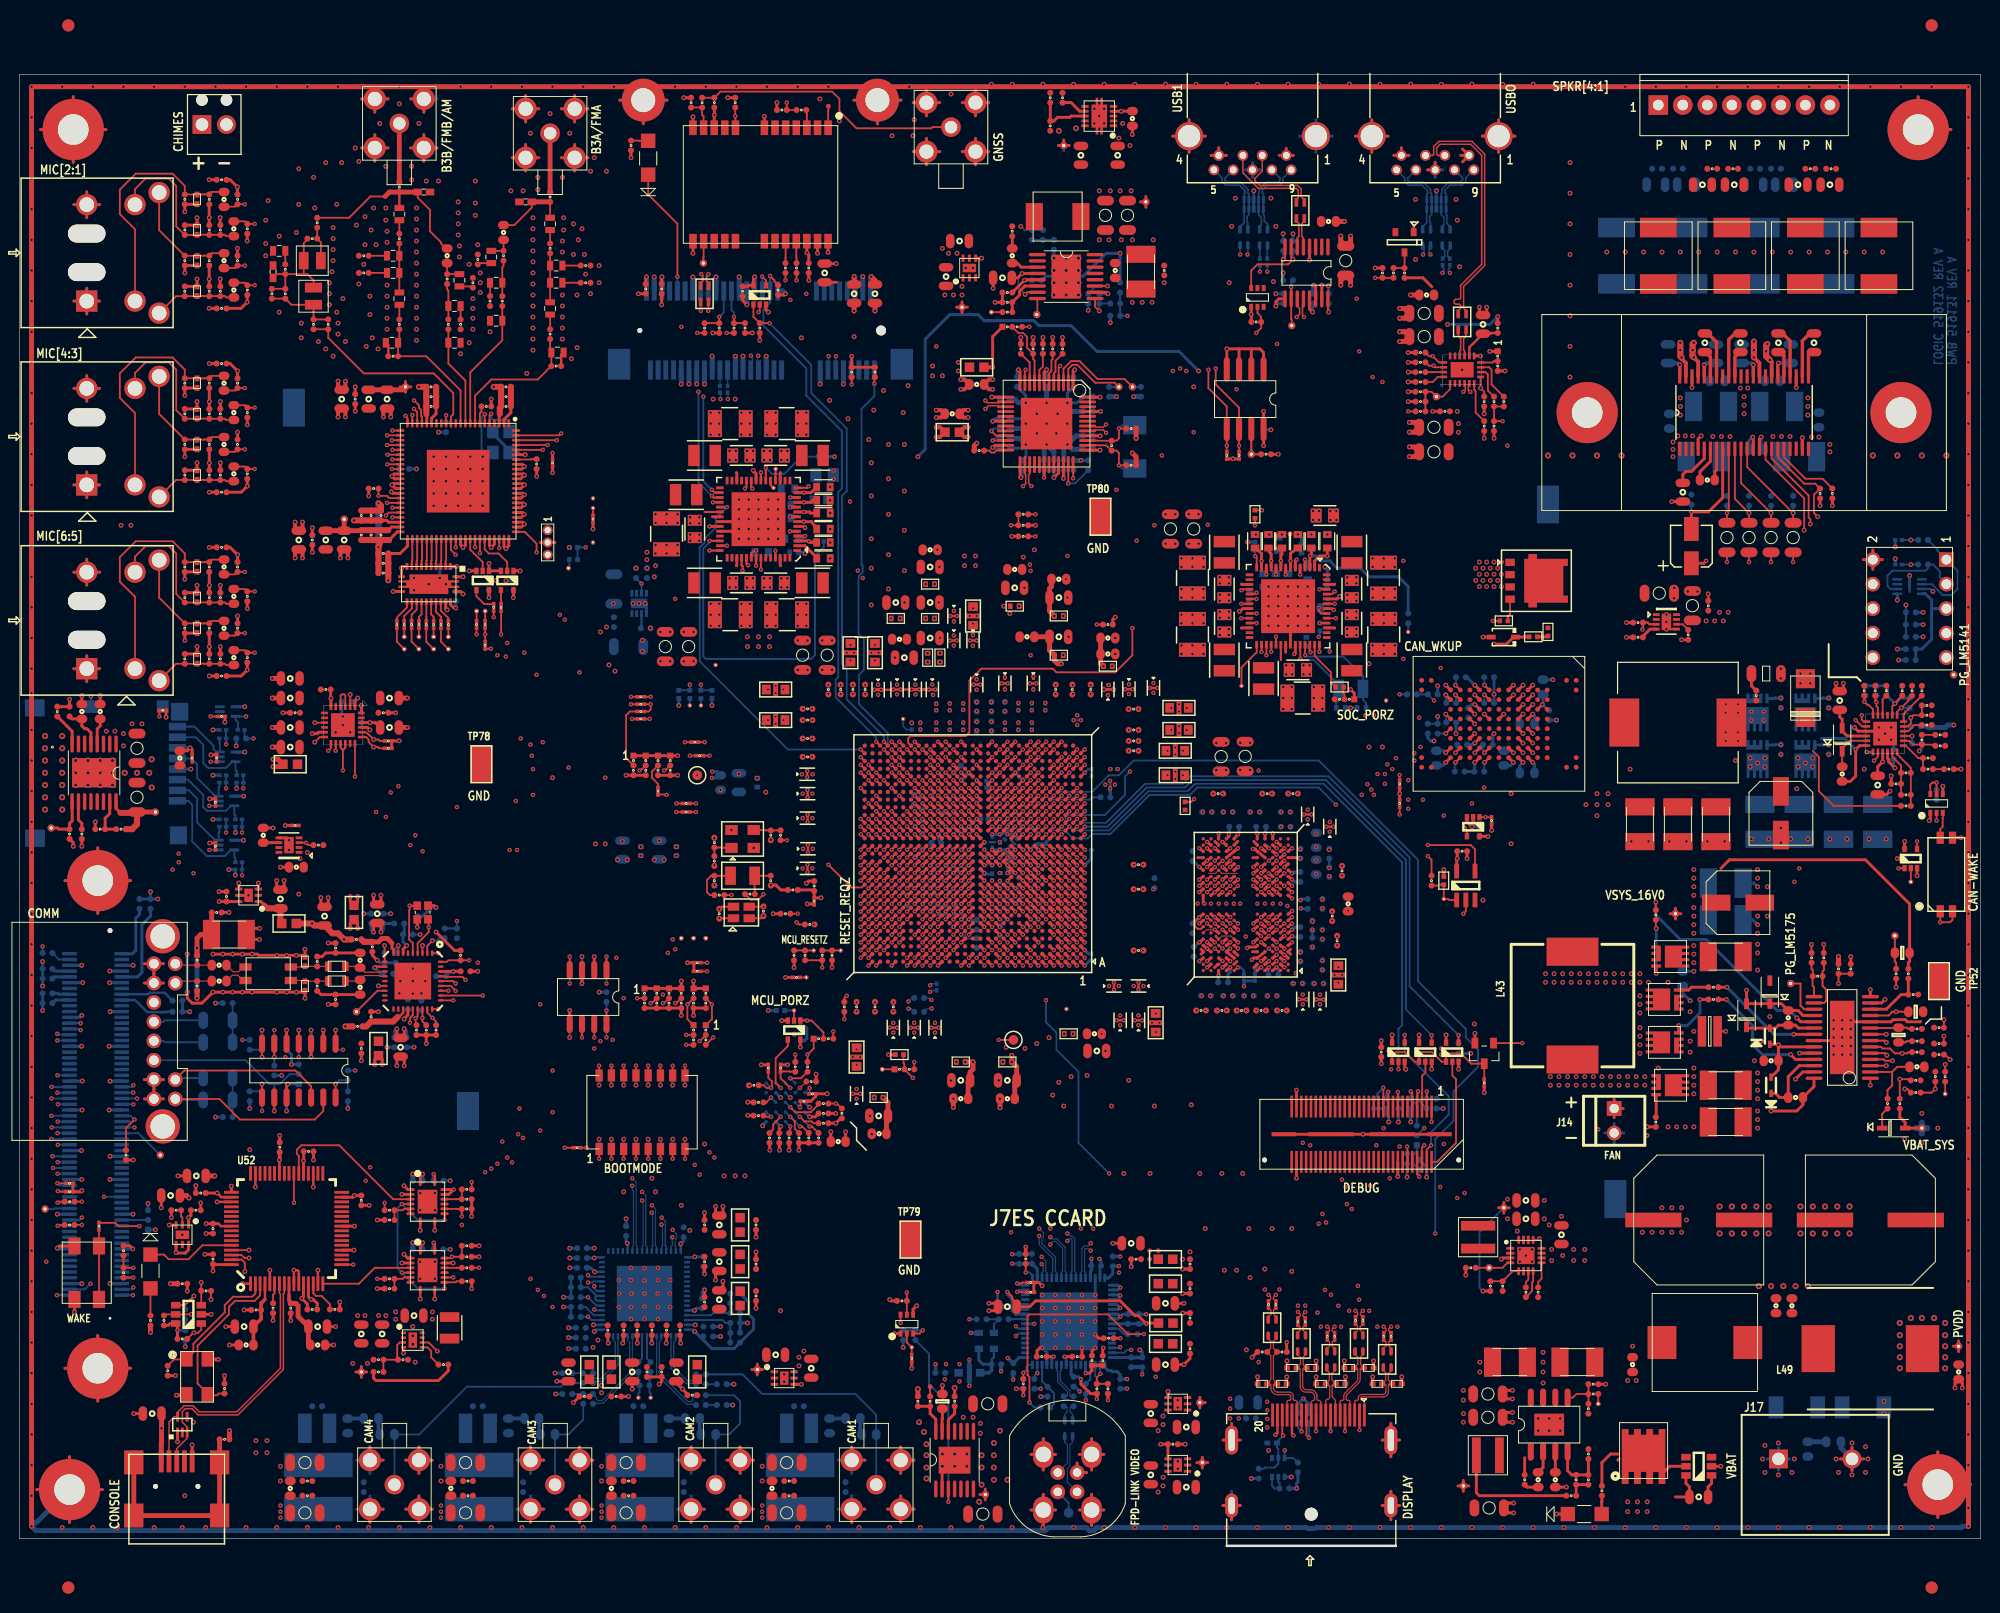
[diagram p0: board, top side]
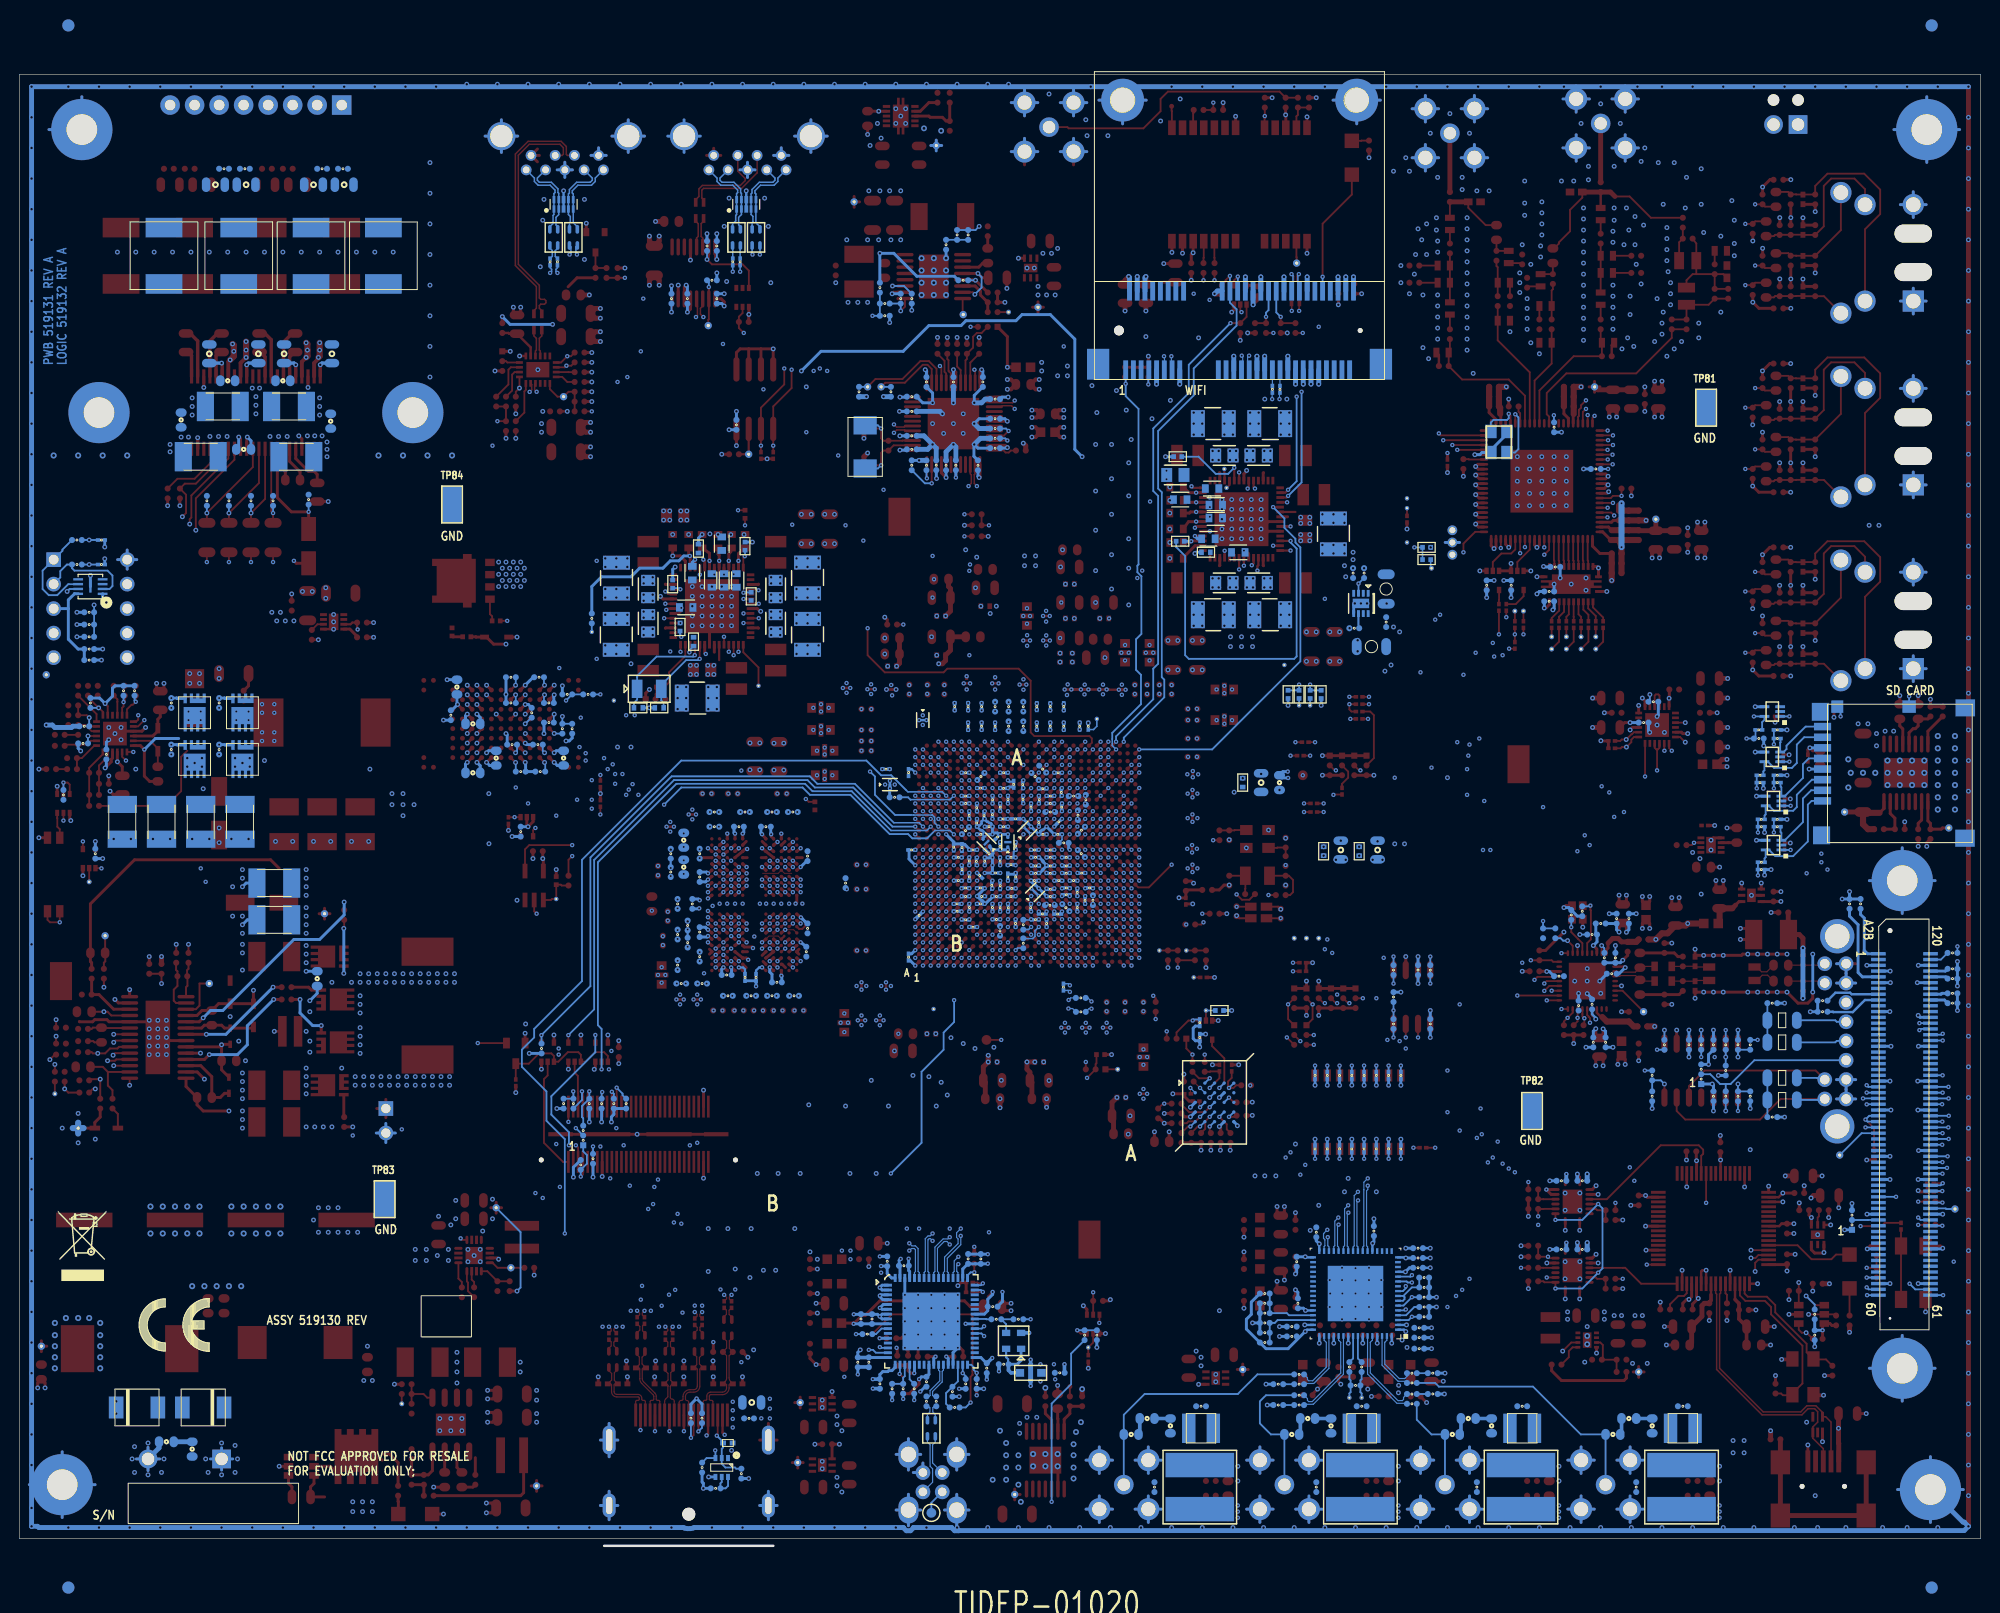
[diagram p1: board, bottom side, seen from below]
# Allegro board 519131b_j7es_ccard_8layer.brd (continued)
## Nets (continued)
DGND: C1.1 C3.2 C4.1 C5.1 C6.1 C7.1 C8.1 C9.1 C10.2 C11.2 C12.2 C13.2 C14.2 C17.1 C19.2 C20.2 C21.1 C24.2 C28.1 C30.2 C34.2 C35.1 C37.2 C38.2 C39.2 C41.1 C42.1 C43.2 C44.2 C45.2 C46.1 C47.1 C49.2 C50.2 C51.2 C52.2 C54.2 C55.1 C56.2 C58.2 C59.2 C60.1 C61.2 C63.2 C65.2 C69.2 C70.2 C72.2 C77.2 C78.2 C79.2 C80.1 C82.2 C87.2 C88.2 C89.2 C90.2 C92.1 C94.2 C96.2 C97.2 C98.2 C99.2 C100.2 C101.2 C102.1 C104.2 C105.2 C106.2 C107.2 C109.2 C111.2 C112.2 C113.2 C114.2 C115.2 C119.2 C120.2 C121.2 C122.2 C123.2 C124.2 C132.2 C133.2 C134.2 C135.2 C136.2 C137.2 C138.2 C139.2 C140.2 C141.2 C143.2 C145.2 C147.1 C149.2 C151.2 C152.2 C153.2 C154.2 C155.2 C156.2 C157.2 C158.2 C159.2 C161.2 C162.2 C163.2 C164.2 C165.2 C166.2 C167.2 C168.2 C169.2 C170.2(GND) C171.2(GND) C172.2 C173.2 C174.2 C175.2 C176.2 C177.1 C179.2 C180.2 C181.2 C182.2 C183.2 C184.2 C185.2(GND) C186.2(GND) C187.2 C188.2 C189.2(GND) C190.2(GND) C191.2 C192.2 C193.2 C194.2 C196.2 C197.2 C198.2 C199.2 C200.2 C201.2 C202.2 C203.2 C204.2(GND) C205.2(GND) C206.2(GND) C207.2(GND) C208.2(GND) C209.2 C210.2(GND) C211.2 C212.2 C213.2 C214.2 C215.2(GND) C216.2(GND) C217.2(GND) C218.2 C219.2 C220.2 C221.2(GND) C222.2(GND) C223.1 C224.2 C225.1 C227.2 C228.2 C229.2 C230.2 C231.2(GND) C232.2(GND) C233.2 C234.2 C235.2 C236.2 C237.2 C238.2 C239.1 C240.2 C241.2(GND) C242.2 C243.1 C244.2 C245.2 C246.2 C247.2(GND) C248.2(GND) C249.1 C250.2 C251.2 C252.2 C253.2 C254.2 C255.2(GND) C256.2 C257.2 C258.2 C259.2 C260.2 C261.2 C264.2(GND) C265.2(GND) C266.2 C267.2(GND) C268.2(GND) C269.2 C270.2 C271.2 C272.2 C273.2 C274.2 C275.2(GND) C276.2(GND) C277.2(GND) C278.2 C279.2 C280.2 C281.2 C282.2(GND) C283.2 C284.2 C285.2 C286.2 C287.2(GND) C288.2 C289.2 C290.2(GND) C291.2 C292.2 C293.2 C294.2 C295.2 C296.2 C297.2 C298.2 C299.2 C300.2 C301.2 C302.2 C303.2 C304.2 C305.1 C306.2 C307.2 C308.2 C309.2 C310.2 C313.1 C314.2(GND) C317.2(GND) C318.2(GND) C320.1 C321.2 C322.2(GND) C323.2(GND) C324.2 C325.2 C326.2 C327.2 C328.2 C329.2 C330.2 C331.2 C332.2 C334.2(GND) C335.2(GND) C336.2(GND) C337.2(GND) C338.2(GND) C339.2(GND) C340.2 C341.2 C342.2 C343.2 C344.2 C345.2 C346.2 C347.2 C348.2 C349.2(GND) C350.2 C351.2 C352.2 C353.2 C355.2 C356.2 C357.1 C358.2 C359.2(GND) C360.2 C362.2 C363.2 C364.2 C365.2 C366.2 C367.2 C368.2 C369.2 C370.2 C371.2 C372.2 C373.2 C374.2 C375.2 C376.2 C377.2 C378.2 C379.2 C380.2 C381.2 C382.2 C383.2 C384.2 C385.2 C386.2 C387.2 C388.2 C389.2 C390.2 C391.2 C392.2 C393.2 C394.2 C396.1 C397.2 C398.2 C399.2 C400.2 C403.2 C404.2 C405.2 C406.2 C407.2 C408.2 C409.2 C410.2 C415.2 C416.2 C417.2 C418.2 C419.2 C420.2 C421.2 C422.2 C423.2 C424.2 C429.2 C430.2 C431.1 C432.2 C433.2 C434.2 C435.2 C436.2 C437.2 C438.2 C439.2 C440.1 C441.2 C443.2 C444.2 C445.2 C446.2 C447.2 C448.2 C449.2 C450.2 C452.2 C453.2 C454.2 C455.2 C456.2 C457.1 C458.2 C459.1 C460.2 C461.2 C462.2 C463.2 C464.1 C465.2 C467.2 C469.2 C470.2 C471.2 C472.1 C473.2 C474.2 C475.2 C476.2 C478.2 C479.2 C480.2 C481.2 C482.2 C483.2 C484.1 C485.1 C486.1 C487.1 C488.2 C489.2 C490.2 C491.2 C492.2 C497.2 C498.2 C504.1 C505.1 C506.2 C507.2 C508.2 C511.2 C512.2 C513.2 C514.2 C515.2 C516.2 C517.1 C518.1 C519.2 C520.2 C521.1 C522.1 C523.2 C524.2 C525.2 C526.2 C527.2 C528.2 C529.2 C530.2 C531.2 C532.2 C533.2 C534.2 C535.2 C536.2 C537.2 C538.2 C539.2 C540.2 C541.2 C542.2 C543.2 C544.2 C545.2 C546.2 C547.2 C548.2 C549.2 C550.2 C551.1 C552.2 C553.2 C554.2 C555.2 C556.2 C557.2 C558.2 C559.2 C560.2 C561.1 C562.1 C563.2 C564.2 C565.2 C566.1 C567.1 C568.2 C569.2 C570.2 C571.2 C572.2 C573.2 C574.2 C575.2 C576.2 C577.2 C578.2 C579.2 C580.2 C581.2 C582.2 C583.2 C584.2 C585.2 C586.2 C587.2 C588.2 C589.2 C590.2 C591.2 C592.1 C593.1 C594.2 C595.2(GND) C596.2 C597.2 C598.2 C599.2 C600.2 C601.2 C602.2 C603.2 C604.2 C605.2 C606.2 C607.2 C608.2 C609.2 C610.2 C611.2 C612.2 C613.2 C614.2(GND) C615.2 C616.2 C617.2 C618.2 C619.2 C620.2 C621.2 C622.2 C623.2 C624.2 C625.2 C626.2 C627.2 C628.2 C629.2 C630.2 C631.2 C632.2 C633.2 C634.2 C635.2 C636.2 C637.2 C638.2 C639.2 C640.2 C641.2 C642.2 C643.2 C644.2 C645.2 C646.2 C647.2 C648.2 C649.2 C650.2 C651.2 C652.2 C653.2 C654.2 C655.2 C657.2 C658.2 C659.2 C660.1 C662.2 C663.2 C664.2 C665.2 C666.2 C667.2 C668.2 C669.2 C670.2 C671.2 C672.2 C673.2 C674.2 C675.2 C676.2 C677.2 C678.2 C679.2 C680.2 C681.2 C682.2 C683.2 C684.2 C685.2 C686.2 C687.2 C688.2 C689.2 C690.2 C691.2 C692.2 C693.2 C694.2 C695.2 C696.2 C697.2 C698.2 C699.2 C700.2 C701.2 C702.2 C703.2 C704.2 C705.2 C706.2 C707.2 C708.2 C709.2 C710.2 C711.2 C712.2 C713.2 C714.2 C715.2 C716.2 C717.2 C718.2 C719.2 C720.2 C722.2 C723.2 C724.2 C725.2 C726.2 C727.2 C728.2 C730.2 C731.2 C732.2 C733.2 C734.2 C735.2 C736.2 C737.2 C738.2 C739.2 C740.2 C741.2 C742.2 C743.2 C744.2 C745.2 C746.2 C747.2 C748.2 C749.2 C750.2 C751.2 C752.2 C753.2 C754.2 C755.2 C756.2 C757.2 C758.2 C759.2 C760.2 C761.2 C762.2 C763.2 C764.2 C765.2 C766.2 C767.2 C768.2 C770.2 C771.2 C772.2 C773.2 C774.2 C775.2 C776.2 C777.2 C778.2 C779.2 C780.2 C781.2 C782.2 C783.2 C784.2 C785.2 C786.2 C787.2 C788.2 C789.2 C790.2 C791.2 C792.2 C793.2 C794.2 C795.2 C796.2 C797.2 C798.2 C799.2 C800.2 C801.2 C802.2 C803.2 C804.2 C805.2 C806.2 C807.2 C808.2 C809.2 C810.2 C811.2 C812.2 C813.2 C814.2 C815.2 C816.2 C817.1 C820.2 C821.1 C824.2 C826.2 C828.2 C833.2 C836.2 C837.1 C839.1 D2.2 D3.2 D4.1(A) D5.2 D6.2(ANODE) D7.2(ANODE) D9.2(ANODE) D15.2(GND) D16.2(GND) D17.2(GND) D18.2(GND) D19.2(GND) D20.2(GND) D21.2(GND) D22.2(GND) D23.2(GND) D24.2(GND) D25.1(CATHODE) DS1.1(CATHODE) FL40.2(GND1) HS1.1 HS1.2 J1.4(GND4) J1.7(GND8) J1.G1 J1.G2 J2.4(GND4) J2.7(GND8) J2.G1 J2.G2 J5.2 J5.3 J5.4 J5.5 J6.2 J6.3 J6.4 J6.5 J7.2 J7.3 J7.4 J7.5 J8.1A J8.1B J9.1A J9.1B J10.2 J11.2 J12.1A J12.1B J13.5 J13.6 J13.11 J13.12 J14.2 J15.16(GND16) J15.57(GND57) J15.58(GND58) J15.61(GNDCT1) J15.62(GNDCT2) J15.63(GNDCT3) J15.64(GNDCT4) J16.4 J16.SH1 J16.SH2 J16.SH3 J16.SH4 J17.2 J18.2(GND#2) J18.5(GND#5) J18.8(GND#8) J18.11(GND#11) J18.16(GND#16) J18.19(RETURN) J18.SH1 J18.SH2 J18.SH3 J18.SH4 J19.5(USBVSS) J20.4(GND#4) J20.9(GND#9) J20.15(GND#15) J20.18(GND#18) J20.21(GND#21) J20.26(GND#26) J20.27(GND#27) J20.29(GND#29) J20.34(GND#34) J20.35(GND#35) J20.37(GND#37) J20.40(GND#40) J20.43(GND#43) J20.50(GND#50) J21.3 J21.4 J21.6 J21.11 J21.17 J21.23 J21.28 J21.36 J21.40 J21.46 J21.52 J21.58 J21.63 J21.69 J21.75 J21.81 J21.86 J21.93 J21.98 J21.104 J21.109 J21.115 J21.118 L1.1 L2.1 L6.1 L23.1 L24.1 L25.1 L26.1 M1.1 M2.1 M3.1 M4.1 M5.1 M6.1 M7.1 M8.1 P1.2 P1.3 P1.4 P1.5 P2.2 P2.3 P2.4 P2.5 P3.2 P3.3 P3.4 P3.5 P4.2 P4.3 P4.4 P4.5 P5.6(VSS) PL1.2 Q1.1(S2) Q2.1(S2) Q2.4(S2) Q6.S Q8.1(S2) Q8.4(S2) Q10.1(S) Q11.1(S) Q15.1(S2) Q15.4(S2) R1.1 R2.1 R8.2 R9.1 R11.1 R14.2 R17.1 R20.1 R21.2 R23.1 R25.2 R26.2 R32.2 R34.2 R35.1 R37.2 R43.2 R44.2 R46.2 R47.2 R52.1 R54.1 R56.2 R58.2 R60.1 R61.2 R64.1 R65.1 R67.1 R69.2 R74.2 R75.2 R77.2 R78.1 R80.1 R84.1 R95.2 R97.2 R101.1 R103.1 R104.2 R106.1 R107.1 R108.1 R111.2 R112.2 R113.2 R114.2 R123.1 R136.2 R137.2 R140.2 R145.2 R148.1 R149.2 R159.2 R169.2 R175.1 R180.2 R182.2 R183.1 R184.2 R189.2 R190.2 R214.2 R216.2 R218.2 R222.1 R227.2 R230.1 R231.2 R235.1 R241.1 R242.2 R244.1 R249.2 R252.1 R253.1 R254.2 R255.1 R256.2 R257.2 R265.1 R269.2 R270.2 R275.1 R276.1 R278.1 R279.1 R280.2 R285.1 R289.1 R291.1 R301.2 R303.2 R306.2 R307.2 R328.2 R331.1 R332.2 R333.2 R334.2 R337.2 R338.2 R341.2 R343.2 R348.2 R349.2 R353.2 R356.2 R358.2 R359.2 R360.2 R361.2 R366.2 R368.2 R369.2 R377.2 R391.2 R394.1 R399.1 R400.1 R401.1 R402.1 R405.1 R413.1 R416.2 R417.2 R418.2 R419.2 R425.2 R430.2 R431.2 R433.2 R436.2 R441.2 R442.2 R443.2 R444.2 R446.2 R449.2 R451.2 R456.2 R457.2 R458.1 RJ2.3 RJ3.3 RJ4.1 RJ5.1 RJ6.1 RJ7.1 RJ8.1 RJ9.1 RJ10.1 RJ11.1 RJ12.3 RJ13.3 RJ18.3 RJ20.1 SW1.3(B2) SW3.1(A) SW3.2(AA) TP52.1 TP78.1 TP79.1 TP80.1 TP81.1 TP82.1 TP83.1 TP84.1 U1.6(GND) U1.11(PP1) U2.7(VDD_USB) U2.10(GND#10) U2.12(GND#12) U2.13(GND#13) U2.24(GND#24) U3.2(GND) U4.2(GND) U5.2(GND) U6.2(NC) U6.5(GND) U6.7(PAD) U7.4(GND#4) U7.13(GND#13) U8.10(AGND) U8.15(PGND#15) U8.16(PGND#16) U8.17(TPAD) U9.2(GND) U10.3(GND) U11.11(GND) U11.21(PAD) U12.2(GND) U13.1(A0) U13.2(A1) U13.3(NC) U13.4(VSS) U14.4(GVDD_RET) U14.13(DVSS) U14.21(GND) U14.25(GND9) U14.30(GND8) U14.37(GND7) U14.42(GND6) U15.2(GND) U16.49(GND(PAD)) U17.2(GND) U18.2(GND) U19.32(SMMODE) U19.33(NVMISO) U19.34(NVMOSI) U19.35(NVSSB) U19.36(NVSCLK) U19.56(DFS1) U19.57(DCLK1) U19.62(DIFS4) U19.63(DICLK4) U19.65(DIFS3) U19.66(DICLK3) U19.68(DIFS2) U19.69(DICLK2) U19.70(DIN2) U19.71(DIFS1) U19.72(DICLK1) U19.73(DIN1) U19.74(GP1) U19.75(GP2) U19.76(GP0) U19.77(DIN0) U19.78(DICLKA) U19.79(DIFSA) U19.80(DICLK0) U19.81(DIFSO) U19.83(ICP) U19.89(EPAD) U20.5(REFGND1) U20.6(REFGND2) U20.21(FB_B2) U20.36(VBACKUP) U20.38(OSC32KIN) U20.57(GND) U21.2(GND) U22.1(OE) U22.3(GND) U23.1(OE) U23.3(GND) U25.11(GND#11) U25.12(GND#12) U25.13(GND#13) U25.22(OEN) U25.25(PP) U26.2(GND) U27.5(REFGND1) U27.6(REFGND2) U27.21(FB_B2) U27.36(VBACKUP) U27.57(GND) U28.5(GND) U28.9(EP) U29.2(GND) U30.2(GND) U31.G2(VSS.1) U31.G3(VSS.2) U31.G4(VSS.3) U31.G5(VSS.4) U31.G6(VSS.5) U31.G7(VSS.6) U31.G8(VSS.7) U31.G9(VSS.8) U31.H2(VSSQ.1) U31.H9(VSSQ.2) U31.J5(VSS.9) U31.L3(VSSQ.3) U31.L8(VSSQ.4) U31.M4(VSSQ.5) U31.M7(VSSQ.6) U31.P2(VSSQ.7) U31.P9(VSSQ.8) U32.1(SPI_SEL) U32.6(AVSS) U32.11(SPKVSS) U32.21(SCLK) U32.24(DVSS) U32.25(IOVSS) U33.3(AGND) U33.9(PGND) U33.25(DAP) U34.12(GND) U34.17(PAD) U35.2(I) U35.3(GND) U36.5(GND) U36.9(EP) U37.A7(VSS#A7) U37.A10(VSS#A10) U37.A13(VSS#A13) U37.A16(VSS#A16) U37.A19(VSS#A19) U37.A22(VSS#A22) U37.AA7(VSS#AA7) U37.AA9(VSS#AA9) U37.AA11(VSS#AA11) U37.AA13(VSS#AA13) U37.AA14(VSS#AA14) U37.AA16(VSS#AA16) U37.AA18(VSS#AA18) U37.AB8(VSS#AB8) U37.AB17(VSS#AB17) U37.AB19(VSS#AB19) U37.AB20(VSS#AB20) U37.AB22(VSS#AB22) U37.AC10(VSS#AC10) U37.AC13(VSS#AC13) U37.AC16(VSS#AC16) U37.AD11(VSS#AD11) U37.AD14(VSS#AD14) U37.AD17(VSS#AD17) U37.AE7(VSS#AE7) U37.AE10(VSS#AE10) U37.AE12(VSS#AE12) U37.AE15(VSS#AE15) U37.AE16(VSS#AE16) U37.AE19(VSS#AE19) U37.AF5(VSS#AF5) U37.AF8(VSS#AF8) U37.AF11(VSS#AF11) U37.AF14(VSS#AF14) U37.AF17(VSS#AF17) U37.AF20(VSS#AF20) U37.AF25(VSS#AF25) U37.AG4(VSS#AG4) U37.AG7(VSS#AG7) U37.AG10(VSS#AG10) U37.AG13(VSS#AG13) U37.AG16(VSS#AG16) U37.AG19(VSS#AG19) U37.AH2(VSS#AH2) U37.AH5(VSS#AH5) U37.AH8(VSS#AH8) U37.AH11(VSS#AH11) U37.AH14(VSS#AH14) U37.AH17(VSS#AH17) U37.AH20(VSS#AH20) U37.AJ4(VSS#AJ4) U37.AJ7(VSS#AJ7) U37.AJ10(VSS#AJ10) U37.AJ13(VSS#AJ13) U37.AJ16(VSS#AJ16) U37.AJ19(VSS#AJ19) U37.B3(VSS#B3) U37.B6(VSS#B6) U37.B9(VSS#B9) U37.B12(VSS#B12) U37.B15(VSS#B15) U37.B18(VSS#B18) U37.B21(VSS#B21) U37.C1(VSS#C1) U37.C5(VSS#C5) U37.C8(VSS#C8) U37.C11(VSS#C11) U37.C14(VSS#C14) U37.C17(VSS#C17) U37.C20(VSS#C20) U37.D2(VSS#D2) U37.D4(VSS#D4) U37.D7(VSS#D7) U37.D10(VSS#D10) U37.D13(VSS#D13) U37.D16(VSS#D16) U37.D19(VSS#D19) U37.E1(VSS#E1) U37.E5(VSS#E5) U37.E9(VSS#E9) U37.E12(VSS#E12) U37.E15(VSS#E15) U37.F4(VSS#F4) U37.F8(VSS#F8) U37.F14(VSS#F14) U37.G1(VSS#G1) U37.G7(VSS#G7) U37.G11(VSS#G11) U37.G13(VSS#G13) U37.G15(VSS#G15) U37.G17(VSS#G17) U37.H4(VSS#H4) U37.H6(VSS#H6) U37.H8(VSS#H8) U37.H10(VSS#H10) U37.H12(VSS#H12) U37.H14(VSS#H14) U37.H16(VSS#H16) U37.H18(VSS#H18) U37.H20(VSS#H20) U37.J7(VSS#J7) U37.J9(VSS#J9) U37.J11(VSS#J11) U37.J13(VSS#J13) U37.J15(VSS#J15) U37.J17(VSS#J17) U37.J21(VSS#J21) U37.J23(VSS#J23) U37.K1(VSS#K1) U37.K4(VSS#K4) U37.K8(VSS#K8) U37.K10(VSS#K10) U37.K12(VSS#K12) U37.K14(VSS#K14) U37.K16(VSS#K16) U37.K18(VSS#K18) U37.K20(VSS#K20) U37.K22(VSS#K22) U37.L3(VSS#L3) U37.L7(VSS#L7) U37.L9(VSS#L9) U37.L13(VSS#L13) U37.L15(VSS#L15) U37.L17(VSS#L17) U37.L19(VSS#L19) U37.L21(VSS#L21) U37.L23(VSS#L23) U37.M1(VSS#M1) U37.M4(VSS#M4) U37.M6(VSS#M6) U37.M8(VSS#M8) U37.M10(VSS#M10) U37.M14(VSS#M14) U37.M16(VSS#M16) U37.M18(VSS#M18) U37.M20(VSS#M20) U37.M28(VSS#M28) U37.N3(VSS#N3) U37.N7(VSS#N7) U37.N15(VSS#N15) U37.N17(VSS#N17) U37.N19(VSS#N19) U37.N21(VSS#N21) U37.N27(VSS#N27) U37.N29(VSS#N29) U37.P1(VSS#P1) U37.P4(VSS#P4) U37.P8(VSS#P8) U37.P10(VSS#P10) U37.P12(VSS#P12) U37.P14(VSS#P14) U37.P16(VSS#P16) U37.P18(VSS#P18) U37.P20(VSS#P20) U37.P28(VSS#P28) U37.R3(VSS#R3) U37.R7(VSS#R7) U37.R9(VSS#R9) U37.R13(VSS#R13) U37.R15(VSS#R15) U37.R17(VSS#R17) U37.R19(VSS#R19) U37.T8(VSS#T8) U37.T10(VSS#T10) U37.T14(VSS#T14) U37.T16(VSS#T16) U37.T18(VSS#T18) U37.T21(VSS#T21) U37.U5(VSS#U5) U37.U9(VSS#U9) U37.U15(VSS#U15) U37.U17(VSS#U17) U37.U19(VSS#U19) U37.U21(VSS#U21) U37.V8(VSS#V8) U37.V10(VSS#V10) U37.V12(VSS#V12) U37.V14(VSS#V14) U37.V18(VSS#V18) U37.W9(VSS#W9) U37.W11(VSS#W11) U37.W13(VSS#W13) U37.W16(VSS#W16) U37.W20(VSS#W20) U37.Y8(VSS#Y8) U37.Y10(VSS#Y10) U37.Y12(VSS#Y12) U37.Y15(VSS#Y15) U37.Y17(VSS#Y17) U37.Y19(VSS#Y19) U37.Y21(VSS#Y21) U38.3(GND) U39.5(GND) U39.7(PAD) U40.A3(VSS#A3) U40.A10(VSS#A10) U40.AB3(VSS#AB3) U40.AB5(VSS#AB5) U40.AB8(VSS#AB8) U40.AB10(VSS#AB10) U40.C1(VSS#C1) U40.C5(VSS#C5) U40.C8(VSS#C8) U40.C12(VSS#C12) U40.D2(VSS#D2) U40.D4(VSS#D4) U40.D9(VSS#D9) U40.D11(VSS#D11) U40.E1(VSS#E1) U40.E5(VSS#E5) U40.E8(VSS#E8) U40.E12(VSS#E12) U40.G1(VSS#G1) U40.G3(VSS#G3) U40.G5(VSS#G5) U40.G8(VSS#G8) U40.G10(VSS#G10) U40.G12(VSS#G12) U40.J1(VSS#J1) U40.J3(VSS#J3) U40.J10(VSS#J10) U40.J12(VSS#J12) U40.K2(VSS#K2) U40.K4(VSS#K4) U40.K9(VSS#K9) U40.K11(VSS#K11) U40.N2(VSS#N2) U40.N4(VSS#N4) U40.N9(VSS#N9) U40.N11(VSS#N11) U40.P1(VSS#P1) U40.P3(VSS#P3) U40.P10(VSS#P10) U40.P12(VSS#P12) U40.T1(VSS#T1) U40.T3(VSS#T3) U40.T5(VSS#T5) U40.T8(VSS#T8) U40.T10(VSS#T10) U40.T12(VSS#T12) U40.V1(VSS#V1) U40.V5(VSS#V5) U40.V8(VSS#V8) U40.V12(VSS#V12) U40.W2(VSS#W2) U40.W4(VSS#W4) U40.W9(VSS#W9) U40.W11(VSS#W11) U40.Y1(VSS#Y1) U40.Y5(VSS#Y5) U40.Y8(VSS#Y8) U40.Y12(VSS#Y12) U41.2(GND) U42.37(GND) U43.2(GND) U44.2(GND) U45.3(GND) U46.10(AGND) U46.13(ISNS(-)) U46.14(ISNS(+)) U46.22(PGND) U46.29(PAD) U47.3(GND) U48.3(GND) U49.3(GND) U50.2(GND) U51.3(2DIR) U51.8(GND.1) U51.9(GND.2) U51.14(2O\E\) U51.15(1O\E\) U51.17(GND.3) U52.1(GND#1) U52.5(GND#5) U52.10(AGND) U52.11(GND#11) U52.13(TEST) U52.15(GND#15) U52.25(GND#25) U52.35(GND#35) U52.47(GND#47) U52.51(GND#51) U53.3(GND#3) U53.7(GND#7) U54.3(FREQ) U54.6(AGND) U54.14(PGND#14) U54.15(PGND#15) U54.17(PGND#17) U55.3(2DIR) U55.8(GND.1) U55.9(GND.2) U55.14(2O\E\) U55.17(GND.3) U56.2(GND) U57.1(GND) U57.9(PAD) U58.2(NC) U58.5(GND) U58.7(PAD) U59.2(NC) U59.5(GND) U59.7(PAD) U60.4(GND) U61.6(AGND) U61.8(PGND) U61.9(PAD) U62.2(GND) U62.15(TAB(GND)) U63.2(NC) U63.5(GND) U63.7(PAD) U64.2(GND) U65.3(GND#3) U65.8(GND#8) U66.3(GND#3) U66.8(GND#8) U67.1(GND#1) U67.9(GND#9) U68.5(GND) U68.9(EP) U69.4(GND) U70.4(GND) U71.4(GND) U72.4(GND) U73.B3(VSS#B3) U73.C1(VSS#C1) U73.E5(VSS#E5) U74.65(DAP) U75.1(DSI1_D2N) U75.2(DSI1_D2P) U75.3(DSI1_D1N) U75.4(DSI1_D1P) U75.5(DSI1_D0N) U75.6(DSI1_D0P) U75.7(DSI1_CLKN) U75.8(DSI1_CLKP) U75.29(RES0) U75.40(RES1) U75.62(DSI1_D3N) U75.63(DSI1_D3P) U75.65(GND) U76.2(GND) U77.3(GND) U78.2(GND) Y1.2(GND1) Y1.4(GND2) Y3.2(GND1) Y3.4(GND2) Y4.2(GND1) Y4.4(GND2) Y5.2(NC1) Y5.4(NC2) Y6.2(GND1) Y6.4(GND2)
PVDD: C376.1 C448.1 C504.2 C505.2 C513.1 C514.1 C517.2 C518.2 C529.1 C530.1 L49.2 TP65.1(TP) U14.1(PVDD1) U14.2(PVDDQ) U14.3(VBAT) U14.22(PVDD3) U14.33(PVDD4) U14.34(PVDD5)
V3V3_DP0: C472.2 C833.1 C836.1 J18.20(PWR) TP72.1(TP) U63.1(OUT)
V941_IO_1V1: C394.1 C410.1 C430.1 C459.2 FL23.1 FL25.1 FL27.1 TP70.1(TP) U59.1(OUT)
V960_IO_1V1: C391.1 C397.1 C431.2 C452.1 FL22.1 FL24.1 FL34.1 TP67.1(TP) U58.1(OUT)
VBAT: C477.2 C838.2 D26.1(CATHODE) J17.1 Q9.1(S1) Q9.2(S2) Q9.3(S3) U64.3(EN) U64.6(ANODE)
VBAT_SYS: C266.1 C358.1 C364.1 C377.1 C439.1 C645.1 C646.1 C647.1 C648.1 C787.1 D13.2(ANODE) J14.1 L46.2 Q7.5(D) Q12.5(D) Q13.5(D) R199.1 R315.2 R342.2 RJ18.1 TP60.1(TP) U33.15(VIN) U50.10(VSUP)
VBUS2_5V0: C21.2 J1.1(VBUS) U7.2(VBUS_CON) U7.3(VBUS_SON)
VBUS_USBC_CONN: C60.2 C65.1 C72.1 J2.1(VBUS) R19.1 R33.1 U11.15(OUT#15) U11.16(OUT#16)
VCC_1V1USB: C82.1 C506.1 C508.1 C515.1 C516.1 C531.1 C533.1 FL4.1 RJ1.1 U16.1(VDD#1) U16.12(VDD#12) U16.18(VDD#18) U16.30(VDD#30) U16.34(VDD#34) U16.45(VDD#45)
VCC_APL: C580.1 J11.5 R296.2 U67.8(VCC)
VCC_LM5141: C230.1 D8.2(ANODE) U33.10(VCC)
VCC_LM5175: C350.1 D11.2(A) D12.2(A) R193.2 U46.23(VCC)
VCCA_3V3: C105.1 C106.1 C119.1 C120.1 C153.1 C154.1 C157.1 C158.1 C175.1 C176.1 C201.1 C527.1 C528.1 C535.1 C536.1 C538.1 C543.1 C544.1 C546.1 C547.1 C548.1 C549.1 C552.1 C553.1 C556.1 C557.1 C558.1 C559.1 C560.1 C563.1 C564.1 C565.1 C572.1 C573.1 U20.4(VCCA) U20.8(PVIN_LDO4) U20.10(PVIN_LDO3) U20.12(PVIN_LDO12) U20.17(PVIN_B2) U20.26(PVIN_B1) U20.35(PVIN_B5) U20.45(PVIN_B3) U20.54(PVIN_B4) U24.1(S1) U24.2(S2) U24.3(S3) U27.4(VCCA) U27.8(PVIN_LDO4) U27.10(PVIN_LDO3) U27.12(PVIN_LDO12) U27.17(PVIN_B2) U27.26(PVIN_B1) U27.35(PVIN_B5) U27.45(PVIN_B3) U27.54(PVIN_B4) U68.1(VIN1) U68.2(VIN2) U68.4(VBIAS)
VDD1_LPDDR4_1V8: C135.1 C635.1 C636.1 C652.1 C666.1 C683.1 C705.1 C759.1 C761.1 C771.1 C775.1 C777.1 U27.13(VOUT_LDO1) U40.F1(VDD1#F1) U40.F12(VDD1#F12) U40.G4(VDD1#G4) U40.G9(VDD1#G9) U40.T4(VDD1#T4) U40.T9(VDD1#T9) U40.U1(VDD1#U1) U40.U12(VDD1#U12)
VDD18_DSI: C384.1 C388.1 C801.1 C824.1 FL21.2 R246.1 R248.1 R447.1 U75.24(VDD18#24) U75.61(VDD18#61)
VDD_1P0: C303.1 FL14.1 R152.2 R176.2
VDD_CORE_0V8: C98.1 C99.1 C168.1 C169.1 C187.1 C188.1 C189.1(INPUT) C189.3(OUTPUT) C190.1(INPUT) C190.3(OUTPUT) C192.1 C193.1 C210.1(INPUT) C210.3(OUTPUT) C211.1 C212.1 C213.1 C214.1 C215.1(INPUT) C215.3(OUTPUT) C216.1(INPUT) C216.3(OUTPUT) C217.1(INPUT) C217.3(OUTPUT) C222.1(INPUT) C222.3(OUTPUT) C233.1 C241.1(INPUT) C241.3(OUTPUT) C242.1 C250.1 C258.1 C264.1(INPUT) C264.3(OUTPUT) C267.1(INPUT) C267.3(OUTPUT) C268.1(INPUT) C268.3(OUTPUT) C276.1(INPUT) C276.3(OUTPUT) C277.1(INPUT) C277.3(OUTPUT) C287.1(INPUT) C287.3(OUTPUT) C519.1 C520.1 C569.1 C570.1 C606.1 C644.1 C662.1 C664.1 C669.1 C672.1 C673.1 C674.1 C685.1 C686.1 C687.1 C688.1 C693.1 C694.1 C695.1 C701.1 C702.1 C707.1 C708.1 C710.1 C717.1 C722.1 C726.1 C727.1 C728.1 C730.1 C736.1 FL9.1 FL11.1 FL17.1 L28.2 L29.2 L34.2 L35.2 U20.22(FB_B1) U37.J10(VDD_CORE#J10) U37.K9(VDD_CORE#K9) U37.K11(VDD_CORE#K11) U37.K13(VDD_CORE#K13) U37.K15(VDD_CORE#K15) U37.K17(VDD_CORE#K17) U37.L10(VDD_CORE#L10) U37.L16(VDD_CORE#L16) U37.L18(VDD_CORE#L18) U37.M15(VDD_CORE#M15) U37.N14(VDD_CORE#N14) U37.N16(VDD_CORE#N16) U37.N18(VDD_CORE#N18) U37.P13(VDD_CORE#P13) U37.P15(VDD_CORE#P15) U37.P17(VDD_CORE#P17) U37.R14(VDD_CORE#R14) U37.R16(VDD_CORE#R16) U37.R18(VDD_CORE#R18) U37.R20(VDD_CORE#R20) U37.T9(VDD_CORE#T9) U37.T15(VDD_CORE#T15) U37.T17(VDD_CORE#T17) U37.U14(VDD_CORE#U14) U37.U16(VDD_CORE#U16) U37.U18(VDD_CORE#U18) U37.V15(VDD_CORE#V15) U37.V17(VDD_CORE#V17) U37.V20(VDD_CORE#V20) U37.W14(VDD_CORE#W14)
VDD_CORE_0V8_REG_SW1: L28.1 U20.27(SW_B1A) U20.28(SW_B1B)
VDD_CORE_0V8_REG_SW2: L29.1 U20.15(SW_B2A) U20.16(SW_B2B)
VDD_CORE_0V8_REG_SW3: L34.1 U20.43(SW_B3A) U20.44(SW_B3B)
VDD_CORE_0V8_REG_SW4: L35.1 U20.55(SW_B4A) U20.56(SW_B4B)
VDD_CORE_RAM_0V85: C612.1 C613.1 C649.1 C650.1 C657.1 C720.1 FL39.2 U37.L14(VDDAR_CORE#L14) U37.V13(VDDAR_CORE#V13) U37.V16(VDDAR_CORE#V16) U37.W19(VDDAR_CORE#W19)
VDD_CPU_AVS: C122.1 C123.1 C151.1 C179.1 C218.1 C219.1 C220.1 C221.1(INPUT) C221.3(OUTPUT) C231.1(INPUT) C231.3(OUTPUT) C232.1(INPUT) C232.3(OUTPUT) C234.1 C246.1 C247.1(INPUT) C247.3(OUTPUT) C248.1(INPUT) C248.3(OUTPUT) C254.1 C255.1(INPUT) C255.3(OUTPUT) C256.1 C257.1 C265.1(INPUT) C265.3(OUTPUT) C554.1 C577.1 C595.1(INPUT) C595.3(OUTPUT) C614.1(INPUT) C614.3(OUTPUT) C642.1 C651.1 C655.1 C663.1 C665.1 C668.1 C677.1 C692.1 C699.1 L32.2 L36.2 U27.22(FB_B1) U37.N10(VDD_CPU#N10) U37.P11(VDD_CPU#P11) U37.R10(VDD_CPU#R10) U37.R12(VDD_CPU#R12) U37.U10(VDD_CPU#U10) U37.V9(VDD_CPU#V9) U37.V11(VDD_CPU#V11) U37.W10(VDD_CPU#W10)
VDD_CPU_AVS_REG_SW1: L36.1 U27.27(SW_B1A) U27.28(SW_B1B)
VDD_CPU_AVS_REG_SW2: L32.1 U27.15(SW_B2A) U27.16(SW_B2B)
VDD_CPU_RAM_0V85: C149.1 C155.1 C643.1 C714.1 FL6.2 U37.L11(VDDAR_CPU#L11) U37.W12(VDDAR_CPU#W12)
VDD_DDR_1V1: C152.1 C269.1 C270.1 C271.1 C275.1(INPUT) C275.3(OUTPUT) C282.1(INPUT) C282.3(OUTPUT) C288.1 C291.1 C294.1 C299.1 C304.1 C306.1 C309.1 C314.1(INPUT) C314.3(OUTPUT) C317.1(INPUT) C317.3(OUTPUT) C318.1(INPUT) C318.3(OUTPUT) C322.1(INPUT) C322.3(OUTPUT) C323.1(INPUT) C323.3(OUTPUT) C327.1 C328.1 C329.1 C330.1 C331.1 C334.1(INPUT) C334.3(OUTPUT) C335.1(INPUT) C335.3(OUTPUT) C336.1(INPUT) C336.3(OUTPUT) C555.1 C634.1 C637.1 C653.1 C654.1 C670.1 C671.1 C682.1 C684.1 C689.1 C697.1 C698.1 C706.1 C709.1 C716.1 C725.1 C733.1 C734.1 C735.1 C739.1 C745.1 C755.1 C758.1 C760.1 C762.1 C763.1 C764.1 C767.1 C770.1 C772.1 C774.1 C776.1 L33.2 R132.1 R352.1 R365.1 R373.1 R374.1 U27.50(FB_B4) U37.A1(VDDS_DDR#A1) U37.G8(VDDS_DDR#G8) U37.H7(VDDS_DDR_BIAS#H7) U37.J6(VDDS_DDR_BIAS#J6) U37.J8(VDDS_DDR#J8) U37.K7(VDDS_DDR#K7) U37.L8(VDDS_DDR#L8) U37.M7(VDDS_DDR#M7) U37.M9(VDDS_DDR_C) U37.N8(VDDS_DDR#N8) U37.P7(VDDS_DDR#P7) U37.R6(VDDS_DDR_BIAS#R6) U37.R8(VDDS_DDR#R8) U37.T1(VDDS_DDR#T1) U37.T7(VDDS_DDR_BIAS#T7) U40.A4(VDD2#A4) U40.A9(VDD2#A9) U40.AA3(VDDQ#AA3) U40.AA5(VDDQ#AA5) U40.AA8(VDDQ#AA8) U40.AA10(VDDQ#AA10) U40.AB4(VDD2#AB4) U40.AB9(VDD2#AB9) U40.B3(VDDQ#B3) U40.B5(VDDQ#B5) U40.B8(VDDQ#B8) U40.B10(VDDQ#B10) U40.D1(VDDQ#D1) U40.D5(VDDQ#D5) U40.D8(VDDQ#D8) U40.D12(VDDQ#D12) U40.F3(VDDQ#F3) U40.F5(VDD2#F5) U40.F8(VDD2#F8) U40.F10(VDDQ#F10) U40.H1(VDD2#H1) U40.H5(VDD2#H5) U40.H8(VDD2#H8) U40.H12(VDD2#H12) U40.K1(VDD2#K1) U40.K3(VDD2#K3) U40.K10(VDD2#K10) U40.K12(VDD2#K12) U40.N1(VDD2#N1) U40.N3(VDD2#N3) U40.N10(VDD2#N10) U40.N12(VDD2#N12) U40.R1(VDD2#R1) U40.R5(VDD2#R5) U40.R8(VDD2#R8) U40.R12(VDD2#R12) U40.U3(VDDQ#U3) U40.U5(VDD2#U5) U40.U8(VDD2#U8) U40.U10(VDDQ#U10) U40.W1(VDDQ#W1) U40.W5(VDDQ#W5) U40.W8(VDDQ#W8) U40.W12(VDDQ#W12)
VDD_DDR_1V1_REG_SW: L33.1 U27.55(SW_B4A) U27.56(SW_B4B)
VDD_DSI_OSC: C817.2 FL40.3(OUT) U76.1(STANDBY) U76.4(VDD)
VDD_IO_1V8: C115.1 C204.1(INPUT) C204.3(OUTPUT) C205.1(INPUT) C205.3(OUTPUT) C608.1 C609.1 C620.1 C628.1 R297.1 R298.1 R311.1 R312.1 R313.2 R314.1 R318.1 R324.1 R325.1 R329.1 R330.1 U20.9(VOUT_LDO3) U31.H3(VCCQ.1) U31.H8(VCCQ.2) U31.L2(VCCQ.3) U31.L4(VCCQ.4) U31.L7(VCCQ.5) U31.L9(VCCQ.6) U31.P3(VCCQ.7) U31.P8(VCCQ.8) U37.AA8(VDDS_MMC0#AA8) U37.AB7(VDDS_MMC0#AB7) U37.Y7(VDDS_MMC0#Y7)
VDD_IO_3V3: C3.1 C39.1 C45.1 C51.1 C55.2 C59.1 C87.1 C88.1 C116.1 C117.1 C118.1 C144.1 C146.1 C150.1 C165.1 C166.1 C170.1(INPUT) C170.3(OUTPUT) C171.1(INPUT) C171.3(OUTPUT) C185.1(INPUT) C185.3(OUTPUT) C186.1(INPUT) C186.3(OUTPUT) C206.1(INPUT) C206.3(OUTPUT) C245.1 C281.1 C289.1 C295.1 C498.1 C525.1 C551.2 C561.2 C562.2 C566.2 C567.2 C583.1 C584.1 C585.1 C586.1 C587.1 C588.1 C589.1 C590.1 C591.1 C596.1 C597.1 C598.1 C599.1 C600.1 C601.1 C602.1 C603.1 C604.1 C605.1 C611.1 C618.1 C619.1 C621.1 C626.1 C629.1 C631.1 C660.2 C789.1 C793.1 C796.1 C815.1 C816.1 C820.1 C821.2 FL5.2 FL12.2 FL13.2 FL16.1 FL40.1(IN) J20.2(3.3VAUX) J20.24(+3.3VAUX#24) J20.39(+3.3VAUX#39) J20.41(+3.3VAUX#41) J20.52(+3.3VAUX#52) L27.1 R3.1 R6.1 R29.1 R31.1 R36.2 R38.2 R39.2 R40.2 R41.1 R42.1 R68.2 R70.2 R73.2 R118.1 R121.1 R126.1 R131.1 R139.1 R142.1 R164.1 R211.1 R213.1 R228.1 R233.1 R234.1 R240.2 R250.1 R266.1 R273.2 R274.2 R282.1 R288.1 R292.2 R296.1 R316.2 R379.2 R382.2 R393.1 R395.1 R396.1 R397.1 R398.1 R426.2 R427.2 R429.1 R439.1 R448.1 R464.2 R465.2 RJ2.1 RJ4.3 RJ5.3 RJ6.3 RJ7.3 RJ20.3 U1.4(BIAS) U2.22(V_BCKP) U2.23(VCC) U7.9(VIN) U10.5(VCC) U14.14(DVDD) U19.42(VIO1) U19.45(VIO2) U22.5(VCC) U23.5(VCC) U25.1(VCCA) U25.2(DIR) U25.23(VCCB#23) U25.24(VCCB#24) U28.7(VOUT1) U28.8(VOUT2) U31.F2(VCC.1) U31.F3(VCC.2) U31.F4(VCC.3) U31.F5(VCC.4) U31.F6(VCC.5) U31.F7(VCC.6) U31.F8(VCC.7) U31.F9(VCC.8) U32.22(IOVDD) U35.5(VCC) U36.1(VIN1) U36.2(VIN2) U36.4(VBIAS) U37.AA17(VDDSHV2#AA17) U37.AA19(VDDSHV1#AA19) U37.AA20(VDDSHV1#AA20) U37.AA21(VDDSHV4#AA21) U37.AB16(VDDSHV2#AB16) U37.AB18(VDDSHV2#AB18) U37.AC17(VDDSHV2#AC17) U37.AC19(VDDSHV1#AC19) U37.AC20(VDDSHV1#AC20) U37.U8(VDDSHV0#U8) U37.U20(VDDSHV6#U20) U37.U22(VDDSHV6#U22) U37.V7(VDDSHV0#V7) U37.V21(VDDSHV3#V21) U37.W22(VDDSHV3#W22) U37.Y22(VDDSHV4#Y22) U39.3(EN) U39.4(BIAS) U39.6(IN) U51.16(VCCB) U74.16(VDDIO) U75.16(VDDIO#16) U75.33(VDDIO#33)
VDD_MCU_0V85: C180.1 C324.1 C325.1 C326.1 C337.1(INPUT) C337.3(OUTPUT) C338.1(INPUT) C338.3(OUTPUT) C349.1(INPUT) C349.3(OUTPUT) C359.1(INPUT) C359.3(OUTPUT) C576.1 C696.1 C703.1 C711.1 C712.1 C718.1 FL19.1 L37.2 U27.49(FB_B3) U37.L20(VDD_MCU#L20) U37.M19(VDD_MCU#M19) U37.M21(VDD_MCU#M21) U37.N20(VDD_MCU#N20) U37.P19(VDD_MCU#P19)
VDD_MCU_0V85_REG_SW: L37.1 U27.43(SW_B3A) U27.44(SW_B3B)
VDD_MCU_RAM_0V85: C360.1 C363.1 C724.1 FL19.2 U37.K19(VDDAR_MCU#K19) U37.T19(VDDAR_MCU#T19)
VDD_MCUIO_1V8: C136.1 C339.1(INPUT) C339.3(OUTPUT) C362.1 C365.1 C366.1 C740.1 C747.1 C773.1 C782.1 R187.2 R188.2 R194.2 R195.2 R196.1 R200.1 R201.1 R203.1 R204.1 R205.1 R206.1 R207.1 R208.1 R385.2 U27.11(VOUT_LDO2) U37.H19(VDDSHV1_MCU#H19) U37.H21(VDDSHV1_MCU#H21) U37.J20(VDDSHV1_MCU#J20) U45.5(VCC) U73.B4(VCC#B4) U73.D1(VCC#D1) U73.E4(VCC#E4)
VDD_MCUIO_3V3: C290.1(INPUT) C290.3(OUTPUT) C521.2 C550.1 C568.1 C571.1 C579.1 C719.1 C723.1 C731.1 C781.1 C786.1 C794.1 C839.2 R62.1 R63.1 R155.1 R158.1 R163.1 R166.1 R210.2 R221.1 R284.2 R408.1 R410.1 R412.1 R414.1 R415.1 R420.2 R421.2 R422.2 R423.2 R424.1 R463.2 RJ3.1 RJ8.3 RJ9.3 RJ10.3 RJ11.3 RJ12.1 RJ13.1 U13.8(VCC) U20.48(VIO_IN) U27.48(VIO_IN) U37.J22(VDDSHV2_MCU#J22) U37.K21(VDDSHV2_MCU#K21) U37.L22(VDDSHV0_MCU#L22) U37.M22(VDDSHV0_MCU#M22) U44.5(VIO/NC) U50.5(VIO) U55.16(VCCB) U68.7(VOUT1) U68.8(VOUT2) U77.5(VCC)
VDD_PHYIO_1V8: C229.1 C582.1 C610.1 FL7.1 FL8.1 FL18.1 L38.2 U27.37(FB_B5) U37.W7(VDDA_1P8_MLB)
VDD_PHYIO_1V8_REG_SW: L38.1 U27.34(SW_B5A)
VDD_RAM_0V85: C124.1 C545.1 FL6.1 FL39.1 L30.2 U20.37(FB_B5)
VDD_RAM_0V85_REG_SW: L30.1 U20.34(SW_B5A)
VDD_SD_DV: C111.1 C667.1 R320.1 R321.1 R336.1 R339.1 R345.1 R346.1 R351.1 U20.13(VOUT_LDO1) U37.T20(VDDSHV5#T20) U37.T22(VDDSHV5#T22)
VDD_SPK: C237.1 C244.1 C252.1 FL12.1 U32.8(LDO_SEL) U32.10(SPKVDD)
VDD_TAS: C203.1 C209.1 C227.1 C228.1 C238.1 U32.7(AVDD) U32.23(DVDD)
VDDA_0P8_CSIRX: C351.1 C355.1 C741.1 C743.1 C744.1 C748.1 C752.1 C756.1 FL17.2 U37.G12(VDDA_0P8_DP#G12) U37.G14(VDDA_0P8_DP_C#G14) U37.H13(VDDA_0P8_DP_C#H13) U37.H15(VDDA_0P8_DSITX) U37.H17(VDDA_0P8_CSIRX) U37.J12(VDDA_0P8_DP#J12) U37.J16(VDDA_0P8_DSITX_C)
VDDA_0P8_DLL_MMC0: C191.1 C200.1 C633.1 C641.1 FL10.2 U37.W8(VDDA_0P8_PLL_MLB) U37.Y9(VDDA_0P8_DLL_MMC0)
VDDA_0P8_PLL_DDR: C342.1 C347.1 C704.1 FL15.2 U37.N9(VDDA_0P8_PLL_DDR)
VDDA_0P8_SERDES: C184.1 C196.1 C197.1 C198.1 C623.1 C624.1 C630.1 C632.1 C639.1 FL11.2 U37.AA12(VDDA_0P8_SERDES2_3#AA12) U37.AA15(VDDA_0P8_SERDES0_1#AA15) U37.AB12(VDDA_0P8_SERDES_C2_3#AB12) U37.AB13(VDDA_0P8_SERDES_C2_3#AB13) U37.AB14(VDDA_0P8_SERDES_C0_1#AB14) U37.AB15(VDDA_0P8_SERDES_C0_1#AB15) U37.Y11(VDDA_0P8_SERDES2_3#Y11) U37.Y13(VDDA_0P8_SERDES2_3#Y13) U37.Y14(VDDA_0P8_SERDES0_1#Y14) U37.Y16(VDDA_0P8_SERDES0_1#Y16)
VDDA_0P8_UFS: C182.1 C194.1 FL9.2 U37.AA10(VDDA_0P8_USB) U37.AB9(VDDA_0P8_UFS)
VDDA_1P8_CSI_RX: C352.1 C356.1 C738.1 C753.1 FL18.2 U37.G16(VDDA_1P8_CSIRX) U37.H11(VDDA_1P8_DP) U37.J14(VDDA_1P8_DSITX)
VDDA_1P8_SERDES: C156.1 C167.1 C615.1 C617.1 FL7.2 U37.AC11(VDDA_1P8_SERDES2_3#AC11) U37.AC12(VDDA_1P8_SERDES2_3#AC12) U37.AC14(VDDA_1P8_SERDES0_1#AC14) U37.AC15(VDDA_1P8_SERDES0_1#AC15)
VDDA_1P8_UFS: C162.1 C172.1 C616.1 FL8.2 U37.AC8(VDDA_1P8_UFS) U37.AC9(VDDA_1P8_USB)
VDDA_LM5141: C224.1 R299.2 R300.2 R308.2 U33.2(VDDA)
VDDA_TC811: C301.1 C750.1 C751.1 C766.1 FL13.1 R154.1 R177.1 R178.1 R179.1 R357.2 U42.11(VDDA)
VDDHS11_DSI: C400.1 C429.1 C432.1 C433.1 C434.1 C435.1 C799.1 FL23.2 U75.12(VDD11_A) U75.21(VDD11_HS1) U75.25(VDD11_S) U75.28(VDD11_HS0) U75.64(VDD11_DSI)
VDDI_MMC2: C581.1 C594.1 U31.E4(VDDIM)
VDDIO_TC811: C345.1 C346.1 C779.1 C780.1 C783.1 C784.1 FL16.2 R165.2 R362.2 U42.22(VDDIO)
VDDL11_DSI: C405.1 C804.1 C806.1 C807.1 FL25.2 U75.9(VDD11_L#9) U75.42(VDD11_L#42)
VDDP11_DSI: C438.1 C797.1 C798.1 C826.1 FL27.2 U75.17(VDD11_P0) U75.50(VDD11_P1)
VINT_LEOA_1V8: C140.1 R277.1 U27.2(VOUT_LDOVINT)
VINT_LEOB_1V8: C145.1 U20.2(VOUT_LDOVINT)
A2B_GPIO_INTR_43: J21.43 U37.AG25(PRG1_PRU1_GPO13)
A2B_GPIO_INTR_77: R215.2 U37.AJ25(PRG1_PRU1_GPO11)
A2B_GPIO_OUT_57: R222.2 R225.2 U37.AH21(PRG1_PRU0_GPO19)
A2B_GPIO_OUT_74: J21.74 U37.AH25(PRG1_PRU1_GPO12)
A2B_MCU_SCL: J21.24 U37.G27(WKUP_GPIO0_8)
A2B_MCU_SDA: J21.25 U37.G28(WKUP_GPIO0_7)
A2B_MCU_SPI_CLK: J21.59 RJ8.2 U37.E27(MCU_SPI0_CLK)
A2B_MCU_SPI_CS0: J21.62 U37.E25(MCU_SPI0_CS0)
A2B_MCU_SPI_D0: J21.60 RJ9.2 U37.E24(MCU_SPI0_D0)
A2B_MCU_SPI_D1: J21.61 RJ10.2 U37.E28(MCU_SPI0_D1)
A2B_SCL1: J21.79 R213.2 U37.T28(MMC2_DAT3)
A2B_SDA1: J21.80 R211.2 U37.T29(MMC2_DAT2)
A2B_SPI1_CLK: J21.82 R134.2
A2B_SPI1_CS0: J21.85 U37.W27(RGMII6_TD0)
A2B_SPI1_D0: J21.83 U37.V25(RGMII6_TD1)
A2B_SPI1_D1: J21.84 U37.W24(RGMII6_RD1)
A2B_SPORT0_CLK: J21.87 R109.2
A2B_SPORT0_D0: J21.88 R209.1 U37.AD20(PRG1_PRU0_GPO5)
A2B_SPORT0_D1: J21.31 U37.AE20(PRG1_PRU0_GPO7)
A2B_SPORT0_FS: J21.89 R120.2
A2B_SPORT1_CLK: J21.92 U37.AH24(PRG1_PRU1_GPO4)
A2B_SPORT1_D0: J21.91 U37.AD23(PRG1_PRU1_GPO3)
A2B_SPORT1_FS: J21.90 U37.AE23(PRG1_PRU1_GPO6)
A2B_WKUP_GPIO_0: J21.97 R423.1 SW2.1(A1) U37.F26(WKUP_GPIO0_0)
A2B_WKUP_GPIO_1: J21.96 R422.1 SW2.2(A2) U37.F25(WKUP_GPIO0_1)
A2B_WKUP_GPIO_2: J21.95 R421.1 SW2.3(A3) U37.F28(WKUP_GPIO0_2)
A2B_WKUP_GPIO_15: J21.94 RJ11.2 U37.J27(WKUP_GPIO0_15)
A2B_WKUP_UART0_RXD: J21.27 RJ15.3 U37.J29(WKUP_UART0_RXD)
A2B_WKUP_UART0_TXD: J21.26 RJ14.3 U37.J28(WKUP_UART0_TXD)
A2B_XREF_CLK_IN: R130.2 R219.2
A2B_XREF_CLK_OUT: R367.2 U37.W25(RGMII6_RD0)
A72_CONSOLE_RXD: R212.2 U37.AB2(UART0_RXD)
A72_CONSOLE_TXD: R216.1 U37.AB3(UART0_TXD) U51.11(2B1)
AMI: C66.1 R27.1 U19.13(AMI)
APL_RSTN: R295.1 U37.W3(MCAN1_RX)
APL_SCL: J11.1 R281.1 U67.6(SCL)
APL_SDA: J11.3 R287.1 U67.2(SDA)
AUDIO_EXT_REFCLK2: R130.1 U37.W26(RGMII6_RXC)
B3A: C62.1 L23.2 U19.9(B3A)
BOOTMODE0: R209.2 R419.1 SW2.5(A5)
BOOTMODE1: R115.2 RJ4.2
BOOTMODE2: RJ5.2 U37.AC29(PRG0_PRU0_GPO5)
BOOTMODE3: R128.2 RJ6.2
BOOTMODE4: R418.1 SW2.6(A6) U37.V6(TIMER_IO0)
BOOTMODE5: R417.1 SW2.7(A7) U37.V5(TIMER_IO1)
BOOTMODE6: R100.2 R416.1 SW2.8(A8)
BOOTMODE7: RJ7.2 U37.AB24(PRG0_PRU0_GPO17)
C_DP0_AUX_N: C401.1 U37.G6(DP0_AUXN)
C_DP0_AUX_P: C402.1 U37.F7(DP0_AUXP)
C_DP0_TX0_N: C427.1 U37.B11(SERDES4_TX0_N)
C_DP0_TX0_P: C428.1 U37.A12(SERDES4_TX0_P)
C_DP0_TX1_N: C411.1 U37.B10(SERDES4_TX1_N)
C_DP0_TX1_P: C412.1 U37.A11(SERDES4_TX1_P)
C_DP0_TX2_N: C425.1 U37.B8(SERDES4_TX2_N)
C_DP0_TX2_P: C426.1 U37.A9(SERDES4_TX2_P)
C_DP0_TX3_N: C413.1 U37.B7(SERDES4_TX3_N)
C_DP0_TX3_P: C414.1 U37.A8(SERDES4_TX3_P)
C_PCIE0_TX0_N: C509.1 U37.AF19(SERDES0_TX0_N)
C_PCIE0_TX0_P: C510.1 U37.AG18(SERDES0_TX0_P)
C_UB981_DOUT0_N: C831.1 U75.26(DOUT0-)
C_UB981_DOUT0_P: C832.1 U75.27(DOUT0+)
C_USB0_SS_TX_N: C494.1 U37.AF9(SERDES3_TX0_N)
C_USB0_SS_TX_P: C493.1 U37.AG8(SERDES3_TX0_P)
C_USB1_SS_TX_N: C496.1 U37.AF12(SERDES2_TX1_N)
C_USB1_SS_TX_P: C495.1 U37.AG11(SERDES2_TX1_P)
CAM_0_N: C827.1 U74.51(RIN0-)
CAM_0_P: C823.1 U74.50(RIN0+)
CAM_1_N: C835.1 U74.54(RIN1-)
CAM_1_P: C830.1 U74.53(RIN1+)
CAM_2_N: C829.1 U74.60(RIN2-)
CAM_2_P: C834.1 U74.59(RIN2+)
CAM_3_N: C822.1 U74.63(RIN3-)
CAM_3_P: C825.1 U74.62(RIN3+)
CAM_POWERON: R438.2 U62.3(IN)
CAN_POWER_ON_HV: Q2.2(G2) R392.1
CAN_WAKE: J13.10 R220.1 R406.2 RJ18.2
CAN_WKUP: R293.1 SW1.1(A1) SW1.2(A2) TP23.1 U27.47(GPIO4)
CANH_1: J13.4 R409.1 U50.13(CANH)
CANH_2: J13.9 R387.1 U44.7(CANH)
CANL_1: J13.3 R404.2 U50.12(CANL)
CANL_2: J13.8 R384.2 U44.6(CANL)
CHIMES_FSYNC: R116.2 U32.14(WCLK)
CHIMES_M_SCLK: R122.2 U32.15(BCLK) U32.16(MCLK)
CHIMES_NSTANDBY: R307.1 U32.2(RSTN) U37.AH23(PRG1_PRU0_GPO4)
CHIMES_SDIN: U32.13(DIN) U37.AG24(PRG1_PRU0_GPO13)
CHIMES_SDOUT: U32.18(GPIO/DOUT) U37.AD24(PRG1_PRU0_GPO14)
CON_DP0_AUX_N: D19.1(I/O) FL26.3 J18.17(AUX_CH_N) R240.1
CON_DP0_AUX_P: D20.1(I/O) FL26.2 J18.15(AUX_CH_P) R241.2
CON_DP0_HPD: J18.18(HPD) Q15.2(G2) R458.2 U78.1(IO)
CON_DP0_TX0_N: D23.1(I/O) FL31.3 J18.3(ML_L0_N)
CON_DP0_TX0_P: D24.1(I/O) FL31.2 J18.1(ML_L0_P)
CON_DP0_TX1_N: D18.1(I/O) FL28.3 J18.6(ML_L1_N)
CON_DP0_TX1_P: D17.1(I/O) FL28.2 J18.4(ML_L1_P)
CON_DP0_TX2_N: D21.1(I/O) FL30.3 J18.9(ML_L2_N)
CON_DP0_TX2_P: D22.1(I/O) FL30.2 J18.7(ML_L2_P)
CON_DP0_TX3_N: D15.1(I/O) FL29.3 J18.12(ML_L3_N)
CON_DP0_TX3_P: D16.1(I/O) FL29.2 J18.10(ML_L3_P)
CON_MMC1_CLK: P5.5(CLK) R340.2 U71.3(IO1)
CON_MMC1_CMD: P5.3(CMD) R344.2 U71.5(IO2)
CON_MMC1_DAT0: P5.7(DAT0) R335.2 U70.5(IO2)
CON_MMC1_DAT1: P5.8(DAT1) R322.2 U70.3(IO1)
CON_MMC1_DAT2: P5.1(DAT2) R350.2 U72.5(IO2)
CON_MMC1_DAT3: P5.2(DAT3) R347.2 U72.3(IO1)
CONN_USB1_DM: FL3.2 J2.2(D-)
CONN_USB1_DP: FL3.3 J2.3(D+)
CONN_USB2_DM: FL1.3 J1.2(D-)
CONN_USB2_DP: FL1.2 J1.3(D+)
CONN_USB_RXN0: FL36.3 J2.5(STDA_SSRX-) U65.5(D2-) U65.6(NC6)
CONN_USB_RXN1: FL38.3 J1.5(STDA_SSRX-) U66.5(D2-) U66.6(NC6)
CONN_USB_RXP0: FL36.2 J2.6(STDA_SSRX+) U65.4(D2+) U65.7(NC7)
CONN_USB_RXP1: FL38.2 J1.6(STDA_SSRX+) U66.4(D2+) U66.7(NC7)
CONN_USB_TXN0: FL35.3 J2.8(STDA_SSTX-) U65.2(D1-) U65.9(NC9)
CONN_USB_TXN1: FL37.3 J1.8(STDA_SSTX-) U66.2(D1-) U66.9(NC9)
CONN_USB_TXP0: FL35.2 J2.9(STDA_SSTX+) U65.1(D1+) U65.10(NC10)
CONN_USB_TXP1: FL37.2 J1.9(STDA_SSTX+) U66.1(D1+) U66.10(NC10)
CS_P: C769.1 Q4.1(S) Q5.1(S) R160.2 R180.1
CSI0_RX0_N: U37.B19(CSI0_RXN0) U74.24(CSI0_D0-)
CSI0_RX0_P: U37.A20(CSI0_RXP0) U74.25(CSI0_D0+)
CSI0_RX1_N: U37.D18(CSI0_RXN1) U74.26(CSI0_D1-)
CSI0_RX1_P: U37.C19(CSI0_RXP1) U74.27(CSI0_D1+)
CSI0_RX2_N: U37.D17(CSI0_RXN2) U74.28(CSI0_D2-)
CSI0_RX2_P: U37.C18(CSI0_RXP2) U74.29(CSI0_D2+)
CSI0_RX3_N: U37.E16(CSI0_RXN3) U74.30(CSI0_D3-)
CSI0_RX3_P: U37.E17(CSI0_RXP3) U74.31(CSI0_D3+)
CSI0_RXCLK_N: U37.B20(CSI0_RXCLKN) U74.22(CSI0_CLK-)
CSI0_RXCLK_P: U37.A21(CSI0_RXCLKP) U74.23(CSI0_CLK+)
CSI0_RXRCALIB: R366.1 U37.F16(CSI0_RXRCALIB)
CSI1_RXRCALIB: R358.1 U37.F15(CSI1_RXRCALIB)
D3B: C68.1 L25.2 U19.10(B3B)
DDR0_CAL0: R356.1 U37.H2(DDR0_CAL0)
DEBUGN: J10.3 U19.54(DEBUGN)
DEBUGP: J10.1 U19.55(DEBUGP)
DOUT0: U19.61(DOUT0) U23.2(I)
DOUT1: U19.58(DOUT1) U22.2(I)
DP0_AUX_N: C401.2 FL26.4
DP0_AUX_P: C402.2 FL26.1
DP0_CONFIG1: J18.13(CONFIG1) R456.1
DP0_CONFIG2: J18.14(CONFIG2) R457.1
DP0_HPD: Q15.3(D2) R465.1 U37.Y4(SPI0_CS1)
DP0_TX0_N: C427.2 FL31.4
DP0_TX0_P: C428.2 FL31.1
DP0_TX1_N: C411.2 FL28.4
DP0_TX1_P: C412.2 FL28.1
DP0_TX2_N: C425.2 FL30.4
DP0_TX2_P: C426.2 FL30.1
DP0_TX3_N: C413.2 FL29.4
DP0_TX3_P: C414.2 FL29.1
DSI0_TX0_N: U37.D11(DSI_TXN0) U75.57(DSI0_D0N)
DSI0_TX0_P: U37.C12(DSI_TXP0) U75.58(DSI0_D0P)
DSI0_TX1_N: U37.D12(DSI_TXN1) U75.55(DSI0_D1N)
DSI0_TX1_P: U37.C13(DSI_TXP1) U75.56(DSI0_D1P)
DSI0_TX2_N: U37.B13(DSI_TXN2) U75.53(DSI0_D2N)
DSI0_TX2_P: U37.A14(DSI_TXP2) U75.54(DSI0_D2P)
DSI0_TX3_N: U37.B14(DSI_TXN3) U75.51(DSI0_D3N)
DSI0_TX3_P: U37.A15(DSI_TXP3) U75.52(DSI0_D3P)
DSI0_TXCLK_N: U37.E10(DSI_TXCLKN) U75.59(DSI0_CLKN)
DSI0_TXCLK_P: U37.E11(DSI_TXCLKP) U75.60(DSI0_CLKP)
DSI_TX_CALIB: R361.1 U37.F12(DSI_TXRCALIB)
DSI_UB981_INTB: R437.2 R455.2 U37.AC4(UART1_CTSN)
EMU_RSTN: J15.6(NRESET) R156.2 R157.2
EN_3V3IO_LDSW: Q6.G R84.2 U20.53(GPIO11) U28.3(ON) U46.1(EN/UVLO) U54.13(EN)
EN_DRV_OUT: TP34.1 U27.29(EN_DRV)
EN_MCU3V3IO_LDSW: R289.2 R294.1 U68.3(ON)
ENET_EN: R364.1 U37.T27(MMC2_DAT1)
ENET_INH: R369.1 U37.W23(RGMII6_TD3) U42.10(INH)
ENET_INTSN: R362.1 R363.1 U37.V23(RGMII6_RX_CTL)
ENET_WAKE: R368.1 U37.Y23(PRG1_PRU1_GPO8) U42.8(WAKE)
EXT_TDI: J15.5(TDI) U48.2(I)
EXT_TDO: J15.4(TDO) U47.4(O)
EXT_TMS: J15.2(TMS) U49.2(I)
FB: R167.1 R175.2 U46.11(FB)
FB_5141: R123.2 R124.1 U33.19(FB)
FMA: C71.1 C79.1 L26.2 U19.8(FMA)
FMB: C67.1 C77.1 L24.2 U19.11(FMB)
FPD_DOUT0_N: FL41.3 J16.3
FPD_DOUT0_P: FL41.2 J16.1
G720_VDD1A: C307.1 R152.1 U42.9(NC9)
G720_VDD1B: C332.1 R176.1 U42.21(NC21)
G720_VDDIO: C768.1 R165.1 U42.34(TX_ER)
G720_VSLEEP: R357.1 R364.2 U42.7(EN)
H_DDR_RET_1V1: R132.2 U20.47(GPIO4) U37.P6(DDR_RET)
H_MCU_INT#: R151.2 R284.1 U20.14(NINT) U27.14(NINT)
H_MCU_PORZ_1V8: R381.1 TP55.1 U27.25(NRSTOUT) U37.H23(MCU_PORZ) U45.2(B)
H_MCU_SAFETY_ERRZ: R174.2 U77.2(A)
H_MMC1_CLK: R336.2 R340.1 U37.P25(MMC1_CLK)
H_MMC1_CMD: R344.1 R346.2 U37.R29(MMC1_CMD)
H_MMC1_D0: R335.1 R339.2 U37.R24(MMC1_DAT0)
H_MMC1_D1: R320.2 R322.1 U37.P24(MMC1_DAT1)
H_MMC1_D2: R350.1 R351.2 U37.R25(MMC1_DAT2)
H_MMC1_D3: R345.2 R347.1 U37.R26(MMC1_DAT3)
H_MMC1_SDCD: R319.1 R321.2 U37.P23(MMC1_SDCD)
H_PMIC_POWER_EN1: RJ17.3 U37.G23(PMIC_POWER_EN1)
H_SOC_PORZ_1V8: R290.1 TP35.1 U27.53(GPIO11) U37.J24(PORZ)
HDRV1_N: C361.2 L43.1 Q5.5(D) Q7.1(S) U46.28(SW1)
HDRV1_P: R202.2 U46.27(HDRV1)
HDRV2_N: C333.1 D9.1(CATHODE) D10.2(ANODE) L43.2 Q3.1(S) Q4.5(D) U46.18(SW2)
HDRV2_P: R150.1 U46.19(HDRV2)
I2C0_SCL: R281.2 R282.2 U37.AC5(I2C0_SCL)
I2C0_SDA: R287.2 R288.2 U37.AA5(I2C0_SDA)
I2C1_SCL: R233.2 U37.Y6(I2C1_SCL) U75.47(I2C_SCL)
I2C1_SDA: R228.2 U37.AA6(I2C1_SDA) U75.48(I2C_SDA)
I2C3_SCL: R121.2 U14.15(SCL) U32.19(SCL/SSZ) U37.T26(MMC2_CLK)
I2C3_SDA: R118.2 U14.16(SDA) U32.20(SDA/MOSI) U37.T25(MMC2_CMD)
I2C4_SCL: R30.2 U37.AD19(PRG1_MDIO0_MDIO)
I2C4_SDA: R28.2 U37.AD18(PRG1_MDIO0_MDC)
I2C6_SCL: R126.2 U37.AA3(SPI0_D1) U74.12(I2C_SCL)
I2C6_SDA: R131.2 U37.W1(I3C0_SDA) U74.11(I2C_SDA)
ICN: R64.2 U19.82(ICN)
LDRV1: R173.2 U46.25(LDRV1)
LDRV2: R172.1 U46.21(LDRV2)
LEOA_GPIO3: R294.2 U27.46(GPIO3)
LEOA_GPIO7: U27.18(GPIO7) U77.4(Y)
LEOA_GPIO8: R105.2 U27.41(GPIO8)
LEOA_GPIO9: R291.2 U27.19(GPIO9)
LEOA_GPIO10: R183.2 RJ17.2 U27.42(GPIO10)
LEOA_OSC32KCAP: C578.1 U27.40(OSC32KCAP)
LEOA_OSC32KIN: C593.2 U27.38(OSC32KIN) Y8.2
LEOA_OSC32KOUT: C592.2 U27.39(OSC32KOUT) Y8.1
LEOA_SCLK: U20.23(GPIO5) U27.23(GPIO5)
LEOA_SDATA: U20.24(GPIO6) U27.24(GPIO6)
LEOA_WDOG_DISABLE: R105.1 RJ3.2
LEOB_GPIO1: TP16.1 U20.32(GPIO1)
LEOB_GPIO3: TP32.1 U20.46(GPIO3)
LEOB_GPIO7: TP14.1 U20.18(GPIO7)
LEOB_GPIO8: TP19.1 U20.41(GPIO8)
LEOB_GPIO9: TP13.1 U20.19(GPIO9)
LEOB_GPIO10: R285.2 R286.1 U20.42(GPIO10)
LFDSI: C386.1 U75.49(LFDSI)
LFT: C828.1 U75.20(LFT)
LM5141_CS: C262.2 R129.1 R133.2 U33.18(CS)
LM5141_HB: C263.2 D8.1(CATHODE) U33.11(HB)
LM5141_HO: R326.2 U33.13(HO)
LM5141_HOL: R327.1 U33.14(HOL)
LM5141_LO: R310.2 U33.8(LO)
LM5141_LOL: R309.1 U33.7(LOL)
LM5141_SW: C226.2 C263.1 D7.1(CATHODE) L39.1 Q10.5(D) Q11.5(D) Q12.1(S) Q13.1(S) R133.1 U33.12(SW)
LM5141_VOUT: C262.1 R127.1 R129.2 U33.17(VOUT)
LPDDR4_CA0: U37.G4(DDR0_CA0) U40.H2(CA0_A) U40.R2(CA0_B)
LPDDR4_CA1: U37.H3(DDR0_CA1) U40.J2(CA1_A) U40.P2(CA1_B)
LPDDR4_CA2: U37.K5(DDR0_CA2) U40.H9(CA2_A) U40.R9(CA2_B)
LPDDR4_CA3: U37.J4(DDR0_CA3) U40.H10(CA3_A) U40.R10(CA3_B)
LPDDR4_CA4: U37.K2(DDR0_CA4) U40.H11(CA4_A) U40.R11(CA4_B)
LPDDR4_CA5: U37.H5(DDR0_CA5) U40.J11(CA5_A) U40.P11(CA5_B)
LPDDR4_CK_C: U37.J1(DDR0_CKN) U40.J9(CK_C_A) U40.P9(CK_C_B)
LPDDR4_CK_T: U37.H1(DDR0_CKP) U40.J8(CK_T_A) U40.P8(CK_T_B)
LPDDR4_CKE0: U37.G3(DDR0_CKE0) U40.J4(CKE0_A) U40.P4(CKE0_B)
LPDDR4_CKE1: U37.J3(DDR0_CKE1) U40.J5(CKE1_A) U40.P5(CKE1_B)
LPDDR4_CSN0_0: U37.J5(DDR0_CSN0_0) U40.H4(CS0_A)
LPDDR4_CSN0_1: U37.K3(DDR0_CSN0_1) U40.R4(CS0_B)
LPDDR4_CSN1_0: U37.G5(DDR0_CSN1_0) U40.H3(CS1_A)
LPDDR4_CSN1_1: U37.J2(DDR0_CSN1_1) U40.R3(CS1_B)
LPDDR4_DM0_DBI0#: U37.A3(DDR0_DM0) U40.C3(DMI0_A)
LPDDR4_DM1_DBI1#: U37.E4(DDR0_DM1) U40.C10(DMI1_A)
LPDDR4_DM2_DBI2#: U37.N1(DDR0_DM2) U40.Y3(DMI0_B)
LPDDR4_DM3_DBI3#: U37.R5(DDR0_DM3) U40.Y10(DMI1_B)
LPDDR4_DQ0: U37.A5(DDR0_DQ0) U40.B2(DQ0_A)
LPDDR4_DQ1: U37.A6(DDR0_DQ1) U40.C2(DQ1_A)
LPDDR4_DQ2: U37.B5(DDR0_DQ2) U40.E2(DQ2_A)
LPDDR4_DQ3: U37.C2(DDR0_DQ3) U40.F2(DQ3_A)
LPDDR4_DQ4: U37.B4(DDR0_DQ4) U40.F4(DQ4_A)
LPDDR4_DQ5: U37.C3(DDR0_DQ5) U40.E4(DQ5_A)
LPDDR4_DQ6: U37.A2(DDR0_DQ6) U40.C4(DQ6_A)
LPDDR4_DQ7: U37.A4(DDR0_DQ7) U40.B4(DQ7_A)
LPDDR4_DQ8: U37.D1(DDR0_DQ8) U40.B11(DQ8_A)
LPDDR4_DQ9: U37.C4(DDR0_DQ9) U40.C11(DQ9_A)
LPDDR4_DQ10: U37.F1(DDR0_DQ10) U40.E11(DQ10_A)
LPDDR4_DQ11: U37.G2(DDR0_DQ11) U40.F11(DQ11_A)
LPDDR4_DQ12: U37.F2(DDR0_DQ12) U40.F9(DQ12_A)
LPDDR4_DQ13: U37.F3(DDR0_DQ13) U40.E9(DQ13_A)
LPDDR4_DQ14: U37.D3(DDR0_DQ14) U40.C9(DQ14_A)
LPDDR4_DQ15: U37.F5(DDR0_DQ15) U40.B9(DQ15_A)
LPDDR4_DQ16: U37.L5(DDR0_DQ16) U40.AA2(DQ0_B)
LPDDR4_DQ17: U37.M5(DDR0_DQ17) U40.Y2(DQ1_B)
LPDDR4_DQ18: U37.N5(DDR0_DQ18) U40.V2(DQ2_B)
LPDDR4_DQ19: U37.L4(DDR0_DQ19) U40.U2(DQ3_B)
LPDDR4_DQ20: U37.L2(DDR0_DQ20) U40.U4(DQ4_B)
LPDDR4_DQ21: U37.L1(DDR0_DQ21) U40.V4(DQ5_B)
LPDDR4_DQ22: U37.N2(DDR0_DQ22) U40.Y4(DQ6_B)
LPDDR4_DQ23: U37.N4(DDR0_DQ23) U40.AA4(DQ7_B)
LPDDR4_DQ24: U37.T3(DDR0_DQ24) U40.AA11(DQ8_B)
LPDDR4_DQ25: U37.T2(DDR0_DQ25) U40.Y11(DQ9_B)
LPDDR4_DQ26: U37.P2(DDR0_DQ26) U40.V11(DQ10_B)
LPDDR4_DQ27: U37.P3(DDR0_DQ27) U40.U11(DQ11_B)
LPDDR4_DQ28: U37.P5(DDR0_DQ28) U40.U9(DQ12_B)
LPDDR4_DQ29: U37.R4(DDR0_DQ29) U40.V9(DQ13_B)
LPDDR4_DQ30: U37.T4(DDR0_DQ30) U40.Y9(DQ14_B)
LPDDR4_DQ31: U37.T5(DDR0_DQ31) U40.AA9(DQ15_B)
LPDDR4_DQS0_N: U37.B1(DDR0_DQS0N) U40.E3(DQS0_C_A)
LPDDR4_DQS0_P: U37.B2(DDR0_DQS0P) U40.D3(DQS0_T_A)
LPDDR4_DQS1_N: U37.E2(DDR0_DQS1N) U40.E10(DQS1_C_A)
LPDDR4_DQS1_P: U37.E3(DDR0_DQS1P) U40.D10(DQS1_T_A)
LPDDR4_DQS2_N: U37.M2(DDR0_DQS2N) U40.V3(DQS0_C_B)
LPDDR4_DQS2_P: U37.M3(DDR0_DQS2P) U40.W3(DQS0_T_B)
LPDDR4_DQS3_N: U37.R1(DDR0_DQS3N) U40.V10(DQS1_C_B)
LPDDR4_DQS3_P: U37.R2(DDR0_DQS3P) U40.W10(DQS1_T_B)
LPDDR4_ODT_CA_A: R359.1 R365.2 U40.G2(ODT_CA_A)
LPDDR4_ODT_CA_B: R349.1 R352.2 U40.T2(ODT_CA_B)
LPDDR4_RST#: R353.1 U37.K6(DDR0_RESETN) U40.T11(RESET_N)
LPDDR4_ZQ0: R373.2 U40.A5(ZQ0)
LPDDR4_ZQ1: R374.2 U40.A8(ZQ1)
LS2_CT: C181.1 U28.6(CT)
LS3_CT: C575.1 U68.6(CT)
MCAN_EN: R390.1 U37.F29(WKUP_GPIO0_6)
MCAN_NFAULT: R407.1 U37.F27(WKUP_GPIO0_3)
MCASP1_ACLKX_BOOTMODE6: R94.1 R100.1 U37.AB27(PRG0_PRU1_GPO5)
MCASP1_AFSX: R93.1 U37.AA28(PRG0_PRU1_GPO8)
MCASP2_AXR3_BOOTMODE3: R128.1 U37.Y25(PRG0_PRU1_GPO17)
MCASP3_ACLKX: R109.1 U37.AG20(PRG1_PRU0_GPO9)
MCASP3_AFSX: R120.1 U37.AD21(PRG1_PRU0_GPO10)
MCASP7_ACLKX: R122.1 U37.AF24(PRG1_PRU0_GPO11)
MCASP7_AFSX: R116.1 U37.AJ24(PRG1_PRU0_GPO12)
MCU_ADC0_AIN0: J21.108 U37.K25(MCU_ADC0_AIN0)
MCU_ADC0_AIN1: J21.107 U37.K26(MCU_ADC0_AIN1)
MCU_ADC0_AIN2: J21.106 U37.K28(MCU_ADC0_AIN2)
MCU_ADC0_AIN3: J21.105 U37.L28(MCU_ADC0_AIN3)
MCU_ADC0_AIN4: TP46.1(TP) U37.K24(MCU_ADC0_AIN4)
MCU_ADC0_AIN5: TP48.1(TP) U37.K27(MCU_ADC0_AIN5)
MCU_ADC0_AIN6: TP47.1(TP) U37.K29(MCU_ADC0_AIN6)
MCU_BOOTMODE6: R420.1 SW2.4(A4) U37.H29(WKUP_GPIO0_14)
MCU_BOOTMODE8: RJ12.2 RJ14.1 U37.G29(WKUP_GPIO0_12)
MCU_BOOTMODE9: RJ13.2 RJ15.1 U37.H28(WKUP_GPIO0_13)
MCU_CAN0_STBZ: R403.1 U37.H26(WKUP_GPIO0_10)
MCU_CAN1_STBZ: R386.1 U37.H27(WKUP_GPIO0_11)
MCU_CONSOLE_RXD: R223.2 RJ15.2
MCU_CONSOLE_TXD: RJ14.2 U55.11(2B1)
MCU_DMTIMER2: TP43.1(TP) U37.A28(MCU_RGMII1_TD3) U38.2(I)
MCU_DMTIMER3: C64.2 TP6.1(TP) U37.A27(MCU_RGMII1_TD2)
MCU_DMTIMER4: C354.1 TP59.1(TP) U37.A25(MCU_RGMII1_RD3)
MCU_DMTIMER5: C451.1 TP71.1(TP) U37.D24(MCU_RGMII1_RD2)
MCU_DMTIMER8: RJ17.1 TP58.1(TP) U37.D26(MCU_I3C0_SCL)
MCU_DMTIMER9: R286.2 TP20.1(TP) U37.D25(MCU_I3C0_SDA)
MCU_HYPERBUS0_CS1#: R185.1 U37.E22(MCU_OSPI1_CSN1)
MCU_HYPERBUS0_RESETO#: R186.2 U73.A2(RFU1)
MCU_I2C0_SCL: R163.2 U27.32(GPIO1) U37.J26(MCU_I2C0_SCL)
MCU_I2C0_SDA: R166.2 U27.33(GPIO2) U37.H25(MCU_I2C0_SDA)
MCU_MCAN0_RX: R389.1 U37.C29(MCU_MCAN0_RX)
MCU_MCAN0_TX: R388.1 U37.D29(MCU_MCAN0_TX)
MCU_MCAN1_RX: R372.1 U37.G24(WKUP_GPIO0_5)
MCU_MCAN1_TX: R371.1 U37.G25(WKUP_GPIO0_4)
MCU_OSPI0_CLK_N: R194.1 R378.2 U73.B1(RFU3)
MCU_OSPI0_CLK_P: R190.1 R383.2 U73.B2(C)
MCU_OSPI0_CS0#: R195.1 U37.F19(MCU_OSPI0_CSN0) U73.C2(S#)
MCU_OSPI0_D0: R206.2 U37.D20(MCU_OSPI0_D0) U73.D3(DQ0)
MCU_OSPI0_D1: R203.2 U37.G19(MCU_OSPI0_D1) U73.D2(DQ1)
MCU_OSPI0_D2: R196.2 U37.G20(MCU_OSPI0_D2) U73.C4(DQ2/W#)
MCU_OSPI0_D3: R204.2 U37.F20(MCU_OSPI0_D3) U73.D4(DQ3)
MCU_OSPI0_D4: R201.2 U37.F21(MCU_OSPI0_D4) U73.D5(DQ4)
MCU_OSPI0_D5: R205.2 U37.E21(MCU_OSPI0_D5) U73.E3(DQ5)
MCU_OSPI0_D6: R207.2 U37.B22(MCU_OSPI0_D6) U73.E2(DQ6)
MCU_OSPI0_D7: R208.2 U37.G21(MCU_OSPI0_D7) U73.E1(DQ7)
MCU_OSPI0_DQS: R197.2 R200.2 U37.D21(MCU_OSPI0_DQS)
MCU_OSPI0_ECC_FAIL: R192.1 U37.B23(MCU_OSPI1_DQS)
MCU_OSPI_RST#: U45.4(Y) U73.A4(RESET#)
MCU_PORZ_OUT: Q8.2(G2) R242.1 TP66.1 U37.B28(MCU_PORZ_OUT)
MCU_RESETSTATZ: R169.1 TP51.1 U37.C27(MCU_RESETSTATZ)
MCU_RESETZ: R155.2 R156.1 TP49.1 U37.D28(MCU_RESETZ)
MCUBOOT_BUFF_ENZ: C385.1 J21.99 Q8.6(D2) R221.2 U38.1(OE) U55.15(1O\E\)
MDIO0_MDC: U37.V24(MDIO0_MDC) U42.1(MDC)
MDIO0_MDIO: R154.2 U37.V26(MDIO0_MDIO) U42.36(MDIO)
MMC0_CALPAD: R331.2 U37.AE1(MMC0_CALPAD)
MMC0_CLK: R119.2 R317.1 R318.2
MMC0_CMD: R314.2 U31.P5(CMD) U37.AE3(MMC0_CMD)
MMC0_DAT0: R297.2 U31.K2(DAT0) U37.AG2(MMC0_DAT0)
MMC0_DAT1: R298.2 U31.N2(DAT1) U37.AH1(MMC0_DAT1)
MMC0_DAT2: R311.2 U31.K3(DAT2) U37.AG3(MMC0_DAT2)
MMC0_DAT3: R312.2 U31.N3(DAT3) U37.AF4(MMC0_DAT3)
MMC0_DAT4: R325.2 U31.N8(DAT4) U37.AE5(MMC0_DAT4)
MMC0_DAT5: R324.2 U31.K8(DAT5) U37.AF3(MMC0_DAT5)
MMC0_DAT6: R330.2 U31.N9(DAT6) U37.AG1(MMC0_DAT6)
MMC0_DAT7: R329.2 U31.K9(DAT7) U37.AF2(MMC0_DAT7)
MMC0_DS: R302.1 U37.AE4(MMC0_DS)
MMC_PWR_ON: R142.2 U36.3(ON) U37.AG29(PRG0_PRU1_GPO16)
NEO_RESETN: R2.2 U2.8(RESET_N) U37.AC2(UART0_CTSN)
NEO_RXD: R15.2 U37.AA4(UART1_RXD)
NEO_TIMEPULSE: R3.2 R4.1 U37.T24(MMC2_DAT0)
NEO_TXD: R16.2 U37.AB4(UART1_TXD)
NTRST: J15.9(NTRST) R412.2 RJ19.3
OSC1_XI: R141.1 U37.P29(OSC1_XI)
OSC1_XO: R143.1 U37.P27(OSC1_XO)
OSPI0_ECC_FAIL/MCU_HYPERBUS0_IN: R187.1 R192.2 U73.A5(DNU1)
OSPI_DQS_R: R197.1 U73.C3(DQS)
OUT1M3: C76.1 L11.1 U14.24(OUT_1M)
OUT1P3: C75.1 L10.1 U14.26(OUT_1P)
OUT2M3: C500.1 L55.1 U14.29(OUT_2M)
OUT2P3: C501.1 L56.1 U14.31(OUT_2P)
OUT3M3: C74.1 L9.1 U14.36(OUT_3M)
OUT3P3: C73.1 L8.1 U14.38(OUT_3P)
OUT4M3: C502.1 L57.1 U14.41(OUT_4M)
OUT4P3: C503.1 L58.1 U14.43(OUT_4P)
PCIE0_CLKREQ#: J20.7(CLKREQ#) R41.2 U37.W2(I3C0_SCL)
PCIE0_PERSTZ: J20.22(PERST#) U10.4(Y)
PCIE0_RC_RSTZ: R32.1 U10.1(A) U37.AJ26(PRG1_PRU1_GPO16)
PCIE0_REFCLK_N: J20.11(REFCLK-) R328.1 U37.AE17(PCIE_REFCLK0N)
PCIE0_REFCLK_P: J20.13(REFCLK+) R338.1 U37.AD16(PCIE_REFCLK0P)
PCIE0_RX0_N: J20.23(PERN0) U37.AH19(SERDES0_RX0_N)
PCIE0_RX0_P: J20.25(PERP0) U37.AJ18(SERDES0_RX0_P)
PCIE0_SCL: J20.30(SMB_CLK) R30.1 R31.2
PCIE0_SDA: J20.32(SMB_DATA) R28.1 R29.2
PCIE0_TX0_N: C509.2 J20.31(PETN0)
PCIE0_TX0_P: C510.2 J20.33(PETP0)
PCIE0_USB_D+: FL2.3 U16.14(USB_DP_DN2)
PCIE0_USB_D-: FL2.2 U16.15(USB_DM_DN2)
PCIE0_W_DISABLE#: J20.20(W_DISABLE#) R21.1 U37.AJ27(PRG1_PRU1_GPO15)
PCIE0_WAKE#: J20.1(WAKE#) R42.2 U37.AH26(PRG1_PRU1_GPO14)
PG_LM5141: R72.2 R323.1 TP33.1(TP) U33.21(PG) U57.6(EN)
PG_LM5175: C313.2 R164.2 R271.1 TP53.1(TP) U46.17(PGOOD)
PG_LM53603: R48.2 TP7.1(TP) U8.8(RESETN) U11.7(EN)
PMICB_EN: R277.2 U20.20(NPWRON/ENABLE)
PMICB_FB3: R303.1 R304.1 U20.49(FB_B3)
PMICB_FB4: R305.1 R306.1 U20.50(FB_B4)
PWR_SW_CNTL_DSI0: R256.1 U37.AB1(UART0_RTSN) U63.4(EN)
RESET_REQZ: R157.1 R158.2 TP50.1 U37.C28(RESET_REQZ)
RESETSTATZ: R348.1 TP54.1 U37.T6(RESETSTATZ)
RGMII5_RD0: R179.2 U37.T23(RGMII5_RD0) U42.26(RX_D0)
RGMII5_RD1: R178.2 U37.R23(RGMII5_RD1) U42.25(RX_D1)
RGMII5_RD2: R177.2 U37.U24(RGMII5_RD2) U42.24(RX_D2)
RGMII5_RD3: U37.U27(RGMII5_RD3) U42.23(RX_D3)
RGMII5_RX_CTL: U37.U26(RGMII5_RX_CTL) U42.15(RX_DV/CRS_DIV/RX_CTRL)
RGMII5_RXC: U37.U25(RGMII5_RXC) U42.27(RX_CLK)
RGMII5_TD0: U37.U28(RGMII5_TD0) U42.33(TX_D0)
RGMII5_TD1: U37.V27(RGMII5_TD1) U42.32(TX_D1)
RGMII5_TD2: U37.V29(RGMII5_TD2) U42.31(TX_D2)
RGMII5_TD3: U37.V28(RGMII5_TD3) U42.30(TX_D3)
RGMII5_TX_CTL: U37.U23(RGMII5_TX_CTL) U42.29(TX_EN/TX_CTRL)
RGMII5_TXC: U37.U29(RGMII5_TXC) U42.28(TX_CLK)
SEL_SDIO_3V3_1V8N: R73.1 TP17.1 U20.33(GPIO2) U37.AH29(PRG0_PRU0_GPO13)
SERDES0_REXT: R334.1 U37.AE18(SERDES0_REXT)
SERDES1_REXT: R333.1 U37.AE13(SERDES1_REXT)
SERDES2_REXT: R341.1 U37.AD13(SERDES2_REXT)
SERDES3_REXT: R332.1 U37.AE8(SERDES3_REXT)
SERDES4_REXT: R360.1 U37.F9(SERDES4_REXT)
SOC_EMU0: J15.19(TRD0.1) R414.2 U37.C26(EMU0)
SOC_EMU1: J15.21(TRD0.2) R415.2 U37.B29(EMU1)
SOC_HYPERBUS0_RESET#: RJ16.3 U37.E19(MCU_OSPI0_CSN1)
SOC_MCU_OSPI0_CLK_R: R383.1 U37.E20(MCU_OSPI0_CLK)
SOC_MCU_OSPI0_LBCLKO_R: R378.1 U37.C21(MCU_OSPI0_LBCLKO)
SOC_PORZ_OUT: R136.1 U10.2(B) U16.11(GRSTZ) U35.1(OE) U37.U1(PORZ_OUT) U42.3(RESET_N)
SOC_PWR_EN: R72.1 U27.20(NPWRON/ENABLE)
SOC_SAFETY_ERRZ: R135.2 R463.1 TP40.1 U77.1(B)
SOC_TCK: J15.3(TCK) R410.2 R411.2 U37.E29(TCK)
SOC_TDI: U37.V1(TDI) U48.4(O)
SOC_TDO: U37.V3(TDO) U47.2(I)
SOC_TMS: R393.2 U37.V2(TMS) U49.4(O)
SOC_TRST#: RJ19.2 U37.F24(TRSTN)
SOC_WKUP_I2C0_SCL: R63.2 U13.6(SCL) U20.31(SCL_I2C1/SCK_SPI) U27.31(SCL_I2C1/SCK_SPI) U37.J25(WKUP_I2C0_SCL)
SOC_WKUP_I2C0_SDA: R62.2 U13.5(SDA) U20.30(SDA_I2C1/SDI_SPI) U27.30(SDA_I2C1/SDI_SPI) U37.H24(WKUP_I2C0_SDA)
SPI5_CLK: R134.1 U37.W29(RGMII6_TXC)
SPI6_CLK_BOOTMODE1: R110.1 R115.1 U37.AC22(PRG1_PRU1_GPO17)
SPKM: J4.2 U32.9(SPKM)
SPKP: J4.1 U32.12(SPKP)
TPA6304_NSTANDBY: R69.1 U14.17(STANDBYN) U37.AJ23(PRG1_PRU0_GPO3)
TRD1_N: C316.1 J13.2 R170.1
TRD1_P: C312.1 J13.1 R161.1
TRD_N: C319.1 L42.1 U42.13(TRD_N)
TRD_P: C311.1 L40.1 U42.12(TRD_P)
TRSTPD: J15.8(TRSTPD) R425.1 RJ19.1
TUNER0_IQ_ACLKR: R89.2 TP30.1(TP) U37.AE27(PRG0_PRU0_GPO2)
TUNER0_IQ_AXR0: R90.2 TP26.1(TP) U37.AF28(PRG0_PRU0_GPO0)
TUNER0_IQ_AXR1: R88.2 TP25.1(TP) U37.AE28(PRG0_PRU0_GPO1)
TUNER0_IQ_FSR: R87.2 TP29.1(TP) U37.AD26(PRG0_PRU0_GPO3)
TUNER1_IQ_ACLKR: R91.2 TP31.1(TP) U37.AA27(PRG0_MDIO0_MDC)
TUNER1_IQ_AXR0: R86.2 TP24.1(TP) U37.AE25(PRG0_PRU1_GPO14)
TUNER1_IQ_AXR1: R85.2 TP28.1(TP) U37.AF29(PRG0_PRU1_GPO15)
TUNER1_IQ_FSR: R92.2 TP27.1(TP) U37.Y26(PRG0_MDIO0_MDIO)
TUNER_AGND: C142.1 PL1.1
TUNER_AUDIO_ACLKX: R94.2 TP22.1(TP) U19.60(DCLK0)
TUNER_AUDIO_AXR0: U19.67(DIN3) U37.AE29(PRG0_PRU1_GPO0)
TUNER_AUDIO_AXR1: U19.64(DIN4) U37.AD28(PRG0_PRU1_GPO1)
TUNER_AUDIO_AXR10: R82.2 U37.AD27(PRG0_PRU1_GPO2)
TUNER_AUDIO_AXR11: R81.2 U37.AC25(PRG0_PRU1_GPO3)
TUNER_AUDIO_FSX: R93.2 TP21.1(TP) U19.59(DFSO)
TUNER_IN1M: C23.1 R9.2 U19.20(AIN0N)
TUNER_IN1P: C18.1 R8.1 U19.19(AIN0P)
TUNER_IN2M: C53.1 R20.2 U19.22(AIN1N)
TUNER_IN2P: C36.1 R14.1 U19.21(AIN1P)
TUNER_IN3M: C95.1 R52.2 U19.24(AIN2N)
TUNER_IN3P: C81.1 R46.1 U19.23(AIN2P)
TUNER_IN4M: C108.1 R65.2 U19.26(AIN3N)
TUNER_IN4P: C103.1 R58.1 U19.25(AIN3P)
TUNER_IN5M: C160.1 R78.2 U19.28(AIN4N)
TUNER_IN5P: C148.1 R77.1 U19.27(AIN4P)
TUNER_IN6M: C195.1 R101.2 U19.30(AIN5N)
TUNER_IN6P: C178.1 R97.1 U19.29(AIN5P)
TUNER_INTB_CHIP0: R68.1 U19.37(INTB) U37.W28(RGMII6_TD2)
TUNER_OUT0: C131.2 U19.84(AOUT0)
TUNER_OUT1: C130.2 U19.85(AOUT1)
TUNER_OUT2: C129.2 U19.86(AOUT2)
TUNER_OUT3: C128.2 U19.87(AOUT3)
TUNER_RSTB_CHIP0: R280.1 U19.31(RSTB) U37.Y27(RGMII6_RD2)
TUNER_SPI_CS0: U19.41(SSB/A1) U37.AC21(PRG1_PRU1_GPO7)
TUNER_SPI_D0: U19.39(MOSI/SDA) U37.AJ22(PRG1_PRU1_GPO18)
TUNER_SPI_D1: U19.38(MISO/A0) U37.AH22(PRG1_PRU1_GPO19)
TUNER_SPI_SCLK: R110.2 U19.40(SCLK/SCL)
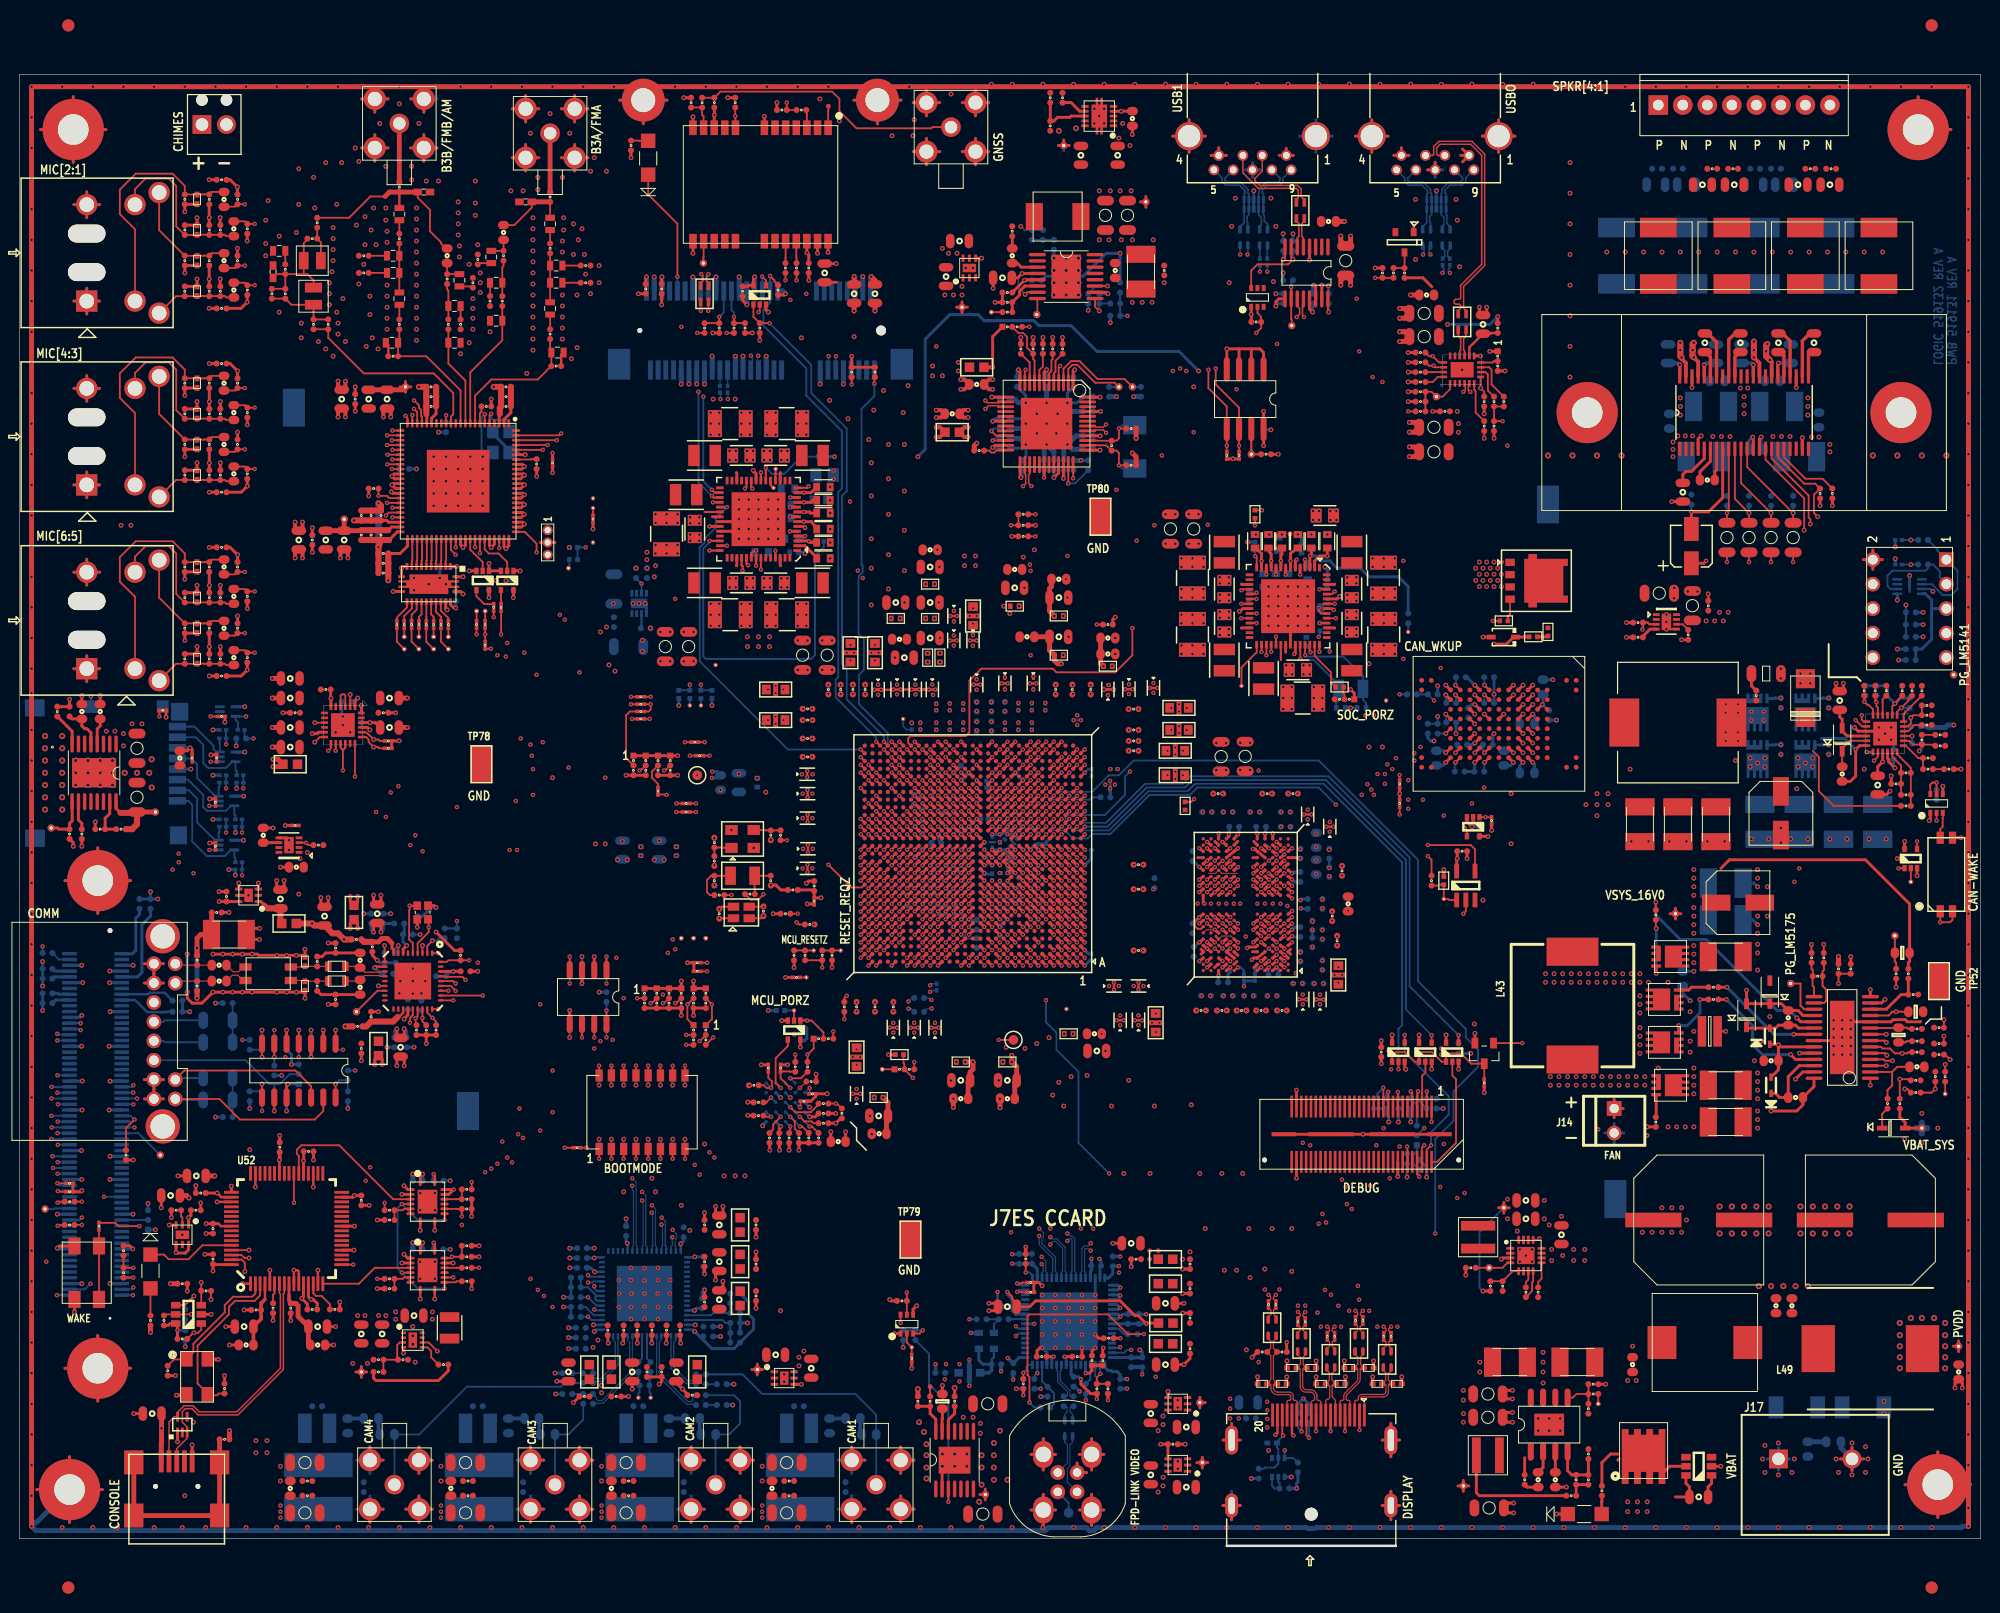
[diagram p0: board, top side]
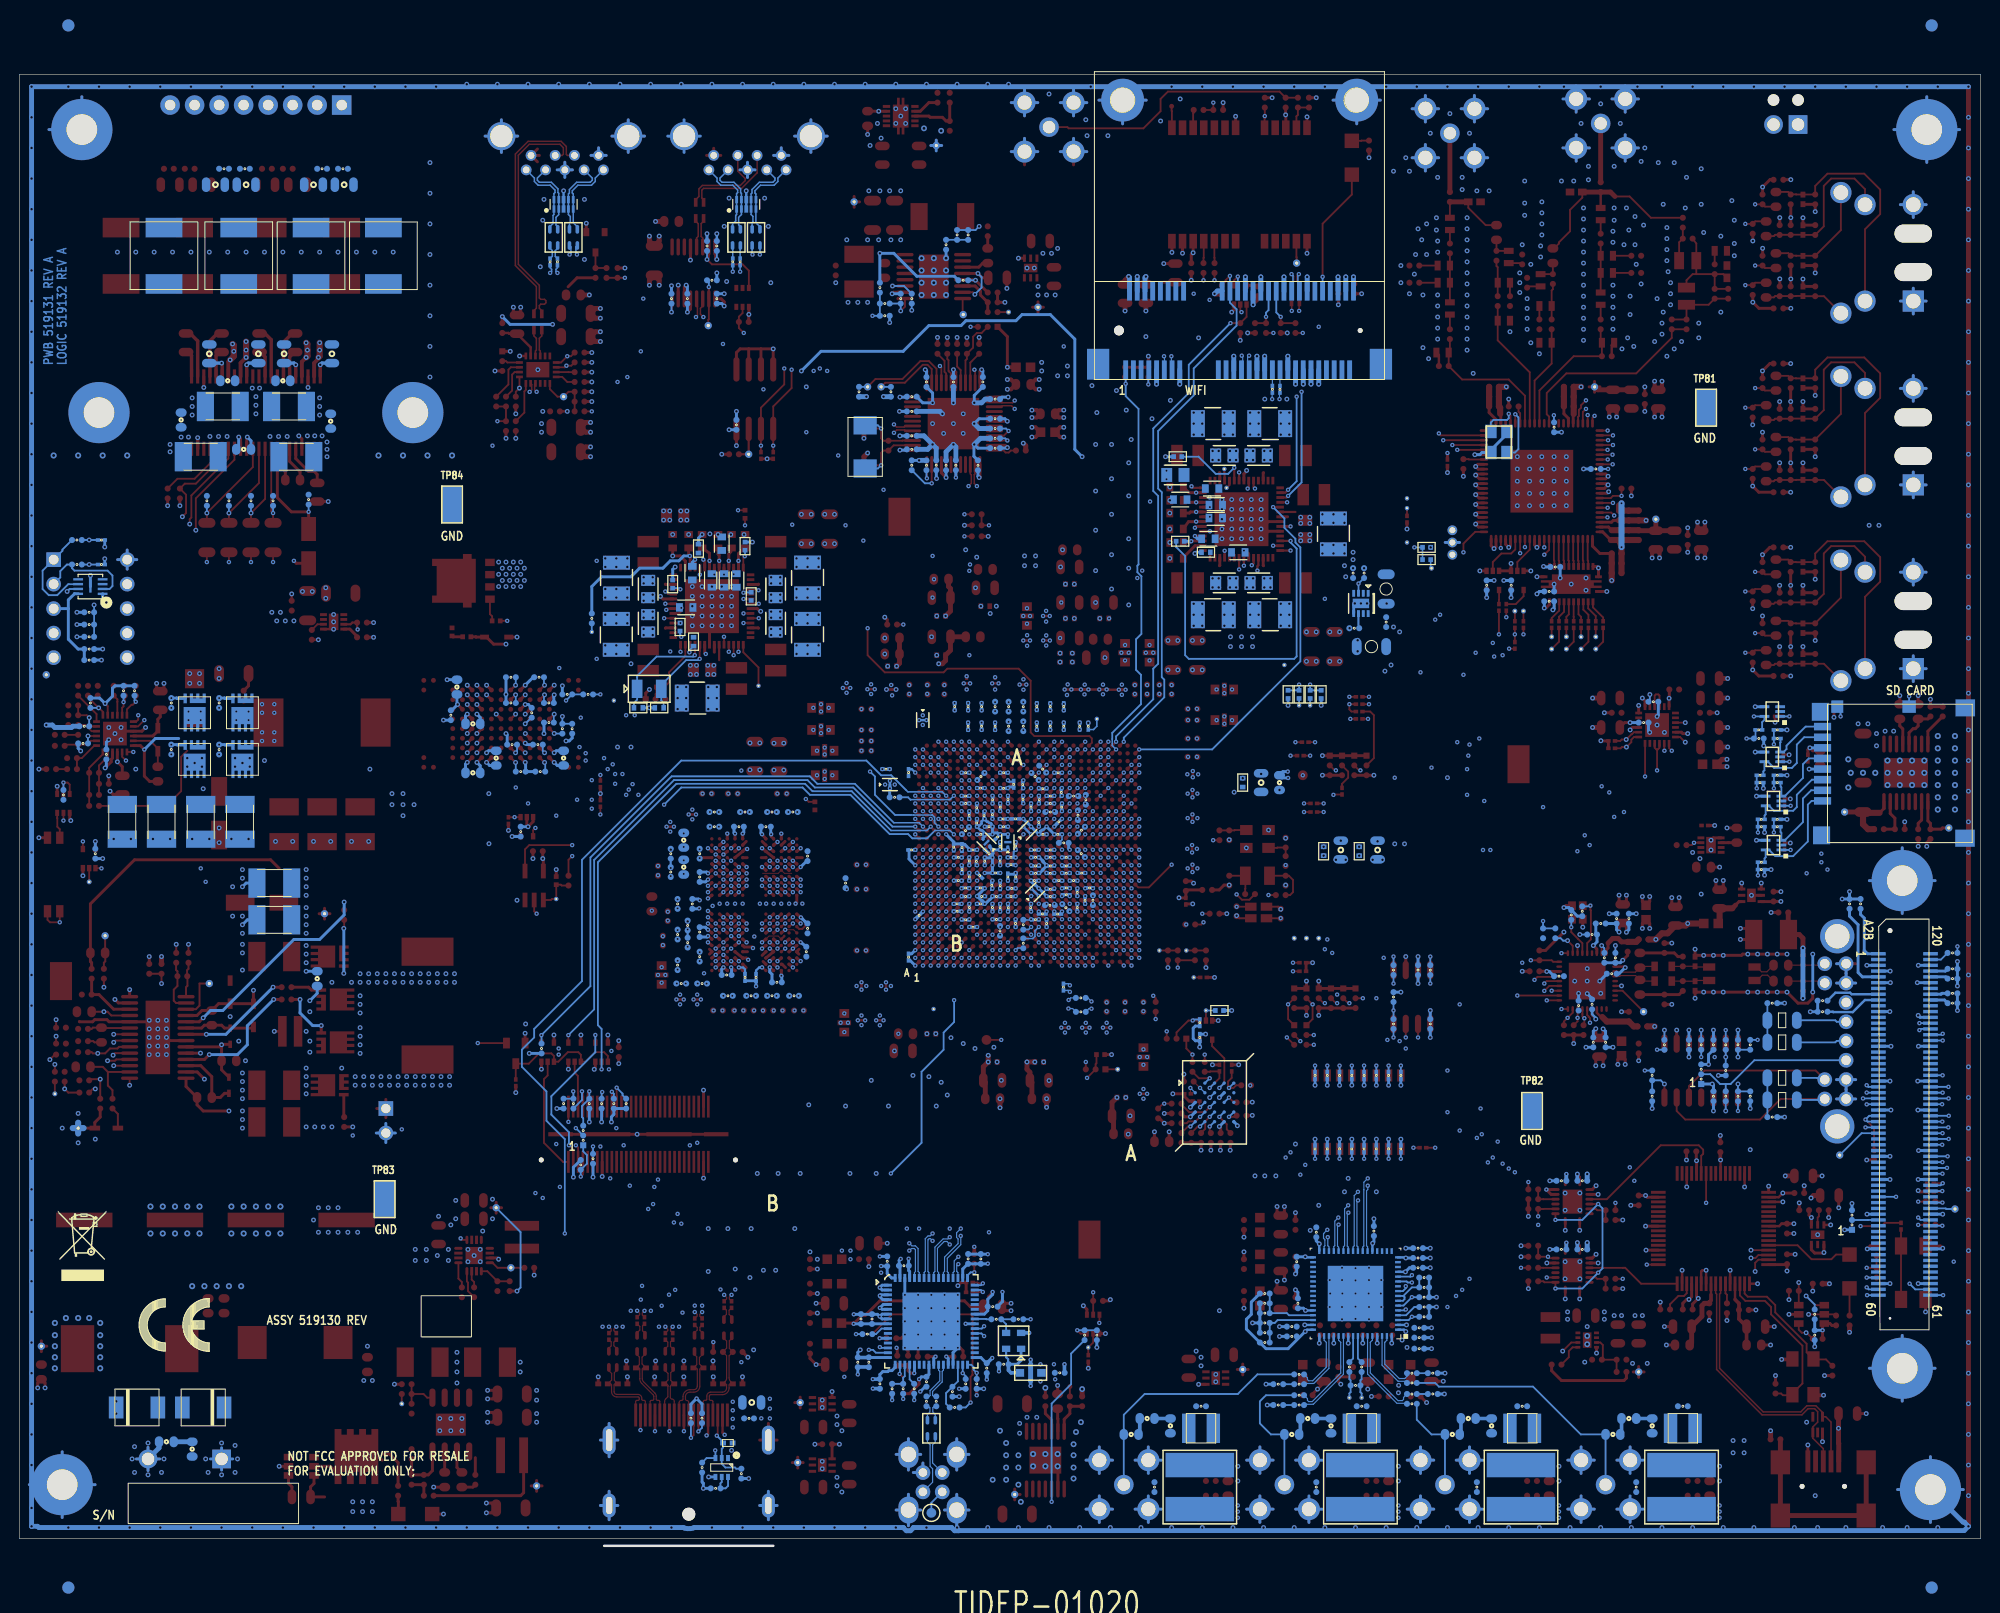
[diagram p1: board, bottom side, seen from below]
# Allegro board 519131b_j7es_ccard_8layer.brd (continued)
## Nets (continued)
UB960_CAM_NPOWERON: Q8.5(G2) R234.2 U37.AB5(SPI0_D0)
UB960_FRAME_SYNC: U37.AA2(SPI0_CS0) U74.9(GPIO_0)
UB960_IDX: C808.1 R436.1 R440.2 U74.46(IDX)
UB960_INTB: R429.2 U37.W5(MCAN0_RX) U74.6(INTB)
UB960_MODE: C805.1 R428.2 R430.1 U74.45(MODE)
UB960_PDB: R433.1 U37.AA1(SPI0_CLK) U74.3(PDB)
UB960_REFCLK: R435.2 U74.5(REFCLOCK)
UB981_CLKIN: R434.2 U75.41(REFCLK0)
UB981_DOUT0_N: C831.2 FL41.4
UB981_DOUT0_P: C832.2 FL41.1
UB981_GPIO0: U37.Y3(SPI1_CS0) U75.14(GPIO0)
UB981_GPIO1: U37.W4(SPI1_CS1) U75.15(GPIO1)
UB981_GPIO2: U37.Y5(SPI1_D0) U75.38(I2S_DC/GPIO2)
UB981_GPIO3: U37.Y2(SPI1_D1) U75.39(I2S_DD/GPIO3)
UB981_IDX: R446.1 R447.2 U75.19(IDX)
UB981_INTB: R448.2 R455.1 U75.30(INTB)
UB981_MODE_SEL0: R248.2 R249.1 U75.18(MODE_SEL0)
UB981_MODE_SEL1: R246.2 R443.1 U75.32(MODE_SEL1)
UB981_PDB: R442.1 U37.Y1(SPI1_CLK) U75.31(PDB)
UB981_REM_INTB: R437.1 U75.10(REM_INTB)
USART_A_RXD: R226.1 U52.17(ADBUS1/RXD/TDI)
USART_A_TXD: U52.16(ADBUS0/TXD/TCK) U55.4(1A1)
USART_B_RXD: R217.1 U52.39(BDBUS1/RXD/TDI)
USART_B_TXD: U51.4(1A1) U52.38(BDBUS0/TXD/TCK)
USART_DM: J19.2(D-) U52.7(USBDM) U60.5(IO2)
USART_DP: J19.3(D+) U52.8(USBDP) U60.3(IO1)
USART_EECS: R238.1 U52.63(EECS) U56.5(CS)
USART_EEDIN: R232.2 U52.61(EEDATA) U56.3(DIN)
USART_EEDOUT: R232.1 R239.1 U56.1(DO)
USART_EESK: R432.1 U52.62(EESK) U56.4(CLK)
USART_GND: J19.6(SHIELD1) J19.7(SHIELD2) J19.8(SHIELD3) J19.9(SHIELD4) R255.2
USART_LED: D14.2(ANODE) R237.2
USART_NR: C374.1 U53.2(NR)
USART_OSCI: C441.1 U52.2(OSCI) Y5.1
USART_OSCO: C449.1 U52.3(OSCO) Y5.3
USART_PD: R227.1 U51.5(1A2) U51.10(2B2) U55.5(1A2) U55.10(2B2)
USART_PWREN: D14.1(CATHODE) U52.60(PWREN#)
USART_RESETN: R236.2 U52.14(RESET#)
USART_RSET: R235.2 U52.6(REF)
USB0_CS: C499.1 R55.1 R268.2 R272.1
USB0_DATA_N: U11.4(DM_OUT) U37.AJ5(USB0_DM)
USB0_DATA_P: U11.5(DP_OUT) U37.AH6(USB0_DP)
USB0_DRVVBUS: R49.1 R50.1 R56.1 U37.U6(USB0_DRVVBUS)
USB0_ID: R95.1 U37.AC6(USB0_ID)
USB0_IMON: R51.1 U37.L29(MCU_ADC0_AIN7)
USB0_RCALIB: R343.1 U37.AB6(USB0_RCALIB)
USB0_SS_RX2_N: FL36.4 U37.AH9(SERDES3_RX0_N)
USB0_SS_RX2_P: FL36.1 U37.AJ8(SERDES3_RX0_P)
USB0_SS_TX2_N: C494.2 FL35.4
USB0_SS_TX2_P: C493.2 FL35.1
USB0_STATUS: R39.1 U11.17(STATUS) U37.AD5(UART1_RTSN)
USB0_VBUS_OCN: R40.1 U11.18(FAULT) U37.W6(MCAN0_TX)
USB0_VBUS_SOC: R17.2 R18.2 U37.AC7(USB0_VBUS)
USB1_DATA_N: U16.27(USB_DM_UP) U37.AH7(USB1_DM)
USB1_DATA_P: U16.26(USB_DP_UP) U37.AJ6(USB1_DP)
USB1_DM: FL3.1 U11.14(DM_IN)
USB1_DP: FL3.4 U11.13(DP_IN)
USB1_DRVVBUS: R71.1 RJ1.3 U37.V4(MCAN1_TX)
USB1_HUB_D_N: U7.12(D-) U16.42(USB_DM_DN1)
USB1_HUB_D_P: U7.11(D+) U16.41(USB_DP_DN1)
USB1_HUB_PWRCLT1: Q1.2(G2) R26.1 U16.4(PWRCLT1/BATEN1)
USB1_ID: R75.1 U37.AD7(USB1_ID)
USB1_RCALIB: R337.1 U37.AD9(USB1_RCALIB)
USB1_SS_RX1_N: FL38.4 U37.AH12(SERDES2_RX1_N)
USB1_SS_RX1_P: FL38.1 U37.AJ11(SERDES2_RX1_P)
USB1_SS_TX1_N: C496.2 FL37.4
USB1_SS_TX1_P: C495.2 FL37.1
USB1_VBUS_SOC: R71.2 R74.1 U37.AD8(USB1_VBUS)
USB2_DM: FL1.4 U7.5(VD-)
USB2_DP: FL1.1 U7.6(VD+)
VCAM_10V5: C460.1 C461.1 C462.1 C463.1 C465.1 C469.1 C470.1 C471.1 C483.1 L51.2 L52.2 L53.2 L54.2 TP74.1(TP) U62.5(OUT5) U62.6(OUT6) U62.7(OUT7)
VCAM_VDD18: C443.1 C809.1 C810.1 C812.1 C813.1 C814.1 FL32.2 R428.1 R440.1 U74.1(VDD18_P3) U74.2(VDD18_P2) U74.47(VDD18_P1) U74.48(VDD18_P0)
VCAM_VDD18_FPD: C417.1 C419.1 C420.1 C422.1 C444.1 C445.1 FL33.2 U74.49(VDD18_FPD0) U74.55(VDD18_FPD1) U74.58(VDD18_FPD2) U74.64(VDD18_FPD3)
VCAM_VDD_CSI: C389.1 C390.1 C791.1 C800.1 FL22.2 U74.21(VDD_CSI0) U74.33(VDD_CSI1)
VCAM_VDD_FPD: C418.1 C421.1 C446.1 C447.1 FL34.2 U74.52(VDD_FPD1) U74.61(VDD_FPD2)
VCAM_VDDA18: C379.1 C380.1 C792.1 FL20.2 U74.32(VDDA18A)
VCAM_VDDL: C398.1 C399.1 C802.1 C803.1 FL24.2 U74.13(VDDL1) U74.44(VDDL2)
VCAP_MCU_VDDS0: C732.1 U37.K23(CAP_VDDS0_MCU)
VCAP_MCU_VDDS1: C737.1 U37.J18(CAP_VDDS1_MCU)
VCAP_MCU_VDDS2: C742.1 U37.J19(CAP_VDDS2_MCU)
VCAP_VDDS0: C659.1 U37.U7(CAP_VDDS0)
VCAP_VDDS1: C622.1 U37.AB21(CAP_VDDS1)
VCAP_VDDS2: C638.1 U37.Y18(CAP_VDDS2)
VCAP_VDDS3: C640.1 U37.W21(CAP_VDDS3)
VCAP_VDDS4: C627.1 U37.AA22(CAP_VDDS4)
VCAP_VDDS5: C680.1 U37.R22(CAP_VDDS5)
VCAP_VDDS6: C658.1 U37.V22(CAP_VDDS6)
VDA_DLL_0V8: C137.1 FL10.1 FL15.1 U27.9(VOUT_LDO3)
VDA_MCU_1V8: C138.1 C675.1 C676.1 C678.1 C679.1 C700.1 R290.2 R381.2 U27.7(VOUT_LDO4) U37.G18(VDDA_MCU_PLLGRP0) U37.H22(VDDA_WKUP) U37.M23(VDDA_ADC1) U37.N22(VDDA_ADC0) U37.P21(VDDA_MCU_TEMP) U37.P22(VDDA_POR_WKUP)
VDA_PLL_1V8: C121.1 C163.1 C173.1 C690.1 C691.1 C715.1 U20.7(VOUT_LDO4) U37.H9(VDDA_TEMP2_3) U37.L12(VDDA_PLLGRP3) U37.M17(VDDA_PLLGRP2) U37.P9(VDDA_PLLGRP5) U37.R11(VDDA_PLLGRP4) U37.R21(VDDS_OSC1) U37.W15(VDDA_TEMP0_1) U37.W17(VDDA_PLLGRP1) U37.W18(VDDA_PLLGRP6) U37.Y20(VDDA_PLLGRP0)
VDA_USB_3V3: C114.1 C164.1 C174.1 U20.11(VOUT_LDO2) U37.AB10(VDDA_3P3_USB)
VEXP_1V8A: J21.113 R376.2
VEXP_1V8B: J21.112 R380.2
VEXP_3V3A: J21.8 R379.1
VEXP_3V3B: J21.9 R382.1
VEXP_5V0A: J21.1 R355.1
VEXP_5V0B: J21.5 R354.1
VEXP_5V0C: J21.117 R370.2
VEXP_5V0D: J21.116 R375.2
VIO_3V3_SD: C259.1 C260.1 C261.1 C273.1 C286.1 P5.4(VDD) U36.7(VOUT1) U36.8(VOUT2) U70.1(VCC) U71.1(VCC) U72.1(VCC)
VIO_3V3USB: C97.1 C507.1 C511.1 C512.1 C523.1 C524.1 C526.1 C532.1 C534.1 FL5.1 U16.7(VDD33#7) U16.13(VDD33#13) U16.23(VDD33#23) U16.25(VDD33#25) U16.33(VDD33#33) U16.37(VDD33#37) U16.40(VDD33#40) U16.48(VDD33#48)
VMIC_BIAS: C10.1 C63.1 C78.1 C112.1 C143.1 C202.1 C272.1 R7.2 R10.1 R13.2 R22.1 R45.2 R53.1 R57.2 R66.1 R76.2 R79.1 R96.2 R102.1 R138.1 TP41.1(TP) U34.16(OUT)
VMON_VEXT: TP39.1(TP) U37.V19(VMON_IR_VEXT)
VMON_VSYS: C297.1 R144.2 R145.1 U37.M26(VMON_ER_VSYS)
VOSNS: C320.2 R168.2 U46.12(VOSNS)
VPCIE0_1V5: C4.2 C52.1 C58.1 J20.6(1.5V) J20.28(+1.5V#28) J20.48(+1.5V#48) R5.2 TP2.1(TP) U1.9(VOUT1) U1.10(VOUT2)
VPHY_USART: C408.1 C415.1 L47.1 U52.4(VPHY)
VPLL_USART: C406.1 C416.1 L48.1 U52.9(VPLL)
VPP_EFUSE_1V8: C207.1(INPUT) C207.3(OUTPUT) C208.1(INPUT) C208.3(OUTPUT) C625.1 C757.1 U37.AB11(VPP_CORE) U37.F17(VPP_MCU)
VRTC_LEOA_1V8: C139.1 R293.2 U27.3(VOUT_LDOVRTC)
VRTC_LEOB_1V8: C141.1 R283.1 U20.3(VOUT_LDOVRTC)
VSYS_3V3: C159.1 C183.1 C274.1 C278.1 C279.1 C280.1 C348.1 C383.1 C409.1 C681.1 L39.2 L45.1 R98.1 R125.2 R127.2 R144.1 R191.1 R224.2 R323.2 U24.5(D) U28.1(VIN1) U28.2(VIN2) U28.4(VBIAS) U38.5(VCC) U47.5(VCC) U48.5(VCC) U49.5(VCC) U54.10(AVIN) U54.11(PVIN#11) U54.12(PVIN#12) U57.4(ILM) U57.8(VIN)
VSYS_5V0: C423.1 C424.1 C442.1 C464.2 C607.1 C765.1 C785.1 R243.2 R245.2 R354.2 R355.2 R370.1 R375.1 TP68.1(TP) U33.16(VCCX) U44.3(VCC) U50.3(VCC) U57.2(VOUT) U63.6(IN)
VSYS_10V5: C253.1 C450.1 C455.1 C458.1 C478.1 L50.2 R261.2 TP73.1(TP) U34.1(IN) U34.2(EN1) U46.24(BIAS) U62.8(VS8) U62.9(VS9) U62.10(VS10)
VSYS_16V0: C41.2 C42.2 C43.1 C298.1 C310.1 C436.1 C437.1 C713.1 C754.1 C769.2 Q3.5(D) R153.2 R168.1 R247.1 TP44.1(TP) U8.12(VIN1) U8.13(VIN2) U61.7(VIN)
VSYS_IO_1V8: C5.2 C28.2 C132.1 C133.1 C373.1 C378.1 C381.1 C392.1 C440.2 C453.1 C454.1 C457.2 FL20.1 FL21.1 FL32.1 FL33.1 L31.1 L44.2 R229.2 R376.1 R380.1 TP62.1(TP) U1.1(IN1) U1.2(IN2) U1.5(EN) U6.4(EN) U6.6(IN) U54.16(VOS) U58.4(EN) U58.6(IN) U59.4(EN) U59.6(IN)
VSYS_SENSE: D6.1(CATHODE) R99.2 U27.51(VSYS_SENSE)
VTUN_1V8: C125.1 C126.1 C127.1 C134.1 L31.2 TP18.1(TP) U19.43(VD)
VTUN_3V3: C83.2 C84.2 C85.2 C86.2 C89.1 C91.2 C93.2 L27.2 TP9.1(TP) U19.3(VA1) U19.18(VA2)
VUSART_1V8: C368.1 C369.1 C387.1 C407.1 U52.12(VCORE#12) U52.37(VCORE#37) U52.49(VREGOUT) U52.64(VCORE#64)
VUSART_3V3: C367.1 C370.1 C371.1 C372.1 C375.1 C382.1 C790.1 C795.1 C811.1 L47.2 L48.2 R236.1 R238.2 R239.2 R432.2 U51.1(VCCA) U51.2(1DIR) U52.20(VCCIO#20) U52.31(VCCIO#31) U52.42(VCCIO#42) U52.50(VREGIN) U52.56(VCCIO#56) U53.1(VOUT) U55.1(VCCA) U55.2(1DIR) U56.6(VCC)
VUSART_VBUS: C393.1 C456.1 J19.1(USBVDD) R237.1 U53.4(EN) U53.6(VIN) U60.1(VCC)
VUSB_5V0: C19.1 C20.1 C37.1 C94.1 C100.1 C104.1 C497.1 C499.2 L4.2 R48.1 R264.1 R267.2 R268.1 TP3.1(TP) U7.14(VBUS_SYS#14) U7.15(VBUS_SYS#15) U11.2(IN#2) U11.3(IN#3)
VUSB_IO_1V1: C46.2 FL4.2 TP5.1(TP) U6.1(OUT)
WKUP_GPIO0_30: R186.1 RJ16.1 U37.A23(MCU_OSPI1_LBCLKO)
WKUP_LFOSC_XI: R146.1 U37.N28(WKUP_LFOSC0_XI)
WKUP_LFOSC_XO: R147.1 U37.N26(WKUP_LFOSC0_XO)
WKUP_OSC0_XIN: C300.1 U37.M29(WKUP_OSC0_XI) Y4.3
WKUP_OSC0_XOUT: C302.1 U37.M27(WKUP_OSC0_XO) Y4.1
XTAL1: U19.6(XTALI) Y6.1(Y1)
XTAL2: U19.5(XTALO) Y6.3(C1)
ZIFCLK0: U19.50(ZIFCLK) U25.6(A4)
ZIFCLK1: U19.52(ISFSN) U25.4(A2)
ZIFFS0: U19.48(ZIFFS) U25.8(A6)
ZIFFS1: U19.53(ISFSP) U25.3(A1)
ZIFI0: U19.51(ZIFI0) U25.5(A3)
ZIFI1: U19.47(ZIFI1) U25.9(A7)
ZIFQ0: U19.49(ZIFQ0) U25.7(A5)
ZIFQ1: U19.46(ZIFQ1) U25.10(A8)
N22073312: R317.2 U31.P6(CLK)
N22073335: R313.1 U31.M5(RSTN) U35.4(O)
N23139394: D4.3(C) R18.1 R19.2
N23154802: R174.1 U37.D27(MCU_SAFETY_ERRORN)
N23300995: R316.1 TP38.1 U37.AC18(EXTINTN)
N23785887: J16.2 TP75.1(TP)
N23786032: R434.1 R435.1 U76.3(OUTPUT)
N24377130: R135.1 U37.U4(SOC_SAFETY_ERRORN)
N24525426: R151.1 U37.G26(WKUP_GPIO0_9)
N27191474: R83.2 U27.52(OVPGDRV)
N27191486: R83.1 U24.4(GATE)
N27191539: R98.2 R99.1
N28200806: C293.1 R146.2 Y2.2
N28200825: C292.1 R147.2 Y2.1
N28200987: C284.1 R141.2 Y1.3
N28201033: C285.1 R143.2 Y1.1
N28832809: C827.2 R444.1
N28833063: C473.1 C479.1 L51.1 L75.2 R459.2
N28833077: L67.2 L75.1 R450.2 R459.1
N28833083: L63.2 L67.1 R450.1
N28833091: L59.2 L63.1
N28833093: L59.1 L71.2
N28833539: C823.2 L71.1 P4.1
N28846480: L64.2 L68.1 R454.1
N28846484: L68.2 L76.1 R454.2 R460.1
N28846490: C476.1 C482.1 L54.1 L76.2 R460.2
N28846519: C830.2 L72.1 P3.1
N28846523: L60.1 L72.2
N28846525: L60.2 L64.1
N28846680: C835.2 R451.1
N28847093: L65.2 L69.1 R452.1
N28847097: L69.2 L77.1 R452.2 R461.1
N28847103: C475.1 C481.1 L53.1 L77.2 R461.2
N28847132: C834.2 L73.1 P2.1
N28847136: L61.1 L73.2
N28847138: L61.2 L65.1
N28847293: C829.2 R449.1
N28847739: L66.2 L70.1 R453.1
N28847743: L70.2 L78.1 R453.2 R462.1
N28847749: C474.1 C480.1 L52.1 L78.2 R462.2
N28847778: C825.2 L74.1 P1.1
N28847782: L62.1 L74.2
N28847784: L62.2 L66.1
N28847939: C822.2 R441.1
N28964551: R301.1 R302.2 U31.K5(DS)
N28998069: TP57.1(TP) U37.F13(TEMP_DIODE_P)
N29097715: C487.2 C491.1 J3.1 L58.2
N29097939: C486.2 C490.1 J3.2 L57.2
N29097966: C503.2 U14.44(BST_4P)
N29098001: C502.2 U14.40(BST_4M)
N29098045: C6.2 C11.1 J3.3 L8.2
N29098079: C113.1 U14.5(GVDD)
N29098081: C73.2 U14.39(BST_3P)
N29098121: C110.2 U14.7(AVDD_RET)
N29098125: C110.1 U14.6(AVDD)
N29098127: C74.2 U14.35(BST_3M)
N29098169: C7.2 C12.1 J3.4 L9.2
N29098206: C142.2 C537.1 U14.8(IN_REF)
N29098208: C501.2 U14.32(BST_2P)
N29098269: C128.1 C542.1 U14.9(IN4_P)
N29098271: C500.2 U14.28(BST_2M)
N29098305: C129.1 C541.1 U14.10(IN3_P)
N29098342: C130.1 C540.1 U14.11(IN2_P)
N29098355: C485.2 C489.1 J3.5 L56.2
N29098388: C484.2 C488.1 J3.6 L55.2
N29098394: C131.1 C539.1 U14.12(IN1_P)
N29098396: C75.2 U14.27(BST_1P)
N29098418: C8.2 C13.1 J3.7 L10.2
N29098431: C9.2 C14.1 J3.8 L11.2
N29098435: C76.2 U14.23(BST_1M)
N29098652: R70.1 U14.18(FAULTN)
N29134681: R431.1 U74.4(TESTEN)
N29136651: C818.2 R445.1 TP76.1
N29136657: C819.2 R445.2 TP77.1
N29136703: C818.1 U74.56(LPTXP)
N29136712: C819.1 U74.57(LPTXN)
N29139158: R426.1 R427.1 U74.7(I2C_SDA2) U74.8(I2C_SCL2)
N29142214: C778.1 R384.1 R387.2
N29142221: R371.2 U44.1(TXD)
N29142246: R372.2 U44.4(RXD)
N29142266: R377.1 R386.2 U44.8(STB)
N29144479: C17.2 C18.2 J8.5B R7.1 U3.1(IO)
N29144501: C80.2 C81.2 J9.5B R45.1 U12.1(IO)
N29144523: C147.2 C148.2 J12.5B R76.1 U21.1(IO)
N29144983: C23.2 C24.1 J8.2B R10.2 R11.2 U4.1(IO)
N29144989: C95.2 C96.1 J9.2B R53.2 R54.2 U15.1(IO)
N29144995: C160.2 C161.1 J12.2B R79.2 R80.2 U26.1(IO)
N29145145: C35.2 C36.2 J8.5A R13.1 U5.1(IO)
N29145167: C102.2 C103.2 J9.5A R57.1 U17.1(IO)
N29145189: C177.2 C178.2 J12.5A R96.1 U29.1(IO)
N29145646: C53.2 C54.1 J8.2A R22.2 R23.2 U9.1(IO)
N29145652: C108.2 C109.1 J9.2A R66.2 R67.2 U18.1(IO)
N29145658: C195.2 C199.1 J12.2A R102.2 R103.2 U30.1(IO)
N29159706: C574.1 J11.8 R292.1 R295.2 U67.7(RST)
N29176310: J21.119 R367.1
N29176636: J21.32 TP61.1(TP)
N29176758: J21.77 R215.1
N29176776: J21.76 TP63.1(TP)
N29176797: J21.47 RJ20.2
N29176814: J21.73 R219.1
N29176862: J21.57 R225.1
N29180491: J15.1(VREF_DBG) J15.12(VREF_TR) R424.2
N29180693: Q6.D R191.2 U47.1(OE) U48.1(OE) U49.1(OE)
N29180734: J15.7(RTCK) R411.1
N29180779: J15.15(TGT_DETECT) R413.2
N29182955: R223.1 U55.13(1B1)
N29183037: R226.2 R231.1 U55.6(2A1)
N29184661: R212.1 R214.1 U51.13(1B1)
N29185762: R217.2 R218.1 U51.6(2A1)
N29203019: C16.1 C25.2 D3.1 L5.1
N29203023: C25.1 C32.2 L12.2
N29203029: C32.1 C62.2 L17.2
N29203179: C34.1 L12.1
N29203181: C61.1 L17.1
N29203576: C16.2 J7.1
N29203584: R82.1 U23.4(O)
N29203608: R81.1 U22.4(O)
N29203733: C29.2 L5.2
N29203735: C29.1 L14.2 L18.2 L22.1
N29203745: C71.2 L22.2
N29203827: C522.2 U19.14(AMVAG)
N29203843: C38.1 L14.1
N29203845: C50.1 L18.1
N29203849: C83.1 C85.1 C91.1 U19.17(ABYP2)
N29203873: C116.2 C117.2 C118.2 C125.2 C126.2 C127.2 C144.2 C146.2 C150.2 U19.44(DBYP)
N29204635: C15.1 C22.1 C31.2 D2.1 L3.1
N29204639: C31.1 C48.2 L16.2
N29204645: C48.1 C68.2 L21.2
N29204746: C49.1 L16.1
N29204748: C69.1 L21.1
N29205057: C15.2 J5.1
N29205223: C27.2 L3.2
N29205225: C27.1 L7.2 L15.2 L20.1
N29205235: C67.2 L20.2
N29205377: C44.1 L15.1
N29205379: C30.1 L7.1
N29205614: C26.1 C40.1 C57.2 D5.1 L13.2 L19.1 R24.2
N29205618: C57.1 C66.2 L19.2 R24.1 R27.2
N29205650: C22.2 C26.2 L13.1
N29205730: C40.2 L6.2
N29214431: C2.2 J6.1 L2.2
N29214437: C2.1 L1.2 U2.11(RF_IN)
N29214443: TP4.1(TP) U2.14(LA_EN)
N29214525: R15.1 U2.20(TXD/SPI_MISO)
N29214549: R16.1 U2.21(RXD_SPI_MOSI)
N29214557: R4.2 U2.3(TIMEPULSE)
N29214575: TP1.1(TP) U2.1(SAFEBOOT_N)
N29427544: C403.1 C404.1 L46.1 L49.1 Q9.5(D1) R260.2 U64.4(CATHODE)
N29427613: C837.2 C838.1
N29427634: D25.2(ANODE) D26.2(ANODE)
N29427748: DS1.2(ANODE) R260.1
N29427750: Q9.4(G) U64.5(GATE)
N29427801: C477.1 U64.1(VCAP)
N29457313: R274.1 TP10.1(TP) U16.2(SCL/SMBCLK)
N29457315: R273.1 TP11.1(TP) U16.3(SDA/SMBDAT)
N29457363: R35.2 RJ1.2 U16.9(USB_VBUS)
N29457411: R34.1 U16.10(TEST)
N29457441: R60.2 U16.24(USB_R1)
N29457479: R278.2 U16.35(GANGED/SMBA2)
N29457500: R279.2 U16.36(FULLPWWRMGMTTZ/SMBA1)
N29457524: R276.2 U16.22(SMBUSZ)
N29457542: R38.1 U16.5(OVERCUR1Z)
N29457548: R275.2 U16.21(PWRCTL_POL)
N29457593: C107.1 R59.2 U16.38(XI) Y7.1
N29457640: R37.1 U16.6(PWRCTL2/BATEN2)
N29457654: C101.1 R59.1 U16.39(XO) Y7.2
N29457660: R36.1 U16.8(OVERCUR2Z)
N29483068: FL2.4 J20.38(USB_D+)
N29483119: FL2.1 J20.36(USB_D-)
N29500308: R149.1 U37.L24(MCU_ADC1_AIN2) U37.L25(MCU_ADC1_AIN6) U37.L26(MCU_ADC1_AIN3) U37.L27(MCU_ADC1_AIN7) U37.M24(MCU_ADC1_AIN5) U37.M25(MCU_ADC1_AIN1) U37.N23(MCU_ADC1_AIN0) U37.N24(MCU_ADC1_AIN4)
N29500526: R119.1 U37.AF1(MMC0_CLK)
N29520912: R402.2 SW2.16(B1)
N29520937: R401.2 SW2.15(B2)
N29520962: R400.2 SW2.14(B3)
N29520987: R399.2 SW2.13(B4)
N29521012: R398.2 SW2.12(B5)
N29521037: R397.2 SW2.11(B6)
N29521062: R396.2 SW2.10(B7)
N29521082: R395.2 SW2.9(B8)
N29622583: R283.2 U20.40(OSC32KCAP)
N29626619: C236.1 U34.4(VCC)
N29626723: R137.1 R138.2 U34.15(FB1)
N29626795: C235.1 R114.1 U34.5(SNS_1)
N29626827: R140.1 U34.10(LIM1)
N29626839: R113.1 U34.8(SNS_EN)
N29626843: R139.2 TP42.1(TP) U34.9(ERR)
N29649764: D1.1(CATHODE) J20.44(LED_WLAN#)
N29668820: C296.1 FL14.2 U39.1(OUT)
N29890935: C92.2 U19.7(DACREF)
N29891501: C84.1 C86.1 C93.1 U19.2(ABYP1)
N30029908: R92.1 U25.21(B1)
N30029911: R91.1 U25.20(B2)
N30029914: R90.1 U25.19(B3)
N30029917: R88.1 U25.17(B5)
N30029920: R89.1 U25.18(B4)
N30029923: R87.1 U25.16(B6)
N30029926: R86.1 U25.15(B7)
N30029929: R85.1 U25.14(B8)
N30068694: U32.3(AINL) U32.4(AINR)
N30080305: R269.1 U7.16(IADJ)
N30080322: R266.2 TP8.1(TP) U7.10(FLT)
N30080336: Q1.6(D2) R264.2 U7.7(VEN)
N30080339: R265.2 U7.8(DEN)
N30130836: R250.2 R251.2 U62.14(STN)
N30130873: R251.1 TP69.1(TP)
N30130899: R252.2 U62.13(CL)
N30130913: R253.2 U62.12(DIAG_EN)
N30133146: Q8.3(D2) R438.1 R439.2
N30186501: R385.1 RJ16.2 U45.1(A)
N30188271: Q12.4(G) Q13.4(G) R326.1 R327.2
N30188608: Q10.4(G) Q11.4(G) R309.2 R310.1
N30703324: C70.1 R33.2 U11.12(BIAS)
N30703458: R43.1 U11.19(ILIM_LO)
N30703463: R44.1 U11.20(ILIM_HI)
N30745719: C90.1 R47.1 R51.2 TP12.1(TP) U11.1(IMON)
N30746595: RJ2.2 U11.10(OVP_SEL)
N30808408: L45.2 U57.7(SW)
N30809211: C442.2 R243.1 R244.2 U57.3(FB)
N30811250: C451.2 R247.2 R254.1 U61.5(EN/SYNC)
N30811520: C467.1 U61.3(VCC)
N30812987: C466.1 U61.2(BOOT)
N30812990: C466.2 R258.1
N30812993: L50.1 R258.2 U61.1(SW)
N30813342: C468.1 R257.1 R259.1 U61.4(FB)
N30813649: C468.2 R259.2 R261.1
N30821669: R245.1 U57.5(PG)
N31193882: Q7.4(G) R202.1
N31194203: Q5.4(G) R173.1
N31194290: Q4.4(G) R172.2
N31194295: Q3.4(G) R150.2
N31194655: D13.1(CATHODE) R198.1
N31194670: C353.1 R198.2 U46.2(VIN)
N31194787: C361.1 D12.1(K) U46.26(BOOT1)
N31194818: C333.2 D10.1(CATHODE) D11.1(K) U46.20(BOOT2)
N31196095: C315.2 R159.1 U46.15(CSG)
N31196104: C315.1 R160.1 U46.16(CS)
N31196146: C344.1 U46.7(SLOPE)
N31196169: R184.1 U46.5(DTH)
N31196187: C354.2 R182.1 U46.6(RT/SYNC)
N31196205: R189.1 R193.1 U46.4(MODE)
N31196259: C341.1 R181.2 U46.9(COMP)
N31196266: C343.1 R181.1
N31197066: C340.1 U46.8(SS)
N31197134: C357.2 R199.2 U46.3(VISNS)
N31197473: R153.1 R167.2 TP45.1(TP)
N31208960: C226.1 R104.1
N31222024: R108.2 R308.1 U33.1(DEMB) U38.4(O)
N31222073: C239.2 R111.1 R315.1 U33.23(EN)
N31222132: C249.2 R117.1
N31222198: C251.1 R117.2 U33.20(COMP)
N31222241: C225.2 U33.24(RES)
N31222246: C243.2 U33.22(SS)
N31222265: R106.2 R300.1 U33.6(OSC)
N31222285: C223.2 R299.1 U33.5(DITH)
N31222303: R107.2 U33.4(RT)
N31222717: R124.2 R125.1
N31223527: L4.1 R12.2 R262.1 R263.1 U8.1(SW1) U8.2(SW2)
N31223584: C56.1 R267.1 U8.5(BIAS)
N31223889: C33.2 R12.1
N31224124: R270.1 R272.2 U8.9(FB)
N31225374: R55.2 U11.6(CS)
N31225630: R271.2 U8.11(EN)
N31225660: C64.1 R25.1 U8.6(SYNC)
N31226612: C47.2 U8.4(VCC) U8.7(FPWM)
N31251157: C319.2 C321.1 R171.2
N31251611: L41.3 L42.2 R171.1 U43.1(IO)
N31252401: L40.2 L41.4 R162.1 U41.1(IO)
N31252434: C308.1 C311.2 R162.2
N31279750: R220.2 SW3.3(B) SW3.4(BB)
N31313642: R49.2 U11.8(CTL1)
N31313645: R50.2 U11.9(CTL2)
N31555915: C492.1 R262.2 R263.2
N31823309: R224.1 TP64.1(TP) U54.4(PG)
N31823321: R229.1 R230.2 U54.5(FB)
N31823861: L44.1 U54.1(SW#1) U54.2(SW#2)
N31828740: C395.1 U54.7(CP)
N31828749: C395.2 U54.8(CN)
N31829052: C396.2 U54.9(SS)
N31832097: R1.2 R5.1 U1.8(FB)
N31834422: C1.2 U1.7(SS)
N31987713: R304.2 TP37.1(TP)
N31987901: R305.2 TP36.1(TP)
N32008315: D1.2(ANODE) R6.2
N32011520: J21.29 J21.30 R210.1
N32137181: R185.2 R188.1 U73.A3(RFU2)
N32140279: Q2.3(D2) SW1.4(B1)
N32140322: Q2.5(G2) Q2.6(D2) R342.1
N32413216: R61.1 TP15.1(TP) U13.7(WP)
N32594642: P5.9(INSERT) R319.2 U69.5(IO2)
N32594704: P5.10(INSERT_COM) R112.1
N32594856: C240.1 U69.1(VCC)
N32595187: C283.1 U36.6(CT)
N33430702: Q15.5(G2) Q15.6(D2) R464.1
N33657189: C305.2 R148.2 R161.2 R170.2
N33657272: C312.2 L41.1
N33657370: C316.2 L41.2
N33657483: C746.1 U42.5(XI) Y3.3(C1)
N33657512: C749.1 U42.4(XO) Y3.1(Y1)
N33657557: R363.2 U42.2(INT_N)
N33657559: TP56.1(TP) U42.16(CLK_OUT/GPIO_2)
N33658409: R391.1 R392.2 U50.7(INH)
N33658469: R407.2 R408.2 U50.8(NFAULT)
N33658487: R390.2 R394.2 U50.6(EN)
N33658532: R403.2 R405.2 U50.14(NSTB)
N33658660: R406.1 U50.9(WAKE)
N33658666: C788.1 R404.1 R409.2
N33658711: R389.2 U50.4(RXD)
N33658728: R388.2 U50.1(TXD)
N289339640: C33.1 U8.3(CBOOT)

Pads without a net: D4 2; J11 4 6 7 9 10; J13 7 13 14; J15 10 11 13 14 17 18 20 22 23 24 25 26 27 28 29 30 31 32 33 34 35 36 37 38 39 40 41 42 43 44 45 46 47 48 49 50 51 52 53 54 55 56 59 60; J19 4; J20 3 5 8 10 12 14 16 17 19 42 45 46 47 49 51; J21 2 7 10 12 13 14 15 16 18 19 20 21 22 33 34 35 37 38 39 41 42 44 45 48 49 50 51 53 54 55 56 64 65 66 67 68 70 71 72 78 100 101 102 103 110 111 114 120; NOREF#3 1; NOREF#4 1; NOREF#5 1; NOREF#6 1; NOREF#10 1; NOREF#12 1; NOREF#13 1; NOREF#14 1; P5 11 12 13 14; Q1 3 4 5; U1 3; U2 2 4 5 6 9 15 16 17 18 19; U6 3; U7 1; U8 14; U14 19 20; U16 16 17 19 20 28 29 31 32 43 44 46 47; U19 1 4 12 15 16 88; U20 1 25 29 39 51 52; U27 1; U31 A1 A2 A9 A10 B1 B10 D2 D3 D4 D5 D6 D7 D8 D9 E2 E3 E5 E6 E7 E8 E9 H4 H5 H6 H7 J2 J3 J4 J6 J7 J8 J9 K4 K6 K7 L5 L6 M2 M3 M6 M8 M9 N4 N5 N6 N7 P4 P7 T1 T10 U1 U2 U9 U10; U32 5 17; U34 3 6 7 11 13 14; U37 A17 A18 A24 A26 AA23 AA24 AA25 AA26 AA29 AB23 AB25 AB26 AB28 AB29 AC1 AC3 AC23 AC24 AC26 AC27 AC28 AD1 AD2 AD3 AD4 AD6 AD10 AD12 AD15 AD22 AD25 AD29 AE2 AE6 AE9 AE11 AE14 AE21 AE22 AE24 AE26 AF6 AF7 AF10 AF13 AF15 AF16 AF18 AF21 AF22 AF23 AF26 AF27 AG5 AG6 AG9 AG12 AG14 AG15 AG17 AG21 AG22 AG23 AG26 AG27 AG28 AH3 AH4 AH10 AH13 AH15 AH16 AH18 AH27 AH28 AJ2 AJ3 AJ9 AJ12 AJ14 AJ15 AJ17 AJ20 AJ21 AJ28 AJ29 B16 B17 B24 B25 B26 B27 C6 C7 C9 C10 C15 C16 C22 C23 C24 C25 D5 D6 D8 D9 D14 D15 D22 D23 E6 E7 E8 E13 E14 E18 E23 E26 F6 F10 F11 F18 F22 F23 G9 G10 G22 L6 N6 N25 P26 R27 R28 U2 U3 Y24 Y28 Y29; U39 2; U40 A1 A2 A11 A12 AA1 AA12 AB1 AB2 AB11 AB12 B1 B12 G11 K5 K8 N5 N8; U42 6 14 17 18 19 20 35; U50 11; U51 7 12; U52 18 19 21 22 23 24 26 27 28 29 30 32 33 34 36 40 41 43 44 45 46 48 52 53 54 55 57 58 59; U53 5; U55 7 12; U58 3; U59 3; U60 2; U62 1 4 11; U63 3; U67 3 4 5; U69 2 3; U70 2; U71 2; U72 2; U73 B5 C5; U74 10 14 15 17 18 19 20 34 35 36 37 38 39 40 41 42 43; U75 11 13 22 23 34 35 36 37 43 44 45 46

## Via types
v1: diameter 0.457, hole 0.203, TOP to BOTTOM, 2019 vias
v2: diameter 0.508, hole 0.254, TOP to BOTTOM, 2232 vias
v3: diameter 0.61, hole 0.305, TOP to BOTTOM, 22 vias
v4: diameter 0.635, hole 0.305, TOP to BOTTOM, 95 vias

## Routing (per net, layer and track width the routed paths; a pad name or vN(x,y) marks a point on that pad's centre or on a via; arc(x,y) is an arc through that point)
DGND: length 7380
  TOP w0.102: U40.G12 122.98,63.86 123.93,63.86 U40.G10
  TOP w0.203: Y4.2 76.82,65.05 v2(77.09,65.32) ; Y4.4 72.78,66.25 v2(72.52,65.98) ; v2(113.36,88.76) C221.2 ; R159.2 v2(185.67,62.35)
  TOP w0.229: J18.2 v1(138.84,12) ; v1(94.38,80.95) 94.78,80.55 U37.AF20 ; U20.21 v1(76.83,111.27) ; v1(90.38,80.95) 90.78,80.55 U37.AF25 ; U27.21 v1(126.59,97.65)
  TOP w0.254: L26.1 56.13,123.43 C79.2 ; U28.5 170.65,95.02 v2(170.64,95.01) ; J18.8 v1(135.84,11.88) ; C166.2 v2(174.98,98.67) ; C181.2 v2(172.22,93.92) ; U11.11 v2(151.37,123.33) ; v2(43.04,32.71) U51.9 ; v1(130.12,11.51) 130.34,11.73 J18.19 ; U52.51 v2(20.5,35.65) ; C94.2 v2(146.43,117.59) ; U52.47 v2(24.46,37.2) ; U52.1 v2(23.11,27.17) ; U53.3 v2(15.54,33.26) ; U52.10 v2(28.45,28.56) 28.83,28.56 28.96,28.44 U52.11 ; R180.2 v2(176.78,53.33) ; v1(91.31,88.76) v1(92.44,88.76) ; v2(43.04,25.59) U55.9 ; L24.1 38.23,124.45 C77.2 ; v1(90.55,88.76) 90.33,88.76 90.3,88.74 v1(89.29,88.74) ; C221.2 v2(112.37,88.76) ; v2(41.54,25.59) U55.8 ; v2(41.54,32.71) U51.8 ; v1(132,11.44) 131.84,11.59 J18.16 ; J18.5 v1(137.34,11.88) ; U52.5 v2(25.96,28.56) ; U52.15 v2(30.94,28.56) ; U52.35 v2(30.45,37.2) ; J18.11 v1(134.34,11.88)
  TOP w0.305: v1(103.98,76.95) 103.58,76.55 U37.AA9 ; v1(95.98,70.55) 96.38,70.95 U37.P18 ; U37.N27 89.18,70.15 v1(88.78,69.75) ; U2.10 71.99,148.31 v2(72.01,148.33) L2.1 ; 62.19,149.85 M6.1 ; M6.1 64.64,147.4 ; M6.1 67.09,149.85 ; v1(131.86,69.06) 131.45,69.38 U40.T1 ; C444.2 v2(63.5,16.25) ; R183.1 v2(90.04,50.92) ; U19.77 52.19,110.1 v2(52.32,109.97) 51.95,109.6 U19.76 ; U37.K20 94.78,67.75 v1(94.38,67.35) ; v2(69.85,54.98) RJ12.3 RJ13.3 ; U31.G9 v2(155.79,81.2) ; U37.B18 96.38,61.35 v1(95.98,60.95) ; v1(127.69,60.74) 127.88,60.93 128.25,60.93 U40.C5 U40.D4 ; M7.1 11.53,68.95 ; M7.1 8.13,65.55 ; M7.1 8.13,72.35 ; M7.1 4.72,68.95 ; 128.25,71.98 129.05,71.33 U40.W4 ; 128.25,71.98 128.01,72.23 v1(127.8,72.23) ; 128.25,71.98 U40.Y5 ; U37.U17 v1(96.78,73.75) ; v2(151.26,128.39) 151.26,127.99 151.64,127.61 C70.2 152.02,127.96 v2(152.02,128.39) ; C452.2 69.22,15.74 v2(68.71,16.25) 68.07,16.88 C447.2 ; P1.3 42.77,8.88 ; P1.3 40.03,8.88 ; P1.3 41.4,10.25 ; P1.3 41.4,7.51 ; v1(104.78,82.55) 104.38,82.15 U37.AH8 ; J16.SH3 111.09,5.34 ; J16.SH3 111.09,2.08 ; J16.SH3 112.36,3.71 ; J16.SH3 109.82,3.71 ; U40.E8 v1(126.25,61.91) ; v1(97.58,80.15) 97.98,79.75 U37.AE16 ; C454.2 v2(63.12,15.48) ; v1(122.25,69.06) 122.65,69.38 U40.T12 ; U37.AA14 99.58,76.55 v1(99.18,76.95) ; 40.03,3.8 P1.5 ; P1.5 41.4,5.17 ; P1.5 41.4,2.43 ; P1.5 42.77,3.8 ; U37.AC10 102.78,78.15 v1(103.18,78.55) ; U40.AB5 v1(128.25,73.82) ; D19.2 v2(128.28,17.52) ; U37.N17 97.18,70.15 v1(96.78,69.75) ; R149.2 v2(78.11,65.52) ; 198.75,2.94 M3.1 ; M3.1 198.75,9.74 ; M3.1 202.16,6.34 ; M3.1 195.35,6.34 ; J2.4 143.97,144.12 ; J2.4 143.18,144.91 ; J2.4 142.4,144.12 ; R58.2 v2(22.61,115.43) ; 12.95,58.33 J13.6 ; J13.6 14.94,58.33 ; J13.6 13.94,59.32 ; C238.2 v2(38.99,86.35) ; U37.N15 98.78,70.15 v1(98.38,69.75) ; 12.95,46.32 J13.12 ; J13.12 13.94,47.31 ; J13.12 14.94,46.32 ; R32.2 v2(76.71,124.96) ; C366.2 v2(85.6,42.92) ; R227.2 v2(46.86,26.66) ; U21.2 18.4,100.95 C147.1 v2(17.14,100.19) ; v1(102.38,68.95) 102.78,69.34 U37.M10 ; U48.3 v2(146.32,49.41) ; v1(103.98,71.35) 103.58,71.75 U37.R9 ; U37.A22 93.18,60.54 v1(92.78,60.14) ; v2(154.69,16.12) 154.05,16.12 C450.2 154.18,15.23 v2(154.69,15.23) ; U37.G1 109.98,65.35 v1(110.38,64.95) ; v1(95.98,68.95) 96.38,69.35 U37.M18 ; v2(72.9,35.17) 72.9,34.61 C380.2 72.14,34.61 v2(72.14,35.17) ; 58.04,2.43 P2.5 ; P2.5 59.41,3.8 ; P2.5 58.04,5.17 ; P2.5 56.67,3.8 ; v1(108.78,69.75) 108.38,70.15 U37.N3 ; U37.AJ7 105.18,82.95 v1(105.58,83.35) ; v1(111.46,20.52) 111.12,20.19 C434.2 ; U37.K14 v1(99.98,67.35) ; U37.E9 v1(103.98,63.35) ; J15.61 J15.62 v2(139.19,42.66) J15.63 J15.64 ; 35.46,144.9 J5.3 ; J5.3 36.83,143.52 ; J5.3 38.2,144.9 ; J5.3 36.83,146.27 ; R190.2 v2(82.55,48.88) ; v2(188.85,52.69) v2(187.96,52.69) 187.63,52.37 U46.22 ; U40.Y8 125.85,71.98 ; 125.85,71.98 125.05,71.33 U40.W9 ; 125.85,71.98 v1(126.26,72.31) ; U37.B3 v1(108.78,60.95) ; J6.5 95.35,149.6 ; J6.5 92.61,149.6 ; J6.5 93.98,148.22 ; J6.5 93.98,150.97 ; v1(96.78,77.75) 97.18,77.35 U37.AB17 ; v1(94.38,68.95) 94.78,69.35 U37.M20 ; v1(110.08,20.52) 110.09,20.52 110.09,19.61 C433.2 ; J6.2 99.06,145.89 ; J6.2 97.69,144.52 ; J6.2 99.06,143.14 ; J6.2 100.43,144.52 ; 13.94,47.33 J13.11 ; J13.11 14.94,48.33 ; J13.11 12.95,48.33 ; 54,104 J10.2 55.47,104 ; U37.AD14 99.58,78.95 v1(99.18,79.35) ; v1(101.58,74.55) 101.18,74.15 U37.V12 ; U37.G13 100.38,65.35 v1(100.78,64.95) ; U37.P20 94.78,70.95 v1(94.38,70.55) ; 106.08,2.08 J16.SH2 ; J16.SH2 104.81,3.71 ; J16.SH2 107.35,3.71 ; J16.SH2 106.08,5.34 ; U37.U15 98.78,73.35 v1(98.38,73.75) ; 41.97,149.98 41.97,149.97 ; 41.97,149.98 41.97,151.24 ; 41.97,149.98 J5.4 ; C88.2 v2(34.8,120.13) ; J6.4 99.06,150.97 ; J6.4 97.69,149.6 ; J6.4 99.06,148.22 ; J6.4 100.43,149.6 ; M8.1 8.13,21.81 ; M8.1 4.72,18.4 ; M8.1 8.13,15 ; M8.1 11.53,18.4 ; U37.AB8 104.38,77.35 v1(104.78,77.75) ; U37.W11 101.98,74.95 v1(102.38,75.35) ; v2(17.14,131.94) C35.1 18.4,132.7 U5.2 ; v1(98.38,71.35) 98.78,71.75 U37.R15 ; RJ8.1 RJ9.1 RJ10.1 RJ11.1 v2(68.58,58.54) ; J1.G2 122.88,146.12 ; J1.G2 121.19,147.81 ; J1.G2 119.5,146.12 ; J1.G2 121.19,144.43 ; v1(103.98,75.35) 103.58,74.95 U37.W9 ; 70.97,3.8 P3.4 69.6,2.43 ; U37.K8 v1(104.78,67.35) ; C416.2 v2(32.77,22.72) ; J13.5 14.94,60.34 ; J13.5 12.95,60.34 ; J13.5 13.94,59.35 ; C24.2 18.4,136.9 U4.2 v2(18.41,137.66) ; C430.2 121.28,19.42 v2(120.65,18.79) C438.2 ; v1(110.38,68.95) 109.98,69.35 U37.M1 ; U32.24 v2(35.43,87.11) ; U37.AJ10 102.78,82.95 v1(103.18,83.35) ; U37.K18 96.38,67.75 v1(95.98,67.35) ; 111.09,7.85 J16.SH4 ; J16.SH4 109.82,9.48 ; J16.SH4 111.09,11.1 ; J16.SH4 112.36,9.48 ; U40.P3 129.85,68.08 v1(130.26,67.76) 130.65,67.43 U40.N2 ; 123.47,144.12 J1.4 ; J1.4 124.26,144.91 ; J1.4 125.05,144.12 ; 59.56,59.68 v2(59.56,61.08) ; J19.5 v2(17.91,10.45) ; U37.C20 94.78,62.15 v1(94.38,61.75) ; C392.2 v2(120.52,28.69) ; v2(20.82,137.67) 20.82,136.91 R11.1 ; 73.3,8.88 P3.3 ; P3.3 74.68,7.51 ; P3.3 74.68,10.25 ; P3.3 76.05,8.88 ; C308.2 v2(32,62.47) ; J7.4 58.9,148.96 ; J7.4 57.53,150.33 ; J7.4 57.53,147.59 ; J7.4 56.16,148.96 ; U37.A19 95.58,60.54 v1(95.18,60.14) ; v2(27.94,73.14) 27.7,73.38 U36.5 ; v2(43.18,66.16) 42.98,66.36 Y3.2 ; J9.1B 8.32,119.97 ; J9.1B 6.99,121.31 ; J9.1B 6.99,118.64 ; J9.1B 5.65,119.97 ; v1(100.78,71.35) 100.38,71.75 U37.R13 ; R23.1 20.82,130.56 v2(20.82,131.32) ; v1(111.46,21.89) 111.83,21.52 C429.2 112.39,21.52 ; C236.2 v2(8.38,88.13) ; U12.2 18.4,120 17.14,120 v2(17.14,119.24) ; U51.14 44.5,36.43 v1(45,36.93) U51.15 ; v2(77.85,68.49) 78.39,68.49 78.89,67.99 R145.2 ; J8.1A 6.99,130.36 ; J8.1A 6.99,127.69 ; J8.1A 8.32,129.02 ; J8.1A 5.65,129.02 ; v1(103.18,74.55) 102.78,74.15 U37.V10 ; J12.1B 8.32,100.92 ; J12.1B 5.65,100.92 ; J12.1B 6.99,99.59 ; J12.1B 6.99,102.26 ; R2.1 v2(73.41,150.1) ; U37.M8 104.38,69.35 v1(104.78,68.95) ; U40.T10 124.25,69.38 v1(123.85,69.06) ; R65.1 v2(23.62,109.84) 22.99,109.21 21.46,109.21 ; v1(127.85,70.36) 128.25,70.68 U40.V5 ; J2.G1 153.25,147.81 ; J2.G1 153.25,144.43 ; J2.G1 151.57,146.12 ; J2.G1 154.94,146.12 ; C375.2 v2(18.8,35.55) ; J5.4 41.91,151.35 ; J5.4 41.91,148.6 ; J5.4 40.54,149.98 ; J17.2 189.87,10.21 ; J17.2 191.07,9.01 ; J17.2 189.87,7.8 ; J17.2 188.66,9.01 ; v2(37.47,67.44) 37.47,66.87 C301.2 36.7,66.87 v2(36.7,67.44) ; C406.2 v2(28.12,23.36) ; U37.K12 v1(101.58,67.35) ; v1(93.58,69.75) 93.98,70.15 U37.N21 ; U37.H18 96.38,66.15 v1(95.98,65.75) ; v1(107.98,68.95) 107.58,69.35 U37.M4 ; U37.C11 v1(102.38,61.75) ; v1(109.58,62.55) 109.18,62.95 U37.D2 ; 22.61,133.72 22.59,133.73 v2(22.59,134.5) ; U37.V18 v1(95.98,74.55) ; v1(93.58,60.95) 93.98,61.35 U37.B21 ; v2(3.94,30.85) 4.17,31.08 SW3.2 ; U37.J23 92.38,66.95 v1(91.98,66.55) ; 127.64,124.07 126.36,124.07 ; 127.64,124.07 U13.2 ; 127.64,124.07 128.52,124.07 128.91,123.69 U13.1 ; 126.36,124.07 U13.3 ; 126.36,124.07 v2(125.09,124.07) U13.4 ; v1(131.86,67.76) 131.45,68.08 U40.P1 ; J18.SH2 143,10.96 ; J18.SH2 142.09,12.69 ; J18.SH2 141.19,10.96 ; J18.SH2 142.09,9.23 ; R21.2 79.25,129.66 v2(79.38,129.78) ; U37.P4 107.58,70.95 v1(107.98,70.55) ; v2(193.29,84.19) 192.53,84.19 192.28,84.44 U33.9 190.51,84.44 v2(190.12,84.83) ; U37.M14 99.58,69.35 v1(99.98,68.95) ; v1(125.45,65.16) U40.K9 ; C52.2 v2(66.55,128.64) ; J18.SH1 125.59,12.69 ; J18.SH1 126.5,10.96 ; J18.SH1 124.69,10.96 ; v1(106.38,60.95) 105.98,61.35 U37.B6 ; U37.J17 97.18,66.95 v1(96.78,66.55) ; U31.G4 v2(155.79,87.21) ; 5.65,109.97 J9.1A ; J9.1A 6.99,108.64 ; J9.1A 6.99,111.31 ; J9.1A 8.32,109.97 ; U40.V1 131.45,70.68 v1(131.06,70.36) ; v1(104.78,72.15) 104.38,72.55 U37.T8 ; C51.2 v2(64.14,129.78) ; U37.Y17 97.18,75.75 v1(96.78,76.15) ; v2(30.35,84.19) 30.86,84.19 31,84.33 31.62,84.33 ; C369.2 v2(16.43,38.34) ; C216.2 v1(93.22,88.76) v1(94.21,88.76) ; U37.K10 v1(103.18,67.35) ; R78.1 v2(23.62,97.14) ; 56.16,143.88 57.53,143.88 ; 57.53,143.88 57.53,145.25 ; 57.53,143.88 57.53,142.51 ; 57.53,143.88 58.9,143.88 ; U7.13 133.67,128.2 v2(133.99,127.88) ; 23.61,129.66 v2(23.61,128.91) 22.97,128.27 21.46,128.27 ; 23.61,129.66 R20.1 ; 23.61,129.66 23.61,129.67 ; C399.2 v2(70.99,26.53) ; U54.3 153.68,29.84 v2(153.54,29.71) ; 70.97,8.88 P3.2 69.6,10.25 ; J15.58 v2(132.32,38.11) ; C286.2 v2(19.72,72.85) ; J11.2 192.02,103.22 ; J11.2 193.02,102.22 ; J11.2 191.03,102.22 ; J11.2 192.02,101.23 ; U37.H4 v1(107.98,65.75) ; 200.13,146.8 M2.1 196.72,150.21 ; v2(154.69,12.82) 154.18,12.82 C458.2 154.18,13.83 v2(154.69,13.83) ; v1(97.58,83.35) 97.98,82.95 U37.AJ16 ; v1(105.58,62.55) 105.18,62.95 U37.D7 ; v1(89.29,88.74) C222.2 v1(88.59,88.74) ; U37.AH20 94.78,82.15 v1(94.38,82.55) ; 51.08,148.96 J7.5 ; J7.5 52.45,150.33 ; J7.5 52.45,147.59 ; J7.5 53.82,148.96 ; v2(46.86,34.15) R216.2 R214.2 ; J16.SH1 106.08,11.1 ; J16.SH1 106.08,7.85 ; J16.SH1 104.81,9.48 ; J16.SH1 107.35,9.48 ; v1(97.58,62.55) 97.98,62.95 U37.D16 ; J18.SH4 142.09,5.65 ; J18.SH4 141.19,4.18 ; J18.SH4 142.09,2.71 ; J18.SH4 143,4.18 ; 88.9,147.4 M5.1 ; M5.1 91.35,149.85 ; M5.1 86.45,149.85 ; v1(99.98,72.94) 99.58,72.54 U37.T14 ; C388.2 v2(115.19,28.95) ; U37.P8 104.38,70.95 v1(104.78,70.55) ; U37.A7 v1(105.58,60.14) ; v2(23.29,24.45) C408.2 ; R67.1 v2(20.83,112.26) ; P3.5 74.68,5.17 ; P3.5 76.05,3.8 ; P3.5 74.68,2.43 ; P3.5 73.3,3.8 ; U40.N4 129.05,67.43 v1(128.66,67.76) ; U37.G15 98.78,65.35 v1(98.38,64.95) ; v2(179.58,114.92) 179.64,114.86 U14.13 ; C362.2 v2(84.58,44.82) ; U40.Y1 131.45,71.98 v1(131.86,72.31) ; U37.L7 v1(105.58,68.15) ; D16.2 v2(134.35,19.17) ; U55.3 v2(39.63,29.32) ; v2(18.29,37.33) C370.2 ; v2(31.24,67.19) 31.24,66.61 C303.2 32,66.61 v2(32,67.19) ; 52.96,2.43 P2.4 54.33,3.8 ; U37.L17 97.18,68.55 v1(96.78,68.15) ; C209.2 32.26,87.87 v2(32.28,87.85) U32.6 ; U37.L3 v1(108.78,68.15) ; J15.57 v2(132.32,47.23) ; v2(197.87,75.17) 197.98,75.29 Q2.1 ; v2(16.18,17.64) C441.2 ; U14.42 v2(173.29,120.07) ; U25.13 v2(38.73,98.92) ; U40.T3 129.85,69.38 v1(129.46,69.71) ; U37.E1 v1(110.38,63.35) ; C295.2 v2(20.7,67.81) ; U37.M6 105.98,69.35 v1(106.38,68.95) ; v1(103.18,70.55) 102.78,70.95 U37.P10 ; C133.2 v2(30.35,105.53) ; 21.46,141.61 21.83,141.61 v2(22.59,140.85) 22.59,140.08 R8.2 ; 21.46,141.61 21.46,141.59 ; 21.46,141.61 21.45,141.61 ; PL1.2 v2(55.24,111.24) ; U52.25 v2(34.72,33.14) ; v1(89.03,92.57) C190.2 v1(88.27,92.57) ; U37.AA13 100.38,76.55 v1(100.78,76.95) ; v1(104.78,80.95) 104.38,80.55 U37.AF8 ; U39.5 v2(23.75,67.43) ; C407.2 30.86,25.14 30.46,25.54 v2(30.23,25.54) 29.95,25.82 U52.13 ; U37.L13 v1(100.78,68.15) ; C289.2 v2(27.05,70.35) ; U37.C8 v1(104.78,61.75) ; R35.1 v2(105.03,125.26) ; v1(93.58,76.15) 93.98,75.75 U37.Y21 ; v2(24.89,62.85) 24,62.85 23.52,63.34 C305.1 23.52,63.39 24.13,64 v2(24.89,64) ; 56.67,8.88 P2.3 ; P2.3 58.04,7.51 ; P2.3 58.04,10.25 ; P2.3 59.41,8.88 ; v1(96.78,61.75) 97.18,62.15 U37.C17 ; U40.E5 128.1,62.07 127.3,62.07 v1(127.19,61.97) ; v1(97.58,76.95) 97.98,76.55 U37.AA16 ; C384.2 v2(113.28,31.36) ; U37.C1 v1(110.38,61.75) ; U37.T16 97.98,72.55 v1(97.58,72.15) ; U37.R7 105.18,71.75 v1(105.58,71.35) ; U37.AG13 100.38,81.35 v1(100.78,81.75) ; U19.79 52.21,111.1 v2(52.32,110.99) 51.94,110.6 U19.78 ; v2(193.29,56.63) 192.93,56.27 U46.13 ; 36.83,148.6 J5.5 ; J5.5 38.2,149.98 ; J5.5 36.83,151.25 ; J5.5 35.46,149.98 ; v1(104.78,74.55) 104.38,74.15 U37.V8 ; 87.61,8.88 P4.2 86.23,10.25 ; U37.Y8 104.38,75.75 v1(104.78,76.15) ; U20.6 81.27,105.67 v1(81.41,105.53) ; 52.45,143.88 52.45,145.25 ; 52.45,143.88 52.45,142.51 ; 52.45,143.88 53.82,143.88 ; 52.45,143.88 51.08,143.88 ; v1(100.78,78.55) 100.38,78.15 U37.AC13 ; R84.1 v2(166.5,95.7) ; U40.AB10 124.25,73.82 v1(124.26,73.82) ; U40.V8 125.85,70.68 v1(125.46,70.36) ; U37.T10 102.78,72.55 v1(103.18,72.15) ; U37.P14 v1(99.98,70.55) ; v1(122.25,72.31) 122.65,71.98 U40.Y12 ; v2(21.39,22.72) C415.2 22.33,22.75 ; U25.12 v2(39.6,101.36) 39.75,101.51 U25.11 ; R140.2 v2(6.48,72.51) ; Q1.1 v2(127.62,127.64) 127.64,127.62 R26.2 ; v2(77.6,127.88) 77.36,128.12 U10.3 ; U62.2 95.6,8.21 ; v2(38.54,109.26) 38.71,109.1 U19.36 ; v2(174.24,115.05) 173.93,114.73 U14.4 ; C45.2 84.66,130.98 ; v1(103.18,80.15) 102.78,79.75 U37.AE10 ; R148.1 v2(21.72,65.65) ; v1(100.78,66.55) 100.38,66.95 U37.J13 ; U23.1 v2(51.89,101.06) ; U37.AG19 95.58,81.35 v1(95.18,81.75) ; U31.G3 v2(155.79,88.21) ; v1(103.98,73.75) 103.58,73.35 U37.U9 ; D18.2 v2(137.28,19.17) ; U2.24 v2(83.79,134.07) ; U37.E15 98.78,63.75 v1(98.38,63.35) ; U31.G5 v2(155.79,86.21) ; C54.2 18.4,130.55 U9.2 v2(18.41,131.31) ; U37.P28 88.38,70.95 v1(87.98,70.55) ; 103.5,104.64 v2(102.83,104.64) ; 91.31,2.43 P4.5 ; P4.5 92.69,3.8 ; P4.5 91.31,5.17 ; P4.5 89.94,3.8 ; RJ4.1 RJ5.1 RJ6.1 RJ7.1 v2(68.2,81.9) ; U37.AA7 105.18,76.55 v1(105.58,76.95) ; U45.3 v2(78.99,54.45) ; v1(112.31,20.52) 112.24,20.45 C435.2 ; v1(107.18,82.55) 106.78,82.15 U37.AH5 ; v2(17.14,93.84) C177.1 18.4,94.6 U29.2 ; U40.C8 125.85,60.93 U40.D9 125.06,61.59 125.45,61.91 v1(125.45,61.91) ; C365.2 v2(78.77,41.01) ; C390.2 72.14,28.11 v2(72.14,27.55) ; U19.73 52.16,108.1 v2(52.32,107.94) 51.99,107.6 U19.72 ; C273.2 v2(19.72,77.42) ; L1.1 v2(68.83,150.1) ; U19.68 52.02,105.6 v2(52.32,105.91) 52.13,106.1 U19.69 ; U37.U19 v1(95.18,73.75) ; J8.1B 8.32,139.02 ; J8.1B 6.99,140.36 ; J8.1B 6.99,137.69 ; J8.1B 5.65,139.02 ; U19.70 52,106.6 v2(52.32,106.92) 52.14,107.1 U19.71 ; v1(93.58,66.55) 93.98,66.95 U37.J21 ; v2(17.14,112.89) C102.1 18.4,113.65 U17.2 ; U8.10 112.62,129.94 v2(112.78,129.78) ; v1(93.58,72.15) 93.98,72.55 U37.T21 ; v2(39.12,49.76) 39.12,50.33 C345.2 39.88,50.33 v2(39.88,49.76) ; U47.3 143.53,49.5 v2(143.64,49.39) ; v1(86.49,92.57) C189.2 v1(85.72,92.57) ; R69.2 v2(186.56,107.81) ; v1(101.58,76.15) 101.18,75.75 U37.Y12 ; U37.K22 93.18,67.75 v1(92.78,67.35) ; 5.65,90.92 J12.1A ; J12.1A 8.32,90.92 ; J12.1A 6.99,92.26 ; J12.1A 6.99,89.59 ; D15.2 v2(131.33,19.17) ; U40.G8 v1(125.45,63.86) ; U37.C5 v1(107.18,61.75) ; v2(48.66,101.83) U22.1 U23.3 ; v1(96.78,79.35) 97.18,78.95 U37.AD17 ; R46.2 v2(22.61,121.78) 21.84,122.54 21.46,122.54 ; U40.W11 123.45,71.33 v1(123.06,71.01) 122.65,70.68 U40.V12 ; v1(98.38,80.15) 98.78,79.75 U37.AE15 ; C55.1 74.93,129.09 v2(75.38,128.64) ; U19.62 48.72,103.67 v2(48.9,103.49) 49.22,103.82 U19.63 ; U40.D11 v1(123.05,61.91) U40.E12 ; Q2.4 v2(199.28,78.73) ; U40.N9 125.05,67.43 v1(125.45,67.76) ; U19.35 38.98,109.6 v2(38.61,109.97) 38.74,110.1 U19.34 ; v2(113.54,96.26) 113.28,96 R95.2 ; U2.7 v2(77.19,148.17) ; v1(96.78,82.55) 97.18,82.15 U37.AH17 ; C367.2 v2(26.97,42.53) ; R47.2 v2(143.89,119.62) ; U27.36 131.69,94.63 v2(131.44,97.4) ; v2(81.64,66.54) 82.35,66.54 C297.2 ; C161.2 18.4,98.8 U26.2 v2(18.41,99.56) ; 109.59,8.59 J16.4 110.58,7.59 ; M4.1 8.61,5.83 ; M4.1 5.21,9.24 ; M4.1 5.21,2.43 ; M4.1 1.8,5.83 ; 58.04,15.48 v2(57.4,14.85) ; 146.69,143.41 J2.7 145.9,142.62 ; U40.C12 v1(122.25,60.61) ; C445.2 C446.2 66.55,17.01 v2(66.29,16.75) ; v1(110.38,70.55) 109.98,70.95 U37.P1 ; J5.2 41.91,146.27 ; J5.2 41.91,143.52 ; J5.2 43.28,144.9 ; J5.2 40.54,144.9 ; v1(105.58,80.15) 105.18,79.75 U37.AE7 ; U37.U21 93.98,73.35 v1(93.58,73.75) ; v2(29.59,61.84) U41.2 29.45,61.2 v2(28.7,61.2) v2(27.69,61.2) v2(26.67,61.2) 24.78,61.2 24.66,61.33 v2(24.13,61.33) v2(23.11,61.33) v2(22.1,61.33) v2(21.08,61.33) v2(20.07,61.33) ; R242.2 v2(92.46,18.4) ; 140.12,144.43 J2.G2 ; J2.G2 138.43,146.12 ; J2.G2 140.12,147.81 ; J2.G2 141.8,146.12 ; U37.V14 99.58,74.15 v1(99.18,74.55) ; C266.2 193.47,77.89 v2(193.8,78.22) ; C259.2 17.4,82.41 v2(17.7,82.72) 17.91,82.51 C260.2 ; v1(103.98,60.95) 103.58,61.35 U37.B9 ; v2(26.67,68.96) 26.67,68.39 C296.2 27.43,68.39 v2(27.43,68.96) ; U37.AF17 97.18,80.55 v1(96.78,80.95) ; U40.A10 v1(124.25,59.09) ; R43.2 v2(143.89,121.66) ; U37.F14 v1(99.98,64.15) ; U37.L23 92.38,68.55 v1(91.98,68.15) ; U35.3 149.97,75.06 v2(150.5,74.54) 150.62,74.67 U35.2 ; M1.1 5.59,150.21 ; M1.1 5.59,143.4 ; M1.1 8.99,146.8 ; M1.1 2.18,146.8 ; v1(97.58,81.75) 97.98,81.35 U37.AG16 ; U19.33 38.87,110.6 v2(38.61,110.86) 38.85,111.1 U19.32 ; U32.1 34.77,87.59 v2(35.05,87.87) ; U40.J3 v1(130.26,65.16) U40.K2 ; v1(95.18,80.15) 95.58,79.75 U37.AE19 ; U2.12 v2(69.79,148.12) ; v1(96.78,71.35) 97.18,71.75 U37.R17 ; C394.2 v2(120.52,26.15) ; U19.65 50.22,103.57 v2(50.42,103.37) 50.72,103.66 U19.66 ; v2(189.74,54.47) 189.89,54.32 U46.10 193.9,54.32 194.12,54.54 195.39,54.54 195.61,54.32 196.95,54.32 196.98,54.35 ; U31.G6 v2(155.79,84.21) ; v2(17.4,57.39) 17.4,56.76 17.91,56.25 18.92,56.25 v2(20.07,57.39) v2(21.08,57.39) v2(22.1,57.39) v2(23.11,57.39) v2(24.13,57.39) v2(26.67,57.39) v2(27.69,57.39) v2(28.7,57.39) 29.45,57.39 U43.2 v2(29.59,56.76) ; v1(97.58,68.95) 97.98,69.35 U37.M16 ; U37.B12 101.18,61.35 v1(101.58,60.95) ; Q6.S v2(150.8,53.13) ; U31.L3 v2(150.79,88.21) ; R64.1 v2(53.59,110.86) ; U37.L15 98.78,68.55 v1(98.38,68.15) ; U51.3 v2(39.63,36.43) ; U37.AF11 101.98,80.55 v1(102.38,80.95) ; U37.F8 104.38,64.54 v1(104.78,64.15) ; v1(105.97,20.52) 105.73,20.52 105.43,20.22 105.43,19.61 C432.2 ; v1(95.18,76.15) 95.58,75.75 U37.Y19 ; U37.H8 v1(104.78,65.75) ; C839.1 v2(149.99,71.24) ; v2(37.08,60.7) 36.58,61.2 36.58,61.58 ; v2(100.46,25.14) 101.09,25.14 101.4,24.83 C405.2 101.38,24.79 100.97,24.37 v2(100.46,24.37) ; U31.M4 v2(150.79,86.21) ; 52.96,10.25 P2.2 54.33,8.88 ; U37.D4 v1(107.98,62.55) ; U40.T5 128.25,69.38 v1(128.66,69.06) ; U37.AJ19 95.58,82.95 v1(95.18,83.35) ; v1(99.18,82.55) 99.58,82.15 U37.AH14 ; U37.W20 v1(94.38,75.35) ; U37.K16 97.98,67.75 v1(97.58,67.35) ; v2(36.32,84.57) 36.06,84.83 U32.21 ; U46.14 v2(191.77,57.65) ; v1(131.06,71.66) 130.65,71.33 U40.W2 ; U37.M28 88.38,69.35 v1(87.98,68.95) ; v1(126.25,73.76) 125.85,73.28 U40.AB8 ; v1(97.58,75.35) 97.98,74.95 U37.W16 ; U37.P12 101.18,70.95 v1(101.58,70.55) ; U37.AD11 101.98,78.95 v1(102.38,79.35) ; U37.G7 v1(105.58,64.95) ; D21.2 v2(134.36,17.52) ; U37.K4 v1(107.98,67.35) ; v2(188.21,89.4) 188.21,88.89 188.52,88.59 C230.2 188.67,88.59 188.98,88.89 v2(188.98,89.4) ; Y3.4 v2(41.22,64.12) ; v1(95.18,71.35) 95.58,71.75 U37.R19 ; U37.A10 v1(103.18,60.14) ; 21.46,128.27 21.45,128.27 ; 21.46,128.27 21.46,128.26 ; 36.32,2.43 P1.4 37.69,3.8 ; U40.E1 v1(131.86,62.56) ; U31.G7 v2(155.79,83.21) ; R37.2 v2(107.06,125.26) ; v1(97.58,60.14) 97.98,60.54 U37.A16 ; R169.2 v2(79.38,58.92) ; U37.N7 v1(105.58,69.75) ; U40.G3 v1(130.26,63.86) ; R112.2 v2(15.2,85.88) ; v1(97.58,70.55) 97.98,70.95 U37.P16 ; C183.2 v2(166.5,94.17) ; v1(130.26,59.96) 129.85,59.63 U40.A3 ; 131.3,20.1 131.23,20.1 ; 131.3,20.1 R241.1 ; 131.3,20.1 v1(131.3,21.12) ; v2(72.9,27.42) 72.9,26.86 C398.2 ; C379.2 v2(70.99,34.53) ; v1(99.18,80.95) 99.58,80.55 U37.AF14 ; C400.2 v2(120.65,25.14) ; U50.2 v2(31.5,53.46) ; 92.61,144.52 J6.3 ; J6.3 93.98,145.89 ; J6.3 93.98,143.14 ; J6.3 95.35,144.52 ; U37.U5 106.78,73.35 v1(107.18,73.75) ; v1(93.58,68.15) 93.98,68.55 U37.L21 ; D4.1 v2(144.46,137.09) ; U37.K1 v1(110.38,67.35) ; v1(107.98,83.35) 107.58,82.95 U37.AJ4 ; v1(95.98,72.15) 96.38,72.55 U37.T18 ; v1(103.18,62.55) 102.78,62.95 U37.D10 ; R17.1 v2(140.46,132.45) ; U19.57 46.22,103.74 v2(45.97,103.49) 45.72,103.75 U19.56 ; 22.61,101.97 v2(22.61,102.73) 21.84,103.49 21.46,103.49 ; C235.2 v2(6.48,88.13) ; C456.2 v2(11.86,13.71) ; C199.2 18.4,92.45 U30.2 v2(18.41,93.21) ; v1(103.18,76.15) 102.78,75.75 U37.Y10 ; U40.P12 122.65,68.08 v1(122.25,67.76) ; v1(128.66,65.16) U40.K4 ; U40.C1 v1(131.06,61.26) U40.D2 ; C368.2 v2(30.48,39.99) ; v1(105.58,81.75) 105.18,81.35 U37.AG7 ; C3.2 v2(115.32,146.29) ; v1(95.18,62.55) 95.58,62.95 U37.D19 ; U40.G5 v1(128.66,63.21) ; v2(101.09,128.89) R25.2 C56.2 ; v1(98.38,60.95) 98.78,61.35 U37.B15 ; v1(98.38,76.15) 98.78,75.75 U37.Y15 ; R231.2 v2(37.08,26.66) ; C47.1 v2(100.89,130.34) ; C410.2 v2(120.52,24.12) ; v1(98.38,66.55) 98.78,66.95 U37.J15 ; U2.13 v2(69.79,133.97) ; 23.61,136.01 R9.1 ; 23.61,136.01 23.61,136.02 ; 23.61,136.01 v2(23.61,135.26) ; C346.2 v2(35.43,50.28) ; v1(95.98,76.95) 96.38,76.55 U37.AA18 ; v1(100.78,75.35) 100.38,74.95 U37.W13 ; R137.2 v2(7.87,75.05) ; C313.1 v2(189.74,61.08) ; U20.36 73.81,106.17 74.04,105.93 v2(76.58,106.42) 74.04,104.92 73.79,105.17 U20.38 ; U27.6 132.2,102.09 v1(132.33,102.22) ; v1(102.38,76.95) 101.98,76.55 U37.AA11 ; v1(95.18,69.75) 95.58,70.15 U37.N19 ; 36.32,10.25 P1.2 37.69,8.88 ; RJ2.3 v2(153.92,121.78) ; U37.J9 v1(103.98,66.55) ; v1(87.18,69.75) 87.58,70.15 U37.N29 ; R34.2 v2(103.76,125.26) ; v1(102.38,82.55) 101.98,82.15 U37.AH11 ; v1(101.58,80.15) 101.18,79.75 U37.AE12 ; D17.2 v2(140.3,19.17) ; v1(94.38,77.75) 94.78,77.35 U37.AB20 ; U37.F4 v1(107.98,64.15) ; v1(109.58,82.55) 109.18,82.15 U37.AH2 ; C374.2 v2(15.75,34.03) ; v1(97.58,78.55) 97.98,78.15 U37.AC16 ; C389.2 v2(70.99,28.18) ; U22.3 v2(46.61,101.06) ; U3.2 18.4,139.05 C17.1 v2(17.14,138.29) ; v1(102.38,64.95) 101.98,65.35 U37.G11 ; C39.2 v2(81.79,131.18) ; R252.1 v2(95.63,16.63) ; v1(105.58,66.55) 105.18,66.95 U37.J7 ; v1(112.78,15.11) R249.2 112.78,15.86 ; 23.62,116.96 v2(23.62,116.19) ; v2(154.81,4.43) 154.31,4.43 C478.2 154.31,3.42 v2(154.81,3.42) ; U31.M7 v2(150.78,84.2) ; R101.1 v2(23.62,90.79) 22.99,90.16 21.46,90.16 ; C371.2 v2(14.71,35.04) ; U40.J1 v1(131.86,65.16) ; U31.H2 v2(154.79,89.21) ; U40.P10 124.25,68.08 v1(123.85,67.76) 123.45,67.43 U40.N11 ; U37.E12 v1(101.58,63.35) ; C372.2 v2(36.25,35.3) ; U19.74 51.97,108.6 v2(52.32,108.96) 52.18,109.1 U19.75 ; R103.1 v2(20.83,93.21) ; C113.2 v2(171.2,108.24) ; 124.69,4.18 J18.SH3 ; J18.SH3 126.5,4.18 ; J18.SH3 125.59,2.71 ; U37.AG10 102.78,81.35 v1(103.18,81.75) ; U25.22 44.17,97.17 v2(44.32,97.02) ; U37.H16 97.98,66.15 v1(97.58,65.75) ; U37.G17 97.18,65.35 v1(96.78,64.95) ; v1(123.85,63.86) U40.G10 ; P4.3 91.31,10.25 ; P4.3 91.31,7.51 ; P4.3 92.69,8.88 ; P4.3 89.94,8.88 ; U19.80 52.05,111.6 v2(52.32,111.88) 52.1,112.1 U19.81 ; U37.H20 94.78,66.15 v1(94.38,65.75) ; U40.K11 v1(123.85,65.16) U40.J10 ; C237.2 v2(27.3,86.35) ; U19.83 v2(52.41,113.1) ; U31.J5 v2(153.79,86.21) ; C443.2 v2(55.68,17.06) ; U37.D13 100.38,62.95 v1(100.78,62.55) ; U37.H12 v1(101.58,65.75) ; v2(17.4,26.41) 17.4,27.17 ; U37.H6 v1(106.38,65.75) ; U31.H9 v2(154.79,81.2) ; 86.23,2.43 P4.4 87.61,3.8 ; C348.2 v2(141.1,49.98) ; U37.AG4 107.58,81.35 v1(107.98,81.75) ; R136.2 v2(152.53,74.16) ; U37.L9 v1(103.98,68.15) ; R54.1 v2(20.83,118.61) ; v2(21.26,17.64) C449.2 ; Q8.1 v2(90.68,22) ; R97.2 v2(22.61,96.38) ; C321.2 v2(32,56.12) ; U37.J11 v1(102.38,66.55) ; v1(95.18,68.15) 95.58,68.55 U37.L19 ; v1(125.45,69.06) 125.85,69.38 U40.T8 ; U37.C14 v1(99.98,61.75) ; U7.4 v2(133.67,133.28) ; U31.P9 v2(147.78,81.2) ; D6.2 v2(151.64,94.19) ; C240.2 v2(21.3,85.37) ; C283.2 v2(26.29,74.41) ; v2(5.21,87.75) R114.2 R113.2 ; U31.G8 v2(155.79,82.2) ; C261.2 v2(19.85,81.99) ; DS1.1 v2(159.26,3.29) ; J15.16 v2(142.81,38.28) ; C96.2 18.4,117.85 U15.2 v2(18.41,118.61) ; v2(19.86,23.99) U56.2 ; D22.2 v2(137.38,17.52) ; C391.2 v2(76.33,30.47) ; R74.2 v2(105.28,105.78) ; U31.L8 v2(150.79,82.2) ; C467.2 v2(160.27,6.09) ; R218.2 v2(37.08,33.77) ; U37.AF5 106.78,80.55 v1(107.18,80.95) ; C92.1 v2(48.9,118.86) ; U14.25 v2(184.09,120.07) ; R61.2 v2(130.43,113.15) ; R253.1 v3(96.9,16.37) ; v1(132.69,100.67) U27.5 ; U37.AB19 95.58,77.35 v1(95.18,77.75) ; v1(108.78,71.35) 108.38,71.75 U37.R3 ; D20.2 v2(131.31,17.52) ; U37.E5 v1(107.18,63.35) ; U37.H10 v1(103.18,65.75) ; U31.P2 v2(147.78,89.21) ; 10.79,31.1 11.43,31.1 v2(11.76,30.78) ; R256.2 v2(120.78,10.53) ; SW1.3 v2(201.17,73.4) ; Q8.4 92.6,24.52 v2(92.96,24.88) ; C381.2 v2(76.33,31.99) ; SW3.1 v2(5.71,24.25) ; U37.AB22 v1(92.78,77.75) ; U38.3 v2(196.61,69.46) ; C385.2 v2(47.62,29.96) ; v2(19.35,32.37) 20.07,32.37 ; D23.2 v2(140.2,17.52) ; C90.2 v2(143.89,118.61) ; v2(200.53,16.37) 200.53,16.88 C448.2 201.29,16.88 v2(201.29,16.37) ; v1(79.85,105.17) U20.5 ; U40.AB3 v1(129.85,73.82) ; R80.1 v2(20.83,99.56) ; U37.A13 v1(100.78,60.14) ; C281.2 v2(27.56,74.67) ; C332.2 v2(37.21,55.36) ; U64.2 v2(176.28,8.24) ; U31.G2 v2(155.79,89.21) ; U49.3 v2(149.11,49.41) ; v2(18.41,112.26) U18.2 18.4,111.5 C109.2 ; v2(19.23,30.22) C387.2 ; U40.G1 v1(131.86,63.86) ; v1(100.78,83.35) 100.38,82.95 U37.AJ13 ; C397.2 v2(76.33,24.63) ; D24.2 v2(143.22,17.52) ; R56.2 v2(152.78,114.8) ; U55.14 v2(44.95,29.32) ; U40.J12 v1(122.25,64.51) ; R235.1 v2(26.29,23.36) ; R44.2 v2(143.89,120.64) ; U37.H14 v1(99.98,65.75)
  TOP w0.356: U14.21 v2(184.72,114.86)
  TOP w0.381: v2(20.62,19.32) 19.51,19.32 ; 19.51,19.32 Y5.4 ; 19.51,19.32 19.48,19.32 ; v2(16.28,15.61) 17.3,15.61 Y5.2 ; C386.2 v1(104.27,30.99)
  TOP w0.406: v2(33.78,120.72) 33.78,120.21 C87.2 33.02,120.21 v2(33.02,120.72) ; v2(97.54,120.89) 97.92,120.89 C82.2 97.92,119.88 v2(97.54,119.88) ; v2(37.72,117.01) 37.72,117.52 C89.2 38.48,117.52 v2(38.48,117.01) ; v2(28.57,106.11) 28.57,105.6 C132.2 29.34,105.6 v2(29.34,106.11) ; v2(95,117.72) 95.5,117.72 C97.2 95.5,116.96 v2(95,116.96) ; v2(34.04,102.4) 34.04,102.91 C134.2 33.27,102.91 v2(33.27,102.4)
  TOP w0.508: R255.1 v2(21.77,11.93) ; v2(143,128.26) 143.51,128.26 C65.2 143.51,127.24 v2(143,127.24) ; v2(143,124.83) 143.51,124.83 C72.2 143.51,125.85 v2(143,125.85) ; v2(144.02,116.45) 144.53,116.45 C100.2 144.53,115.43 v2(144.02,115.43) ; C58.2 v2(86.49,128.01) ; C107.2 115.7,112.89 v2(115.32,113.27) ; C227.2 v2(26.21,87.87) ; C21.1 v2(137.29,137.28) ; C203.2 v2(26.21,89.91) ; R60.1 98.93,114.04 v2(99.19,114.29) ; v2(201.93,2.02) v2(201.93,3.93) v2(201.93,8.37) v2(201.93,11.55) v2(201.93,14.72) v2(201.93,17.9) v2(201.93,21.07) v2(201.93,24.25) v2(201.93,27.42) v2(201.93,30.6) v2(201.93,33.77) v2(201.93,36.95) v2(201.93,40.12) v2(201.93,43.3) v2(201.93,46.47) v2(201.93,49.65) v2(201.93,52.82) v2(201.93,56) v2(201.93,59.17) v2(201.93,62.35) v2(201.93,65.52) v2(201.93,68.7) v2(201.93,71.87) v2(201.93,75.05) v2(201.93,78.22) v2(201.93,81.4) v2(201.93,84.57) v2(201.93,87.75) v2(201.93,90.92) v2(201.93,94.1) v2(201.93,97.27) v2(201.93,100.45) v2(201.93,103.62) v2(201.93,106.8) v2(201.93,109.97) v2(201.93,113.15) v2(201.93,116.32) v2(201.93,119.5) v2(201.93,122.67) v2(201.93,125.85) v2(201.93,129.02) v2(201.93,132.2) v2(201.93,135.37) v2(201.93,138.55) v2(201.93,141.72) v2(201.93,144.9) v2(201.93,148.07) v2(201.93,151.25) v2(198.12,151.25) v2(194.94,151.25) v2(191.77,151.25) v2(188.59,151.25) v2(185.42,151.25) v2(182.25,151.25) v2(179.07,151.25) v2(175.9,151.25) v2(172.72,151.25) v2(169.54,151.25) v2(166.37,151.25) v2(163.19,151.25) v2(160.02,151.25) v2(92.2,151.25) v2(83.82,151.25) v2(80.64,151.25) v2(77.47,151.25) v2(74.3,151.25) v2(71.12,151.25) v2(67.94,151.25) v2(61.59,151.25) v2(58.42,151.25) v2(55.24,151.25) v2(52.07,151.25) v2(48.9,151.25) v2(45.72,151.25) v2(43.18,151.25) v2(39.37,151.25) v2(35.56,151.25) v2(33.02,151.25) v2(29.84,151.25) v2(26.67,151.25) v2(23.5,151.25) v2(20.32,151.25) v2(17.14,151.25) v2(13.97,151.25) v2(10.79,151.25) v2(7.62,151.25) v2(4.45,151.25) v2(1.27,151.25) v2(1.27,148.07) v2(1.27,144.9) v2(1.27,141.72) v2(1.27,138.55) v2(1.27,135.37) v2(1.27,132.2) v2(1.27,129.02) v2(1.27,125.85) v2(1.27,122.67) v2(1.27,119.5) v2(1.27,116.32) v2(1.27,113.15) v2(1.27,109.97) v2(1.27,106.8) v2(1.27,103.62) v2(1.27,100.45) v2(1.27,97.27) v2(1.27,94.1) v2(1.27,90.92) v2(1.27,88.38) v2(1.27,84.57) v2(1.27,81.4) v2(1.27,78.22) v2(1.27,75.05) v2(1.27,71.87) v2(1.27,68.7) v2(1.27,65.52) v2(1.27,62.35) v2(1.27,59.17) v2(1.27,56) v2(1.27,52.82) v2(1.27,49.65) v2(1.27,46.47) v2(1.27,43.3) v2(1.27,40.12) v2(1.27,36.95) v2(1.27,33.77) v2(1.27,30.6) v2(1.27,27.42) v2(1.27,24.25) v2(1.27,21.07) v2(1.27,17.9) v2(1.27,14.72) v2(1.27,11.55) v2(1.27,8.37) v2(1.27,5.2) v2(1.27,2.02) ; v2(137.92,135.75) 137.92,135.24 C37.2 136.91,135.24 v2(136.91,135.75) ; C252.2 v2(26.21,82.79) ; C101.2 v2(115.7,114.8) ; C244.2 v2(26.21,84.83) ; v2(144.02,113.91) 144.53,113.91 C104.2 144.53,112.89 v2(144.02,112.89) ; C245.2 v2(40.21,84.83) ; C60.1 v2(144.15,129.66) ; C59.2 v2(88.65,128.01) ; C228.2 v2(40.21,87.87)
  L2-SIGNAL w0.305: J9.1B 6.99,121.51 ; J9.1B 5.45,119.97 ; J9.1B 8.52,119.97 ; J5.3 36.83,146.47 ; J5.3 38.41,144.9 ; J5.3 35.25,144.9 ; J5.3 36.83,143.32 ; J11.2 193.22,102.22 ; J11.2 190.83,102.22 ; J11.2 192.02,103.42 ; J11.2 192.02,101.03 ; J5.2 43.49,144.9 ; J5.2 41.91,143.32 ; J5.2 41.91,146.47 ; J5.2 40.33,144.9 ; J1.G2 121.19,148.02 ; J1.G2 121.19,144.23 ; J1.G2 123.08,146.12 ; J1.G2 119.3,146.12 ; J6.4 99.06,151.17 ; J6.4 97.48,149.6 ; J6.4 99.06,148.02 ; J6.4 100.64,149.6 ; 6.99,89.38 J12.1A ; J12.1A 5.45,90.92 ; J12.1A 8.52,90.92 ; 192.29,117.46 HS1.2 ; HS1.2 194.94,120.12 ; HS1.2 194.94,114.81 ; HS1.2 197.6,117.46 ; J7.5 52.45,150.54 ; J7.5 52.45,147.39 ; J7.5 54.03,148.96 ; J7.5 50.88,148.96 ; 5.45,129.02 J8.1A ; J8.1A 8.52,129.02 ; J8.1A 6.99,127.48 ; 196.72,144.15 M2.1 ; M2.1 199.38,146.8 ; M2.1 194.07,146.8 ; M2.1 196.72,149.46 ; M1.1 5.59,149.46 ; M1.1 2.93,146.8 ; M1.1 8.24,146.8 ; M1.1 5.59,144.15 ; 5.45,100.92 J12.1B ; J12.1B 8.52,100.92 ; J12.1B 6.99,102.46 ; 99.06,142.94 J6.2 ; J6.2 97.48,144.52 ; J6.2 99.06,146.09 ; J6.2 100.64,144.52 ; J2.4 144.18,144.12 ; J2.4 143.18,145.11 ; J2.4 142.19,144.12 ; 35.25,149.98 J5.5 ; J5.5 36.83,151.55 ; J5.5 36.83,148.4 ; J5.5 38.41,149.98 ; 40.33,149.98 J5.4 ; J5.4 41.91,148.4 ; J5.4 41.91,151.55 ; J5.4 43.49,149.98 ; 164.03,42.79 J14.2 ; J14.2 165.23,41.59 ; J14.2 165.23,43.98 ; J14.2 166.42,42.79 ; 145.69,142.62 J2.7 ; J2.7 146.69,143.61 ; J2.7 146.69,141.63 ; J2.7 147.68,142.62 ; 88.9,147.2 M5.1 ; M5.1 91.55,149.85 ; M5.1 86.25,149.85 ; 5.45,109.97 J9.1A ; J9.1A 6.99,108.43 ; J9.1A 8.52,109.97 ; J2.G2 142.01,146.12 ; J2.G2 140.12,148.02 ; J2.G2 140.12,144.23 ; J2.G2 138.22,146.12 ; 57.53,142.31 57.53,143.88 ; 57.53,143.88 59.11,143.88 ; 57.53,143.88 57.53,145.46 ; 57.53,143.88 55.96,143.88 ; 92.4,144.52 J6.3 ; J6.3 93.98,146.09 ; J6.3 93.98,142.94 ; J6.3 95.56,144.52 ; 5.45,139.02 J8.1B ; J8.1B 8.52,139.02 ; J8.1B 6.99,140.56 ; 64.64,147.2 M6.1 ; M6.1 61.99,149.85 ; M6.1 67.3,149.85 ; M3.1 201.41,6.34 ; M3.1 198.75,3.69 ; M3.1 198.75,8.99 ; M3.1 196.1,6.34 ; 55.68,104 J10.2 53.8,104 ; 52.45,143.88 52.45,145.46 ; 52.45,143.88 52.45,142.31 ; 52.45,143.88 50.88,143.88 ; 52.45,143.88 54.03,143.88 ; J17.2 189.87,10.41 ; J17.2 188.46,9.01 ; J17.2 189.87,7.6 ; J17.2 191.27,9.01 ; J2.G1 153.25,148.02 ; J2.G1 155.15,146.12 ; J2.G1 151.36,146.12 ; J2.G1 153.25,144.23 ; 92.4,149.6 J6.5 ; J6.5 95.56,149.6 ; J6.5 93.98,151.17 ; J6.5 93.98,148.02 ; 126.77,142.62 J1.7 ; J1.7 128.75,142.62 ; J1.7 127.76,141.63 ; J1.7 127.76,143.61 ; HS1.1 165.09,117.46 ; HS1.1 162.43,114.81 ; HS1.1 162.43,120.12 ; HS1.1 159.78,117.46 ; J1.G1 134.33,148.02 ; J1.G1 136.22,146.12 ; J1.G1 134.33,144.23 ; J1.G1 132.44,146.12 ; J7.4 59.11,148.96 ; J7.4 57.53,147.39 ; J7.4 55.96,148.96 ; J7.4 57.53,150.54 ; J1.4 124.26,145.11 ; J1.4 125.25,144.12 ; J1.4 123.27,144.12
  L2-SIGNAL w0.508: v2(4.45,151.25) v2(7.62,151.25) v2(10.79,151.25) v2(13.97,151.25) v2(17.14,151.25) v2(20.32,151.25) v2(23.5,151.25) v2(26.67,151.25) v2(29.84,151.25) v2(33.02,151.25) v2(35.56,151.25) v2(39.37,151.25) v2(43.18,151.25) v2(45.72,151.25) v2(48.9,151.25) v2(52.07,151.25) v2(55.24,151.25) v2(58.42,151.25) v2(61.59,151.25) v2(67.94,151.25) v2(71.12,151.25) v2(74.3,151.25) v2(77.47,151.25) v2(80.64,151.25) v2(83.82,151.25) v2(92.2,151.25) v2(160.02,151.25) v2(163.19,151.25) v2(166.37,151.25) v2(169.54,151.25) v2(172.72,151.25) v2(175.9,151.25) v2(179.07,151.25) v2(182.25,151.25) v2(185.42,151.25) v2(188.59,151.25) v2(191.77,151.25) v2(194.94,151.25) v2(198.12,151.25) v2(201.93,151.25) v2(201.93,148.07) v2(201.93,144.9) v2(201.93,141.72) v2(201.93,138.55) v2(201.93,135.37) v2(201.93,132.2) v2(201.93,129.02) v2(201.93,125.85) v2(201.93,122.67) v2(201.93,119.5) v2(201.93,116.32) v2(201.93,113.15) v2(201.93,109.97) v2(201.93,106.8) v2(201.93,103.62) v2(201.93,100.45) v2(201.93,97.27) v2(201.93,94.1) v2(201.93,90.92) v2(201.93,87.75) v2(201.93,84.57) v2(201.93,81.4) v2(201.93,78.22) v2(201.93,75.05) v2(201.93,71.87) v2(201.93,68.7) v2(201.93,65.52) v2(201.93,62.35) v2(201.93,59.17) v2(201.93,56) v2(201.93,52.82) v2(201.93,49.65) v2(201.93,46.47) v2(201.93,43.3) v2(201.93,40.12) v2(201.93,36.95) v2(201.93,33.77) v2(201.93,30.6) v2(201.93,27.42) v2(201.93,24.25) v2(201.93,21.07) v2(201.93,17.9) v2(201.93,14.72) v2(201.93,11.55) v2(201.93,8.37) v2(201.93,3.93) v2(201.93,2.02) 201.29,2.02 201.17,1.89 v2(198.12,1.89) v2(194.94,1.89) v2(191.77,1.89) v2(188.59,1.89) v2(185.42,1.89) v2(182.25,1.89) v2(179.07,1.89) v2(175.9,1.89) v2(172.72,1.89) v2(169.54,1.89) v2(166.37,1.89) v2(163.19,1.89) v2(160.02,1.89) v2(156.84,1.89) v2(153.67,1.89) v2(150.5,1.89) v2(147.32,1.89) v2(144.15,1.89) v2(140.97,1.89) v2(137.79,1.89) v2(135.64,1.89) 134.42,1.89 134.28,1.84 133.99,1.78 133.7,1.78 133.41,1.84 133.27,1.89 v2(131.44,1.89) v2(128.27,1.89) v2(125.09,1.89) v2(121.92,1.89) v2(118.75,1.89) v2(115.57,1.89) v2(112.39,1.89) v2(109.22,1.89) v2(106.05,1.89) v2(102.87,1.89) v2(99.69,1.89) v2(96.52,1.89) v2(93.34,1.89) v2(90.17,1.89) v2(87,1.89) v2(83.82,1.89) v2(80.64,1.89) v2(77.47,1.89) v2(74.3,1.89) v2(71.12,1.89) v2(67.94,1.89) v2(64.77,1.89) v2(61.59,1.89) v2(58.42,1.89) v2(55.24,1.89) v2(52.07,1.89) v2(48.9,1.89) v2(45.72,1.89) v2(42.55,1.89) v2(39.37,1.89) v2(36.2,1.89) v2(33.02,1.89) v2(29.84,1.89) v2(26.67,1.89) v2(23.5,1.89) v2(19.3,1.89) v2(16.89,1.89) v2(13.97,1.89) v2(10.16,1.89) v2(7.62,1.89) v2(4.45,1.89) 2.03,1.89 1.91,2.02 v2(1.27,2.02) v2(1.27,5.2) v2(1.27,8.37) v2(1.27,11.55) v2(1.27,14.72) v2(1.27,17.9) v2(1.27,21.07) v2(1.27,24.25) v2(1.27,27.42) v2(1.27,30.6) v2(1.27,33.77) v2(1.27,36.95) v2(1.27,40.12) v2(1.27,43.3) v2(1.27,46.47) v2(1.27,49.65) v2(1.27,52.82) v2(1.27,56) v2(1.27,59.17) v2(1.27,62.35) v2(1.27,65.52) v2(1.27,68.7) v2(1.27,71.87) v2(1.27,75.05) v2(1.27,78.22) v2(1.27,81.4) v2(1.27,84.57) v2(1.27,88.38) v2(1.27,90.92) v2(1.27,94.1) v2(1.27,97.27) v2(1.27,100.45) v2(1.27,103.62) v2(1.27,106.8) v2(1.27,109.97) v2(1.27,113.15) v2(1.27,116.32) v2(1.27,119.5) v2(1.27,122.67) v2(1.27,125.85) v2(1.27,129.02) v2(1.27,132.2) v2(1.27,135.37) v2(1.27,138.55) v2(1.27,141.72) v2(1.27,144.9) v2(1.27,148.07) v2(1.27,151.25) v2(4.45,151.25)
  L3-GND w0.305: P3.4 70.92,3.8 ; P3.4 69.6,2.48 ; P3.4 69.6,5.12 ; P3.4 68.27,3.8 ; J13.6 14.88,58.33 ; J13.6 13,58.33 ; J13.6 13.94,57.39 ; J13.6 13.94,59.27 ; 6.99,127.74 J8.1A ; J8.1A 5.7,129.02 ; J8.1A 6.99,130.31 ; J8.1A 8.27,129.02 ; 8.13,65.6 M7.1 ; M7.1 11.48,68.95 ; M7.1 8.13,72.3 ; M7.1 4.77,68.95 ; 104.86,3.71 J16.SH2 ; J16.SH2 107.3,3.71 ; J16.SH2 106.08,2.14 ; J16.SH2 106.08,5.29 ; 56.72,8.88 P2.3 ; P2.3 58.04,10.2 ; P2.3 59.36,8.88 ; P2.3 58.04,7.56 ; 64.64,147.45 M6.1 ; M6.1 67.04,149.85 ; M6.1 62.24,149.85 ; 6.99,89.64 J12.1A ; J12.1A 5.7,90.92 ; J12.1A 8.27,90.92 ; J12.1A 6.99,92.21 ; 92.66,149.6 J6.5 ; J6.5 95.3,149.6 ; J6.5 93.98,148.27 ; M4.1 5.21,9.19 ; M4.1 1.85,5.83 ; M4.1 8.56,5.83 ; M4.1 5.21,2.48 ; M2.1 200.08,146.8 ; M2.1 193.37,146.8 ; M2.1 196.72,150.16 ; M2.1 196.72,143.45 ; 138.48,146.12 J2.G2 ; J2.G2 141.75,146.12 ; J2.G2 140.12,147.76 ; J2.G2 140.12,144.48 ; 97.74,149.6 J6.4 ; J6.4 99.06,148.27 ; J6.4 100.38,149.6 ; 6.99,99.64 J12.1B ; J12.1B 6.99,102.21 ; J12.1B 8.27,100.92 ; J12.1B 5.7,100.92 ; 5.7,139.02 J8.1B ; J8.1B 6.99,140.31 ; J8.1B 6.99,137.74 ; J8.1B 8.27,139.02 ; 36.32,2.48 P1.4 ; P1.4 37.64,3.8 ; P1.4 36.32,5.12 ; P1.4 35,3.8 ; J9.1A 8.27,109.97 ; J9.1A 6.99,108.69 ; J9.1A 5.7,109.97 ; J9.1A 6.99,111.26 ; P4.5 91.31,5.12 ; P4.5 92.63,3.8 ; P4.5 89.99,3.8 ; P4.5 91.31,2.48 ; J17.2 191.02,9.01 ; J17.2 188.71,9.01 ; J17.2 189.87,7.85 ; J17.2 189.87,10.16 ; J16.4 109.59,8.53 ; J16.4 109.59,6.65 ; J16.4 110.53,7.59 ; J16.4 108.65,7.59 ; 56.21,143.88 57.53,143.88 ; 57.53,143.88 58.85,143.88 ; 57.53,143.88 57.53,142.56 ; 57.53,143.88 57.53,145.2 ; 6.99,118.69 J9.1B ; J9.1B 8.27,119.97 ; J9.1B 5.7,119.97 ; J9.1B 6.99,121.26 ; 124.26,143.39 J1.4 ; J1.4 123.52,144.12 ; J1.4 124.26,144.86 ; J1.4 125,144.12 ; P3.3 76,8.88 ; P3.3 73.35,8.88 ; P3.3 74.68,10.2 ; P3.3 74.68,7.56 ; J6.2 100.38,144.52 ; J6.2 99.06,145.84 ; J6.2 97.74,144.52 ; 165.23,41.85 J14.2 ; J14.2 165.23,43.73 ; J14.2 166.17,42.79 ; J14.2 164.29,42.79 ; 73.35,3.8 P3.5 ; P3.5 76,3.8 ; P3.5 74.68,5.12 ; P3.5 74.68,2.48 ; J11.2 192.02,103.17 ; J11.2 192.02,101.28 ; J11.2 192.96,102.22 ; J11.2 191.08,102.22 ; M8.1 8.13,21.76 ; M8.1 4.77,18.4 ; M8.1 11.48,18.4 ; M8.1 8.13,15.05 ; J18.SH1 125.59,12.64 ; J18.SH1 126.45,10.96 ; J18.SH1 125.59,9.28 ; J18.SH1 124.74,10.96 ; 88.9,147.45 M5.1 ; M5.1 91.3,149.85 ; M5.1 86.5,149.85 ; 36.32,7.56 P1.2 ; P1.2 35,8.88 ; P1.2 37.64,8.88 ; P1.2 36.32,10.2 ; 121.19,144.48 J1.G2 ; J1.G2 122.83,146.12 ; J1.G2 121.19,147.76 ; J1.G2 119.55,146.12 ; 58.04,2.48 P2.5 ; P2.5 56.72,3.8 ; P2.5 58.04,5.12 ; P2.5 59.36,3.8 ; J7.5 53.77,148.96 ; J7.5 52.45,150.28 ; J7.5 52.45,147.64 ; J7.5 51.13,148.96 ; P3.2 69.6,10.2 ; P3.2 70.92,8.88 ; P3.2 68.27,8.88 ; P3.2 69.6,7.56 ; 54.05,104 J10.2 55.42,104 ; 52.45,143.88 52.45,145.2 ; 52.45,143.88 52.45,142.56 ; 52.45,143.88 51.13,143.88 ; 52.45,143.88 53.77,143.88 ; J13.12 14.88,46.32 ; J13.12 13.94,45.38 ; J13.12 13,46.32 ; J13.12 13.94,47.26 ; J2.7 146.69,143.36 ; J2.7 147.42,142.62 ; J2.7 146.69,141.89 ; J2.7 145.95,142.62 ; 41.91,143.58 J5.2 ; J5.2 41.91,146.22 ; J5.2 40.59,144.9 ; J5.2 43.23,144.9 ; 36.83,143.58 J5.3 ; J5.3 35.51,144.9 ; J5.3 36.83,146.22 ; J5.3 38.15,144.9 ; J7.4 58.85,148.96 ; J7.4 56.21,148.96 ; J7.4 57.53,150.28 ; J7.4 57.53,147.64 ; J13.5 14.88,60.34 ; J13.5 13.94,61.28 ; J13.5 13,60.34 ; J13.5 13.94,59.4 ; 142.09,9.28 J18.SH2 ; J18.SH2 141.24,10.96 ; J18.SH2 142.95,10.96 ; J18.SH2 142.09,12.64 ; HS1.2 198.3,117.46 ; HS1.2 194.94,114.11 ; HS1.2 191.59,117.46 ; HS1.2 194.94,120.82 ; 41.4,7.56 P1.3 ; P1.3 42.72,8.88 ; P1.3 41.4,10.2 ; P1.3 40.08,8.88 ; 92.66,144.52 J6.3 ; J6.3 95.3,144.52 ; J6.3 93.98,145.84 ; P2.2 54.28,8.88 ; P2.2 51.64,8.88 ; P2.2 52.96,7.56 ; P2.2 52.96,10.2 ; P4.4 87.55,3.8 ; P4.4 86.23,2.48 ; P4.4 84.91,3.8 ; P4.4 86.23,5.12 ; 52.96,2.48 P2.4 ; P2.4 52.96,5.12 ; P2.4 51.64,3.8 ; P2.4 54.28,3.8 ; P1.5 42.72,3.8 ; P1.5 41.4,5.12 ; P1.5 41.4,2.48 ; P1.5 40.08,3.8 ; J5.5 38.15,149.98 ; J5.5 36.83,148.66 ; J5.5 35.51,149.98 ; J5.5 36.83,151.3 ; J16.SH1 107.3,9.48 ; J16.SH1 106.08,11.05 ; J16.SH1 104.86,9.48 ; J16.SH1 106.08,7.9 ; 159.08,117.46 HS1.1 ; HS1.1 162.43,114.11 ; HS1.1 165.79,117.46 ; HS1.1 162.43,120.82 ; J1.G1 134.33,147.76 ; J1.G1 135.97,146.12 ; J1.G1 134.33,144.48 ; J1.G1 132.69,146.12 ; J2.4 143.18,144.86 ; J2.4 143.18,143.39 ; J2.4 142.45,144.12 ; J2.4 143.92,144.12 ; J5.4 41.91,151.3 ; J5.4 40.59,149.98 ; J5.4 43.23,149.98 ; J5.4 41.91,148.66 ; 195.4,6.34 M3.1 ; M3.1 198.75,9.69 ; M3.1 202.11,6.34 ; M3.1 198.75,2.99 ; J18.SH3 126.45,4.18 ; J18.SH3 125.59,5.6 ; J18.SH3 124.74,4.18 ; J18.SH3 125.59,2.76 ; J1.7 127.76,143.36 ; J1.7 127.02,142.62 ; J1.7 128.5,142.62 ; J1.7 127.76,141.89 ; J2.G1 154.89,146.12 ; J2.G1 153.25,147.76 ; J2.G1 153.25,144.48 ; J2.G1 151.62,146.12 ; P4.3 92.63,8.88 ; P4.3 89.99,8.88 ; P4.3 91.31,10.2 ; P4.3 91.31,7.56 ; J16.SH4 111.09,11.05 ; J16.SH4 109.87,9.48 ; J16.SH4 112.31,9.48 ; J16.SH4 111.09,7.9 ; 13.94,47.39 J13.11 ; J13.11 13.94,49.27 ; J13.11 14.88,48.33 ; J13.11 13,48.33 ; 142.09,2.76 J18.SH4 ; J18.SH4 141.24,4.18 ; J18.SH4 142.09,5.6 ; J18.SH4 142.95,4.18 ; 2.23,146.8 M1.1 ; M1.1 5.59,143.45 ; M1.1 5.59,150.16 ; M1.1 8.94,146.8 ; 84.91,8.88 P4.2 ; P4.2 87.55,8.88 ; P4.2 86.23,7.56 ; P4.2 86.23,10.2 ; 109.87,3.71 J16.SH3 ; J16.SH3 111.09,5.29 ; J16.SH3 112.31,3.71 ; J16.SH3 111.09,2.14
  L4-SIGNAL w0.305: 192.29,117.46 HS1.2 ; HS1.2 197.6,117.46 ; HS1.2 194.94,120.12 ; HS1.2 194.94,114.81 ; J1.G2 121.19,148.02 ; J1.G2 119.3,146.12 ; J1.G2 121.19,144.23 ; J1.G2 123.08,146.12 ; 193.22,102.22 J11.2 192.02,103.42 ; v2(176.78,53.33) 175.9,53.33 175.57,53.66 175.57,54.02 176.28,54.73 178.56,54.73 183.77,59.93 183.77,63.24 184.53,64 185.42,64 185.93,63.49 185.93,62.6 v2(185.67,62.35) ; 127.76,141.63 J1.7 ; J1.7 126.77,142.62 ; J1.7 127.76,143.61 ; J1.7 128.75,142.62 ; 142.09,2.5 J18.SH4 ; J18.SH4 142.09,5.86 ; J18.SH4 143.2,4.18 ; J18.SH4 140.99,4.18 ; 142.19,144.12 J2.4 ; J2.4 144.18,144.12 ; J2.4 143.18,145.11 ; J2.G1 153.25,148.02 ; J2.G1 155.15,146.12 ; J2.G1 153.25,144.23 ; J2.G1 151.36,146.12 ; J1.4 125.25,144.12 ; J1.4 123.27,144.12 ; J1.4 124.26,145.11 ; 194.07,146.8 M2.1 ; M2.1 196.72,149.46 ; M2.1 196.72,144.15 ; M2.1 199.38,146.8 ; 55.68,104 J10.2 53.8,104 ; 165.23,41.59 J14.2 ; J14.2 165.23,43.98 ; J14.2 166.42,42.79 ; J14.2 164.03,42.79 ; J1.G1 136.22,146.12 ; J1.G1 134.33,144.23 ; J1.G1 134.33,148.02 ; J1.G1 132.44,146.12 ; 138.22,146.12 J2.G2 ; J2.G2 142.01,146.12 ; J2.G2 140.12,148.02 ; J2.G2 140.12,144.23 ; 189.87,7.6 J17.2 ; J17.2 191.27,9.01 ; J17.2 189.87,10.41 ; J17.2 188.46,9.01 ; J18.SH3 126.7,4.18 ; J18.SH3 125.59,5.86 ; J18.SH3 125.59,2.5 ; J18.SH3 124.49,4.18 ; HS1.1 162.43,120.12 ; HS1.1 165.09,117.46 ; HS1.1 162.43,114.81 ; HS1.1 159.78,117.46 ; 198.75,3.69 M3.1 ; M3.1 198.75,8.99 ; M3.1 196.1,6.34 ; M3.1 201.41,6.34 ; J2.7 146.69,143.61 ; J2.7 145.69,142.62 ; J2.7 147.68,142.62 ; J2.7 146.69,141.63
  L4-SIGNAL w0.508: v2(166.37,151.25) v2(169.54,151.25) v2(172.72,151.25) v2(175.9,151.25) v2(179.07,151.25) v2(182.25,151.25) v2(185.42,151.25) v2(188.59,151.25) v2(191.77,151.25) v2(194.94,151.25) v2(198.12,151.25) v2(201.93,151.25) v2(201.93,148.07) v2(201.93,144.9) v2(201.93,141.72) v2(201.93,138.55) v2(201.93,135.37) v2(201.93,132.2) v2(201.93,129.02) v2(201.93,125.85) v2(201.93,122.67) v2(201.93,119.5) v2(201.93,116.32) v2(201.93,113.15) v2(201.93,109.97) v2(201.93,106.8) v2(201.93,103.62) v2(201.93,100.45) v2(201.93,97.27) v2(201.93,94.1) v2(201.93,90.92) v2(201.93,87.75) v2(201.93,84.57) v2(201.93,81.4) v2(201.93,78.22) v2(201.93,75.05) v2(201.93,71.87) v2(201.93,68.7) v2(201.93,65.52) v2(201.93,62.35) v2(201.93,59.17) v2(201.93,56) v2(201.93,52.82) v2(201.93,49.65) v2(201.93,46.47) v2(201.93,43.3) v2(201.93,40.12) v2(201.93,36.95) v2(201.93,33.77) v2(201.93,30.6) v2(201.93,27.42) v2(201.93,24.25) 201.93,22.34 202.31,21.96 202.31,3.28 201.93,2.9 v2(201.93,2.02) 201.29,2.02 201.17,1.89 v2(198.12,1.89) v2(194.94,1.89) v2(191.77,1.89) v2(188.59,1.89) v2(185.42,1.89) v2(182.25,1.89) v2(179.07,1.89) v2(175.9,1.89) v2(172.72,1.89) v2(169.54,1.89) v2(166.37,1.89) v2(163.19,1.89) v2(160.02,1.89) v2(156.84,1.89) v2(153.67,1.89) v2(150.5,1.89) v2(147.32,1.89) v2(144.15,1.89) v2(140.97,1.89) v2(137.79,1.89) v2(135.64,1.89) 134.42,1.89 134.28,1.84 133.99,1.78 133.7,1.78 133.41,1.84 133.27,1.89 v2(131.44,1.89) v2(128.27,1.89) v2(125.09,1.89) v2(121.92,1.89) v2(118.75,1.89) v2(115.57,1.89) v2(112.39,1.89) v2(109.22,1.89) v2(106.05,1.89) v2(102.87,1.89) v2(99.69,1.89) v2(96.52,1.89) v2(93.34,1.89) v2(90.17,1.89) v2(87,1.89) v2(83.82,1.89) v2(80.64,1.89) v2(77.47,1.89) v2(74.3,1.89) v2(71.12,1.89) v2(67.94,1.89) v2(64.77,1.89) v2(61.59,1.89) v2(58.42,1.89) v2(55.24,1.89) v2(52.07,1.89) v2(48.9,1.89) v2(45.72,1.89) v2(42.55,1.89) v2(39.37,1.89) v2(36.2,1.89) v2(33.02,1.89) v2(29.84,1.89) v2(26.67,1.89) v2(23.5,1.89) v2(19.3,1.89) v2(16.89,1.89) v2(13.97,1.89) v2(10.16,1.89) v2(7.62,1.89) v2(4.45,1.89) 2.03,1.89 1.91,2.02 v2(1.27,2.02) v2(1.27,5.2) v2(1.27,8.37) v2(1.27,11.55) v2(1.27,14.72) v2(1.27,17.9) v2(1.27,21.07) v2(1.27,24.25) v2(1.27,27.42) v2(1.27,30.6) v2(1.27,33.77) v2(1.27,36.95) v2(1.27,40.12) v2(1.27,43.3) v2(1.27,46.47) v2(1.27,49.65) v2(1.27,52.82) v2(1.27,56) v2(1.27,59.17) v2(1.27,62.35) v2(1.27,65.52) v2(1.27,68.7) v2(1.27,71.87) v2(1.27,75.05) v2(1.27,78.22) v2(1.27,81.4) v2(1.27,84.57) v2(1.27,88.38) v2(1.27,90.92) v2(1.27,94.1) v2(1.27,97.27) v2(1.27,100.45) v2(1.27,103.62) v2(1.27,106.8) v2(1.27,109.97) v2(1.27,113.15) v2(1.27,116.32) v2(1.27,119.5) v2(1.27,122.67) v2(1.27,125.85) v2(1.27,129.02) v2(1.27,132.2) v2(1.27,135.37) v2(1.27,138.55) v2(1.27,141.72) v2(1.27,144.9) v2(1.27,148.07) v2(1.27,151.25) v2(4.45,151.25) v2(7.62,151.25) v2(10.79,151.25) v2(13.97,151.25) v2(17.14,151.25) v2(20.32,151.25) v2(23.5,151.25) v2(26.67,151.25) v2(29.84,151.25) v2(33.02,151.25) v2(35.56,151.25) v2(39.37,151.25) v2(43.18,151.25) v2(45.72,151.25) v2(48.9,151.25) v2(52.07,151.25) v2(55.24,151.25) v2(58.42,151.25) v2(61.59,151.25) 63.88,151.25 M6.1 66.67,151.25 v2(67.94,151.25) v2(71.12,151.25) v2(74.3,151.25) v2(77.47,151.25) v2(80.64,151.25) v2(83.82,151.25) 86.87,151.25 M5.1 89.66,151.25 v2(92.2,151.25) v2(160.02,151.25) v2(163.19,151.25) v2(166.37,151.25)
  L5-SIGNAL w0.097: v2(140.21,99.18) 140.21,99.12
  L5-SIGNAL w0.305: 93.98,148.02 J6.5 ; J6.5 93.98,151.17 ; J6.5 95.56,149.6 ; J6.5 92.4,149.6 ; M1.1 8.24,146.8 ; M1.1 5.59,144.15 ; M1.1 2.93,146.8 ; M1.1 5.59,149.46 ; M2.1 196.72,149.46 ; M2.1 194.07,146.8 ; M2.1 199.38,146.8 ; M2.1 196.72,144.15 ; 51.38,3.8 P2.4 ; P2.4 54.53,3.8 ; P2.4 52.96,2.22 ; P2.4 52.96,5.38 ; J6.2 99.06,146.09 ; J6.2 99.06,142.94 ; J6.2 97.48,144.52 ; J6.2 100.64,144.52 ; 58.04,7.3 P2.3 ; P2.3 58.04,10.46 ; P2.3 59.61,8.88 ; P2.3 56.46,8.88 ; 89.74,8.88 P4.3 ; P4.3 92.89,8.88 ; P4.3 91.31,10.46 ; P4.3 91.31,7.3 ; 68.02,3.8 P3.4 ; P3.4 69.6,2.22 ; P3.4 69.6,5.38 ; P3.4 71.17,3.8 ; 57.53,142.31 57.53,143.88 ; 57.53,143.88 55.96,143.88 ; 57.53,143.88 59.11,143.88 ; 57.53,143.88 57.53,145.46 ; 86.23,2.22 P4.4 ; P4.4 84.66,3.8 ; P4.4 87.81,3.8 ; P4.4 86.23,5.38 ; J8.1B 8.52,139.02 ; J8.1B 5.45,139.02 ; J8.1B 6.99,140.56 ; 140.99,10.96 J18.SH2 ; J18.SH2 143.2,10.96 ; J18.SH2 142.09,12.89 ; J18.SH2 142.09,9.03 ; 52.45,143.88 52.45,145.46 ; 52.45,143.88 54.03,143.88 ; 52.45,143.88 52.45,142.31 ; 52.45,143.88 50.88,143.88 ; 5.21,3.18 M4.1 ; M4.1 2.55,5.83 ; M4.1 7.86,5.83 ; M4.1 5.21,8.49 ; 35.25,149.98 J5.5 ; J5.5 36.83,148.4 ; J5.5 38.41,149.98 ; 124.49,4.18 J18.SH3 ; J18.SH3 125.59,5.86 ; J18.SH3 125.59,2.5 ; J18.SH3 126.7,4.18 ; P1.3 41.4,10.46 ; P1.3 41.4,7.3 ; P1.3 39.83,8.88 ; P1.3 42.98,8.88 ; J6.3 93.98,146.09 ; J6.3 95.56,144.52 ; J6.3 92.4,144.52 ; J6.3 93.98,142.94 ; 41.4,2.22 P1.5 ; P1.5 39.83,3.8 ; P1.5 42.98,3.8 ; P1.5 41.4,5.38 ; J17.2 191.27,9.01 ; J17.2 189.87,10.41 ; J17.2 188.46,9.01 ; J17.2 189.87,7.6 ; 86.25,149.85 M5.1 ; M5.1 91.55,149.85 ; M5.1 88.9,147.2 ; 5.45,119.97 J9.1B ; J9.1B 6.99,121.51 ; J9.1B 8.52,119.97 ; P2.2 52.96,10.46 ; P2.2 52.96,7.3 ; P2.2 54.53,8.88 ; P2.2 51.38,8.88 ; M6.1 67.3,149.85 ; M6.1 64.64,147.2 ; M6.1 61.99,149.85 ; P2.5 59.61,3.8 ; P2.5 58.04,5.38 ; P2.5 56.46,3.8 ; J5.4 43.49,149.98 ; J5.4 41.91,148.4 ; J5.4 40.33,149.98 ; 111.09,7.65 J16.SH4 ; J16.SH4 109.61,9.48 ; J16.SH4 112.56,9.48 ; J16.SH4 111.09,11.31 ; 36.32,7.3 P1.2 ; P1.2 36.32,10.46 ; P1.2 34.75,8.88 ; P1.2 37.9,8.88 ; HS1.1 162.43,120.12 ; HS1.1 165.09,117.46 ; HS1.1 162.43,114.81 ; 5.45,129.02 J8.1A ; J8.1A 8.52,129.02 ; J8.1A 6.99,127.48 ; 5.47,68.95 M7.1 ; M7.1 10.78,68.95 ; M7.1 8.13,71.61 ; M3.1 201.41,6.34 ; M3.1 196.1,6.34 ; M3.1 198.75,3.69 ; M3.1 198.75,8.99 ; 106.08,7.65 J16.SH1 ; J16.SH1 106.08,11.31 ; J16.SH1 107.56,9.48 ; J16.SH1 104.61,9.48 ; 5.47,18.4 M8.1 ; M8.1 8.13,15.75 ; M8.1 8.13,21.06 ; M8.1 10.78,18.4 ; P4.5 92.89,3.8 ; P4.5 89.74,3.8 ; P4.5 91.31,2.22 ; P4.5 91.31,5.38 ; 140.99,4.18 J18.SH4 ; J18.SH4 142.09,2.5 ; J18.SH4 142.09,5.86 ; J18.SH4 143.2,4.18 ; J9.1A 8.52,109.97 ; J9.1A 6.99,108.43 ; J9.1A 5.45,109.97 ; 97.48,149.6 J6.4 ; J6.4 100.64,149.6 ; J6.4 99.06,151.17 ; J6.4 99.06,148.02 ; J5.3 36.83,146.47 ; J5.3 35.25,144.9 ; J5.3 36.83,143.32 ; J5.3 38.41,144.9 ; J14.2 165.23,43.98 ; J14.2 166.42,42.79 ; J14.2 165.23,41.59 ; 86.23,7.3 P4.2 ; P4.2 86.23,10.46 ; P4.2 87.81,8.88 ; P4.2 84.66,8.88 ; 106.08,5.54 J16.SH2 104.61,3.71 ; 112.56,3.71 J16.SH3 111.09,5.54 ; P1.4 36.32,5.38 ; P1.4 34.75,3.8 ; P1.4 37.9,3.8 ; J18.SH1 126.7,10.96 ; J18.SH1 125.59,12.89 ; J18.SH1 124.49,10.96 ; J18.SH1 125.59,9.03 ; J7.5 54.03,148.96 ; J7.5 52.45,150.54 ; J7.5 52.45,147.39 ; J7.5 50.88,148.96 ; 5.45,90.92 J12.1A ; J12.1A 8.52,90.92 ; J12.1A 6.99,89.38 ; J5.2 41.91,146.47 ; J5.2 41.91,143.32 ; J5.2 43.49,144.9 ; J5.2 40.33,144.9 ; 5.45,100.92 J12.1B ; J12.1B 6.99,102.46 ; J12.1B 8.52,100.92 ; 55.96,148.96 J7.4 ; J7.4 59.11,148.96 ; J7.4 57.53,150.54 ; J7.4 57.53,147.39 ; P3.3 74.68,10.46 ; P3.3 76.25,8.88 ; P3.3 73.1,8.88 ; P3.3 74.68,7.3 ; 69.6,7.3 P3.2 ; P3.2 71.17,8.88 ; P3.2 68.02,8.88 ; P3.2 69.6,10.46 ; 109.59,8.79 J16.4 110.78,7.59 ; 73.1,3.8 P3.5 ; P3.5 76.25,3.8 ; P3.5 74.68,5.38
  L5-SIGNAL w0.508: v2(1.27,36.95) v2(1.27,40.12) v2(1.27,43.3) v2(1.27,46.47) v2(1.27,49.65) v2(1.27,52.82) v2(1.27,56) v2(1.27,59.17) v2(1.27,62.35) v2(1.27,65.52) v2(1.27,68.7) v2(1.27,71.87) v2(1.27,75.05) v2(1.27,78.22) v2(1.27,81.4) v2(1.27,84.57) v2(1.27,88.38) v2(1.27,90.92) v2(1.27,94.1) v2(1.27,97.27) v2(1.27,100.45) v2(1.27,103.62) v2(1.27,106.8) v2(1.27,109.97) v2(1.27,113.15) v2(1.27,116.32) v2(1.27,119.5) v2(1.27,122.67) v2(1.27,125.85) v2(1.27,129.02) v2(1.27,132.2) v2(1.27,135.37) v2(1.27,138.55) v2(1.27,141.72) v2(1.27,144.9) v2(1.27,148.07) v2(1.27,151.25) v2(4.45,151.25) v2(7.62,151.25) v2(10.79,151.25) v2(13.97,151.25) v2(17.14,151.25) v2(20.32,151.25) v2(23.5,151.25) v2(26.67,151.25) v2(29.84,151.25) v2(33.02,151.25) v2(35.56,151.25) v2(39.37,151.25) v2(43.18,151.25) v2(45.72,151.25) v2(48.9,151.25) v2(52.07,151.25) v2(55.24,151.25) v2(58.42,151.25) v2(61.59,151.25) v2(67.94,151.25) v2(71.12,151.25) v2(74.3,151.25) v2(77.47,151.25) v2(80.64,151.25) v2(83.82,151.25) v2(92.2,151.25) v2(160.02,151.25) v2(163.19,151.25) v2(166.37,151.25) v2(169.54,151.25) v2(172.72,151.25) v2(175.9,151.25) v2(179.07,151.25) v2(182.25,151.25) v2(185.42,151.25) v2(188.59,151.25) v2(191.77,151.25) v2(194.94,151.25) v2(198.12,151.25) v2(201.93,151.25) v2(201.93,148.07) v2(201.93,144.9) v2(201.93,141.72) v2(201.93,138.55) v2(201.93,135.37) v2(201.93,132.2) v2(201.93,129.02) v2(201.93,125.85) v2(201.93,122.67) v2(201.93,119.5) v2(201.93,116.32) v2(201.93,113.15) v2(201.93,109.97) v2(201.93,106.8) v2(201.93,103.62) v2(201.93,100.45) v2(201.93,97.27) v2(201.93,94.1) v2(201.93,90.92) v2(201.93,87.75) v2(201.93,84.57) v2(201.93,81.4) v2(201.93,78.22) v2(201.93,75.05) v2(201.93,71.87) v2(201.93,68.7) v2(201.93,65.52) v2(201.93,62.35) v2(201.93,59.17) v2(201.93,56) v2(201.93,52.82) v2(201.93,49.65) v2(201.93,46.47) v2(201.93,43.3) v2(201.93,40.12) v2(201.93,36.95) v2(201.93,33.77) v2(201.93,30.6) v2(201.93,27.42) v2(201.93,24.25) v2(201.93,21.07) v2(201.93,17.9) v2(201.93,14.72) v2(201.93,11.55) v2(201.93,8.37) v2(201.93,3.93) v2(201.93,2.02) 201.31,2.02 201.18,1.89 v2(198.12,1.89) v2(194.94,1.89) v2(191.77,1.89) v2(188.59,1.89) v2(185.42,1.89) v2(182.25,1.89) v2(179.07,1.89) v2(175.9,1.89) v2(172.72,1.89) v2(169.54,1.89) v2(166.37,1.89) v2(163.19,1.89) v2(160.02,1.89) v2(156.84,1.89) v2(153.67,1.89) v2(150.5,1.89) v2(147.32,1.89) v2(144.15,1.89) v2(140.97,1.89) v2(137.79,1.89) v2(135.64,1.89) 134.42,1.89 134.28,1.84 133.99,1.78 133.7,1.78 133.41,1.84 133.27,1.89 v2(131.44,1.89) v2(128.27,1.89) v2(125.09,1.89) v2(121.92,1.89) v2(118.75,1.89) v2(115.57,1.89) v2(112.39,1.89) v2(109.22,1.89) v2(106.05,1.89) v2(102.87,1.89) v2(99.69,1.89) v2(96.52,1.89) v2(93.34,1.89) 91.59,1.89 91.53,1.83 91.1,1.83 91.03,1.89 v2(90.17,1.89) v2(87,1.89) 86.51,1.89 86.45,1.83 86.02,1.83 85.95,1.89 v2(83.82,1.89) v2(80.64,1.89) v2(77.47,1.89) 75.08,1.89 74.89,1.7 74.46,1.7 74.27,1.89 v2(71.12,1.89) 70,1.89 69.81,1.7 69.38,1.7 69.19,1.89 v2(67.94,1.89) v2(64.77,1.89) v2(61.59,1.89) 58.45,1.89 58.25,1.7 57.82,1.7 57.63,1.89 v2(55.24,1.89) 53.37,1.89 53.17,1.7 52.74,1.7 52.55,1.89 v2(52.07,1.89) v2(48.9,1.89) v2(45.72,1.89) v2(42.55,1.89) 41.81,1.89 41.62,1.7 41.19,1.7 41,1.89 v2(39.37,1.89) 36.73,1.89 36.54,1.7 36.11,1.7 35.92,1.89 v2(33.02,1.89) v2(29.84,1.89) v2(26.67,1.89) v2(23.5,1.89) v2(19.3,1.89) v2(16.89,1.89) v2(13.97,1.89) v2(10.16,1.89) v2(7.62,1.89) v2(4.45,1.89) 2.02,1.89 1.89,2.02 v2(1.27,2.02) v2(1.27,5.2) v2(1.27,8.37) v2(1.27,11.55) v2(1.27,14.72) v2(1.27,17.9) v2(1.27,21.07) v2(1.27,24.25) v2(1.27,27.42) v2(1.27,30.6) v2(1.27,33.77) v2(1.27,36.95)
  L6-PWR w0.152: v1(76.83,111.27) 76.53,110.97 75.55,110.97 74.1,109.53 74.1,103.05 71.63,100.57 71.63,98.26 72.06,97.83 72.06,97.47 71.81,97.22 71.8,97.21 71.8,96.94 71.81,96.94 72.06,96.69 72.06,96.33 71.8,96.07 71.8,95.8 71.81,95.8 72.06,95.55 72.06,95.16 71.5,94.6 71.5,90.9 73.03,89.38 73.03,83.05 75.74,80.33 75.74,78.72 76.71,77.76 76.71,75.81 77.98,74.54 81.79,74.54 85.12,71.21 86.49,71.21 86.74,70.96 93.02,70.96 93.17,71.11 93.17,71.5 93.41,71.74 93.74,71.74 93.75,71.74 94.78,71.74 v1(95.18,71.35) ; v1(87.18,69.75) 86.77,69.75 86.04,70.47 85.02,70.47 81.48,74.01 77.62,74.01 76.12,75.5 76.12,77.41 75.18,78.35 75.18,80 75.03,80.15 74.69,80.15 v2(74.55,80.01) 74.55,80.51 72.26,82.79 72.26,89.14 70.87,90.54 70.87,100.83 72.77,102.73 72.77,103.88 73.41,104.51 73.41,106.99 72.9,107.5 72.9,107.83 73.41,108.34 73.41,109.92 75.39,111.9 76.49,111.9 v2(77.14,112.55)
  L6-PWR w0.305: 188.71,9.01 J17.2 ; J17.2 191.02,9.01 ; J17.2 189.87,10.16 ; J17.2 189.87,7.85 ; M3.1 198.75,9.69 ; M3.1 202.11,6.34 ; M3.1 195.4,6.34 ; M3.1 198.75,2.99
  L7-SIGNAL w0.152: v1(126.59,97.65) 126.59,97.65 126.87,97.65 127.66,96.87 127.66,94.22 128.16,93.73 134.21,93.73 135.1,92.84 135.1,90.16 134.56,89.61 134.56,88.72 134.32,88.48 133.78,88.48 133.32,88.03 133.32,83.4 128.37,78.45 118.59,78.45 112.78,72.63 104.72,72.63 103.98,73.38 v1(103.98,73.75) ; v2(137.58,96.84) 137.53,96.89 137.03,96.89 136.7,96.56 136.23,96.56 135.78,96.1 135.78,94.41 136.84,93.34 136.84,86.79 135.13,85.08 135.13,75.18 133.81,73.86 133.81,69.71 v1(131.86,67.76) ; v2(105.16,103.24) 109.73,103.24 117.47,95.49 117.47,93.08 119.32,91.23 130.18,91.23 131.01,92.06 131.89,92.06 132.69,91.26 v2(133.04,91.26) 133.94,92.16 134.02,92.16 134.48,91.7 134.48,90.46 132.79,88.78 132.79,83.63 128.22,79.06 118.19,79.06 112.29,73.17 105.6,73.17 105.19,73.59 105.19,74.14 v1(104.78,74.55) ; v2(138.52,96.2) 138.95,95.77 138.95,91.67 139.62,91 140.01,91 140.26,91.25 140.26,91.61 139.48,92.38 139.48,97.44 138.96,97.96 v2(138.52,97.96) v2(137.58,97.96) 136.54,97.96 136.44,98.06 135.88,98.06 135.24,97.42 135.24,94.08 136.27,93.06 136.27,87.24 134.37,85.33 134.37,75.43 133.2,74.26 133.2,70.2 132.33,69.33 132.21,69.33 131.93,69.06 v1(131.86,69.06) ; 127.89,93.21 127.92,93.21 127.93,93.2 129.93,93.2 130.3,92.83 130.3,92.45 129.67,91.81 119.76,91.81 118.26,93.31 118.26,95.74 110,104 104.78,104 104.39,103.62 104.39,102.86 v2(104.01,102.48)
  L7-SIGNAL w0.163: 127.89,93.21 127.05,94.04 127.05,95.29 126.86,95.49 123.83,95.49 123.7,95.62 v2(122.68,95.62)
  L7-SIGNAL w0.305: J5.4 43.49,149.98 ; J5.4 40.33,149.98 ; J5.4 41.91,151.55 ; J5.4 41.91,148.4 ; J16.SH3 112.56,3.71 ; J16.SH3 109.61,3.71 ; J16.SH3 111.09,1.88 ; J16.SH3 111.09,5.54 ; 92.4,144.52 J6.3 ; J6.3 93.98,142.94 ; J6.3 95.56,144.52 ; J6.3 93.98,146.09 ; J6.4 99.06,151.17 ; J6.4 97.48,149.6 ; J6.4 99.06,148.02 ; J6.4 100.64,149.6 ; J2.4 143.18,145.11 ; J2.4 144.18,144.12 ; J2.4 142.19,144.12 ; P3.4 71.17,3.8 ; P3.4 69.6,5.38 ; P3.4 68.02,3.8 ; P3.4 69.6,2.22 ; J1.4 125.25,144.12 ; J1.4 123.27,144.12 ; J1.4 124.26,145.11 ; P2.3 58.04,10.46 ; P2.3 59.61,8.88 ; P2.3 58.04,7.3 ; P2.3 56.46,8.88 ; 6.99,89.38 J12.1A ; J12.1A 8.52,90.92 ; J12.1A 5.45,90.92 ; 55.96,143.88 57.53,143.88 ; 57.53,143.88 57.53,145.46 ; 57.53,143.88 59.11,143.88 ; 57.53,143.88 57.53,142.31 ; 53.8,104 J10.2 55.68,104 ; 140.99,4.18 J18.SH4 ; J18.SH4 142.09,2.5 ; J18.SH4 142.09,5.86 ; J18.SH4 143.2,4.18 ; P4.3 91.31,10.46 ; P4.3 89.74,8.88 ; P4.3 92.89,8.88 ; P4.3 91.31,7.3 ; P1.5 42.98,3.8 ; P1.5 41.4,5.38 ; P1.5 41.4,2.22 ; P1.5 39.83,3.8 ; 188.46,9.01 J17.2 ; J17.2 189.87,7.6 ; J17.2 191.27,9.01 ; J17.2 189.87,10.41 ; P3.3 74.68,10.46 ; P3.3 74.68,7.3 ; P3.3 76.25,8.88 ; P3.3 73.1,8.88 ; M1.1 8.24,146.8 ; M1.1 5.59,149.46 ; M1.1 2.93,146.8 ; M1.1 5.59,144.15 ; J5.3 36.83,146.47 ; J5.3 35.25,144.9 ; J5.3 36.83,143.32 ; J5.3 38.41,144.9 ; J2.G1 153.25,148.02 ; J2.G1 155.15,146.12 ; J2.G1 153.25,144.23 ; J2.G1 151.36,146.12 ; 61.99,149.85 M6.1 ; M6.1 67.3,149.85 ; M6.1 64.64,147.2 ; J1.7 127.76,143.61 ; J1.7 128.75,142.62 ; J1.7 127.76,141.63 ; J1.7 126.77,142.62 ; J16.SH4 111.09,11.31 ; J16.SH4 109.61,9.48 ; J16.SH4 112.56,9.48 ; J16.SH4 111.09,7.65 ; 86.23,2.22 P4.4 ; P4.4 84.66,3.8 ; P4.4 87.81,3.8 ; P4.4 86.23,5.38 ; P1.2 37.9,8.88 ; P1.2 36.32,7.3 ; P1.2 34.75,8.88 ; P1.2 36.32,10.46 ; J14.2 166.42,42.79 ; J14.2 165.23,41.59 ; J14.2 165.23,43.98 ; 74.68,2.22 P3.5 ; P3.5 76.25,3.8 ; P3.5 74.68,5.38 ; P3.5 73.1,3.8 ; M3.1 201.41,6.34 ; M3.1 198.75,3.69 ; M3.1 196.1,6.34 ; M3.1 198.75,8.99 ; 5.45,109.97 J9.1A ; J9.1A 8.52,109.97 ; J9.1A 6.99,108.43 ; P2.4 52.96,5.38 ; P2.4 52.96,2.22 ; P2.4 51.38,3.8 ; P2.4 54.53,3.8 ; 41.4,7.3 P1.3 ; P1.3 39.83,8.88 ; P1.3 42.98,8.88 ; P1.3 41.4,10.46 ; J2.7 146.69,143.61 ; J2.7 145.69,142.62 ; J2.7 147.68,142.62 ; J2.7 146.69,141.63 ; J7.5 52.45,150.54 ; J7.5 54.03,148.96 ; J7.5 50.88,148.96 ; J7.5 52.45,147.39 ; 5.45,129.02 J8.1A ; J8.1A 6.99,127.48 ; J8.1A 8.52,129.02 ; 86.25,149.85 M5.1 ; M5.1 88.9,147.2 ; M5.1 91.55,149.85 ; 91.31,2.22 P4.5 ; P4.5 91.31,5.38 ; P4.5 92.89,3.8 ; P4.5 89.74,3.8 ; P3.2 71.17,8.88 ; P3.2 69.6,7.3 ; P3.2 69.6,10.46 ; P3.2 68.02,8.88 ; J12.1B 8.52,100.92 ; J12.1B 5.45,100.92 ; J12.1B 6.99,102.46 ; J16.SH1 106.08,11.31 ; J16.SH1 104.61,9.48 ; J16.SH1 107.56,9.48 ; J16.SH1 106.08,7.65 ; 97.48,144.52 J6.2 ; J6.2 100.64,144.52 ; J6.2 99.06,146.09 ; J6.2 99.06,142.94 ; J11.2 192.02,103.42 ; J11.2 190.83,102.22 ; J11.2 192.02,101.03 ; J11.2 193.22,102.22 ; 57.53,147.39 J7.4 ; J7.4 55.96,148.96 ; J7.4 57.53,150.54 ; J7.4 59.11,148.96 ; 132.44,146.12 J1.G1 ; J1.G1 134.33,148.02 ; J1.G1 136.22,146.12 ; J1.G1 134.33,144.23 ; J1.G2 123.08,146.12 ; J1.G2 121.19,144.23 ; J1.G2 121.19,148.02 ; J1.G2 119.3,146.12 ; M2.1 196.72,149.46 ; M2.1 199.38,146.8 ; M2.1 194.07,146.8 ; M2.1 196.72,144.15 ; 162.43,114.81 HS1.1 ; HS1.1 165.09,117.46 ; HS1.1 159.78,117.46 ; HS1.1 162.43,120.12 ; J5.2 43.49,144.9 ; J5.2 40.33,144.9 ; J5.2 41.91,143.32 ; J5.2 41.91,146.47 ; J9.1B 8.52,119.97 ; J9.1B 6.99,121.51 ; J9.1B 5.45,119.97 ; J8.1B 8.52,139.02 ; J8.1B 6.99,140.56 ; J8.1B 5.45,139.02 ; 52.45,142.31 52.45,143.88 ; 52.45,143.88 54.03,143.88 ; 52.45,143.88 52.45,145.46 ; 52.45,143.88 50.88,143.88 ; 34.75,3.8 P1.4 ; P1.4 37.9,3.8 ; P1.4 36.32,2.22 ; P1.4 36.32,5.38 ; J18.SH3 125.59,5.86 ; J18.SH3 124.49,4.18 ; J18.SH3 125.59,2.5 ; J18.SH3 126.7,4.18 ; J18.SH2 142.09,12.89 ; J18.SH2 142.09,9.03 ; J18.SH2 143.2,10.96 ; J18.SH2 140.99,10.96 ; J18.SH1 126.7,10.96 ; J18.SH1 124.49,10.96 ; J18.SH1 125.59,12.89 ; J18.SH1 125.59,9.03 ; 5.47,68.95 M7.1 ; M7.1 8.13,71.61 ; M7.1 10.78,68.95 ; 104.61,3.71 J16.SH2 ; J16.SH2 106.08,5.54 ; J16.SH2 107.56,3.71 ; J16.SH2 106.08,1.88 ; 36.83,148.4 J5.5 ; J5.5 38.41,149.98 ; J5.5 36.83,151.55 ; J5.5 35.25,149.98 ; 192.29,117.46 HS1.2 ; HS1.2 197.6,117.46 ; HS1.2 194.94,120.12 ; HS1.2 194.94,114.81 ; P4.2 86.23,10.46 ; P4.2 87.81,8.88 ; P4.2 86.23,7.3 ; P4.2 84.66,8.88 ; P2.5 59.61,3.8 ; P2.5 58.04,5.38 ; P2.5 56.46,3.8 ; P2.5 58.04,2.22 ; J6.5 95.56,149.6 ; J6.5 92.4,149.6 ; J6.5 93.98,148.02 ; J6.5 93.98,151.17 ; P2.2 54.53,8.88 ; P2.2 52.96,7.3 ; P2.2 52.96,10.46 ; P2.2 51.38,8.88 ; 110.78,7.59 J16.4 109.59,8.79 ; 138.22,146.12 J2.G2 ; J2.G2 142.01,146.12 ; J2.G2 140.12,144.23 ; J2.G2 140.12,148.02
  L7-SIGNAL w0.508: v2(182.25,1.89) v2(179.07,1.89) v2(175.9,1.89) v2(172.72,1.89) v2(169.54,1.89) v2(166.37,1.89) v2(163.19,1.89) v2(160.02,1.89) v2(156.84,1.89) v2(153.67,1.89) v2(150.5,1.89) v2(147.32,1.89) v2(144.15,1.89) v2(140.97,1.89) v2(137.79,1.89) v2(135.64,1.89) 134.42,1.89 134.28,1.84 133.99,1.78 133.7,1.78 133.41,1.84 133.27,1.89 v2(131.44,1.89) v2(128.27,1.89) v2(125.09,1.89) v2(121.92,1.89) v2(118.75,1.89) v2(115.57,1.89) v2(112.39,1.89) v2(109.22,1.89) v2(106.05,1.89) v2(102.87,1.89) v2(99.69,1.89) v2(96.52,1.89) v2(93.34,1.89) 91.59,1.89 91.53,1.83 91.1,1.83 91.03,1.89 v2(90.17,1.89) v2(87,1.89) 86.51,1.89 86.45,1.83 86.02,1.83 85.95,1.89 v2(83.82,1.89) v2(80.64,1.89) v2(77.47,1.89) 75.08,1.89 74.89,1.7 74.46,1.7 74.27,1.89 v2(71.12,1.89) 70,1.89 69.81,1.7 69.38,1.7 69.19,1.89 v2(67.94,1.89) v2(64.77,1.89) v2(61.59,1.89) 58.45,1.89 58.25,1.7 57.82,1.7 57.63,1.89 v2(55.24,1.89) 53.37,1.89 53.17,1.7 52.74,1.7 52.55,1.89 v2(52.07,1.89) v2(48.9,1.89) v2(45.72,1.89) v2(42.55,1.89) 41.81,1.89 41.62,1.7 41.19,1.7 41,1.89 v2(39.37,1.89) 36.73,1.89 36.54,1.7 36.11,1.7 35.92,1.89 v2(33.02,1.89) v2(29.84,1.89) v2(26.67,1.89) v2(23.5,1.89) v2(19.3,1.89) v2(16.89,1.89) v2(13.97,1.89) v2(10.16,1.89) v2(7.62,1.89) v2(4.45,1.89) 2.02,1.89 1.89,2.02 v2(1.27,2.02) v2(1.27,5.2) v2(1.27,8.37) v2(1.27,11.55) v2(1.27,14.72) v2(1.27,17.9) v2(1.27,21.07) v2(1.27,24.25) v2(1.27,27.42) v2(1.27,30.6) v2(1.27,33.77) v2(1.27,36.95) v2(1.27,40.12) v2(1.27,43.3) v2(1.27,46.47) v2(1.27,49.65) v2(1.27,52.82) v2(1.27,56) v2(1.27,59.17) v2(1.27,62.35) v2(1.27,65.52) v2(1.27,68.7) v2(1.27,71.87) v2(1.27,75.05) v2(1.27,78.22) v2(1.27,81.4) v2(1.27,84.57) v2(1.27,88.38) v2(1.27,90.92) v2(1.27,94.1) v2(1.27,97.27) v2(1.27,100.45) v2(1.27,103.62) v2(1.27,106.8) v2(1.27,109.97) v2(1.27,113.15) v2(1.27,116.32) v2(1.27,119.5) v2(1.27,122.67) v2(1.27,125.85) v2(1.27,129.02) v2(1.27,132.2) v2(1.27,135.37) v2(1.27,138.55) v2(1.27,141.72) v2(1.27,144.9) v2(1.27,148.07) v2(1.27,151.25) v2(4.45,151.25) v2(7.62,151.25) v2(10.79,151.25) v2(13.97,151.25) v2(17.14,151.25) v2(20.32,151.25) v2(23.5,151.25) v2(26.67,151.25) v2(29.84,151.25) v2(33.02,151.25) v2(35.56,151.25) v2(39.37,151.25) v2(43.18,151.25) v2(45.72,151.25) v2(48.9,151.25) v2(52.07,151.25) v2(55.24,151.25) v2(58.42,151.25) v2(61.59,151.25) v2(67.94,151.25) v2(71.12,151.25) v2(74.3,151.25) v2(77.47,151.25) v2(80.64,151.25) v2(83.82,151.25) v2(92.2,151.25) v2(160.02,151.25) v2(163.19,151.25) v2(166.37,151.25) v2(169.54,151.25) v2(172.72,151.25) v2(175.9,151.25) v2(179.07,151.25) v2(182.25,151.25) v2(185.42,151.25) v2(188.59,151.25) v2(191.77,151.25) v2(194.94,151.25) v2(198.12,151.25) v2(201.93,151.25) v2(201.93,148.07) v2(201.93,144.9) v2(201.93,141.72) v2(201.93,138.55) v2(201.93,135.37) v2(201.93,132.2) v2(201.93,129.02) v2(201.93,125.85) v2(201.93,122.67) v2(201.93,119.5) v2(201.93,116.32) v2(201.93,113.15) v2(201.93,109.97) v2(201.93,106.8) v2(201.93,103.62) v2(201.93,100.45) v2(201.93,97.27) v2(201.93,94.1) v2(201.93,90.92) v2(201.93,87.75) v2(201.93,84.57) v2(201.93,81.4) v2(201.93,78.22) v2(201.93,75.05) v2(201.93,71.87) v2(201.93,68.7) v2(201.93,65.52) v2(201.93,62.35) v2(201.93,59.17) v2(201.93,56) v2(201.93,52.82) v2(201.93,49.65) v2(201.93,46.47) v2(201.93,43.3) v2(201.93,40.12) v2(201.93,36.95) v2(201.93,33.77) v2(201.93,30.6) v2(201.93,27.42) v2(201.93,24.25) v2(201.93,21.07) v2(201.93,17.9) v2(201.93,14.72) v2(201.93,11.55) v2(201.93,8.37) v2(201.93,3.93) v2(201.93,2.02) 201.31,2.02 201.18,1.89 v2(198.12,1.89) v2(194.94,1.89) v2(191.77,1.89) v2(188.59,1.89) v2(185.42,1.89) v2(182.25,1.89)
  BOTTOM w0.152: v1(94.36,57.42) 94.51,57.57 95.02,57.57 C773.2 ; v1(99.98,61.75) 99.76,61.97 99.19,61.97 R366.2 ; C649.2 95.75,74.78 v1(95.98,74.55) ; v1(95.98,65.75) 95.9,65.67 95.9,65.49 C747.2 ; 99.19,64.87 R358.2
  BOTTOM w0.163: v1(101.58,68.94) C715.2 101.58,68.71 ; C667.2 95.18,73.19 v1(95.18,73.75) ; 102.45,68.74 C714.2 102.45,68.88 v1(102.38,68.95) ; 99.19,64.87 98.45,64.87 v1(98.38,64.95)
  BOTTOM w0.191: U73.B3 v2(79.87,46.46)
  BOTTOM w0.203: v1(97.58,65.75) 97.58,65.58 97.5,65.5 C748.2 ; C644.2 100.78,75.35 v1(100.78,75.35)
  BOTTOM w0.254: v2(146.81,140.45) U65.8 U65.3 ; C793.2 v2(57.02,30.85) ; U66.3 U66.8 v2(127.89,140.45) ; C796.2 v2(57.02,29.83) ; v2(56.39,24.75) R431.2 R433.2 ; C802.2 v2(57.02,28.82) ; 130.94,135.24 v2(130.94,136.01)
  BOTTOM w0.305: C653.2 128.14,73.94 v1(128.25,73.82) ; C592.1 v2(137.92,86.86) C593.1 ; J21.86 v2(6.44,40.97) ; 92.61,149.6 J6.5 ; J6.5 95.35,149.6 ; J6.5 93.98,150.97 ; J6.5 93.98,148.22 ; C547.2 v2(130.81,104.83) ; 35.46,149.98 J5.5 ; J5.5 36.83,151.35 ; J5.5 36.83,148.6 ; J5.5 38.2,149.98 ; v2(34.29,84.32) 34.42,84.44 C596.2 ; C672.2 104.67,72.13 105.26,72.71 105.59,72.71 ; C814.2 v2(56.9,20.44) ; J1.7 127.76,143.41 ; J1.7 126.97,142.62 ; J1.7 127.76,141.83 ; J1.7 128.55,142.62 ; v1(130.26,59.96) 130.43,59.78 C767.2 ; J7.5 53.82,148.96 ; J7.5 52.45,150.33 ; J7.5 51.08,148.96 ; J7.5 52.45,147.59 ; P4.4 86.23,5.17 ; P4.4 86.23,2.43 ; P4.4 84.86,3.8 ; P4.4 87.61,3.8 ; J18.SH2 142.09,12.69 ; J18.SH2 142.09,9.23 ; J18.SH2 141.19,10.96 ; J18.SH2 143,10.96 ; J18.SH4 143,4.18 ; J18.SH4 142.09,5.65 ; J18.SH4 141.19,4.18 ; J18.SH4 142.09,2.71 ; 151.26,74.54 v2(150.5,74.54) ; P1.4 36.32,5.17 ; P1.4 36.32,2.43 ; P1.4 34.95,3.8 ; P1.4 37.69,3.8 ; U72.4 v2(23.23,73.13) ; R301.2 v2(146.94,89.14) ; R307.2 33.4,86.1 v2(33.53,85.97) ; J5.3 38.2,144.9 ; J5.3 36.83,143.52 ; J5.3 35.46,144.9 ; J5.3 36.83,146.27 ; C778.2 v2(20.32,56.25) ; 51.08,143.88 52.45,143.88 ; 52.45,143.88 53.82,143.88 ; 52.45,143.88 52.45,145.25 ; 52.45,143.88 52.45,142.51 ; P1.2 36.32,10.25 ; P1.2 34.95,8.88 ; P1.2 37.69,8.88 ; P1.2 36.32,7.51 ; R401.1 v2(61.34,47.74) ; J2.G1 153.25,147.81 ; J2.G1 154.94,146.12 ; J2.G1 153.25,144.43 ; J2.G1 151.57,146.12 ; R343.2 113.03,78.23 113,78.26 v1(113,78.53) C614.2 ; J16.SH1 107.35,9.48 ; J16.SH1 106.08,11.1 ; J16.SH1 104.81,9.48 ; J16.SH1 106.08,7.85 ; 8.13,15 M8.1 ; M8.1 4.72,18.4 ; M8.1 11.53,18.4 ; M8.1 8.13,21.81 ; v2(17.4,57.39) v2(17.4,61.33) ; 125.59,2.71 J18.SH3 ; J18.SH3 126.5,4.18 ; J18.SH3 124.69,4.18 ; J18.SH3 125.59,5.65 ; J13.11 14.94,48.33 ; J13.11 13.94,47.33 ; J13.11 12.95,48.33 ; 196.72,150.21 M2.1 200.13,146.8 ; 188.66,9.01 J17.2 ; J17.2 189.87,7.8 ; J17.2 191.07,9.01 ; J17.2 189.87,10.21 ; R413.1 v2(142.88,43.93) ; C813.2 v2(56.9,21.58) ; 138.43,146.12 J2.G2 ; J2.G2 140.12,144.43 ; J2.G2 141.8,146.12 ; J2.G2 140.12,147.81 ; C609.2 147.47,80.89 v2(147.78,81.2) ; U75.4 113.74,25.52 114.05,25.82 v1(114.05,25.93) 113.96,26.02 U75.3 ; 6.99,127.69 J8.1A ; J8.1A 6.99,130.36 ; J8.1A 5.65,129.02 ; J8.1A 8.32,129.02 ; 88.27,151.25 M5.1 ; M5.1 88.9,147.4 ; M5.1 91.35,149.85 ; M5.1 86.45,149.85 ; v2(40.77,57.24) 40.26,56.73 C779.2 ; 97.69,149.6 J6.4 ; J6.4 99.06,150.97 ; J6.4 100.43,149.6 ; J6.4 99.06,148.22 ; 110.58,7.59 J16.4 109.59,8.59 ; U75.6 113.81,24.52 113.96,24.66 v1(114.05,24.66) 113.69,25.02 U75.5 ; R419.2 v2(65.15,42.15) ; R441.2 v2(55.5,17.9) ; R368.2 R369.2 37.34,60.44 v2(37.08,60.7) ; J21.93 v2(6.51,45.17) ; P4.2 86.23,10.25 ; P4.2 86.23,7.51 ; P4.2 87.61,8.88 ; P4.2 84.86,8.88 ; 58.04,2.43 P2.5 ; P2.5 59.41,3.8 ; P2.5 56.67,3.8 ; P2.5 58.04,5.17 ; C492.2 v4(107.19,133.47) ; R402.1 v2(60.07,47.74) ; C746.2 41.78,65.27 C749.2 42.67,66.16 v2(43.18,66.16) ; C791.2 v2(62.87,33.9) ; U75.29 106.46,20.03 v1(105.97,20.52) ; 52.96,7.51 P2.2 ; P2.2 51.59,8.88 ; P2.2 54.33,8.88 ; P2.2 52.96,10.25 ; R303.2 v2(71.75,87.11) ; R451.2 v2(73.91,14.59) ; 112.05,29.03 112.02,29.03 ; 112.05,29.03 112.05,29.58 v1(111.89,29.74) ; 112.05,29.03 111.96,28.95 U75.63 ; 112.05,29.03 C801.2 ; 13.94,59.35 J13.5 14.94,60.34 ; M4.1 5.21,9.24 ; M4.1 5.21,2.43 ; M4.1 1.8,5.83 ; M4.1 8.61,5.83 ; 69.6,2.43 P3.4 ; P3.4 69.6,5.17 ; P3.4 70.97,3.8 ; P3.4 68.22,3.8 ; J11.2 192.02,103.22 ; J11.2 193.02,102.22 ; J11.2 191.03,102.22 ; J11.2 192.02,101.23 ; 5.65,100.92 J12.1B ; J12.1B 6.99,102.26 ; J12.1B 8.32,100.92 ; J12.1B 6.99,99.59 ; R417.2 v2(67.69,42.15) ; J21.109 6.27,54.78 v2(6.48,54.98) ; 5.65,139.02 J8.1B ; J8.1B 6.99,137.69 ; J8.1B 6.99,140.36 ; J8.1B 8.32,139.02 ; 64.64,147.4 M6.1 ; M6.1 62.19,149.85 ; M6.1 67.09,149.85 ; v1(116.75,24) 116,24 ; 116,24 114.86,24 ; 116,24 C806.2 116,24.04 ; 106.08,2.08 J16.SH2 ; J16.SH2 107.35,3.71 ; J16.SH2 104.81,3.71 ; J16.SH2 106.08,5.34 ; J12.1A 8.32,90.92 ; J12.1A 6.99,89.59 ; J12.1A 6.99,92.26 ; J12.1A 5.65,90.92 ; 27.69,46.09 v2(27.69,45.07) ; C511.2 109.6,118.48 v2(108.58,118.48) 108.58,119.5 C506.2 ; C516.2 103.76,116.83 v2(104.27,116.32) ; v2(145.8,38.22) 145.8,39.23 R425.2 ; v2(180.09,68.32) 179.71,68.7 C713.2 ; v2(155.79,81.2) 155.45,80.86 C611.2 ; 41.4,7.51 P1.3 ; P1.3 42.77,8.88 ; P1.3 41.4,10.25 ; P1.3 40.03,8.88 ; R416.2 v2(68.96,42.15) ; C654.2 126.36,73.87 v1(126.25,73.76) ; 58.04,7.51 P2.3 ; P2.3 58.04,10.25 ; P2.3 59.41,8.88 ; P2.3 56.67,8.88 ; 132.64,146.12 J1.G1 ; J1.G1 134.33,147.81 ; J1.G1 136.02,146.12 ; J1.G1 134.33,144.43 ; U67.9 v2(195.83,100.57) ; v2(44.32,97.02) 44.2,97.14 C567.1 ; C799.2 v1(114.05,30) ; J14.2 166.22,42.79 ; J14.2 164.24,42.79 ; J14.2 165.23,41.8 ; J14.2 165.23,43.78 ; C581.2 v2(158.88,89.78) ; C750.2 v2(38.48,65.52) ; C498.2 v2(130.18,129.78) ; U67.1 v2(194.56,98.03) ; 40.03,3.8 P1.5 ; P1.5 41.4,2.43 ; P1.5 42.77,3.8 ; P1.5 41.4,5.17 ; R418.2 v2(66.42,42.15) ; 89.94,3.8 P4.5 ; P4.5 92.69,3.8 ; P4.5 91.31,5.17 ; P4.5 91.31,2.43 ; v2(52.41,113.1) 51.89,113.1 51.66,113.32 Y6.4 50.75,113.58 49.07,115.26 Y6.2 ; 114.86,24 C807.2 ; 114.86,24 114.86,23.97 ; 114.86,24 114.29,24 v1(114.06,23.77) ; J21.36 v2(9.4,40.37) ; 57.53,142.51 57.53,143.88 ; 57.53,143.88 58.9,143.88 ; 57.53,143.88 57.53,145.25 ; 57.53,143.88 56.16,143.88 ; C812.2 v2(72.64,21.71) ; 195.33,71.24 v2(194.56,71.24) ; J1.4 124.26,144.91 ; J1.4 125.05,144.12 ; J1.4 123.47,144.12 ; C780.2 v2(41.66,57.27) ; 5.59,143.4 M1.1 ; M1.1 8.99,146.8 ; M1.1 5.59,150.21 ; M1.1 2.18,146.8 ; 109.82,9.48 J16.SH4 ; J16.SH4 111.09,11.1 ; J16.SH4 112.36,9.48 ; J16.SH4 111.09,7.85 ; J21.118 v2(6.46,60.17) ; 54,104 J10.2 55.47,104 ; R399.1 v2(63.88,47.74) ; P3.3 76.05,8.88 ; P3.3 73.3,8.88 ; P3.3 74.68,7.51 ; P3.3 74.68,10.25 ; 105.59,72.71 105.64,72.76 106.4,72.76 R348.2 106.4,72.97 v1(107.18,73.75) ; 105.59,72.71 C670.2 ; C766.2 38.71,59.3 v2(39.47,58.54) ; 30.23,52.44 v2(30.23,53.46) ; v2(70.99,28.18) 70.87,28.31 C800.2 ; 109.82,3.71 J16.SH3 ; J16.SH3 111.09,5.34 ; J16.SH3 111.09,2.08 ; J16.SH3 112.36,3.71 ; 68.22,8.88 P3.2 ; P3.2 70.97,8.88 ; P3.2 69.6,10.25 ; P3.2 69.6,7.51 ; 25.15,52.44 v2(25.15,53.46) ; J13.12 13.94,47.31 ; J13.12 14.94,46.32 ; J13.12 12.95,46.32 ; v1(111.46,26.01) 111.46,26.02 U75.62 ; U75.1 113.81,27.02 v1(114.06,26.77) 113.81,26.52 U75.2 ; C782.2 v2(80.3,53.04) ; R457.2 132.48,14.71 v1(133.04,15.27) 133.62,14.68 R456.2 ; C497.2 v2(133.99,127.88) ; 73.3,3.8 P3.5 ; P3.5 74.68,5.17 ; P3.5 76.05,3.8 ; P3.5 74.68,2.43 ; v1(100.78,78.55) 100.68,78.65 100.18,78.65 R341.2 ; v1(109.85,15.99) 109.35,16.5 C824.2 ; U68.5 64.96,97.57 v2(64.85,97.68) ; 5.65,119.97 J9.1B ; J9.1B 6.99,118.64 ; J9.1B 6.99,121.31 ; J9.1B 8.32,119.97 ; Q15.4 v2(131.79,7.14) ; 146.69,141.83 J2.7 ; J2.7 147.47,142.62 ; J2.7 145.9,142.62 ; J2.7 146.69,143.41 ; 92.61,144.52 J6.3 ; J6.3 95.35,144.52 ; J6.3 93.98,145.89 ; C808.2 C805.2 R430.2 ; C808.2 R436.2 ; C808.2 v2(75.44,23.1) ; 5.65,109.97 J9.1A ; J9.1A 6.99,108.64 ; J9.1A 8.32,109.97 ; J9.1A 6.99,111.31 ; R278.1 v2(109.98,112.51) ; C804.2 101.86,24.8 101.35,25.32 v1(101.35,26.31) ; C786.2 28.19,50.92 v2(28.19,49.9) RJ18.3 ; J21.4 v2(9.38,59.57) ; C798.2 103.59,30.23 ; 103.59,30.23 104.9,30.23 104.9,30.23 ; 103.59,30.23 v1(102.87,30.23) ; C548.2 132.84,104.45 v2(132.46,104.83) ; J13.6 14.94,58.33 ; J13.6 13.94,59.32 ; J13.6 12.95,58.33 ; M7.1 8.13,72.35 ; M7.1 11.53,68.95 ; M7.1 8.13,65.55 ; M7.1 4.72,68.95 ; v1(131.86,63.86) 132.04,64.04 132.05,64.04 132.14,64.12 C759.2 ; C561.1 v2(50.42,100.07) ; U75.7 113.81,24.02 v1(114.06,23.77) ; J6.2 99.06,145.89 ; J6.2 100.43,144.52 ; J6.2 97.69,144.52 ; C788.2 v2(20.32,44.44) ; 119.5,146.12 J1.G2 ; J1.G2 121.19,147.81 ; J1.G2 122.88,146.12 ; J1.G2 121.19,144.43 ; M3.1 198.75,9.74 ; M3.1 198.75,2.94 ; M3.1 202.16,6.34 ; M3.1 195.35,6.34 ; v2(154.79,81.2) 154.48,80.89 C608.2 ; 40.54,149.98 J5.4 ; J5.4 41.91,148.6 ; J5.4 41.91,151.35 ; J5.4 43.28,149.98 ; J7.4 58.9,148.96 ; J7.4 56.16,148.96 ; J7.4 57.53,147.59 ; J7.4 57.53,150.33 ; 52.96,2.43 P2.4 ; P2.4 52.96,5.17 ; P2.4 54.33,3.8 ; P2.4 51.59,3.8 ; P4.3 92.69,8.88 ; P4.3 91.31,10.25 ; P4.3 89.94,8.88 ; P4.3 91.31,7.51 ; J21.75 v2(3.94,34.38) ; C751.2 v2(35.69,65.52) ; R270.2 v2(112.78,129.78) ; v1(110.38,70.55) 111.02,71.19 111.02,72.13 C671.2 ; v1(116.33,17.77) C815.2 116.33,18.54 ; C734.2 132.81,66.03 v1(132.76,66.08) ; J21.104 v2(6.45,51.78) ; C770.2 124.21,59.04 v1(124.25,59.09) ; C789.2 v2(44.64,37.84) ; 196.47,95.49 v2(197.23,95.49) ; v2(77.01,43.54) 77.01,43.58 77.04,43.61 77.04,43.63 U73.E5 ; J21.52 v2(11.76,30.78) ; R377.2 v2(60.07,57.39) ; v2(155.79,86.21) 155.45,85.86 C597.2 ; J2.4 143.18,144.91 ; J2.4 142.4,144.12 ; J2.4 143.97,144.12 ; J21.28 v2(9.3,45.17) ; C524.2 103.89,113.78 v2(104.27,114.16) 104.3,114.13 104.3,112.93 C534.2 ; 41.91,143.52 J5.2 ; J5.2 43.28,144.9 ; J5.2 41.91,146.27 ; J5.2 40.54,144.9 ; C794.2 v2(44.64,30.72) ; U70.4 v2(23.36,82.28) ; v1(114.06,23.77) 113.81,23.52 U75.8 ; U71.4 v2(23.23,77.71) ; C566.1 v2(44.2,99.68) ; R400.1 v2(62.61,47.74) ; v2(3.94,30.85) 4.01,30.78 J21.69 ; v2(70.99,26.53) 70.74,26.28 C803.2 ; R394.1 v2(27.18,48.76) ; J21.23 v2(9.4,48.17) ; J21.63 v2(6.48,27.18) ; 110.22,65.11 110.21,65.11 110.36,64.95 v1(110.38,64.95) ; R280.2 v2(41.15,111.62) ; J21.81 v2(6.48,37.97) ; v1(131.86,69.06) 132.09,68.82 C705.2 ; RJ20.1 v2(14.1,32.76) ; R249.2 v1(112.78,15.11) ; J21.58 v2(9.4,27.18) ; J21.3 v2(11.8,60.17) ; C562.1 v2(49.4,100.07) ; 40.13,51.68 v2(40.89,51.68) ; U73.C1 v2(81.87,45.46) ; C810.2 v2(56.9,22.6) ; C811.2 v2(17.2,20.64) ; J21.17 v2(9.3,51.78) ; v2(180.09,64.38) 179.58,64.89 C754.2 ; C765.2 v2(58.29,61.08) ; C809.2 v2(72.64,22.72) ; J21.46 v2(11.78,34.38) ; P5.6 v2(17.7,82.72) ; C781.2 v2(57.02,52.69) ; C607.2 194.18,83.3 v2(193.93,83.56) ; R449.2 v2(55.56,15.74) ; C763.2 110.76,61.37 v1(110.38,61.75) ; R444.2 v2(74.04,16.75) ; J21.115 v2(6.57,58.37) ; C594.2 v2(159.26,85.59) ; R269.2 v2(135.64,130.61) ; R306.2 v2(68.33,87.11) ; v2(104.27,118.48) 104.27,119.24 C508.2 ; J21.11 v2(9.41,55.38) ; J21.6 v2(9.36,58.37) ; v2(179.58,114.92) 179.2,114.54 C525.2 ; C828.2 v1(110.49,15.11) ; R458.1 v2(127.64,6.97) ; C551.1 v2(43.56,100.32) ; J21.98 v2(6.53,48.17) ; C521.1 v2(129.67,115.69) ; J21.40 v2(9.4,37.97) ; R442.2 v1(105.83,16.28) ; R443.2 v2(103.29,16.28) ; 34.04,46.09 v2(34.04,45.33) ; U75.40 v1(105.16,23.02) ; U69.4 v2(23.36,86.98) ; 38.86,51.68 v2(38.1,51.68) ; 44.2,115.43 v2(43.43,115.43) ; C580.2 v2(194.56,92.95)
  BOTTOM w0.381: 94.92,17.93 C821.1 ; 94.92,17.93 v1(94.92,18.82) ; 94.92,17.93 94.95,17.93 ; v1(98.42,16.57) FL40.2 v1(98.42,19.29) ; U76.2 v1(98.58,22.07) ; 101.71,18.82 v1(101.71,18.1) ; C816.2 115.19,18.54 116.33,18.54 ; C820.2 v1(102.97,17.23) ; v1(114.77,16.3) 114.05,16.3
  BOTTOM w0.508: J20.43 v2(68.58,120.42) ; C507.2 v2(106.43,118.48) ; J20.35 v2(71.78,123.31) ; J20.29 v2(74.18,123.31) ; v2(104.27,114.16) 103.63,114.8 R276.1 ; v2(104.27,118.48) 103.5,118.48 103.12,118.86 C512.2 ; J20.50 v2(65.78,131.53) ; R275.1 103.76,115.81 v2(104.27,116.32) ; C523.2 109.47,115.05 v2(108.58,114.16) ; 40.77,37.84 v2(40.77,38.53) ; v2(79.38,129.78) 79.08,130.08 J20.18 ; J17.2 188.72,10.15 C837.1 ; v2(108.58,114.16) 109.09,113.65 C526.2 ; v2(108.58,114.16) 108.2,113.78 C531.2 ; J20.26 v2(75.38,128.64) ; J20.40 v2(69.78,131.53) ; v2(1.27,151.25) v2(4.45,151.25) v2(7.62,151.25) v2(10.79,151.25) v2(13.97,151.25) v2(17.14,151.25) v2(20.32,151.25) v2(23.5,151.25) v2(26.67,151.25) v2(29.84,151.25) v2(33.02,151.25) v2(35.56,151.25) v2(39.37,151.25) v2(43.18,151.25) v2(45.72,151.25) v2(48.9,151.25) v2(52.07,151.25) v2(55.24,151.25) v2(58.42,151.25) v2(61.59,151.25) v2(67.94,151.25) v2(71.12,151.25) v2(74.3,151.25) v2(77.47,151.25) v2(80.64,151.25) v2(83.82,151.25) v2(92.2,151.25) v2(160.02,151.25) v2(163.19,151.25) v2(166.37,151.25) v2(169.54,151.25) v2(172.72,151.25) v2(175.9,151.25) v2(179.07,151.25) v2(182.25,151.25) v2(185.42,151.25) v2(188.59,151.25) v2(191.77,151.25) v2(194.94,151.25) v2(198.12,151.25) v2(201.93,151.25) v2(201.93,148.07) v2(201.93,144.9) v2(201.93,141.72) v2(201.93,138.55) v2(201.93,135.37) v2(201.93,132.2) v2(201.93,129.02) v2(201.93,125.85) v2(201.93,122.67) v2(201.93,119.5) v2(201.93,116.32) v2(201.93,113.15) v2(201.93,109.97) v2(201.93,106.8) v2(201.93,103.62) v2(201.93,100.45) v2(201.93,97.27) v2(201.93,94.1) v2(201.93,90.92) v2(201.93,87.75) v2(201.93,84.57) v2(201.93,81.4) v2(201.93,78.22) v2(201.93,75.05) v2(201.93,71.87) v2(201.93,68.7) v2(201.93,65.52) v2(201.93,62.35) v2(201.93,59.17) v2(201.93,56) v2(201.93,52.82) v2(201.93,49.65) v2(201.93,46.47) v2(201.93,43.3) v2(201.93,40.12) v2(201.93,36.95) v2(201.93,33.77) v2(201.93,30.6) v2(201.93,27.42) v2(201.93,24.25) v2(201.93,21.07) v2(201.93,17.9) v2(201.93,14.72) v2(201.93,11.55) v2(201.93,8.37) v2(201.93,3.93) v2(201.93,2.02) 201.31,2.02 201.18,1.89 v2(198.12,1.89) v2(194.94,1.89) v2(191.77,1.89) v2(188.59,1.89) v2(185.42,1.89) v2(182.25,1.89) v2(179.07,1.89) v2(175.9,1.89) v2(172.72,1.89) v2(169.54,1.89) v2(166.37,1.89) v2(163.19,1.89) v2(160.02,1.89) v2(156.84,1.89) v2(153.67,1.89) v2(150.5,1.89) v2(147.32,1.89) v2(144.15,1.89) v2(140.97,1.89) v2(137.79,1.89) v2(135.64,1.89) 134.42,1.89 134.28,1.84 133.99,1.78 133.7,1.78 133.41,1.84 133.27,1.89 v2(131.44,1.89) v2(128.27,1.89) v2(125.09,1.89) v2(121.92,1.89) v2(118.75,1.89) v2(115.57,1.89) v2(112.39,1.89) 111.61,1.89 111.61,1.87 111.3,1.56 110.87,1.56 110.57,1.87 110.57,1.89 v2(109.22,1.89) 106.6,1.89 106.6,1.87 106.3,1.56 105.87,1.56 105.85,1.58 1.71,1.58 v2(1.27,2.02) 1.71,2.46 1.84,2.46 M4.1 ; J20.4 v2(87.38,131.56) ; C532.2 107.19,113.4 v2(106.43,114.16) 106.17,113.91 C533.2 ; v2(107.57,117.34) 107.82,117.59 C515.2 ; J20.27 v2(74.98,123.31) ; J20.9 v2(85.38,120.42) ; J20.21 v2(77.38,123.31) ; J20.37 v2(70.98,120.42) ; J20.15 v2(82.98,120.42) ; J20.34 v2(72.18,131.53) ; v2(109.98,112.51) R279.1 ; 40.77,30.72 v2(40.77,31.42)
  vias: v1(62.1,27.55) v1(62.14,26.15) v1(62.1,24.75) v1(63.37,28.82) v1(63.37,27.55) v1(63.41,26.15) v1(63.37,24.75) v1(63.37,23.48) v1(64.77,28.78) v1(64.77,27.51) v1(64.77,26.15) v1(64.77,24.79) v1(64.77,23.53) v1(66.13,26.15) v1(66.17,28.82) v1(66.17,27.55) v1(66.17,24.75) v1(66.17,23.48) v1(67.44,27.55) v1(67.4,26.15) v1(67.44,24.75) v1(78.36,89.14) v1(78.36,88.38) v1(78.36,85.97) v1(78.36,85.21) v1(81.2,86.76) v1(81.2,85.59) v1(81.2,83.68) v1(81.2,81.78) v1(81.62,80.31) v1(81.62,79.66) v1(81.66,78.35) v1(81.66,77.59) v1(81.66,75.81) v1(81.66,75.05) v1(81.7,72.63) v1(81.7,71.87) v1(81.66,70.6) v1(81.66,69.84) v1(83.82,89.22) v1(84.35,111.45) v1(84.35,110.56) v1(85.09,89.22) v1(86.36,89.22) v1(86.36,50.66) v1(86.36,46.85) v1(86.74,55.41) v1(87.12,50.66) v1(87.12,46.85) v1(87.63,89.22) v1(88.65,55.41) v1(90.17,53.71) v1(90.55,55.41) v1(90.93,53.71) v1(92.33,53.71) v1(93.09,53.71) v1(93.34,85.33) v1(94.49,53.71) v1(94.9,88.76) v1(95,87.26) v1(95,85.33) v1(95.25,97.78) v1(95.25,53.71) v1(95.38,94.1) v1(96.44,96.38) v1(96.43,93.84) v1(96.39,87.32) v1(96.39,85.33) v1(97.14,96.38) v1(97.13,93.84) v1(97.79,87.32) v1(97.79,85.33) v1(98.49,96.38) v1(98.49,93.84) v1(98.87,89.27) v1(99.19,96.38) v1(99.19,93.84) v1(99.19,87.44) v1(99.19,85.41) v1(99.57,89.27) v1(100.71,87.44) v1(100.71,85.41) v1(100.78,68.95) v1(101.59,72.95) v1(101.58,69.74) v1(101.75,89.4) v1(102.11,87.44) v1(102.11,85.33) v1(102.41,89.4) v1(102.74,32.5) v1(103.5,87.37) v1(103.5,85.33) v1(104.7,89.4) v1(104.78,92.32) v1(104.9,87.37) v1(104.9,85.33) v1(105.36,89.4) v1(105.97,26.01) v1(105.97,24.64) v1(105.97,23.27) v1(105.97,21.89) v1(106.3,87.37) v1(106.81,32.88) v1(107.34,26.01) v1(107.34,24.64) v1(107.34,23.27) v1(107.34,21.89) v1(107.34,20.52) v1(107.37,89.22) v1(108.58,102.61) v1(108.58,98.29) v1(108.71,26.01) v1(108.71,24.64) v1(108.71,23.27) v1(108.71,21.89) v1(108.71,20.52) v1(109.14,89.22) v1(109.22,85.59) v1(109.98,85.59) v1(109.98,32.88) v1(110.08,26.01) v1(110.08,24.64) v1(110.08,23.27) v1(110.08,21.89) v1(111,89.22) v1(111.25,32.88) v1(111.46,24.64) v1(111.46,23.27) v1(113,79.29) v1(113.41,58.41) v1(113.41,57.65) v1(113.67,109.46) v1(113.67,54.47) v1(113.79,80.51) v1(114.43,54.47) v1(114.58,88.79) v1(115.34,88.79) v1(115.57,54.47) v1(115.95,86.73) v1(115.95,84.57) v1(115.95,82.41) v1(115.95,58.41) v1(115.95,57.65) v1(116.33,54.47) v1(116.41,70.6) v1(116.41,68.06) v1(116.41,61.71) v1(117.12,88.92) v1(117.35,54.22) v1(117.88,88.92) v1(118.11,54.22) v1(118.36,113.02) v1(119.76,82.74) v1(119.76,82.03) v1(119.76,80.25) v1(119.76,79.49) v1(120.14,87.24) v1(120.14,86.48) v1(120.14,84.95) v1(120.14,84.24) v1(121.67,115.43) v1(122.48,57.01) v1(122.6,76.06) v1(122.89,55.49) v1(124.67,77.97) v1(124.76,76.06) v1(124.76,57.01) v1(125.05,55.49) v1(125.44,15.24) v1(125.44,14.22) v1(125.44,13.21) v1(126.11,119.88) v1(126.33,13.21) v1(126.92,57.01) v1(127.08,55.49) v1(127.56,76.06) v1(129.03,26.57) v1(129.11,55.49) v1(129.33,57.01) v1(129.75,77.97) v1(130.3,124.58) v1(130.56,26.57) v1(130.73,76.06) v1(130.73,74.54) v1(131.27,55.49) v1(132,58.28) v1(132.41,77.97) v1(132.46,24.89) v1(132.59,56.63) v1(132.72,72.2) v1(132.72,60.62) v1(133.1,75.81) v1(133.22,24.89) v1(133.35,56.63) v1(133.86,75.81) v1(134.37,72.44) v1(134.37,69.65) v1(134.37,56.63) v1(134.85,22.71) v1(135,66.08) v1(135,62.9) v1(135,59.73) v1(135.08,58.28) v1(135.13,56.63) v1(135.38,74.54) v1(135.76,92.7) v1(136.02,64.81) v1(136.14,74.54) v1(136.27,59.17) v1(136.53,62.27) v1(136.93,22.71) v1(137.03,69.51) v1(137.03,59.17) v1(137.67,65.84) v1(137.77,24.36) v1(138.56,129.28) v1(138.81,123.81) v1(139.85,24.36) v1(140.69,22.71) v1(142.77,22.71) v2(16.89,32.25) v2(17.14,5.2) v2(18.03,12.82) v2(25.53,137.4) v2(25.53,134.99) v2(25.53,133.72) v2(25.78,139.44) v2(26.92,135.75) v2(26.92,127.88) v2(27.94,72.13) v2(28.7,136.13) v2(28.96,142.74) v2(28.96,139.05) v2(29.21,126.74) v2(29.21,125.21) v2(30.48,141.85) v2(30.61,138.67) v2(30.99,124.83) v2(31.75,143.37) v2(31.75,124.07) v2(32.13,130.93) v2(32.13,129.78) v2(32.13,128.64) v2(32.38,132.07) v2(32.51,136.64) v2(32.51,135.5) v2(32.51,134.36) v2(32.51,133.21) v2(32.51,123.31) v2(32.77,84.32) v2(32.89,139.05) v2(32.89,127.88) v2(33.02,126.74) v2(33.02,125.59) v2(33.4,143.37) v2(33.53,129.28) v2(33.53,85.08) v2(33.78,124.83) v2(34.8,144.9) v2(34.92,136.9) v2(35.05,23.87) v2(35.18,143.5) v2(35.18,130.8) v2(35.69,132.83) v2(35.81,137.78) v2(35.81,134.86) v2(35.81,23.87) v2(35.94,124.32) v2(36.32,129.53) v2(36.32,127.62) v2(36.45,136.39) v2(36.58,125.21) v2(36.7,138.67) v2(36.96,134.86) v2(37.16,124.07) v2(37.21,23.87) v2(37.34,147.44) v2(37.97,142.99) v2(37.97,138.67) v2(37.97,137.4) v2(37.97,23.87) v2(38.1,136.26) v2(38.1,135.12) v2(38.1,130.67) v2(38.1,129.53) v2(38.1,128.39) v2(38.1,127.24) v2(38.1,126.1) v2(38.99,24.25) v2(38.99,23.48) v2(39.37,149.47) v2(39.37,57.27) v2(40.64,142.99) v2(40.64,141.59) v2(40.77,59.83) v2(40.77,58.54) v2(40.77,22.72) v2(40.89,100.32) v2(40.89,99.05) v2(41.02,19.04) v2(41.15,138.67) v2(41.15,137.53) v2(41.15,136.39) v2(41.15,135.24) v2(41.15,134.1) v2(41.15,132.96) v2(41.15,131.82) v2(41.15,130.67) v2(41.15,129.53) v2(41.15,128.39) v2(41.15,127.24) v2(41.15,126.1) v2(41.15,124.96) v2(41.4,147.44) v2(41.53,36.57) v2(41.53,34.79) v2(41.53,29.45) v2(41.53,27.68) v2(42.06,58.54) v2(42.16,141.47) v2(42.42,99.68) v2(42.93,112.89) v2(42.93,111.62) v2(42.93,110.35) v2(42.93,109.08) v2(42.93,107.81) v2(43.05,36.57) v2(43.05,34.79) v2(43.05,29.45) v2(43.05,27.68) v2(43.43,141.47) v2(44.2,112.89) v2(44.2,111.62) v2(44.2,110.35) v2(44.2,109.08) v2(44.2,107.81) v2(45.47,139.31) v2(45.47,138.17) v2(45.47,137.02) v2(45.47,135.88) v2(45.47,112.89) v2(45.47,111.62) v2(45.47,110.35) v2(45.47,109.08) v2(45.47,107.81) v2(45.59,134.74) v2(45.59,133.59) v2(45.72,123.56) v2(46.61,132.83) v2(46.61,124.7) v2(46.74,112.89) v2(46.74,111.62) v2(46.74,110.35) v2(46.74,109.08) v2(46.74,107.81) v2(46.99,129.28) v2(46.99,128.26) v2(46.99,127.24) v2(46.99,126.1) v2(47.24,141.47) v2(47.24,139.18) v2(47.24,137.91) v2(47.5,134.86) v2(47.75,131.94) v2(47.75,130.93) v2(47.75,129.91) v2(48.01,112.89) v2(48.01,111.62) v2(48.01,110.35) v2(48.01,109.08) v2(48.01,107.81) v2(48.77,125.85) v2(50.93,140.45) v2(52.2,140.45) v2(52.58,121.53) v2(52.96,146.42) v2(53.21,137.66) v2(53.21,136.51) v2(53.21,135.37) v2(53.21,134.23) v2(53.21,133.09) v2(53.21,131.94) v2(53.21,130.8) v2(53.21,129.66) v2(53.21,128.51) v2(53.21,127.37) v2(53.21,126.23) v2(53.21,125.08) v2(53.21,123.94) v2(53.72,141.85) v2(53.72,140.58) v2(54.99,148.45) v2(56.26,141.85) v2(56.26,135.24) v2(56.26,134.1) v2(56.26,129.66) v2(56.26,128.51) v2(56.26,127.37) v2(56.26,126.23) v2(56.26,125.08) v2(56.39,137.66) v2(56.39,136.39) v2(57.02,146.42) v2(56.98,103.49) v2(57.2,123.05) v2(57.4,137.02) v2(57.4,133.85) v2(57.78,129.66) v2(57.78,124.2) v2(57.91,135.37) v2(58.29,136.51) v2(58.55,133.85) v2(58.67,131.82) v2(59.18,142.48) v2(59.18,129.78) v2(59.56,143.88) v2(60.07,132.7) v2(60.07,130.93) v2(60.83,142.48) v2(61.54,97.67) v2(62.48,73.03) v2(62.61,36.69) v2(63.58,97.68) v2(63.88,101.34) v2(64.21,97.68) v2(64.39,72.46) v2(64.55,93.86) v2(64.55,92.72) v2(65.02,101.34) v2(65.38,95.12) v2(65.53,38.09) v2(65.91,103.75) v2(65.91,102.86) v2(65.91,36.69) v2(66.29,73.09) v2(66.42,94.73) v2(67.06,103.75) v2(67.06,102.86) v2(67.44,94.73) v2(68.07,72.46) v2(68.2,103.75) v2(68.2,102.86) v2(68.58,35.3) v2(68.83,94.73) v2(69.51,104.82) v2(69.51,104.18) v2(69.46,32.7) v2(69.85,94.73) v2(70.45,104.82) v2(70.45,104.18) v2(71.88,118.86) v2(72.01,73.35) v2(72.01,68.49) v2(73.78,74.19) v2(74.17,118.86) v2(74.55,108.45) v2(74.55,107.43) v2(74.55,106.42) v2(74.55,105.4) v2(74.55,104.38) v2(74.8,117.46) v2(74.8,116.32) v2(74.8,115.18) v2(74.8,97.65) v2(74.8,96.51) v2(74.8,95.37) v2(75.39,113.49) v2(75.39,112.55) v2(75.39,100.28) v2(75.39,99.34) v2(75.56,108.45) v2(75.56,107.43) v2(75.56,106.42) v2(75.56,105.4) v2(75.56,104.38) v2(75.69,117.46) v2(75.69,116.32) v2(75.69,115.18) v2(75.69,97.65) v2(75.69,96.51) v2(75.69,95.37) v2(76.02,113.49) v2(76.02,112.55) v2(76.02,100.28) v2(76.02,99.34) v2(76.08,72.34) v2(76.45,79.57) v2(76.58,108.45) v2(76.58,107.43) v2(76.58,105.4) v2(76.58,104.38) v2(77.14,113.49) v2(77.14,100.28) v2(77.14,99.34) v2(77.47,117.46) v2(77.47,116.32) v2(77.47,115.18) v2(77.47,97.65) v2(77.47,96.51) v2(77.47,95.37) v2(77.6,108.45) v2(77.6,107.43) v2(77.6,106.42) v2(77.6,105.4) v2(77.6,104.38) v2(77.78,113.49) v2(77.78,112.55) v2(77.78,100.28) v2(77.78,99.34) v2(77.85,73.19) v2(78.36,117.46) v2(78.36,116.32) v2(78.36,115.18) v2(78.36,97.65) v2(78.36,96.51) v2(78.36,95.37) v2(78.61,108.45) v2(78.61,107.43) v2(78.61,106.42) v2(78.61,105.4) v2(78.61,104.38) v2(79.25,17.77) v2(79.25,17.01) v2(80.64,93.84) v2(81.03,125.21) v2(81.66,93.84) v2(82.93,149.98) v2(83.19,93.84) v2(83.95,118.73) v2(84,109.74) v2(84,108.37) v2(84.01,107.05) v2(84.01,105.4) v2(84.01,104) v2(84.01,102.35) v2(84.2,93.84) v2(84.96,147.69) v2(85.85,116.83) v2(86.49,125.34) v2(88.01,114.67) v2(88.13,44.57) v2(88.27,112.26) v2(88.27,108.83) v2(88.27,104.38) v2(88.27,101.34) v2(88.27,97.53) v2(88.52,117.72) v2(88.57,46.47) v2(89.53,119.75) v2(90.04,114.16) v2(90.04,110.61) v2(90.04,106.92) v2(90.04,102.73) v2(90.04,99.18) v2(90.42,146.17) v2(90.73,92.06) v2(91.26,96.13) v2(91.57,117.46) v2(91.69,114.16) v2(91.69,109.34) v2(91.69,105.27) v2(91.69,101.08) v2(91.7,97.78) v2(92.08,120.26) v2(92.58,146.17) v2(92.71,147.82) v2(94.11,92.52) v2(94.82,99.68) v2(94.82,96.13) v2(95.33,101.46) v2(95.38,92.52) v2(96.52,150.48) v2(96.52,48.22) v2(97.08,50.15) v2(98.04,132.45) v2(98.81,132.45) v2(100.71,151.5) v2(101.46,48.25) v2(101.9,50.15) v2(102.23,51.68) v2(102.87,151.5) v2(103.58,97.4) v2(104.14,99.3) v2(104.19,51.55) v2(105.41,117.34) v2(105.41,115.31) v2(105.41,52.06) v2(106.05,151.5) v2(106.43,116.32) v2(106.68,52.67) v2(107.06,46.73) v2(107.44,115.31) v2(107.7,48.05) v2(108.16,96.38) v2(108.16,92.32) v2(108.2,45.58) v2(108.25,53.08) v2(108.58,116.32) v2(108.69,94.22) v2(108.97,48.63) v2(109.22,151.5) v2(110.62,48.76) v2(111.38,148.96) v2(111.38,147.44) v2(111.89,148.2) v2(111.89,135.37) v2(112.39,151.5) v2(112.39,148.96) v2(112.39,147.44) v2(112.53,51.3) v2(112.9,135.37) v2(113.24,91.18) v2(113.16,45.58) v2(113.54,92.45) v2(114.17,135.37) v2(114.43,38.6) v2(114.94,48.25) v2(115.32,135.37) v2(115.57,151.5) v2(117.14,38.6) v2(117.47,135.37) v2(117.6,45.58) v2(118.75,151.5) v2(118.75,106.92) v2(119.76,106.92) v2(120.02,15.1) v2(120.02,14.34) v2(120.02,8.75) v2(120.02,7.99) v2(120.4,99.18) v2(120.4,98.29) v2(120.4,96.51) v2(120.4,95.62) v2(121.16,106.92) v2(121.41,45.71) v2(121.54,99.18) v2(121.54,98.29) v2(121.54,96.51) v2(121.54,95.62) v2(121.67,120.13) v2(121.92,151.5) v2(122.17,106.92) v2(122.3,38.6) v2(122.68,99.18) v2(122.68,98.29) v2(122.68,96.51) v2(122.86,32.88) v2(124,80.41) v2(124.37,98.59) v2(124.37,97.96) v2(124.37,96.84) v2(124.37,96.2) v2(124.59,38.6) v2(124.84,28.56) v2(125.02,80.41) v2(125.09,151.5) v2(125.35,130.93) v2(125.31,98.59) v2(125.31,97.96) v2(125.31,96.84) v2(125.31,96.2) v2(125.6,136.77) v2(125.98,139.69) v2(126.11,28.56) v2(126.49,80.43) v2(126.75,38.6) v2(127.13,20.31) v2(127.38,32.88) v2(127.51,80.43) v2(127.51,27.8) v2(128.12,104.82) v2(128.27,151.5) v2(129.03,28.69) v2(129.41,99.43) v2(129.41,98.41) v2(129.41,97.4) v2(129.41,96.38) v2(129.41,95.37) v2(129.41,9.9) v2(129.49,104.82) v2(129.67,139.69) v2(129.79,32.88) v2(129.92,131.05) v2(130.18,136.77) v2(130.43,99.43) v2(130.43,98.41) v2(130.43,97.4) v2(130.43,96.38) v2(130.43,95.37) v2(131.44,151.5) v2(131.44,99.43) v2(131.44,98.41) v2(131.44,96.38) v2(131.44,95.37) v2(131.83,32.88) v2(131.83,28.44) v2(132.46,99.43) v2(132.46,98.41) v2(132.46,97.4) v2(132.46,96.38) v2(132.46,95.37) v2(133.04,90.32) v2(133.48,99.43) v2(133.48,98.41) v2(133.48,97.4) v2(133.48,96.38) v2(133.48,95.37) v2(133.68,91.26) v2(133.68,90.32) v2(133.86,104.83) v2(134.04,107.27) v2(134.04,106.33) v2(133.96,64.72) v2(134.11,89.02) v2(134.11,87.87) v2(134.11,86.73) v2(134.62,151.5) v2(134.67,107.27) v2(134.67,106.33) v2(135,89.02) v2(135,87.87) v2(135,86.73) v2(135.51,104.83) v2(135.71,72.16) v2(137.58,98.59) v2(137.58,96.2) v2(137.79,151.5) v2(138.52,98.59) v2(138.52,96.84) v2(140.21,98.29) v2(140.21,96.51) v2(140.21,95.62) v2(140.97,151.5) v2(141.35,99.18) v2(141.35,98.29) v2(141.35,96.51) v2(141.35,95.62) v2(142.49,99.18) v2(142.49,98.29) v2(142.49,96.51) v2(142.49,95.62) v2(144.15,151.5) v2(144.65,139.56) v2(144.65,133.34) v2(147.32,151.5) v2(148.84,139.56) v2(148.97,137.4) v2(149.22,132.58) v2(149.48,121.91) v2(150.5,151.5) v2(151.31,19.04) v2(151.31,18.02) v2(151.64,66.92) v2(153.67,151.5) v2(155.45,30.72) v2(155.45,29.45) v2(156.08,30.09) v2(156.72,30.72) v2(156.72,29.45) v2(156.84,151.5) v2(157.35,13.2) v2(157.35,11.93) v2(157.99,35.8) v2(157.99,33.9) v2(158.5,33.26) v2(158.5,13.2) v2(158.5,11.93) v2(159.64,13.2) v2(159.64,11.93) v2(159.77,34.15) v2(160.66,143.37) v2(160.66,140.2) v2(160.66,137.02) v2(160.66,133.85) v2(160.66,130.67) v2(160.66,127.5) v2(160.66,124.32) v2(160.66,121.15) v2(164.47,134.1) v2(166.37,134.1) v2(166.62,17.13) v2(166.88,80.51) v2(167,73.01) v2(167.51,17.13) v2(168.28,134.1) v2(168.78,73.01) v2(170.18,134.1) v2(170.64,96.54) v2(170.64,95.77) v2(170.94,73.01) v2(171.45,99.3) v2(171.45,98.22) v2(172.09,134.1) v2(172.09,118.99) v2(172.09,118.1) v2(172.09,117.21) v2(172.72,73.01) v2(172.85,98.92) v2(173.86,98.92) v2(173.99,134.1) v2(174.88,73.01) v2(175.45,114.99) v2(175.9,134.1) v2(176.34,114.99) v2(176.66,73.01) v2(177.23,114.99) v2(177.8,134.1) v2(179.45,73.27) v2(179.71,134.1) v2(179.77,50.28) v2(180.09,70.09) v2(180.09,69.2) v2(180.09,65.27) v2(180.09,63.49) v2(180.09,62.35) v2(180.09,61.46) v2(180.09,59.68) v2(180.09,49.01) v2(180.09,48.12) v2(180.09,47.23) v2(180.09,46.34) v2(180.09,45.07) v2(180.09,44.19) v2(180.09,43.3) v2(180.47,52.31) v2(181.1,68.32) v2(181.1,65.27) v2(181.23,73.27) v2(181.36,54.85) v2(181.61,134.1) v2(181.67,114.99) v2(182.5,90.92) v2(182.5,89.91) v2(182.5,74.41) v2(182.5,72.89) v2(182.56,114.99) v2(183.51,134.1) v2(183.45,114.99) v2(183.51,73.27) v2(184.53,90.41) v2(184.53,89.4) v2(185.29,118.99) v2(185.29,118.1) v2(185.29,117.21) v2(185.29,73.27) v2(185.42,134.1) v2(185.55,90.41) v2(185.55,89.4) v2(187.32,134.1) v2(187.58,73.27) v2(187.96,54.47) v2(187.96,53.58) v2(187.96,51.81) v2(187.96,50.92) v2(188.21,9.01) v2(188.47,7.61) v2(188.85,54.47) v2(188.85,53.58) v2(188.85,51.81) v2(188.85,50.92) v2(189.23,134.1) v2(189.36,73.27) v2(189.74,53.58) v2(189.74,52.69) v2(189.74,51.81) v2(189.74,50.92) v2(189.87,10.66) v2(189.87,7.36) v2(191.13,134.1) v2(191.13,80.51) v2(191.26,10.28) v2(191.26,7.61) v2(191.52,9.01) v2(191.64,73.27) v2(192.66,84.83) v2(192.66,83.56) v2(193.04,134.1) v2(193.17,14.98) v2(193.17,13.71) v2(193.42,73.27) v2(193.93,84.83) v3(40.77,21.76) v3(40.77,20.89) v3(93.22,12.82) v3(93.73,11.8) v3(93.98,10.53) v3(93.98,9.39) v3(93.98,8.12) v3(93.98,6.97) v3(99.69,9.39) v3(99.69,8.12) v3(100.97,10.66) v3(100.97,9.39) v3(100.97,8.12) v3(100.97,6.85) v3(101.6,11.93) v3(102.36,6.85) v4(2.67,83.94) v4(2.67,82.67) v4(2.67,81.4) v4(2.67,80.13) v4(2.67,78.86) v4(2.67,77.59) v4(2.67,76.32) v4(4.45,83.94) v4(4.45,82.67) v4(4.45,81.4) v4(4.45,80.13) v4(4.45,78.86) v4(4.45,77.59) v4(4.45,76.32) v4(5.84,81.4) v4(5.84,80.13) v4(5.84,78.86) v4(7.11,81.4) v4(7.11,80.13) v4(7.11,78.86) v4(8.38,81.4) v4(8.38,80.13) v4(8.38,78.86) v4(9.65,81.4) v4(9.65,80.13) v4(9.65,78.86) v4(10.92,80.13) v4(12.19,80.13) v4(13.46,80.13) v4(13.72,81.52) v4(13.72,78.6) v4(95.63,9.51) v4(95.63,8.24) v4(96.9,9.51) v4(96.9,8.24) v4(98.17,9.51) v4(98.17,8.24) v4(107.19,132.2) v4(107.19,130.93) v4(107.19,129.66) v4(108.46,133.47) v4(108.46,132.2) v4(108.46,130.93) v4(108.46,129.66) v4(109.73,133.47) v4(109.73,132.2) v4(109.73,130.93) v4(109.73,129.66) v4(158.37,113.02) v4(160.91,113.02) v4(163.45,113.02) v4(165.99,113.02) v4(176.15,35.17) v4(176.15,32.37) v4(177.42,35.17) v4(177.42,32.37) v4(178.69,35.17) v4(178.69,32.37) v4(179.96,35.17) v4(179.96,32.37) v4(180.21,26.91) v4(181.23,35.17) v4(181.23,32.37) v4(181.48,26.91) v4(182.75,26.91) v4(184.02,26.91) v4(184.53,35.17) v4(184.53,32.37) v4(185.29,26.91) v4(185.8,35.17) v4(185.8,32.37) v4(187.07,35.17) v4(187.07,32.37) v4(188.34,35.17) v4(188.34,32.37) v4(189.61,35.17) v4(189.61,32.37) v4(192.02,113.02) v4(194.56,113.02) v4(197.1,113.02) v4(199.64,113.02)
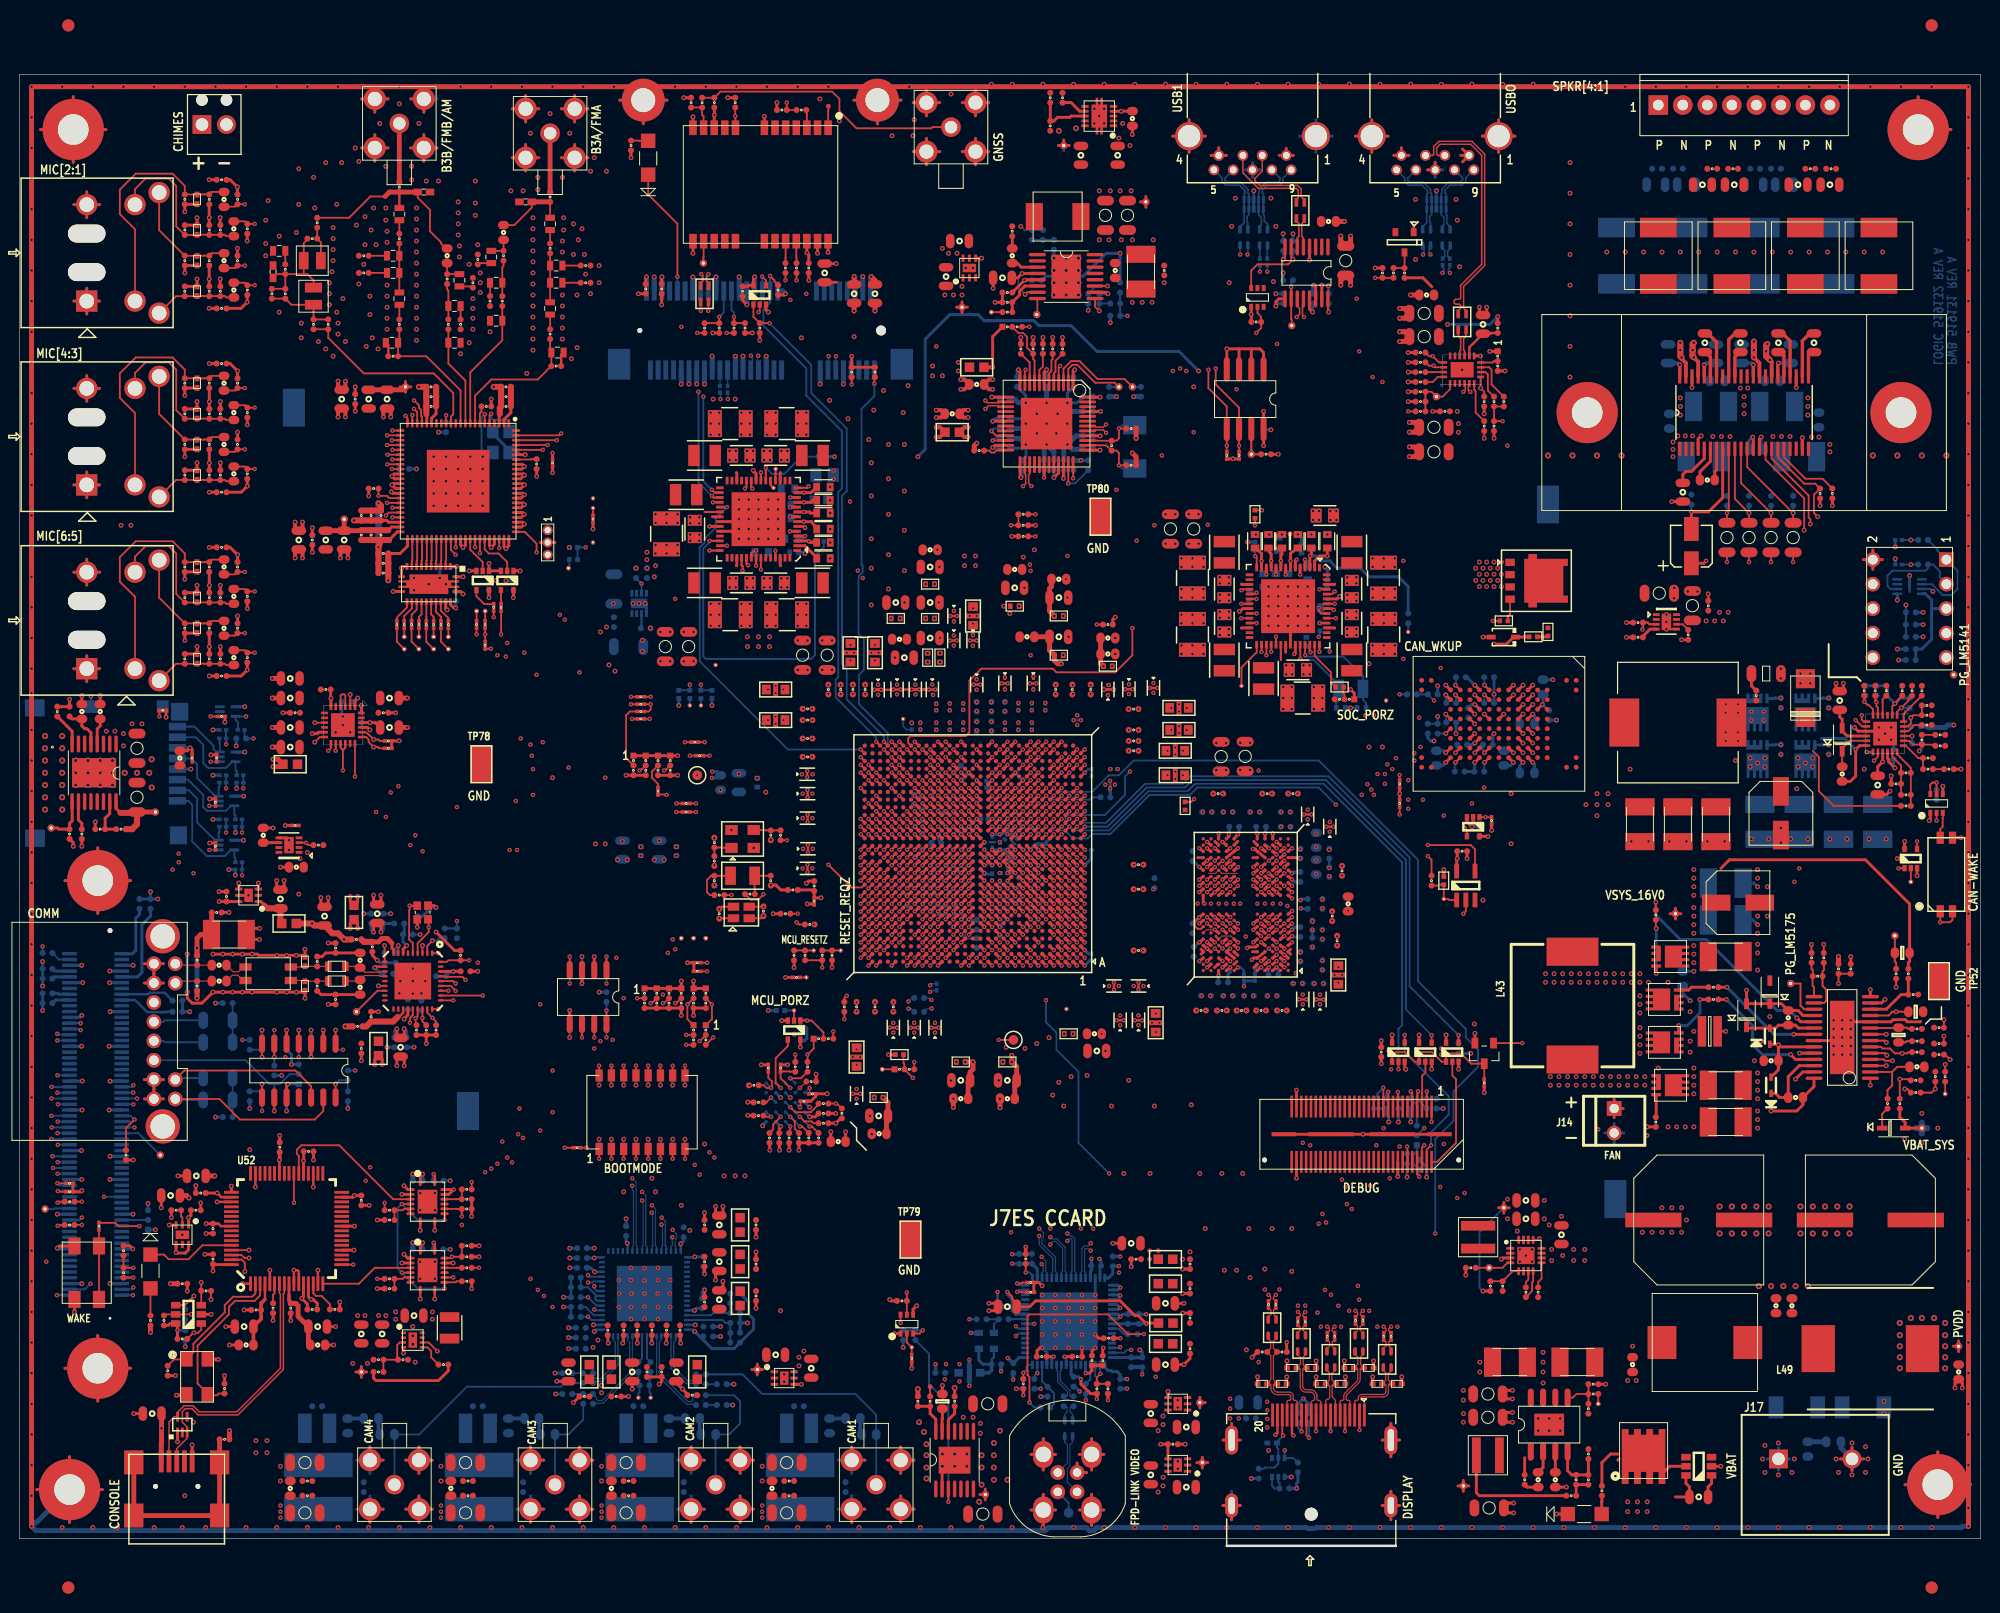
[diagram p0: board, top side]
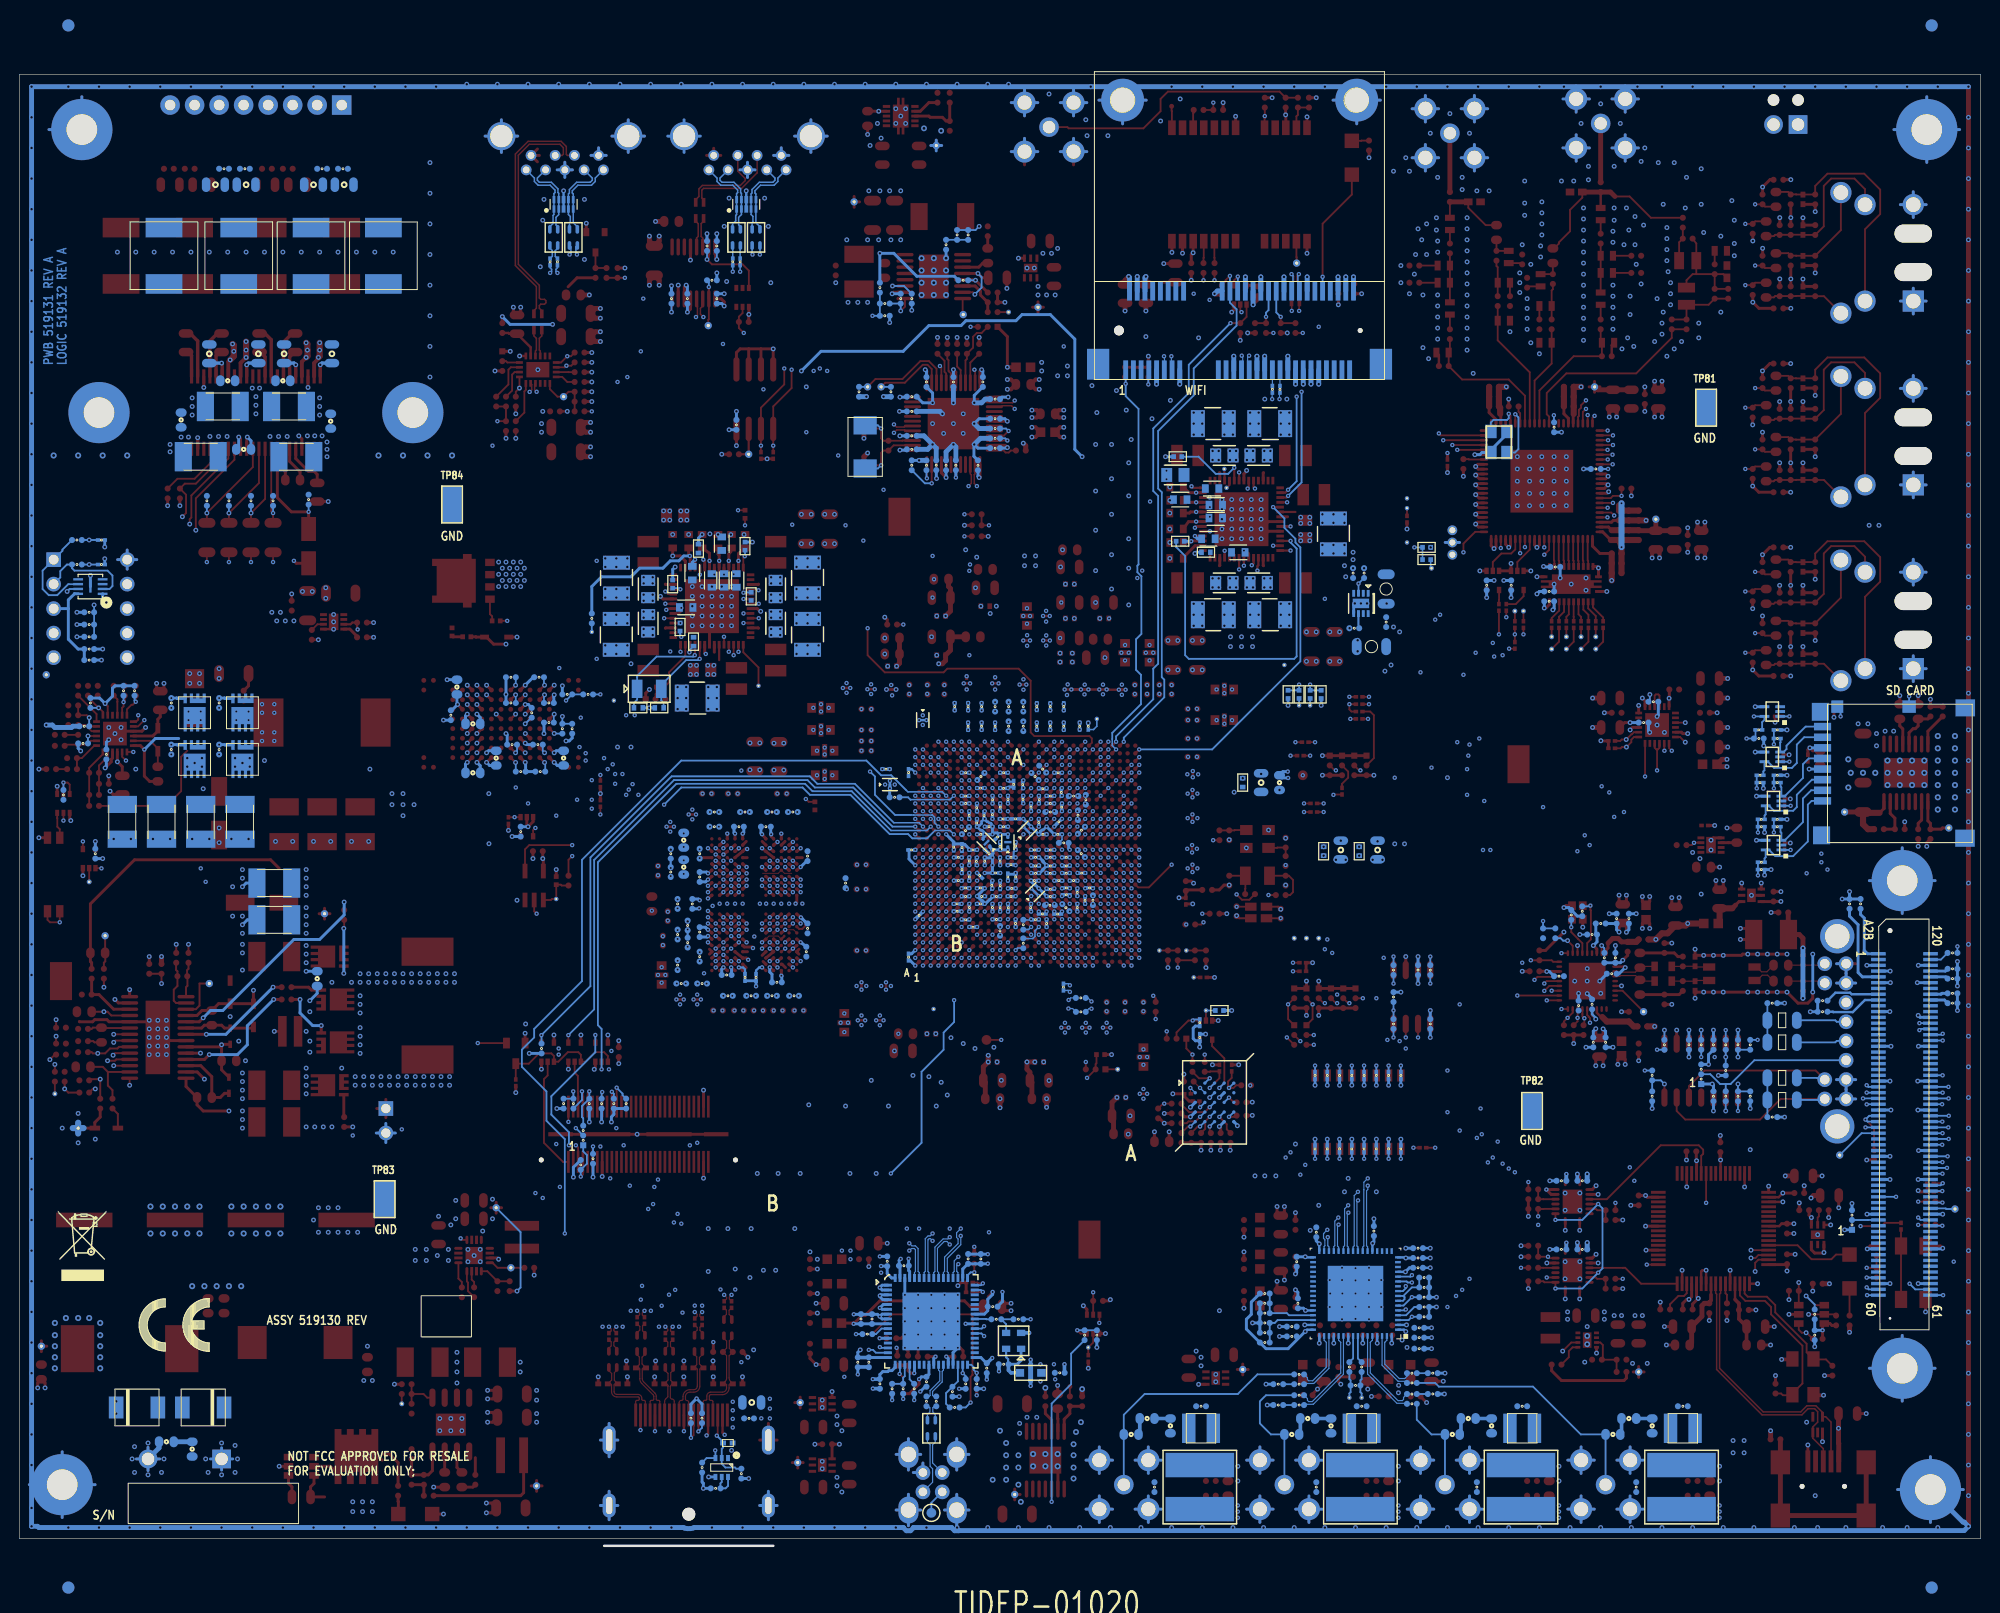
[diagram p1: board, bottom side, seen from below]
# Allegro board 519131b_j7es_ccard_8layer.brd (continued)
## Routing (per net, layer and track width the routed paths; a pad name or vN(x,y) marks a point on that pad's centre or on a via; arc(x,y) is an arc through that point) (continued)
PVDD: length 3.4
  TOP w0.305: 200.91,20.13 TP65.1 ; TP65.1 200.91,21.25 ; TP65.1 200.35,20.69
  L5-SIGNAL w0.305: 200.35,20.69 TP65.1 ; TP65.1 200.91,20.13 ; TP65.1 200.91,21.25
  vias: v2(171.32,114.42) v2(171.32,113.65) v2(171.32,112.89) v2(171.83,115.05) v2(172.59,115.05) v2(173.35,115.05) v2(178.31,120) v2(178.69,119.12) v2(178.69,118.23) v2(178.69,117.34) v2(179.07,120) v2(185.67,114.92) v2(186.44,114.92) v2(187.58,114.16) v2(187.58,113.4) v4(194.82,23.1) v4(194.82,21.83) v4(194.82,20.69) v4(194.82,19.55) v4(194.82,18.4) v4(195.96,23.61) v4(197.1,23.61) v4(198.37,23.61) v4(199.52,23.1) v4(199.52,21.83) v4(199.52,20.69) v4(199.52,19.55) v4(199.52,18.4)
V3V3_DP0: length 2.2
  TOP w0.305: 122,8.63 TP72.1 ; TP72.1 122.56,9.19 ; TP72.1 123.11,8.63 ; TP72.1 122.56,8.07
  vias: v1(129.29,14.94) v1(129.29,14.05) v1(129.29,13.16) v1(129.29,12.27)
V941_IO_1V1: length 1.7
  TOP w0.305: 122.3,14.29 TP70.1 ; TP70.1 122.3,15.41 ; TP70.1 122.86,14.85
V960_IO_1V1: length 2.2
  TOP w0.305: TP67.1 76.45,18.84 ; TP67.1 77.01,18.28 ; TP67.1 76.45,17.72 ; TP67.1 75.89,18.28
VBAT: length 13
  TOP w0.305: 171.58,5.07 C477.2 173.02,6.11 172.67,6.47 U64.6
  L6-PWR w0.305: J17.1 182.25,10.16 ; J17.1 181.09,9.01 ; J17.1 182.25,7.85 ; J17.1 183.4,9.01
  BOTTOM w0.305: 182.25,7.85 J17.1 ; J17.1 183.4,9.01 ; J17.1 181.09,9.01 ; J17.1 182.25,10.16
  vias: v2(166.62,4.56) v2(166.62,3.55) v2(167.64,4.56) v2(167.64,3.55) v2(168.66,4.56) v2(168.66,3.55) v2(180.59,9.01) v2(180.85,10.4) v2(180.85,7.61) v2(182.25,10.66) v2(182.25,7.36) v2(183.64,7.61) v2(183.9,9.01)
VBAT_SYS: length 203
  TOP w0.305: R199.1 194.82,44.44 195.38,43.88 D13.2 TP60.1 ; C266.1 192.53,80.76 v2(193.04,81.27) 193.05,81.27 U33.15 ; v2(27.81,47.87) 27.69,47.74 U50.10 ; J14.1 166.17,45.33 ; J14.1 165.23,46.27 ; J14.1 165.23,44.39
  L5-SIGNAL w0.635: v2(167.13,20.69) 165.48,19.04 165.48,15 158.34,7.86 124.84,7.86 123.06,9.64 117.47,9.64 113.69,13.43 103.76,13.43 101.96,15.23 77.22,15.23 73.15,19.29 54.36,19.29 51.69,16.63 33.15,16.63 27.24,22.53 27.24,35.87 28.57,37.2 28.57,47.11 v2(27.81,47.87)
  L6-PWR w0.305: TP60.1 197.1,43.86 ; TP60.1 197.1,42.74 ; TP60.1 196.54,43.3 ; TP60.1 197.66,43.3
  BOTTOM w0.305: C787.1 27.69,47.74 v2(27.81,47.87) RJ18.1
  BOTTOM w0.508: R315.2 197.66,84.95 197.79,84.83 199.53,84.83 199.78,85.08 v2(200.41,85.08)
  BOTTOM w0.635: 196.54,43.3 TP60.1 ; TP60.1 197.1,43.86 ; TP60.1 197.66,43.3 ; TP60.1 197.1,42.74
  vias: v2(168.15,32.5) v2(169.16,32.5) v2(170.18,35.04) v2(170.18,32.5) v2(170.81,43.42) v2(171.2,35.04) v2(171.2,32.5) v2(171.7,43.42) v2(172.21,35.04) v2(172.21,32.5) v2(172.59,43.42) v2(172.72,33.77) v2(173.48,49.52) v2(173.48,48.63) v2(173.48,47.74) v2(173.48,46.85) v2(173.48,43.42) v2(177.8,81.4) v2(179.32,81.65) v2(179.32,80.76) v2(180.09,81.14) v2(180.85,81.65) v2(180.85,80.76) v2(184.28,81.65) v2(184.28,80.76) v2(185.04,81.14) v2(185.8,81.65) v2(185.8,80.76) v2(195.33,42.15) v2(197.1,44.82) v2(197.1,41.77) v2(198.75,43.3)
VBUS2_5V0: length 2.2
  TOP w0.305: J1.1 131.26,144.86 ; J1.1 132,144.12 ; J1.1 130.53,144.12
VBUS_USBC_CONN: length 12.2
  TOP w0.305: 149.52,143.46 J2.1 ; J2.1 149.52,144.78 ; J2.1 149.32,144.12 ; 146.34,130.51 145.41,131.43 R19.1 ; v2(153.16,127.42) R33.1
  BOTTOM w0.305: v2(153.16,127.42) 152.36,126.61 v2(147.96,126.61)
VCC_1V1USB: length 20.9
  TOP w0.305: U16.45 111.99,117.57 v2(112.01,117.59) ; U16.18 v2(100.84,116.57) ; U16.30 106.18,110.74 v1(106.17,110.73) ; v2(100.84,122.16) 100.84,125.34 RJ1.1 ; v2(109.35,121.91) 109.17,121.74 U16.1 ; U16.12 103.68,121.74 v2(103.5,121.91) ; U16.34 v2(108.18,110.63)
  TOP w0.406: v2(100.84,119.88) 100.46,119.88 C82.1 100.46,120.89 v2(100.84,120.89) ; 99.95,122.16 v2(100.84,122.16)
  BOTTOM w0.305: v2(108.18,110.63) 108.2,110.66 C531.1 ; v2(103.5,121.91) 103.38,121.78 C508.1 ; C516.1 101.1,116.83 v2(100.84,116.57) ; v2(109.35,121.91) 109.22,121.78 C506.1 ; C533.1 v1(106.17,110.73) ; C515.1 v2(112.01,117.59)
VCC_APL: length 10.1
  BOTTOM w0.305: 196.47,91.81 196.47,92.95 197.1,92.95 198.12,93.97 198.12,97.14 ; 198.12,97.14 J11.5 ; 198.12,97.14 198.12,98.05 197.49,98.68 U67.8
VCC_LM5141: length 5.1
  TOP w0.305: U33.10 189.36,83.94 188.85,84.46 D8.2 188.85,85.68 188.59,85.93 C230.1
VCC_LM5175: length 24.4
  TOP w0.203: R193.2 195.58,47.36 v2(195.33,47.36)
  TOP w0.305: D12.2 182.25,49.34 C350.1 v2(182.25,51.93) ; D11.2 182.19,51.98 v2(182.25,51.93) ; v2(182.25,51.93) 182.46,51.72 U46.23
  L4-SIGNAL w0.305: v2(195.33,47.36) 194.56,47.36 193.29,48.63 189.36,48.63 185.67,52.31 182.63,52.31 v2(182.25,51.93)
VCCA_3V3: length 16.6
  TOP w0.305: U20.26 74.33,111.21 74.3,111.24 ; U20.35 71.81,106.67 ; U27.8 v1(131.2,100.68) ; U27.35 131.2,92.63 ; 78.87,101.59 78.83,101.63 U20.54 ; U20.8 v1(79.86,106.67) ; U27.26 126.66,95.15 126.62,95.11 ; 136.27,95.11 136.23,95.15 U27.45 ; U20.12 v1(79.88,108.67) ; U20.10 v1(79.86,107.67) ; 136.27,99.68 136.23,99.65 U27.54 ; 74.3,101.59 74.33,101.63 U20.45 ; U27.12 v1(129.2,100.7) ; v1(133.2,102.22) U27.4 ; U27.10 v1(130.2,100.68) ; 78.87,111.24 78.83,111.21 U20.17 ; U27.17 126.66,99.65 126.62,99.68 ; v1(81.41,104.67) U20.4
  BOTTOM w0.305: C549.1 81.28,102.99 v2(81.41,102.86) ; v1(133.2,102.22) 133.48,101.94 C552.1 ; v1(81.41,104.67) 81.13,104.38 C546.1
  vias: v2(65.02,102.99) v2(65.02,102.22) v2(65.79,100.45) v2(65.91,101.59) v2(69.51,106.62) v2(69.51,105.98) v2(70.45,106.62) v2(70.45,105.98) v2(73.59,113.49) v2(73.59,112.55) v2(73.59,100.28) v2(73.59,99.34) v2(74.22,113.49) v2(74.22,112.55) v2(74.22,100.28) v2(74.22,99.34) v2(78.94,113.49) v2(78.94,112.55) v2(78.94,100.28) v2(78.94,99.34) v2(79.58,113.49) v2(79.58,112.55) v2(79.58,100.28) v2(79.58,99.34) v2(124.37,100.39) v2(124.37,99.76) v2(124.37,95.04) v2(124.37,94.4) v2(125.31,100.39) v2(125.31,99.76) v2(125.31,95.04) v2(125.31,94.4) v2(131.24,91.26) v2(131.24,90.32) v2(131.88,91.26) v2(131.88,90.32) v2(135.82,107.27) v2(135.82,106.33) v2(136.45,107.27) v2(136.45,106.33) v2(137.58,100.39) v2(137.58,99.76) v2(137.58,95.04) v2(137.58,94.4) v2(138.52,100.39) v2(138.52,99.76) v2(138.52,95.04) v2(138.52,94.4) v2(150.88,101.34) v2(150.88,100.07) v2(151.26,101.97) v2(151.26,100.7) v2(151.26,99.43) v2(151.64,101.34) v2(151.64,100.07) v2(152.02,101.97) v2(152.02,100.7) v2(152.02,99.43) v2(152.4,101.34) v2(152.4,100.07) v2(152.78,101.97) v2(152.78,100.7) v2(152.78,99.43) v2(153.16,101.34) v2(153.16,100.07) v2(153.54,101.97) v2(153.54,100.7) v2(153.54,99.43)
VDD1_LPDDR4_1V8: length 14.8
  TOP w0.305: U40.F1 v1(131.86,63.21) ; C135.1 128.12,103.42 128.69,102.84 v1(128.69,102.1) U27.13 ; U40.F12 v1(122.25,62.56) ; v1(131.86,69.71) 131.45,70.03 U40.U1 ; U40.T4 129.05,69.38 v1(129.46,69.06) ; U40.U12 122.65,70.03 v1(122.25,70.36) ; U40.G9 v1(124.65,63.86) ; v1(124.65,69.06) 125.05,69.38 U40.T9 ; U40.G4 v1(128.66,63.86)
  L6-PWR w0.305: v1(122.25,62.56) 122.99,63.29 124.08,63.29 v1(124.65,63.86)
  L7-SIGNAL w0.305: v1(122.25,62.56) 122.25,62.14 122.3,62.09 ; v1(122.25,70.36) 122.25,70.81 122.3,70.86 ; 131.7,70.47 131.86,70.32 v1(131.86,69.71)
  BOTTOM w0.305: 132.72,63.11 131.95,63.11 v1(131.86,63.21) ; C761.1 121.67,62.12 122.02,62.38 v1(122.25,62.56) ; v1(131.86,69.71) 131.99,69.84 C705.1 ; C683.1 121.63,70.98 v1(122.25,70.36)
  vias: v1(123.4,57.01) v1(125.68,76.06) v1(127.84,57.01) v1(128.48,76.06) v1(131.65,74.54) v1(134.16,58.28) v1(134.37,73.84)
VDD18_DSI: length 8.6
  TOP w0.305: v1(109.98,17.28) 109.98,16.78 110.99,15.77 R248.1 v1(111.63,15.23) ; R246.1 v1(104.01,15.61)
  BOTTOM w0.229: R248.1 v1(111.63,15.23)
  BOTTOM w0.305: 111.07,29.03 111.07,28.54 110.96,28.44 U75.61 ; 111.07,29.03 v1(111.07,29.76) ; 111.07,29.03 111.1,29.03 ; 111.07,29.03 C801.1 ; v1(109.98,17.28) 109.75,17.52 C824.1 108.96,17.77 U75.24
  vias: v1(117.09,30.6) v1(117.09,29.71) v1(117.98,30.6)
VDD_1P0: length 7.2
  TOP w0.635: R152.2 v2(33.66,62.85) 33.02,63.49 32.44,63.49 C303.1 30.56,64.3 v2(30.35,64.51) FL14.1 ; R176.2 v2(33.78,53.84)
VDD_CORE_0V8: length 96.2
  TOP w0.305: v1(96.78,67.35) 97.18,67.75 U37.K17 ; U37.M15 98.78,69.35 v1(98.38,68.95) ; U37.U16 97.98,73.35 v1(97.58,73.75) ; U37.R18 96.38,71.75 v1(95.98,71.35) ; U37.L18 96.38,68.55 v1(95.98,68.15) ; U37.R16 97.98,71.75 v1(97.58,71.35) ; U37.K15 98.78,67.75 v1(98.38,67.35) ; v1(103.98,72.15) 103.58,72.55 U37.T9 ; U37.U18 v1(95.98,73.75) ; v1(99.18,73.75) 99.58,73.35 U37.U14 ; v1(98.38,72.15) 98.78,72.55 U37.T15 ; U37.P15 98.78,70.95 v1(98.38,70.55) ; U37.N18 96.38,70.15 v1(95.98,69.75) ; v1(97.58,68.15) 97.98,68.55 U37.L16 ; U37.V15 98.78,74.15 v1(98.38,74.55) ; U37.V17 v1(96.78,74.55) ; v1(94.38,74.55) 94.78,74.15 U37.V20 ; U37.N16 97.98,70.15 v1(97.58,69.75) ; v2(76.05,111.47) 76.05,111.39 76.33,111.11 U20.22 ; v1(99.18,75.35) 99.58,74.95 U37.W14 ; U37.P13 100.38,70.95 v1(100.78,70.55) ; U37.T17 97.18,72.55 v1(96.78,72.15) ; U37.L10 v1(103.18,68.15) ; U37.K13 v1(100.78,67.35) ; U37.R14 99.58,71.75 v1(99.98,71.35) ; U37.K9 v1(103.98,67.35) ; v1(94.38,71.35) 94.78,71.75 U37.R20 ; v1(96.78,70.55) 97.18,70.95 U37.P17 ; v1(94.66,88.19) C217.3 ; U37.J10 v1(103.18,66.55) ; U37.N14 v1(99.98,69.75) ; U37.K11 v1(102.38,67.35)
  TOP w0.508: v2(96.77,46.34) v2(96.77,45.46)
  L6-PWR w0.152: v1(94.38,71.35) 93.98,70.95 93.98,70.35 93.77,70.14 92.94,70.14 92.94,70.14 92.61,70.14 92.61,70.14 91.01,70.14 91.01,70.14 88.94,70.14 88.94,70.14 87,70.14 86.28,70.86 85.03,70.86 81.61,74.27 77.74,74.27 76.39,75.62 76.39,77.64 75.48,78.55 75.48,80.09 72.63,82.93 72.63,89.28 71.18,90.73 71.18,100.64 73.79,103.24 73.79,109.71 75.54,111.47 v2(76.05,111.47)
  BOTTOM w0.152: v1(103.98,72.15) 104,72.13 C672.1 104.11,72.13
  BOTTOM w0.203: C644.1 99.18,75.35 v1(99.18,75.35) ; C685.1 100.18,71.36 ; 100.18,71.36 v1(99.98,71.35) ; 100.18,71.36 100.18,71.95 v1(99.98,72.15)
  BOTTOM w0.254: v1(96.78,74.55) 97.11,74.21 97.23,74.21 97.31,74.13 97.33,74.13 97.39,74.08 97.42,74.08 97.43,74.07 97.43,73.89 v1(97.58,73.75)
  BOTTOM w0.305: v1(97.58,73.75) v1(98.38,74.55) 98.71,74.89 98.72,74.89 v1(99.18,75.35) ; v1(99.98,69.75) 99.98,69.61 ; 99.98,69.61 100.79,69.61 C707.1 ; 99.98,69.61 99.97,69.61 C708.1 ; v1(103.18,68.15) 103.85,67.48 C726.1 103.85,67.22 103.5,66.87 103.42,66.87 103.18,66.63 v1(103.18,66.55) 103.11,66.55 102.67,66.99 102.64,66.99 C727.1 ; v1(97.58,69.75) 97.47,69.75 97.15,70.07 97.15,70.11 96.78,70.47 C695.1 ; C686.1 97.53,71.36 97.16,71 97.16,70.95 97.11,70.9 97.11,70.88 v1(96.78,70.55) ; v1(95.98,73.75) v1(96.78,74.55) ; v1(96.78,67.35) 96.79,67.35 97.21,67.77 97.21,67.78 v1(97.58,68.15) 97.95,68.52 98.04,68.52 98.39,68.87 C710.1
  vias: v1(77.56,88.76) v1(77.56,85.59) v1(79.16,88.76) v1(79.16,85.59) v1(81.07,79.97) v1(81.15,77.97) v1(81.15,75.43) v1(81.2,72.25) v1(82.12,86.76) v1(82.12,85.59) v1(82.12,83.68) v1(82.12,81.78) v1(82.19,79.97) v1(82.16,77.97) v1(82.16,75.43) v1(82.2,72.25) v1(83.82,88.3) v1(85.09,88.3) v1(86.11,93.37) v1(86.11,91.77) v1(86.36,88.3) v1(87.63,88.3) v1(88.65,93.37) v1(88.65,91.77) v1(88.97,89.26) v1(88.97,88.21) v1(90.93,89.26) v1(90.93,88.26) v1(92.82,89.26) v1(92.85,88.25) v1(93.34,84.62) v1(94.59,89.29) v2(66.42,91.68) v2(67.44,91.68) v2(68.83,91.68) v2(69.85,91.68) v2(71.63,117.46) v2(71.63,116.32) v2(71.63,115.18) v2(71.63,97.65) v2(71.63,96.51) v2(71.63,95.37) v2(72.52,117.46) v2(72.52,116.32) v2(72.52,115.18) v2(72.52,97.65) v2(72.52,96.51) v2(72.52,95.37) v2(75.44,94.22) v2(75.44,93.21) v2(76.58,94.22) v2(76.58,93.21) v2(77.72,94.22) v2(77.72,93.21) v2(80.64,117.46) v2(80.64,116.32) v2(80.64,115.18) v2(80.64,97.65) v2(80.64,96.51) v2(80.64,95.37) v2(80.64,90.79) v2(81.53,117.46) v2(81.53,116.32) v2(81.53,115.18) v2(81.53,97.65) v2(81.53,96.51) v2(81.53,95.37) v2(81.66,90.79) v2(83.19,90.79) v2(84.2,90.79)
VDD_CORE_RAM_0V85: length 2.4
  TOP w0.305: v1(97.58,74.55) 97.98,74.15 U37.V16 ; U37.W19 v1(95.18,75.35) ; U37.L14 v1(99.98,68.15) ; v1(100.78,74.55) 100.38,74.15 U37.V13
  BOTTOM w0.152: v1(95.18,75.35) 95.24,75.29 C649.1
  vias: v2(72.64,78.35) v2(77.34,78.12)
VDD_CPU_AVS: length 78.9
  TOP w0.305: v1(103.18,69.74) 102.78,70.14 U37.N10 ; v1(100.78,72.14) 101.18,71.74 U37.R12 101.18,71.75 v1(101.58,72.14) ; v1(103.98,74.55) 103.58,74.15 U37.V9 ; v1(103.18,75.35) 102.78,74.95 U37.W10 ; v1(103.18,71.35) 102.78,71.75 U37.R10 102.78,71.74 v1(102.38,72.14) ; U37.U10 102.78,73.35 v1(103.18,73.75) ; U37.N10 v1(102.38,69.74) ; U37.N10 v1(102.38,70.55) 101.98,70.95 U37.P11 101.98,70.94 v1(102.38,71.34) ; v1(102.38,74.55) 101.98,74.15 U37.V11 ; v2(126.39,96.87) 126.47,96.87 126.75,97.15 U27.22
  L7-SIGNAL w0.152: v1(103.98,74.55) 104.39,74.13 104.39,73.92 104.39,73.91 104.39,73.59 104.39,73.58 104.39,73.45 104.94,72.9 112.53,72.9 118.39,78.76 128.3,78.76 133.06,83.51 133.06,88.57 134.75,90.26 134.75,91.81 134.29,92.27 134.29,93.06 133.88,93.46 128.05,93.46 127.38,94.13 127.38,96.51 127.03,96.87 v2(126.39,96.87)
  BOTTOM w0.254: C655.1 102.49,74.63 102.49,74.85 102.56,74.92 102.72,74.92 102.84,75.05 102.96,75.05 C642.1 103.5,75.08 103.5,74.87 103.71,74.67 103.92,74.67 C651.1 103.62,74.18 103.5,74.18 103.45,74.13 103.4,74.13 103.24,73.97 C665.1
  BOTTOM w0.305: C231.1 100.79,72.15 v1(100.78,72.14) 101.58,72.14 C668.1 ; C231.3 100.79,73.74 v1(100.78,73.75) v1(101.58,73.75) ; C699.1 102.38,69.74 v1(103.18,69.74) ; C692.1 102.41,71.31 v1(102.38,71.34) ; v1(102.38,73.75) 102.38,74.52 C655.1 ; v1(102.38,73.75) 102.23,73.89 101.88,73.89 101.7,73.71 C663.1 ; v1(102.38,73.75) v1(103.18,73.75) 103.18,73.56 103.35,73.39 C247.3 ; C247.1 102.64,72.4 v1(102.38,72.14) ; v1(102.38,71.34) 102.38,71.71 102.32,71.77 102.32,72.08 v1(102.38,72.14) ; v1(102.38,71.34) v1(102.38,70.55) v1(102.38,69.74) ; v1(102.38,72.14) 101.58,72.14 v1(101.58,72.14)
  vias: v1(107.37,88.3) v1(109.14,88.3) v1(109.6,86.09) v1(109.6,85.09) v1(111,88.3) v1(112.5,78.91) v1(112.78,88.15) v1(112.88,89.23) v1(113.5,78.91) v1(114.94,86.73) v1(114.94,84.57) v1(114.94,82.41) v1(118.96,82.41) v1(118.96,79.87) v1(119.34,86.86) v1(119.34,84.57) v1(120.56,82.41) v1(120.56,79.87) v1(120.94,86.86) v1(120.94,84.57) v2(118.75,103.88) v2(119.76,103.88) v2(120.4,102.35) v2(120.4,101.46) v2(120.4,93.33) v2(120.4,92.45) v2(121.16,103.88) v2(121.54,102.35) v2(121.54,101.46) v2(121.54,93.33) v2(121.54,92.45) v2(122.17,103.88) v2(122.68,102.35) v2(122.68,101.46) v2(122.68,93.33) v2(122.68,92.45) v2(124,83.2) v2(125.02,83.2) v2(126.49,83.23) v2(127.51,83.23)
VDD_CPU_RAM_0V85: length 1.1
  TOP w0.305: U37.L11 v1(102.38,68.15) ; U37.W12 101.18,74.95 v1(101.58,75.35)
  vias: v2(93.9,99.68)
VDD_DDR_1V1: length 85.2
  TOP w0.102: U40.F8 125.53,63.21 124.58,63.21 U40.F10 ; 123.19,69.71 123.93,69.71 U40.U10 124.58,69.71 126.19,69.71
  TOP w0.203: U40.H12 122.42,63.95 122.08,63.95 121.81,64.22 121.81,64.72 v1(122.23,65.14)
  TOP w0.229: 123.95,63.24 123.95,63.19 U40.F10 ; U27.50 136.27,97.65 v1(136.27,97.65)
  TOP w0.305: 105.18,69.35 U37.M7 105.18,69.35 ; 105.18,69.35 v1(105.58,68.95) ; 105.18,69.35 v1(104.78,69.75) U37.N8 ; v1(106.38,71.35) 105.98,71.75 ; 105.98,71.75 105.98,71.75 ; 105.98,71.75 U37.R6 105.98,71.75 ; v1(132.72,71.28) 132.67,71.33 U40.W1 ; U40.AB4 v1(129.05,73.82) ; v1(124.65,65.16) U40.K10 ; U40.N1 131.45,67.43 v1(131.86,67.11) ; U40.F5 v1(127.85,62.56) ; U40.W5 127.79,71.33 ; v1(131.86,65.81) U40.K1 ; 109.98,72.55 v1(110.38,72.15) ; 109.98,72.55 U37.T1 109.98,72.55 109.98,72.55 ; U40.U5 128.25,70.03 v1(127.85,69.71) ; U40.N12 122.65,66.69 v1(122.78,66.56) ; 122.43,61.33 122.65,61.56 U40.D12 122.65,61.61 122.43,61.84 ; U37.R8 104.38,71.75 v1(104.78,71.35) 105.18,70.95 U37.P7 105.18,70.95 v1(105.58,70.55) ; U37.A1 v1(110.38,60.14) ; 105.98,71.75 v1(105.58,72.15) 105.18,72.55 U37.T7 ; U40.F8 v1(126.25,62.56) ; U40.N10 124.25,67.43 v1(124.65,67.76) ; U40.R1 131.45,68.73 v1(131.86,68.41) ; U40.A9 125.06,59.63 125.06,59.64 125.45,59.96 v1(125.45,59.96) ; v1(129.46,67.76) 129.85,67.43 U40.N3 ; U40.R5 128.25,68.73 v1(127.85,69.06) ; U37.M9 v1(103.98,68.95) U37.L8 v1(104.78,68.15) U37.K7 v1(105.58,67.35) 105.98,66.95 ; U40.H5 v1(127.85,63.86) ; U37.G8 104.38,65.35 U37.G8 ; U37.G8 v1(104.78,64.95) ; U40.AA5 128.25,72.65 127.89,73.01 ; v1(129.46,65.16) U40.K3 ; 132.67,61.58 v1(132.72,61.54) ; U40.B8 126.14,60.57 ; U40.B5 128.24,60.28 127.89,59.93 ; v1(126.25,69.06) 125.85,68.73 U40.R8 ; U37.J8 104.38,66.95 v1(104.78,66.55) U37.H7 v1(105.58,65.75) ; U40.AA3 129.85,72.63 v1(130.26,72.31) ; U40.D5 127.76,61.58 ; v1(125.31,73.76) 125.31,73.54 125.05,73.28 U40.AB9 ; 105.98,66.95 U37.J6 105.98,66.95 ; 105.98,66.95 v1(106.38,66.55) ; v1(129.46,59.96) 129.05,59.63 U40.A4 ; U40.U3 129.85,70.03 v1(130.26,70.36) ; U40.H1 v1(131.86,64.51) ; U40.R12 122.65,68.73 v1(122.25,68.41) ; U40.K12 122.24,65.15 122.23,65.14 v1(122.23,65.14) ; U40.B3 v1(130.26,60.61) ; 131.7,61.33 131.45,61.57 U40.D1 131.45,61.59 131.7,61.84 ; U40.F3 v1(130.26,62.56) ; U40.AA10 123.87,73.01 ; v1(126.25,70.36) 125.85,70.03 U40.U8 ; U40.AA8 126.24,73.01 ; U40.W8 126.33,71.33 ; 123.83,59.93 124.17,60.28 U40.B10 ; 126.24,61.2 125.86,61.58 U40.D8 ; U40.H8 v1(126.25,63.86) ; U40.W12 122.08,71.33
  L4-SIGNAL w0.163: 105.94,60.35 105.94,60.34 105.98,60.31 105.98,59.98 105.9,59.9 105.89,59.76
  L7-SIGNAL w0.152: v1(136.27,97.65) 135.85,97.65 135.51,97.31 135.51,94.3 136.58,93.23 136.58,87.04 134.75,85.21 134.75,75.3 133.48,74.03 133.48,70.03 v1(131.86,68.41)
  BOTTOM w0.305: C734.1 132.84,67.05 v1(132.72,66.92) ; 129.41,59.17 129.41,59.91 v1(129.46,59.96) ; v1(125.45,59.96) 125.45,59.48 125.22,59.25 C770.1 ; v1(110.38,60.14) 110.92,60.68 C763.1 ; 129.16,74.54 129.16,73.93 v1(129.05,73.82) ; v1(122.23,65.14) 122.07,64.98 122.06,64.98 121.78,64.7 121.78,64.69 121.6,64.51 C758.1 ; C654.1 125.35,73.8 v1(125.31,73.76) ; v1(126.87,58) R374.1 R373.1
  vias: v1(112.9,58.03) v1(113.91,58.03) v1(114.05,54.97) v1(114.05,53.96) v1(115.49,70.6) v1(115.49,68.06) v1(115.49,61.71) v1(115.45,58.03) v1(115.95,54.97) v1(115.95,53.97) v1(116.46,58.03) v1(117.73,55.18) v1(117.73,53.25) v1(121.97,55.49) v1(123.52,76.06) v1(123.7,77.97) v1(124.13,55.49) v1(125.68,57.01) v1(126.16,55.49) v1(127.05,63.16) v1(128.19,55.49) v1(128.78,77.97) v1(130.25,57.01) v1(130.35,55.49) v1(131.37,66.33) v1(131.49,77.97) v1(131.65,76.06) v1(132.26,59.35) v1(132.92,58.28) v1(132.97,57.13) v1(132.97,56.12) v1(133.48,76.31) v1(133.48,75.3) v1(133.96,62.1) v1(134.37,71.05) v1(134.75,57.13) v1(134.75,56.12) v1(135,67) v1(135,63.82) v1(135,60.65) v1(135.71,69.42) v1(135.76,75.04) v1(135.76,74.03) v1(136.02,65.73) v1(136.53,63.19) v1(136.65,59.97) v1(136.65,58.37) v1(137.03,70.47) v2(140.21,102.35) v2(140.21,101.46) v2(141.35,102.35) v2(141.35,101.46) v2(142.49,102.35) v2(142.49,101.46)
VDD_DSI_OSC: length 6.3
  BOTTOM w0.229: 100.73,18.82 100.76,18.82 100.76,19.34 100.97,19.55 U76.4
  BOTTOM w0.305: U76.1 99.42,19.23 99.82,18.82 C817.2 100.73,18.82 ; 100.73,18.2 100.71,18.19
  BOTTOM w0.381: 100.71,18.19 100.46,17.93 FL40.3 ; 100.73,18.82 100.73,18.2
VDD_IO_1V8: length 24.4
  TOP w0.305: C115.1 81.98,107.05 81.86,107.17 v1(81.28,107.17) U20.9 ; U31.P3 v2(147.78,88.21) ; U37.Y7 105.18,75.75 v1(105.58,76.15) ; v1(105.58,77.75) 105.18,77.35 U37.AB7 104.79,76.95 v1(104.78,76.95) 104.38,76.55 U37.AA8 ; U31.L7 v2(150.79,83.21) ; C205.1 v1(105.05,90.13) ; U31.L4 v2(150.79,87.21) ; U31.H8 v2(154.79,82.2) ; U31.L2 v2(150.79,89.21) ; U31.P8 v2(147.78,82.2) ; U31.L9 v2(150.79,81.2) ; U31.H3 v2(154.79,88.21)
  BOTTOM w0.305: v2(150.79,81.2) 150.75,81.17 R329.1 R330.1 ; R313.2 150.46,87.21 v2(150.79,87.21) ; v2(154.79,82.2) 154.58,82.41 C608.1 ; v2(147.78,88.21) 147.83,88.17 R312.1 ; R314.1 v2(148.84,84.19) ; v2(150.79,83.21) 150.63,83.05 R325.1 ; R297.1 v2(152.78,88.25) R311.1 ; R324.1 152.65,84.06 v2(152.78,84.19) ; R318.1 145.92,83.73 146.23,83.43 v2(146.56,83.43) ; v2(147.78,82.2) 147.58,82.41 C609.1 ; R298.1 149.96,90.03 v2(150.79,89.21)
  vias: v1(102.11,90.03) v1(102.11,88.76) v1(105.05,88.76)
VDD_IO_3V3: length 178.5
  TOP w0.254: 43.04,37.71 43.04,38.42 v1(42.93,38.53)
  TOP w0.305: v2(39.35,83.45) 39.33,83.43 R118.1 R121.1 ; R126.1 v2(143,77.97) R131.1 ; v1(97.58,77.75) 97.98,77.35 U37.AB16 ; U2.23 v2(82.69,133.99) ; v1(105.58,74.55) 105.18,74.15 U37.V7 ; U39.6 21.48,66.78 C295.1 v2(20.7,66.79) ; U25.2 v2(45.29,101.51) ; U37.AB18 96.38,77.35 v1(95.98,77.75) ; U31.F3 v2(156.79,88.21) ; U31.F8 v2(156.79,82.2) ; U35.5 152.12,73.55 v2(152.15,73.52) ; R233.1 105.1,26.28 105.1,27.29 R228.1 105.63,27.29 v2(105.97,26.96) ; R29.1 v2(71.84,125.72) ; U2.22 v2(81.59,134.03) 81.79,133.83 C39.1 ; U1.4 v2(114.17,148.7) 114.17,148.71 C3.1 ; U37.AA19 v1(95.18,76.95) ; U37.AA21 v1(93.58,76.95) ; U37.V21 93.98,74.15 v1(93.58,74.55) ; U22.5 v2(48.66,98.29) ; U31.F6 v2(156.79,84.21) ; U31.F2 v2(156.79,89.21) ; R139.1 5.59,72.89 v2(5.59,72.51) ; U37.U20 94.78,73.35 v1(94.38,73.75) ; C45.1 v2(84.63,132.91) ; U37.AC20 94.78,78.15 v1(94.38,78.55) ; v2(90.17,25.52) 90.3,25.39 R234.1 ; U25.24 45.72,98.92 v2(45.97,98.67) ; RJ5.3 RJ4.3 v2(62.87,79.87) ; v2(76.18,131.53) 76.06,131.41 U10.5 75.55,130.65 75.45,130.55 C55.2 ; R211.1 R213.1 6.35,36.69 v2(6.48,36.82) ; U37.Y22 93.18,75.75 v1(92.78,76.15) ; U37.AC19 95.58,78.15 v1(95.18,78.55) ; R3.1 v2(78.49,149.6) ; R70.2 v2(187.83,107.81) ; R73.2 v2(59.44,105.4) ; v1(94.38,76.95) 94.78,76.55 U37.AA20 ; v2(64.98,131.53) 64.9,131.45 C51.1 ; R38.2 v2(108.08,125.26) ; U19.45 40.22,103.63 39.45,102.86 C144.1 ; RJ2.1 v2(152.34,123.81) ; U37.U22 93.18,73.35 v1(92.78,73.75) ; U32.22 v2(36.32,85.33) 36.89,85.33 C245.1 ; C88.1 v2(34.8,117.59) ; U39.3 v2(24.77,68.7) ; U37.AC17 97.18,78.15 v1(96.78,78.55) ; U37.W22 93.18,74.95 v1(92.78,75.35) ; v2(37.59,49.9) 37.59,50.41 37.21,50.79 FL16.1 36.83,50.42 v2(36.83,49.9) ; v1(96.78,76.95) 97.18,76.55 U37.AA17 ; R42.1 R41.1 v2(86.23,123.31) ; U31.F7 v2(156.79,83.21) ; U25.23 44.67,97.58 44.97,97.27 45.21,97.27 v2(45.21,97.21) ; R31.1 v2(75.95,125.72) ; R68.2 v2(36.2,108.83) ; v1(104.78,73.75) 104.38,73.35 U37.U8 ; U23.5 51.2,98.3 v2(51.18,98.29) ; U31.F4 v2(156.79,87.21) ; R36.2 v2(106.05,125.26) ; U19.42 38.25,106.1 38.06,106.29 C118.1 ; v2(68.2,79.87) RJ7.3 RJ6.3 ; v2(180.47,114.92) 180.28,114.73 U14.14 ; U31.F5 v2(156.79,86.21) ; U25.1 v2(45.97,100.45) ; R6.1 v2(63.37,143.88) ; v2(35.05,67.3) 35.05,66.78 FL13.2 34.67,66.41 34.29,66.79 v2(34.29,67.3) ; v2(130.18,128.51) 130.18,128.95 130.48,129.25 U7.9 ; R40.2 v2(143.89,122.67) ; U39.4 v2(22.73,68.7) ; R39.2 v2(143.89,123.69) ; U31.F9 v2(156.79,81.2) ; R240.2 v2(127.72,19.55)
  TOP w0.406: v2(95,115.94) 95.38,115.94 95.89,115.43 ; 95.89,115.43 FL5.2 ; 95.89,115.43 95.38,114.92 v2(95,114.92) ; v2(33.78,117.01) 33.78,117.52 C87.1 33.02,117.52 v2(33.02,117.01)
  TOP w0.508: 27.3,81.02 26.8,81.52 v2(26.29,81.52) ; 27.3,81.02 27.05,80.76 v2(26.29,80.76) ; 27.3,81.02 FL12.2 ; C59.1 88.65,131.18 v2(88.27,131.56) ; R250.1 v3(93.09,16.25) ; R164.1 v2(188.47,61.08)
  TOP w0.635: v2(38.23,100.07) C150.1 C146.1 C144.1 ; C118.1 C117.1 C116.1 v2(34.67,106.29)
  L4-SIGNAL w0.305: v2(143,77.97) v2(154.56,77.97)
  L5-SIGNAL w0.305: v2(152.15,73.52) 152.89,72.78 v2(154.54,72.78)
  L7-SIGNAL w0.305: v2(55.24,79.62) 59.82,79.62 60.45,80.25 62.48,80.25 v2(62.87,79.87) v2(68.2,79.87)
  L7-SIGNAL w0.508: v2(127.72,19.55) 127.72,18.93 127.51,18.71 127.51,16.75 128.52,15.74 128.52,11.93 130.3,10.15 130.3,9.39 131.94,7.75 132.04,7.75 132.4,7.39 132.4,6.89 132.33,6.82 v2(132.33,5.96)
  BOTTOM w0.254: v2(56.39,25.77) R429.1 R427.2 R426.2 ; v2(59.56,29.83) 59.63,29.9 U74.16
  BOTTOM w0.305: R448.1 v2(105.83,15.47) ; C820.1 102.98,18.91 ; 102.98,18.91 102.97,18.9 ; 102.98,18.91 103.58,19.52 U75.33 ; R379.2 R382.2 v2(17.65,55.36) ; R439.1 v2(91.57,20.56) ; R393.1 v2(150.37,51.04) ; C597.1 156.97,86.03 v2(156.79,86.21) ; v2(156.79,81.2) 156.97,81.02 C611.1 ; C816.1 115.19,19.52 ; 115.19,19.52 115.19,19.49 ; 115.19,19.52 U75.16 ; C562.2 48.64,98.3 v2(48.66,98.29) ; R397.1 v2(66.42,47.74) ; 116.33,19.56 116.33,20.06 v2(116.08,20.31) ; 44.58,101.46 45.24,101.46 v2(45.29,101.51) ; R288.1 v2(194.35,102.31) ; C566.2 45.72,98.92 v2(45.97,98.67) ; C498.1 130.43,128.77 v2(130.18,128.51) ; C596.1 36.32,85.33 v2(36.32,85.33) ; R395.1 v2(68.96,47.74) ; 196.47,96.76 v2(197.23,96.76) ; 130.94,131.18 v2(130.94,131.94) ; C525.1 180.47,113.91 v2(180.47,114.92) ; C660.2 v2(152.15,73.52) ; R282.1 v2(194.35,103.53) ; R396.1 v2(67.69,47.74) ; R464.2 v2(132.33,5.96) 132.33,6.48 132.46,6.61 R465.2 ; R398.1 v2(65.15,47.74) ; C796.1 v2(59.56,29.83) ; C793.1 v2(59.56,30.85) ; C561.2 v2(51.18,98.29) ; C567.2 v2(45.21,97.21) ; RJ20.3 v2(13.34,35.49) ; R296.1 v2(194.69,91.81)
  BOTTOM w0.381: 115.19,19.52 116.33,19.52 C815.1 116.33,19.56 ; v1(102.41,19.47) 102.97,18.9 ; C789.1 v1(42.93,38.53)
  BOTTOM w0.508: v2(88.27,131.56) 88.18,131.48 J20.2 ; J20.24 v2(76.18,131.53) ; R273.2 v2(115.44,119.12) ; J20.52 v2(64.98,131.53) ; J20.39 v2(70.18,120.42) ; R274.2 v2(113.67,119.12) ; J20.41 v2(69.38,120.42)
  vias: v1(95,86.6) v1(95,84.57) v1(95.88,17.26) v1(96.01,18.82) v1(96.39,86.6) v1(96.39,84.57) v1(96.82,96.91) v1(96.82,95.8) v1(96.81,94.37) v1(96.81,93.32) v1(97.41,18.82) v1(97.41,17.04) v1(97.79,86.65) v1(97.79,84.57) v1(98.81,97.18) v1(98.81,95.58) v1(98.79,94.39) v1(98.79,93.29) v1(99.17,89.82) v1(99.17,88.74) v1(99.19,86.52) v1(99.19,84.54) v1(100.71,86.52) v1(100.71,84.49) v1(102.11,86.52) v1(102.11,84.57) v1(103.5,86.6) v1(103.5,84.57) v1(104.9,86.6) v1(104.9,84.57) v1(106.3,86.6) v2(29.08,71.24) v2(29.84,71.87) v2(92.46,85.3) v2(94.61,122.29) v2(94.61,121.27) v2(95.63,121.27) v2(97.92,102.61) v2(97.92,101.59) v2(99.06,102.61) v2(99.06,101.59) v2(174.75,95.87) v2(175.64,95.87) v2(176.15,96.76) v2(176.53,95.87) v2(177.04,96.76)
VDD_MCU_0V85: length 117.5
  TOP w0.229: v1(136.18,97.02) 136.14,97.02 136.01,97.15 U27.49
  TOP w0.305: v1(95.18,70.55) 95.58,70.95 U37.P19 ; v1(94.38,69.75) 94.78,70.15 U37.N20 ; v1(95.18,68.95) 95.58,69.35 U37.M19 ; U37.M21 93.98,69.35 v1(93.58,68.95) ; v1(94.38,68.15) 94.78,68.55 U37.L20
  L6-PWR w0.152: v1(95.18,70.55) 95.22,70.55 95.63,70.96 95.81,70.96 95.81,70.96 96.14,70.96 96.14,70.96 96.61,70.96 96.61,70.96 96.93,70.96 97.18,70.7 97.18,68.77 97.41,68.54 97.74,68.54 97.92,68.37 97.92,68.36 97.97,68.31 97.97,67.98 97.97,67.18 97.97,65.58 97.74,65.35 97.72,65.35 97.71,65.34 97.41,65.34 97.34,65.27 97.34,65.27 97.18,65.12 97.18,63.89 97.34,63.74 97.74,63.74 97.97,63.51 97.97,59.37 98.42,58.92 98.42,51.68 100.84,49.27 104.14,49.27 107.31,52.44 121.67,52.44 122.81,53.58 134.62,53.58 141.48,60.44 141.48,77.71 138.5,80.7 138.5,90.1 v2(139.83,91.43)
  L7-SIGNAL w0.152: v1(136.18,97.02) 136.59,97.02 137.1,97.53 138.81,97.53 139.22,97.12 139.22,92.04 v2(139.83,91.43)
  vias: v1(86.74,56.33) v1(86.74,51.46) v1(86.74,49.86) v1(86.74,47.35) v1(86.74,46.34) v1(88.65,56.33) v1(90.55,56.33) v1(90.55,54.21) v1(90.55,53.2) v1(92.71,54.21) v1(92.71,53.2) v2(88.32,42.67) v2(140.21,93.33) v2(140.21,92.45) v2(141.35,93.33) v2(141.35,92.45) v2(142.49,93.33) v2(142.49,92.45)
VDD_MCU_RAM_0V85: length 5.2
  TOP w0.305: U37.T19 95.58,72.55 v1(95.18,72.15) ; v1(95.18,67.35) 95.58,67.75 U37.K19
  TOP w0.508: v2(89.49,46.47) 89.99,45.97 C363.1 89.84,44.41 FL19.2
VDD_MCUIO_1V8: length 25.2
  TOP w0.305: U37.H19 95.58,66.15 v1(95.18,65.75) ; R200.1 85.09,44.31 v2(84.58,43.8) R203.1 ; 76.07,45.96 76.07,45.99 v2(75.46,45.99) ; C136.1 129.49,103.42 129.49,103.04 129.69,102.83 v1(129.69,102.1) U27.11 ; v2(80.77,41.01) R206.1 R207.1 R208.1 ; v2(81.87,44.46) 82.45,44.46 C362.1 ; U45.5 v2(80.91,51.69) ; C366.1 v2(84.07,42.92) ; C365.1 78.74,43.33 v2(78.87,43.46) ; 76.07,44.59 76.07,44.62 v2(75.46,44.62) ; R205.1 v2(79.76,41.01) ; R195.2 82,46.09 82.51,46.6 R194.2 v2(83.69,46.85) ; U37.J20 94.78,66.95 v1(94.38,66.55) ; R188.2 v2(79.59,49.86) ; U37.H21 93.98,66.15 v1(93.58,65.75) ; R187.2 v2(76.87,49.86) ; R204.1 v2(77.75,41.01)
  BOTTOM w0.152: C747.1 95.34,65.49 95.34,65.58 v1(95.18,65.75) ; C773.1 94.51,58.26 94.36,58.11 v1(94.36,58.11)
  BOTTOM w0.305: U73.E4 v2(78.87,43.46) ; v2(80.91,51.69) 80.9,51.71 C782.1 81.36,52.35 81.58,52.58 81.58,53.66 81.37,53.88 R385.2 ; U73.D1 v2(81.87,44.46) ; U73.B4 v2(78.87,46.46)
  vias: v1(94.87,54.21) v1(94.87,53.2)
VDD_MCUIO_3V3: length 128.6
  TOP w0.229: U20.48 75.83,102.87 76.07,103.11 76.28,103.11 v1(76.33,103.16) ; v1(134.62,97.22) 134.62,96.89 134.86,96.65 U27.48
  TOP w0.254: v1(42.93,31.42) 43.04,31.31 U55.16
  TOP w0.305: R62.1 v2(125.73,112.68) R63.1 ; U37.L22 93.18,68.55 v1(92.78,68.15) ; U50.5 v2(27.69,53.46) ; RJ13.1 RJ12.1 v2(69.85,58.54) ; v1(93.58,67.35) 93.97,67.74 U37.K21 ; R158.1 v2(84.2,59.93) ; v1(92.78,66.55) 93.17,66.94 U37.J22 ; R463.2 v2(147.57,70.09) ; C839.2 v2(148.97,71.24) 148.91,71.18 U77.5 ; R155.1 v2(80.26,59.93) ; v2(137.92,88.76) 138.3,88.38 RJ3.1 ; v2(128.91,114.04) U13.8 v2(128.91,117.59) ; v2(68.58,54.98) RJ11.3 RJ10.3 RJ9.3 RJ8.3 ; R166.1 R163.1 v2(69.22,60.44) ; v1(92.78,68.95) 93.18,69.35 U37.M22 ; R221.1 v2(47.62,31.1) ; R210.2 v2(11.81,39.99) ; 57.02,54.09 v2(57.02,55.49)
  L5-SIGNAL w0.305: v2(27.69,53.46) 25.78,51.55 25.78,49.9 23.88,48 v2(23.88,45.33) v2(23.88,41.06) ; v2(63.88,42.15) 63.88,43.17 66.29,45.58 68.07,45.58 69.85,47.36 69.85,53.71 v2(68.58,54.98)
  L7-SIGNAL w0.305: v2(23.88,41.06) 18.97,41.06 18.03,40.12 16.25,40.12 15.36,39.23 12.57,39.23 v2(11.81,39.99) ; v2(27.69,53.46) 28.19,52.95 50.93,52.95 53.47,55.49 v2(57.02,55.49) 57.53,54.98 v2(68.58,54.98)
  BOTTOM w0.305: R410.1 v2(147.51,45.33) ; v2(27.69,53.46) 27.69,52.44 ; R412.1 v2(144.15,43.93) ; C781.1 v2(57.02,55.49) ; R421.2 v2(62.61,42.15) ; R284.2 v2(127.25,104.04) ; 23.88,46.09 v2(23.88,45.33) ; R422.2 v2(61.34,42.15) ; R424.1 v2(143.76,38.22) ; R423.2 v2(60.07,42.15) ; v2(141.86,43.93) 141.86,44.45 141.6,44.71 R414.1 R415.1 ; 128.91,116.7 v2(128.91,117.59) ; R420.2 v2(63.88,42.15)
  BOTTOM w0.381: C794.1 v1(42.93,31.42)
  vias: v1(81.15,70.22) v1(82.16,70.22) v2(60.2,94.73) v2(60.83,95.24)
VDD_PHYIO_1V8: length 38.5
  TOP w0.305: v1(105.58,75.35) 105.18,74.95 U37.W7 ; v1(132.08,92.45) 132.2,92.56 U27.37
  TOP w0.381: v1(108.43,100.19) FL8.1
  TOP w0.508: v2(101.6,46.34) v2(101.6,45.41)
  L7-SIGNAL w0.152: v1(132.08,92.45) 130.85,92.45 129.92,91.51 128.84,91.51 128.83,91.51 128.47,91.51 128.47,91.51 119.55,91.51 117.86,93.21 117.86,95.62 109.8,103.67 104.98,103.67 104.71,103.4 v1(104.71,101.72)
  vias: v1(104.78,101.06) v1(113.03,80.51) v2(130.94,89.02) v2(130.94,87.87) v2(130.94,86.73) v2(131.83,89.02) v2(131.83,87.87) v2(131.83,86.73) v2(139.83,82.79) v2(141.22,82.79)
VDD_PHYIO_1V8_REG_SW: length 1.6
  TOP w0.229: 130.69,91.81 U27.34
VDD_RAM_0V85: length 29.6
  TOP w0.305: v1(71.5,105.67) U20.37
  L6-PWR w0.152: v1(71.79,80.25) 71.79,81.62 71.91,81.74 71.91,82.07 71.79,82.19 71.79,86.18 71.25,86.73 71.25,89.65 70.48,90.41 70.48,103.49 70.88,103.89 70.88,105.04 v1(71.5,105.67)
  BOTTOM w0.305: 72.64,79.87 72.37,79.59 v1(71.75,79.59) ; 72.64,79.87 72.64,79.9 72.29,80.25 v1(71.79,80.25) ; 72.64,79.87 FL39.1
  vias: v2(65.91,106.92) v2(65.91,106.03) v2(67.06,106.92) v2(67.06,106.03) v2(68.2,106.92) v2(68.2,106.03) v2(95.12,103.24)
VDD_RAM_0V85_REG_SW: length 1.6
  TOP w0.229: 70.99,107.17 U20.34
VDD_SD_DV: length 9.4
  TOP w0.305: U20.13 v1(81.28,109.17) 82.03,109.17 C111.1 ; U37.T22 93.18,72.55 v1(92.78,72.15) ; U37.T20 94.78,72.55 v1(94.38,72.15)
  BOTTOM w0.305: v2(22.39,69.52) R351.1 v2(21.72,70.09) ; R321.1 v2(22.48,82.92) ; R345.1 v2(20.07,75.3) ; R320.1 v2(20.07,84.57) ; R336.1 v2(20.07,79.87) ; C667.1 94.49,72.26 v1(94.38,72.15) ; R339.1 v2(22.52,78.51) ; R346.1 v2(22.39,73.94)
  vias: v2(59.69,72.76) v2(60.71,72.76) v2(61.09,91.3) v2(61.72,90.67)
VDDA_0P8_CSIRX: length 9.2
  TOP w0.305: v1(101.58,66.55) 101.18,66.95 U37.J12 ; U37.H15 98.78,66.15 v1(98.38,65.75) ; v1(96.78,65.75) 97.18,66.15 U37.H17 ; v1(97.58,66.55) 97.98,66.95 U37.J16 ; U37.H13 v1(100.78,65.75) ; U37.G12 101.18,65.35 v1(101.58,64.95) ; v1(99.98,64.95) 99.58,65.35 U37.G14
  TOP w0.508: FL17.2 98.3,48.05 C355.1 98.5,49.09 98.81,49.39 v2(98.81,50.15) v2(98,50.15)
  BOTTOM w0.203: v1(96.78,65.75) 96.78,65.66 96.94,65.5 C748.1
VDDA_0P8_DLL_MMC0: length 5.3
  TOP w0.305: U37.Y9 103.58,75.75 v1(103.98,76.15) ; U37.W8 104.38,74.95 v1(104.78,75.35)
  TOP w0.508: FL10.2 C191.1 112.01,91.48 v2(112.32,91.18)
  L5-SIGNAL w0.305: v1(103.98,76.15) 104.32,75.81 v1(104.78,75.35)
VDDA_0P8_PLL_DDR: length 0.6
  TOP w0.305: U37.N9 v1(103.98,69.75)
  vias: v2(109.17,53.08)
VDDA_0P8_SERDES: length 5.8
  TOP w0.305: U37.AB14 99.58,77.35 v1(99.18,77.75) ; U37.Y11 101.98,75.75 v1(102.38,76.15) ; U37.AB15 98.78,77.35 v1(98.38,77.75) ; v1(98.38,76.95) 98.78,76.55 U37.AA15 ; U37.AA12 101.18,76.55 v1(101.58,76.95) ; v1(100.78,77.75) 100.38,77.35 U37.AB13 ; U37.AB12 101.18,77.35 v1(101.58,77.75) ; U37.Y14 99.58,75.75 v1(99.18,76.15) ; U37.Y16 97.98,75.75 v1(97.58,76.15) ; v1(100.78,76.15) 100.38,75.75 U37.Y13
  BOTTOM w0.152: C623.1 99.22,77.71 v1(99.18,77.75) ; v1(100.78,77.75) 100.78,77.75 C624.1
  vias: v2(94.11,91.6) v2(95.38,91.6)
VDDA_0P8_UFS: length 6.2
  TOP w0.305: U37.AB9 103.58,77.35 v1(103.98,77.75) ; v1(103.18,76.95) 102.78,76.55 U37.AA10
  TOP w0.508: FL9.2 C182.1 106.73,92.82 C194.1 107.24,91.76 107.57,91.43 v2(107.95,91.43)
VDDA_1P8_CSI_RX: length 6.5
  TOP w0.305: v1(99.98,66.55) 99.58,66.95 U37.J14 ; U37.G16 97.98,65.35 v1(97.58,64.95) ; U37.H11 101.98,66.15 v1(102.38,65.75)
  TOP w0.508: v2(102.82,50.84) v2(102.82,50.15) 103.33,49.65 C356.1 103.12,48.05 FL18.2
VDDA_1P8_SERDES: length 2.3
  TOP w0.305: U37.AC12 101.18,78.15 v1(101.58,78.55) ; U37.AC11 101.98,78.15 v1(102.38,78.55) ; v1(99.18,78.55) 99.58,78.15 U37.AC14 ; U37.AC15 v1(98.38,78.54)
  vias: v2(101.98,97.4) v2(102.62,96.64)
VDDA_1P8_UFS: length 5.2
  TOP w0.305: v1(104.78,78.55) 104.38,78.15 U37.AC8 ; v1(103.98,78.55) 103.58,78.15 U37.AC9
  TOP w0.508: v2(107.24,96.38) 106.73,96.89 C162.1 106.73,99.23 106.93,99.43 FL8.2
VDDA_LM5141: length 8.5
  TOP w0.203: U33.2 194.04,87.03 v2(194.31,87.3) 194.65,87.64 194.65,87.7 C224.1
  BOTTOM w0.305: R308.2 194.88,87.87 v2(194.31,87.3) 193.55,88.06 193.55,88.89 193.29,89.14 R299.2 R300.2
VDDA_TC811: length 22.3
  TOP w0.254: v2(36.83,59.93) 36.93,60.04 U42.11
  TOP w0.305: v2(35.05,64) 35.05,64.51 34.67,64.89 FL13.1 34.29,64.52 v2(34.29,64) ; v2(37.47,63.62) 37.47,64.18 C301.1 36.7,64.18 v2(36.7,63.6) ; R178.1 v2(42.16,52.06) ; R178.1 R177.1 ; R178.1 R179.1 ; v2(43.18,63.62) 45.09,61.71 R154.1
  L5-SIGNAL w0.305: v2(43.18,63.62) 42.66,63.62 41.9,62.85 38.23,62.85 v2(37.47,63.62)
  BOTTOM w0.305: R357.2 C750.1 37.72,63.87 v2(37.47,63.62) ; C751.1 36.45,63.86 v2(36.7,63.6) ; 37.72,59.3 37.47,59.3 v2(36.83,59.93)
VDDHS11_DSI: length 10.7
  TOP w0.305: C429.1 v1(114.07,21.52) ; 111.12,18.71 C434.1 111.12,18.15 110.87,17.9 v1(110.49,17.9) ; C432.1 v1(107.16,19.61) ; C433.1 v1(108.28,19.61)
  TOP w0.381: 111.12,18.71 112.24,18.71 C435.1
  BOTTOM w0.305: v1(110.49,17.9) 110.46,17.92 U75.21 ; U75.25 108.46,19.43 v1(108.28,19.61) ; v1(113.92,29) 113.28,29 C799.1 113.28,28.22 112.83,27.77 U75.64 ; v1(107.16,19.61) 106.96,19.41 U75.28 ; U75.12 v1(114.07,21.52)
  vias: v1(113.92,28.31)
VDDI_MMC2: length 2.7
  TOP w0.305: U31.E4 v2(157.79,87.21)
  BOTTOM w0.305: C594.1 158.4,86.6 v2(157.79,87.21) 157.86,87.28 C581.1
VDDIO_TC811: length 7.4
  TOP w0.305: v2(39.88,54.6) 39.88,54.65 40.26,55.03 40.26,55.63 U42.22 ; v2(39.88,53.6) 39.88,53.03 C345.1 39.12,53.03 v2(39.12,53.58) ; R165.2 v2(47.5,59.55)
  BOTTOM w0.254: C779.1 40.26,55.11 39.88,54.73 v2(39.88,54.6)
  BOTTOM w0.305: C784.1 38.86,53.33 v2(39.12,53.58) 39.12,53.6 ; C783.1 40.13,53.34 v2(39.88,53.6)
VDDL11_DSI: length 25.1
  TOP w0.229: v1(102.36,26.31) 102.84,25.83 102.84,25.59 103.33,25.11 C405.1
  TOP w0.305: FL25.2 116.83,23.09 v1(116.76,23.02) 115.91,23.87 115.57,23.87 114.05,25.39 105.28,25.39 104.68,24.79 C405.1
  BOTTOM w0.305: U75.9 114.86,23.02 ; 114.86,23.02 116,23.02 ; 114.86,23.02 C807.1 ; 116,23.02 C806.1 ; 116,23.02 v1(116.76,23.02) ; U75.42 103.23,24.02 102.87,24.37 C804.1 102.86,24.79 102.86,25.56 102.36,26.06 v1(102.36,26.31)
VDDP11_DSI: length 7.1
  BOTTOM w0.305: v1(102.87,29.25) 102.88,29.23 C798.1 104.17,29.23 104.18,29.24 C797.1 104.92,29.24 105.46,28.69 U75.50 ; C826.1 114.05,17.75 113.74,18.06 113.22,18.06 113.12,18.16 112.8,18.16 112.46,18.5 U75.17
  BOTTOM w0.381: C826.1 114.05,17.28 v1(114.77,17.28)
  vias: v1(117.73,17.52)
VINT_LEOA_1V8: length 85.4
  TOP w0.305: C140.1 v2(135.51,102.61) 134.73,102.61 134.2,102.07 U27.2
  L5-SIGNAL w0.305: v2(135.51,102.61) 135.51,103.49 134.75,104.26 134.75,105.02 134.11,105.65 133.48,105.65 132.97,106.16 132.97,116.96 129.29,120.64 123.32,120.64 v2(122.17,121.78) ; v2(84.45,112.89) v2(93.09,112.89)
  BOTTOM w0.305: R277.1 v2(84.45,112.89) ; v2(93.09,112.89) 93.85,113.65 93.85,125.08 96.39,127.62 99.31,127.62 99.95,126.99 105.13,126.99 105.64,126.48 108.97,126.48 111.63,123.81 120.14,123.81 v2(122.17,121.78)
VINT_LEOB_1V8: length 2.6
  TOP w0.305: U20.2 81.39,103.67 82.61,102.44 C145.1
A2B_GPIO_INTR_43: length 123.8
  TOP w0.229: v1(90.38,81.75) 90.78,81.35 U37.AG25
  L5-SIGNAL w0.163: v1(8.77,36.17) 8.38,36.57 8.38,62.04 7.62,62.8 7.62,64.61 8.89,65.88 10.26,65.88 14.48,70.09 v1(15.88,70.09)
  L7-SIGNAL w0.107: v1(90.38,81.75) 89.97,82.16 85.47,82.16 84.84,82.79 54.36,82.79 54.23,82.67 40.39,82.67 38.86,81.14 32.51,81.14 30.23,78.86 26.29,78.86 23.37,75.94 19.43,75.94 18.03,74.54 18.03,71.49 16.64,70.09 v1(15.88,70.09)
  BOTTOM w0.191: J21.43 v1(8.77,36.17)
A2B_GPIO_INTR_77: length 126.7
  TOP w0.191: R215.2 v1(6.48,35.68)
  TOP w0.229: U37.AJ25 90.78,82.95 v1(90.38,83.35)
  L5-SIGNAL w0.163: v1(6.48,35.68) 7.62,36.82 7.62,62.02 6.93,62.7 6.93,64.84 8.62,66.52 9.63,66.52 14.86,71.74 v1(16.51,71.74)
  L7-SIGNAL w0.107: v1(16.51,71.74) 16.51,76.44 18.54,78.48 19.94,78.48 21.08,79.62 29.97,79.62 32,81.65 38.61,81.65 41.66,84.7 79.63,84.7 80.01,85.08 88.9,85.08 90.38,83.6 v1(90.38,83.35)
A2B_GPIO_OUT_57: length 144.6
  TOP w0.191: R222.2 R225.2 v1(11.81,28.82)
  TOP w0.229: v1(93.58,82.55) 93.98,82.15 U37.AH21
  L5-SIGNAL w0.163: v1(11.81,28.82) 10.92,29.71 10.92,66.03 14.48,69.59 16.38,69.59 18.67,71.87 18.67,86.6 21.46,89.4 43.43,89.4 46.35,86.48 79.5,86.48 79.88,86.1 89.92,86.1 91.82,84.19 92.5,84.19 93.58,83.11 v1(93.58,82.55)
A2B_GPIO_OUT_74: length 129.1
  TOP w0.229: v1(90.38,82.55) 90.78,82.15 U37.AH25
  L5-SIGNAL w0.163: v1(16.51,70.86) 14.61,70.86 9.91,66.16 8.76,66.16 7.21,64.6 7.21,62.82 8,62.03 8,35.55 v1(6.48,34.03)
  L7-SIGNAL w0.107: v1(16.51,70.86) 17.14,71.49 17.14,76.19 19.05,78.09 20.07,78.09 21.21,79.24 30.1,79.24 32.26,81.4 38.73,81.4 41.78,84.44 80.51,84.44 80.78,84.71 80.79,84.71 80.91,84.82 88.78,84.82 89.95,83.65 89.95,83.2 89.94,83.19 89.94,82.98 v1(90.38,82.55)
  BOTTOM w0.191: v1(6.48,34.03) 6.23,33.78 J21.74
A2B_MCU_SCL: length 87.9
  TOP w0.229: U37.G27 89.18,65.35 v1(88.78,64.95)
  L7-SIGNAL w0.107: v1(11.81,47.74) 11.81,49.52 13.59,51.3 15.24,51.3 18.98,55.04 34.36,55.04 34.58,54.81 37.81,54.81 39.24,56.25 42.16,56.25 42.85,56.93 45.67,56.93 46.23,56.38 48.39,56.38 49.4,57.39 58.93,57.39 61.47,59.94 71.41,59.94 71.41,59.93 73.79,59.93 76.96,63.11 80.77,63.11 81.63,63.96 83.66,63.96 85.01,65.32 88.4,65.32 v1(88.78,64.95)
  BOTTOM w0.191: J21.24 11.64,47.57 v1(11.81,47.74)
A2B_MCU_SDA: length 86.4
  TOP w0.229: v1(87.98,64.95) 88.38,65.35 U37.G28
  L7-SIGNAL w0.107: v1(87.98,64.95) 87.59,64.56 86.4,64.56 85.59,63.74 81.92,63.74 80.9,62.73 77.22,62.73 73.53,59.04 63.5,59.04 61.44,56.98 49.64,56.98 48.68,56.03 44.44,56.03 43.93,56.54 42.94,56.54 42.3,55.9 39.38,55.9 37.98,54.5 34.41,54.5 34.18,54.73 19.81,54.73 14.35,49.27 13.55,49.27 13.55,49.27 13.46,49.27 12.57,48.38 12.57,47.74 v1(11.81,46.98)
  BOTTOM w0.191: J21.25 11.8,46.97 v1(11.81,46.98)
A2B_MCU_SPI_CLK: length 109.2
  TOP w0.191: RJ8.2 v1(64.01,56.76)
  TOP w0.229: v1(88.78,63.35) 88.78,63.35 U37.E27
  L2-SIGNAL w0.107: v1(64.01,56.76) 65.38,55.39 70.58,55.39 70.74,55.23 74.3,55.23 81.66,62.6 84.2,62.6 85.34,63.74 88.38,63.74 v1(88.78,63.35)
  L4-SIGNAL w0.163: v1(53.72,26.53) 53.72,30.6 63.12,39.99 63.12,45.71 63.25,45.84 63.25,53.84 64.01,54.6 v1(64.01,56.76)
  L7-SIGNAL w0.107: v1(11.81,26.79) 12.21,26.79 12.46,26.53 16.26,26.53 16.76,27.04 17.78,27.04 18.67,26.15 43.43,26.15 43.69,25.9 53.09,25.9 v1(53.72,26.53)
  BOTTOM w0.191: v1(11.81,26.79) 11.61,26.58 J21.59
A2B_MCU_SPI_CS0: length 113.9
  TOP w0.229: U37.E25 90.78,63.75 v1(90.38,63.35)
  L2-SIGNAL w0.107: v1(90.38,63.35) 90.01,62.98 90.01,62.44 89.69,62.12 89.42,62.12 89.2,61.9 89.2,61.13 88.39,60.31 88.39,59.81 87.76,59.17 82.17,59.17 81.92,59.43 81.28,59.43 79.88,58.03 78.74,58.03 72.26,51.55 v1(59.56,51.55)
  L4-SIGNAL w0.163: v1(52.96,27.68) 52.96,30.47 58.17,35.68 58.17,50.15 v1(59.56,51.55)
  L7-SIGNAL w0.107: v1(7.37,27.17) 8.26,27.17 9.02,26.41 10.41,26.41 11.3,27.29 14.61,27.29 15.11,27.8 17.53,27.8 18.67,26.66 35.94,26.66 36.45,27.17 46.35,27.17 46.86,27.68 v1(52.96,27.68)
  BOTTOM w0.191: J21.62 6.78,26.58 v1(7.37,27.17)
A2B_MCU_SPI_D0: length 111.9
  TOP w0.191: RJ9.2 65.53,56.25 v1(65.41,56.25)
  TOP w0.229: U37.E24 91.58,63.75 v1(91.18,63.35)
  L2-SIGNAL w0.107: v1(65.41,56.25) 65.92,55.74 70.74,55.74 70.99,55.49 73.91,55.49 81.41,62.98 84.07,62.98 85.67,64.57 90.48,64.57 90.8,64.25 90.8,63.72 v1(91.18,63.35)
  L4-SIGNAL w0.163: v1(54.36,25.9) 54.36,30.6 63.44,39.68 63.44,44.51 64.52,45.58 64.52,53.84 65.41,54.73 v1(65.41,56.25)
  L7-SIGNAL w0.107: v1(11.77,25.98) 16.3,25.98 17.27,25.01 28.57,25.01 28.83,24.75 34.04,24.75 34.54,25.26 41.29,25.26 41.37,25.18 41.71,25.18 41.79,25.26 42.79,25.26 42.87,25.18 43.21,25.18 43.29,25.26 44.45,25.26 44.58,25.39 53.85,25.39 v1(54.36,25.9)
  BOTTOM w0.191: J21.60 v1(11.77,25.98)
A2B_MCU_SPI_D1: length 117.1
  TOP w0.191: v1(66.67,56.25) 66.8,56.25 RJ10.2
  TOP w0.229: U37.E28 88.38,63.75 v1(87.98,63.35)
  L4-SIGNAL w0.163: v1(66.67,56.25) 67.06,55.87 67.06,45.58 65.79,44.31 65.79,39.87 64.64,38.72 63.12,38.72 55.24,30.85 v1(55.24,24.75)
  L7-SIGNAL w0.107: v1(87.98,63.35) 87.75,63.12 87.74,63.12 87.59,62.97 86.35,62.97 85.98,62.6 82.04,62.6 81.28,61.84 78.23,61.84 73.66,57.27 67.69,57.27 v1(66.67,56.25) ; v1(55.24,24.75) 54.85,24.75 54.72,24.88 34.92,24.88 34.42,24.37 24.64,24.37 24.13,23.87 22.86,23.87 22.1,24.63 17.02,24.63 16.26,25.39 10.54,25.39 9.95,25.98 v1(3.9,25.98)
  BOTTOM w0.191: J21.61 v1(3.9,25.98)
A2B_SCL1: length 124.4
  TOP w0.191: R213.2 4.06,36.69 v1(3.98,36.77)
  TOP w0.229: v1(87.98,72.15) 88.38,72.55 U37.T28
  L2-SIGNAL w0.107: v1(48.26,38.72) 48.26,44.31 51.31,47.36 51.31,70.22 50.8,70.73 v1(50.8,72.13)
  L7-SIGNAL w0.107: v1(3.98,36.77) 4.74,36.77 5.46,36.06 6.32,36.06 6.32,36.06 6.64,36.06 6.64,36.06 7.69,36.06 8.83,34.91 12.32,34.91 12.6,34.63 15.09,34.63 15.49,35.04 32.26,35.04 35.56,38.34 38.23,38.34 38.99,39.11 47.88,39.11 v1(48.26,38.72) ; v1(50.8,72.13) 53.85,75.17 74.42,75.17 75.55,74.04 82.7,74.04 83.97,72.77 87.35,72.77 v1(87.98,72.15)
  BOTTOM w0.191: J21.79 v1(3.98,36.77)
A2B_SDA1: length 123
  TOP w0.191: v1(3.94,37.58) R211.2
  TOP w0.229: U37.T29 87.58,72.55 v1(87.18,72.15)
  L2-SIGNAL w0.107: v1(51.56,72.13) 51.56,70.86 51.69,70.73 51.69,46.98 48.9,44.19 v1(48.9,39.11)
  L7-SIGNAL w0.107: v1(51.56,72.13) 53.47,74.03 70.99,74.03 71.88,74.92 74.17,74.92 75.31,73.78 82.55,73.78 83.77,72.55 86.77,72.55 v1(87.18,72.15) ; v1(3.94,37.58) 4.83,37.58 6.1,36.31 8,36.31 9.02,35.3 12.45,35.3 12.8,34.94 13.74,34.94 14.23,35.43 14.51,35.43 14.54,35.45 14.88,35.45 14.9,35.43 18.1,35.43 18.73,36.06 32.77,36.06 35.43,38.72 38.1,38.72 38.73,39.36 48.64,39.36 v1(48.9,39.11)
  BOTTOM w0.191: J21.80 4.15,37.37 v1(3.94,37.58)
A2B_SPI1_CLK: length 105.2
  TOP w0.191: R134.2 v1(68.07,76.06)
  L4-SIGNAL w0.163: v1(36.35,39.23) 36.35,61.05 36.07,61.33 36.07,63.87 36.58,64.38 36.58,65.39 37.97,66.79 v1(37.97,75.55)
  L5-SIGNAL w0.163: v1(68.07,76.06) 67.56,75.55 v1(37.97,75.55)
  L7-SIGNAL w0.107: v1(3.96,38.57) 4.36,38.57 5.6,37.33 8.26,37.33 9.69,35.9 13.62,35.9 13.84,35.68 17.38,35.68 17.41,35.65 17.75,35.65 18.54,36.44 19.43,36.44 20.07,37.07 20.83,37.07 21.58,36.32 32.4,36.32 35.31,39.23 v1(36.35,39.23)
  BOTTOM w0.191: J21.82 v1(3.96,38.57)
A2B_SPI1_CS0: length 128
  TOP w0.229: U37.W27 89.18,74.95 v1(88.78,75.35)
  L2-SIGNAL w0.107: v1(53.21,77.84) 53.21,45.46 50.55,42.79 v1(50.55,40.25)
  L7-SIGNAL w0.107: v1(3.43,40.37) 5.97,40.37 8.35,37.99 8.74,37.99 9.91,36.82 16.76,36.82 17.78,37.84 20.74,37.84 21.25,38.34 33.02,38.34 35.05,40.38 50.02,40.38 50.15,40.25 v1(50.55,40.25) ; v1(53.21,77.84) 53.61,77.44 67.42,77.44 67.69,77.71 70.87,77.71 71.75,76.82 78.72,76.82 78.78,76.76 82,76.76 82.07,76.82 83.82,76.82 84.92,75.72 88.39,75.72 88.76,75.35 v1(88.78,75.35)
  BOTTOM w0.191: J21.85 v1(3.43,40.37)
A2B_SPI1_D0: length 130.9
  TOP w0.229: U37.V25 v1(90.38,74.55)
  L2-SIGNAL w0.107: v1(49.53,39.61) 49.53,44.19 52.07,46.73 52.07,76.57 v1(51.44,77.21)
  L7-SIGNAL w0.107: v1(3.5,39.17) 6.16,39.17 7.78,37.55 8.54,37.55 9.91,36.18 17.02,36.18 17.49,36.66 19.14,36.66 19.78,37.29 20.92,37.29 21.67,36.55 32.24,36.55 35.43,39.74 49,39.74 49.13,39.61 v1(49.53,39.61) ; v1(90.38,74.55) 90,74.92 85.09,74.92 83.44,76.57 82.13,76.57 82.1,76.54 78.69,76.54 78.62,76.6 71.66,76.6 70.81,77.46 67.94,77.46 67.69,77.21 v1(51.44,77.21)
  BOTTOM w0.191: J21.83 v1(3.5,39.17)
A2B_SPI1_D1: length 135.1
  TOP w0.229: v1(91.18,75.35) 91.58,74.95 U37.W24
  L2-SIGNAL w0.107: v1(51.05,39.74) 51.05,42.79 53.47,45.2 53.47,49.9 54.36,50.79 54.36,77.46 53.21,78.6 v1(53.21,80.51)
  L5-SIGNAL w0.163: v1(91.18,75.35) 91.18,76.07 89.9,77.35 84.69,77.35 83.21,78.83 62.51,78.83 61.09,80.25 53.47,80.25 v1(53.21,80.51)
  L7-SIGNAL w0.107: v1(51.05,39.74) 50.16,39.74 49.78,40.12 35.31,40.12 33.02,37.84 21.72,37.84 21.46,37.58 19.56,37.58 18.86,36.88 17.33,36.88 16.89,36.44 9.96,36.44 8.63,37.77 8.07,37.77 6.07,39.77 v1(3.97,39.77)
  BOTTOM w0.191: J21.84 v1(3.97,39.77)
A2B_SPORT0_CLK: length 109.2
  TOP w0.191: R109.2 v1(63.37,88)
  L5-SIGNAL w0.163: v1(3.99,41.57) 4.57,42.15 4.57,65.27 3.3,66.54 3.3,71.24 5.59,73.52 16.13,73.52 18.29,75.68 18.29,87.11 20.95,89.78 24.13,89.78 25.15,90.79 43.05,90.79 46.86,86.98 60.83,86.98 61.85,88 v1(63.37,88)
  BOTTOM w0.191: J21.87 v1(3.99,41.57)
A2B_SPORT0_D0: length 139.5
  TOP w0.191: R209.1 v1(56.52,41.26)
  TOP w0.229: v1(94.38,79.35) 94.78,78.95 U37.AD20
  L2-SIGNAL w0.107: v1(56.52,41.26) 55.75,42.03 55.75,77.84 56.9,78.98 v1(56.9,80.67)
  L5-SIGNAL w0.163: v1(56.9,80.67) 62.77,80.67 63.5,81.4 70.87,81.4 70.96,81.49 80.55,81.49 80.68,81.37 84.1,81.37 86.52,78.95 93.98,78.95 v1(94.38,79.35)
  L7-SIGNAL w0.107: v1(3.32,42.17) 4.55,42.17 8.26,38.47 9.91,38.47 11.18,37.2 16.76,37.2 17.65,38.09 19.18,38.09 19.94,38.85 33.02,38.85 34.8,40.63 51.18,40.63 51.82,41.26 v1(56.52,41.26)
  BOTTOM w0.191: J21.88 v1(3.32,42.17)
A2B_SPORT0_D1: length 127.8
  TOP w0.229: U37.AE20 v1(94.38,80.15)
  L2-SIGNAL w0.107: v1(51.82,45.33) 52.45,45.96 52.45,76.7 51.94,77.21 v1(51.94,83.68)
  L5-SIGNAL w0.163: v1(51.94,83.68) 52.45,84.19 87.12,84.19 89.16,82.15 92.37,82.15 v1(94.38,80.15)
  L7-SIGNAL w0.107: v1(51.82,45.33) 51.41,45.74 23.71,45.74 23.68,45.71 20.83,45.71 16.48,41.36 13.95,41.36 v1(11.94,43.37)
  BOTTOM w0.191: J21.31 v1(11.94,43.37)
A2B_SPORT0_FS: length 111.6
  TOP w0.191: R120.2 v1(68.96,83.3)
  L2-SIGNAL w0.107: v1(54.23,83.3) 54.23,78.86 54.99,78.09 54.99,50.28 54.23,49.52 54.23,44.31 v1(52.2,42.28)
  L5-SIGNAL w0.163: v1(68.96,83.3) v1(54.23,83.3)
  L7-SIGNAL w0.107: v1(3.95,42.77) 5.48,42.77 9.53,38.72 10.29,38.72 11.56,37.45 16.64,37.45 17.53,38.34 18.92,38.34 19.68,39.11 32.77,39.11 34.67,41.01 50.93,41.01 v1(52.2,42.28)
  BOTTOM w0.191: J21.89 v1(3.95,42.77)
A2B_SPORT1_CLK: length 132.6
  TOP w0.229: v1(91.18,82.55) 91.58,82.15 U37.AH24
  L5-SIGNAL w0.163: v1(18.03,69.71) 19.18,70.86 19.18,86.35 21.72,88.89 29.21,88.89 31.62,86.48 36.32,86.48 36.96,87.11 43.31,87.11 44.83,85.59 62.23,85.59 62.99,84.83 75.69,84.83 76,84.52 80.08,84.52 80.26,84.7 89.81,84.7 90.77,83.74 90.77,82.95 v1(91.18,82.55)
  L7-SIGNAL w0.107: v1(18.03,69.71) 17.14,68.82 13.46,68.82 10.03,65.39 6.73,65.39 3.05,61.71 3.05,54.85 2.29,54.09 2.29,45.59 v1(3.31,44.57)
  BOTTOM w0.191: J21.92 v1(3.31,44.57)
A2B_SPORT1_D0: length 133.9
  TOP w0.229: v1(91.98,79.35) 92.38,78.95 U37.AD23
  L2-SIGNAL w0.107: v1(50.04,41.9) 50.04,42.79 52.83,45.58 52.83,76.95 52.32,77.46 52.32,81.14 v1(53.09,81.9)
  L5-SIGNAL w0.163: v1(53.09,81.9) 53.57,82.39 83.72,82.39 86.36,79.75 91.58,79.75 v1(91.98,79.35)
  L7-SIGNAL w0.107: v1(50.04,41.9) 27.94,41.9 25.65,39.61 19.3,39.61 18.54,38.85 16.26,38.85 15.49,38.09 12.06,38.09 10.79,39.36 9.78,39.36 5.17,43.97 v1(3.98,43.97)
  BOTTOM w0.191: J21.91 v1(3.98,43.97)
A2B_SPORT1_FS: length 137.7
  TOP w0.229: U37.AE23 92.38,79.75 v1(91.98,80.15)
  L2-SIGNAL w0.107: v1(52.96,83.05) 53.72,82.29 53.72,78.6 54.61,77.71 54.61,50.54 53.85,49.77 53.85,44.82 v1(51.69,42.66)
  L5-SIGNAL w0.163: v1(91.98,80.15) 91.58,80.55 86.19,80.55 83.99,82.75 53.26,82.75 v1(52.96,83.05)
  L7-SIGNAL w0.107: v1(3.35,43.37) 5.26,43.37 9.65,38.98 10.54,38.98 11.81,37.71 16.51,37.71 17.27,38.47 17.34,38.47 17.43,38.56 18.64,38.56 19.43,39.36 32.51,39.36 34.54,41.39 50.42,41.39 v1(51.69,42.66)
  BOTTOM w0.191: J21.90 v1(3.35,43.37)
A2B_WKUP_GPIO_0: length 114.5
  TOP w0.191: SW2.1 v1(60.07,40.12)
  TOP w0.229: U37.F26 89.98,64.55 v1(89.58,64.15)
  L2-SIGNAL w0.107: v1(60.2,52.32) 60.2,53.2 60.96,53.96 73.53,53.96 81.79,62.22 84.33,62.22 85.02,62.92 88.96,62.92 89.58,63.53 v1(89.58,64.15)
  L4-SIGNAL w0.163: v1(60.07,40.12) SW2.1 59.56,41.65 59.56,50.54 60.2,51.17 v1(60.2,52.32)
  L7-SIGNAL w0.107: v1(60.07,40.12) 59.31,40.12 54.99,44.44 21.21,44.44 17.91,41.14 12.32,41.14 5.88,47.57 v1(3.34,47.57)
  BOTTOM w0.191: R423.1 v1(60.07,40.12) ; J21.97 v1(3.34,47.57)
A2B_WKUP_GPIO_1: length 115.6
  TOP w0.191: 61.34,41.14 v1(61.34,40.12)
  TOP w0.229: U37.F25 90.38,64.15 v1(90.38,64.15)
  L2-SIGNAL w0.107: v1(90.38,64.15) 89.97,63.74 89.97,63.45 89.43,62.92 89.42,62.92 89.2,62.7 89.2,62.4 88.93,62.12 88.62,62.12 88.39,61.89 88.39,60.7 88.21,60.52 87.32,60.52 86.23,59.43 82.42,59.43 82.17,59.68 81.03,59.68 79.78,58.43 78.63,58.43 73.79,53.58 62.61,53.58 v1(61.47,52.44)
  L4-SIGNAL w0.163: v1(61.47,52.44) 61.47,51.17 60.64,50.35 60.64,41.58 61.34,40.88 v1(61.34,40.12)
  L7-SIGNAL w0.107: v1(61.34,40.12) 60.96,39.74 59.18,39.74 54.86,44.06 21.34,44.06 17.91,40.63 16,40.63 15.11,39.74 13.08,39.74 5.85,46.97 v1(3.94,46.97)
  BOTTOM w0.191: J21.96 v1(3.94,46.97) ; R422.1 v1(61.34,40.12)
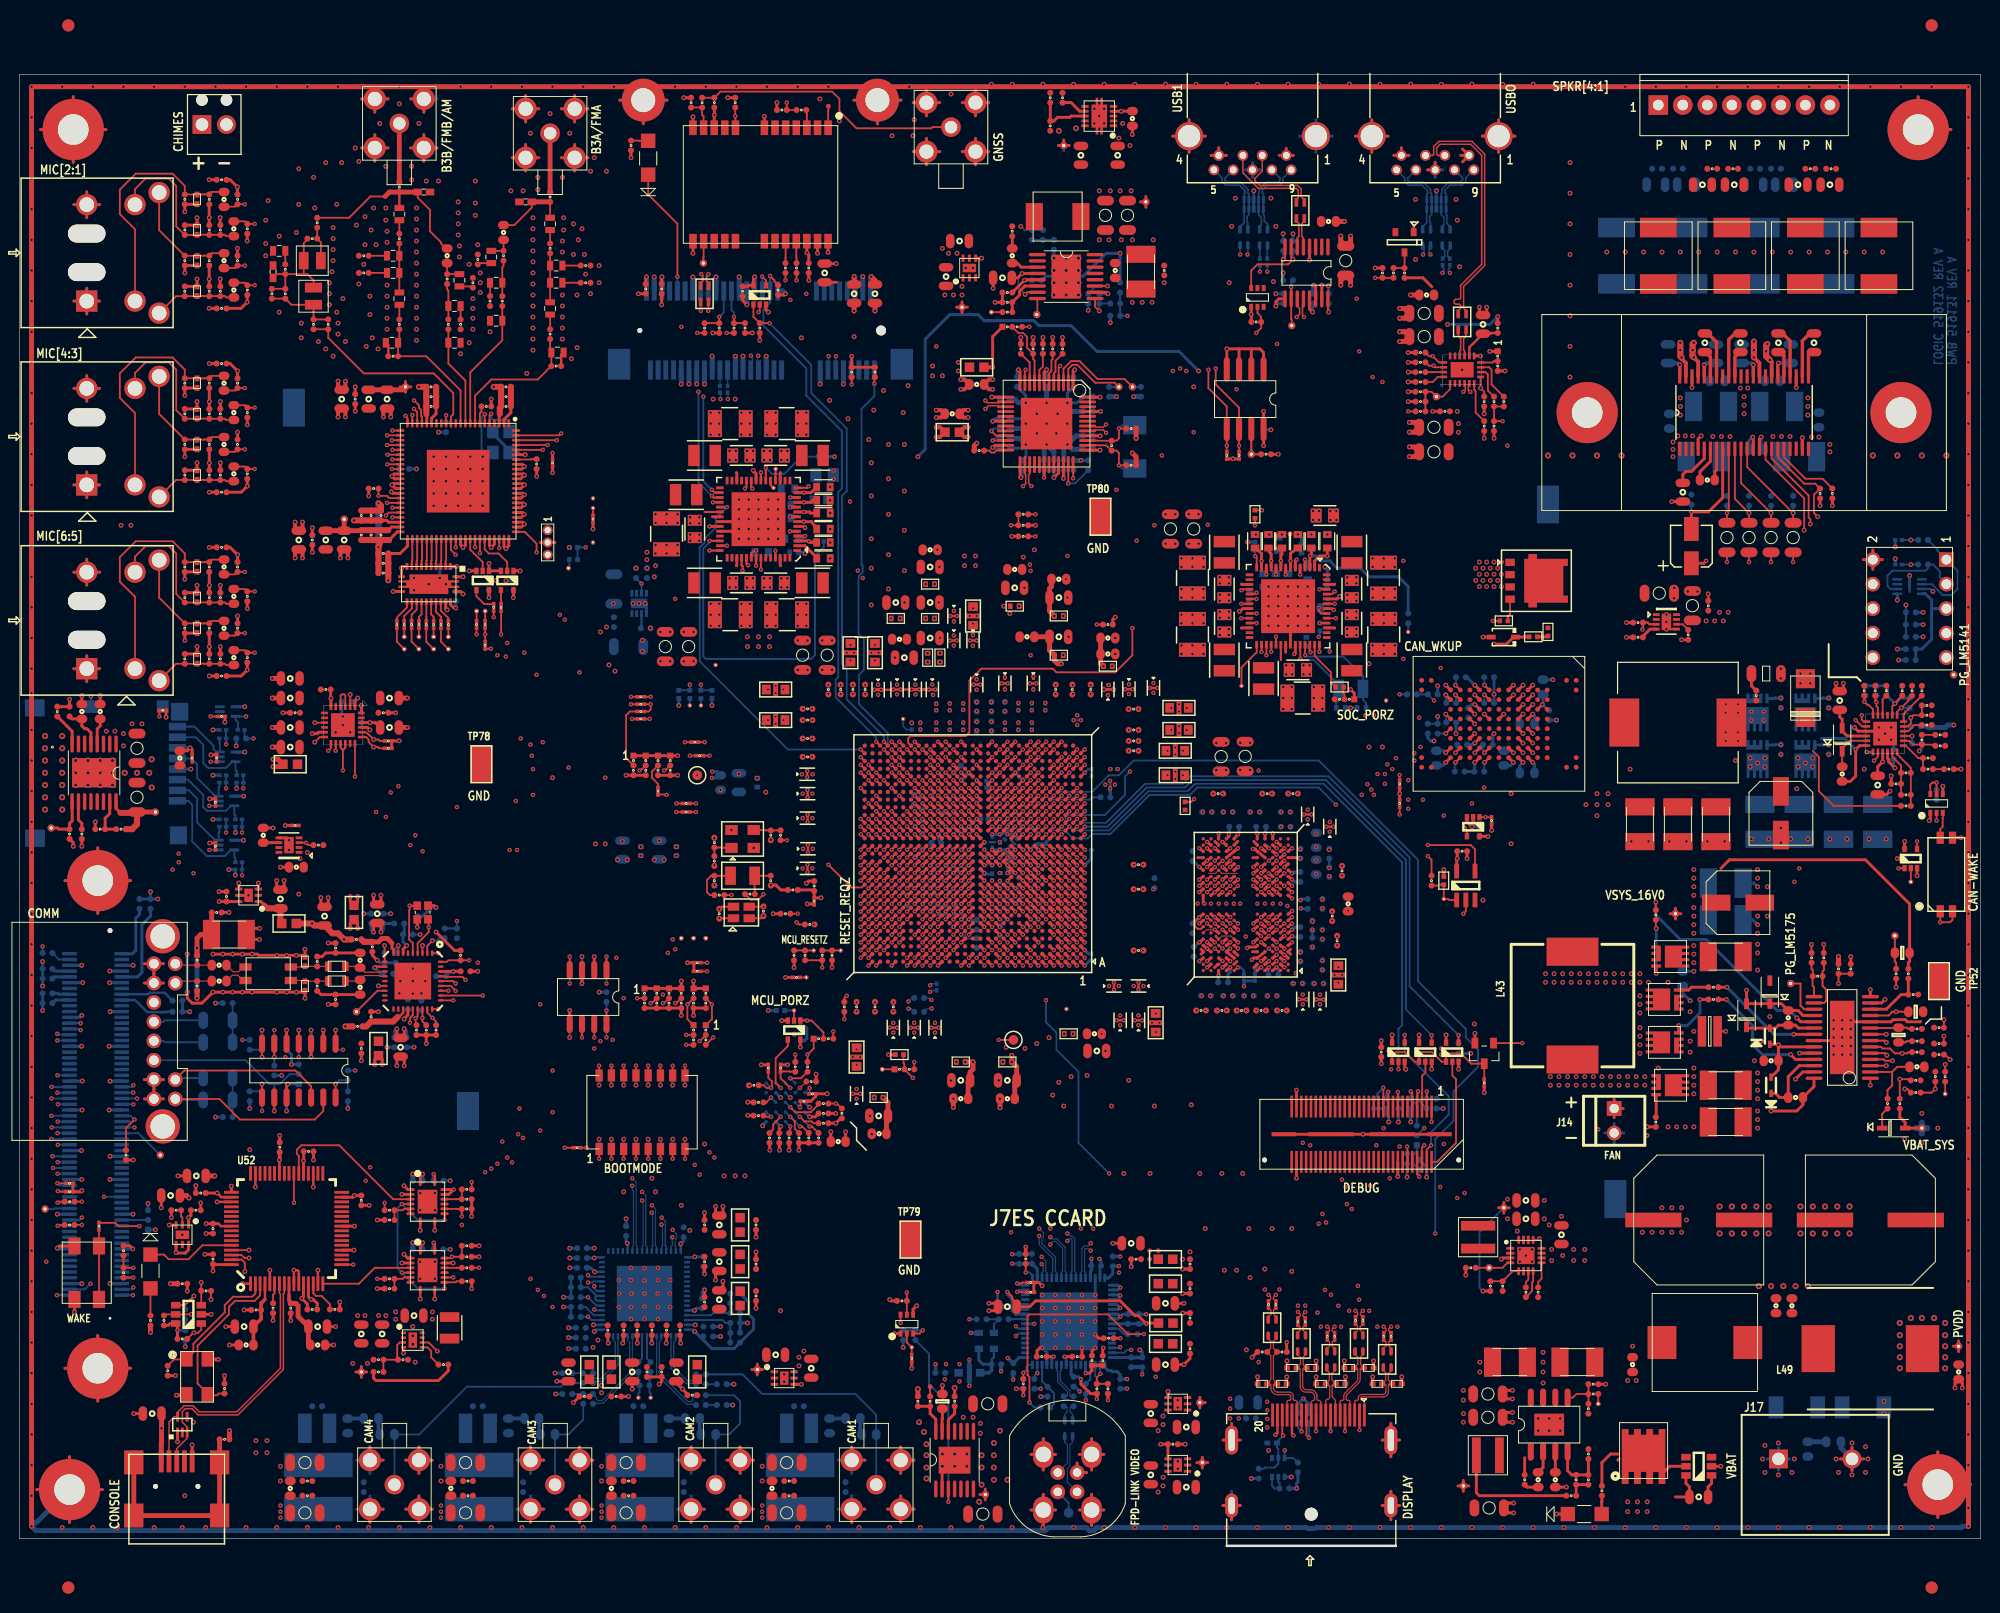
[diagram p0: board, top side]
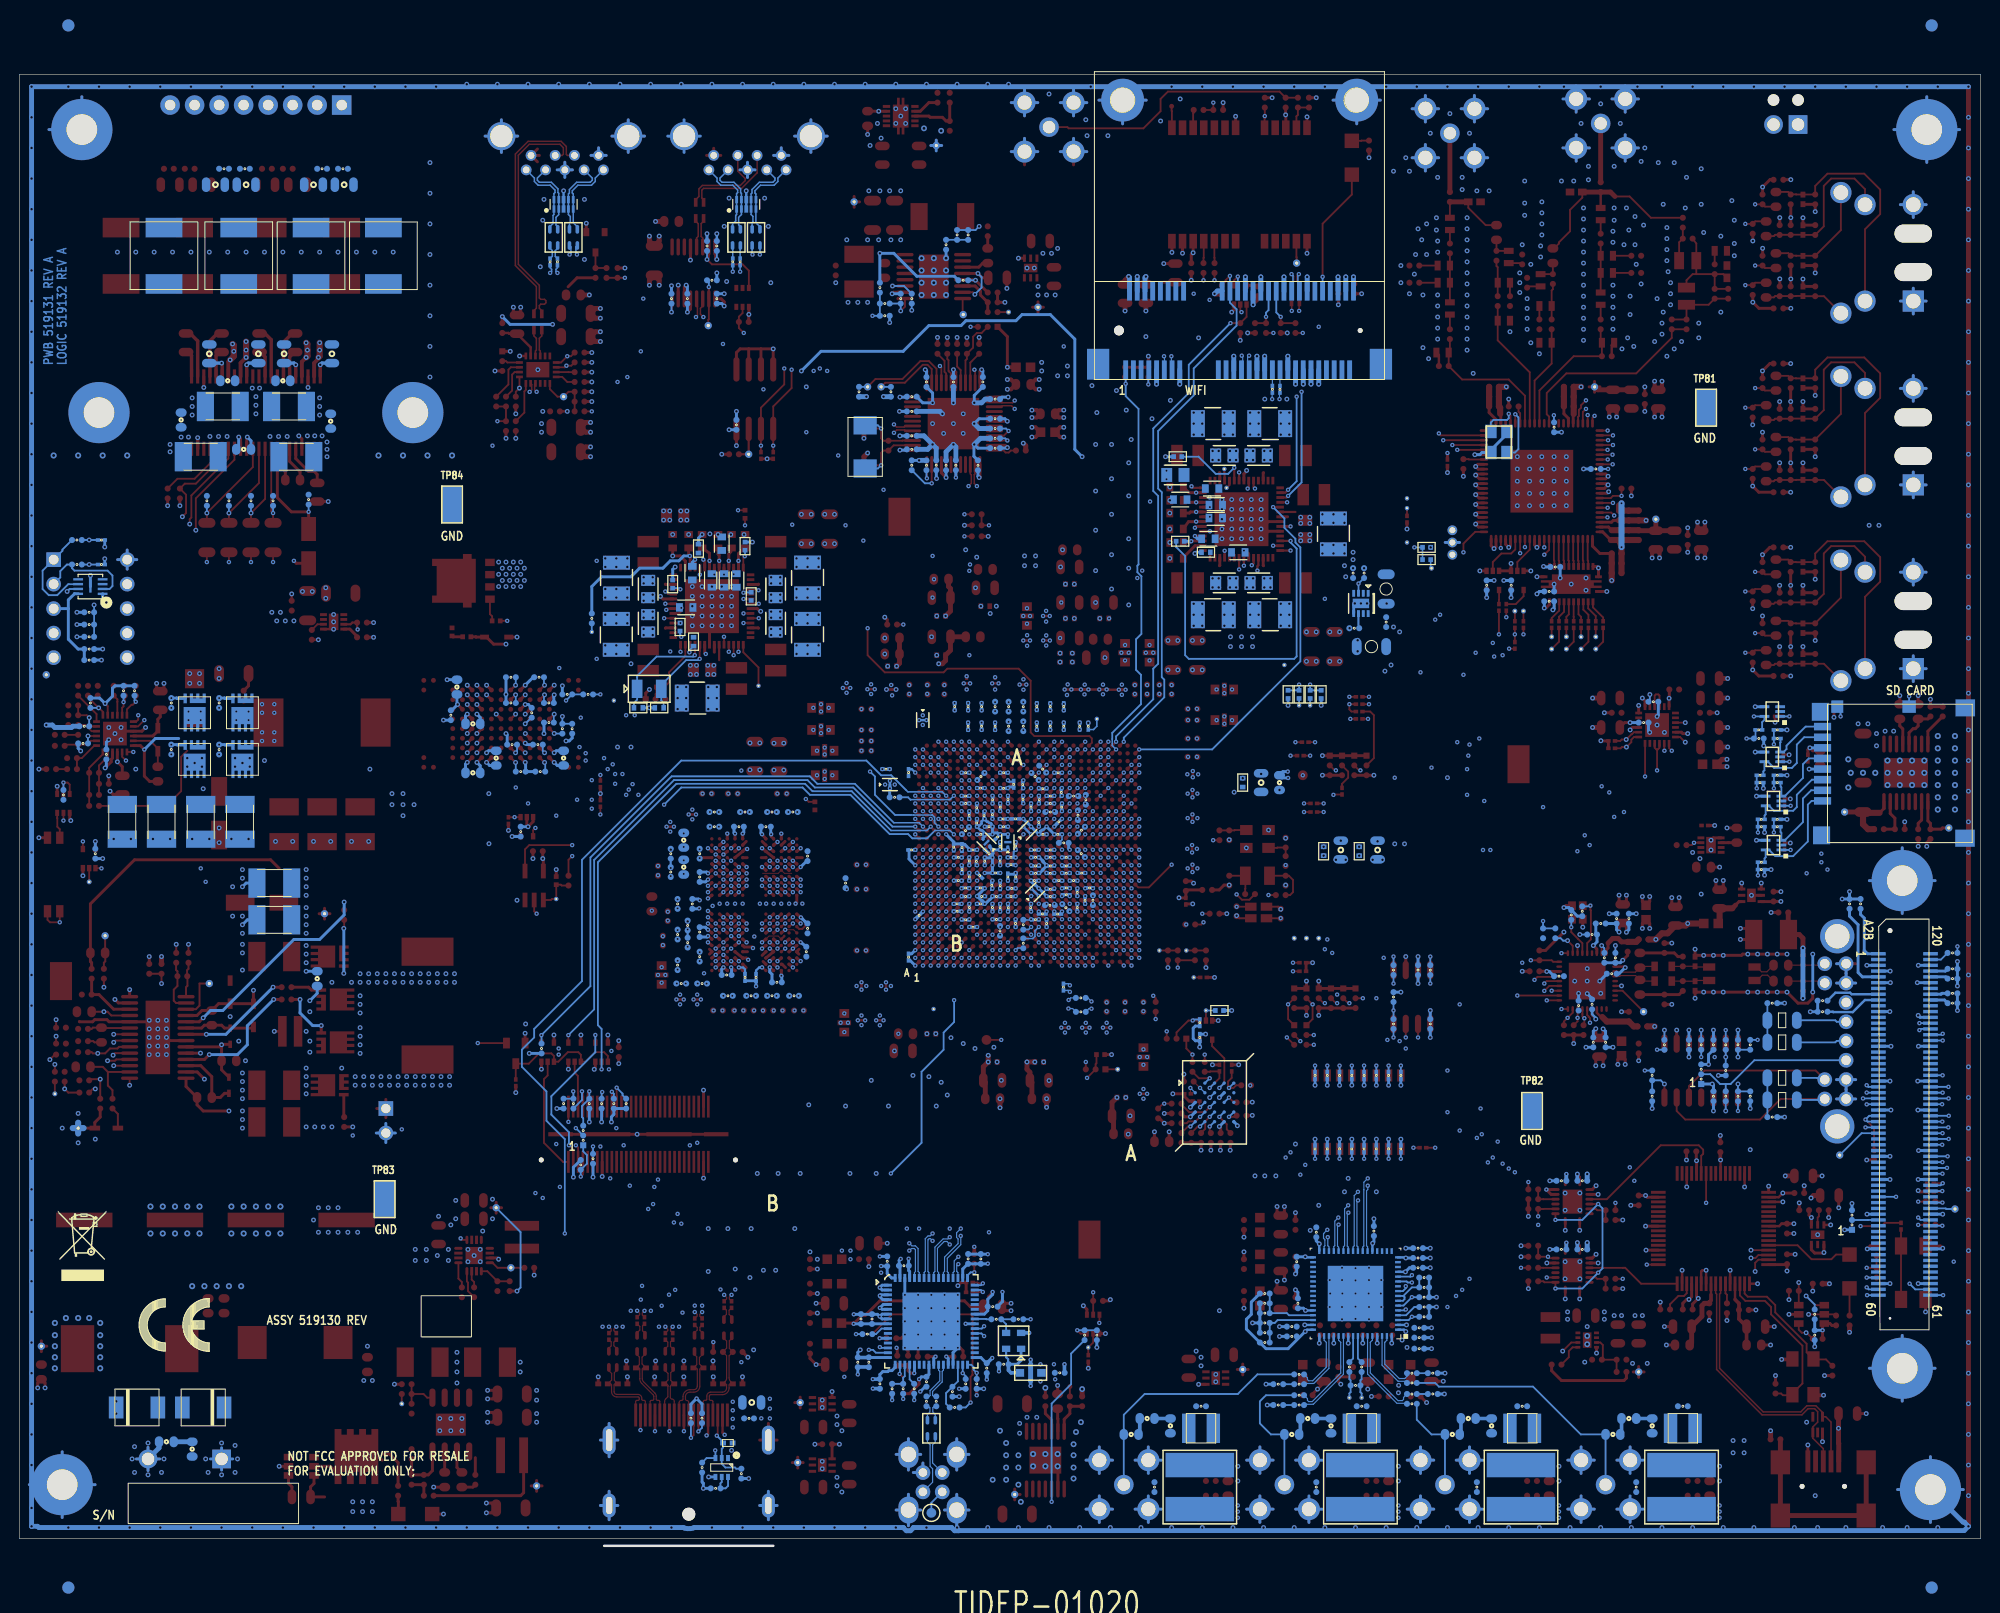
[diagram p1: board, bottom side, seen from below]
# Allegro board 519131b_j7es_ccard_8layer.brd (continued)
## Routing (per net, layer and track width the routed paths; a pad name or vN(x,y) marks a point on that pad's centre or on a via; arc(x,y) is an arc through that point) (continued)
A2B_WKUP_GPIO_2: length 116
  TOP w0.191: SW2.3 v1(62.61,40.12)
  TOP w0.229: U37.F28 87.98,64.15 v1(87.98,64.15)
  L4-SIGNAL w0.163: v1(62.61,40.12) 62.61,41.01 61.98,41.65 61.98,54.09 62.61,54.73 v1(62.61,56.76)
  L7-SIGNAL w0.107: v1(62.61,40.12) 61.98,39.49 58.93,39.49 54.86,43.55 27.3,43.55 24,40.25 18.92,40.25 18.29,39.61 16.2,39.61 15.48,38.9 11.88,38.9 9.78,41 9.66,41 4.29,46.37 v1(3.33,46.37) ; v1(62.61,56.76) 63.5,57.65 73.53,57.65 77.98,62.09 81.03,62.09 81.92,62.98 85.79,62.98 86.56,63.74 87.57,63.74 v1(87.98,64.15)
  BOTTOM w0.191: J21.95 v1(3.33,46.37) ; R421.1 v1(62.61,40.12)
A2B_WKUP_GPIO_15: length 113.7
  TOP w0.191: v1(67.94,56.25) 68.07,56.25 RJ11.2
  TOP w0.229: v1(88.78,66.55) 89.18,66.95 U37.J27
  L4-SIGNAL w0.163: v1(53.98,43.04) v1(53.98,56.12) ; v1(88.78,66.55) 88.78,66.29 88.63,66.14 88.61,66.14 88.38,65.91 88.38,65.89 88.37,65.88 88.37,65.58 88.14,65.35 86.59,65.35 83.85,62.6 72.77,62.6 72.14,61.97 68.51,61.97 68.38,61.84 v1(67.94,61.84)
  L5-SIGNAL w0.163: v1(67.94,56.25) v1(67.94,61.84)
  L7-SIGNAL w0.107: v1(4,45.77) 8.99,40.78 9.69,40.78 12,38.47 15.49,38.47 16.26,39.23 18.54,39.23 19.28,39.97 25.7,39.97 28.77,43.04 51.53,43.04 51.53,43.05 51.85,43.05 51.85,43.04 v1(53.98,43.04) ; v1(53.98,56.12) 62.74,56.12 63.25,55.62 67.31,55.62 v1(67.94,56.25)
  BOTTOM w0.191: J21.94 v1(4,45.77)
A2B_WKUP_UART0_RXD: length 94
  TOP w0.191: RJ15.3 v1(71.88,52.69)
  TOP w0.229: v1(87.18,66.55) 87.18,66.55 U37.J29
  L5-SIGNAL w0.163: v1(87.18,66.55) 85.48,66.55 84.96,66.03 79.63,66.03 74.53,60.93 70.84,60.93 70.61,60.7 70.61,56.5 71.88,55.23 v1(71.88,52.69)
  L7-SIGNAL w0.107: v1(71.88,52.69) 70.23,51.04 58.67,51.04 53.72,46.09 20.57,46.09 19.81,45.33 15.83,45.33 15.39,45.77 14.73,45.77 14.33,45.38 12.19,45.38 v1(11.81,45.76)
  BOTTOM w0.191: v1(11.81,45.76) 11.81,45.77 J21.27
A2B_WKUP_UART0_TXD: length 96
  TOP w0.191: RJ14.3 v1(69.09,51.93)
  TOP w0.229: U37.J28 88.38,66.95 v1(87.98,66.55)
  L5-SIGNAL w0.163: v1(67.19,61.46) 67.19,57.39 67.44,57.14 67.44,53.58 v1(69.09,51.93)
  L7-SIGNAL w0.107: v1(67.19,61.46) 74.29,61.46 76.33,63.49 80.77,63.49 82.3,65.01 83.69,65.01 84.84,66.16 87.59,66.16 v1(87.98,66.55) ; v1(12.19,46.37) 13.08,47.26 17.75,47.26 18.54,46.47 53.34,46.47 58.8,51.93 v1(69.09,51.93)
  BOTTOM w0.191: J21.26 v1(12.19,46.37)
A2B_XREF_CLK_IN: length 103.4
  TOP w0.191: R130.2 v1(68.07,76.95) ; R219.2 v1(6.48,33.26)
  L4-SIGNAL w0.163: v1(36.96,76.06) 36.96,69.2 35.81,68.06 35.81,66.66 36.2,66.28 36.2,64.66 35.69,64.15 35.69,60.95 35.89,60.75 v1(35.89,37.84)
  L5-SIGNAL w0.163: v1(68.07,76.95) 67.18,76.06 v1(36.96,76.06)
  L7-SIGNAL w0.107: v1(6.48,33.26) 11.56,33.26 12.06,33.77 12.06,33.79 12.17,33.9 14.73,33.9 15.62,34.79 32.38,34.79 35.43,37.84 v1(35.89,37.84)
A2B_XREF_CLK_OUT: length 97.4
  TOP w0.229: U37.W25 v1(90.38,75.35)
  L7-SIGNAL w0.107: v1(90.38,75.35) 89.95,75.78 88.62,75.78 88.34,76.06 84.89,76.06 83.91,77.05 81.98,77.05 81.91,76.98 78.87,76.98 78.81,77.05 72.17,77.05 70.87,78.35 44.2,78.35 43.31,77.46 35.19,77.46 30.09,72.38 28.96,72.38 28.7,72.63 21.21,72.63 20.07,71.49 18.92,71.49 16.64,69.2 13.21,69.2 9.91,65.9 6.73,65.9 2.96,62.13 v1(2.41,62.13)
  BOTTOM w0.191: R367.2 v1(2.41,62.13)
A72_CONSOLE_RXD: length 172.6
  TOP w0.191: R212.2 v1(46.86,37.71)
  TOP w0.229: U37.AB2 109.58,77.74 v1(109.58,77.75)
  L2-SIGNAL w0.107: v1(141.72,81.01) 141.72,80.39 141.86,80.25 141.86,56.89 137.03,52.06 v1(137.03,37.96)
  L5-SIGNAL w0.163: v1(137.03,37.96) 136.65,37.58 131.83,37.58 131.71,37.71 76.2,37.71 76.07,37.84 68.1,37.84 66.34,39.59 59.31,39.59 57.43,37.71 v1(46.86,37.71) ; v1(109.58,77.75) 109.58,77.97 110.59,78.98 111.25,78.98 112.29,80.02 114.28,80.02 114.55,79.75 116.97,79.75 118.75,81.52 141.21,81.52 v1(141.72,81.01)
A72_CONSOLE_TXD: length 179
  TOP w0.191: v1(45.85,34.15) 45.85,34.91 45.31,34.91 45.29,34.93 U51.11
  TOP w0.229: U37.AB3 108.78,77.74 v1(108.78,77.75)
  L2-SIGNAL w0.107: v1(137.41,37.2) 137.67,37.45 137.67,52.19 142.24,56.76 142.24,80.1 142.24,80.1 v1(142.24,80.51)
  L4-SIGNAL w0.163: v1(142.24,80.51) 140.34,80.51 140.05,80.79 130.02,80.79 129.41,81.4 123.04,81.4 120.37,78.73 114.55,78.73 113.58,79.7 112.72,79.7 111.49,78.48 110.36,78.48 110.04,78.15 109.18,78.15 v1(108.78,77.75)
  L5-SIGNAL w0.163: v1(45.85,34.15) 48.9,37.2 57.63,37.2 59.59,39.16 66.12,39.16 68.07,37.2 v1(137.41,37.2)
AMI: length 21
  TOP w0.191: U19.13 44.72,117.05 44.96,117.29 44.96,119.5 42.93,121.53 35.69,121.53 32,125.21 R27.1 C66.1
APL_RSTN: length 97.9
  TOP w0.229: v1(108.78,75.35) 108.38,74.95 U37.W3
  L4-SIGNAL w0.163: v1(143.89,79.36) 161.04,79.36 173.86,92.19 181.61,92.19 182.75,93.33 193.67,93.33 194.56,94.22 v2(197.23,94.22)
  L5-SIGNAL w0.163: v1(108.78,75.35) 109.18,75.75 109.75,75.75 109.98,75.98 109.98,76.31 110.22,76.55 110.55,76.55 111.71,77.71 113.54,77.71 114.43,78.6 119.63,78.6 120.4,79.36 121.54,79.36 121.69,79.52 141.83,79.52 141.99,79.36 v1(143.89,79.36)
  BOTTOM w0.191: 196.47,94.22 v2(197.23,94.22)
APL_SCL: length 10.8
  BOTTOM w0.191: R281.1 198.73,103.26 198.73,103.14 J11.1 200.79,101.08 200.79,99.18 200.15,98.54 199.27,98.54 198.13,99.68 U67.6
APL_SDA: length 10.3
  BOTTOM w0.191: U67.2 193.85,99.18 193.55,99.48 193.55,100.57 194.06,101.08 197.49,101.08 197.74,101.34 R287.1 198.27,101.72 198.96,101.03 198.96,100.37 J11.3
AUDIO_EXT_REFCLK2: length 21.4
  TOP w0.191: R130.1 v1(70.1,76.95)
  TOP w0.229: U37.W26 v1(89.58,75.35)
  L5-SIGNAL w0.163: v1(70.1,76.95) 71.25,76.95 71.63,76.57 82.93,76.57 83.75,75.75 88.89,75.75 88.89,75.75 89.18,75.75 v1(89.58,75.35)
B3A: length 13.5
  TOP w0.191: U19.9 46.72,121.64 50.04,124.96 L23.2 C62.1
BOOTMODE0: length 9.2
  TOP w0.191: R209.2 v1(58.77,41.26) ; 65.15,41.14 v1(65.15,40.12)
  L7-SIGNAL w0.107: v1(58.77,41.26) 59.05,40.98 64.29,40.98 v1(65.15,40.12)
  BOTTOM w0.191: R419.1 v1(65.15,40.12)
BOOTMODE1: length 6.9
  TOP w0.191: R115.2 63.25,86.48 62.87,86.1 62.87,81.65 63.63,80.89
BOOTMODE2: length 25.7
  TOP w0.191: 64.9,80.89 64.39,80.38 v1(64.26,80.38)
  TOP w0.229: U37.AC29 87.58,78.15 v1(87.18,78.55)
  L5-SIGNAL w0.163: v1(87.18,78.55) 85.91,78.55 83.44,81.02 80.39,81.02 80.26,81.14 71.37,81.14 71.12,80.89 64.77,80.89 v1(64.26,80.38)
BOOTMODE3: length 2.9
  TOP w0.191: R128.2 66.17,78.98 65.53,79.62 65.53,80.25 66.17,80.89
BOOTMODE4: length 159.8
  TOP w0.191: SW2.6 v1(66.42,40.12)
  TOP w0.229: U37.V6 105.98,74.15 v1(106.38,74.55)
  L2-SIGNAL w0.107: v1(139.95,37.33) 139.95,41.52 140.46,42.03 140.46,52.44 144.27,56.25 144.27,76.24 144.28,76.25 144.28,76.57 144.27,76.57 144.27,76.95 v1(143.89,77.33)
  L5-SIGNAL w0.163: v1(106.38,74.55) 106.81,74.11 106.98,74.11 107.01,74.15 109.77,74.15 109.98,74.36 109.98,74.71 110.21,74.95 110.57,74.95 112.68,77.06 113.78,77.06 114.56,77.84 119.89,77.84 120.65,78.6 122.17,78.6 122.43,78.86 136.91,78.86 138.43,77.33 v1(143.89,77.33) ; v1(66.42,40.12) 67.56,38.98 75.69,38.98 76.58,38.09 130.68,38.09 131.19,38.6 137.41,38.6 138.68,37.33 v1(139.95,37.33)
  BOTTOM w0.191: R418.1 v1(66.42,40.12)
BOOTMODE5: length 90.5
  TOP w0.191: SW2.7 v1(67.69,40.12)
  TOP w0.229: U37.V5 106.78,74.15 v1(107.18,74.55)
  L5-SIGNAL w0.163: v1(107.18,74.55) 106.78,74.95 106.21,74.95 105.98,74.71 105.98,73.59 105.41,73.01 104.9,73.01 104.38,72.49 104.38,58.54 v1(106.36,56.56) ; v1(67.69,40.12) 68.2,39.61 69.34,39.61 69.79,40.06 70.54,40.06 71.25,39.36 76.07,39.36 76.83,38.6 v1(112.9,38.6)
  BOTTOM w0.191: v1(106.36,56.56) 106.36,54.29 107.44,53.2 107.44,51.42 109.73,49.14 109.73,41.77 v1(112.9,38.6) ; R417.1 v1(67.69,40.12)
BOOTMODE6: length 69.2
  TOP w0.191: 68.96,41.14 v1(68.96,40.12) ; R100.2 v1(48.86,92.99)
  L2-SIGNAL w0.107: v1(55.24,44.95) 55.24,48 54.74,48.5 54.74,49.52 55.37,50.15 55.37,78.48 54.74,79.11 54.74,84.44 48.86,90.32 v1(48.86,92.99)
  L7-SIGNAL w0.107: v1(68.96,40.12) 67.69,41.39 59.44,41.39 58.93,41.9 58.29,41.9 v1(55.24,44.95)
  BOTTOM w0.191: R416.1 v1(68.96,40.12)
BOOTMODE7: length 27.6
  TOP w0.191: v1(66.8,80.38) 66.93,80.38 67.44,80.89
  TOP w0.229: U37.AB24 v1(91.18,77.75)
  L5-SIGNAL w0.163: v1(66.8,80.38) 71.25,80.38 71.61,80.74 82.83,80.74 85.42,78.15 87.43,78.15 87.88,78.6 89.7,78.6 90.55,77.75 v1(91.18,77.75)
C_DP0_AUX_N: length 51.6
  TOP w0.122: C401.1 129.64,25.58 129.64,25.78 v1(129.41,26.01) ; U37.G6 v1(106.38,64.95)
  L2-SIGNAL w0.102: v1(106.38,64.95) 105.95,64.51 105.43,64.51 105.21,64.3 105.21,63.63 104.83,63.25 104.83,62.22 105.21,61.83 105.21,59.99 105.33,59.87 105.33,55.06 107.19,53.2 107.19,49.27 129.59,26.86 129.59,26.19 v1(129.41,26.01)
C_DP0_AUX_P: length 51.6
  TOP w0.122: v1(130.18,26.01) 129.92,25.76 129.92,25.61 C402.1 ; U37.F7 v1(105.58,64.15)
  L2-SIGNAL w0.102: v1(130.18,26.01) 129.92,26.26 129.92,27 107.52,49.4 107.52,53.34 105.66,55.19 105.66,58.74 105.81,58.88 106.21,58.88 106.35,59.02 106.35,59.22 106.21,59.36 105.81,59.36 105.66,59.5 105.66,59.71 105.95,59.99 105.95,60.3 105.73,60.51 105.73,60.58 105.95,60.79 105.95,61.1 105.54,61.5 105.54,61.97 105.16,62.36 105.16,63.11 105.54,63.49 105.54,64.16 105.56,64.16 v1(105.58,64.15)
C_DP0_TX0_N: length 69
  TOP w0.122: C427.1 141.6,22.3 141.6,22.45 v1(141.35,22.71) ; v1(102.38,60.95) 101.98,61.35 U37.B11
  L4-SIGNAL w0.122: v1(102.38,60.95) 101.99,60.56 101.99,60.54 101.98,60.53 101.99,60.51 101.99,60.06 101.97,60.03 101.97,59.98 101.92,59.93 101.92,59.31 101.98,59.25 101.98,57.94 101.98,52.92 102.17,52.73 102.17,52.68 102.45,52.4 102.53,52.4 102.96,51.98 102.96,51.9 125.65,29.2 125.65,23.82 130.81,18.66 138.43,18.66 141.58,21.81 141.58,22.48 v1(141.35,22.71)
C_DP0_TX0_P: length 69
  TOP w0.122: C428.1 141.88,22.28 141.88,22.48 v1(142.11,22.71) ; U37.A12 v1(101.58,60.14)
  L4-SIGNAL w0.122: v1(142.11,22.71) 141.88,22.48 141.88,21.68 138.56,18.35 130.68,18.35 125.35,23.69 125.35,29.07 102.65,51.77 102.65,51.85 102.41,52.1 102.33,52.1 101.86,52.56 101.86,52.6 101.68,52.79 101.68,57.94 101.67,59.12 101.61,59.19 101.61,60.03 101.61,60.06 101.57,60.11 101.57,60.13 v1(101.58,60.14)
C_DP0_TX1_N: length 68.5
  TOP w0.122: v1(138.43,24.36) 138.66,24.13 138.66,23.93 C411.1 ; U37.B10 v1(103.18,60.95)
  L4-SIGNAL w0.122: v1(138.43,24.36) 138.76,24.03 138.76,21.4 137.59,20.23 131.39,20.23 127.05,24.58 127.05,30.52 121.67,35.9 121.67,36.11 122.05,36.49 122.05,36.95 121.72,37.27 121.26,37.27 120.88,36.9 120.67,36.9 120.52,37.04 120.52,37.25 120.9,37.63 120.9,38.09 120.58,38.42 120.11,38.42 119.74,38.04 118.77,38.04 103.01,53.8 103.01,59.43 102.77,59.67 102.77,60.53 v1(103.18,60.95)
C_DP0_TX1_P: length 68.5
  TOP w0.122: v1(139.19,24.36) 138.94,24.11 138.94,23.95 C412.1 ; U37.A11 v1(102.38,60.14)
  L4-SIGNAL w0.122: v1(102.38,60.14) 102.46,60.06 102.46,59.54 102.7,59.3 102.7,53.67 118.64,37.74 119.86,37.74 120.24,38.11 120.45,38.11 120.6,37.96 120.6,37.76 120.22,37.38 120.22,36.92 120.55,36.59 121.01,36.59 121.39,36.97 121.59,36.97 121.74,36.82 121.74,36.61 121.36,36.24 121.36,35.77 126.75,30.39 126.75,24.45 131.27,19.93 137.72,19.93 139.06,21.28 139.06,24.23 v1(139.19,24.36)
C_DP0_TX2_N: length 68.2
  TOP w0.122: C425.1 135.74,22.28 135.74,22.48 v1(135.51,22.71) ; U37.B8 104.38,61.35 v1(104.78,60.95)
  L4-SIGNAL w0.122: v1(104.78,60.95) 104.39,60.56 104.39,60.01 104.27,59.88 104.27,59.65 104.19,59.57 104.19,54.46 110.95,47.79 114.38,47.79 114.73,47.44 114.73,46.98 114.2,46.45 114.2,46.24 114.35,46.09 114.56,46.09 115.09,46.62 115.55,46.62 115.87,46.29 115.87,45.83 115.35,45.3 115.35,45.1 115.49,44.95 115.7,44.95 116.23,45.48 116.69,45.48 117.02,45.15 117.02,44.69 116.49,44.16 116.49,43.95 116.64,43.8 116.85,43.8 117.38,44.33 117.84,44.33 118.16,44.01 118.16,43.55 117.63,43.02 117.63,42.81 117.78,42.66 117.99,42.66 118.52,43.19 118.98,43.19 119.31,42.86 119.31,42.4 118.78,41.87 118.78,41.66 118.93,41.52 119.13,41.52 119.66,42.04 120.12,42.04 128.52,33.64 128.52,25.01 131.44,22.09 135.62,22.09 135.74,22.21 135.74,22.48 v1(135.51,22.71)
C_DP0_TX2_P: length 68.2
  TOP w0.122: C426.1 136.02,22.3 136.02,22.45 v1(136.27,22.71) ; U37.A9 v1(103.98,60.15)
  L4-SIGNAL w0.122: v1(136.27,22.71) 136.04,22.48 136.04,22.08 135.74,21.78 131.32,21.78 128.22,24.88 128.22,33.52 120,41.74 119.79,41.74 119.26,41.21 118.8,41.21 118.47,41.54 118.47,42 119,42.53 119,42.74 118.85,42.88 118.65,42.88 118.12,42.35 117.66,42.35 117.33,42.68 117.33,43.14 117.86,43.67 117.86,43.88 117.71,44.03 117.5,44.03 116.97,43.5 116.51,43.5 116.18,43.83 116.18,44.29 116.71,44.82 116.71,45.02 116.57,45.17 116.36,45.17 115.83,44.64 115.37,44.64 115.04,44.97 115.04,45.43 115.57,45.96 115.57,46.17 115.42,46.32 115.21,46.32 114.68,45.79 114.22,45.79 113.9,46.11 113.9,46.57 114.43,47.1 114.43,47.31 114.25,47.49 110.83,47.49 103.89,54.34 103.89,60.05 v1(103.98,60.14)
C_DP0_TX3_N: length 65.4
  TOP w0.122: v1(105.58,60.95) 105.18,61.35 U37.B7 ; v1(132.46,24.23) 132.7,23.99 132.7,23.81 C413.1
  L4-SIGNAL w0.122: v1(132.46,24.23) 132.55,24.23 132.72,24.06 132.72,23.8 132.54,23.61 131.83,23.61 131.32,24.12 131.32,33.14 122.12,42.33 122.12,42.54 122.67,43.1 122.67,43.56 122.35,43.89 121.89,43.89 121.33,43.33 121.12,43.33 120.98,43.48 120.98,43.69 121.53,44.24 121.53,44.7 121.2,45.03 120.74,45.03 120.19,44.47 119.98,44.47 119.83,44.62 119.83,44.83 120.39,45.39 120.39,45.85 120.06,46.17 119.6,46.17 119.04,45.62 118.84,45.62 118.69,45.77 118.69,45.97 119.24,46.53 119.24,46.99 118.92,47.32 118.46,47.32 117.9,46.76 117.69,46.76 117.54,46.91 117.54,47.12 118.1,47.67 118.1,48.13 117.77,48.46 117.31,48.46 116.76,47.91 116.55,47.91 116.4,48.05 116.4,48.26 116.96,48.82 116.96,49.28 116.63,49.6 116.17,49.6 115.74,49.18 111.53,49.18 105.17,55.46 105.17,59.75 105.18,59.76 105.18,60.54 v1(105.58,60.95)
C_DP0_TX3_P: length 65.4
  TOP w0.122: v1(133.22,24.23) 132.98,23.99 132.98,23.82 C414.1 ; U37.A8 v1(104.78,60.15)
  L4-SIGNAL w0.122: v1(104.78,60.14) 104.79,60.14 104.79,59.82 104.86,59.74 104.86,55.33 111.41,48.87 115.87,48.87 116.29,49.3 116.5,49.3 116.65,49.15 116.65,48.94 116.1,48.39 116.1,47.93 116.42,47.6 116.88,47.6 117.44,48.16 117.65,48.16 117.79,48.01 117.79,47.8 117.24,47.24 117.24,46.78 117.57,46.46 118.03,46.46 118.58,47.01 118.79,47.01 118.94,46.86 118.94,46.66 118.38,46.1 118.38,45.64 118.71,45.31 119.17,45.31 119.73,45.87 119.93,45.87 120.08,45.72 120.08,45.51 119.53,44.96 119.53,44.5 119.85,44.17 120.31,44.17 120.87,44.72 121.08,44.72 121.23,44.58 121.23,44.37 120.67,43.81 120.67,43.35 121,43.03 121.46,43.03 122.01,43.58 122.22,43.58 122.37,43.43 122.37,43.22 121.82,42.67 121.82,42.21 131.01,33.01 131.01,23.99 131.7,23.31 132.66,23.31 133.03,23.67 133.03,24.04 v1(133.22,24.23)
C_PCIE0_TX0_N: length 57.9
  TOP w0.122: v1(95.18,80.95) 95.58,80.55 U37.AF19
  L4-SIGNAL w0.122: v1(73.41,118.86) 73.1,119.17 73.1,119.6 73.51,120 75.56,120 76.2,119.37 84.45,119.37 89.03,114.8 89.03,95.62 89.86,94.79 89.86,88.19 91.82,86.22 93.14,86.22 94.15,85.21 94.15,83.39 95.6,81.95 95.6,81.92 95.59,81.91 95.59,81.36 v1(95.18,80.95)
  BOTTOM w0.122: v1(73.41,118.86) 73.41,119.51 C509.1
C_PCIE0_TX0_P: length 57.9
  TOP w0.122: U37.AG18 96.38,81.35 v1(95.98,81.75)
  L4-SIGNAL w0.122: v1(95.98,81.75) 95.98,82 94.46,83.52 94.46,85.34 93.27,86.53 91.95,86.53 90.16,88.32 90.16,94.92 89.33,95.75 89.33,114.92 84.58,119.67 76.33,119.67 75.69,120.31 73.38,120.31 72.8,119.72 72.8,119.01 v1(72.64,118.86)
  BOTTOM w0.122: C510.1 72.64,119.48 v1(72.64,118.86)
C_UB981_DOUT0_N: length 4.1
  BOTTOM w0.122: C831.1 108.95,15.48 108.84,15.59 108.84,16.1 107.84,17.1 107.84,18.09 107.96,18.21 U75.26
C_UB981_DOUT0_P: length 4.1
  BOTTOM w0.122: C832.1 108.48,15.48 108.58,15.59 108.58,15.99 107.59,16.99 107.59,18.09 107.46,18.21 U75.27
C_USB0_SS_TX_N: length 76.5
  TOP w0.157: v1(103.98,80.95) 103.98,80.94 U37.AF9
  L4-SIGNAL w0.147: v1(147.45,131.94) 147.7,131.69 147.7,131.23 147.53,131.06 144.2,131.06 136.83,123.69 132.66,123.69 119.63,110.66 117.6,110.66 110.69,103.75 110.69,95.37 108.97,93.64 108.97,90.46 108.28,89.78 108.28,87.75 105.68,85.14 105.68,84.01 105.18,83.52 105.18,82.38 105.19,82.38 104.96,82.14 104.95,82.15 104.61,82.15 104.38,81.92 104.38,81.58 104.41,81.55 104.41,81.38 v1(103.98,80.95)
  BOTTOM w0.157: C494.1 147.45,132.48 147.6,132.32 147.6,132.1 v1(147.45,131.94)
C_USB0_SS_TX_P: length 76.5
  TOP w0.157: U37.AG8 104.78,81.74 v1(104.78,81.75)
  L4-SIGNAL w0.147: v1(148.21,131.94) 148.08,131.82 148.08,131.18 147.66,130.76 144.33,130.76 136.96,123.38 132.79,123.38 119.76,110.35 117.73,110.35 111,103.62 111,95.24 109.27,93.51 109.27,90.34 108.58,89.65 108.58,87.62 105.98,85.01 105.98,84.69 106.11,84.55 106.47,84.55 106.6,84.42 106.6,84.23 106.47,84.1 106.11,84.1 105.98,83.97 105.98,82.38 105.75,82.15 105.4,82.15 105.08,81.83 105,81.75 v1(104.78,81.75)
  BOTTOM w0.157: C493.1 148.21,132.48 148.05,132.32 148.05,132.1 v1(148.21,131.94)
C_USB1_SS_TX_N: length 65.2
  TOP w0.157: v1(101.58,80.95) 101.58,80.94 U37.AF12
  L4-SIGNAL w0.147: v1(101.58,80.95) 101.58,81.52 102.21,82.15 102.55,82.15 102.78,82.38 102.78,84.08 102.63,84.23 102.63,87.72 103,88.09 103,94.76 106.39,98.15 106.39,101.34 107.36,102.31 107.36,104.55 117.09,114.29 119.08,114.29 128.73,123.94 128.73,131.87 v1(128.52,132.07)
  BOTTOM w0.157: C496.1 v1(128.52,132.07)
C_USB1_SS_TX_P: length 65.2
  TOP w0.157: U37.AG11 102.38,81.74 v1(102.38,81.75)
  L4-SIGNAL w0.147: v1(102.38,81.75) 102.41,81.75 102.51,81.85 102.67,81.85 103.08,82.26 103.08,82.88 103.16,82.96 103.57,82.96 103.81,83.2 103.81,83.53 103.6,83.74 103.19,83.74 103.08,83.85 103.08,84.21 102.94,84.35 102.94,87.6 103.3,87.96 103.3,94.63 106.69,98.02 106.69,101.21 107.66,102.18 107.66,104.43 117.22,113.99 119.2,113.99 129.03,123.81 129.03,131.82 v1(129.29,132.07)
  BOTTOM w0.157: C495.1 v1(129.29,132.07)
CAM_0_N: length 6.6
  BOTTOM w0.122: C827.1 70.03,16.83 69.09,16.83 67.52,18.4 U74.51
CAM_0_P: length 6.6
  BOTTOM w0.122: C823.1 69.75,17.41 69.75,17.23 69.63,17.11 69.2,17.11 67.8,18.51 67.8,21.09 68.02,21.31 U74.50
CAM_1_N: length 9.4
  BOTTOM w0.122: C835.1 70.03,14.67 69.14,14.67 66.02,17.79 U74.54
CAM_1_P: length 9.3
  BOTTOM w0.122: C830.1 69.75,15.26 69.75,15.07 69.63,14.95 69.25,14.95 66.3,17.91 66.3,21.09 66.52,21.31 U74.53
CAM_2_N: length 9.3
  BOTTOM w0.122: U74.60 63.02,21.31 63.24,21.09 63.24,17.93 60.37,15.05 59.91,15.05 59.79,15.17 59.79,15.38 C829.1
CAM_2_P: length 9.3
  BOTTOM w0.122: U74.59 63.52,17.81 60.48,14.77 59.49,14.77 C834.1
CAM_3_N: length 6.4
  BOTTOM w0.122: C822.1 59.44,17.57 59.66,17.34 60.24,17.34 61.74,18.84 61.74,21.09 61.52,21.31 U74.63
CAM_3_P: length 6.4
  BOTTOM w0.122: C825.1 59.61,17.06 60.35,17.06 62.02,18.72 U74.62
CAM_POWERON: length 19.5
  TOP w0.191: U62.3 v1(96.25,4.56)
  BOTTOM w0.191: v1(96.25,4.56) 96.25,14.74 94.23,16.75 94.23,19.93 R438.2
CAN_POWER_ON_HV: length 231.4
  TOP w0.191: Q2.2 v1(198.63,75.17)
  L2-SIGNAL w0.107: v1(147.19,37.2) 147.19,41.9 148.59,43.3 148.59,54.47 149.1,54.98 149.1,66.16 149.48,66.54 149.48,72.76 151,74.28 151,75.17 150.5,75.68 v1(150.5,76.95)
  L4-SIGNAL w0.163: v1(198.63,75.17) 197.74,76.06 195.07,76.06 193.17,77.97 183.77,77.97 182.63,79.11 162.31,79.11 160.15,76.95 v1(150.5,76.95)
  L5-SIGNAL w0.163: v1(147.19,37.2) 141.43,37.2 140.79,37.84 138.68,37.84 137.54,38.98 130.94,38.98 130.43,38.47 127.76,38.47 127.13,39.1 77.09,39.1 76.45,39.74 71.5,39.74 70.48,40.76 31.88,40.76 29.34,43.3 29.34,49.52 28.32,50.54 28.32,53.58 27.81,54.09 24.77,54.09 v1(23.11,52.44)
  BOTTOM w0.191: 23.88,52.44 v1(23.11,52.44)
CAN_WAKE: length 39.4
  TOP w0.191: v1(12.45,33.14) 10.29,33.14 9.94,33.48 R220.1
  L5-SIGNAL w0.163: J13.10 12.7,49.09 12.7,42.53 12.45,42.28 v1(12.45,33.14)
  BOTTOM w0.191: 26.42,47.87 25.91,47.87 23.44,50.33 J13.10 ; 26.42,47.87 27,47.87 28.02,48.88 RJ18.2 ; 26.42,47.87 R406.2
CAN_WKUP: length 96
  TOP w0.191: U27.47 v1(136.4,96.15) ; SW1.1 v1(199.01,64.63) 200.03,64.63 200.28,64.89 SW1.2
  L2-SIGNAL w0.107: v1(145.41,77.33) 145.41,79.75 144.02,81.14 144.02,92.06 143.89,92.19 TP23.1
  L4-SIGNAL w0.163: v1(145.41,77.33) 149.1,77.33 150.11,76.32 160.15,76.32 162.31,78.48 182.5,78.48 183.51,77.46 193.04,77.46 199.01,71.49 v1(199.01,64.63)
  L5-SIGNAL w0.163: v1(136.4,96.15) 136.7,95.85 136.7,95.85 136.93,95.62 138.94,95.62 139.83,94.73 TP23.1
  BOTTOM w0.191: 143.89,95.62 TP23.1
CANH_1: length 20.9
  TOP w0.191: J13.4 20.73,46.32 22.86,44.19 30.61,44.19 31.5,45.07 U50.13
  BOTTOM w0.191: R409.1 16.89,46.22 J13.4
CANH_2: length 54.3
  TOP w0.191: 59.56,54.09 v1(59.56,52.69)
  L5-SIGNAL w0.163: J13.9 22,52.34 24.13,54.47 32.51,54.47 34.42,52.57 50.16,52.57 50.67,52.06 58.93,52.06 v1(59.56,52.69)
  BOTTOM w0.191: R387.1 15.07,52.19 14.92,52.34 J13.9
CANL_1: length 19.2
  TOP w0.191: J13.3 17.09,49.27 28.61,49.27 30.23,47.65 U50.12
  BOTTOM w0.191: J13.3 16.97,48.5 R404.2
CANL_2: length 52.2
  TOP w0.191: U44.6 v1(58.29,52.69)
  L5-SIGNAL w0.163: J13.8 20.42,54.32 20.95,54.85 33.91,54.85 35.81,52.95 50.29,52.95 50.55,53.2 57.78,53.2 v1(58.29,52.69)
  BOTTOM w0.191: R384.2 15.07,54.47 14.92,54.32 J13.8
CHIMES_FSYNC: length 33.9
  TOP w0.191: U32.14 32.78,82.6 32.77,82.58 v1(32.77,82.41) ; R116.2 v1(63.47,85.71)
  L7-SIGNAL w0.107: v1(63.47,85.71) 40.39,85.71 36.96,82.29 36.07,82.29 35.43,82.92 33.27,82.92 v1(32.77,82.41)
CHIMES_M_SCLK: length 41
  TOP w0.191: U32.15 33.28,82.72 33.46,82.54 33.53,82.54 ; v1(33.53,80.38) 33.53,82.54 ; 33.53,82.54 33.59,82.54 33.78,82.72 U32.16 ; R122.2 v1(69.47,81.9)
  L7-SIGNAL w0.107: v1(33.53,80.38) 40.13,80.38 41.15,81.4 68.96,81.4 v1(69.47,81.9)
CHIMES_NSTANDBY: length 63.8
  TOP w0.191: U32.2 v2(34.27,88.24)
  TOP w0.229: U37.AH23 92.38,82.15 v1(91.98,82.55)
  L5-SIGNAL w0.163: v2(34.27,88.24) 34.8,88.76 42.42,88.76 45.21,85.97 62.48,85.97 63.15,85.3 75.85,85.3 76.36,84.8 79.47,84.8 79.76,85.08 90.27,85.08 91.57,83.78 91.57,82.95 v1(91.98,82.55)
  BOTTOM w0.191: R307.1 34.27,87.64 v2(34.27,88.24)
CHIMES_SDIN: length 65.5
  TOP w0.191: v1(32,82.41) 32.28,82.69 U32.13
  TOP w0.229: v1(91.18,81.75) 91.58,81.35 U37.AG24
  L7-SIGNAL w0.107: v1(91.18,81.75) 90.81,82.12 90.81,83.56 88.27,86.1 80.35,86.1 80.02,86.43 76.66,86.43 75.31,85.08 41.66,85.08 38.48,81.9 32.51,81.9 v1(32,82.41)
CHIMES_SDOUT: length 61.4
  TOP w0.191: v1(34.77,79.75) U32.18
  TOP w0.229: v1(91.18,79.35) 91.58,78.95 U37.AD24
  L7-SIGNAL w0.107: v1(91.18,79.35) 90.78,79.75 83.69,79.75 82.67,80.76 59.95,80.76 59.31,80.13 54.61,80.13 54.23,79.75 v1(34.77,79.75)
CON_DP0_AUX_N: length 11.1
  TOP w0.122: FL26.3 129.39,21.5 129.64,21.25 129.64,20.47 129.27,20.1 129.27,20.1 ; 129.27,20.1 129.67,19.7 129.67,17.42 arc(129.62,17.2) 129.5,17.02 129.27,16.79 D19.1 129.54,16.79 arc(129.63,16.75) 129.67,16.66 129.67,16.36 arc(129.87,15.87) 130.36,15.67 131.57,15.67 arc(131.67,15.63) 131.71,15.53 131.71,15.2 arc(131.68,15.11) 131.59,15.08 131.46,15.08 arc(131.38,15.04) 131.34,14.96 J18.17 ; 129.27,20.1 R240.1
CON_DP0_AUX_P: length 11.1
  TOP w0.122: FL26.2 130.2,21.5 129.92,21.22 129.92,20.5 130.32,20.1 130.31,20.1 ; J18.15 132.34,14.96 arc(132.31,15.04) 132.23,15.08 132.09,15.08 arc(132.01,15.11) 131.98,15.2 131.98,15.53 arc(131.86,15.81) 131.57,15.93 130.36,15.93 arc(130.06,16.06) 129.93,16.36 129.93,16.66 arc(129.93,16.68) 129.93,16.7 arc(129.97,16.76) 130.05,16.79 D20.1 130.31,16.79 130.07,17.04 arc(129.96,17.2) 129.92,17.4 129.92,19.7 130.31,20.1 ; 130.31,20.1 R241.2
CON_DP0_HPD: length 7.7
  TOP w0.191: v1(130.94,11.42) 130.84,11.51 J18.18
  BOTTOM w0.191: v1(130.94,11.42) 130.29,10.77 U78.1 130.29,10.19 130.43,10.05 Q15.2 130.43,8.5 130.05,8.12 129.05,8.12 128.92,7.99 128.4,7.99
CON_DP0_TX0_N: length 8.4
  TOP w0.122: FL31.3 141.31,18.2 141.55,17.95 141.55,17.15 D23.1 141.46,16.79 arc(141.55,16.75) 141.58,16.67 141.58,15.98 arc(141.5,15.78) 141.3,15.7 139.09,15.7 arc(138.83,15.58) 138.71,15.32 138.71,15.2 arc(138.68,15.11) 138.59,15.08 138.46,15.08 arc(138.38,15.04) 138.34,14.96 J18.3
CON_DP0_TX0_P: length 8.4
  TOP w0.122: J18.1 139.34,14.96 arc(139.31,15.04) 139.23,15.08 139.09,15.08 arc(139.01,15.11) 138.98,15.2 138.98,15.32 arc(139.01,15.4) 139.09,15.43 141.3,15.43 arc(141.68,15.59) 141.84,15.98 141.84,16.67 arc(141.88,16.75) 141.96,16.79 D24.1 141.83,17.19 141.83,17.87 142.12,18.16 FL31.2
CON_DP0_TX1_N: length 8
  TOP w0.122: FL28.3 138.38,19.85 138.68,19.55 138.68,18.85 D18.1 138.54,18.44 arc(138.62,18.41) 138.66,18.32 138.66,17.32 arc(138.63,17.15) 138.53,17.01 137.35,15.82 arc(137.25,15.68) 137.21,15.5 137.21,15.2 arc(137.18,15.11) 137.09,15.08 136.96,15.08 arc(136.88,15.04) 136.84,14.96 J18.6
CON_DP0_TX1_P: length 8
  TOP w0.122: FL28.2 139.2,19.81 138.96,19.57 138.96,18.79 D17.1 139.04,18.44 arc(138.96,18.41) 138.92,18.32 138.91,17.32 138.92,17.32 arc(138.87,17.05) 138.71,16.83 137.53,15.64 arc(137.48,15.58) 137.47,15.5 137.47,15.2 arc(137.51,15.11) 137.59,15.08 137.73,15.08 arc(137.81,15.04) 137.84,14.96 J18.4
CON_DP0_TX2_N: length 5.7
  TOP w0.122: J18.9 135.34,14.98 arc(135.41,15.14) 135.57,15.21 arc(135.7,15.26) 135.76,15.39 135.76,16.5 arc(135.75,16.51) 135.75,16.53 arc(135.63,16.72) 135.41,16.79 D21.1 135.71,17.15 135.71,17.95 135.46,18.2 FL30.3
CON_DP0_TX2_P: length 5.6
  TOP w0.122: J18.7 136.34,14.98 arc(136.32,15.11) 136.25,15.21 136.01,15.45 136.01,16.5 arc(136.01,16.54) 136,16.59 arc(136.07,16.73) 136.21,16.79 D22.1 135.99,17.19 135.99,17.87 136.28,18.16 FL30.2
CON_DP0_TX3_N: length 8.4
  TOP w0.122: J18.12 133.84,14.86 arc(133.9,15.01) 134.05,15.06 arc(134.15,15.11) 134.19,15.21 134.19,15.47 arc(134.05,15.79) 133.73,15.93 133.32,15.93 arc(132.88,16.11) 132.7,16.54 132.7,18.29 arc(132.66,18.4) 132.55,18.44 D15.1 132.74,18.86 132.74,19.52 132.44,19.83 FL29.3
CON_DP0_TX3_P: length 8.4
  TOP w0.122: FL29.2 133.25,19.83 133.02,19.6 133.02,18.78 D16.1 133.16,18.44 arc(133.04,18.41) 132.96,18.31 arc(132.96,18.3) 132.96,18.29 132.95,16.55 132.96,16.54 arc(133.06,16.29) 133.32,16.18 133.73,16.18 arc(134.23,15.97) 134.44,15.47 134.44,15.21 arc(134.48,15.11) 134.58,15.07 134.62,15.07 arc(134.78,15.01) 134.84,14.85 J18.10
CON_MMC1_CLK: length 8.2
  BOTTOM w0.191: P5.5 17.82,81.62 18.41,81.02 18.41,79.59 20.29,77.71 U71.3 20.65,78.62 20.74,78.71 R340.2
CON_MMC1_CMD: length 9.6
  BOTTOM w0.191: P5.3 17.48,79.42 19.05,77.85 19.05,76.57 19.43,76.19 21.4,76.19 21.92,76.71 U71.5 22.28,75.82 22.39,75.7 R344.2
CON_MMC1_DAT0: length 10.2
  BOTTOM w0.191: R335.2 22.52,80.27 22.4,80.39 U70.5 22.05,81.28 21.4,80.63 19.56,80.63 19.05,81.14 19.05,83.05 18.28,83.81 P5.7
CON_MMC1_DAT1: length 7.1
  BOTTOM w0.191: P5.8 18.14,84.91 20.12,82.93 20.12,82.58 20.42,82.28 U70.3 20.78,83.24 20.74,83.28 R322.2
CON_MMC1_DAT2: length 12.1
  BOTTOM w0.191: P5.1 17.52,77.22 17.91,76.82 17.91,73.01 19.43,71.49 21.28,71.49 21.92,72.13 U72.5 22.28,71.37 22.39,71.26 R350.2
CON_MMC1_DAT3: length 9.3
  BOTTOM w0.191: R347.2 20.74,73.99 20.65,73.91 U72.3 20.29,73.13 18.41,75.01 18.41,77.46 17.56,78.32 P5.2
CONN_USB1_DM: length 25.3
  TOP w0.157: FL3.2 149.07,128.03 149.33,128.29 149.33,128.56 149.18,128.7 148.79,128.7 148.64,128.85 148.64,129.06 148.79,129.2 149.18,129.2 149.33,129.35 149.33,130.66 151.5,132.83 151.5,144.14 150.36,145.28 147.19,145.28 146.84,144.92 146.84,144.25 146.96,144.12 J2.2
CONN_USB1_DP: length 25.3
  TOP w0.157: J2.3 146.42,144.12 146.53,144.24 146.53,145.05 147.07,145.58 150.49,145.58 151.81,144.26 151.81,132.71 149.63,130.53 149.63,128.29 149.89,128.03 FL3.3
CONN_USB2_DM: length 9.6
  TOP w0.157: FL1.3 133.12,139.54 132.79,139.87 132.79,140.65 132.44,141.01 128.5,141.01 128,141.51 128,141.73 128.76,142.49 J1.2
CONN_USB2_DP: length 9.6
  TOP w0.157: FL1.2 132.31,139.54 132.49,139.72 132.49,140.53 132.31,140.71 128.37,140.71 126.76,142.32 J1.3
CONN_USB_RXN0: length 8.5
  BOTTOM w0.157: FL36.3 145.39,136.73 145.81,137.15 U65.5 U65.6 145.81,140.13 145.91,140.23 145.91,140.46 145.33,141.04 143.92,141.04 143.53,141.42 143.53,141.78 J2.5
CONN_USB_RXN1: length 8.5
  BOTTOM w0.157: J1.5 124.61,141.78 124.61,141.42 125,141.04 126.41,141.04 126.99,140.46 126.99,140.23 126.89,140.13 U66.6 U66.5 126.89,137.17 126.74,137.02 126.74,137 126.47,136.73 FL38.3
CONN_USB_RXP0: length 8.5
  BOTTOM w0.157: J2.6 143.84,141.78 143.84,141.55 144.05,141.34 145.46,141.34 146.21,140.58 146.21,140.23 146.31,140.13 U65.7 U65.4 146.31,137.99 146.12,137.8 146.12,137.2 146.2,137.11 FL36.2
CONN_USB_RXP1: length 8.5
  BOTTOM w0.157: FL38.2 127.28,137.15 127.19,137.23 127.19,137.8 127.39,137.99 U66.4 U66.7 127.39,140.13 127.29,140.23 127.29,140.58 126.53,141.34 125.12,141.34 124.91,141.55 124.91,141.78 J1.6
CONN_USB_TXN0: length 8.4
  BOTTOM w0.157: J2.8 149.53,141.78 149.53,141.55 149.32,141.34 148.08,141.34 147.4,140.66 147.4,140.27 147.31,140.19 U65.9 U65.2 147.31,137.99 147.6,137.71 147.6,136.92 147.42,136.74 FL35.3
CONN_USB_TXN1: length 8.4
  BOTTOM w0.157: J1.8 130.61,141.78 130.61,141.55 130.4,141.34 129.16,141.34 128.47,140.66 128.47,140.27 128.39,140.19 U66.9 U66.2 128.39,137.99 128.68,137.71 128.68,136.92 128.5,136.74 FL37.3
CONN_USB_TXP0: length 8.3
  BOTTOM w0.157: J2.9 149.84,141.78 149.84,141.42 149.45,141.04 148.21,141.04 147.7,140.53 147.7,140.27 147.81,140.16 U65.10 U65.1 147.81,137.99 147.9,137.9 147.9,137.06 148.23,136.73 FL35.2
CONN_USB_TXP1: length 8.3
  BOTTOM w0.157: J1.9 130.91,141.78 130.91,141.42 130.53,141.04 129.29,141.04 128.78,140.53 128.78,140.27 128.89,140.16 U66.10 U66.1 128.89,137.99 128.98,137.9 128.98,137.33 129.31,137 FL37.2
CS_P: length 24.5
  TOP w0.203: R160.2 v2(186.94,62.35)
  L4-SIGNAL w0.305: v2(173.48,53.33) 174.62,53.33 175.01,53.71 175.01,54.22 176.02,55.23 178.31,55.23 183.26,60.19 183.26,63.49 184.28,64.51 185.67,64.51 186.44,63.74 186.44,62.85 v2(186.94,62.35)
  BOTTOM w0.305: v2(173.1,56.5) 172.34,57.27 C769.1
  vias: v2(173.1,55.36) v2(173.1,52.31) v2(173.1,51.17)
CSI0_RX0_N: length 59.7
  TOP w0.122: U37.B19 95.58,61.35 v1(95.18,60.95)
  L2-SIGNAL w0.102: v1(95.18,60.95) 94.81,60.58 94.81,59.11 93.98,58.28 93.98,52.19 91.52,49.72 91.52,47.85 91.69,47.67 92.34,47.67 92.71,47.3 92.71,46.78 92.34,46.4 91.69,46.4 91.52,46.23 91.52,45.97 91.69,45.8 92.34,45.8 92.71,45.42 92.71,44.9 92.34,44.53 91.69,44.53 91.52,44.35 91.52,41.59 85.73,35.8 v1(64.51,35.8)
  BOTTOM w0.122: U74.24 64.52,30.98 64.62,31.08 64.62,35.69 v1(64.51,35.8)
CSI0_RX0_P: length 59.7
  TOP w0.122: U37.A20 94.78,60.54 v1(94.38,60.14)
  L2-SIGNAL w0.102: v1(64.52,36.69) 64.52,36.31 64.64,36.18 64.67,36.18 64.72,36.13 85.6,36.13 91.19,41.72 91.19,44.48 91.56,44.86 92.2,44.86 92.38,45.03 92.38,45.29 92.2,45.46 91.56,45.46 91.19,45.84 91.19,46.36 91.56,46.73 92.2,46.73 92.38,46.91 92.38,47.17 92.2,47.34 91.56,47.34 91.19,47.72 91.19,49.86 93.65,52.32 93.65,58.42 94.48,59.25 94.48,59.86 94.38,59.96 v1(94.38,60.14)
  BOTTOM w0.122: v1(64.52,36.69) 64.9,36.31 64.9,31.1 65.02,30.98 U74.25
CSI0_RX1_N: length 60.1
  TOP w0.122: U37.D18 96.38,62.95 v1(95.98,62.55)
  L2-SIGNAL w0.102: v1(95.98,62.55) 95.61,62.18 95.61,61.59 95.89,61.31 96.13,61.31 96.34,61.1 96.34,60.79 95.89,60.33 95.89,58.03 95.96,57.95 95.96,54.99 95.96,52.77 93.6,50.41 93.6,43.93 93.23,43.56 92.76,43.56 92.58,43.38 92.58,43.13 92.76,42.95 93,42.95 93.4,42.55 93.4,41.38 86.6,34.58 74.12,34.58 73.33,33.8 70.63,33.8 69.89,34.53 v1(65.51,34.53)
  BOTTOM w0.122: U74.26 65.52,30.97 65.62,31.07 65.62,34.42 v1(65.51,34.53)
CSI0_RX1_P: length 60.1
  TOP w0.122: U37.C19 95.58,62.15 v1(95.18,61.75)
  L2-SIGNAL w0.102: v1(95.18,61.75) 95.18,61.56 95.61,61.13 95.61,60.52 95.55,60.47 95.55,57.89 95.63,57.82 95.63,55.13 95.63,52.91 93.27,50.55 93.27,44.07 93.09,43.89 92.62,43.89 92.25,43.52 92.25,42.99 92.62,42.62 92.86,42.62 93.07,42.42 93.07,41.52 86.46,34.91 73.98,34.91 73.19,34.13 70.76,34.13 70.03,34.86 67.66,34.86 67.48,35.04 67.48,35.27 67.31,35.45 67.05,35.45 66.87,35.27 66.87,35.04 66.7,34.86 65.74,34.86 65.53,35.07 v1(65.53,35.3)
  BOTTOM w0.122: v1(65.53,35.3) 65.9,34.93 65.9,31.12 66.02,31 U74.27
CSI0_RX2_N: length 59.3
  TOP w0.122: v1(96.78,62.55) 96.78,62.55 U37.D17
  L2-SIGNAL w0.102: v1(66.52,33.29) 69.58,33.29 70.37,32.5 83.2,32.5 83.66,32.96 84.01,32.96 84.46,32.5 86.49,32.5 94.77,40.78 94.77,50.18 97.1,52.52 97.1,58.59 96.77,58.92 96.77,60.36 96.98,60.56 96.98,61.41 96.97,61.42 97.14,61.59 97.14,61.9 96.93,62.11 96.7,62.11 96.59,62.22 96.59,62.36 v1(96.78,62.55)
  BOTTOM w0.122: v1(66.52,33.29) 66.64,33.18 66.64,31.06 66.52,30.95 U74.28
CSI0_RX2_P: length 59.3
  TOP w0.122: U37.C18 96.38,62.15 v1(95.98,61.75)
  L2-SIGNAL w0.102: v1(95.98,61.75) 96.2,61.96 96.27,61.96 96.41,61.82 96.41,61.53 96.54,61.39 96.65,61.28 96.65,60.7 96.44,60.49 96.44,58.78 96.77,58.45 96.77,52.65 94.44,50.32 94.44,40.92 86.35,32.83 84.6,32.83 84.14,33.29 83.53,33.29 83.07,32.83 70.51,32.83 69.72,33.62 67.94,33.62 67.77,33.8 67.46,33.8 67.28,33.62 66.95,33.62 v1(66.55,34.03)
  BOTTOM w0.122: U74.29 67.02,31.01 66.91,31.12 66.91,33.66 v1(66.55,34.03)
CSI0_RX3_N: length 59.9
  TOP w0.122: v1(97.58,63.35) 97.58,63.35 U37.E16
  L2-SIGNAL w0.102: v1(67.64,31.99) 68.07,32.43 68.53,32.43 69.94,31.02 69.98,31.02 86.93,31.02 95.87,39.96 95.87,49.57 98.12,51.81 98.12,59.11 97.76,59.46 97.76,59.76 97.98,59.97 97.98,60.32 97.84,60.46 97.84,62.12 97.97,62.25 97.97,62.67 97.73,62.91 97.48,62.91 97.36,63.03 97.36,63.13 v1(97.58,63.35)
  BOTTOM w0.122: U74.30 67.52,30.99 67.64,31.11 v1(67.64,31.99)
CSI0_RX3_P: length 59.9
  TOP w0.122: v1(96.78,63.35) 97.18,63.75 U37.E17
  L2-SIGNAL w0.102: v1(67.69,32.76) 68.67,32.76 70.07,31.35 86.8,31.35 95.54,40.09 95.54,49.7 97.79,51.95 97.79,58.97 97.43,59.32 97.43,59.77 97.21,59.99 97.21,60.3 97.51,60.6 97.51,62.09 97.21,62.39 97.21,62.72 97.03,62.9 97.03,63.08 97.03,63.09 v1(96.78,63.35)
  BOTTOM w0.122: U74.31 68.02,31.03 67.94,31.1 67.94,31.74 68.08,31.88 68.08,32.34 68.07,32.35 68.07,32.37 v1(67.69,32.76)
CSI0_RXCLK_N: length 56.6
  TOP w0.122: U37.B20 94.78,61.35 v1(94.38,60.95)
  L2-SIGNAL w0.102: v1(94.38,60.95) 94.38,60.67 94,60.29 94,59.53 91.64,57.17 91.64,51.66 91.64,51.25 90.42,50.03 90.42,42.51 85.24,37.33 v1(63.5,37.33)
  BOTTOM w0.122: U74.22 63.52,31 63.63,31.1 63.63,36.8 63.5,36.92 v1(63.5,37.33)
CSI0_RXCLK_P: length 56.6
  TOP w0.122: v1(93.58,60.14) 93.58,60.14 U37.A21
  L2-SIGNAL w0.102: v1(63.5,38.09) 63.93,37.66 64.16,37.66 64.26,37.76 64.26,37.89 64.36,37.99 64.64,37.99 64.74,37.89 64.74,37.76 64.85,37.66 85.11,37.66 90.09,42.65 90.09,50.17 91.31,51.38 91.31,51.52 91.31,51.52 91.31,57.3 93.65,59.64 93.65,60.07 v1(93.58,60.14)
  BOTTOM w0.122: U74.23 64.02,30.97 63.91,31.08 63.91,36.91 63.9,36.91 63.9,37.69 v1(63.5,38.09)
CSI0_RXRCALIB: length 3
  TOP w0.229: v1(97.58,64.15) 97.58,64.15 U37.F16
  BOTTOM w0.163: v1(97.58,64.15) 97.98,63.75 97.98,63.18 98.21,62.95 99.19,62.95 R366.1
CSI1_RXRCALIB: length 1.5
  TOP w0.229: U37.F15 98.78,64.55 v1(98.38,64.15)
  BOTTOM w0.163: R358.1 99.19,63.89 98.63,63.89 v1(98.38,64.15)
D3B: length 10.5
  TOP w0.191: C68.1 L25.2 44.45,122.54 46.22,120.78 U19.10
DDR0_CAL0: length 0.8
  TOP w0.229: U37.H2 v1(109.58,65.75)
  BOTTOM w0.229: v1(109.58,65.75) 109.58,65.72 109.72,65.6 109.75,65.58
DEBUGN: length 12.4
  TOP w0.191: v1(45.21,102.73) 44.72,103.23 U19.54
  L5-SIGNAL w0.163: v1(45.21,102.73) 45.84,102.73 47.11,104 53.47,104 J10.3
DEBUGP: length 11.1
  TOP w0.191: U19.55 v1(45.22,103.5)
  L5-SIGNAL w0.163: J10.1 53.85,104.38 46.1,104.38 v1(45.22,103.5)
DOUT0: length 4.9
  TOP w0.191: U23.2 50.55,101.97 49.66,102.86 48.64,102.86 48.22,103.28 U19.61
DOUT1: length 3.8
  TOP w0.191: U19.58 46.72,103.26 48.01,101.97 U22.2
DP0_AUX_N: length 1.4
  TOP w0.122: C401.2 129.67,24.41 129.67,23.99 129.39,23.71 FL26.4
DP0_AUX_P: length 1.4
  TOP w0.122: FL26.1 130.2,23.74 129.95,23.99 129.95,24.44 C402.2
DP0_CONFIG1: length 4
  TOP w0.191: v1(133.62,11.2) 133.34,11.48 J18.13
  BOTTOM w0.191: R456.1 v1(133.62,11.2)
DP0_CONFIG2: length 2.7
  TOP w0.191: J18.14 v1(132.84,11.86)
  BOTTOM w0.191: R457.1 132.48,12.23 v1(132.84,11.86)
DP0_HPD: length 90.3
  TOP w0.229: U37.Y4 107.98,76.14 v1(107.98,76.15)
  L4-SIGNAL w0.163: v1(107.98,76.15) 108.38,75.75 108.38,74.38 108.14,74.15 107.81,74.15 107.58,73.91 107.58,73.89 107.58,73.89 107.58,73.58 107.35,73.35 106.92,73.35 105.98,72.41 105.98,71.98 105.75,71.75 105.32,71.75 105.18,71.61 105.18,71.18 104.95,70.95 103.02,70.95 102.78,70.71 102.78,64.31 101.98,63.51 101.98,63.11 101.82,62.94 101.41,62.94 101.18,62.71 101.18,59.98 100.9,59.7 100.9,49.96 102.62,48.25 102.62,46.98 117.35,32.25 120.65,32.25 122.43,30.47 122.43,23.23 126.62,19.04 v1(128.4,19.04)
  L5-SIGNAL w0.163: v1(128.4,19.04) 131.4,16.03 131.4,10.2 v1(131.1,9.9)
  BOTTOM w0.191: v1(131.1,9.9) 131.08,9.87 Q15.3 131.99,9.1 R465.1
DP0_TX0_N: length 1.4
  TOP w0.122: C427.2 141.6,21.11 141.6,20.74 141.31,20.44 FL31.4
DP0_TX0_P: length 1.4
  TOP w0.122: C428.2 141.88,21.14 141.88,20.72 142.12,20.48 FL31.1
DP0_TX1_N: length 1.4
  TOP w0.122: FL28.4 138.38,22.04 138.63,22.29 138.63,22.81 C411.2
DP0_TX1_P: length 1.4
  TOP w0.122: C412.2 138.91,22.74 138.91,22.37 139.2,22.08 FL28.1
DP0_TX2_N: length 1.4
  TOP w0.122: FL30.4 135.46,20.39 135.74,20.67 135.74,21.14 C425.2
DP0_TX2_P: length 1.4
  TOP w0.122: C426.2 136.02,21.11 136.02,20.69 136.28,20.43 FL30.1
DP0_TX3_N: length 1.3
  TOP w0.122: C413.2 132.69,22.66 132.69,22.34 132.44,22.09 FL29.4
DP0_TX3_P: length 1.3
  TOP w0.122: FL29.1 133.25,22.09 132.97,22.37 132.97,22.63 C414.2
DSI0_TX0_N: length 40.2
  TOP w0.122: v1(102.38,62.55) 101.98,62.95 U37.D11
  L2-SIGNAL w0.102: v1(102.38,62.55) 101.98,62.15 101.98,61.58 102.25,61.31 102.53,61.31 102.81,61.03 102.81,59.95 103.2,59.56 103.2,53.85 104.98,52.07 104.98,38.7 109.55,34.13 109.55,32.24 109.11,31.8 108.77,31.8 v1(108.58,31.61)
  BOTTOM w0.122: v1(108.58,31.61) 108.81,31.84 108.94,31.84 109.06,31.72 109.06,28.43 108.96,28.32 U75.57
DSI0_TX0_P: length 40.2
  TOP w0.122: U37.C12 v1(101.58,61.75)
  L2-SIGNAL w0.102: v1(101.58,61.75) 101.58,61.59 101.58,61.47 102.01,61.03 102.01,59.99 102.23,59.78 102.52,59.78 102.87,59.43 102.87,59.2 102.73,59.06 102.35,59.06 102.21,58.92 102.21,58.71 102.35,58.57 102.73,58.57 102.87,58.43 102.87,53.71 104.65,51.93 104.65,38.56 109.22,33.99 109.22,32.37 108.97,32.13 108.83,32.13 v1(108.58,32.37)
  BOTTOM w0.122: U75.58 109.46,28.32 109.34,28.44 109.34,31.84 109.06,32.12 108.84,32.12 v1(108.58,32.37)
DSI0_TX1_N: length 40.1
  TOP w0.122: U37.D12 101.18,62.95 v1(101.58,62.55)
  L2-SIGNAL w0.102: v1(106.81,31.23) 107.09,31.51 107.31,31.51 107.72,31.93 107.72,34.13 103.7,38.15 103.7,51.7 102.11,53.29 102.11,58.19 101.15,59.15 101.15,60.3 101.18,60.33 101.18,62.15 v1(101.58,62.55)
  BOTTOM w0.122: v1(106.81,31.23) 106.81,31.26 107.09,31.55 107.38,31.55 108.08,30.85 108.08,28.44 107.96,28.32 U75.55
DSI0_TX1_P: length 40.2
  TOP w0.122: U37.C13 100.38,62.15 v1(100.78,61.75)
  L2-SIGNAL w0.102: v1(106.81,31.99) 106.96,31.84 107.17,31.84 107.39,32.06 107.39,33.99 103.37,38.02 103.37,51.56 101.78,53.15 101.78,58.05 101.52,58.31 101.32,58.31 101.1,58.09 100.9,58.09 100.76,58.23 100.76,58.43 100.98,58.65 100.98,58.85 100.82,59.01 100.82,59.59 100.41,59.99 100.41,60.3 100.85,60.74 100.85,61.68 v1(100.78,61.75)
  BOTTOM w0.122: U75.56 108.46,28.32 108.34,28.44 108.34,30.95 107.49,31.81 106.99,31.81 v1(106.81,31.99)
DSI0_TX2_N: length 39
  TOP w0.122: v1(99.98,60.95) 100.38,61.35 U37.B13
  L2-SIGNAL w0.102: v1(105.67,32.12) 105.38,32.41 105.01,32.41 101.87,35.56 101.87,36.03 102.3,36.46 102.3,36.66 102.16,36.81 101.96,36.81 101.53,36.37 101.05,36.37 100.51,36.92 100.51,55.18 99.58,56.12 99.58,59.79 99.45,59.92 99.45,60.37 99.72,60.64 99.72,60.69 v1(99.98,60.95)
  BOTTOM w0.122: U75.53 106.96,28.32 107.06,28.43 107.06,29.81 105.66,31.21 105.66,32.12 v1(105.67,32.12)
DSI0_TX2_P: length 39
  TOP w0.122: U37.A14 v1(99.98,60.14)
  L2-SIGNAL w0.102: v1(99.98,60.14) 99.98,60.04 99.91,59.97 99.91,56.25 100.13,56.02 100.33,56.02 100.49,56.18 100.68,56.18 100.83,56.03 100.83,55.83 100.68,55.68 100.68,55.48 100.84,55.32 100.84,37.05 101.19,36.7 101.39,36.7 101.83,37.14 102.3,37.14 102.63,36.8 102.63,36.33 102.2,35.89 102.2,35.69 105.15,32.74 105.52,32.74 v1(105.66,32.88)
  BOTTOM w0.122: v1(105.66,32.88) 106.1,32.45 106.1,31.97 105.94,31.81 105.94,31.32 107.34,29.92 107.34,28.44 107.46,28.32 U75.54
DSI0_TX3_N: length 38.4
  TOP w0.122: v1(99.18,60.95) 99.58,61.35 U37.B14
  L2-SIGNAL w0.102: v1(99.18,60.95) 98.84,60.61 98.84,60.14 99.07,59.92 99.07,55.26 99.85,54.48 99.85,36.5 105.04,31.31 105.87,31.31 106.88,30.29 106.88,29.78 106.5,29.4 106.12,29.4 v1(105.92,29.2)
  BOTTOM w0.122: v1(105.92,29.2) 106.08,29.04 106.08,28.44 105.96,28.32 U75.51
DSI0_TX3_P: length 38.4
  TOP w0.122: v1(98.38,60.14) 98.78,60.54 U37.A15
  L2-SIGNAL w0.102: v1(105.92,29.96) 106.15,29.73 106.37,29.73 106.55,29.92 106.55,30.16 105.73,30.98 104.9,30.98 99.52,36.36 99.52,54.35 99.35,54.51 99.16,54.51 99.05,54.4 98.85,54.4 98.71,54.54 98.71,54.74 98.81,54.85 98.81,55.05 98.74,55.13 98.74,59.78 v1(98.38,60.14)
  BOTTOM w0.122: v1(105.92,29.96) 106.34,29.54 106.34,28.44 106.46,28.32 U75.52
DSI0_TXCLK_N: length 41.7
  TOP w0.122: U37.E10 v1(103.18,63.35)
  L2-SIGNAL w0.102: v1(111,31.36) 110.99,31.36 110.81,31.18 110.54,31.18 110.36,31.36 110.36,31.61 110.69,31.94 110.69,34.87 106.25,39.32 106.25,52.83 104.35,54.73 104.35,60.3 104.16,60.49 104.16,60.6 104.35,60.79 104.35,61.1 104.13,61.31 103.99,61.31 103.33,61.97 103.33,62.18 103.55,62.39 103.55,62.7 103.33,62.91 103,62.91 102.88,63.03 102.88,63.05 v1(103.18,63.35)
  BOTTOM w0.122: v1(111,31.36) 110.99,31.36 110.72,31.09 110.36,31.09 110.08,30.82 110.08,28.45 109.96,28.32 U75.59
DSI0_TXCLK_P: length 41.7
  TOP w0.122: U37.E11 v1(102.38,63.35)
  L2-SIGNAL w0.102: v1(102.38,63.35) 102.55,63.17 102.55,62.89 102.81,62.63 102.81,62.39 103,62.2 103,61.83 103.61,61.22 103.61,60.79 103.83,60.58 103.83,60.51 103.61,60.3 103.61,59.99 104.02,59.59 104.02,59.36 103.88,59.22 103.8,59.22 103.66,59.08 103.66,58.87 103.8,58.73 103.88,58.73 104.02,58.59 104.02,54.6 105.92,52.7 105.92,39.18 110.36,34.74 110.36,32.08 110.03,31.75 110.03,31.22 110.4,30.85 110.74,30.85 v1(111,30.6)
  BOTTOM w0.122: U75.60 110.46,28.32 110.36,28.42 110.36,30.7 110.48,30.81 110.78,30.81 v1(111,30.6)
DSI_TX_CALIB: length 0.6
  TOP w0.229: U37.F12 v1(101.58,64.15)
DSI_UB981_INTB: length 143.5
  TOP w0.191: v1(116.52,21.95) 114.83,21.95 112.79,23.99 104.65,23.99 104.44,23.79 104.44,18.13 104.46,18.12 104.46,17.75 104.44,17.74 104.44,17.72 104.65,17.52 v1(104.65,14.85)
  TOP w0.229: U37.AC4 107.98,78.54 v1(107.98,78.55)
  L2-SIGNAL w0.107: v1(138.68,26.94) 139.07,27.33 139.07,41.78 139.7,42.41 139.7,43.04 138.94,43.81 138.94,51.93 143.51,56.5 143.51,80.13 142.62,81.02 v1(142.62,81.65)
  L4-SIGNAL w0.163: v1(142.62,81.65) 142.31,81.96 141.28,81.96 140.72,81.4 130.23,81.4 129.65,81.98 122.63,81.98 121.35,80.7 114.61,80.7 114.4,80.92 112.86,80.92 112.62,80.68 112.62,80.6 111.13,79.11 110.24,79.11 110.13,79.21 108.64,79.21 v1(107.98,78.55)
  L5-SIGNAL w0.163: v1(138.68,26.94) 131.86,26.94 128.27,23.36 117.93,23.36 v1(116.52,21.95)
  BOTTOM w0.191: v1(104.65,14.85) 105.16,14.34 R455.2 ; R437.2 v1(116.52,21.95)
EMU_RSTN: length 81.9
  TOP w0.191: v1(83.19,59.93) R157.2 R156.2 ; v1(145.54,41.52) 145.31,41.29 J15.6
  L5-SIGNAL w0.163: v1(145.54,41.52) 144.53,40.5 138.43,40.5 135.89,43.04 126.36,43.04 125.06,41.74 91.73,41.74 87.53,45.93 87.53,53.3 84.96,55.87 84.96,58.16 v1(83.19,59.93)
EN_3V3IO_LDSW: length 240.1
  TOP w0.191: U54.13 157.33,31.71 v1(157.48,31.87) ; Q6.G v1(155.7,52.11) ; U46.1 v2(191.77,47.74)
  TOP w0.229: U20.53 v1(78.33,103.14) ; U28.3 168.88,95.52 168.71,95.7 R84.2 168.21,95.05 v1(168.15,94.99)
  L2-SIGNAL w0.107: v1(157.48,31.87) 157.48,35.68 155.7,37.45 v1(155.7,52.11) 155.7,52.82 155.83,52.95 155.83,66.66 165.35,76.19 165.35,94.35 165.99,94.99 v1(168.15,94.99)
  L4-SIGNAL w0.163: v1(155.7,52.11) 164.54,52.11 166.5,50.15 178.56,50.15 179.07,49.65 186.31,49.65 188.21,47.74 v2(191.77,47.74)
  L7-SIGNAL w0.107: v1(78.33,103.14) 77.85,103.62 74.17,103.62 73.79,104 73.79,109.72 74.93,110.86 78.61,110.86 79.63,111.88 84.58,111.88 84.96,111.5 84.96,111.11 93.6,102.48 96.52,102.48 103,108.96 119,108.96 124.71,114.67 150.88,114.67 163.7,101.84 163.7,99.43 v1(168.15,94.99)
EN_DRV_OUT: length 4.9
  TOP w0.191: TP34.1 126.62,91.05 128.2,92.62 U27.29
EN_MCU3V3IO_LDSW: length 107.6
  L4-SIGNAL w0.163: v1(64.46,99.74) 66.04,98.16 v1(67.94,98.16)
  L7-SIGNAL w0.107: v1(67.94,98.16) 77.6,98.16 78.36,98.92 78.36,101.21 79.25,102.1 79.25,104.51 78.87,104.89 75.31,104.89 75.06,105.15 75.06,108.83 74.68,109.21 74.68,109.72 75.31,110.35 79.12,110.35 79.5,110.73 82.68,110.73 83.26,110.15 85.16,110.15 93.34,101.97 97.16,101.97 97.28,102.1 99.57,102.1 102.74,105.27 103.12,105.27 104.39,106.54 105.12,106.54 105.12,106.54 105.44,106.54 105.44,106.54 114.55,106.54 118.11,102.99 118.11,98.92 119.54,97.49 125.44,97.49 126.24,98.29 127.38,98.29 128.78,96.89 128.78,95.11 129.16,94.73 130.68,94.73 131.19,94.22 v1(134.62,94.22)
  BOTTOM w0.191: R289.2 v1(64.46,99.74) U68.3 ; R294.1 134.75,94.35 134.62,94.22 v1(134.62,94.22)
ENET_EN: length 59.8
  TOP w0.229: v1(88.78,72.15) 89.18,72.55 U37.T27
  L4-SIGNAL w0.163: v1(41.78,72) 41.78,63.62 v2(41.53,63.36)
  L7-SIGNAL w0.107: v1(88.78,72.15) 87.91,73.01 84.07,73.01 82.8,74.28 76.58,74.28 75.44,75.43 45.21,75.43 v1(41.78,72)
  BOTTOM w0.191: v2(41.53,63.36) R364.1
ENET_INH: length 74.5
  TOP w0.191: U42.10 37.87,60.89 37.85,60.91 v2(37.85,62.22)
  TOP w0.229: U37.W23 v1(91.98,75.35)
  L4-SIGNAL w0.163: v1(38.48,78.09) 38.48,66.41 37.85,65.78 37.85,63.85 37.9,63.8 37.9,63.44 37.85,63.38 v2(37.85,62.22)
  L7-SIGNAL w0.107: v1(38.48,78.09) 43.18,78.09 43.81,78.73 71.25,78.73 72.71,77.27 78.9,77.27 78.96,77.2 79.28,77.2 79.34,77.27 81.44,77.27 81.5,77.2 81.82,77.2 81.88,77.27 84.14,77.27 84.84,76.57 90.75,76.57 v1(91.98,75.35)
  BOTTOM w0.191: v2(37.85,62.22) R369.1
ENET_INTSN: length 62.2
  TOP w0.229: U37.V23 v1(91.98,74.55)
  L2-SIGNAL w0.107: v1(45.34,76.57) v1(45.34,64.76)
  L7-SIGNAL w0.107: v1(45.34,76.57) 67.91,76.57 67.91,76.57 68.23,76.57 68.23,76.57 69.94,76.57 69.94,76.57 70.26,76.57 70.27,76.57 71.25,76.57 71.59,76.22 82.39,76.22 84.45,74.16 91.58,74.16 v1(91.98,74.55)
  BOTTOM w0.191: v1(45.34,64.76) R362.1 R363.1
ENET_WAKE: length 72.8
  TOP w0.191: U42.8 v2(39.27,62.22)
  TOP w0.229: U37.Y23 v1(91.98,76.15)
  L4-SIGNAL w0.163: v2(39.27,62.22) v1(39.27,78.73)
  L7-SIGNAL w0.107: v1(91.98,76.15) 90.79,77.33 84.96,77.33 83.19,79.11 43.43,79.11 43.05,78.73 v1(39.27,78.73)
  BOTTOM w0.191: v2(39.27,62.22) 39,61.95 39,61.47 R368.1
EXT_TDI: length 4.8
  TOP w0.191: U48.2 145.67,49.05 145.33,48.71 145.33,46.93 145.31,46.91 J15.5
EXT_TDO: length 16.8
  TOP w0.191: v1(146.26,41.52) 145.81,41.07 J15.4 ; U47.4 v1(143.53,52.95)
  BOTTOM w0.191: v1(146.26,41.52) 146.26,42.87 148.08,44.69 148.08,46.6 143.53,51.16 v1(143.53,52.95)
EXT_TMS: length 11.9
  TOP w0.191: J15.2 146.87,39.8 148.84,41.77 148.84,48.38 148.46,48.76 U49.2
FB: length 7.5
  TOP w0.203: v2(194.44,57.9) R167.1 ; U46.11 193.66,54.97 194.06,55.36 v2(194.44,55.36) R175.2
  L4-SIGNAL w0.163: v2(194.44,55.36) v2(194.44,57.9)
FB_5141: length 3.7
  TOP w0.191: U33.19 195.43,82.95 196.72,81.65 R123.2 R124.1
FMA: length 14.9
  TOP w0.191: C71.1 54.99,123.81 L26.2 C79.1 53.72,120.89 48.9,120.89 47.22,119.21 U19.8
FMB: length 14.2
  TOP w0.191: U19.11 45.72,119.75 42.16,123.31 C77.1 39.24,124.7 39.37,124.83 C67.1
FPD_DOUT0_N: length 6.4
  BOTTOM w0.122: FL41.3 109.12,10.75 108.84,10.47 108.84,8.25 108.58,7.99 108.58,6.59 J16.3
FPD_DOUT0_P: length 4.3
  BOTTOM w0.122: J16.1 108.58,8.6 108.58,10.47 108.31,10.75 FL41.2
G720_VDD1A: length 4.7
  TOP w0.305: 38.61,62.47 38.61,61.97 38.77,61.81 U42.9
  TOP w0.508: C307.1 37.21,62.6 37.57,62.96 38.13,62.96 38.61,62.47
  TOP w0.635: R152.1 35.69,62.6 C307.1
G720_VDD1B: length 5.2
  TOP w0.254: U42.21 39.77,55.25 39.33,54.82 39.2,54.82
  TOP w0.635: 39.2,54.82 38.73,54.35 C332.1 35.94,53.84 R176.1
G720_VDDIO: length 3
  TOP w0.305: U42.34 v2(44.96,59.54) 44.97,59.55 R165.1
  BOTTOM w0.305: C768.1 44.69,59.54 v2(44.96,59.54)
G720_VSLEEP: length 3.4
  TOP w0.305: v2(40.13,62.22) 39.77,61.86 U42.7
  BOTTOM w0.305: v2(40.13,62.22) 39.75,62.6 R364.2 39.88,63.49 R357.1
H_DDR_RET_1V1: length 130.4
  TOP w0.191: R132.2 121.42,77.12 v1(121.71,77.41)
  TOP w0.229: U20.47 75.33,101.82 v1(75.51,101.64) ; U37.P6 v1(106.38,70.55)
  L2-SIGNAL w0.107: v1(123.13,105.84) 128.65,100.32 128.65,93.97 128.31,93.63 128.31,81.36 128.78,80.89 128.78,79.88 127.26,78.35 122.65,78.35 v1(121.71,77.41)
  L7-SIGNAL w0.107: v1(75.51,101.64) 76.33,100.83 77.47,100.83 78.87,102.22 78.87,103.37 78.36,103.88 74.37,103.88 74.14,104.11 74.14,109.56 75.22,110.64 78.9,110.64 79.63,111.37 83.44,111.37 83.75,111.06 84.64,111.06 93.47,102.22 96.77,102.22 103,108.45 116.08,108.45 118.68,105.84 v1(123.13,105.84) ; v1(106.38,70.55) 106.75,70.92 111.95,70.92 118.15,77.12 121.32,77.12 121.34,77.13 121.43,77.13 v1(121.71,77.41)
H_MCU_INT#: length 188.6
  TOP w0.191: U27.14 128.2,102.43 v1(128.04,102.58) ; R151.2 80.75,64.4 v1(80.52,64.63)
  TOP w0.229: v1(81.76,109.82) 81.61,109.67 U20.14
  L2-SIGNAL w0.107: v1(115.76,104.19) 117.54,104.19 119.63,106.29 123.44,106.29 127.15,102.58 v1(128.04,102.58) ; v1(80.52,64.63) 64.01,64.63 58.04,70.6 v1(58.04,90.54)
  L5-SIGNAL w0.163: v1(86.05,108.25) 89.71,108.25 93.85,112.38 93.85,113.53 90.93,116.45 88.9,116.45 85.82,119.53 85.82,122.96 84.45,124.32 61.47,124.32 58.29,121.15 58.29,104.64 58.04,104.38 v1(58.04,90.54)
  L7-SIGNAL w0.107: v1(115.76,104.19) 114.68,105.27 104.78,105.27 100.08,100.57 93.73,100.57 v1(86.05,108.25) 85.22,109.08 82.5,109.08 v1(81.76,109.82)
  BOTTOM w0.191: v1(128.04,102.58) 128.02,102.61 R284.1
H_MCU_PORZ_1V8: length 170.8
  TOP w0.191: U27.25 v1(128.17,95.65) ; U45.2 TP55.1
  TOP w0.229: v1(91.98,65.75) 92.38,66.15 U37.H23
  L2-SIGNAL w0.107: v1(144.53,81.4) 145.92,80 145.92,77.08 145.41,76.57 145.41,55.87 144.15,54.6 144.15,49.01 143.51,48.38 143.51,42.53 141.99,41.01 v1(141.99,38.09)
  L4-SIGNAL w0.163: TP55.1 83.57,58.79 87.35,58.79 88.37,59.82 88.37,60.31 88.37,60.31 88.37,60.55 89.18,61.35 89.18,61.91 89.41,62.15 89.77,62.15 89.97,62.35 89.97,62.71 90.21,62.95 90.54,62.95 90.77,63.18 90.77,63.51 91.01,63.74 91.34,63.74 91.58,63.98 91.58,65.35 v1(91.98,65.75)
  L5-SIGNAL w0.163: v1(144.53,81.4) 144.1,81.4 141.43,84.06 129.67,84.06 128.17,85.56 v1(128.17,95.65) ; v1(141.99,38.09) 141.1,38.98 138.43,38.98 135.13,42.28 126.87,42.28 125.19,40.6 88.81,40.6 85.34,44.06 85.34,53.58 83.44,55.49 TP55.1
  BOTTOM w0.191: R381.1 TP55.1
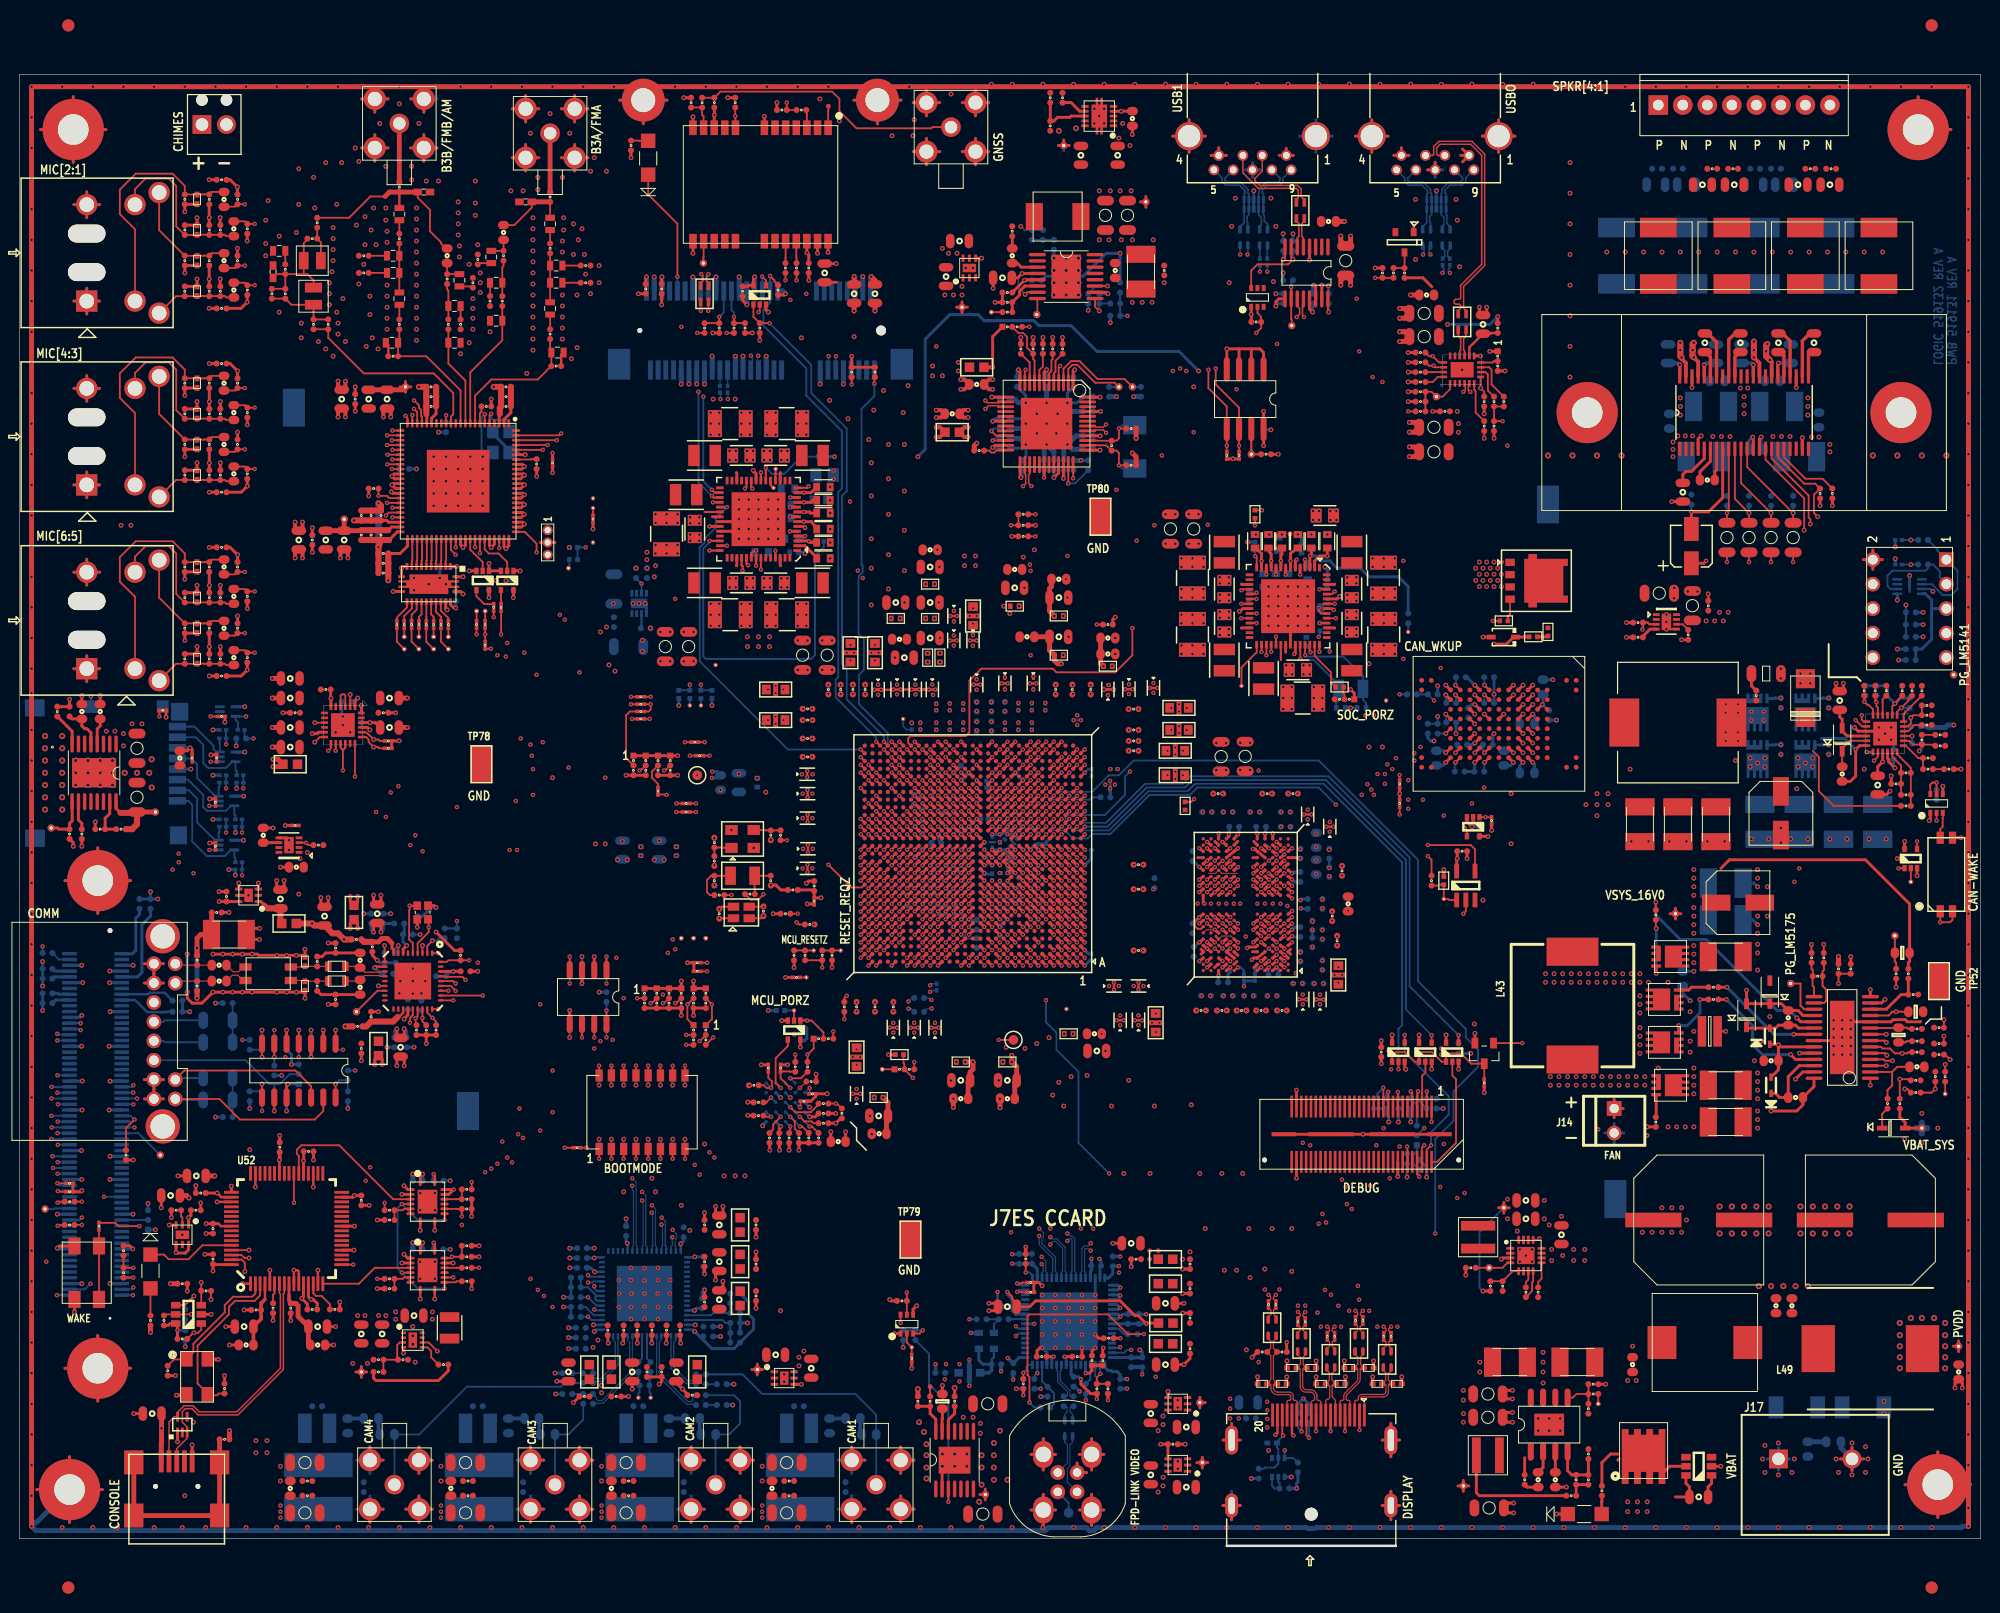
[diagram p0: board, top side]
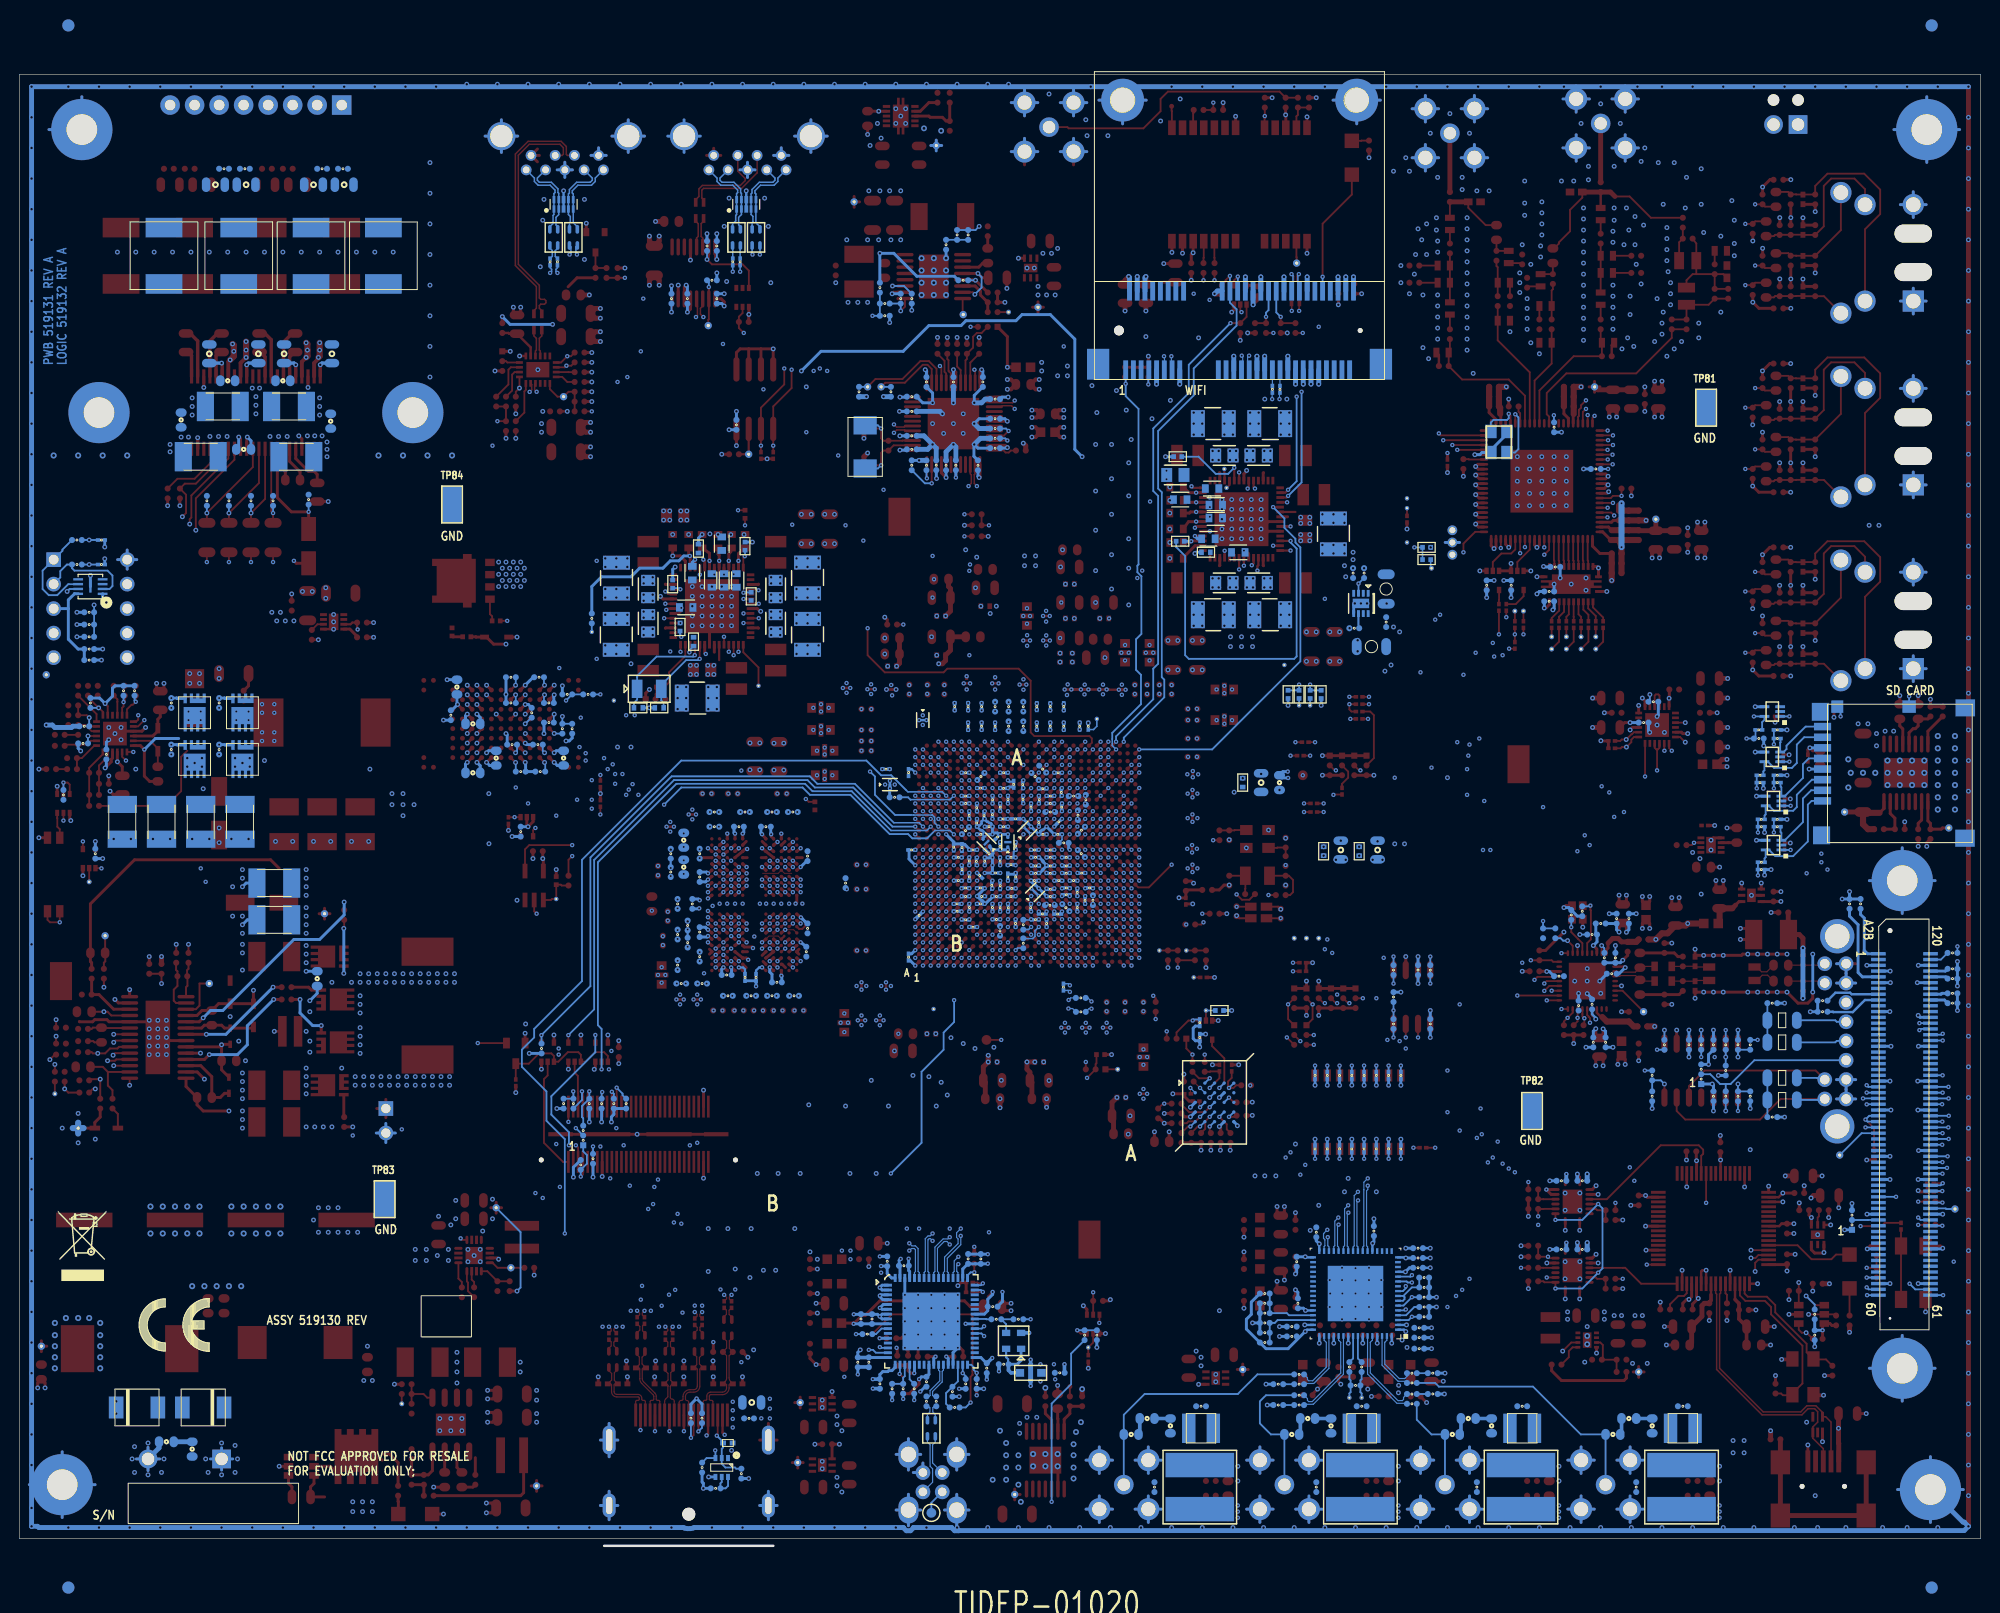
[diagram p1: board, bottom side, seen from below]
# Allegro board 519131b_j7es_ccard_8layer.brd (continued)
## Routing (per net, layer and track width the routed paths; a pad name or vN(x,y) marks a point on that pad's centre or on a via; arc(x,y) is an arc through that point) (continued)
H_MCU_SAFETY_ERRZ: length 102.9
  TOP w0.191: R174.2 v1(85.47,54.6) ; U77.2 149.86,65.78 v1(149.61,65.52)
  L2-SIGNAL w0.107: v1(149.61,65.52) 149.61,43.68 v1(147.58,41.65)
  L5-SIGNAL w0.163: v1(85.47,54.6) 85.47,53.85 85.72,53.59 85.72,44.31 88.93,41.11 125.06,41.11 126.62,42.66 135.51,42.66 138.05,40.12 144.78,40.12 145.54,40.88 146.81,40.88 v1(147.58,41.65)
H_MMC1_CLK: length 77
  TOP w0.229: U37.P25 90.78,70.95 v1(90.38,70.55)
  L5-SIGNAL w0.163: v1(90.38,70.55) 89.98,70.94 89.98,72.41 89.53,72.85 86.95,72.85 86.87,72.76 82.42,72.76 82.14,73.05 81.12,73.05 79.82,71.74 73.79,71.74 73.15,72.38 71.37,72.38 70.74,73.01 67.44,73.01 67.01,72.59 65.58,72.59 65.15,73.01 63.88,73.01 63.46,72.59 61.89,72.59 61.21,73.27 58.67,73.27 58.55,73.14 31.11,73.14 27.05,77.21 22.73,77.21 v1(21.42,78.51)
  BOTTOM w0.191: v1(21.42,78.51) R340.1 R336.2
H_MMC1_CMD: length 69
  TOP w0.229: v1(87.18,71.35) 87.58,71.75 U37.R29
  L5-SIGNAL w0.163: v1(87.18,71.35) 85.96,71.35 84.04,69.43 81.18,69.43 80.52,70.09 70.1,70.09 69.72,69.71 28.57,69.71 24.35,73.94 v1(23.08,73.94)
  BOTTOM w0.191: v1(23.08,73.94) R346.2 R344.1
H_MMC1_D0: length 73.9
  TOP w0.229: v1(91.18,71.35) 91.18,71.35 U37.R24
  L5-SIGNAL w0.163: v1(23.2,78.51) 26.63,78.51 30.86,74.28 72.52,74.28 73.41,73.4 74.68,73.4 74.93,73.65 78.87,73.65 79.12,73.9 86.62,73.9 86.79,73.74 86.79,73.59 87.02,73.35 90.09,73.35 90.78,72.66 90.78,71.75 v1(91.18,71.35)
  BOTTOM w0.191: R335.1 R339.2 v1(23.2,78.51)
H_MMC1_D1: length 79.1
  TOP w0.229: U37.P24 91.18,70.55 v1(91.18,70.55)
  L5-SIGNAL w0.163: v1(21.42,83.09) 25.53,78.98 27.05,78.98 31.37,74.67 77.6,74.67 77.98,74.28 86.87,74.28 87,74.15 90.56,74.15 90.79,73.92 90.79,73.41 91.57,72.63 91.57,72.32 91.57,72.31 91.57,71.98 91.57,71.98 91.57,71.52 91.57,71.51 91.57,71.18 91.57,71.18 91.57,70.94 v1(91.18,70.55)
  BOTTOM w0.191: R320.2 R322.1 v1(21.42,83.09)
H_MMC1_D2: length 72.6
  TOP w0.229: U37.R25 90.78,71.75 v1(90.38,71.35)
  L5-SIGNAL w0.163: v1(90.38,71.35) 90.77,70.95 90.77,70.38 90.54,70.15 89.99,70.15 89.15,70.98 87.37,70.98 87.34,70.95 86.06,70.95 84.26,69.15 80.83,69.15 80.26,69.71 70.36,69.71 69.72,69.08 28.45,69.08 28.03,69.5 v1(23.08,69.5)
  BOTTOM w0.191: v1(23.08,69.5) R351.2 R350.1
H_MMC1_D3: length 73.3
  TOP w0.229: U37.R26 89.58,71.35 v1(89.58,71.35)
  L5-SIGNAL w0.163: v1(89.58,71.35) 89.18,71.75 83.82,71.75 83.16,71.09 80.62,71.09 80.08,70.54 72.96,70.54 72.53,70.97 70.35,70.97 69.6,70.22 28.83,70.22 24.51,74.54 22.02,74.54 v1(21.42,73.94)
  BOTTOM w0.191: v1(21.42,73.94) R347.1 R345.2
H_MMC1_SDCD: length 79.5
  TOP w0.229: U37.P23 92.38,70.95 v1(91.98,70.55)
  L5-SIGNAL w0.163: v1(24.26,83.68) 24.26,81.52 26.29,79.49 27.43,79.49 31.85,75.07 78.21,75.07 78.64,74.64 82.27,74.64 82.58,74.95 91.34,74.95 91.57,74.71 91.57,73.92 91.58,73.92 91.58,73.51 92.37,72.72 92.37,70.98 92.27,70.88 92.27,70.84 v1(91.98,70.55)
  BOTTOM w0.191: v1(24.26,83.68) 23.5,83.68 23.33,83.85 R319.1
H_PMIC_POWER_EN1: length 17.5
  TOP w0.191: RJ17.3 v1(92.71,50.15)
  TOP w0.229: v1(91.98,64.95) 91.98,64.95 U37.G23
  L5-SIGNAL w0.163: v1(91.98,64.95) 92.37,64.55 92.37,58.36 93.22,57.52 93.22,55.23 93.98,54.47 93.98,52.31 92.71,51.04 v1(92.71,50.15)
H_SOC_PORZ_1V8: length 119.4
  TOP w0.191: U27.53 v1(134.72,99.15)
  TOP w0.229: v1(91.18,66.55) 91.18,66.55 U37.J24
  L2-SIGNAL w0.107: v1(141.86,51.3) 141.86,51.71 141.73,51.83 141.73,53.2 144.65,56.12 144.65,77.08 144.53,77.21 144.53,79.62 143.26,80.89 143.26,85.97 TP35.1
  L5-SIGNAL w0.163: v1(134.72,99.15) 135.64,98.23 135.64,94.86 139.62,90.03 140.08,90.03 141.6,88.51 TP35.1 ; v1(91.18,66.55) 91.58,66.95 92.14,66.95 92.38,66.71 92.38,66.38 92.61,66.15 92.94,66.15 93.18,65.91 93.18,65.58 93.41,65.35 93.74,65.35 93.98,65.11 93.98,64.78 94.21,64.55 94.54,64.55 94.77,64.31 94.77,59.14 96.65,57.27 96.65,54.35 101.35,49.65 106.05,49.65 107.06,50.66 139.19,50.66 139.83,51.3 v1(141.86,51.3)
  BOTTOM w0.191: v1(134.72,99.15) 134.83,99.26 R290.1
HDRV1_N: length 20.3
  TOP w0.305: v2(181.48,45.07) 184.15,45.07 184.78,45.71 C361.2 185.93,47.61 U46.28
  L4-SIGNAL w0.305: v2(169.8,49.52) 173.61,45.71 180.85,45.71 v2(181.48,45.07)
  vias: v2(158.62,48.63) v2(158.62,47.74) v2(159.51,48.63) v2(159.51,47.74) v2(160.4,48.63) v2(160.4,47.74) v2(161.29,48.63) v2(161.29,47.74) v2(162.18,48.63) v2(162.18,47.74) v2(163.07,48.63) v2(163.07,47.74) v2(163.96,48.63) v2(163.96,47.74) v2(164.85,48.63) v2(164.85,47.74) v2(165.74,48.63) v2(165.74,47.74) v2(166.62,48.63) v2(166.62,47.74) v2(167.51,48.63) v2(167.51,47.74) v2(167.89,53.71) v2(167.89,52.82) v2(167.89,51.93) v2(167.89,51.04) v2(168.4,48.63) v2(168.4,47.74)
HDRV1_P: length 22.5
  TOP w0.305: R202.2 v2(168.66,43.42) ; U46.27 184.76,49.12 v2(184.02,48.38)
  L4-SIGNAL w0.305: v2(168.66,43.42) 169.42,42.66 180.59,42.66 184.02,46.09 v2(184.02,48.38)
HDRV2_N: length 17.7
  TOP w0.305: v2(178.94,57.58) D10.2 178.97,56.2 D9.1 182.55,56.2 C333.1 184.28,55.49 184.8,54.97 U46.18
  L5-SIGNAL w0.305: v2(170.81,58.41) 172.02,57.21 178.57,57.21 v2(178.94,57.58)
  vias: v2(158.12,59.3) v2(158.12,58.41) v2(159,59.3) v2(159,58.41) v2(159.89,59.3) v2(159.89,58.41) v2(160.78,59.3) v2(160.78,58.41) v2(161.67,59.3) v2(161.67,58.41) v2(162.56,59.3) v2(162.56,58.41) v2(163.45,59.3) v2(163.45,58.41) v2(164.34,59.3) v2(164.34,58.41) v2(165.23,59.3) v2(165.23,58.41) v2(166.12,59.3) v2(166.12,58.41) v2(167,59.3) v2(167,58.41) v2(167.89,59.3) v2(167.89,58.41) v2(167.89,57.01) v2(167.89,56.12) v2(167.89,55.23) v2(168.78,58.41)
HDRV2_P: length 23.1
  TOP w0.191: R150.1 v2(169.54,66.73)
  TOP w0.305: U46.19 184.56,54.32 v2(184.15,54.73)
  BOTTOM w0.305: v2(169.54,66.73) 169.54,65.39 172.09,62.85 174.75,62.85 182.12,55.49 183.39,55.49 v2(184.15,54.73)
I2C0_SCL: length 104
  TOP w0.229: U37.AC5 106.78,78.15 v1(107.18,78.55)
  L4-SIGNAL w0.163: v2(195.96,104.26) 191.64,104.26 180.9,93.51 173.53,93.51 160.27,80.25 144.65,80.25 142.63,82.28 140.91,82.28 140.4,81.78 130.26,81.78 129.77,82.27 122.75,82.27 122.75,82.27 122.51,82.27 122.51,82.27 122.41,82.27 121.13,80.99 114.83,80.99 114.55,81.27 112.78,81.27 110.98,79.48 108.11,79.48 v1(107.18,78.55)
  BOTTOM w0.191: 196.72,104.26 v2(195.96,104.26) R282.2
I2C0_SDA: length 105.1
  TOP w0.229: U37.AA5 107.18,76.94 v1(107.18,76.95)
  L4-SIGNAL w0.163: v2(195.96,101.72) 195.2,100.95 189.23,100.95 181.08,92.8 173.71,92.8 160.78,79.87 143.64,79.87 141.99,81.52 141.35,81.52 140.91,81.08 130.14,81.08 129.53,81.69 122.92,81.69 121.61,80.38 120.49,80.38 120.15,80.04 120.15,79.7 120.27,79.58 120.27,79.27 120.08,79.08 115.06,79.08 114.09,80.05 112.54,80.05 111.26,78.77 110.07,78.77 109.89,78.95 109.18,78.95 108.39,78.15 107.86,78.15 107.86,78.15 107.81,78.15 107.58,77.92 107.58,77.35 v1(107.18,76.95)
  BOTTOM w0.191: 196.72,101.72 v2(195.96,101.72) R288.2
I2C1_SCL: length 59.7
  TOP w0.191: v1(103.38,26.31) 103.84,26.31 103.88,26.28 R233.2
  TOP w0.229: U37.Y6 105.98,75.75 v1(106.38,76.15)
  L4-SIGNAL w0.163: v1(106.38,76.15) 105.98,75.75 105.98,74.35 105.78,74.15 105.41,74.15 105.18,73.91 105.18,73.55 104.52,72.89 102.09,72.89 101.75,72.54 100.62,72.54 100.38,72.31 100.38,71.54 100.38,71.54 100.38,63.92 99.31,62.85 99.31,61.64 98.78,61.11 98.78,60.78 99.31,60.25 99.31,30.38 v1(103.38,26.31)
  BOTTOM w0.191: v1(103.38,26.31) 103.58,26.52 U75.47
I2C1_SDA: length 59.2
  TOP w0.191: v1(103.38,27.2) 103.84,27.2 103.93,27.29 R228.2
  TOP w0.229: v1(106.38,76.95) 106.38,76.94 U37.AA6
  L4-SIGNAL w0.163: v1(103.38,27.2) 99.82,30.76 99.82,59.66 99.58,59.9 99.58,62.61 100.71,63.74 100.95,63.74 101.18,63.97 101.18,64.31 101.18,64.31 101.18,65.11 101.18,66.71 101.18,66.71 101.18,67.51 101.18,69.58 101.18,69.58 101.18,69.91 101.18,69.91 101.18,71.51 101.42,71.74 101.75,71.74 101.98,71.98 101.98,72.31 102.22,72.54 102.52,72.54 102.52,72.54 103.01,72.54 103.01,72.55 103.34,72.55 103.35,72.54 103.81,72.54 103.81,72.55 104.15,72.55 104.15,72.54 104.61,72.54 104.61,72.55 104.94,72.55 105.98,73.58 105.98,73.91 106.21,74.15 106.55,74.15 106.78,74.38 106.78,76.55 v1(106.38,76.95)
  BOTTOM w0.191: U75.48 103.56,27.02 v1(103.38,27.2)
I2C3_SCL: length 291.7
  TOP w0.191: U14.15 180.91,112.58 184.91,108.57 v2(184.91,105.27) ; R121.2 37.3,82.67 37.17,82.79 v2(36.7,82.79) 36.2,83.3 36.2,83.56 35.92,83.84 U32.19
  TOP w0.229: v1(89.58,72.15) 89.58,72.15 U37.T26
  L2-SIGNAL w0.107: v2(36.7,82.79) 40.51,78.98 v1(40.51,72.63)
  L4-SIGNAL w0.163: v2(184.91,105.27) 185.29,104.89 185.29,101.46 184.53,100.7 163.83,100.7 154.84,109.69 154.84,128.49 147.83,135.5 141.35,135.5 138.81,138.04 118.24,138.04 116.71,136.51 107.7,136.51 102.11,130.93 99.95,130.93 98.17,129.15 95.25,129.15 94.11,130.29 71.25,130.29 62.23,121.27 62.23,103.49 56.52,97.78 v1(56.52,96)
  L5-SIGNAL w0.163: v1(89.58,72.15) 89.18,72.55 87.01,72.55 86.59,72.13 83.06,72.13 82.39,71.46 81.53,71.46 81.37,71.62 80.52,71.62 80.01,71.11 73.66,71.11 73.15,71.62 69.09,71.62 68.73,71.98 67.89,71.98 67.66,71.74 64.8,71.74 64.57,71.98 63.73,71.98 63.5,71.74 58.29,71.74 57.4,72.63 v1(40.51,72.63)
  L7-SIGNAL w0.107: v2(36.7,82.79) 40.39,86.48 48.01,86.48 56.52,94.99 v1(56.52,96)
I2C3_SDA: length 290.7
  TOP w0.191: R118.2 37.34,83.43 37.19,83.58 v2(36.72,83.58) 36.18,84.12 36.14,84.12 35.92,84.33 U32.20 ; U14.16 181.55,112.7 185.38,108.87 185.38,106.59 185.55,106.42 v2(185.55,105.91)
  TOP w0.229: v1(90.38,72.15) 90.78,72.55 U37.T25
  L2-SIGNAL w0.107: v2(36.72,83.58) 41.02,79.28 v1(41.02,73.65)
  L4-SIGNAL w0.163: v2(185.55,105.91) 184.95,105.91 184.75,105.71 184.73,105.71 184.48,105.45 184.48,104.19 184.66,104 184.66,101.59 184.28,101.21 164.08,101.21 155.35,109.95 155.35,128.74 148.21,135.88 141.6,135.88 139.06,138.42 118.11,138.42 116.59,136.9 107.44,136.9 101.85,131.31 95.5,131.31 94.87,130.67 71.09,130.67 61.85,121.43 61.85,103.98 56.01,98.13 v1(56.01,96.51)
  L5-SIGNAL w0.163: v1(41.02,73.65) 41.27,73.9 72.26,73.9 73.28,72.89 74.8,72.89 75.18,73.27 76.83,73.27 77.72,72.38 79.76,72.38 80.91,73.54 86.22,73.54 86.42,73.33 86.68,73.33 86.91,73.1 89.84,73.1 90.38,72.56 v1(90.38,72.15)
  L7-SIGNAL w0.107: v2(36.72,83.58) 37.15,83.58 40.43,86.86 47.75,86.86 56.01,95.11 v1(56.01,96.51)
I2C4_SCL: length 73.5
  TOP w0.191: R30.2 v1(73.28,125.72)
  TOP w0.229: U37.AD19 95.58,78.95 v1(95.18,79.35)
  L4-SIGNAL w0.163: v1(86.87,101.08) 86.87,113.53 84.71,115.69 70.87,115.69 67.31,119.24 67.31,123.69 69.85,126.23 72.77,126.23 v1(73.28,125.72)
  L5-SIGNAL w0.163: v1(95.18,79.35) 94.78,79.75 94.78,83.14 93.76,84.16 93.76,85.56 93.47,85.84 92.46,85.84 92.16,86.14 91.52,86.14 90.04,87.62 90.04,89.02 87.25,91.81 87.25,95.24 86.87,95.62 v1(86.87,101.08)
I2C4_SDA: length 69.8
  TOP w0.191: R28.2 v1(70.23,125.72)
  TOP w0.229: v1(95.98,79.35) 96.38,78.95 U37.AD18
  L4-SIGNAL w0.163: v1(87.38,100.32) 87.38,100.76 87.5,100.88 87.5,101.46 87.38,101.59 87.38,113.78 84.33,116.83 70.61,116.83 67.94,119.5 67.94,123.43 v1(70.23,125.72)
  L5-SIGNAL w0.163: v1(95.98,79.35) 95.58,79.75 95.58,83.51 95.15,83.94 94.74,83.94 94.23,84.44 94.23,85.84 93.09,86.98 92.46,86.98 91.82,87.62 91.82,89.14 91.06,89.91 89.66,89.91 87.76,91.81 87.76,98.29 87.38,98.67 v1(87.38,100.32)
I2C6_SCL: length 168.3
  TOP w0.191: R126.2 v1(143,79.9)
  TOP w0.229: U37.AA3 108.38,76.55 v1(108.78,76.95)
  L2-SIGNAL w0.107: v1(137.54,35.42) 137.54,36.09 138.18,36.72 138.18,52.19 142.62,56.63 142.62,75.65 142.62,75.65 142.62,75.97 142.62,75.97 142.62,77.77 142.59,77.8 142.59,78.96 143,79.36 v1(143,79.9)
  L5-SIGNAL w0.163: v1(108.78,76.95) 109.18,77.35 109.75,77.35 109.98,77.59 109.98,77.97 110.62,78.6 111.38,78.6 112.52,79.75 113.92,79.75 114.3,79.36 117.09,79.36 118.87,81.14 140.97,81.14 142.21,79.9 v1(143,79.9) ; v1(58.93,28.06) 59.23,27.76 60.06,27.76 62.9,30.6 68.71,30.6 69.98,31.87 72.14,31.87 75.69,35.42 v1(137.54,35.42)
  BOTTOM w0.191: U74.12 59.08,27.9 v1(58.93,28.06)
I2C6_SDA: length 163.3
  TOP w0.191: R131.2 v1(143,75.81)
  TOP w0.229: U37.W1 110.38,75.34 v1(110.38,75.35)
  L2-SIGNAL w0.107: v1(138.05,34.91) 138.05,36.18 138.56,36.69 138.56,52.06 143,56.5 v1(143,75.81)
  L4-SIGNAL w0.163: v1(143,75.81) 138.81,75.81 135.94,78.68 135.87,78.68 135.81,78.74 123.62,78.74 121.88,77 121.33,77 120.98,76.65 112.09,76.65 110.79,75.35 v1(110.38,75.35)
  L5-SIGNAL w0.163: v1(138.05,34.91) 76.07,34.91 72.52,31.36 70.1,31.36 68.96,30.22 62.99,30.22 60.2,27.42 59.48,27.42 59.35,27.29 v1(58.93,27.29)
  BOTTOM w0.191: U74.11 59.47,27.4 59.37,27.29 v1(58.93,27.29)
ICN: length 2.1
  TOP w0.191: U19.82 53.02,112.6 53.05,112.64 R64.2
LDRV1: length 13.6
  TOP w0.305: U46.25 184.01,50.42 v2(183.51,50.92) ; v2(176.85,56.63) R173.2
  BOTTOM w0.305: v2(176.85,56.63) 179.58,53.9 179.58,51.93 180.59,50.92 v2(183.51,50.92)
LDRV2: length 11.9
  TOP w0.305: R172.1 v2(176.91,57.9) ; U46.21 v2(183.82,53.02)
  BOTTOM w0.305: v2(183.82,53.02) 181.79,53.02 v2(176.91,57.9)
LEOA_GPIO3: length 0.7
  TOP w0.191: U27.46 v1(134.72,95.65)
LEOA_GPIO7: length 49.6
  TOP w0.191: U27.18 126.72,99.15 v1(126.62,99.05) ; U77.4 150.81,72.19 150.37,72.63 v1(145.92,72.63)
  L5-SIGNAL w0.163: v1(126.62,99.05) 127.1,98.56 127.1,96.28 127.64,95.75 127.64,85.33 129.41,83.56 141.35,83.56 144.65,80.25 144.65,73.9 v1(145.92,72.63)
LEOA_GPIO8: length 5.3
  TOP w0.191: R105.2 136.36,89.03 135.89,89.5 135.89,90.54 134.2,92.23 134.2,92.78 134.2,92.78 U27.41
LEOA_GPIO9: length 1.6
  TOP w0.191: v1(128.18,98.8) 128.03,98.65 U27.19
  BOTTOM w0.191: R291.2 128.1,98.83 128.14,98.8 v1(128.18,98.8)
LEOA_GPIO10: length 107.6
  TOP w0.191: v1(92.58,48.5) RJ17.2 91.69,49.93 91.61,50.02 R183.2 ; v1(134.69,92.67) U27.42
  L2-SIGNAL w0.107: v1(143.38,91.94) 143.67,91.65 143.67,80.98 144.91,79.75 144.91,77.21 145.03,77.08 145.03,56 142.75,53.71 142.75,50.03 v1(142.11,49.39)
  L4-SIGNAL w0.163: v1(134.69,92.67) 135.43,91.94 v1(143.38,91.94)
  L5-SIGNAL w0.163: v1(92.58,48.5) 94.74,48.5 95.63,47.61 105.92,47.61 107.7,49.39 v1(142.11,49.39)
LEOA_OSC32KCAP: length 1.6
  TOP w0.191: U27.40 133.69,92.7 v1(133.78,92.62)
  BOTTOM w0.191: C578.1 133.78,92.83 v1(133.78,92.62)
LEOA_OSC32KIN: length 9
  TOP w0.191: v1(132.72,91.94) 132.72,92.74 132.69,92.76 132.69,92.99 132.7,93 132.69,93.01 132.69,93.05 132.7,93.06 132.69,93.06 U27.38
  BOTTOM w0.191: C593.2 136.45,87.38 136.69,87.63 Y8.2 136.69,89.23 134.11,91.81 132.84,91.81 v1(132.72,91.94)
LEOA_OSC32KOUT: length 11.4
  TOP w0.191: U27.39 133.2,92.35 v1(133.22,92.32)
  BOTTOM w0.191: C592.2 139.52,87.38 139.19,87.71 Y8.1 139.19,90.01 139.19,90.02 139.19,90.16 137.18,92.17 133.37,92.17 v1(133.22,92.32)
LEOA_SCLK: length 67.6
  TOP w0.191: U27.23 v1(128.17,96.65)
  TOP w0.229: U20.23 75.83,109.71 v1(75.95,109.59)
  L7-SIGNAL w0.107: v1(75.95,109.59) 77.22,109.59 77.69,110.06 81.24,110.06 81.53,110.35 82.3,110.35 83.31,109.34 84.17,109.34 84.18,109.34 85.6,109.34 93.98,100.95 99.95,100.95 104.37,105.38 104.37,105.63 105.03,106.29 114.3,106.29 117.73,102.86 117.73,98.8 119.26,97.27 125.68,97.27 126.44,98.03 127.19,98.03 128.17,97.05 v1(128.17,96.65)
LEOA_SDATA: length 63.3
  TOP w0.191: U27.24 v1(126.59,96.15)
  TOP w0.229: U20.24 75.33,109.74 v1(75.18,109.59)
  L7-SIGNAL w0.107: v1(75.18,109.59) 75.69,109.08 78.61,109.08 79.12,109.59 81.4,109.59 82.16,108.83 84.84,108.83 93.34,100.32 100.2,100.32 104.9,105.02 105.12,105.02 105.12,105.02 110.11,105.02 118.11,97.02 122.94,97.02 124.16,95.79 126.24,95.79 v1(126.59,96.15)
LEOA_WDOG_DISABLE: length 1.3
  TOP w0.191: R105.1 137.2,88.37 137.29,88.29 137.29,87.75
LEOB_GPIO1: length 16.3
  TOP w0.229: v1(71.86,108.17) U20.32
  L7-SIGNAL w0.107: v1(71.86,108.17) 71.86,106.81 70.57,105.53 62.48,105.53 TP16.1
LEOB_GPIO3: length 14.8
  TOP w0.229: U20.46 74.83,101.64 74.93,101.55 v1(74.93,101.08)
  L4-SIGNAL w0.163: v1(74.93,101.08) 72.14,101.08 71.12,100.07 71.12,92.32 TP32.1
LEOB_GPIO7: length 1.2
  TOP w0.229: U20.18 78.33,111.13 78.36,111.16 TP14.1
LEOB_GPIO8: length 15.2
  TOP w0.229: v1(73.3,103.67) U20.41
  L7-SIGNAL w0.107: v1(73.3,103.67) 69.43,103.67 68.58,104.51 59.94,104.51 TP19.1
LEOB_GPIO9: length 0.9
  TOP w0.229: U20.19 77.83,109.97 TP13.1
LEOB_GPIO10: length 16.8
  TOP w0.229: v1(71.5,103.17) U20.42
  L7-SIGNAL w0.107: v1(58.67,103.49) 59.91,103.49 60.67,104.26 68.45,104.26 69.54,103.17 v1(71.5,103.17)
  BOTTOM w0.163: R286.1 R285.2
  BOTTOM w0.191: R285.2 v1(58.67,103.49)
LFDSI: length 2
  TOP w0.191: C386.1 v1(104.27,28.35)
  BOTTOM w0.191: U75.49 104.96,28.03 104.65,28.35 v1(104.27,28.35)
LFT: length 2.2
  BOTTOM w0.191: C828.1 110.96,17.26 U75.20
LM5141_CS: length 6.2
  TOP w0.191: R133.2 R129.1 C262.2 195.96,80.63 194.54,82.06 U33.18
LM5141_HB: length 4.8
  TOP w0.191: U33.11 189.64,83.44 188.85,82.65 D8.1 C263.2
LM5141_HO: length 4.7
  TOP w0.191: U33.13 v1(191.39,82.29)
  L4-SIGNAL w0.163: v1(191.39,82.29) 191.13,82.03 v1(187.45,82.03)
LM5141_HOL: length 11.2
  TOP w0.191: v1(192.15,81.4) 192.55,81.79 U33.14
  L4-SIGNAL w0.163: v1(182.5,82.03) 182.81,82.34 186.13,82.34 187.07,81.4 v1(192.15,81.4)
LM5141_LO: length 9.9
  TOP w0.191: U33.8 190.9,84.94 v1(190.25,85.59)
  L4-SIGNAL w0.163: v1(190.25,85.59) 187.58,85.59 186,87.17 182.81,87.17 v1(182.5,86.86)
LM5141_LOL: length 4.8
  TOP w0.191: v1(190.88,86.1) 190.88,85.64 191.08,85.44 U33.7
  L4-SIGNAL w0.163: v1(187.45,86.86) 188.21,86.1 v1(190.88,86.1)
LM5141_SW: length 23.3
  TOP w0.191: 185.8,82.41 186.44,81.78 186.44,78.22 187.96,76.7 R133.1
  TOP w0.305: C263.1 189.7,79.24 190.25,79.78 v1(190.25,82.54) 190.65,82.95 U33.12
  BOTTOM w0.305: 186.69,83.68 189.1,83.68 v1(190.25,82.54)
  vias: v1(176.78,87.24) v1(176.78,86.35) v1(176.78,84.32) v1(176.78,83.43) v1(178.05,87.24) v1(178.05,86.35) v1(178.05,84.32) v1(178.05,83.43) v1(179.45,86.48) v1(179.45,85.59) v1(180.72,86.48) v1(180.72,85.59) v1(184.4,86.48) v1(184.4,85.59) v1(185.67,86.48) v1(185.67,85.59)
LM5141_VOUT: length 4.8
  TOP w0.191: R129.2 C262.1 194.94,80.89 194.04,81.79 U33.17
LPDDR4_CA0: length 33.7
  TOP w0.191: U40.R2 130.65,68.73 v1(131.06,68.41) ; U40.H2 v1(131.06,64.51)
  TOP w0.457: U37.G4 v1(107.98,64.95)
  L2-SIGNAL w0.114: v1(131.06,68.41) 130.65,68.01 130.65,67.59 130.37,67.3 130.37,66.84 v1(130.65,66.56) 130.65,65.16 130.65,64.85 130.99,64.51 v1(131.06,64.51)
  L7-SIGNAL w0.107: v1(130.65,66.56) 129.84,65.75 128.45,65.75 127.33,64.63 127.33,63.64 127.58,63.39 127.58,63.01 127.23,62.65 126.82,62.65 126.44,63.04 122.15,63.04 122.07,62.96 121.01,62.96 120.37,62.32 112.29,62.32 111.23,63.39 111.23,64.07 110.76,64.55 108.38,64.55 v1(107.98,64.95)
LPDDR4_CA1: length 33.7
  TOP w0.191: U40.P2 130.65,68.08 v1(130.26,68.41) ; U40.J2 v1(130.26,64.51)
  TOP w0.457: U37.H3 v1(108.78,65.75)
  L2-SIGNAL w0.114: v1(130.26,68.41) 129.86,68.02 129.86,67.6 129.58,67.31 129.58,66.85 v1(129.86,66.56) 129.86,64.83 130.19,64.51 v1(130.26,64.51)
  L7-SIGNAL w0.107: v1(129.86,66.56) 129.97,66.67 129.97,67.1 129.77,67.3 128.22,67.3 127.56,66.64 127.26,66.64 127.05,66.44 127.05,66.15 127.2,66 127.3,66 127.5,65.8 127.5,65.51 126.8,64.81 126.8,63.72 126.54,63.46 126.45,63.46 126.43,63.44 122.08,63.44 122.06,63.46 120.78,63.46 120.14,62.83 112.62,62.83 111.81,63.64 111.81,64.94 111.56,65.19 110.7,65.19 110.55,65.35 109.18,65.35 v1(108.78,65.75)
LPDDR4_CA2: length 33.7
  TOP w0.191: U40.H9 v1(124.65,64.51) ; U40.R9 125.05,68.73 v1(124.65,68.41)
  TOP w0.457: U37.K5 v1(107.18,67.35)
  L2-SIGNAL w0.114: v1(124.65,68.41) 125.06,68 125.06,67.49 125.33,67.22 125.33,66.84 v1(125.05,66.56) 125.05,66.19 125.07,66.16 125.07,64.89 124.69,64.51 v1(124.65,64.51)
  L7-SIGNAL w0.107: v1(107.18,67.35) 107.58,67.75 107.58,68.37 107.76,68.55 108.95,68.55 109.18,68.78 109.18,69.11 109.42,69.35 110.78,69.35 111.51,70.07 116.52,70.07 116.87,70.41 116.87,70.76 117.45,71.34 119.89,71.34 121.31,69.92 122.23,69.92 122.26,69.89 126.67,69.89 127.14,69.42 127.14,67.52 126.6,66.97 125.46,66.97 v1(125.05,66.56)
LPDDR4_CA3: length 33.6
  TOP w0.191: U40.R10 124.25,68.73 v1(123.85,68.41) ; U40.H10 v1(123.85,64.51)
  TOP w0.457: U37.J4 107.58,66.95 v1(107.98,66.55)
  L2-SIGNAL w0.114: v1(123.85,68.41) 124.26,68.01 124.26,67.53 124.53,67.25 124.53,66.83 v1(124.26,66.56) 124.28,66.54 124.28,64.91 123.88,64.51 v1(123.85,64.51)
  L7-SIGNAL w0.107: v1(107.98,66.55) 108.38,66.95 108.38,67.53 108.6,67.75 109.75,67.75 109.98,67.98 109.98,68.37 110.16,68.55 110.55,68.55 110.55,68.54 110.84,68.54 111.83,69.54 117.45,69.54 117.61,69.7 117.61,70.42 117.82,70.63 119.81,70.63 120.07,70.37 120.07,69.59 120.52,69.13 121.74,69.13 122.08,69.47 126.48,69.47 126.79,69.16 126.79,67.77 126.36,67.35 124.56,67.35 124.26,67.05 v1(124.26,66.56)
LPDDR4_CA4: length 33.7
  TOP w0.191: U40.H11 v1(123.05,64.51) ; v1(123.05,68.41) 123.45,68.73 U40.R11
  TOP w0.457: U37.K2 v1(109.58,67.35)
  L2-SIGNAL w0.114: v1(123.05,64.51) 123.09,64.51 123.47,64.89 123.47,66.16 123.45,66.19 v1(123.45,66.56) 123.74,66.85 123.74,67.23 123.48,67.49 123.48,67.98 v1(123.05,68.41)
  L7-SIGNAL w0.107: v1(109.58,67.35) 109.8,67.35 110.19,67.73 110.2,67.73 110.21,67.75 111.55,67.75 111.73,67.93 111.73,68.57 111.86,68.7 112.24,68.7 112.4,68.54 112.4,67.66 112.56,67.5 112.79,67.5 112.95,67.66 112.95,68.54 113.11,68.7 113.33,68.7 113.49,68.54 113.49,67.66 113.65,67.5 113.88,67.5 114.04,67.66 114.04,68.87 114.2,69.03 114.68,69.03 114.83,68.87 114.83,67.66 114.99,67.5 115.75,67.5 115.95,67.71 115.95,68.8 116.15,69 116.74,69 116.94,68.8 116.94,67.76 117.2,67.5 118.08,67.5 118.29,67.71 118.29,69 118.49,69.2 119.18,69.2 119.38,69 119.38,68.62 119.61,68.39 120.53,68.39 120.69,68.54 121.31,68.54 121.64,68.21 121.64,67.33 121.84,67.12 123.16,67.12 123.38,67.35 123.71,67.35 123.84,67.22 123.84,66.95 v1(123.45,66.56)
LPDDR4_CA5: length 33.6
  TOP w0.191: U40.P11 123.45,68.08 v1(123.05,67.76) ; U40.J11 v1(123.05,65.16)
  TOP w0.457: U37.H5 v1(107.18,65.75)
  L2-SIGNAL w0.114: v1(123.05,65.16) 123.19,65.29 123.19,66.01 123.03,66.17 122.47,66.17 v1(122.08,66.56) 122.08,66.88 122.21,67.02 123.09,67.02 123.22,67.14 123.22,67.6 v1(123.05,67.76)
  L7-SIGNAL w0.107: v1(107.18,65.75) 107.58,66.15 108.98,66.15 109.18,66.35 109.18,66.75 109.37,66.95 110.55,66.95 110.56,66.96 113.04,66.96 113.26,66.74 113.26,66.13 113.46,65.93 113.77,65.93 113.97,66.13 113.97,66.72 114.17,66.92 114.55,66.92 114.75,66.72 114.75,66.07 114.91,65.91 115.14,65.91 115.3,66.07 115.3,66.68 115.46,66.84 115.68,66.84 115.84,66.68 115.84,66.07 116,65.91 116.23,65.91 116.39,66.07 116.39,66.94 116.55,67.1 116.77,67.1 116.93,66.94 116.93,66.07 117.09,65.91 117.32,65.91 117.48,66.07 117.48,66.68 117.64,66.84 117.87,66.84 118.03,66.68 118.03,66.21 118.19,66.05 118.41,66.05 118.57,66.21 118.57,66.68 118.73,66.84 119.15,66.84 119.31,66.68 119.31,66.01 119.47,65.85 119.74,65.85 119.94,66.06 119.94,67.72 120.1,67.88 120.49,67.88 120.65,67.72 120.65,66.51 120.88,66.28 121.23,66.28 121.52,66.56 v1(122.08,66.56)
LPDDR4_CK_C: length 33.5
  TOP w0.157: U40.P9 125.05,68.08 v1(125.45,68.41) ; U40.J9 v1(125.45,64.51) ; U37.J1 110.04,66.94 110.38,66.61 v1(110.38,66.55)
  L2-SIGNAL w0.114: v1(125.45,64.51) 125.83,64.88 125.83,66.56 v1(125.83,66.56) 125.83,66.92 126.07,67.16 126.07,67.79 v1(125.45,68.41)
  L7-SIGNAL w0.114: v1(125.83,66.56) 125.88,66.56 126.03,66.41 126.03,66.18 125.83,65.98 121.87,65.98 121.26,65.37 120.19,65.37 119.76,64.94 119.76,63.92 119.61,63.77 119.18,63.77 119.02,63.92 119.02,64.84 118.67,65.19 118.11,65.19 117.75,64.84 117.75,63.94 117.49,63.67 117.07,63.67 116.92,63.83 116.92,64.89 116.56,65.25 116,65.25 115.65,64.89 115.65,63.97 115.37,63.69 115.01,63.69 114.81,63.9 114.81,64.99 114.4,65.39 113.84,65.39 113.41,64.96 113.41,63.98 113.18,63.74 112.91,63.74 112.73,63.93 112.73,65.63 112.2,66.16 110.45,66.16 110.3,66.31 110.3,66.47 v1(110.38,66.55)
LPDDR4_CK_T: length 33.5
  TOP w0.157: U37.H1 110.38,65.75 v1(110.38,65.75) ; U40.P8 v1(126.25,68.41) ; U40.J8 v1(126.25,64.51)
  L2-SIGNAL w0.114: v1(126.25,68.41) 126.8,67.87 126.8,67.28 126.48,66.96 v1(126.48,66.56) 126.48,66.09 126.55,66.02 126.55,64.81 v1(126.25,64.51)
  L7-SIGNAL w0.114: v1(126.48,66.56) 126.29,66.37 126.29,66.08 125.94,65.73 121.97,65.73 121.36,65.12 120.3,65.12 120.02,64.83 120.02,63.82 119.71,63.52 119.07,63.52 118.77,63.82 118.77,64.73 118.56,64.94 118.21,64.94 118.01,64.73 118.01,63.83 117.59,63.42 116.96,63.42 116.66,63.72 116.66,64.79 116.45,64.99 116.11,64.99 115.9,64.79 115.9,63.87 115.47,63.44 114.91,63.44 114.55,63.79 114.55,64.88 114.3,65.14 113.95,65.14 113.67,64.86 113.67,63.87 113.28,63.49 112.8,63.49 112.47,63.82 112.47,65.52 112.09,65.9 110.54,65.9 v1(110.38,65.75)
LPDDR4_CKE0: length 33.9
  TOP w0.33: U40.P4 129.23,68.26 129.25,68.26 129.4,68.41 v1(129.46,68.41) ; U37.G3 v1(108.78,64.95) ; U40.J4 v1(129.46,64.51)
  L2-SIGNAL w0.152: v1(129.46,68.41) 129.43,68.41 129.05,68.03 129.05,67.59 128.79,67.33 128.79,66.81 v1(129.05,66.56) 129.05,64.85 129.39,64.51 v1(129.46,64.51)
  L5-SIGNAL w0.163: v1(129.05,66.56) 128.3,65.81 127.01,65.45 126.75,65.19 126.75,63.69 125.86,62.8 125.86,62.32 125.85,62.31 125.85,61.7 125.48,61.33 124.67,61.33 124.26,61.74 124.26,62.9 123.94,63.21 122.96,63.21 122.66,62.91 122.66,62.53 122.65,62.53 122.65,61.66 122.38,61.38 120.36,61.38 111.21,65.35 109.18,65.35 v1(108.78,64.95)
LPDDR4_CKE1: length 33.9
  TOP w0.33: U40.J5 v1(127.85,64.51) ; U40.P5 128.25,68.08 v1(127.85,68.41) ; U37.J3 v1(108.78,66.55)
  L2-SIGNAL w0.152: v1(127.85,64.51) 127.9,64.51 128.26,64.86 128.26,65.32 128.26,65.33 v1(128.26,66.56) 127.99,66.83 127.99,67.32 128.26,67.59 128.26,68.01 127.86,68.41 v1(127.85,68.41)
  L5-SIGNAL w0.163: v1(128.26,66.56) 127.21,66.56 126.64,67.12 122,67.12 121.46,67.66 121.46,69.91 121.13,70.34 118.77,71 117.65,70.83 117.02,70.36 116.99,70.15 117.45,69.54 117.42,69.33 117.25,69.21 117.05,69.24 116.59,69.85 116.38,69.88 116.21,69.75 116.18,69.55 116.64,68.93 116.61,68.73 116.44,68.6 116.24,68.63 115.78,69.24 115.57,69.27 111.38,66.15 109.18,66.15 v1(108.78,66.55)
LPDDR4_CSN0_0: length 30.9
  TOP w0.33: U40.H4 v1(128.66,64.51) ; U37.J5 v1(107.18,66.55)
  L5-SIGNAL w0.163: v1(107.18,66.55) 107.57,66.15 107.57,65.92 107.58,65.91 107.58,65.58 107.57,65.58 107.57,65.54 107.77,65.34 108.15,65.34 108.38,65.11 108.38,64.73 108.56,64.54 111.02,64.54 114.94,61.18 123.83,58.59 124.55,58.59 126.27,59.17 126.75,59.65 126.75,62.24 127.51,63 127.51,63.45 127.36,63.6 127.36,64.63 127.64,64.91 128.25,64.91 v1(128.66,64.51)
LPDDR4_CSN0_1: length 30.9
  TOP w0.33: U40.R4 v1(128.66,68.41) ; U37.K3 v1(108.78,67.35)
  L5-SIGNAL w0.163: v1(128.66,68.41) 128.33,68.08 128.16,67.92 127.62,67.92 127.46,68.08 126.75,70.93 126.29,71.39 121.67,71.87 120.8,72.74 118.16,73.68 117.65,73.68 117.4,73.54 117.35,73.34 117.8,72.53 117.75,72.33 117.57,72.23 117.37,72.28 116.91,73.09 116.71,73.14 116.52,73.04 116.47,72.84 116.93,72.03 116.87,71.83 116.69,71.73 116.49,71.78 116.03,72.59 115.83,72.64 114.25,71.74 111.15,67.93 110.83,67.74 109.42,67.74 109.02,67.35 v1(108.78,67.35)
LPDDR4_CSN1_0: length 31
  TOP w0.33: U37.G5 106.78,65.35 v1(107.18,64.95) ; U40.H3 v1(129.46,63.86)
  L5-SIGNAL w0.163: v1(129.46,63.86) 129.06,63.46 129.06,63.37 129.06,63.37 129.06,62.3 128.14,60.74 127.71,59.3 124.64,57.8 124.16,57.75 121.57,58.3 121.4,58.19 121.32,57.85 121.14,57.74 120.93,57.78 120.82,57.96 120.9,58.31 120.79,58.48 113.08,60.29 111.18,62.95 108.62,62.95 108.38,63.18 108.38,63.51 108.15,63.74 107.82,63.74 107.58,63.98 107.58,64.54 v1(107.18,64.95)
LPDDR4_CSN1_1: length 30.9
  TOP w0.33: v1(130.26,69.06) 129.85,68.73 U40.R3 ; U37.J2 109.18,66.94 v1(109.58,66.55)
  L5-SIGNAL w0.163: v1(109.58,66.55) 109.18,66.95 108.62,66.95 108.38,67.18 108.38,67.51 108.62,67.74 108.95,67.74 109.18,67.98 109.18,68.31 109.42,68.54 109.75,68.54 109.98,68.78 109.98,69.11 110.22,69.34 110.8,69.34 111.25,69.69 113.26,73.25 113.89,73.88 115.98,74.93 116.6,74.93 118.93,74.31 119.46,74.56 119.93,74.43 120.17,73.98 121.77,73.55 124.97,73.37 126.45,72.85 127.44,71.87 127.99,71.49 129.85,70.02 129.85,69.46 v1(130.26,69.06)
LPDDR4_DM0_DBI0#: length 31.4
  TOP w0.33: v1(130.26,61.26) 130.25,61.26 U40.C3 ; U37.A3 v1(108.78,60.15)
  L4-SIGNAL w0.163: v1(130.26,61.26) 130,61 129.63,61 129.62,61 129.29,61 129.06,60.77 129.06,59.8 129.05,59.8 129.05,59.79 128.82,59.56 128.81,59.56 128.76,59.5 126.37,59.5 125.7,58.84 125.52,58.84 124.76,58.84 124.31,58.38 121.91,58.38 121.55,58.03 119.78,58.03 119.63,58.18 119.63,58.66 119.79,58.82 121.39,58.82 121.54,58.97 121.54,59.25 121.36,59.43 116.36,59.43 116.03,59.76 116.03,60.34 115.87,60.49 115.54,60.49 115.39,60.34 115.39,60.01 115.24,59.86 114.96,59.86 114.25,60.57 111.41,60.57 110.52,59.68 109.19,59.68 108.78,60.09 v1(108.78,60.15)
LPDDR4_DM1_DBI1#: length 25.5
  TOP w0.33: U40.C10 v1(124.65,60.61) ; U37.E4 v1(107.98,63.35)
  L2-SIGNAL w0.107: v1(124.65,60.61) 124.26,60.21 124.26,59.89 123.27,58.89 116.95,58.89 116.54,59.31 115.54,59.31 115.39,59.46 115.39,60.37 115.23,60.52 115.01,60.52 114.85,60.37 114.85,59.98 114.7,59.83 114.45,59.83 114.3,59.98 114.3,60.34 114.09,60.55 113.81,60.55 113.66,60.4 113.66,60.29 113.5,60.14 113.28,60.14 113.12,60.29 113.12,60.4 112.97,60.55 112.74,60.55 112.59,60.4 112.59,60.29 112.44,60.14 112.21,60.14 112.06,60.29 112.06,60.4 111.9,60.55 111.68,60.55 111.52,60.4 111.52,60.29 111.37,60.14 111.14,60.14 110.99,60.29 110.99,60.4 110.84,60.55 107.77,60.55 107.58,60.75 107.58,62.94 v1(107.98,63.35)
LPDDR4_DM2_DBI2#: length 31.5
  TOP w0.33: v1(130.26,71.66) 130.25,71.66 U40.Y3 ; U37.N1 110.38,69.75 v1(110.38,69.75)
  L4-SIGNAL w0.163: v1(110.38,69.75) 110.43,69.75 110.48,69.8 110.85,69.8 111.27,69.38 112.13,69.38 112.29,69.23 112.76,69.23 113.17,69.64 113.17,70.13 113.87,70.83 113.87,71.77 114.02,71.92 117.27,71.92 117.42,72.08 117.42,72.3 117.27,72.46 115.34,72.46 115.18,72.62 115.18,72.83 115.34,72.99 117.75,72.99 117.96,72.79 117.96,72.1 118.19,71.87 119.96,71.87 120.12,71.72 120.12,71.26 120.13,71.25 120.13,70.34 120.28,70.18 121.48,70.18 122.8,71.51 126.56,71.51 126.88,71.83 128.51,71.83 128.57,71.88 130.03,71.88 v1(130.26,71.66)
LPDDR4_DM3_DBI3#: length 22
  TOP w0.33: U40.Y10 123.85,72.31 v1(123.85,72.31) ; v1(107.18,71.35) 107.18,71.35 U37.R5
  L2-SIGNAL w0.107: v1(107.18,71.35) 107.58,71.75 108.16,71.75 108.38,71.97 108.38,72.33 109.41,73.36 110.63,73.36 112.32,75.05 112.33,75.05 112.36,75.07 114.49,75.07 114.64,74.92 114.64,74.54 114.79,74.39 116.66,74.39 116.81,74.54 116.81,74.94 116.97,75.1 121.03,75.1 122.4,73.73 122.85,73.73 123.49,73.08 123.49,72.51 123.69,72.31 v1(123.85,72.31)
LPDDR4_DQ0: length 31.4
  TOP w0.33: U40.B2 130.68,60.28 131,59.96 v1(131.06,59.96) ; U37.A5 v1(107.18,60.14)
  L4-SIGNAL w0.163: v1(107.18,60.14) 107.18,59.57 108.54,58.21 109.37,58.21 109.52,58.06 109.52,57.52 109.68,57.37 110.13,57.37 110.29,57.52 110.29,58.08 110.44,58.23 110.85,58.23 111,58.08 111,56.5 111.37,56.13 113.9,56.13 114.33,56.56 114.62,56.56 124.97,56.56 125.22,56.81 125.22,57.21 125.48,57.47 127.3,57.47 127.91,58.08 129.78,58.08 131.06,59.35 v1(131.06,59.96)
LPDDR4_DQ1: length 31.4
  TOP w0.33: U37.A6 v1(106.38,60.14) ; U40.C2 v1(131.06,60.61)
  L4-SIGNAL w0.163: v1(106.38,60.14) 106.56,59.96 106.56,59.49 110.38,55.67 114.15,55.67 114.58,56.1 127.57,56.1 128.3,56.82 128.3,56.84 129.08,57.62 129.97,57.62 131.5,59.15 131.5,60.17 v1(131.06,60.61)
LPDDR4_DQ2: length 31.5
  TOP w0.33: U40.E2 v1(131.06,61.91) ; U37.B5 v1(107.18,60.95)
  L4-SIGNAL w0.163: v1(107.18,60.95) 107.58,60.55 107.58,59.98 107.57,59.97 107.57,59.9 108.71,58.77 110.92,58.77 111.79,59.63 111.79,59.63 113.75,59.63 114.84,58.54 114.84,57.49 115.32,57.01 121.83,57.01 122.29,57.47 124.69,57.47 124.95,57.74 125.14,57.93 126.08,57.93 126.77,58.61 129.67,58.61 130.66,59.6 130.66,61.42 130.66,61.42 130.66,61.51 v1(131.06,61.91)
LPDDR4_DQ3: length 31.4
  TOP w0.33: U40.F2 v1(131.06,63.21) ; U37.C2 v1(109.58,61.75)
  L4-SIGNAL w0.163: v1(109.58,61.75) 109.98,62.15 110.67,62.15 110.92,62.4 111.66,62.4 111.84,62.58 111.84,63.31 112.3,63.78 114.77,63.78 114.92,63.93 114.92,64.48 115.07,64.63 115.3,64.63 115.45,64.48 115.45,63.93 115.61,63.78 115.83,63.78 115.99,63.93 115.99,64.48 116.14,64.63 116.37,64.63 116.52,64.48 116.52,63.93 116.67,63.78 117.06,63.78 117.22,63.93 117.22,64.4 117.37,64.55 117.6,64.55 117.75,64.4 117.75,63.93 117.9,63.78 118.62,63.78 118.82,63.58 119.65,63.58 120.19,63.03 126.39,63.03 126.84,62.58 127.21,62.58 127.92,61.87 128.66,61.87 129.41,62.61 129.62,62.61 129.9,62.89 129.9,63.24 130.01,63.35 130.35,63.35 130.47,63.23 130.47,62.92 131.07,62.31 131.3,62.31 131.44,62.46 131.44,63.04 131.28,63.21 v1(131.06,63.21)
LPDDR4_DQ4: length 31.5
  TOP w0.33: v1(107.98,60.95) 107.58,61.35 U37.B4 ; U40.F4 129.45,63.21 v1(129.46,63.21)
  L4-SIGNAL w0.163: v1(107.98,60.95) 108.39,61.35 108.39,61.57 108.38,61.58 108.38,61.91 108.39,61.92 108.39,62.37 108.38,62.38 108.38,62.71 108.39,62.72 108.39,63.17 108.38,63.18 108.38,63.51 108.39,63.52 108.39,63.97 108.38,63.98 108.38,64.31 108.62,64.54 110.85,64.54 111.47,65.17 113.81,65.17 114.37,65.73 120.7,65.73 121.01,65.42 121.01,64.25 121.18,64.08 121.5,64.08 121.65,64.23 121.65,65.25 122.07,65.67 126.9,65.67 127.28,66.06 128.64,66.06 129.05,65.64 129.05,63.61 v1(129.46,63.21)
LPDDR4_DQ5: length 31.4
  TOP w0.33: U37.C3 v1(108.78,61.75) ; U40.E4 v1(128.66,62.56)
  L4-SIGNAL w0.163: v1(108.78,61.75) 109.18,62.15 109.18,63.18 109.18,63.51 109.42,63.74 110.81,63.74 111.77,64.71 114.12,64.71 114.2,64.71 114.76,65.27 118.79,65.27 118.95,65.11 118.95,64.22 118.96,64.21 119.1,64.07 119.47,64.07 119.63,64.22 119.63,65.12 119.78,65.27 120.27,65.27 120.42,65.12 120.42,63.72 120.57,63.57 121.95,63.57 122.12,63.39 126.62,63.39 127.08,63.85 127.08,65.28 127.47,65.67 128.09,65.67 128.25,65.51 128.25,62.96 v1(128.66,62.56)
LPDDR4_DQ6: length 31.5
  TOP w0.33: U37.A2 v1(109.58,60.15) ; v1(128.66,60.61) 128.71,60.61 129.04,60.93 U40.C4
  L4-SIGNAL w0.163: v1(109.58,60.15) 109.98,60.55 110.74,60.55 111.22,61.03 116.33,61.03 116.48,60.87 116.48,60.09 116.64,59.93 118.89,59.93 119.05,60.09 119.05,60.85 119.2,61 121.34,61 121.49,60.85 121.49,60.62 121.34,60.47 119.73,60.47 119.58,60.31 119.58,60.09 119.73,59.93 122.34,59.93 122.61,59.66 122.61,59.24 122.76,59.1 123.34,59.1 123.49,59.25 123.49,60.44 123.65,60.59 124.03,60.59 124.16,60.47 124.16,59.69 124.36,59.49 124.56,59.49 125.34,59.49 125.55,59.49 125.86,59.79 125.86,60.46 126.01,60.62 126.75,60.62 126.9,60.47 126.9,60.01 127.05,59.86 127.91,59.86 v1(128.66,60.61)
LPDDR4_DQ7: length 31.4
  TOP w0.33: U40.B4 129.06,60.28 129.45,60.6 v1(129.46,60.61) ; U37.A4 v1(107.98,60.14)
  L4-SIGNAL w0.163: v1(107.98,60.14) 108.9,59.22 110.71,59.22 111.6,60.11 113.94,60.11 115.09,58.97 118.95,58.97 119.1,58.82 119.1,58.44 118.95,58.28 117.14,58.28 116.97,58.11 116.97,57.74 117.13,57.57 121.74,57.57 122.1,57.93 124.5,57.93 124.95,58.38 125.33,58.38 125.89,58.38 126.68,59.17 129.36,59.17 129.85,59.66 129.85,60.2 129.74,60.32 129.74,60.32 v1(129.46,60.61)
LPDDR4_DQ8: length 25.5
  TOP w0.33: v1(110.38,62.55) 109.98,62.95 U37.D1 ; U40.B11 v1(123.05,59.96)
  L2-SIGNAL w0.107: v1(110.38,62.55) 110.79,62.55 110.95,62.7 111.51,62.7 111.63,62.58 111.63,62.1 111.78,61.96 112.04,61.96 112.22,62.13 112.22,62.63 112.37,62.78 116.6,62.78 116.83,62.55 117.69,62.55 117.85,62.4 117.85,60.88 118.01,60.72 118.37,60.72 118.55,60.9 118.55,64.57 118.67,64.68 119.09,64.68 119.24,64.54 119.24,61.19 119.43,61 120.26,61 123.22,61 123.45,60.77 123.45,60.35 v1(123.05,59.96)
LPDDR4_DQ9: length 25.5
  TOP w0.33: U37.C4 v1(107.98,61.75) ; U40.C11 v1(123.05,60.61)
  L2-SIGNAL w0.107: v1(107.98,61.75) 108.39,62.15 108.39,62.71 108.62,62.94 108.94,62.94 109.17,62.71 109.17,62.39 109.43,62.14 110.54,62.14 111.19,61.49 112.56,61.49 112.71,61.65 112.71,62.15 112.86,62.31 113.08,62.31 113.25,62.14 113.25,61.63 113.4,61.48 113.63,61.48 113.78,61.63 113.78,62.08 113.94,62.24 114.16,62.24 114.31,62.09 114.31,61.66 114.47,61.51 114.68,61.51 114.83,61.66 114.83,62.14 115.01,62.32 115.85,62.32 115.97,62.2 115.97,61.32 116.18,61.12 116.5,61.12 116.98,61.6 117.2,61.6 117.39,61.41 117.39,60.15 117.63,59.91 119.01,59.91 119.16,60.06 119.16,60.39 119.32,60.54 119.54,60.54 119.7,60.39 119.7,60.06 119.85,59.91 120.08,59.91 120.23,60.06 120.23,60.39 120.38,60.54 120.61,60.54 120.76,60.39 120.76,60.06 120.92,59.91 122.36,59.91 v1(123.05,60.61)
LPDDR4_DQ10: length 25.5
  TOP w0.33: v1(123.05,62.56) 123.06,62.56 U40.E11 ; U37.F1 v1(110.38,64.15)
  L2-SIGNAL w0.107: v1(110.38,64.15) 110.96,64.15 111.1,64.28 111.1,64.51 111.35,64.76 111.64,64.76 111.79,64.61 111.79,64.17 111.93,64.02 112.25,64.02 112.4,64.18 112.4,64.61 112.55,64.76 112.78,64.76 112.93,64.61 112.93,64.18 113.08,64.02 113.31,64.02 113.46,64.18 113.46,64.61 113.62,64.76 113.85,64.76 114,64.61 114,64.18 114.15,64.02 114.45,64.02 114.61,64.18 114.61,65.65 114.79,65.83 115.08,65.83 115.23,65.67 115.23,64.13 115.39,63.98 115.71,63.98 115.87,64.14 115.87,65.65 116.04,65.83 120.02,65.83 120.41,65.44 120.41,62.3 120.56,62.14 120.88,62.14 121.03,62.3 121.63,62.3 121.78,62.14 122.21,62.14 122.64,62.14 v1(123.05,62.56)
LPDDR4_DQ11: length 25.5
  TOP w0.33: U40.F11 v1(123.85,62.56) ; U37.G2 109.18,65.35 v1(109.58,64.95)
  L2-SIGNAL w0.107: v1(109.58,64.95) 109.97,64.55 110.54,64.55 111.21,65.22 113.98,65.22 114.13,65.37 114.13,65.6 113.98,65.75 111.58,65.75 111.43,65.9 111.43,66.13 111.58,66.28 113.09,66.28 113.44,66.64 114.21,66.64 114.57,66.28 120.17,66.28 120.87,65.59 120.87,62.88 120.99,62.75 121.71,62.75 121.96,63.01 123.16,63.01 123.61,62.56 v1(123.85,62.56)
LPDDR4_DQ12: length 25.6
  TOP w0.33: U37.F2 v1(109.58,64.15) ; U40.F9 v1(124.65,62.56)
  L2-SIGNAL w0.107: v1(124.65,62.56) 124.95,62.56 125.06,62.67 125.06,62.95 124.91,63.1 123.55,63.1 123.24,63.41 122.27,63.41 122.09,63.58 121.52,63.58 121.32,63.78 121.32,65.81 120.4,66.74 114.76,66.74 114.22,67.27 113.16,67.27 113,67.12 113,66.92 112.85,66.77 112.33,66.77 112.18,66.92 112.18,67.12 112.03,67.27 111.56,67.27 110.82,66.54 110.82,65.52 110.66,65.35 110.13,65.35 109.97,65.5 109.97,65.98 109.81,66.14 109.33,66.14 109.18,65.99 109.18,64.3 109.33,64.15 v1(109.58,64.15)
LPDDR4_DQ13: length 25.5
  TOP w0.33: U40.E9 v1(125.45,62.56) ; U37.F3 v1(108.78,64.15)
  L2-SIGNAL w0.107: v1(125.45,62.56) 125.66,62.56 125.88,62.78 125.88,63.23 125.72,63.39 123.75,63.39 123.35,63.79 122.41,63.79 121.78,64.42 121.78,66.03 120.58,67.22 114.95,67.22 114.44,67.73 111.37,67.73 110.58,66.94 108.58,66.94 108.39,66.75 108.39,64.54 v1(108.78,64.15)
LPDDR4_DQ14: length 25.5
  TOP w0.33: v1(125.45,60.61) 125.45,60.61 125.06,60.93 U40.C9 ; v1(108.78,62.55) 108.38,62.95 U37.D3
  L2-SIGNAL w0.107: v1(125.45,60.61) 125.06,60.21 125.06,59.65 125.29,59.43 125.65,59.43 125.86,59.63 125.86,60.22 126.18,60.54 126.18,61.16 125.91,61.43 124.66,61.43 123.93,60.7 123.93,60.21 123.06,59.35 117.2,59.35 116.76,59.79 116.14,59.79 115.84,60.08 115.84,60.77 115.61,61.01 111.03,61.01 110.7,61.34 109.43,61.34 109.17,61.59 109.17,61.91 108.78,62.3 v1(108.78,62.55)
LPDDR4_DQ15: length 25.5
  TOP w0.33: U37.F5 v1(107.18,64.15) ; U40.B9 v1(124.65,59.96)
  L2-SIGNAL w0.107: v1(124.65,59.96) 124.65,59.38 124.86,59.17 124.86,58.84 124.55,58.53 123.55,58.53 123.46,58.44 116.76,58.44 116.35,58.85 114.59,58.85 113.75,59.68 107.06,59.68 106.78,59.96 106.78,63.75 v1(107.18,64.15)
LPDDR4_DQ16: length 31.6
  TOP w0.33: U37.L5 v1(107.18,68.15) ; U40.AA2 130.65,72.63 v1(130.26,72.96)
  L4-SIGNAL w0.163: v1(107.18,68.15) 107.58,68.55 107.58,69.95 107.77,70.15 108.16,70.15 108.38,70.36 108.38,70.73 108.6,70.95 108.96,70.95 109.18,71.16 109.18,71.53 109.4,71.75 111.83,71.75 112.19,72.11 112.19,73.57 113.08,74.46 125.63,74.46 125.86,74.24 125.86,73.2 126.01,73.04 126.65,73.04 126.83,73.22 126.83,73.91 126.99,74.07 127.36,74.07 127.48,73.95 127.48,73.91 127.48,73.61 127.68,73.41 129.21,73.41 129.53,73.09 130.13,73.09 v1(130.26,72.96)
LPDDR4_DQ17: length 31.5
  TOP w0.33: U40.Y2 131.05,72.31 v1(131.06,72.31) ; U37.M5 106.78,69.35 v1(107.18,68.95)
  L4-SIGNAL w0.163: v1(131.06,72.31) 131.06,73.35 129.01,75.4 112.72,75.4 110.33,73.01 109.07,73.01 108.38,72.31 108.38,71.98 108.33,71.94 108.33,71.91 108.17,71.75 107.8,71.75 107.58,71.53 107.58,71.16 107.36,70.95 107.02,70.95 107.02,70.94 107.02,70.94 106.78,70.71 106.78,70.58 106.78,70.58 106.78,69.35 v1(107.18,68.95)
LPDDR4_DQ18: length 31.6
  TOP w0.33: U37.N5 v1(107.18,69.75) ; U40.V2 130.83,70.86 130.85,70.86 131,71.01 v1(131.06,71.01)
  L4-SIGNAL w0.163: v1(131.06,71.01) 130.66,71.41 130.66,73.17 130.4,73.42 129.69,73.42 129.46,73.66 129.46,74.29 128.8,74.95 128.19,74.95 127.94,74.7 126.73,74.7 126.48,74.95 112.92,74.95 111.66,73.69 111.66,72.91 111.3,72.55 109.41,72.55 109.18,72.32 109.18,71.96 108.97,71.75 108.61,71.75 108.38,71.52 108.38,71.29 108.38,71.29 108.38,71.18 108.15,70.95 108.04,70.95 108.04,70.95 107.81,70.95 107.58,70.71 107.58,70.35 107.18,69.95 v1(107.18,69.75)
LPDDR4_DQ19: length 31.6
  TOP w0.33: U37.L4 v1(107.98,68.15) ; U40.U2 v1(130.26,69.71)
  L4-SIGNAL w0.163: v1(130.26,69.71) 130.24,69.71 129.66,70.28 129.24,70.28 129.05,70.1 129.05,67.23 128.8,66.97 127.63,66.97 126.82,66.16 121.12,66.16 120.96,66.31 120.96,67.11 120.81,67.26 120.27,67.26 120.12,67.11 120.12,66.39 119.92,66.19 114.19,66.19 113.69,65.69 111.12,65.69 110.77,65.35 108.62,65.35 108.38,65.58 108.38,65.62 108.38,65.62 108.38,67.75 v1(107.98,68.15)
LPDDR4_DQ20: length 31.5
  TOP w0.33: U40.U4 v1(128.66,69.71) ; U37.L2 v1(109.58,68.15)
  L4-SIGNAL w0.163: v1(128.66,69.71) 128.26,69.31 128.26,67.54 128.05,67.34 127.34,67.34 126.96,66.96 122.95,66.96 122.95,66.96 121.79,66.96 120.89,67.86 119.43,67.86 119.1,67.53 119.1,67.07 118.95,66.91 118.72,66.91 118.57,67.07 118.57,67.45 118.41,67.6 118.19,67.6 118.03,67.45 118.03,66.8 117.88,66.65 117.65,66.65 117.5,66.8 117.5,67.45 117.35,67.6 117.12,67.6 116.97,67.45 116.97,66.8 116.81,66.65 116.59,66.65 116.43,66.8 116.43,67.45 116.28,67.6 116.05,67.6 115.9,67.45 115.9,66.8 115.75,66.65 115.52,66.65 115.37,66.8 115.37,67.43 115.21,67.58 114.91,67.58 113.48,66.15 109.38,66.15 109.18,66.35 109.18,67.75 v1(109.58,68.15)
LPDDR4_DQ21: length 31.6
  TOP w0.33: U40.V4 128.66,70.36 v1(128.66,70.36) ; U37.L1 v1(110.38,68.15)
  L4-SIGNAL w0.163: v1(110.38,68.15) 110.38,68.07 111.76,66.69 113.36,66.69 114.33,67.66 114.33,69.54 114.78,69.99 116.48,69.99 116.69,69.79 116.69,69.48 116.54,69.33 115.09,69.33 114.94,69.18 114.94,68.9 115.14,68.7 117.47,68.7 118.01,68.16 118.26,68.16 118.53,68.42 118.53,68.84 118.66,68.97 119.27,68.97 119.42,68.82 119.42,68.48 119.59,68.32 121.13,68.32 122.17,67.28 126.2,67.28 127.11,68.19 127.11,69.5 127.36,69.75 127.36,70.66 127.56,70.86 128.15,70.86 128.32,70.69 128.32,70.69 128.65,70.36 v1(128.66,70.36)
LPDDR4_DQ22: length 31.6
  TOP w0.33: v1(128.66,72.31) 129.05,71.98 U40.Y4 ; U37.N2 v1(109.58,69.75)
  L4-SIGNAL w0.163: v1(109.58,69.75) 109.98,70.14 110.54,70.14 110.54,70.15 110.55,70.15 110.66,70.26 111.04,70.26 111.41,69.89 112.15,69.89 113.41,71.15 113.41,73.29 113.56,73.45 113.92,73.45 114.07,73.29 114.07,72.66 114.23,72.5 114.45,72.5 114.6,72.65 114.6,73.29 114.76,73.45 118.26,73.45 118.41,73.29 118.41,72.48 118.57,72.33 120.35,72.33 120.59,72.09 120.59,70.93 120.74,70.78 121.43,70.78 121.79,71.15 121.79,71.54 121.64,71.69 121.22,71.69 121.06,71.85 121.06,72.08 121.22,72.23 121.64,72.23 121.79,72.38 121.79,72.67 121.92,72.8 121.92,73.22 122.17,73.47 123.27,73.47 124.84,71.9 126.49,71.9 127.31,72.72 128.25,72.72 v1(128.66,72.31)
LPDDR4_DQ23: length 31.6
  TOP w0.33: U37.N4 v1(107.98,69.75) ; U40.AA4 129.45,72.31 v1(129.46,72.31)
  L4-SIGNAL w0.163: v1(129.46,72.31) 129.46,72.73 129.11,73.07 127.14,73.07 126.78,72.71 125.62,72.71 124.96,73.37 124.03,73.37 123.49,73.9 119.92,73.9 119.77,73.75 119.77,73.54 119.93,73.37 121.31,73.37 121.46,73.22 121.46,72.99 121.31,72.84 119.06,72.84 118.91,72.99 118.91,73.75 118.75,73.9 113.21,73.9 112.86,73.56 112.86,72.05 111.76,70.95 109.41,70.95 109.18,70.71 109.18,70.37 108.97,70.16 108.96,70.16 108.95,70.15 108.62,70.15 108.61,70.16 108.6,70.16 108.19,69.75 v1(107.98,69.75)
LPDDR4_DQ24: length 22.1
  TOP w0.33: U40.AA11 123.45,72.63 v1(123.05,72.96) ; U37.T3 108.78,72.15 v1(108.78,72.15)
  L2-SIGNAL w0.107: v1(108.78,72.15) 109.57,72.94 110.48,72.94 110.48,72.94 110.92,72.94 111.05,73.07 111.05,73.08 111.81,73.84 111.82,73.84 112.02,74.04 112.22,74.04 112.39,74.22 112.39,74.46 112.55,74.61 112.77,74.61 112.93,74.46 112.93,74.22 113.08,74.07 113.31,74.07 113.46,74.22 113.46,74.46 113.61,74.61 113.84,74.61 113.99,74.46 113.99,74.08 114.15,73.93 116.7,73.93 116.85,73.78 116.85,73.24 117,73.08 117.22,73.08 117.39,73.25 117.39,74.47 117.55,74.64 117.82,74.64 118.02,74.44 118.02,73.73 118.15,73.6 118.49,73.6 118.64,73.75 118.64,74.39 118.8,74.54 120.93,74.54 122.2,73.27 122.75,73.27 v1(123.05,72.96)
LPDDR4_DQ25: length 22.1
  TOP w0.33: U40.Y11 123.05,72.31 v1(123.05,72.31) ; U37.T2 109.18,72.54 v1(109.58,72.15)
  L2-SIGNAL w0.107: v1(123.05,72.31) 122.66,72.7 122.09,72.7 121.77,72.38 121.54,72.38 121.37,72.54 121.37,73.41 120.86,73.92 120.6,73.92 120.45,73.77 120.45,72.71 120.29,72.56 119.94,72.56 119.79,72.71 119.79,73.88 119.61,74.06 119.25,74.06 119.1,73.9 119.1,72.74 118.95,72.58 118.6,72.58 118.45,72.74 118.45,72.93 118.3,73.08 118.07,73.08 117.92,72.93 117.92,72.74 117.77,72.58 116.59,72.58 115.77,73.4 112.01,73.4 111.51,72.89 111.51,72.38 111.25,72.12 111.03,72.12 110.59,72.56 109.8,72.56 109.58,72.33 v1(109.58,72.15)
LPDDR4_DQ26: length 22.1
  TOP w0.33: v1(123.05,70.36) 123.45,70.68 U40.V11 ; v1(109.58,70.55) 109.18,70.94 U37.P2
  L2-SIGNAL w0.107: v1(123.05,70.36) 122.66,70.75 121.95,70.75 121.74,70.55 121.74,70.4 121.36,70.02 120.17,70.02 120.02,70.17 120.02,70.6 119.71,70.91 118.59,70.91 118.44,70.75 118.44,70.02 118.26,69.84 117.95,69.84 117.79,69.99 117.79,70.81 117.65,70.94 117.21,70.94 117.04,70.78 117.04,69.87 116.89,69.71 116.33,69.71 115.93,70.12 115.45,70.12 115.04,69.71 113.28,69.71 113.13,69.87 113.13,70.6 112.95,70.78 112.7,70.78 112.55,70.63 112.55,69.84 112.42,69.71 112.12,69.71 111.96,69.87 111.96,70.32 111.81,70.47 111.58,70.47 111.43,70.32 111.43,69.97 111.28,69.81 111.02,69.81 110.69,70.15 109.98,70.15 v1(109.58,70.55)
LPDDR4_DQ27: length 22
  TOP w0.33: U40.U11 123.45,70.03 v1(123.85,70.36) ; U37.P3 v1(108.78,70.55)
  L2-SIGNAL w0.107: v1(123.85,70.36) 123.85,70.06 123.63,69.84 122.29,69.84 122.28,69.84 121.83,69.84 121.4,69.41 121.4,68.79 121.25,68.63 120.93,68.63 120.78,68.79 120.78,69.38 120.62,69.54 119.71,69.54 119.56,69.69 119.56,70.25 119.41,70.4 119.11,70.4 118.97,70.27 118.97,68.7 118.85,68.57 118.55,68.57 118.4,68.72 118.4,69.22 118.24,69.38 117.3,69.38 117.17,69.26 111.93,69.26 111.83,69.35 109.42,69.35 109.19,69.58 109.19,69.59 109.17,69.61 109.17,70.15 v1(108.78,70.55)
LPDDR4_DQ28: length 22
  TOP w0.33: v1(124.65,70.36) 124.66,70.36 124.8,70.21 124.87,70.21 U40.U9 ; U37.P5 106.78,70.95 v1(107.18,70.55)
  L2-SIGNAL w0.107: v1(124.65,70.36) 124.65,69.6 124.51,69.45 122.09,69.45 121.86,69.22 121.86,68.28 121.69,68.11 118.31,68.11 117.7,68.72 110.79,68.72 110.62,68.55 109.39,68.55 109.17,68.77 109.17,69.11 108.94,69.34 108.62,69.34 108.37,69.58 108.37,69.91 108.14,70.14 107.8,70.14 107.4,70.55 v1(107.18,70.55)
LPDDR4_DQ29: length 22
  TOP w0.33: U37.R4 107.98,71.35 v1(107.98,71.35) ; U40.V9 125.05,70.68 v1(125.45,71.01)
  L2-SIGNAL w0.107: v1(107.98,71.35) 108.21,71.35 108.61,71.75 109.86,71.75 109.87,71.74 110.76,71.74 110.84,71.66 111.73,71.66 111.99,71.92 111.99,72.71 112.2,72.93 115.51,72.93 116.31,72.13 120.73,72.13 120.94,71.92 125.81,71.92 126.11,71.62 126.11,71.29 125.83,71.01 v1(125.45,71.01)
LPDDR4_DQ30: length 22
  TOP w0.33: U40.Y9 125.45,72.31 v1(125.45,72.31) ; U37.T4 107.58,72.55 v1(107.98,72.15)
  L2-SIGNAL w0.107: v1(125.45,72.31) 124.66,72.31 122.78,74.18 122.59,74.18 121.27,75.5 121.2,75.58 116.64,75.58 116.13,75.07 115.21,75.07 114.76,75.53 112.17,75.53 112.14,75.5 112.13,75.5 110.77,74.15 109.41,74.15 109.18,73.92 109.18,73.49 107.98,72.29 v1(107.98,72.15)
LPDDR4_DQ31: length 22
  TOP w0.33: U40.AA9 125.05,72.63 v1(124.65,72.96) ; U37.T5 106.78,72.55 v1(107.18,72.15)
  L2-SIGNAL w0.107: v1(124.65,72.96) 124.46,72.96 121.73,75.69 121.33,76.09 111.91,76.09 110.78,74.96 109.38,74.96 109.18,74.75 109.18,74.36 108.96,74.14 108.62,74.14 108.38,73.91 108.38,73.35 v1(107.18,72.15)
LPDDR4_DQS0_N: length 31.4
  TOP w0.157: v1(130.26,61.91) 130.26,61.91 U40.E3 ; U37.B1 110.38,60.95 v1(110.38,60.95)
  L4-SIGNAL w0.147: v1(110.38,60.95) 110.48,61.04 110.67,61.04 110.68,61.05 110.69,61.05 111.05,61.41 112.26,61.41 112.66,61.8 112.66,62.85 112.76,62.94 112.97,62.94 113.07,62.85 113.07,61.76 113.33,61.5 113.96,61.5 114.27,61.81 114.27,62.75 114.45,62.93 114.81,62.93 114.99,62.75 114.99,62.4 115.26,62.12 115.79,62.12 116.13,62.47 116.13,62.79 116.29,62.96 116.82,62.96 117.04,62.73 117.04,60.84 117.39,60.49 117.88,60.49 118.21,60.82 118.21,62.68 118.37,62.84 118.61,62.84 118.77,62.68 118.77,62.09 119.2,61.66 121.49,61.66 122,61.15 128.96,61.15 129.21,61.41 129.32,61.41 129.72,61.41 130.22,61.91 v1(130.26,61.91)
LPDDR4_DQS0_P: length 31.4
  TOP w0.157: v1(109.58,60.95) 109.18,61.35 U37.B2 ; U40.D3 v1(129.46,61.91)
  L4-SIGNAL w0.147: v1(109.58,60.95) 109.99,61.35 110.21,61.35 110.21,61.35 110.55,61.35 110.55,61.35 110.56,61.35 110.92,61.71 112.14,61.71 112.36,61.93 112.36,62.97 112.63,63.25 113.1,63.25 113.37,62.97 113.37,61.89 113.45,61.81 113.84,61.81 113.97,61.94 113.97,62.63 113.97,62.63 113.97,62.88 114.33,63.24 114.93,63.24 115.29,62.88 115.29,62.52 115.38,62.43 115.66,62.43 115.82,62.59 115.82,62.92 116.17,63.26 116.95,63.26 117.35,62.86 117.35,60.97 117.52,60.8 117.75,60.8 117.91,60.95 117.91,62.81 118.24,63.14 118.74,63.14 119.08,62.8 119.08,62.22 119.33,61.97 121.62,61.97 122.13,61.46 128.83,61.46 129.28,61.91 v1(129.46,61.91)
LPDDR4_DQS1_N: length 25.5
  TOP w0.157: U40.E10 124.65,61.91 v1(124.65,61.91) ; U37.E2 v1(109.58,63.35)
  L2-SIGNAL w0.114: v1(124.65,61.91) 124.48,61.91 124.17,61.59 124.16,61.59 123.83,61.27 123.44,61.27 123.43,61.27 122.64,61.27 122.47,61.45 120.11,61.45 119.68,61.87 119.68,64.99 119.52,65.15 118.28,65.15 118.11,64.99 118.11,63.35 117.83,63.07 117.35,63.07 117.08,63.35 117.08,65.05 117,65.13 116.64,65.13 116.57,65.06 116.57,63.52 116.29,63.25 110.86,63.25 110.54,62.93 110,62.93 v1(109.58,63.35)
LPDDR4_DQS1_P: length 25.5
  TOP w0.157: v1(123.85,61.91) 123.86,61.91 U40.D10 ; U37.E3 v1(108.78,63.35)
  L2-SIGNAL w0.114: v1(123.85,61.91) 123.85,61.65 123.73,61.52 123.72,61.52 122.75,61.52 122.57,61.7 120.21,61.7 119.94,61.97 119.94,65.09 119.63,65.41 118.17,65.41 117.86,65.09 117.86,63.45 117.73,63.33 117.46,63.33 117.33,63.45 117.33,65.15 117.1,65.38 116.53,65.38 116.31,65.17 116.31,63.63 116.19,63.5 110.79,63.5 110.59,63.7 110.56,63.7 110.54,63.73 109.13,63.73 108.78,63.38 v1(108.78,63.35)
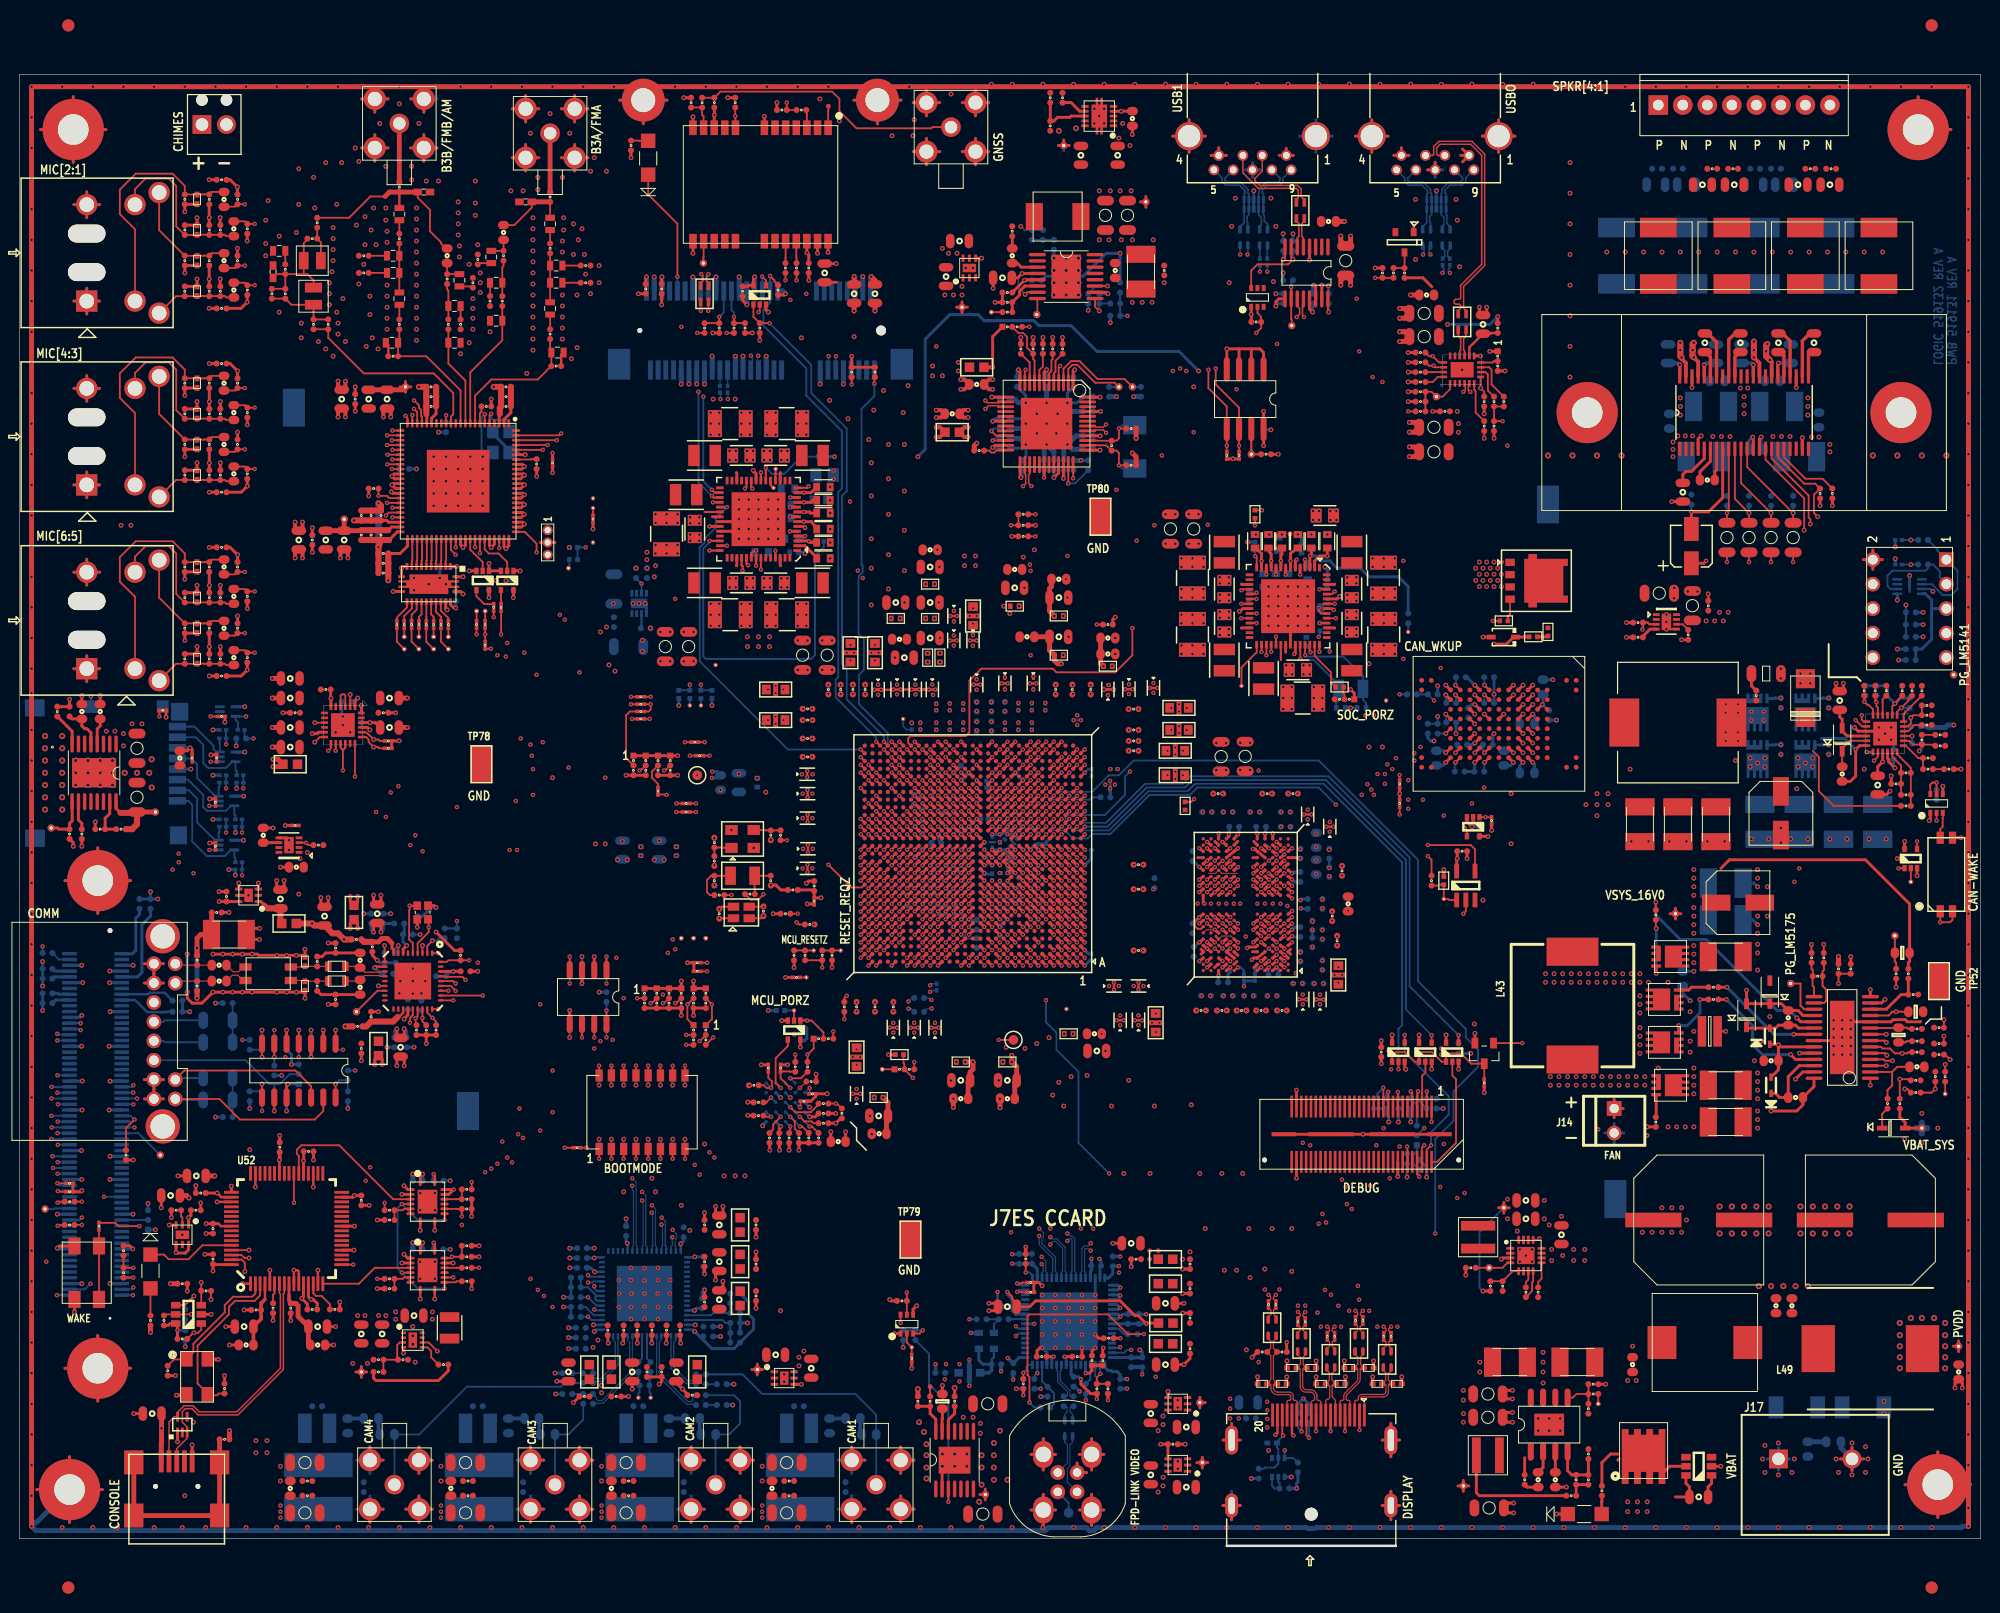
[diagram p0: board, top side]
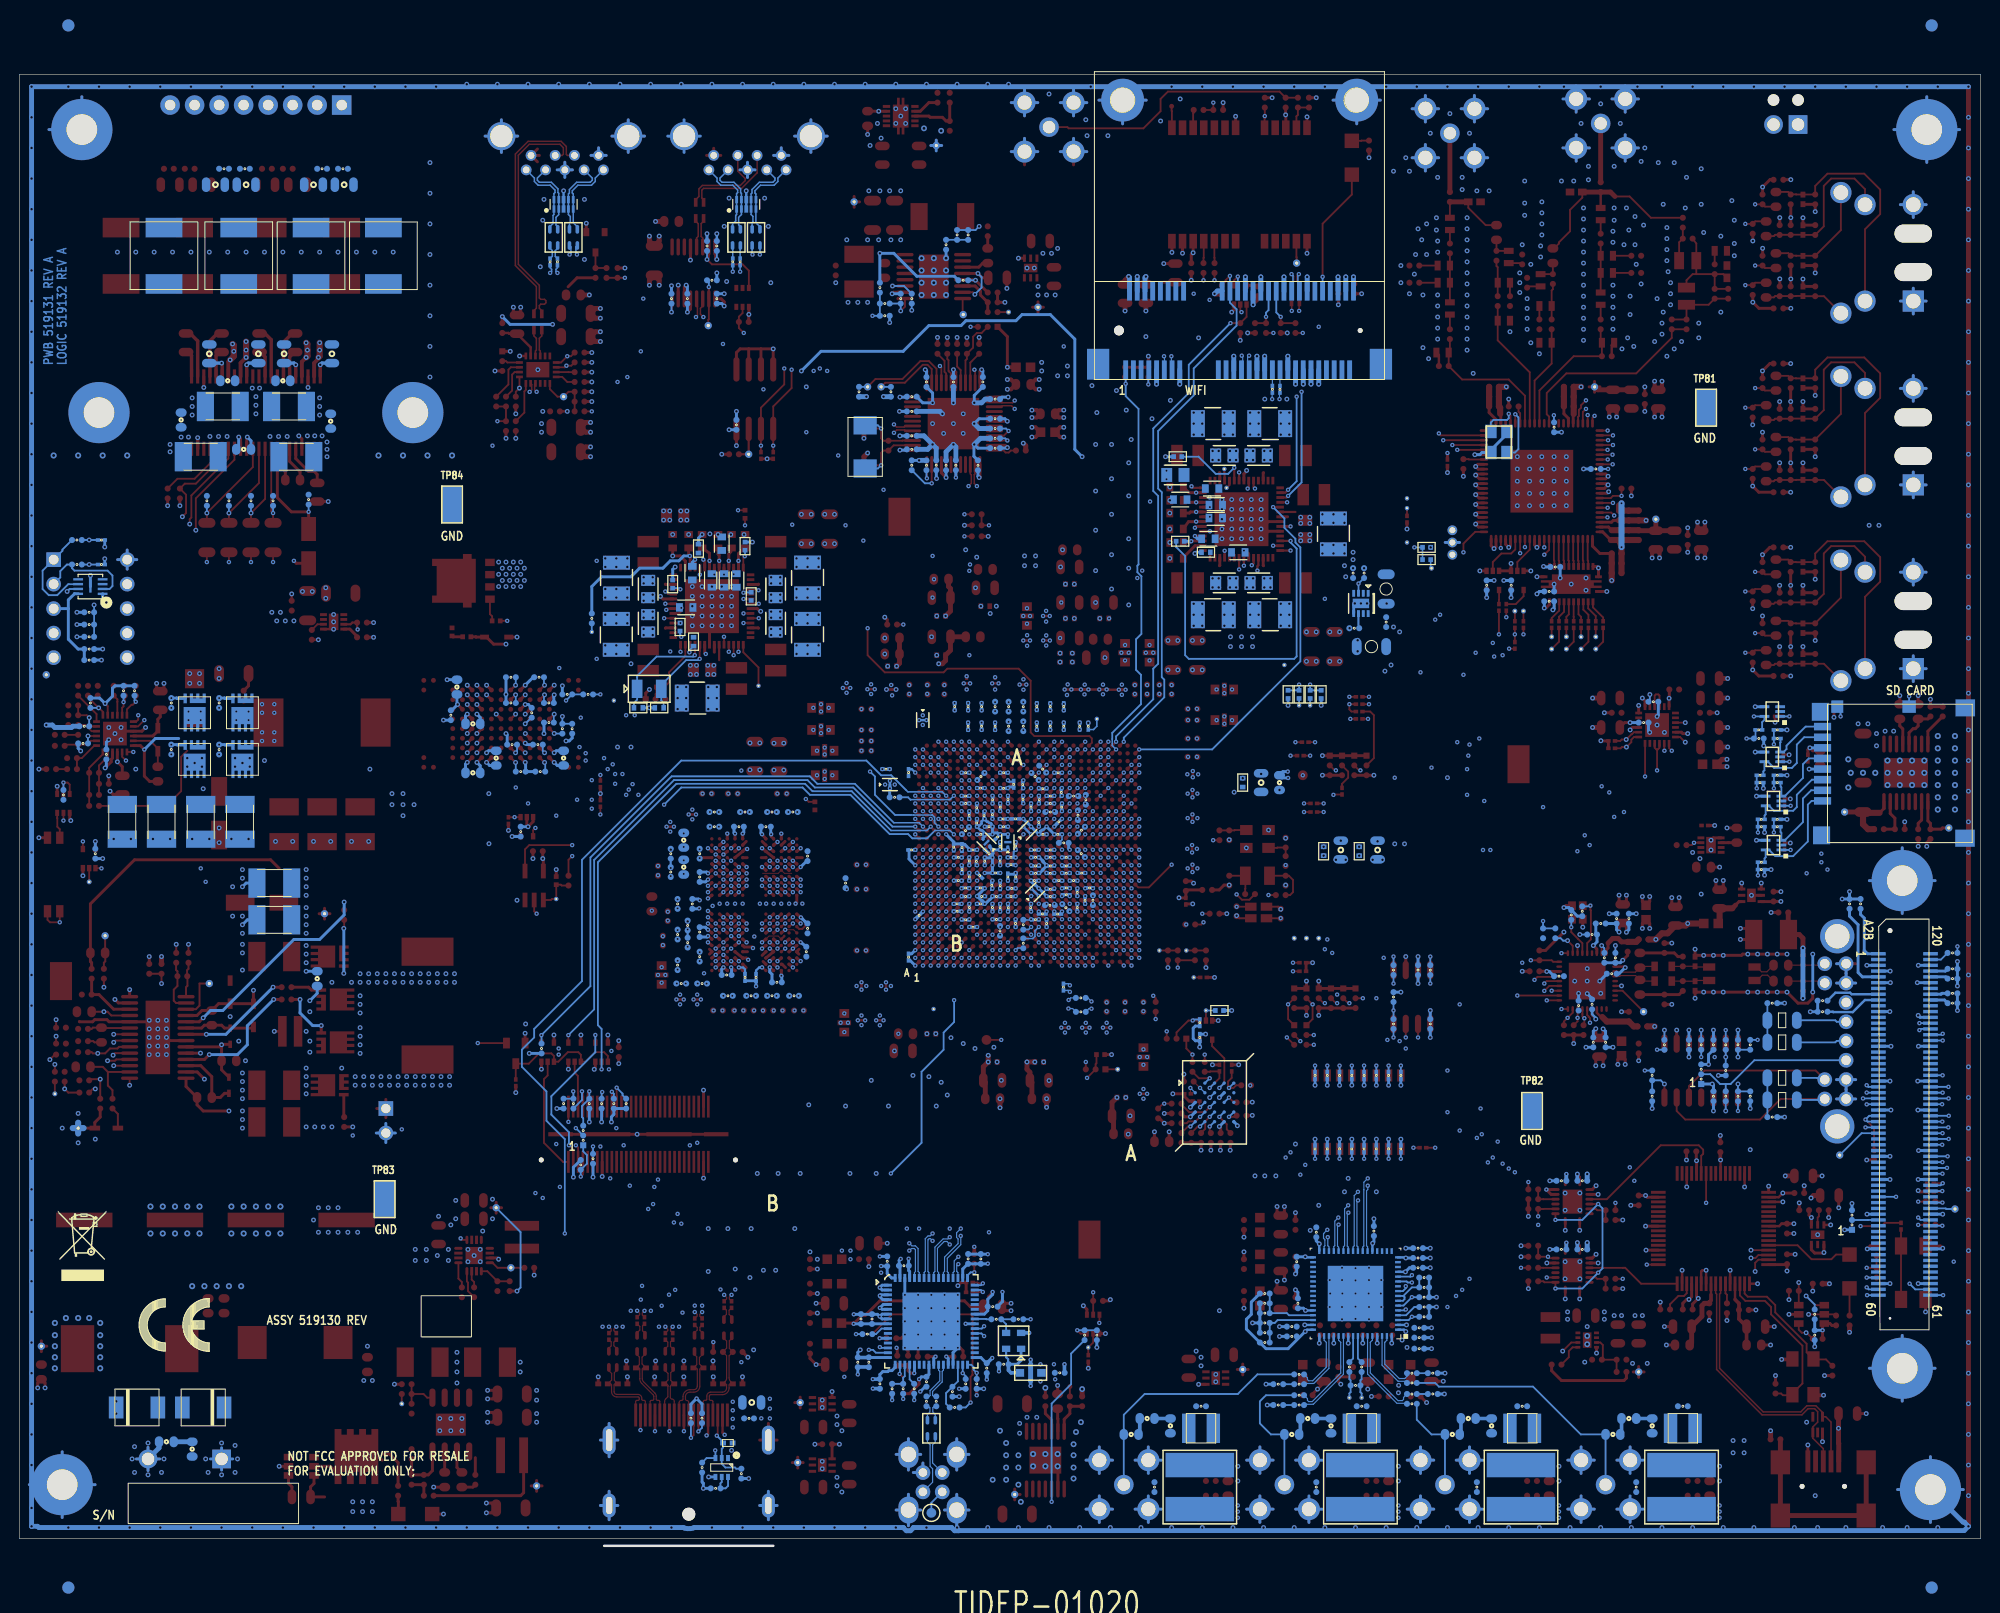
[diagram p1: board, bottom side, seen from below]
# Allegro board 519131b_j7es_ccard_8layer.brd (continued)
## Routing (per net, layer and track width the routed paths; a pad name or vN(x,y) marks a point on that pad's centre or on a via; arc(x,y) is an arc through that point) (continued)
LPDDR4_DQS2_N: length 31.5
  TOP w0.157: U40.V3 129.85,70.68 v1(130.25,71.01) ; U37.M2 v1(109.58,68.95)
  L4-SIGNAL w0.147: v1(130.25,71.01) 129.86,70.61 129.15,70.61 128.53,71.23 127.29,71.23 126.96,70.9 126.96,70.65 126.96,70.65 126.96,70.07 126.96,70.06 126.96,69.93 126.66,69.64 125.11,69.64 124.94,69.47 123.99,69.47 123.84,69.62 122.11,69.62 121.77,69.28 119.93,69.28 119.38,69.84 119.38,70.94 119.28,71.03 118.64,71.03 118.57,70.96 118.57,69.61 118.24,69.28 117.59,69.28 117.27,69.6 117.27,70.55 116.74,71.08 115.11,71.08 113.87,69.84 113.87,67.84 113.49,67.46 111.96,67.46 111.63,67.8 111.63,68.4 111.48,68.55 109.98,68.55 v1(109.58,68.95)
LPDDR4_DQS2_P: length 31.5
  TOP w0.157: U37.M3 v1(108.78,68.95) ; U40.W3 129.46,71.01 v1(129.46,71.01)
  L4-SIGNAL w0.147: v1(129.46,71.01) 129.18,71.01 128.66,71.54 127.16,71.54 126.65,71.03 126.65,70.53 126.65,70.53 126.65,70.19 126.65,70.19 126.65,70.06 126.54,69.94 124.98,69.94 124.81,69.77 124.12,69.77 123.96,69.93 121.98,69.93 121.64,69.59 120.06,69.59 119.68,69.96 119.68,71.06 119.41,71.34 118.52,71.34 118.26,71.08 118.26,69.74 118.11,69.59 117.72,69.59 117.58,69.73 117.58,70.42 117.58,70.43 117.58,70.68 116.87,71.39 114.99,71.39 113.56,69.97 113.56,67.97 113.36,67.77 112.09,67.77 111.93,67.93 111.93,68.53 111.6,68.85 111.01,68.85 110.77,69.09 110.77,69.11 110.54,69.34 109.17,69.34 v1(108.78,68.95)
LPDDR4_DQS3_N: length 22
  TOP w0.157: U40.V10 124.25,70.68 v1(124.65,71.01) ; U37.R1 110.38,71.35 v1(110.38,71.35)
  L2-SIGNAL w0.114: v1(110.38,71.35) 110.52,71.21 112.14,71.21 112.47,71.54 112.47,72.21 112.75,72.48 113.58,72.48 113.86,72.21 113.86,70.59 113.98,70.46 114.24,70.46 114.36,70.59 114.36,72.19 114.63,72.46 115.33,72.46 115.6,72.19 115.6,71.49 115.75,71.34 116.53,71.34 116.84,71.64 120.3,71.64 120.57,71.37 120.57,71.03 120.8,70.8 121.01,70.8 121.66,71.45 122.1,71.45 122.29,71.64 123.58,71.64 123.82,71.4 124.01,71.4 124.41,71.01 v1(124.65,71.01)
LPDDR4_DQS3_P: length 22
  TOP w0.157: U40.W10 123.86,71.01 v1(123.85,71.01) ; v1(109.58,71.35) 109.18,71.75 U37.R2
  L2-SIGNAL w0.114: v1(123.85,71.01) 123.47,71.39 122.4,71.39 122.21,71.2 121.76,71.2 121.11,70.55 120.7,70.55 120.32,70.93 120.32,71.26 120.19,71.39 116.94,71.39 116.64,71.08 115.64,71.08 115.34,71.39 115.34,72.09 115.23,72.2 114.73,72.2 114.62,72.09 114.62,70.48 114.34,70.21 113.88,70.21 113.6,70.48 113.6,72.1 113.47,72.23 112.85,72.23 112.73,72.1 112.73,71.44 112.25,70.96 109.97,70.96 v1(109.58,71.35)
LPDDR4_ODT_CA_A: length 6.3
  TOP w0.229: U40.G2 v1(131.06,63.86)
  L2-SIGNAL w0.107: v1(131.06,63.86) 131.44,63.47 131.44,62.45 131.48,62.41 131.48,62.4 131.7,62.19 132.26,62.19 v1(133.96,63.88)
  BOTTOM w0.229: v1(133.96,63.88) R359.1 R365.2
LPDDR4_ODT_CA_B: length 6.5
  TOP w0.229: U40.T2 v1(131.06,69.71)
  L2-SIGNAL w0.107: v1(131.06,69.71) 131.72,70.37 135.6,70.37 v1(135.71,70.26)
  BOTTOM w0.229: 135.71,71.24 R352.2 v1(135.71,70.26)
LPDDR4_RST#: length 20.1
  TOP w0.229: v1(123.05,69.06) 123.45,69.38 U40.T11 ; U37.K6 v1(106.38,67.35)
  L2-SIGNAL w0.107: v1(123.05,69.06) 122.68,68.69 122.68,67.67 122.63,67.61 122.63,67.6 122.41,67.39 122.1,67.39 122.1,67.39 121.75,67.39 121.46,67.68 117.86,67.68 v1(117.47,68.06) 117.07,67.66 115.29,67.66 114.76,68.19 110.94,68.19 110.75,67.99 110.75,67.99 110.53,67.78 110.52,67.76 106.79,67.76 v1(106.38,67.35)
LPDDR4_ZQ0: length 1.7
  TOP w0.229: U40.A5 v1(128.66,59.96)
  BOTTOM w0.229: R373.2 128.02,59.75 128.22,59.96 v1(128.66,59.96)
LPDDR4_ZQ1: length 1.6
  TOP w0.229: U40.A8 v1(126.25,59.96)
  BOTTOM w0.229: R374.2 126.87,59.63 126.55,59.96 v1(126.25,59.96)
LS2_CT: length 1.5
  TOP w0.191: U28.6 172.31,95.52 C181.1
LS3_CT: length 1.6
  BOTTOM w0.229: U68.6 64.46,95.12 64.39,95.11
MCAN_EN: length 67.3
  TOP w0.229: v1(87.18,64.15) 87.58,64.55 U37.F29
  L7-SIGNAL w0.107: v1(87.18,64.15) 86.53,64.15 85.75,63.36 81.92,63.36 80.9,62.35 77.6,62.35 73.15,57.9 62.99,57.9 61.72,56.63 49.78,56.63 48.9,55.74 44.32,55.74 43.81,56.25 43.05,56.25 42.29,55.49 39.5,55.49 38.23,54.22 34.29,54.22 34.16,54.35 27.3,54.35 v1(26.42,53.46)
  BOTTOM w0.191: 26.42,52.44 v1(26.42,53.46)
MCAN_NFAULT: length 75.6
  TOP w0.229: v1(88.78,64.15) 88.78,64.15 U37.F27
  L5-SIGNAL w0.163: v1(25.15,45.07) 25.15,46.73 26.29,47.87 26.29,49.39 v1(27.56,50.66)
  L7-SIGNAL w0.107: v1(27.56,50.66) 28.07,51.17 31.12,51.17 31.37,50.91 50.92,50.91 54.1,54.09 71.75,54.09 78.95,61.29 85.68,61.29 86.51,62.12 87.27,62.12 87.55,62.39 87.55,62.63 87.6,62.69 87.6,62.7 87.82,62.92 88.07,62.92 88.35,63.19 88.35,63.5 88.34,63.5 88.34,63.71 v1(88.78,64.15)
  BOTTOM w0.191: 25.15,46.09 v1(25.15,45.07)
MCASP1_ACLKX_BOOTMODE6: length 51.3
  TOP w0.191: R94.1 v1(48.26,94.48) R100.1
  TOP w0.229: v1(88.78,77.75) 89.18,77.35 U37.AB27
  L4-SIGNAL w0.163: v1(48.26,94.48) 48.26,92.83 50.29,90.79 50.42,90.79 60.34,80.88 60.83,80.38 63.5,80.38 63.92,79.96 67.14,79.96 67.85,80.67 72.42,80.67 72.7,80.95 80.33,80.95 80.41,80.87 83.07,80.87 85.47,78.48 86.69,78.48 87.01,78.15 88.37,78.15 v1(88.78,77.75)
MCASP1_AFSX: length 50
  TOP w0.191: R93.1 v1(47.37,94.48)
  TOP w0.229: v1(87.98,76.95) 88.38,76.55 U37.AA28
  L4-SIGNAL w0.163: v1(47.37,94.48) 47.37,92.95 v1(60.71,79.62)
  L5-SIGNAL w0.163: v1(60.71,79.62) 61.85,78.48 71.25,78.48 72.55,77.18 83.72,77.18 83.95,76.95 v1(87.98,76.95)
MCASP2_AXR3_BOOTMODE3: length 25.5
  TOP w0.191: v1(67.06,77.84) 67.02,77.88 R128.1
  TOP w0.229: v1(90.38,76.15) 90.78,75.75 U37.Y25
  L5-SIGNAL w0.163: v1(67.06,77.84) 71.25,77.84 72.19,76.9 83.24,76.9 83.59,76.55 89.97,76.55 v1(90.38,76.15)
MCASP3_ACLKX: length 33.5
  TOP w0.191: R109.1 v1(65.41,88)
  TOP w0.229: v1(94.38,81.75) 94.78,81.35 U37.AG20
  L5-SIGNAL w0.163: v1(94.38,81.75) 93.98,82.15 93.98,83.3 92.58,84.7 91.95,84.7 89.41,87.24 73.26,87.24 72.49,88 v1(65.41,88)
MCASP3_AFSX: length 25.9
  TOP w0.191: R120.1 v1(70.99,83.3)
  TOP w0.229: v1(93.58,79.35) 93.98,78.95 U37.AD21
  L5-SIGNAL w0.163: v1(70.99,83.3) 81,83.3 81.03,83.27 82.29,83.27 82.3,83.28 87.27,83.28 89.2,81.35 91.34,81.35 91.39,81.4 92.2,81.4 93.58,80.02 v1(93.58,79.35)
MCASP7_ACLKX: length 21.3
  TOP w0.191: R122.1 v1(71.5,81.9)
  TOP w0.229: U37.AF24 91.58,80.55 v1(91.18,80.95)
  L7-SIGNAL w0.107: v1(71.5,81.9) 78.87,81.9 79.45,81.32 90.81,81.32 v1(91.18,80.95)
MCASP7_AFSX: length 29.1
  TOP w0.191: R116.1 v1(65.3,85.71)
  TOP w0.229: U37.AJ24 91.58,82.95 v1(91.18,83.35)
  L7-SIGNAL w0.107: v1(91.18,83.35) 91.18,83.82 88.65,86.35 80.52,86.35 80.19,86.68 76.4,86.68 75.44,85.71 v1(65.3,85.71)
MCU_ADC0_AIN0: length 97
  TOP w0.229: U37.K25 90.78,67.75 v1(90.38,67.35)
  L4-SIGNAL w0.163: v1(67.69,62.85) 68.07,62.47 71.75,62.47 72.26,62.98 83.44,62.98 86.6,66.15 87.34,66.15 87.38,66.18 87.77,66.18 87.81,66.15 88.14,66.15 88.37,66.38 88.37,66.66 88.38,66.66 88.38,66.71 88.61,66.94 89.97,66.94 v1(90.38,67.35)
  L7-SIGNAL w0.107: v1(6.35,54.18) 8.68,56.5 9.53,56.5 11.43,58.41 11.43,59.96 11.39,60 11.39,60.34 12.7,61.66 12.7,64.12 14.1,65.52 20.95,65.52 21.49,66.06 21.89,66.06 21.97,65.98 39.04,65.98 39.75,65.27 51.05,65.27 53.47,62.85 v1(67.69,62.85)
  BOTTOM w0.191: v1(6.35,54.18) J21.108
MCU_ADC0_AIN1: length 97.5
  TOP w0.229: v1(89.58,67.35) 89.98,67.75 U37.K26
  L7-SIGNAL w0.107: v1(89.58,67.35) 89.2,66.97 84.89,66.97 83.19,65.27 82.17,65.27 80.64,63.74 53.47,63.74 51.56,65.65 39.88,65.65 39.14,66.38 21.44,66.38 20.95,65.9 13.97,65.9 12.32,64.25 12.32,61.92 10.03,59.64 10.03,57.77 9.27,57.01 7.24,57.01 5.71,55.49 5.71,54.09 v1(6.35,53.46)
  BOTTOM w0.191: v1(6.35,53.46) 6.23,53.58 J21.107
MCU_ADC0_AIN2: length 96.7
  TOP w0.229: v1(87.98,67.35) 88.38,67.75 U37.K28
  L7-SIGNAL w0.107: v1(3.94,53.08) 3.94,54.98 7.37,58.41 7.49,58.41 11.94,62.85 11.94,64.38 13.84,66.28 20.83,66.28 21.21,66.66 39.24,66.66 39.81,67.23 50.74,67.23 53.85,64.12 80.64,64.12 82.17,65.65 82.93,65.65 84.99,67.7 86.87,67.7 86.88,67.72 87.33,67.72 87.7,67.35 v1(87.98,67.35)
  BOTTOM w0.191: J21.106 4.03,52.98 v1(3.94,53.08)
MCU_ADC0_AIN3: length 99.2
  TOP w0.229: U37.L28 88.38,68.55 v1(87.98,68.15)
  L7-SIGNAL w0.107: v1(3.94,52.38) 3.4,52.92 3.4,55.96 6.35,58.92 7.37,58.92 11.56,63.11 11.56,64.51 13.62,66.57 19.34,66.57 20.07,67.3 22.48,67.3 22.85,66.93 29.98,66.93 30.99,67.93 50.93,67.93 54.36,64.51 77.85,64.51 80.77,67.43 82.42,67.43 83.14,68.15 v1(87.98,68.15)
  BOTTOM w0.191: J21.105 v1(3.94,52.38)
MCU_ADC0_AIN4: length 25.3
  TOP w0.229: U37.K24 91.58,67.75 v1(91.18,67.35)
  L4-SIGNAL w0.163: TP46.1 69.72,64.12 81.28,64.12 82.17,65.01 83.44,65.01 86.17,67.74 89.41,67.74 89.41,67.75 89.74,67.75 89.74,67.74 90.78,67.74 v1(91.18,67.35)
MCU_ADC0_AIN5: length 20
  TOP w0.229: v1(88.78,67.35) 89.18,67.75 U37.K27
  L4-SIGNAL w0.163: TP48.1 71.45,63.31 83,63.31 86.64,66.95 88.14,66.95 88.54,67.35 v1(88.78,67.35)
MCU_ADC0_AIN6: length 19.7
  TOP w0.229: U37.K29 87.18,67.35 v1(87.18,67.35)
  L4-SIGNAL w0.163: TP47.1 70.61,63.74 82.93,63.74 86.53,67.35 v1(87.18,67.35)
MCU_BOOTMODE6: length 44.5
  TOP w0.191: 63.88,41.14 v1(63.88,40.12)
  TOP w0.229: v1(87.18,65.75) 87.18,65.75 U37.H29
  L2-SIGNAL w0.107: v1(87.18,65.75) 85.19,65.75 83.16,63.72 80.62,63.72 74.04,57.14 v1(66.67,57.14)
  L4-SIGNAL w0.163: v1(63.88,40.12) 63.88,40.76 64.52,41.39 64.52,44.31 65.79,45.58 65.79,53.84 66.04,54.09 66.04,56.5 v1(66.67,57.14)
  BOTTOM w0.191: R420.1 v1(63.88,40.12)
MCU_BOOTMODE8: length 25.8
  TOP w0.191: 69.85,53.96 69.22,54.6 v1(69.22,56.12) RJ12.2
  TOP w0.229: v1(87.18,64.95) 87.58,65.35 U37.G29
  L2-SIGNAL w0.107: v1(87.18,64.95) 85.53,64.95 83.82,63.24 81.15,63.24 73.66,55.74 71.38,55.74 70.99,56.12 v1(69.22,56.12)
MCU_BOOTMODE9: length 24.1
  TOP w0.191: RJ13.2 v1(71.75,56.12) 71.75,54.6 71.12,53.96
  TOP w0.229: v1(87.98,65.75) 87.98,65.75 U37.H28
  L2-SIGNAL w0.107: v1(87.98,65.75) 87.6,65.37 85.45,65.37 83.57,63.49 80.9,63.49 73.53,56.12 v1(71.75,56.12)
MCU_CAN0_STBZ: length 68.6
  TOP w0.229: U37.H26 89.98,66.15 v1(89.58,65.75)
  L4-SIGNAL w0.163: v1(55.24,49.27) 55.24,57.9 57.15,59.81 67.56,59.81 68.96,61.2 83.82,61.2 86.36,63.75 88.14,63.75 88.37,63.98 88.37,64.36 88.56,64.55 88.94,64.55 89.17,64.78 89.17,65.11 89.14,65.14 89.14,65.31 v1(89.58,65.75)
  L5-SIGNAL w0.163: v1(34.8,49.27) v1(55.24,49.27)
  BOTTOM w0.191: R403.1 v1(34.8,49.27)
MCU_CAN1_STBZ: length 39.4
  TOP w0.229: U37.H27 88.78,65.75 v1(88.78,65.75)
  L4-SIGNAL w0.163: v1(88.78,65.75) 88.78,65.51 88.37,65.11 88.37,64.78 88.14,64.55 88.1,64.55 88.09,64.54 87.81,64.54 87.78,64.51 87.37,64.51 87.34,64.54 87.01,64.54 86.98,64.51 86.49,64.51 84.2,62.22 73.03,62.22 72.39,61.58 68.71,61.58 68.07,60.95 v1(61.85,60.95)
  L5-SIGNAL w0.163: v1(60.83,52.69) 60.83,53.96 61.85,54.98 v1(61.85,60.95)
  BOTTOM w0.191: R386.1 v1(60.83,52.69)
MCU_CONSOLE_RXD: length 42.7
  TOP w0.191: RJ15.2 v1(70.48,52.31) ; R223.2 v1(47.62,28.82)
  L4-SIGNAL w0.163: v1(70.48,38.47) v1(70.48,52.31)
  L7-SIGNAL w0.107: v1(47.62,28.82) 51.44,28.82 61.47,38.85 67.44,38.85 67.82,38.47 v1(70.48,38.47)
MCU_CONSOLE_TXD: length 45.3
  TOP w0.191: RJ14.2 v1(69.09,52.95) ; v1(44.96,27.82) U55.11
  L4-SIGNAL w0.163: v1(69.09,52.95) 69.98,52.06 v1(69.98,39.49)
  L7-SIGNAL w0.107: v1(69.98,39.49) 69.6,39.11 61.21,39.11 51.44,29.33 46.47,29.33 v1(44.96,27.82)
MCU_DMTIMER2: length 152.1
  TOP w0.191: U38.2 TP43.1
  TOP w0.229: U37.A28 87.98,60.14 v1(87.98,60.14)
  L4-SIGNAL w0.163: v1(183.9,68.82) TP43.1
  L5-SIGNAL w0.163: v1(87.98,60.14) 87.98,59.73 87.88,59.64 87.88,58.41 89.06,57.24 89.06,54.88 88.62,54.45 88.62,48.78 94.3,43.11 123.89,43.11 125.09,44.31 138.56,44.31 140.72,42.15 158.5,42.15 160.53,40.12 177.93,40.12 180.85,43.04 180.85,51.55 182.75,53.46 182.75,55.23 185.04,57.52 185.04,60.82 183.9,61.97 v1(183.9,68.82)
MCU_DMTIMER3: length 156.6
  TOP w0.191: C64.2 TP6.1
  TOP w0.229: U37.A27 89.18,60.54 v1(88.78,60.14)
  L2-SIGNAL w0.107: v1(88.78,60.14) 88.78,59.56 87.5,58.28 82.93,58.28 81.77,57.12 80.12,57.12 74.15,51.15 57.81,51.15 56.52,52.44 56.52,77.21 57.64,78.33 57.64,93.61 57.4,93.84 57.4,117.21 62.48,122.29 62.48,127.12 65.66,130.29 77.6,130.29 78.74,129.15 v1(79.88,129.15)
  L4-SIGNAL w0.163: v1(79.88,129.15) 93.34,129.15 94.74,127.75 100.12,127.75 100.25,127.88 TP6.1
MCU_DMTIMER4: length 130.4
  TOP w0.191: C354.1 TP59.1
  TOP w0.229: U37.A25 90.38,60.14 v1(90.38,60.14)
  L4-SIGNAL w0.163: TP59.1 199.14,46.47 186.18,46.47 181.74,42.03 169.16,42.03 v1(168.66,42.53)
  L5-SIGNAL w0.163: v1(90.38,60.14) 90.38,57.82 91.34,56.86 91.34,47.33 94.75,43.92 122.55,43.92 123.83,45.2 141.6,45.2 142.37,44.44 142.37,43.55 143.38,42.53 159.51,42.53 161.16,40.88 167,40.88 v1(168.66,42.53)
MCU_DMTIMER5: length 120.1
  TOP w0.191: C451.1 TP71.1
  TOP w0.229: v1(91.18,62.55) 91.18,62.55 U37.D24
  L5-SIGNAL w0.163: v1(91.18,62.55) 91.18,58.17 91.69,57.65 91.69,47.61 94.9,44.41 122.27,44.41 123.4,45.54 141.9,45.54 144.57,42.87 163.28,42.87 v1(163.58,43.17)
  L7-SIGNAL w0.107: TP71.1 v1(163.58,43.17)
MCU_DMTIMER8: length 15.4
  TOP w0.191: RJ17.1 TP58.1
  TOP w0.229: v1(89.58,62.55) 89.98,62.95 U37.D26
  L5-SIGNAL w0.163: v1(89.58,62.55) 89.97,62.15 89.97,60.5 89.79,60.31 89.79,54.22 89.41,53.84 TP58.1
MCU_DMTIMER9: length 92.2
  TOP w0.229: U37.D25 90.38,62.55 v1(90.38,62.55)
  L2-SIGNAL w0.107: TP20.1 56.9,100.9 56.9,100.9 56.9,93.59 57.28,93.21 57.28,78.73 56.13,77.59 56.13,52.31 57.66,50.79 74.3,50.79 80.26,56.76 81.92,56.76 82.8,57.65 87.63,57.65 89.41,59.43 89.41,60.7 90.38,61.66 v1(90.38,62.55)
  BOTTOM w0.163: TP20.1 56.98,101.42 R286.2
MCU_HYPERBUS0_CS1#: length 21.3
  TOP w0.191: R185.1 v1(80.39,50.92)
  TOP w0.229: U37.E22 93.18,63.75 v1(92.78,63.35)
  L2-SIGNAL w0.107: v1(92.78,63.35) 89.79,60.36 89.79,59.3 87.76,57.27 87.76,55.23 86.36,53.84 82.3,53.84 80.39,51.93 v1(80.39,50.92)
MCU_HYPERBUS0_RESETO#: length 2.8
  TOP w0.191: R186.2 80.99,48.46 v1(79.87,48.46)
  BOTTOM w0.191: U73.A2 v1(79.87,48.46)
MCU_I2C0_SCL: length 172.6
  TOP w0.191: v1(71.25,60.44) R163.2 ; v1(129.69,92.68) U27.32
  TOP w0.229: U37.J26 89.58,66.55 v1(89.58,66.55)
  L2-SIGNAL w0.107: v1(140.34,86.1) 140.34,80.38 138.68,78.73 138.68,77.21 138.94,76.95 138.94,58.03 133.86,52.95 133.86,41.65 v1(133.73,41.52)
  L4-SIGNAL w0.163: v1(72.01,40.25) 72.01,50.54 73.15,51.68 73.15,58.54 v1(71.25,60.44)
  L5-SIGNAL w0.163: v1(72.01,40.25) 76.71,40.25 77.22,39.74 125.6,39.74 127.38,41.52 130.31,41.52 130.69,41.14 133.35,41.14 v1(133.73,41.52) ; v1(71.25,60.44) 77.09,60.44 82.17,65.52 85.34,65.52 85.97,66.15 89.18,66.15 v1(89.58,66.55) ; v1(140.34,86.1) 139.57,85.33 130.56,85.33 129.69,86.19 v1(129.69,92.68)
MCU_I2C0_SDA: length 170.7
  TOP w0.191: v1(130.2,94.22) U27.33 ; R166.2 v1(71.25,59.55)
  TOP w0.229: v1(90.38,65.75) 90.38,65.75 U37.H25
  L2-SIGNAL w0.107: v1(139.45,86.1) 139.45,83.17 139.19,82.92 139.19,79.75 138.3,78.86 138.3,77.08 138.56,76.82 138.56,58.16 133.48,53.08 133.48,42.28 v1(132.97,41.77)
  L4-SIGNAL w0.163: v1(71.5,40.79) 71.5,50.92 72.52,51.93 72.52,58.28 v1(71.25,59.55)
  L5-SIGNAL w0.163: v1(132.97,41.77) 130.81,41.77 130.71,41.88 127.1,41.88 125.32,40.09 77.5,40.09 76.8,40.79 v1(71.5,40.79) ; v1(139.45,86.1) 139.19,85.84 130.68,85.84 130.2,86.33 v1(130.2,94.22) ; v1(90.38,65.75) 89.98,65.35 85.99,65.35 85.65,65.01 82.17,65.01 76.71,59.55 v1(71.25,59.55)
MCU_MCAN0_RX: length 64.6
  TOP w0.229: v1(87.18,61.75) 87.18,61.75 U37.C29
  L7-SIGNAL w0.107: v1(87.18,61.75) 86.65,61.75 85.85,60.95 79.12,60.95 72.01,53.84 54.23,53.84 51.08,50.69 31.14,50.69 30.61,50.15 29.46,50.15 v1(28.96,50.66)
  BOTTOM w0.191: R389.1 v1(28.96,50.66)
MCU_MCAN0_TX: length 59.8
  TOP w0.229: v1(87.18,62.55) 87.58,62.95 U37.D29
  L7-SIGNAL w0.107: v1(87.18,62.55) 86.43,62.55 86.11,62.22 82.17,62.22 81.53,61.58 78.61,61.58 71.37,54.35 53.98,54.35 50.77,51.14 33.81,51.14 v1(33.53,51.42)
  BOTTOM w0.191: R388.1 v1(33.53,51.42)
MCU_MCAN1_RX: length 39.5
  TOP w0.229: U37.G24 91.58,65.35 v1(91.18,64.95)
  L2-SIGNAL w0.107: v1(91.18,64.95) 90.8,65.32 88.6,65.32 88.35,65.57 88.35,65.9 88.13,66.12 85.05,66.12 82.93,64 80.39,64 76.43,60.03 58.77,60.03 v1(57.02,58.28)
  BOTTOM w0.191: R372.1 v1(57.02,58.28)
MCU_MCAN1_TX: length 34.5
  TOP w0.229: U37.G25 90.38,64.95 v1(90.38,64.95)
  L4-SIGNAL w0.163: v1(60.83,58.28) 61.94,59.39 69.18,59.39 70.64,60.85 71.85,60.85 72.01,60.7 84.84,60.7 86.28,62.14 87.34,62.14 87.58,62.38 87.58,62.71 87.81,62.94 88.14,62.94 88.37,63.18 88.37,63.51 88.61,63.74 88.94,63.74 89.17,63.98 89.17,64.31 89.41,64.54 89.97,64.54 v1(90.38,64.95)
  BOTTOM w0.191: R371.1 v1(60.83,58.28)
MCU_OSPI0_CLK_N: length 18.7
  TOP w0.122: R194.1 81.87,46.9 v1(81.87,47.46)
  L4-SIGNAL w0.122: v1(92.13,56.43) 91.71,56.02 91.71,55.7 91,54.98 89.99,54.98 87.33,52.31 86.44,52.31 86.43,52.31 85.67,52.31 83.13,49.77 83.13,48.33 83.02,48.22 82.61,48.22 82.5,48.11 82.5,47.95 82.61,47.84 83.02,47.84 83.13,47.73 83.13,47.48 83.01,47.36 81.98,47.36 v1(81.87,47.46)
  BOTTOM w0.122: U73.B1 v1(81.87,47.46) ; v1(92.13,56.43) 92.49,56.79 R378.2
MCU_OSPI0_CLK_P: length 18.7
  TOP w0.122: R190.1 v1(80.87,47.46)
  L4-SIGNAL w0.122: v1(92.13,55.68) 91.12,54.68 90.12,54.68 87.45,52.01 86.31,52.01 85.8,52.01 83.44,49.65 83.44,47.36 83.14,47.06 81.28,47.06 v1(80.87,47.46)
  BOTTOM w0.122: v1(92.13,55.68) 92.39,55.68 R383.2 ; U73.B2 v1(80.87,47.46)
MCU_OSPI0_CS0#: length 32.4
  TOP w0.191: R195.1 80.94,45.53 v1(80.87,45.46)
  TOP w0.229: v1(95.18,64.15) 95.18,64.15 U37.F19
  L2-SIGNAL w0.107: v1(80.87,45.46) 80.87,46.32 81.41,46.85 82.93,46.85 83.19,46.59 83.19,45.34 83.3,45.23 84.74,45.23 85.72,46.22 85.72,46.98 88.52,49.77 88.52,53.08 90.17,54.72 90.17,56.88 93.19,59.91 93.19,60.29 93.48,60.57 93.73,60.57 93.95,60.79 93.95,61.1 93.98,61.13 93.98,61.87 94.22,62.12 94.51,62.12 94.81,62.41 94.81,62.7 95.02,62.92 95.33,62.92 95.63,63.22 95.63,63.69 v1(95.18,64.15)
  BOTTOM w0.191: U73.C2 v1(80.87,45.46)
MCU_OSPI0_D0: length 33.9
  TOP w0.191: R206.2 80.34,43.22 80.34,44 v1(79.87,44.46)
  TOP w0.229: U37.D20 94.78,62.95 v1(94.38,62.55)
  L4-SIGNAL w0.163: v1(94.38,62.55) 93.98,62.15 93.41,62.15 92.38,61.11 92.38,59.47 88.77,55.87 88.27,55.87 85.98,53.58 85.64,53.58 85.29,53.94 85.06,53.94 84.9,53.78 84.9,53.55 85.22,53.24 85.22,52.82 84.45,52.06 84.13,52.06 83.39,52.8 83.16,52.8 83,52.64 83,52.41 83.6,51.81 83.6,51.59 83.44,51.43 83.22,51.43 82.62,52.03 82.39,52.03 82.23,51.87 82.23,51.65 82.83,51.05 82.83,50.82 80.39,48.38 80.39,47.23 80.77,46.85 80.77,46.09 80.39,45.71 80.39,44.98 v1(79.87,44.46)
  BOTTOM w0.191: U73.D3 v1(79.87,44.46)
MCU_OSPI0_D1: length 34.2
  TOP w0.191: v1(80.87,44.46) 81.34,43.99 82.07,43.99 82.26,43.8 R203.2
  TOP w0.229: U37.G19 95.18,64.95 v1(95.18,64.95)
  L4-SIGNAL w0.163: v1(95.18,64.95) 95.58,64.55 95.58,61.58 95.57,61.58 95.57,59.99 96.01,59.55 96.01,56 95.12,55.11 94.36,55.11 93.6,54.35 93.6,53.46 90.17,50.03 88.65,50.03 85.47,46.85 85.47,45.84 84.96,45.33 83.82,45.33 82.42,43.93 81.41,43.93 v1(80.87,44.46)
  BOTTOM w0.191: U73.D2 v1(80.87,44.46)
MCU_OSPI0_D2: length 32.8
  TOP w0.191: R196.2 77.37,45.96 v1(77.87,46.46)
  TOP w0.229: v1(94.38,64.95) 94.78,65.35 U37.G20
  L4-SIGNAL w0.163: v1(77.87,46.46) 77.22,46.46 76.83,46.85 76.83,48.88 77.36,49.41 77.36,50.27 76.83,50.79 76.83,51.81 78.87,53.84 79.25,53.84 83.69,58.28 87.63,58.28 89.28,59.93 89.28,60.7 90.78,62.19 90.78,62.71 91.01,62.94 91.06,62.94 91.06,62.95 91.4,62.95 91.69,63.24 91.69,63.62 92.62,64.55 93.98,64.55 v1(94.38,64.95)
  BOTTOM w0.191: U73.C4 v1(77.87,46.46)
MCU_OSPI0_D3: length 34.3
  TOP w0.191: v1(78.87,44.46) 78.11,43.7 78.11,43.17 R204.2
  TOP w0.229: v1(94.38,64.15) 94.38,64.15 U37.F20
  L4-SIGNAL w0.163: v1(78.87,44.46) 78.87,45.72 79.31,46.15 79.31,46.79 79.05,47.05 78.67,47.05 78.36,47.36 78.36,51.04 79.76,52.44 80.52,52.44 80.9,52.82 80.9,54.29 83.75,57.14 84.84,57.14 85.37,56.6 86.08,56.6 87,57.52 88.52,57.52 90.93,59.93 90.93,60.84 92.91,62.82 92.91,62.92 93.17,63.18 93.17,63.51 93.41,63.75 93.98,63.75 v1(94.38,64.15)
  BOTTOM w0.191: U73.D4 v1(78.87,44.46)
MCU_OSPI0_D4: length 32.8
  TOP w0.191: v1(77.87,44.46) 77.22,44.46 R201.2
  TOP w0.229: v1(93.58,64.15) 93.58,64.15 U37.F21
  L4-SIGNAL w0.163: v1(93.58,64.15) 93.01,64.15 92.08,63.21 92.08,62.36 91.43,61.71 90.93,61.71 89.79,60.57 89.79,59.55 88.14,57.9 83.95,57.9 79.38,53.33 78.99,53.33 77.85,52.19 77.85,49.01 77.34,48.5 77.34,47.16 77.63,46.88 78.2,46.88 78.36,46.71 78.36,45.84 77.87,45.35 v1(77.87,44.46)
  BOTTOM w0.191: U73.D5 v1(77.87,44.46)
MCU_OSPI0_D5: length 34.4
  TOP w0.191: R205.2 79.87,42.9 v1(79.87,43.46)
  TOP w0.229: U37.E21 93.98,63.75 v1(93.58,63.35)
  L4-SIGNAL w0.163: v1(93.58,63.35) 93.58,63.21 93.18,62.81 93.18,62.71 91.54,61.08 91.54,59.78 88.77,57.01 88.14,57.01 87.04,55.92 83.87,55.92 83.66,55.71 83.66,55.49 84.07,55.08 84.07,54.85 83.91,54.69 83.69,54.69 83.28,55.1 83.05,55.1 82.89,54.94 82.89,54.72 83.3,54.31 83.3,54.08 83.14,53.92 82.92,53.92 82.51,54.33 82.28,54.33 81.53,53.58 81.53,51.55 81.03,51.04 81.03,50.41 79.38,48.76 79.38,47.38 79.78,46.98 80.14,46.98 80.39,46.73 80.39,46.27 80.15,46.03 79.69,46.03 79.38,45.71 U73.E3 v1(79.87,43.46)
  BOTTOM w0.191: U73.E3 v1(79.87,43.46)
MCU_OSPI0_D6: length 33.1
  TOP w0.191: R207.2 81.11,43.46 v1(80.87,43.46)
  TOP w0.229: U37.B22 93.18,61.35 v1(92.78,60.95)
  L4-SIGNAL w0.163: v1(80.87,43.46) 80.39,43.95 80.39,44.56 80.78,44.95 82.15,44.95 83.04,45.84 83.82,45.84 84.9,46.92 84.9,47.14 84.55,47.49 84.55,47.71 84.71,47.87 84.94,47.87 85.28,47.53 85.51,47.53 89.53,51.55 89.92,51.55 91.69,53.33 91.69,53.84 93.85,56 93.85,56.29 93.69,56.45 92.87,56.45 92.71,56.6 92.71,56.83 92.87,56.99 93.69,56.99 93.85,57.15 93.85,57.37 93.69,57.53 91.87,57.53 91.71,57.7 91.71,58.04 93.18,59.51 93.18,60.54 v1(92.78,60.95)
  BOTTOM w0.191: U73.E2 v1(80.87,43.46)
MCU_OSPI0_D7: length 35.2
  TOP w0.191: v1(81.87,43.46) 82.13,43.46 R208.2
  TOP w0.229: v1(93.58,64.95) 93.58,64.95 U37.G21
  L4-SIGNAL w0.163: v1(93.58,64.95) 93.97,65.34 96.14,65.34 96.37,65.11 96.37,55.85 95.25,54.73 94.61,54.73 93.98,54.09 93.98,53.31 87.88,47.22 87.88,46.73 85.47,44.31 83.57,44.31 82.72,43.46 v1(81.87,43.46)
  BOTTOM w0.191: U73.E1 v1(81.87,43.46)
MCU_OSPI0_DQS: length 28.2
  TOP w0.191: R197.2 v1(84.58,45.84) 84.71,45.84 R200.2
  TOP w0.229: U37.D21 93.58,62.55 v1(93.58,62.55)
  L2-SIGNAL w0.107: v1(84.58,45.84) 84.58,46.6 85.59,47.6 85.59,47.8 84.58,48.81 84.58,49.01 84.72,49.15 84.93,49.15 85.93,48.15 86.13,48.15 86.28,48.29 86.28,48.49 85.52,49.24 85.52,49.45 85.67,49.59 85.87,49.59 86.62,48.84 86.82,48.84 87.76,49.77 87.76,52.95 89.79,54.98 89.79,57.01 92.4,59.63 92.4,60.3 92.62,60.52 92.91,60.52 93.14,60.75 93.14,60.79 93.15,60.79 93.15,61.1 93.14,61.1 93.14,61.52 93.14,61.52 93.14,62.11 v1(93.58,62.55)
MCU_OSPI0_ECC_FAIL: length 24.3
  TOP w0.191: 75.68,47.74 v1(75.68,47.73)
  TOP w0.229: v1(91.98,60.95) 91.98,60.95 U37.B23
  L2-SIGNAL w0.107: v1(91.98,60.95) 91.57,60.54 91.57,59.93 89.15,57.52 89.15,55.36 86.61,52.82 82.93,52.82 81.15,51.04 81.15,50.4 79.76,49.01 76.96,49.01 v1(75.68,47.73)
MCU_OSPI_RST#: length 6.5
  TOP w0.191: v1(78.87,47.46) 78.36,47.98 78.36,50.54 79.63,51.81 79.63,52.45 U45.4
  BOTTOM w0.191: U73.A4 v1(78.87,47.46)
MCU_PORZ_OUT: length 57
  TOP w0.191: Q8.2 91.95,21.07 TP66.1 R242.1
  TOP w0.229: U37.B28 87.98,60.95 v1(87.98,60.95)
  L4-SIGNAL w0.163: v1(87.98,60.95) 87.58,60.55 86.86,60.55 85.61,59.3 82.68,59.3 76.33,52.95 76.33,40.76 91.44,25.64 91.44,24.25 92.46,23.23 TP66.1
MCU_RESETSTATZ: length 9.7
  TOP w0.191: R169.1 TP51.1
  TOP w0.229: v1(88.78,61.75) 89.18,62.15 U37.C27
  L7-SIGNAL w0.107: v1(88.78,61.75) 88.39,61.36 86.89,61.36 84.45,58.92 TP51.1
MCU_RESETZ: length 8.6
  TOP w0.191: TP49.1 R156.1 R155.2
  TOP w0.229: U37.D28 87.98,62.55 v1(87.98,62.55)
  L2-SIGNAL w0.107: v1(87.98,62.55) 87.55,62.12 84.74,62.12 84.33,61.71 TP49.1
MCUBOOT_BUFF_ENZ: length 274.3
  TOP w0.191: U55.15 44.69,29.82 v1(44.83,29.96) 45.85,29.96 45.85,31.1 ; v1(91.31,23.1) 91.3,23.12 Q8.6 ; v1(194.69,70.22) 194.72,70.25 U38.1
  L4-SIGNAL w0.163: v1(184.4,70.22) v1(194.69,70.22)
  L5-SIGNAL w0.163: v1(44.83,29.96) 44.32,29.45 44.32,27.42 44.58,27.17 44.58,22.47 42.55,20.44 42.55,19.93 43.05,19.42 49.91,19.42 53.85,23.36 58.73,23.36 58.76,23.33 59.1,23.33 59.13,23.36 59.94,23.36 60.33,22.98 66.55,22.98 66.93,23.36 72.77,23.36 73.46,22.67 76.65,22.67 77.09,23.1 v1(91.31,23.1) 95.63,23.1 95.76,22.98 99.06,22.98 99.82,23.74 99.82,28.82 101.85,30.85 103.5,30.85 103.95,30.41 106.11,30.41 106.43,30.09 108.58,30.09 110.36,31.87 147.19,31.87 154.81,39.49 178.05,39.49 182.25,43.68 182.25,50.66 185.55,53.96 185.55,61.46 184.4,62.6 v1(184.4,70.22) ; v1(3.95,48.77) 1.91,46.73 1.91,30.34 v1(2.79,29.45)
  L7-SIGNAL w0.107: v1(2.79,29.45) 8.89,29.45 10.03,28.31 18.92,28.31 19.43,27.8 36.07,27.8 37.08,28.82 40.01,28.82 41.15,29.96 v1(44.83,29.96)
  BOTTOM w0.191: J21.99 v1(3.95,48.77)
MDIO0_MDC: length 56.6
  TOP w0.191: U42.1 v1(43.43,61.43)
  TOP w0.229: v1(91.18,74.55) 91.58,74.15 U37.V24
  L4-SIGNAL w0.163: v1(91.18,74.55) 90.78,74.95 87.81,74.95 87.57,75.19 87.57,75.51 87.15,75.94 84.58,75.94 83.92,76.6 72.42,76.6 71.37,75.55 57.05,75.55 43.43,61.94 v1(43.43,61.43)
MDIO0_MDIO: length 52.7
  TOP w0.191: U42.36 44.29,60.54 44.45,60.7 R154.2 v1(46.61,60.7)
  TOP w0.229: U37.V26 89.98,74.15 v1(89.58,74.55)
  L4-SIGNAL w0.163: v1(46.61,60.7) 46.99,61.08 48.51,61.08 57.4,69.97 68.58,69.97 69.69,71.07 79.13,71.07 79.72,71.07 80.11,71.46 82.52,71.46 83.78,72.72 86.48,72.72 86.51,72.75 86.59,72.75 86.61,72.76 86.85,72.76 86.9,72.81 88.57,72.81 89.18,73.43 89.18,74.16 v1(89.58,74.55)
MMC0_CALPAD: length 1.4
  TOP w0.229: v1(110.38,80.15) 109.98,79.75 U37.AE1
  BOTTOM w0.229: R331.2 110.72,80.49 v1(110.38,80.15)
MMC0_CLK: length 40.9
  L4-SIGNAL w0.163: v1(115.95,83.43) 116.39,83.43 116.64,83.17 117.35,83.17 117.66,82.86 117.66,82.36 117.82,82.19 118.05,82.19 118.21,82.36 118.21,83.01 118.38,83.17 121.22,83.17 122.24,84.19 128.64,84.19 128.84,83.99 128.84,83.72 129,83.56 129.23,83.56 129.38,83.72 129.38,83.99 129.54,84.15 129.77,84.15 129.93,83.99 129.93,83.72 130.09,83.56 130.31,83.56 130.47,83.72 130.47,83.99 130.63,84.15 130.86,84.15 131.02,83.99 131.02,83.72 131.17,83.56 131.4,83.56 131.56,83.72 131.56,83.99 131.72,84.15 131.94,84.15 132.1,83.99 132.1,83.72 132.26,83.56 132.49,83.56 132.65,83.72 132.65,83.99 132.81,84.15 133.03,84.15 133.19,83.99 133.19,83.72 133.35,83.56 133.57,83.56 133.73,83.72 133.73,83.99 133.89,84.15 134.12,84.15 134.28,83.99 134.28,83.72 134.44,83.56 134.66,83.56 134.82,83.72 134.82,83.99 134.99,84.16 143.98,84.16 144.4,84.57 146.43,84.57 146.94,85.08 v2(146.94,85.97)
  BOTTOM w0.191: v2(146.94,85.97) R317.1 R318.2
MMC0_CMD: length 52.4
  TOP w0.229: v1(108.78,80.15) 108.78,80.14 U37.AE3 ; U31.P5 v2(147.78,86.21)
  L4-SIGNAL w0.163: v2(147.78,86.21) 147.78,85.25 148.34,84.7 148.34,83.94 148.59,83.68 148.59,83.18 148.21,82.79 147.45,82.79 146.94,82.29 146.43,82.29 145.16,83.56 138.05,83.56 137.54,83.05 137.25,83.05 137.09,83.21 137.09,83.4 136.93,83.56 136.71,83.56 136.55,83.4 136.55,83.21 136.39,83.05 136.16,83.05 136.01,83.21 136.01,83.4 135.85,83.56 135.62,83.56 135.46,83.4 135.46,83.21 135.3,83.05 128.65,83.05 128.04,83.66 122.66,83.66 120.62,81.62 117.22,81.62 117.07,81.78 117.07,82.51 116.91,82.67 116.68,82.67 116.52,82.51 116.52,81.78 116.36,81.62 115.25,81.62 114.87,82 114.58,82 114.3,82.29 114.3,82.63 114.01,82.92 113.54,82.92 111.24,80.63 111.2,80.63 111.12,80.55 109.77,80.55 109.37,80.15 v1(108.78,80.15)
  BOTTOM w0.191: R314.2 147.83,86.16 v2(147.78,86.21)
MMC0_DAT0: length 52.5
  TOP w0.229: U31.K2 v2(151.79,89.21) ; U37.AG2 109.58,81.74 v1(109.58,81.75)
  L4-SIGNAL w0.163: v2(151.79,89.21) 151.22,89.78 150.29,89.78 150.09,89.58 150.09,88.83 149.89,88.64 149.62,88.64 149.42,88.83 149.42,89.58 148.97,90.03 146.18,90.03 142.88,86.73 138.56,86.73 138.25,86.42 137.34,86.42 137.03,86.73 135.76,86.73 135.33,86.29 133.66,86.29 133.22,86.73 132.59,86.73 132.15,86.29 130.61,86.29 130.3,86.6 130.3,86.98 129.58,87.71 116.2,87.71 115.7,87.2 114.14,87.2 109.98,83.05 109.98,82.38 109.72,82.12 109.72,81.89 v1(109.58,81.75)
  BOTTOM w0.191: R297.2 151.76,89.23 v2(151.79,89.21)
MMC0_DAT1: length 52.3
  TOP w0.229: U37.AH1 110.38,82.54 v1(110.38,82.55) ; U31.N2 v2(148.79,89.21)
  L4-SIGNAL w0.163: v2(148.79,89.21) 148.34,89.65 146.43,89.65 143,86.22 141.35,86.22 140.81,85.68 139.1,85.68 138.81,85.97 137.16,85.97 136.91,86.22 135.89,86.22 135.51,85.84 133.48,85.84 133.1,86.22 132.72,86.22 132.33,85.84 130.34,85.84 129.79,86.39 129.79,86.86 129.41,87.24 128.06,87.24 127.86,87.04 127.86,86.42 127.67,86.22 127.39,86.22 127.19,86.42 127.19,87.04 127,87.24 126.72,87.24 126.52,87.04 126.52,86.42 126.32,86.22 126.05,86.22 125.85,86.42 125.85,87.04 125.65,87.24 125.38,87.24 125.18,87.04 125.18,86.42 124.98,86.22 124.71,86.22 124.51,86.42 124.51,87.04 124.31,87.24 124.04,87.24 123.84,87.04 123.84,86.42 123.64,86.22 123.36,86.22 123.17,86.42 123.17,87.04 123.01,87.21 122.52,87.21 121.38,86.07 113.5,86.07 110.38,82.95 v1(110.38,82.55)
  BOTTOM w0.191: R298.2 148.84,89.27 v2(148.79,89.21)
MMC0_DAT2: length 52.8
  TOP w0.229: v1(108.78,81.75) 108.78,81.74 U37.AG3 ; U31.K3 v2(151.79,88.21)
  L4-SIGNAL w0.163: v1(108.78,81.75) 108.78,82.48 109.6,83.3 109.73,83.3 113.92,87.49 115.44,87.49 116.2,88.25 117.08,88.25 117.33,88.01 117.86,88.01 117.98,88.13 129.79,88.13 130.68,87.24 136.02,87.24 136.14,87.37 140.72,87.37 140.97,87.11 142.62,87.11 145.92,90.41 151.64,90.41 152.27,89.78 152.27,88.69 v2(151.79,88.21)
  BOTTOM w0.191: v2(151.79,88.21) 151.76,88.19 R311.2
MMC0_DAT3: length 52.4
  TOP w0.229: v1(107.98,80.95) 107.98,80.94 U37.AF4 ; U31.N3 v2(148.79,88.21)
  L4-SIGNAL w0.163: v1(147.26,90.99) 142.69,90.99 142.53,90.83 142.53,90.45 142.37,90.29 142.15,90.29 141.99,90.45 141.99,90.83 141.83,90.99 141.54,90.99 140.21,89.65 125.22,89.65 124.46,90.41 115.19,90.41 114.05,89.27 114.05,88.64 109.47,84.06 109.26,84.06 107.57,82.37 107.57,81.36 v1(107.98,80.95)
  L5-SIGNAL w0.163: v1(147.26,90.99) 148.22,90.02 148.22,88.77 v2(148.79,88.21)
  BOTTOM w0.191: v2(148.79,88.21) 148.84,88.15 R312.2
MMC0_DAT4: length 52.6
  TOP w0.229: v1(107.18,80.15) 107.18,80.14 U37.AE5 ; U31.N8 v2(148.79,82.2)
  L4-SIGNAL w0.163: v2(148.79,82.2) 149.32,82.74 149.92,82.74 150.24,82.41 150.24,80.89 149.99,80.63 146.69,80.63 144.09,83.23 138.49,83.23 137.67,82.41 130.3,82.41 130.05,82.67 123.57,82.67 123.19,83.05 122.68,83.05 120.91,81.28 115.05,81.28 114.68,81.65 114.43,81.65 113.92,82.16 113.54,82.16 112.94,81.56 112.66,81.56 110.86,79.77 110.55,79.77 110.53,79.75 110.5,79.75 110.49,79.75 107.58,79.75 v1(107.18,80.15)
  BOTTOM w0.191: R325.2 148.97,82.39 v2(148.79,82.2)
MMC0_DAT5: length 52.4
  TOP w0.229: v1(108.78,80.95) 108.78,80.94 U37.AF3 ; U31.K8 v2(151.79,82.2)
  L4-SIGNAL w0.163: v2(151.79,82.2) 152.11,82.53 152.11,84.73 151.2,85.64 150.31,85.64 148.84,87.11 144.53,87.11 142.75,85.33 138.56,85.33 138.43,85.46 130.17,85.46 129.92,85.71 113.78,85.71 110.87,82.8 110.87,82.48 110.55,82.15 110.22,82.15 109.98,81.92 109.98,81.58 109.75,81.35 109.18,81.35 v1(108.78,80.95)
  BOTTOM w0.191: v2(151.79,82.2) 151.64,82.35 R324.2
MMC0_DAT6: length 52.2
  TOP w0.229: U37.AG1 110.38,81.74 v1(110.38,81.75) ; U31.N9 v2(148.79,81.2)
  L4-SIGNAL w0.163: v1(145.03,85.84) 144.64,86.23 144.41,86.23 143.13,84.95 138.43,84.95 138.3,85.08 129.92,85.08 129.64,85.36 114.08,85.36 111.25,82.54 111.25,82.22 110.78,81.75 v1(110.38,81.75)
  L5-SIGNAL w0.163: v1(145.03,85.84) 145.03,86.73 145.29,86.98 149.57,86.98 149.74,86.82 149.74,86.37 149.73,86.37 149.73,86.11 149.55,85.93 148.52,85.93 148.34,85.75 148.34,81.65 v2(148.79,81.2)
  BOTTOM w0.191: R330.2 148.72,81.14 v2(148.79,81.2)
MMC0_DAT7: length 54.1
  TOP w0.229: U37.AF2 109.58,80.94 v1(109.58,80.95) ; U31.K9 v2(151.79,81.2)
  L4-SIGNAL w0.163: v1(109.58,80.95) 109.81,80.95 110.22,81.35 110.55,81.35 110.66,81.46 110.9,81.46 113.5,84.06 116.59,84.06 116.87,83.78 121.13,83.78 122.17,84.83 129.41,84.83 129.54,84.7 138.27,84.7 138.33,84.65 143.33,84.65 143.89,85.21 145.16,85.21 145.67,85.71 145.67,86.48 145.84,86.64 148.55,86.64 148.72,86.48 148.72,86.12 148.4,85.8 148.4,85.53 148.59,85.33 148.87,85.33 149.23,85.69 149.51,85.69 149.7,85.49 149.7,85.21 149.35,84.86 149.35,84.58 149.54,84.38 149.8,84.38 150.11,84.7 151.05,84.7 151.26,84.49 151.26,81.73 v2(151.79,81.2)
  BOTTOM w0.191: 151.76,80.25 151.76,81.18 v2(151.79,81.2)
MMC0_DS: length 42.3
  TOP w0.229: v1(107.98,80.15) 107.98,80.14 U37.AE4
  L4-SIGNAL w0.163: v1(143,88.25) 136.53,88.25 136.27,88.51 124.97,88.51 123.57,89.91 117.35,89.91 115.32,87.87 113.79,87.87 109.6,83.68 109.35,83.68 108.38,82.71 108.38,80.55 v1(107.98,80.15)
  BOTTOM w0.191: R302.1 v1(143,88.25)
MMC_PWR_ON: length 66.6
  TOP w0.191: R142.2 29.94,72.63 v1(29.7,72.87) 29.69,72.88 U36.3
  TOP w0.229: U37.AG29 87.58,81.35 v1(87.18,81.75)
  L7-SIGNAL w0.107: v1(87.18,81.75) 84.61,81.75 83.95,82.41 41.02,82.41 39.37,80.76 32.89,80.76 29.7,77.57 v1(29.7,72.87)
NEO_RESETN: length 115.7
  TOP w0.191: U2.8 74.19,147.98 74.17,148 v1(74.17,148.2) R2.2
  TOP w0.229: U37.AC2 109.58,78.54 v1(109.58,78.55)
  L2-SIGNAL w0.107: v1(120.9,121.78) 120.9,122.29 119.51,123.69 110.62,123.69 108.46,125.85 95.76,125.85 91.44,130.16 81.92,130.16 v1(81.53,129.78)
  L5-SIGNAL w0.163: v1(120.9,121.78) 120.9,114.04 116.59,109.72 116.59,88.38 115.44,87.24 115.44,85.71 114.17,84.44 114.17,82.54 110.97,79.34 110.37,79.34 v1(109.58,78.55) ; v1(74.17,148.2) 74.17,145.53 81.03,138.67 81.03,130.29 v1(81.53,129.78)
NEO_RXD: length 97
  TOP w0.191: R15.2 v1(79.38,131.18)
  TOP w0.229: v1(107.98,76.95) 107.58,76.55 U37.AA4
  L2-SIGNAL w0.107: v1(79.38,131.18) 79.38,130.55 81.03,128.89 82.3,128.89 82.68,129.28 90.93,129.28 95.89,124.32 103.89,124.32 105.28,122.93 118.36,122.93 v1(119.51,121.78)
  L5-SIGNAL w0.163: v1(107.98,76.95) 107.58,77.35 107.58,77.96 107.78,78.15 108.15,78.15 109.18,79.18 109.18,81.11 109.42,81.35 110.8,81.35 111.12,81.68 111.12,82.41 113.16,84.44 113.16,86.48 113.8,87.12 113.8,89.66 114.68,90.54 114.68,110.23 119.51,115.05 v1(119.51,121.78)
NEO_TIMEPULSE: length 116.2
  TOP w0.191: v1(79.5,149.6) R3.2 R4.1
  TOP w0.229: U37.T24 91.58,72.55 v1(91.18,72.15)
  L2-SIGNAL w0.107: v1(68.58,126.35) 67.69,126.35 58.17,116.83 58.17,94.48 59.56,93.08 61.59,93.08 70.36,84.32 70.36,82.16 71.25,81.27 71.25,78.6 76.2,73.65 79.63,73.65 80.14,73.14 80.14,72.63 81.28,71.49 81.86,71.49 81.86,71.49 84.07,71.49 84.59,70.98 88.64,70.98 89.41,71.74 90.77,71.74 v1(91.18,72.15)
  L5-SIGNAL w0.163: v1(79.5,149.6) 78.99,149.09 73.91,149.09 69.22,144.39 69.22,126.99 v1(68.58,126.35)
NEO_TXD: length 95.7
  TOP w0.191: R16.2 v1(80.52,131.18)
  TOP w0.229: U37.AB4 107.98,77.74 v1(107.98,77.75)
  L2-SIGNAL w0.107: v1(120.27,122.04) 119,123.31 105.66,123.31 104.27,124.7 96.14,124.7 91.19,129.66 82.42,129.66 82.04,129.28 81.28,129.28 80.52,130.04 v1(80.52,131.18)
  L5-SIGNAL w0.163: v1(120.27,122.04) 120.27,113.94 116.2,109.88 116.2,88.76 113.67,86.22 113.67,83.43 110.78,80.55 110.22,80.55 109.98,80.32 109.98,79.54 109.21,78.76 109.21,78.74 108.28,77.82 108.05,77.82 v1(107.98,77.75)
Net_12: length 0.6
  TOP w0.229: 93.18,78.94 93.18,78.95 v1(92.78,79.35)
Net_124: length 0.6
  TOP w0.229: 91.58,79.74 91.58,79.75 v1(91.18,80.15)
NTRST: length 5.6
  TOP w0.191: v1(144.15,47.11) 144.31,46.94 J15.9
  BOTTOM w0.191: RJ19.3 144.78,44.31 144.91,44.44 144.91,45.58 R412.2 v1(144.15,47.11)
OSC1_XI: length 10.2
  TOP w0.191: R141.1 v1(79.52,73.14)
  TOP w0.229: v1(87.18,70.55) 87.18,70.55 U37.P29
  L2-SIGNAL w0.107: v1(87.18,70.55) 84.51,70.55 83.82,71.24 81.02,71.24 79.52,72.73 v1(79.52,73.14)
OSC1_XO: length 18.4
  TOP w0.229: v1(88.78,70.55) 89.18,70.95 U37.P27
  L2-SIGNAL w0.107: v1(88.78,70.55) 88.35,70.12 83.24,70.12 82.45,69.33 73.24,69.33 v1(72.01,70.56)
OSPI0_ECC_FAIL/MCU_HYPERBUS0_IN: length 4
  TOP w0.191: R187.1 77.6,48.5 77.98,48.12 77.98,47.57 v1(77.87,47.46) 77.41,47.46 77.14,47.74 R192.2
  BOTTOM w0.191: U73.A5 v1(77.87,47.46)
OSPI_DQS_R: length 4.3
  TOP w0.191: R197.1 82.8,45.76 82,44.95 80.39,44.95 v1(79.87,45.46)
  BOTTOM w0.191: U73.C3 v1(79.87,45.46)
OUT1M3: length 5.2
  TOP w0.356: C76.1 185.5,125.67 184.72,124.89 U14.24
OUT1P3: length 5.2
  TOP w0.356: C75.1 182.68,125.67 183.45,124.89 U14.26
OUT2M3: length 3.7
  TOP w0.406: U14.29 181.55,122.74 v2(181.36,122.93)
  TOP w0.635: v2(181.1,124.58) 180.97,124.45 v2(180.97,123.81) 180.97,123.31 v2(181.36,122.93)
OUT2P3: length 3.9
  TOP w0.406: U14.31 180.28,122.61 v2(179.71,123.18)
  TOP w0.635: v2(179.71,123.18) v2(179.71,123.94) v2(179.71,124.83)
OUT3M3: length 5.3
  TOP w0.356: U14.36 177.1,125.02 177.75,125.67 C74.1
OUT3P3: length 5.1
  TOP w0.356: C73.1 174.93,125.67 175.83,124.77 U14.38
OUT4M3: length 3.8
  TOP w0.406: U14.41 173.93,122.74 v2(173.48,123.18)
  TOP w0.635: v2(173.48,123.18) 173.34,123.32 173.34,123.93 v2(173.35,123.94) 173.35,124.58 v2(173.48,124.7)
OUT4P3: length 3.7
  TOP w0.406: v2(172.21,123.18) 172.21,123.05 172.66,122.61 U14.43
  TOP w0.635: v2(172.21,123.18) 172.09,123.31 v2(172.09,123.94) v2(172.09,124.7)
PCIE0_CLKREQ#: length 149.4
  TOP w0.191: R41.2 v1(86.23,120.39)
  TOP w0.229: U37.W2 109.58,75.34 v1(109.58,75.35)
  L2-SIGNAL w0.107: v1(147.57,75.68) 147.57,80.84 147.38,81.03 147.38,81.12 144.31,84.19 144.31,101.17 v1(143.38,102.1) ; v1(95,124.32) 95.38,123.94 103.38,123.94 105.92,121.4 119.35,121.4 119.35,121.4 119.67,121.4 119.67,121.4 120.74,121.4 120.74,121.4 121.06,121.4 121.07,121.4 121.98,121.4 122,121.37 122.34,121.37 122.37,121.4 135,121.4 135.25,121.15 v1(140.21,121.15)
  L4-SIGNAL w0.163: v1(147.57,75.68) 144.4,75.68 144.02,75.3 138.84,75.3 135.69,78.45 126.21,78.45 125.09,77.33 122.68,77.33 122.06,76.71 121.45,76.71 121.1,76.36 112.21,76.36 110.8,74.95 109.98,74.95 v1(109.58,75.35)
  L5-SIGNAL w0.163: v1(143.38,102.1) 143.38,110.48 140.21,113.65 v1(140.21,121.15) ; v1(95,124.32) 93.6,124.32 90.68,121.4 87.25,121.4 v1(86.23,120.39)
  BOTTOM w0.191: v1(86.23,120.39) 86.23,121.82 J20.7
PCIE0_PERSTZ: length 2.6
  TOP w0.191: U10.4 77.36,131.17 v1(76.96,131.56)
  BOTTOM w0.191: v1(76.96,131.56) 76.96,130.09 J20.22
PCIE0_RC_RSTZ: length 52.5
  TOP w0.191: U10.1 76.06,127.39 R32.1 v1(77.72,126.74)
  TOP w0.229: v1(89.58,83.35) 89.98,82.95 U37.AJ26
  BOTTOM w0.191: v1(77.72,126.74) 82.04,122.42 82.04,119.5 85.72,115.81 85.72,109.34 85.22,108.83 85.22,91.43 85.72,90.92 85.72,87.75 89.58,83.9 v1(89.58,83.35)
PCIE0_REFCLK_N: length 56.9
  TOP w0.122: v1(96.78,80.15) 97.18,79.75 U37.AE17
  L4-SIGNAL w0.122: v1(96.78,80.15) 96.32,80.61 96.06,80.61 95.92,80.75 95.92,81.08 96.17,81.33 96.73,81.33 96.86,81.46 96.86,82.1 97.15,82.39 97.15,82.71 96.89,82.97 96.89,83.63 97.09,83.83 97.09,84.61 96.97,84.73 96.77,84.73 96.65,84.85 96.65,85.03 96.77,85.16 96.97,85.16 97.08,85.26 97.08,85.64 96.82,85.9 96.1,85.9 95.53,86.47 95.53,89.27 94.49,90.31 93.52,90.31 92.91,90.92 92.91,98.03 92.28,98.67 92.28,118.4 86.49,124.2 84.38,124.2 84.15,123.96 84.15,123.76 v1(84.61,123.31)
  BOTTOM w0.122: v1(84.61,123.31) 84.56,123.26 84.56,121.89 J20.11
PCIE0_REFCLK_P: length 56.9
  TOP w0.122: U37.AD16 97.98,78.95 v1(97.58,79.35)
  L4-SIGNAL w0.122: v1(97.58,79.35) 97.16,79.76 97.16,81.97 97.46,82.27 97.46,82.83 97.2,83.09 97.2,83.51 97.4,83.71 97.4,85.75 96.95,86.2 96.23,86.2 95.83,86.6 95.83,89.4 94.61,90.62 93.65,90.62 93.22,91.05 93.22,98.16 92.58,98.8 92.58,118.53 86.61,124.5 84.23,124.5 83.85,124.12 v1(83.85,123.31)
  BOTTOM w0.122: J20.13 83.85,121.94 v1(83.85,123.31)
PCIE0_RX0_N: length 57.5
  TOP w0.122: U37.AH19 95.58,82.15 v1(95.98,82.55)
  L4-SIGNAL w0.122: v1(76.56,123.36) 76.56,121.92 76.83,121.64 86.42,121.64 91.01,117.06 91.01,97.7 92.01,96.7 92.01,88.38 92.64,87.75 93.29,87.75 94.83,86.2 95.13,86.2 95.97,85.37 95.97,84.24 96.28,83.92 96.39,83.81 96.39,83.19 95.98,82.78 v1(95.98,82.55)
  BOTTOM w0.122: v1(76.56,123.36) 76.45,123.26 76.45,122 J20.23
PCIE0_RX0_P: length 57.5
  TOP w0.122: U37.AJ18 96.38,82.95 v1(95.98,83.35)
  L4-SIGNAL w0.122: v1(95.98,83.35) 95.59,83.73 95.3,83.73 95.12,83.91 95.12,84.11 95.28,84.27 95.56,84.27 95.66,84.37 95.66,85.24 95,85.9 94.7,85.9 93.16,87.44 92.51,87.44 91.7,88.25 91.7,96.58 90.7,97.58 90.7,116.93 86.3,121.34 76.7,121.34 76.25,121.79 76.25,122.91 v1(75.79,123.36)
  BOTTOM w0.122: J20.25 75.95,122.04 75.95,123.21 v1(75.79,123.36)
PCIE0_SCL: length 4.6
  TOP w0.191: v1(74.04,127.39) R30.1 R31.2
  BOTTOM w0.191: J20.30 73.78,128.09 74.04,127.83 v1(74.04,127.39)
PCIE0_SDA: length 5.1
  TOP w0.191: v1(72.52,127.39) R29.2 R28.1
  BOTTOM w0.191: J20.32 72.98,127.85 v1(72.52,127.39)
PCIE0_TX0_N: length 1.7
  BOTTOM w0.122: J20.31 C509.2
PCIE0_TX0_P: length 1.7
  BOTTOM w0.122: J20.33 72.59,121.86 C510.2
PCIE0_USB_D+: length 38.5
  TOP w0.157: FL2.3 70.61,128.92 v1(70.61,128.01) ; U16.14 101.49,118.57 101.4,118.48 100.31,118.48 v1(100.08,118.71)
  L2-SIGNAL w0.114: v1(70.61,128.01) 70.61,128.8 70.96,129.15 72.14,129.15 73.53,127.75 73.53,127.11 73.9,126.74 76.96,126.74 79.25,124.45 89.89,124.45 95.48,118.86 98.78,118.86 99.17,118.48 99.84,118.48 v1(100.08,118.71)
PCIE0_USB_D-: length 38.5
  TOP w0.157: v1(100.08,117.85) 100.41,118.18 101.37,118.18 101.48,118.07 U16.15 ; FL2.2 71.37,128.92 v1(71.37,128.01)
  L2-SIGNAL w0.114: v1(100.08,117.85) 99.69,118.23 99.06,118.23 98.68,118.61 95.38,118.61 89.79,124.2 79.14,124.2 76.86,126.48 73.8,126.48 73.28,127 73.28,127.65 72.03,128.89 71.07,128.89 70.87,128.69 70.87,128.37 70.98,128.26 71.12,128.26 v1(71.37,128.01)
PCIE0_W_DISABLE#: length 55.8
  TOP w0.191: 78.61,130.67 78.23,131.05 78.23,131.18 v1(77.78,131.63)
  TOP w0.229: U37.AJ27 v1(88.78,83.34)
  BOTTOM w0.191: v1(77.78,131.63) J20.20 77.78,128.86 77.09,128.17 77.09,126.48 81.53,122.04 81.53,119.24 85.22,115.56 85.22,109.59 84.84,109.21 84.84,90.03 84.58,89.78 84.58,87.96 88.78,83.76 v1(88.78,83.34)
PCIE0_WAKE#: length 43.2
  TOP w0.191: v1(88.58,120.45) 88.58,121.08 R42.2
  TOP w0.229: U37.AH26 89.98,82.15 v1(89.58,82.55)
  BOTTOM w0.163: v1(89.58,82.55) 89.97,82.95 89.97,83.61
  BOTTOM w0.191: J20.1 v1(88.58,120.45) 88.58,119.18 87.25,117.85 87.25,101.72 87.37,101.6 87.37,100.91 86.95,100.5 86.95,94.52 87.5,93.97 87.5,90.79 87,90.29 87,87.24 89.97,84.26 89.97,83.61
PG_LM5141: length 312.1
  TOP w0.191: R72.2 v1(128.74,107.34) ; U57.6 42.41,21.08 v2(43.31,20.18) ; U33.21 v2(196.08,83.94)
  L2-SIGNAL w0.107: v1(151.76,78.6) 151.76,76.32 151.38,75.94 151.38,74.16 150.5,73.27 150.5,64.25 149.96,63.72 149.96,50.56 150.62,49.9 150.62,38.72 148.97,37.07 v1(148.97,36.06)
  L4-SIGNAL w0.163: v1(128.74,107.34) 133.26,107.34 133.73,107.81 155.19,107.81 163.19,99.81 185.83,99.81 190.91,104.89 199.26,104.89 200.91,103.24 200.91,90.79 TP33.1 201.04,89.65 201.04,84.16 200.31,83.43 196.6,83.43 v2(196.08,83.94) 195.33,83.94 194.06,82.67 191.9,82.67 190.37,84.19 181.1,84.19 178.94,82.03 164.47,82.03 161.04,78.6 v1(151.76,78.6)
  L5-SIGNAL w0.163: v1(148.97,36.06) 75.62,36.06 71.83,32.27 69.65,32.27 69.19,31.82 68.4,31.82 67.51,30.92 62.68,30.92 60.96,29.2 58.67,29.2 49.66,20.18 v2(43.31,20.18)
  BOTTOM w0.191: v2(196.08,83.94) 196.09,83.94 R323.1
PG_LM5175: length 139.7
  TOP w0.203: TP53.1 184.53,58.28 184.53,56 184.91,55.62 U46.17 ; C313.2 R164.2 v2(188.47,58.28)
  L2-SIGNAL w0.107: v1(154.18,114.04) 151.64,114.04 150.5,115.18 150.5,116.07 149.73,116.83 148.21,116.83 145.54,119.5 145.54,120.26 144.65,121.15 143.26,121.15 135.76,128.64 130.88,128.64 130.34,128.1 130.01,128.1 129.47,128.64 125.6,128.64 124.08,127.11 114.05,127.11 113.79,127.37 111.44,127.37 v2(110.74,128.07)
  L4-SIGNAL w0.163: v2(188.47,58.28) TP53.1
  L5-SIGNAL w0.163: v1(154.18,114.04) 154.18,104.76 170.18,88.76 170.18,71.75 170.69,71.24 170.69,59.68 172.34,58.03 175.9,58.03 176.4,58.54 178.05,58.54 178.31,58.28 TP53.1
  BOTTOM w0.191: R271.1 v2(110.74,128.07)
PG_LM53603: length 54.9
  TOP w0.191: R48.2 151.76,119.62 v2(151.38,120) U11.7 ; TP7.1 105.47,127.69 U8.8
  L2-SIGNAL w0.107: TP7.1 107.95,127.62 108.84,128.51 112.27,128.51 112.78,128.01 123.7,128.01 125.07,129.37 136.68,129.37 142.88,123.18 144.91,123.18 147.7,120.39 151,120.39 v2(151.38,120)
PMICB_EN: length 7.8
  TOP w0.229: U20.20 v1(77.33,111.75)
  BOTTOM w0.191: v1(77.33,111.75) 77.97,111.11 79.25,111.11 81.03,112.89 R277.2
PMICB_FB3: length 20.2
  TOP w0.229: U20.49 v1(76.33,101.59)
  L4-SIGNAL w0.163: v1(70.61,89.27) 70.61,93.59 70.74,93.72 70.74,100.32 71.88,101.46 74.42,101.46 75.01,102.05 75.87,102.05 v1(76.33,101.59)
  BOTTOM w0.191: v1(70.61,89.27) R304.1 R303.1
PMICB_FB4: length 22.8
  TOP w0.229: U20.50 v1(76.83,101.21)
  L4-SIGNAL w0.163: v1(76.83,101.21) 76.83,101.85 76.2,102.48 74.8,102.48 74.17,101.84 71.63,101.84 70.32,100.54 70.32,90.12 v1(69.47,89.27)
  BOTTOM w0.191: v1(69.47,89.27) R305.1 R306.1
PWR_SW_CNTL_DSI0: length 119.2
  TOP w0.229: U37.AB1 110.38,77.74 v1(110.38,77.75)
  TOP w0.305: v2(118.24,10.53) R256.1 U63.4
  L2-SIGNAL w0.107: v1(136.65,24.88) 136.65,52.18 141.51,57.05 141.51,78.54 141.48,78.57 v1(141.48,78.98)
  L4-SIGNAL w0.163: v1(110.38,77.75) 110.73,78.09 120.14,78.09 123.16,81.11 129.06,81.11 129.94,80.23 136.07,80.23 139.59,80.23 140.84,78.98 v1(141.48,78.98)
  L5-SIGNAL w0.163: v1(136.65,24.88) 135.97,24.88 134.06,22.98 131.06,22.98 128.91,20.82 124.33,20.82 121.41,17.9 121.41,13.71 v2(118.24,10.53)
RESET_REQZ: length 5.7
  TOP w0.191: R157.1 R158.2 TP50.1
  TOP w0.229: v1(87.98,61.75) 88.38,62.15 U37.C28
  L2-SIGNAL w0.107: v1(87.98,61.75) 87.6,61.37 86.45,61.37 86.11,61.71 TP50.1
RESETSTATZ: length 19.3
  TOP w0.229: v1(106.38,72.15) 106.38,72.15 U37.T6
  L5-SIGNAL w0.163: TP54.1 105.18,58.95 105.18,71.51 105.41,71.75 105.98,71.75 v1(106.38,72.15)
RGMII5_RD0: length 61.6
  TOP w0.191: U42.26 42.27,55.26 v1(42.8,54.73) 43.18,54.35 43.18,53.96
  TOP w0.229: v1(91.98,72.15) 91.98,72.15 U37.T23
  L4-SIGNAL w0.163: v1(91.98,72.15) 91.57,71.75 91.01,71.75 90.78,71.51 90.78,71.23 90.77,71.23 90.77,71.18 90.54,70.95 90.49,70.95 90.49,70.94 90.21,70.94 90.18,70.91 90.18,70.91 90.01,70.75 90.01,70.74 89.98,70.71 89.98,70.43 89.97,70.43 89.97,70.38 89.74,70.15 89.69,70.15 89.69,70.15 89.41,70.15 89.18,69.91 89.18,69.87 89.17,69.86 89.17,69.58 88.94,69.35 86.06,69.35 84.42,67.71 83.99,67.71 83.98,67.7 82.82,67.7 82.17,67.05 59.82,67.05 48.77,56 48.55,56 48.33,56.22 48.1,56.22 47.94,56.06 47.94,55.84 48.16,55.62 48.16,55.39 48,55.23 47.78,55.23 47.56,55.45 47.33,55.45 47.18,55.29 47.18,55.07 47.39,54.85 47.39,54.62 47.19,54.42 43.11,54.42 v1(42.8,54.73)
RGMII5_RD1: length 61.3
  TOP w0.191: 42.16,53.96 41.77,54.36 v1(41.77,54.73) U42.25
  TOP w0.229: v1(91.98,71.35) 91.98,71.35 U37.R23
  L4-SIGNAL w0.163: v1(91.98,71.35) 91.58,70.95 91.03,70.95 91.02,70.94 91.01,70.94 90.78,70.71 90.78,70.7 90.77,70.7 90.77,70.19 89.93,69.34 89.41,69.34 89.18,69.11 89.18,68.78 88.97,68.57 88.96,68.57 88.94,68.55 85.96,68.55 83.31,65.9 81.41,65.9 80.64,66.66 60.07,66.66 47.37,53.96 42.53,53.96 v1(41.77,54.73)
RGMII5_RD2: length 62
  TOP w0.191: 41.15,53.96 41.06,54.05 v1(41.06,54.68) 41.26,54.88 41.26,55.11 41.26,55.11 U42.24
  TOP w0.229: U37.U24 91.18,73.74 v1(91.18,73.75)
  L4-SIGNAL w0.163: v1(41.06,54.68) 41.61,55.23 43.05,55.23 43.23,55.06 45.67,55.06 47.5,56.89 47.5,57.16 48.24,57.9 48.9,57.9 59.67,68.68 69.32,68.68 69.72,69.08 80.39,69.08 81.28,68.19 81.79,68.19 82.42,68.82 84.33,68.82 86.45,70.94 88.94,70.94 88.95,70.94 89.18,71.16 89.18,71.51 89.41,71.75 89.74,71.75 89.75,71.74 89.98,71.96 89.98,72.54 v1(91.18,73.75)
RGMII5_RD3: length 61.7
  TOP w0.191: v1(40.48,54.22) 40.48,54.69 40.61,54.83 40.61,54.87 40.77,55.03 U42.23
  TOP w0.229: U37.U27 89.18,73.35 v1(88.78,73.75)
  L4-SIGNAL w0.163: v1(40.48,54.22) 40.48,54.72 41.9,56.13 44.66,56.13 44.75,56.04 45.16,56.04 46.21,57.1 46.21,57.2 46.23,57.22 46.23,57.77 46.86,58.41 46.86,59.68 46.2,60.35 46.2,60.92 46.86,61.58 48.39,61.58 57.28,70.47 68.33,70.47 69.22,71.36 79.25,71.36 80.93,73.05 81.87,73.05 81.91,73.01 86.48,73.01 86.51,73.03 86.67,73.03 86.73,73.09 88.12,73.09 v1(88.78,73.75)
RGMII5_RX_CTL: length 60.3
  TOP w0.191: U42.15 v2(37.21,58.04)
  TOP w0.229: v1(89.58,73.75) 89.58,73.74 U37.U26
  L4-SIGNAL w0.163: v1(47.5,60.44) 48.51,60.44 57.75,69.68 68.7,69.68 69.12,70.09 79.37,70.09 80.39,71.11 82.8,71.11 84.07,72.38 86.84,72.38 87.01,72.55 88.78,72.55 89.58,73.35 v1(89.58,73.75)
  L5-SIGNAL w0.163: v1(47.5,60.44) 47.2,60.14 42.88,60.14 41.91,59.17 38.34,59.17 v2(37.21,58.04)
RGMII5_RXC: length 60.7
  TOP w0.191: v1(43.43,55.64) U42.27
  TOP w0.229: U37.U25 90.38,73.74 v1(90.38,73.75)
  L4-SIGNAL w0.163: v1(43.43,55.64) 44.46,55.64 44.55,55.55 45.37,55.55 45.46,55.64 45.49,55.64 46.86,57.01 46.86,57.22 54.5,64.86 54.5,65.09 54.39,65.2 54.39,65.43 54.55,65.59 54.77,65.59 54.99,65.37 55.22,65.37 55.38,65.53 55.38,65.75 55.16,65.97 55.16,66.19 55.32,66.35 55.54,66.35 55.76,66.13 55.99,66.13 56.14,66.29 56.14,66.52 55.92,66.74 55.92,66.96 56.08,67.12 56.31,67.12 56.53,66.9 56.75,66.9 56.91,67.06 56.91,67.29 56.69,67.51 56.69,67.73 56.85,67.89 57.08,67.89 57.3,67.67 57.52,67.67 57.68,67.83 57.68,68.06 57.4,68.34 57.4,68.57 57.56,68.73 57.78,68.73 57.94,68.57 58.17,68.57 58.77,69.17 69.05,69.17 69.47,69.59 80.9,69.59 81.07,69.42 83.52,69.42 85.86,71.75 88.94,71.75 89.17,71.98 89.17,72.27 89.18,72.28 89.18,72.31 89.41,72.55 89.45,72.55 90.02,73.12 90.02,73.38 v1(90.38,73.75)
RGMII5_TD0: length 54.6
  TOP w0.191: v1(46.23,58.66) 45.91,58.98 44.26,58.98 44.2,59.04 U42.33
  TOP w0.229: U37.U28 88.38,73.35 v1(87.98,73.75)
  L4-SIGNAL w0.163: v1(46.23,58.66) 46.23,59.68 45.72,60.19 45.72,61.05 56.67,72 58,72 58.16,72.16 58.16,72.47 58.32,72.63 58.54,72.63 58.7,72.47 58.7,72.16 58.86,72 75.31,72 75.57,71.74 78.87,71.74 80.48,73.36 86.56,73.36 86.6,73.39 86.9,73.39 86.91,73.38 86.99,73.38 87.02,73.35 87.59,73.35 v1(87.98,73.75)
RGMII5_TD1: length 56
  TOP w0.191: U42.32 44.96,58.54 v1(45.21,58.28)
  TOP w0.229: v1(88.78,74.55) 89.18,74.15 U37.V27
  L4-SIGNAL w0.163: v1(45.21,58.28) 44.52,58.97 44.52,60.13 44.73,60.35 44.73,61.46 56.26,72.98 56.39,72.98 57.81,74.41 72.52,74.41 73.15,75.05 77.7,75.05 78.4,74.35 86.55,74.35 86.67,74.22 86.94,74.22 87.01,74.15 87.03,74.15 88.38,74.15 v1(88.78,74.55)
RGMII5_TD2: length 56.1
  TOP w0.191: v1(45.21,57.52) 44.69,58.04 U42.31
  TOP w0.229: U37.V29 v1(87.18,74.55)
  L4-SIGNAL w0.163: v1(87.18,74.55) 86.78,74.55 86.41,74.92 82.42,74.92 82.14,74.64 78.52,74.64 77.72,75.43 72.77,75.43 72.14,74.79 57.56,74.79 44.32,61.56 44.32,60.7 44.07,60.44 44.07,58.66 v1(45.21,57.52)
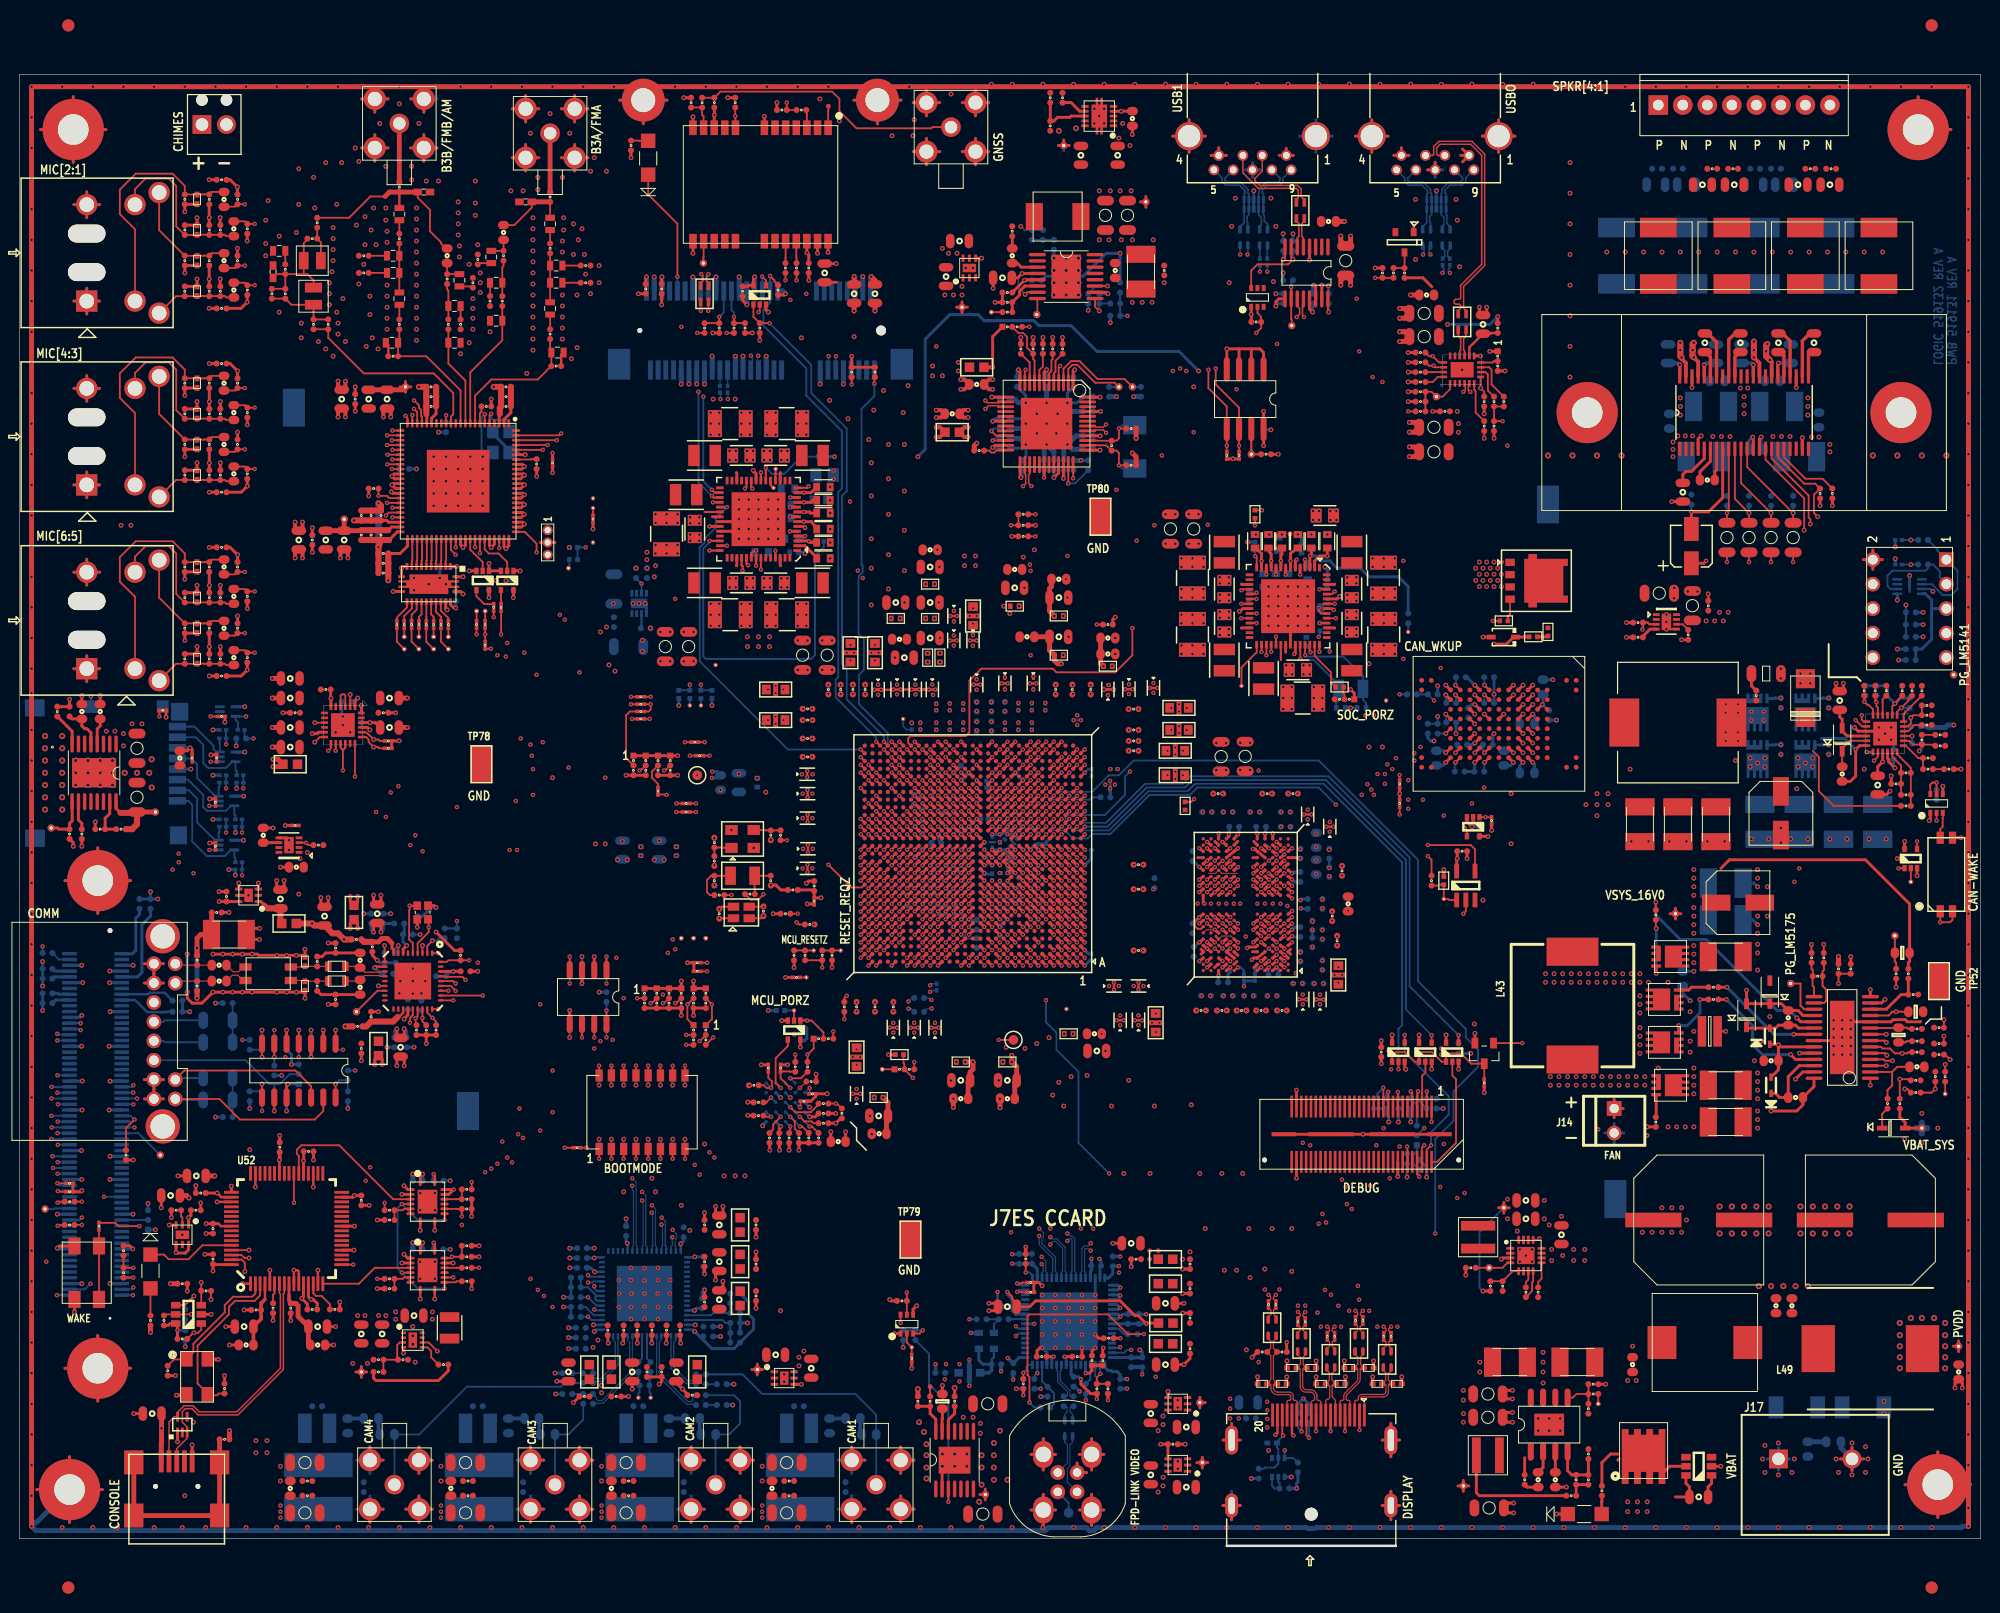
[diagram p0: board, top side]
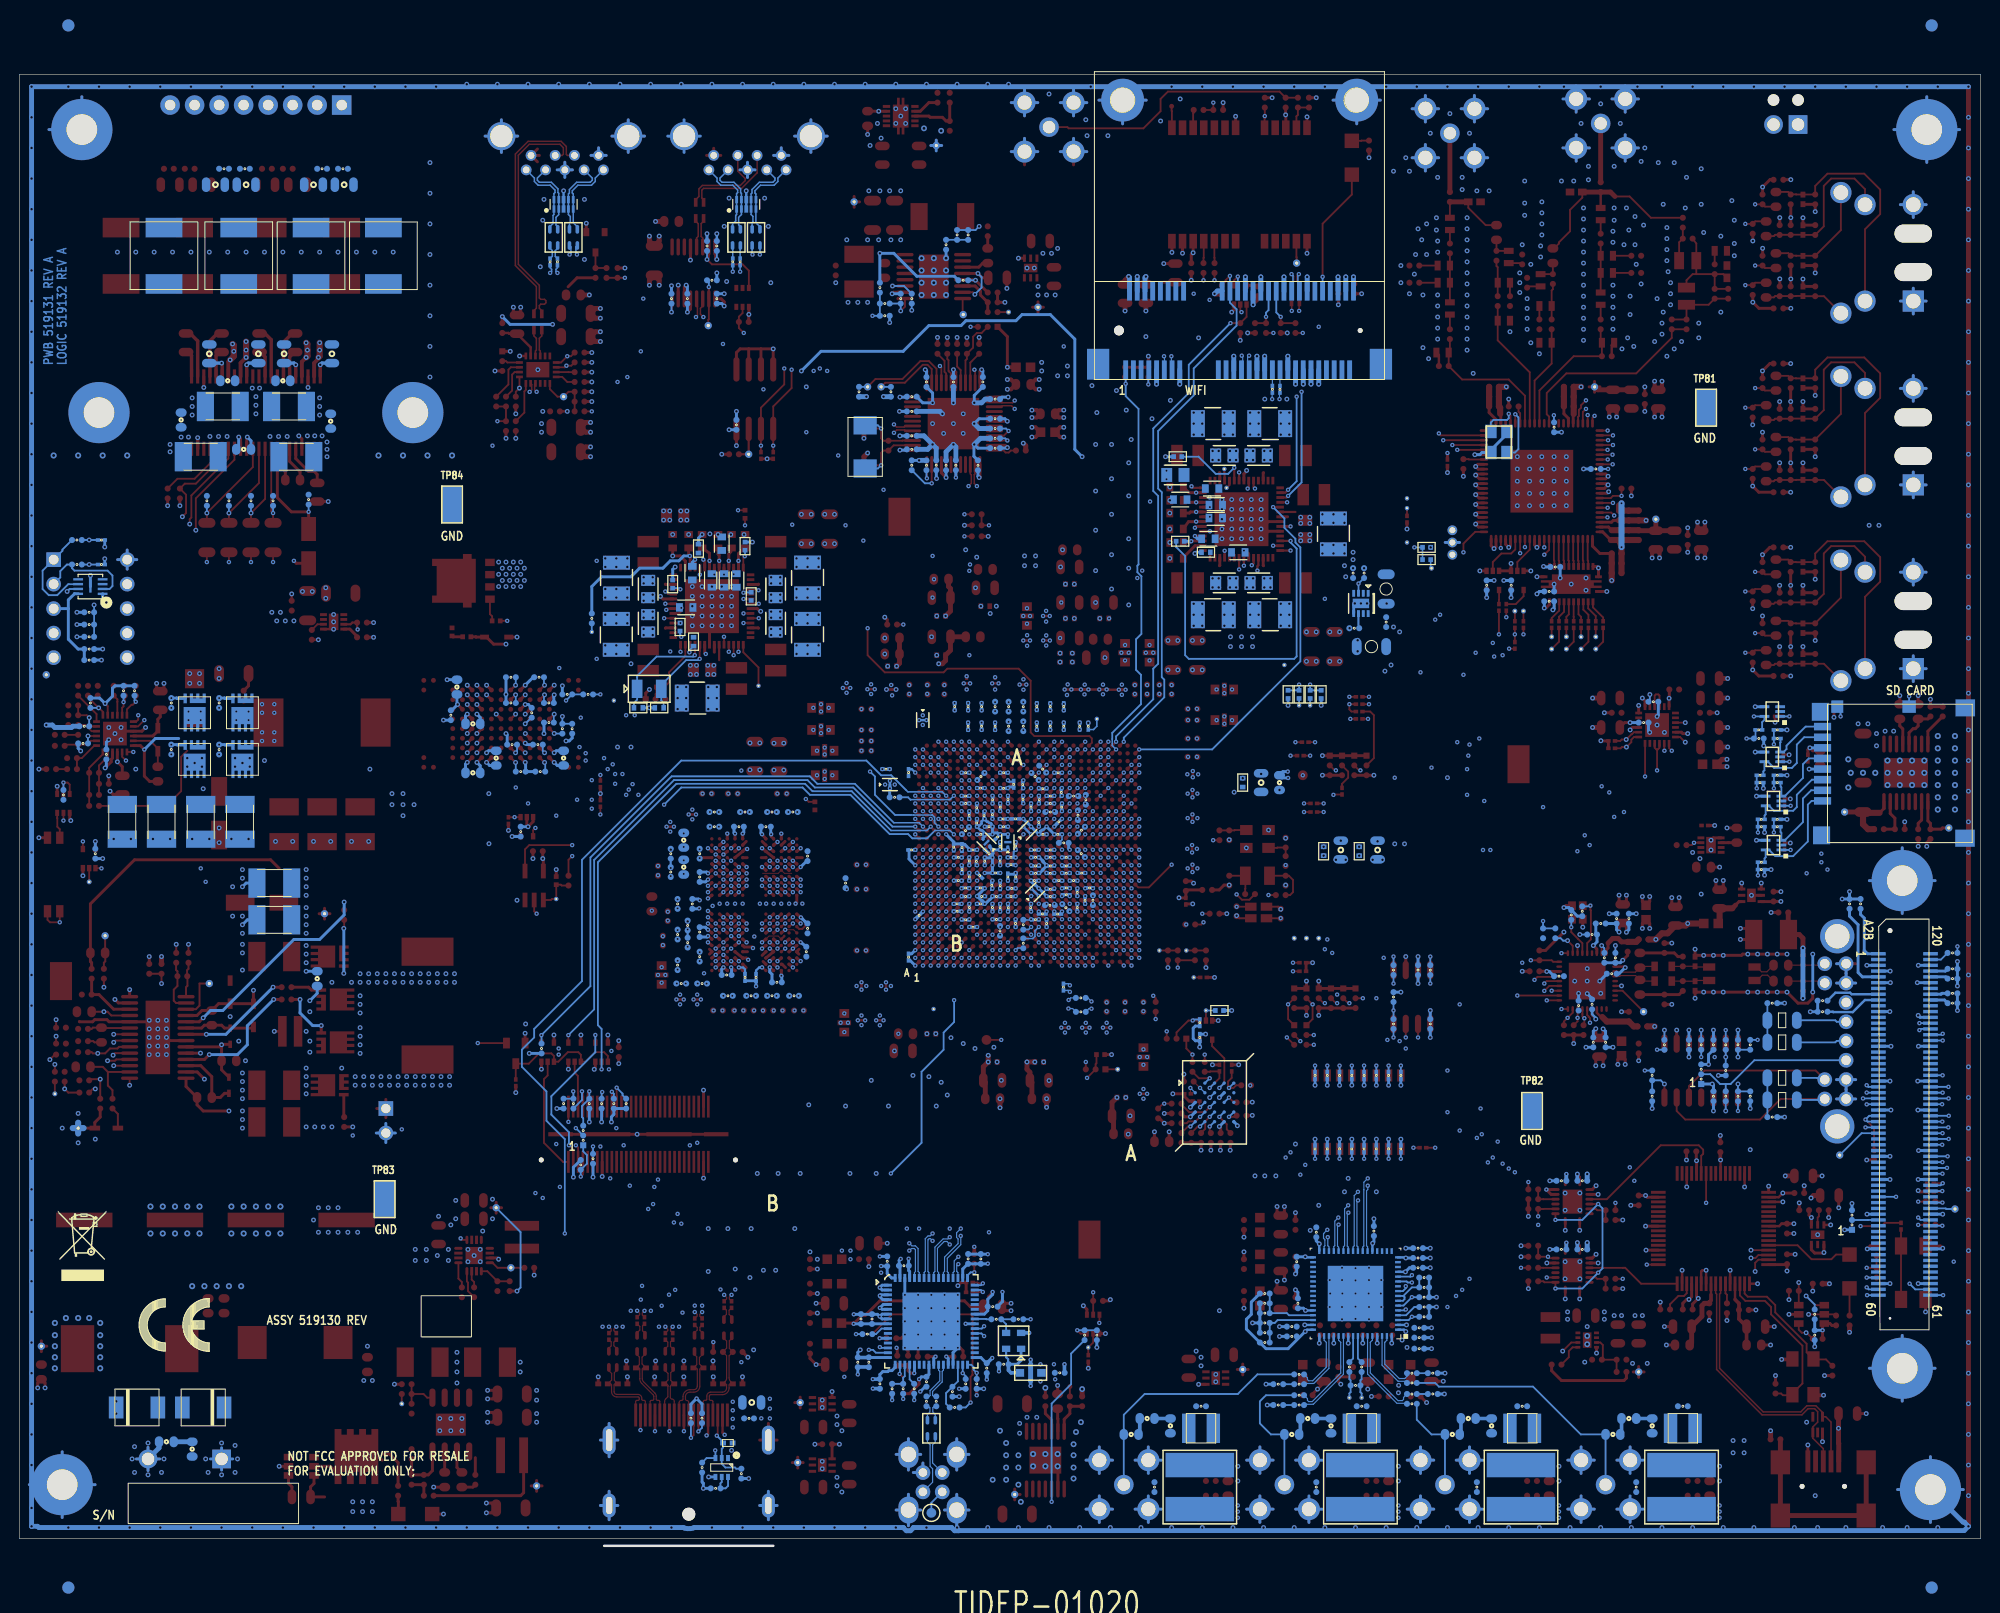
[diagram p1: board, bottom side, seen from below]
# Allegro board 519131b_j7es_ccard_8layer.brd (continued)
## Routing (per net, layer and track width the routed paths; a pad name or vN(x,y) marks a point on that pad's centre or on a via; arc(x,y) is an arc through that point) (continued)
RGMII5_TD3: length 56.7
  TOP w0.191: U42.30 v1(44.45,57.54)
  TOP w0.229: U37.V28 v1(87.98,74.55)
  L4-SIGNAL w0.163: v1(87.98,74.55) 87.74,74.55 87.34,74.95 87.01,74.95 86.41,75.55 84.33,75.55 83.66,76.22 72.67,76.22 71.63,75.17 57.31,75.17 43.87,61.74 43.87,61.01 43.69,60.82 43.69,58.3 v1(44.45,57.54)
RGMII5_TX_CTL: length 56.9
  TOP w0.191: v1(48.01,57.04) U42.29
  TOP w0.229: U37.U23 92.38,73.35 v1(91.98,73.75)
  L4-SIGNAL w0.163: v1(91.98,73.75) 90.78,72.54 90.78,71.99 90.54,71.75 90.21,71.75 89.97,71.51 89.97,71.18 89.74,70.95 89.39,70.95 89.16,70.72 89.17,70.71 89.17,70.38 88.94,70.15 88.89,70.15 88.89,70.14 86.28,70.14 84.33,68.19 82.55,68.19 82.13,67.76 77.64,67.76 77.4,68 72.55,68 72.31,67.76 71.67,67.76 71.43,68 60.14,68 49.17,57.04 v1(48.01,57.04)
RGMII5_TXC: length 54.6
  TOP w0.191: U42.28 v1(44.96,56.54)
  TOP w0.229: v1(87.18,73.75) 87.58,73.35 U37.U29
  L4-SIGNAL w0.163: v1(87.18,73.75) 87.01,73.75 86.95,73.81 86.64,73.81 86.6,73.85 75.3,73.85 74.97,73.52 73.15,73.52 72.77,73.9 58,73.9 56.59,72.49 56.47,72.49 45.23,61.25 45.23,60.14 45.21,60.13 45.21,60.06 45.23,60.05 45.23,59.98 45.72,59.49 45.72,57.3 v1(44.96,56.54)
SEL_SDIO_3V3_1V8N: length 56.1
  TOP w0.191: R73.1 TP17.1
  TOP w0.229: U37.AH29 87.58,82.15 v1(87.18,82.55) ; v1(73.3,107.67) U20.33
  L7-SIGNAL w0.107: v1(73.3,107.67) 73.3,106.7 71.88,105.27 61.72,105.27 TP17.1
  BOTTOM w0.191: v1(87.18,82.55) 79.62,82.55 70.48,91.68 70.48,103.49 70.99,104 70.99,104.38 72.14,105.53 72.14,106.5 v1(73.3,107.67)
SERDES0_REXT: length 0.6
  TOP w0.229: U37.AE18 96.38,79.75 v1(95.98,80.15)
SERDES1_REXT: length 0.6
  TOP w0.229: U37.AE13 100.38,79.75 v1(100.78,80.15)
SERDES2_REXT: length 1.3
  TOP w0.229: v1(100.78,79.35) 100.38,78.95 U37.AD13
  BOTTOM w0.229: R341.1 100.18,79.21 100.64,79.21 v1(100.78,79.35)
SERDES3_REXT: length 0.6
  TOP w0.229: U37.AE8 104.78,80.14 v1(104.78,80.15)
SERDES4_REXT: length 0.6
  TOP w0.229: U37.F9 v1(103.98,64.15)
SOC_EMU0: length 75.8
  TOP w0.191: J15.19 v1(141.81,47.06)
  TOP w0.229: v1(89.58,61.75) 89.98,62.15 U37.C26
  L2-SIGNAL w0.107: v1(141.81,47.06) 141.81,45.28 141.2,44.67 141.2,43.45 v1(141.35,43.3)
  L5-SIGNAL w0.163: v1(89.58,61.75) 89.58,60.74 89.41,60.57 89.41,54.6 88.9,54.09 88.9,49.14 94.52,43.52 122.9,43.52 124.21,44.82 139.83,44.82 v1(141.35,43.3)
  BOTTOM w0.191: R414.2 141.6,46.85 v1(141.81,47.06)
SOC_EMU1: length 79.5
  TOP w0.191: J15.21 v1(141.32,47.49)
  TOP w0.229: U37.B29 87.58,61.35 v1(87.18,60.95)
  L2-SIGNAL w0.107: v1(141.32,47.49) 141.32,45.55 140.88,45.11 140.88,41.81 v1(140.59,41.52)
  L5-SIGNAL w0.163: v1(140.59,41.52) 138.94,41.52 136.53,43.93 125.98,43.93 124.68,42.63 94.14,42.63 88.27,48.5 88.27,54.47 88.01,54.73 88.01,57.52 87.18,58.36 v1(87.18,60.95)
  BOTTOM w0.191: R415.2 140.71,46.72 140.71,46.88 v1(141.32,47.49)
SOC_HYPERBUS0_RESET#: length 18
  TOP w0.191: RJ16.3 v1(84.33,53.33)
  TOP w0.229: U37.E19 95.58,63.75 v1(95.18,63.35)
  L2-SIGNAL w0.107: v1(95.18,63.35) 94.9,63.35 94.53,62.97 93.21,62.97 91.19,60.95 91.19,60.06 88.14,57.01 88.14,54.98 86.49,53.33 v1(84.33,53.33)
SOC_MCU_OSPI0_CLK_R: length 10.3
  TOP w0.122: U37.E20 94.78,63.75 v1(94.38,63.35)
  L4-SIGNAL w0.122: v1(94.38,63.35) 94.76,62.96 94.76,59.84 95.5,59.1 95.5,56.25 94.94,55.69 v1(94.51,55.69)
  BOTTOM w0.122: R383.1 94.08,55.69 v1(94.51,55.69)
SOC_MCU_OSPI0_LBCLKO_R: length 10.3
  TOP w0.122: U37.C21 93.58,61.75 v1(93.58,61.75)
  L4-SIGNAL w0.122: v1(94.49,56.58) 94.49,56.35 94.69,56.15 94.97,56.15 95.2,56.38 95.2,58.97 94.74,59.43 94.49,59.43 93.94,58.88 93.77,58.88 93.56,59.09 93.56,59.26 93.98,59.68 93.98,61.34 v1(93.58,61.75)
  BOTTOM w0.122: R378.1 94.28,56.79 v1(94.49,56.58)
SOC_PORZ_OUT: length 356.9
  TOP w0.191: U10.2 76.71,128.01 v1(76.58,127.88) ; R136.1 151.9,75.52 v1(151.89,75.53) U35.1 ; v1(104.25,121.91) 104.27,121.91 104.18,121.82 U16.11 ; U42.3 v2(41.77,62.22)
  TOP w0.229: v1(110.38,73.75) 109.98,73.35 U37.U1
  L2-SIGNAL w0.107: v1(141.22,120.64) 135.13,120.64 134.75,121.02 105.14,121.02 v1(104.25,121.91) 102.6,123.56 95,123.56 89.66,128.89 82.93,128.89 82.55,128.51 77.22,128.51 v1(76.58,127.88) ; v1(151.89,75.53) 151.89,74.16 150.88,73.14 150.88,64 150.24,63.36 150.24,52.57 151,51.81 151,37.84 v1(149.73,36.57)
  L4-SIGNAL w0.163: v2(41.77,62.22) 40.13,60.58 40.13,56 38.48,54.35 38.48,52.31 38.86,51.93 38.86,51.3 38.48,50.92 38.48,46.22 45.59,39.11 45.59,35.55 45.09,35.04 45.09,34.03 v1(45.85,33.26)
  L5-SIGNAL w0.163: v1(45.85,33.26) 47.35,33.26 50.01,35.93 57.4,35.93 60.15,38.67 65.86,38.67 67.97,36.57 v1(149.73,36.57) ; v1(110.38,73.75) 110.79,73.75 111.25,74.21 111.25,74.54 113.16,76.44 114.05,76.44 114.68,77.08 120.52,77.08 121.28,77.84 123.24,77.84 123.53,77.56 136.81,77.56 138.05,76.32 140.34,76.32 147.07,69.59 149.35,69.59 150.75,70.98 150.75,73.78 151.89,74.92 v1(151.89,75.53) 153.29,76.93 153.29,96.26 149.48,100.07 149.48,106.16 141.22,114.42 v1(141.22,120.64)
SOC_PWR_EN: length 10.6
  TOP w0.191: U27.20 v1(128.17,98.15) ; R72.1 v1(128.02,105.78)
  L5-SIGNAL w0.163: v1(128.17,98.15) 128.65,98.63 128.65,100.7 126.75,102.61 126.75,104.51 v1(128.02,105.78)
SOC_SAFETY_ERRZ: length 4.2
  TOP w0.191: U77.1 148.13,66.94 148.03,67.05 TP40.1 R463.1 147.1,68.53 147.01,68.44 R135.2
SOC_TCK: length 87.1
  TOP w0.191: J15.3 v1(145.81,47.11)
  TOP w0.229: U37.E29 87.58,63.75 v1(87.18,63.35)
  L2-SIGNAL w0.107: v1(145.81,47.11) 145.81,44.2 v1(143,41.39)
  L5-SIGNAL w0.163: v1(87.18,63.35) 86.74,62.91 86.74,57.39 87.63,56.5 87.63,54.47 87.88,54.22 87.88,46.34 92.11,42.12 124.81,42.12 126.11,43.42 136.27,43.42 138.81,40.88 142.49,40.88 v1(143,41.39)
  BOTTOM w0.191: v1(145.81,47.11) 145.8,47.09 R411.2 R410.2
SOC_TDI: length 59.3
  TOP w0.191: U48.4 v1(146.32,52.93)
  TOP w0.229: v1(110.38,74.55) 110.38,74.54 U37.V1
  BOTTOM w0.191: v1(146.32,52.93) 143.65,55.61 143.65,71.1 135.37,79.38 121.55,79.38 120.78,78.6 116.79,78.6 112.74,74.55 v1(110.38,74.55)
SOC_TDO: length 63
  TOP w0.191: U47.2 v1(142.88,49.39)
  TOP w0.229: v1(108.78,74.55) 108.78,74.54 U37.V3
  BOTTOM w0.163: v1(108.78,74.55) 109.18,74.15 112.9,74.15
  BOTTOM w0.191: 112.9,74.15 116.97,78.22 121.03,78.22 121.79,78.98 135.13,78.98 143.26,70.86 143.26,53.97 142.88,53.58 v1(142.88,49.39)
SOC_TMS: length 62.8
  TOP w0.191: U49.4 v1(149.11,52.93)
  TOP w0.229: v1(109.58,74.55) 109.58,74.54 U37.V2
  BOTTOM w0.163: v1(109.58,74.55) 109.98,74.95 112.59,74.95
  BOTTOM w0.191: R393.2 149.1,52.92 v1(149.11,52.93) 144.03,58.01 144.03,71.35 135.62,79.76 121.3,79.76 120.52,78.98 116.63,78.98 112.59,74.95
SOC_TRST#: length 75.7
  TOP w0.229: v1(91.18,64.15) 91.18,64.15 U37.F24
  L5-SIGNAL w0.163: v1(145.54,43.3) 142.88,45.96 123.06,45.96 122.01,44.92 95.16,44.92 92.08,48 92.08,51.04 93.6,52.57 93.6,54.22 92.71,55.11 92.71,57.27 91.57,58.4 91.57,63.75 v1(91.18,64.15)
  BOTTOM w0.191: RJ19.2 v1(145.54,43.3)
SOC_WKUP_I2C0_SCL: length 236.6
  TOP w0.191: v1(123.95,122.04) 123.95,120.39 126.36,117.97 U13.6 v1(126.36,114.04) R63.2 ; U27.31 v1(129.2,92.32)
  TOP w0.229: v1(71.75,108.83) 71.92,108.67 U20.31 ; v1(90.38,66.55) 90.78,66.95 U37.J25
  L2-SIGNAL w0.107: v1(145.16,82.79) 146.81,81.14 146.81,54.09 147.32,53.58 v1(147.32,51.55)
  L4-SIGNAL w0.163: v1(70.36,119.62) 70.87,119.62 71.59,120.35 71.59,121.06 70.87,121.78 70.87,123.69 72.39,125.21 73.79,125.21 75.95,127.37 82.68,127.37 83.95,128.64 91.82,128.64 93.22,127.24 101.73,127.24 103.38,128.89 108.84,128.89 112.39,125.34 120.65,125.34 v1(123.95,122.04)
  L5-SIGNAL w0.163: v1(145.16,82.79) 144.02,82.79 141.99,84.83 130.3,84.83 129.2,85.93 v1(129.2,92.32) 129.2,94.44 128.86,94.78 128.86,96.68 127.76,97.78 127.76,100.97 126.36,102.36 v1(126.36,114.04) ; v1(147.32,51.55) 146.56,50.79 139.95,50.79 139.45,50.28 107.31,50.28 106.3,49.27 101.09,49.27 96.27,54.09 96.27,57.01 93.98,59.3 93.98,64.31 93.74,64.54 93.43,64.54 93.43,64.55 93.41,64.55 93.18,64.78 93.18,64.78 92.38,65.58 92.38,65.6 92.37,65.6 92.37,65.91 92.14,66.15 90.77,66.15 v1(90.38,66.55)
  BOTTOM w0.191: v1(70.36,119.62) 70.36,110.23 v1(71.75,108.83)
SOC_WKUP_I2C0_SDA: length 232.7
  TOP w0.191: v1(123.19,121.91) 123.19,120 125.09,118.1 U13.5 v1(125.09,114.04) R62.2 ; U27.30 v1(128.69,92.67)
  TOP w0.229: U20.30 72.05,109.17 v1(71.75,109.46) ; v1(91.18,65.75) 91.18,65.75 U37.H24
  L2-SIGNAL w0.107: v1(147.32,50.92) 146.81,51.42 146.81,53.46 146.43,53.84 146.43,80.25 v1(144.53,82.16)
  L4-SIGNAL w0.163: v1(123.19,121.91) 120.65,124.45 112.52,124.45 108.58,128.39 104.01,128.39 102.36,126.74 92.96,126.74 92.25,127.45 83.17,127.45 82.8,127.08 79.72,127.08 78.87,126.23 75.56,126.23 74.17,124.83 72.52,124.83 71.25,123.56 71.25,122.16 72.01,121.4 72.01,120.26 v1(70.87,119.12)
  L5-SIGNAL w0.163: v1(125.09,114.04) 125.09,110.86 125.86,110.1 125.86,102.1 127.38,100.57 127.38,96.64 127.96,96.06 128.34,96.06 128.58,95.82 128.58,94.41 128.69,94.3 v1(128.69,92.67) 128.69,85.8 130.05,84.44 141.73,84.44 144.02,82.16 v1(144.53,82.16) ; v1(147.32,50.92) 146.82,50.42 140.6,50.42 140.02,49.84 107.51,49.84 106.55,48.88 100.84,48.88 95.89,53.84 95.89,54.09 95.12,54.85 94.36,54.85 93.73,55.49 93.73,58.03 93.17,58.58 93.17,64.31 92.14,65.34 91.58,65.34 v1(91.18,65.75)
  BOTTOM w0.191: v1(71.75,109.46) 70.87,110.35 v1(70.87,119.12)
SPI5_CLK: length 18.7
  TOP w0.191: R134.1 v1(70.1,76.06)
  TOP w0.229: U37.W29 87.58,74.95 v1(87.18,75.35)
  L5-SIGNAL w0.163: v1(70.1,76.06) 71.34,76.06 71.5,76.22 82.55,76.22 83.42,75.35 v1(87.18,75.35)
SPI6_CLK_BOOTMODE1: length 36
  TOP w0.191: R115.1 65.19,86.48 65.41,86.69 v1(65.41,87.24) R110.1
  TOP w0.229: U37.AC22 93.18,78.15 v1(92.78,78.55)
  L4-SIGNAL w0.163: v1(65.41,87.24) 66.42,87.24 66.77,87.58 75.76,87.58 76.16,87.19 76.16,87.19 76.45,86.9 80.14,86.9 80.41,87.17 82.78,87.17 83.5,86.45 87.14,86.45 87.75,85.84 87.76,85.84 89.97,83.62 89.97,82.67 89.98,82.67 89.98,82.38 90.01,82.35 90.01,82.35 90.17,82.18 90.18,82.18 90.21,82.15 90.49,82.15 90.49,82.15 90.54,82.15 90.77,81.91 90.77,81.56 91,81.34 91.01,81.35 91.65,81.35 92.37,80.62 92.37,78.95 v1(92.78,78.55)
SPKM: length 102.1
  TOP w0.191: v2(30.61,85.33) 31.62,85.33
  L7-SIGNAL w0.107: J4.2 17,142.86 5.84,142.86 3.81,140.83 3.81,88 4.83,86.98 21.21,86.98 22.87,85.33 v2(30.61,85.33)
SPKP: length 101.9
  TOP w0.191: v2(30.61,83.3) 31.14,83.84 31.62,83.84
  L7-SIGNAL w0.107: v2(30.61,83.3) 29.59,83.3 29.08,83.81 26.29,83.81 25.27,84.83 22.73,84.83 21.08,86.48 4.63,86.48 3.3,87.8 3.3,141.16 5.56,143.42 15.02,143.42 J4.1
TPA6304_NSTANDBY: length 132.2
  TOP w0.191: v2(186.31,106.67) 185.93,107.05 185.93,108.96 R69.1 186.06,110.1 184.91,110.1 182.18,112.83 U14.17 ; U37.AJ23 92.08,83.24 92.08,83.69 92.33,83.94 98.04,83.94 98.42,84.32 98.42,89.67 99.67,90.92 107.06,90.92 107.44,90.54 113.54,90.54 115.32,92.32 v1(115.32,95.11)
  L4-SIGNAL w0.163: v1(115.32,95.11) 116.59,96.38 116.59,100.57 119.25,103.24 119.25,104.26 120.4,105.4 125.22,105.4 128.14,108.32 155.45,108.32 163.45,100.32 184.91,100.32 186.31,101.72 v2(186.31,106.67)
TRD1_N: length 3.9
  TOP w0.122: C316.1 R170.1 16.36,58.54 J13.2
TRD1_P: length 3.8
  TOP w0.122: J13.1 16.31,60.19 R161.1 C312.1
TRD_N: length 4.4
  TOP w0.122: L42.1 35.18,58.54 C319.1 35.75,59.11 37.31,59.11 37.38,59.04 U42.13
TRD_P: length 4.4
  TOP w0.122: U42.12 37.38,59.54 37.31,59.47 35.77,59.47 C311.1 35.18,60.06 L40.1
TRSTPD: length 5.3
  TOP w0.191: v1(145.03,38.27) 144.81,38.5 J15.8
  BOTTOM w0.191: v1(145.03,38.27) R425.1 144.4,39.61 144.4,40.5 144.78,40.88 RJ19.1
TUNER0_IQ_ACLKR: length 60.3
  TOP w0.191: TP30.1 42.16,93.72 R89.2
  TOP w0.229: v1(88.78,80.15) 89.18,79.75 U37.AE27
  L4-SIGNAL w0.163: TP30.1 42.04,93.84 42.04,94.73 42.8,95.49 51.05,95.49 51.07,95.48 51.13,95.48 61.4,85.21 76.33,85.21 76.34,85.19 76.4,85.19 77.29,84.3 79.25,84.3 80.12,85.17 80.23,85.17 80.23,85.18 83.01,85.18 83.56,84.63 85.92,84.63 87.63,82.92 87.63,82.24 88.78,81.09 v1(88.78,80.15)
TUNER0_IQ_AXR0: length 53.4
  TOP w0.191: R90.2 TP26.1
  TOP w0.229: U37.AF28 88.38,80.55 v1(87.98,80.95)
  L4-SIGNAL w0.163: TP26.1 43.69,94.99 50.93,94.99 61.21,84.7 76.2,84.7 77.09,83.81 79.46,83.81 80.33,84.68 82.81,84.68 83.35,84.13 83.46,84.13 83.53,84.06 84.2,84.06 86.92,81.35 87.58,81.35 v1(87.98,80.95)
TUNER0_IQ_AXR1: length 53.9
  TOP w0.191: R88.2 TP25.1
  TOP w0.229: U37.AE28 88.38,79.75 v1(87.98,80.15)
  L4-SIGNAL w0.163: v1(50.55,93.59) 52.83,91.3 53.34,91.3 60.83,83.81 75.56,83.81 76.2,83.17 83.95,83.17 86.57,80.55 87.34,80.55 87.34,80.55 87.57,80.55 v1(87.98,80.15)
  L5-SIGNAL w0.163: TP25.1 42.04,93.59 v1(50.55,93.59)
TUNER0_IQ_FSR: length 57.5
  TOP w0.191: R87.2 40.64,93.72 TP29.1
  TOP w0.229: v1(89.58,79.35) 89.98,78.95 U37.AD26
  L4-SIGNAL w0.163: v1(49.53,92.32) 50.56,91.29 50.62,91.29 60.75,81.16 72.02,81.16 72.39,81.52 80.65,81.52 80.8,81.37 83.34,81.37 85.72,78.98 87.78,78.98 87.81,78.95 89.18,78.95 v1(89.58,79.35)
  L5-SIGNAL w0.163: TP29.1 42.04,92.32 v1(49.53,92.32)
TUNER1_IQ_ACLKR: length 54.5
  TOP w0.191: TP31.1 43.69,93.72 R91.2
  TOP w0.229: U37.AA27 v1(88.78,76.95)
  L4-SIGNAL w0.163: v1(88.78,76.95) 88.54,76.95 88.03,77.46 87.13,77.46 86.98,77.31 85.18,77.31 83.73,78.76 80.49,78.76 80.26,78.98 72.58,78.98 72.29,78.69 71.38,78.69 71.21,78.86 61.66,78.86 61.49,78.69 60.58,78.69 60.18,78.69 49.6,89.27 48.13,89.27 TP31.1
TUNER1_IQ_AXR0: length 62
  TOP w0.191: R86.2 TP24.1
  TOP w0.229: v1(90.38,80.15) 90.78,79.75 U37.AE25
  L4-SIGNAL w0.163: v1(90.38,80.15) 89.79,80.73 89.79,81.4 88.34,82.84 88.34,83.99 86.37,85.96 83.3,85.96 82.91,86.34 80.65,86.34 80.59,86.41 76.25,86.41 76.17,86.48 67.82,86.48 67.56,86.73 61.21,86.73 50.29,97.65 42.8,97.65 39.88,94.73 TP24.1
TUNER1_IQ_AXR1: length 56.9
  TOP w0.191: TP28.1 39.12,93.72 R85.2
  TOP w0.229: U37.AF29 87.58,80.55 v1(87.18,80.95)
  L4-SIGNAL w0.163: v1(52.32,92.57) 52.83,92.06 53.21,92.06 61.09,84.19 76.07,84.19 76.74,83.52 79.85,83.52 80.52,84.19 82.8,84.19 83.44,83.56 84.17,83.56 86.78,80.95 v1(87.18,80.95)
  L5-SIGNAL w0.163: TP28.1 41.4,91.43 51.18,91.43 v1(52.32,92.57)
TUNER1_IQ_FSR: length 55.7
  TOP w0.191: R92.2 TP27.1
  TOP w0.229: U37.Y26 v1(89.58,76.15)
  L4-SIGNAL w0.163: v1(89.58,76.15) 89.58,76.91 89.14,77.35 88.76,77.35 88.76,77.35 88.61,77.35 88.16,77.81 85.38,77.81 83.95,79.24 81.03,79.24 79.81,80.46 73.36,80.46 72.08,79.18 71.58,79.18 71.4,79.36 61.47,79.36 61.31,79.21 60.36,79.21 49.78,89.78 48.9,89.78 TP27.1
TUNER_AGND: length 199.6
  TOP w0.305: v1(174.75,102.1) 174.5,101.84 C142.1 ; PL1.1 v1(55.24,113.27)
  L3-GND w0.305: v1(55.24,113.27) 55.24,114.32 55.18,114.39 55.18,117.52 60.2,122.54 60.2,128.51 65.53,133.85 65.53,143.63 67.94,146.04 89.53,146.04 92.84,142.74 101.6,142.74 105.92,147.06 105.92,147.82 108.2,150.1 155.7,150.1 162.69,143.12 162.69,130.8 166.5,126.99 166.5,113.78 170.43,109.84 172.93,109.84 175.13,107.64 175.13,105.15 177.16,103.11 179.07,103.11 179.96,102.22 179.96,101.77 179.65,101.46 175.39,101.46 v1(174.75,102.1)
TUNER_AUDIO_ACLKX: length 8.7
  TOP w0.191: R94.2 TP22.1 ; U19.60 v1(47.72,102.9)
  L5-SIGNAL w0.163: TP22.1 48.26,97.65 48.01,97.91 48.01,102.18 47.72,102.47 v1(47.72,102.9)
TUNER_AUDIO_AXR0: length 54.6
  TOP w0.191: U19.67 52.37,105.1 53.59,103.88 v1(53.59,102.98)
  TOP w0.229: U37.AE29 v1(87.18,80.15)
  L4-SIGNAL w0.163: v1(87.18,80.15) 86.34,80.15 83.6,82.89 60.99,82.89 v1(53.59,90.29)
  L5-SIGNAL w0.163: v1(53.59,90.29) v1(53.59,102.98)
TUNER_AUDIO_AXR1: length 57.1
  TOP w0.191: U19.64 v1(49.72,103.43)
  TOP w0.229: v1(87.98,79.35) 88.38,78.95 U37.AD28
  L4-SIGNAL w0.163: v1(87.98,79.35) 85.87,79.35 83.03,82.19 72.55,82.19 71.81,81.45 61.14,81.45 v1(50.41,92.18)
  L5-SIGNAL w0.163: v1(50.41,92.18) 51.09,92.86 51.09,93.94 50.61,94.41 50.61,98.86 49.91,99.56 49.91,102.81 49.72,103 v1(49.72,103.43)
TUNER_AUDIO_AXR10: length 48.9
  TOP w0.191: R82.2 v1(49.91,94.48)
  TOP w0.229: v1(88.78,79.35) 89.18,78.95 U37.AD27
  L4-SIGNAL w0.163: v1(49.91,94.48) 49.91,93.25 60.63,82.54 83.31,82.54 86.11,79.75 87.81,79.75 87.81,79.75 88.14,79.75 88.14,79.75 88.38,79.75 v1(88.78,79.35)
TUNER_AUDIO_AXR11: length 52.3
  TOP w0.191: v1(49.15,96.26) R81.2
  TOP w0.229: v1(90.38,78.55) 90.78,78.15 U37.AC25
  L4-SIGNAL w0.163: v1(90.38,78.55) 89.97,78.95 89.97,79.51 89.41,80.08 89.41,81.14 88.01,82.54 88.01,83.43 85.77,85.67 83.09,85.67 82.76,86 80.25,86 79.05,84.8 77.5,84.8 76.45,85.84 67.56,85.84 67.18,86.22 61.09,86.22 51.05,96.26 v1(49.15,96.26)
TUNER_AUDIO_FSX: length 8.6
  TOP w0.191: U19.59 v1(47.22,103.52) ; R93.2 TP21.1
  L5-SIGNAL w0.163: v1(47.22,103.52) 47.22,100.09 47.37,99.94 TP21.1
TUNER_IN1M: length 34.5
  TOP w0.191: U19.20 41.22,117.52 v1(40.89,117.85) ; 22.23,137.29 22.21,137.29 ; 22.23,137.29 C23.1 ; 22.23,137.29 23.36,137.29 R9.2 v1(24.38,137.02)
  L4-SIGNAL w0.163: v1(40.89,117.85) 40.57,118.17 39.43,118.17 38.48,119.12 31.88,119.12 25.65,125.34 25.65,131.82 24.38,133.09 v1(24.38,137.02)
TUNER_IN1P: length 37.2
  TOP w0.191: U19.19 41.72,117.02 41.63,117.11 41.63,117.75 41.4,117.97 41.4,118.23 v1(40.89,118.73) ; v1(23.37,139.05) R8.1 22.59,139.07 22.34,138.81 21.21,138.81 ; 21.21,138.81 21.2,138.81 ; 21.21,138.81 C18.1
  L4-SIGNAL w0.163: v1(23.37,139.05) 24.89,137.53 24.89,133.34 26.16,132.07 26.16,125.59 32.13,119.62 38.61,119.62 39.5,118.73 v1(40.89,118.73)
TUNER_IN2M: length 27.6
  TOP w0.191: U19.22 40.22,116.92 v1(40.01,117.13) ; C53.1 23.37,130.93 23.62,130.67 v1(24.38,130.67)
  L4-SIGNAL w0.163: v1(40.01,117.13) 39.2,117.13 38.23,118.1 31.37,118.1 24.38,125.08 v1(24.38,130.67)
TUNER_IN2P: length 30.3
  TOP w0.191: U19.21 v1(40.72,117.21) ; C36.1 22.35,132.45 R14.1 v1(23.37,132.7)
  L4-SIGNAL w0.163: v1(40.72,117.21) 40.33,117.59 39.37,117.59 38.35,118.61 31.62,118.61 25.15,125.08 25.15,130.93 v1(23.37,132.7)
TUNER_IN3M: length 18.5
  TOP w0.191: v1(24.38,117.97) R52.2 23.37,118.23 C95.1 ; U19.24 v1(38.1,115.1)
  L4-SIGNAL w0.163: v1(38.1,115.1) 27.25,115.1 v1(24.38,117.97)
TUNER_IN3P: length 20.2
  TOP w0.191: v1(23.37,120) 22.61,120 22.35,119.75 C81.1 ; U19.23 v1(38.65,115.6)
  L4-SIGNAL w0.163: v1(23.37,120) 27.77,115.6 v1(38.65,115.6)
TUNER_IN4M: length 18.4
  TOP w0.191: C108.1 23.37,111.88 23.62,111.62 v1(24.38,111.62) ; U19.26 v1(38.1,114.1)
  L4-SIGNAL w0.163: v1(38.1,114.1) 26.86,114.1 v1(24.38,111.62)
TUNER_IN4P: length 18.8
  TOP w0.191: C103.1 22.35,113.4 R58.1 v1(23.37,113.65) ; v1(38.61,114.6) U19.25
  L4-SIGNAL w0.163: v1(23.37,113.65) 24.32,114.6 v1(38.61,114.6)
TUNER_IN5M: length 28.3
  TOP w0.191: C160.1 23.37,99.18 23.62,98.92 v1(24.38,98.92) ; U19.28 v1(38.14,113.1)
  L4-SIGNAL w0.163: v1(38.14,113.1) 29.93,113.1 24.38,107.56 v1(24.38,98.92)
TUNER_IN5P: length 27.5
  TOP w0.191: C148.1 22.35,100.7 R77.1 v1(23.37,100.95) ; U19.27 v1(38.66,113.6)
  L4-SIGNAL w0.163: v1(38.66,113.6) 29.28,113.6 23.75,108.07 23.75,101.34 v1(23.37,100.95)
TUNER_IN6M: length 32.9
  TOP w0.191: C195.1 23.37,92.83 R101.2 v1(24.38,92.57) ; U19.30 v1(38.13,112.1)
  L4-SIGNAL w0.163: v1(24.38,92.57) 25.65,93.84 25.65,106.54 31.21,112.1 v1(38.13,112.1)
TUNER_IN6P: length 32.1
  TOP w0.191: C178.1 22.35,94.35 R97.1 v1(23.37,94.6) ; U19.29 v1(38.64,112.6)
  L4-SIGNAL w0.163: v1(23.37,94.6) 25.02,96.26 25.02,107.05 30.57,112.6 v1(38.64,112.6)
TUNER_INTB_CHIP0: length 78.8
  TOP w0.191: U19.37 38.33,108.6 38.1,108.83 v1(37.21,108.83) R68.1
  TOP w0.229: U37.W28 v1(87.98,75.35)
  L4-SIGNAL w0.163: v1(37.21,108.83) 36.8,108.42 36.8,105.05 37.72,104.13 37.72,102.48 37.21,101.97 37.21,92.83 39.88,90.16 45.59,90.16 47.5,88.25 48.51,88.25 59.44,77.33 67.54,77.33 67.64,77.43 70.99,77.43 71.35,77.08 78.11,77.08 78.3,76.89 84.27,76.89 84.71,76.44 87.28,76.44 87.98,75.75 v1(87.98,75.35)
TUNER_OUT0: length 197.8
  TOP w0.191: U19.84 v1(54.23,113.6) ; C131.2 v1(183.77,101.97)
  L3-GND w0.097: v1(183.77,101.97) 181.61,104.13 177.67,104.13 176.02,105.78 176.02,108.19 173.61,110.61 171.2,110.61 167.57,114.23 167.57,127.57 163.83,131.31 163.83,143.63 157.48,149.98 156.52,150.93 100.39,150.93 99.96,151.36 93.38,151.36 91.31,149.29 91.31,148.71 89.54,146.93 67.69,146.93 64.39,143.62 64.39,133.72 59.05,128.38 59.05,122.8 54.23,117.97 v1(54.23,113.6)
TUNER_OUT1: length 194.9
  TOP w0.191: C130.2 v1(181.48,101.97) ; U19.85 v1(54.74,114.1)
  L3-GND w0.097: v1(181.48,101.97) 179.71,103.75 177.42,103.75 175.64,105.53 175.64,107.94 173.35,110.23 170.81,110.23 167.13,113.91 167.13,127.37 163.33,131.17 163.33,143.37 156.08,150.61 100.22,150.61 99.7,151.14 93.66,151.14 91.69,149.17 91.69,148.45 89.79,146.55 67.82,146.55 64.93,143.66 64.93,133.75 59.59,128.42 59.59,122.7 54.74,117.85 v1(54.74,114.1)
TUNER_OUT2: length 198.6
  TOP w0.191: U19.86 v1(55.68,114.6) ; C129.2 v1(179.2,101.97)
  L3-GND w0.097: v1(179.2,101.97) 178.82,102.35 177.16,102.35 174.62,104.89 174.62,107.43 172.72,109.34 161.04,109.34 157.48,112.89 157.48,147.31 155.32,149.47 113.78,149.47 113.63,149.61 108.35,149.61 106.3,147.56 106.3,146.93 101.68,142.31 92.63,142.31 89.34,145.6 68.14,145.6 65.97,143.43 65.97,133.65 60.64,128.32 60.64,122.35 55.69,117.4 55.69,115.31 55.68,115.31 v1(55.68,114.6)
TUNER_OUT3: length 195.3
  TOP w0.191: U19.87 55.93,115.1 v1(56.13,115.31) ; C128.2 v1(176.91,101.97)
  L3-GND w0.097: v1(56.13,115.31) 56.13,117.21 61.09,122.16 61.09,128.24 66.42,133.58 66.42,143.25 68.33,145.15 89.28,145.15 92.35,142.08 101.96,142.08 106.68,146.8 106.68,147.44 108.63,149.39 113.24,149.39 113.5,149.13 155.03,149.13 157.1,147.06 157.1,112.51 160.66,108.96 172.47,108.96 174.12,107.3 174.12,104.76 v1(176.91,101.97)
TUNER_RSTB_CHIP0: length 80
  TOP w0.191: U19.31 38.63,111.6 v1(38.61,111.62)
  TOP w0.229: U37.Y27 v1(88.78,76.15)
  L4-SIGNAL w0.163: v1(88.78,76.15) 88.18,76.15 87.51,76.82 84.97,76.82 84.62,77.18 78.52,77.18 78.11,77.59 71.78,77.59 71.01,78.36 61.99,78.36 61.82,78.2 60.79,78.2 59.97,78.2 49.41,88.76 47.75,88.76 45.85,90.67 40.13,90.67 37.79,93.01 37.79,100.25 38.23,100.68 38.23,104.38 37.39,105.22 37.39,107.23 37.62,107.46 37.62,108.24 37.97,108.59 37.97,110.99 v1(38.61,111.62)
  BOTTOM w0.191: v1(38.61,111.62) R280.1
TUNER_SPI_CS0: length 72.6
  TOP w0.191: U19.41 v1(38.67,106.6)
  TOP w0.229: U37.AC21 93.98,78.15 v1(93.58,78.55)
  L4-SIGNAL w0.163: v1(38.67,106.6) 39.87,105.4 49.91,105.4 51.44,103.88 51.44,99.94 52.2,99.18 52.2,98.03 61.72,88.51 67.94,88.51 68.38,88.08 75.97,88.08 76.65,87.39 79.68,87.39 79.95,87.66 82.58,87.66 82.99,87.66 83.7,86.94 87.34,86.94 87.95,86.33 87.96,86.33 90.77,83.52 90.77,83.23 90.78,83.23 90.78,82.38 91.01,82.15 91.44,82.15 93.17,80.41 93.17,78.95 v1(93.58,78.55)
TUNER_SPI_D0: length 69.2
  TOP w0.191: U19.39 v1(38.65,107.6)
  TOP w0.229: U37.AJ22 v1(92.78,83.35)
  L4-SIGNAL w0.163: v1(92.78,83.35) 92.78,83.59 91.54,84.83 91.09,84.83 88.17,87.75 83.79,87.75 83.16,88.38 79.5,88.38 79.09,87.97 77.12,87.97 76.33,88.76 68.96,88.76 68.45,89.27 62.23,89.27 53.09,98.41 53.09,103.75 50.42,106.42 40.77,106.42 39.58,107.6 v1(38.65,107.6)
TUNER_SPI_D1: length 71.2
  TOP w0.191: U19.38 v1(38.1,108.1)
  TOP w0.229: U37.AH22 93.18,82.15 v1(92.78,82.55)
  L4-SIGNAL w0.163: v1(38.1,108.1) 38.1,107.57 38.48,107.19 39.23,107.19 40.51,105.91 50.29,105.91 52.45,103.75 52.45,99.56 52.7,99.3 52.7,98.16 61.98,88.89 68.2,88.89 68.71,88.38 76.2,88.38 76.9,87.68 79.34,87.68 79.62,87.97 83.09,87.97 83.69,87.37 87.85,87.37 91.07,84.19 91.7,84.19 92.37,83.51 92.37,82.95 v1(92.78,82.55)
TUNER_SPI_SCLK: length 39
  TOP w0.191: v1(37.97,106.8) 38.28,107.1 U19.40 ; R110.2 v1(63.37,87.24)
  L4-SIGNAL w0.163: v1(37.97,106.8) 37.97,106.29 39.37,104.89 49.66,104.89 50.93,103.62 50.93,99.81 50.94,99.8 50.94,99.73 51.7,98.97 51.7,97.83 61.52,88.02 61.58,88.02 62.36,87.24 v1(63.37,87.24)
UB960_CAM_NPOWERON: length 147.5
  TOP w0.191: Q8.5 R234.2 v1(91.95,26.28)
  TOP w0.229: v1(107.18,77.75) 107.18,77.74 U37.AB5
  L5-SIGNAL w0.163: v1(91.95,26.28) 95.38,26.28 100.71,31.61 105.66,31.61 106.55,30.72 108.58,30.72 110.24,32.37 v1(146.69,32.37)
  BOTTOM w0.163: v1(107.18,77.75) 107.58,78.15 111.15,78.15 111.34,78.35
  BOTTOM w0.191: v1(146.69,32.37) 146.69,42.15 148.59,44.06 148.59,47.11 151.13,49.65 151.13,51.42 149.86,52.69 149.86,53.58 144.91,58.54 144.91,71.11 134.62,81.4 115.44,81.4 113.92,79.87 112.87,79.87 111.34,78.35
UB960_FRAME_SYNC: length 158.9
  TOP w0.229: U37.AA2 109.58,76.94 v1(109.58,76.95)
  L2-SIGNAL w0.107: v1(140.06,78.39) 139.77,78.1 139.77,77.86 139.95,77.68 139.95,57.52 135,52.57 v1(135,34.41)
  L4-SIGNAL w0.163: v1(109.58,76.95) 109.98,76.55 110.7,76.55 111.66,77.52 120.38,77.52 120.42,77.55 120.44,77.55 122.54,79.65 138.14,79.65 139.41,78.39 v1(140.06,78.39)
  L5-SIGNAL w0.163: v1(135,34.41) 76.2,34.41 72.77,30.98 70.36,30.98 69.22,29.83 63.12,29.83 60.2,26.91 v1(59.56,26.91)
  BOTTOM w0.191: v1(59.56,26.91) 59.56,26.7 59.86,26.4 U74.9
UB960_IDX: length 6.6
  BOTTOM w0.191: R440.2 R436.1 C808.1 73.13,23.1 72.83,23.4 U74.46
UB960_INTB: length 165.4
  TOP w0.229: U37.W5 107.18,75.34 v1(107.18,75.35)
  L2-SIGNAL w0.107: v1(135.38,33.52) 135.38,34.25 135.38,34.25 135.38,34.41 135.54,34.57 135.54,52.6 140.34,57.39 140.34,77.3 140.33,77.31 v1(140.33,77.84)
  L5-SIGNAL w0.163: v1(140.33,77.84) 139.83,77.84 138.43,79.24 121.92,79.24 121.67,78.98 120.52,78.98 119.76,78.22 114.55,78.22 113.67,77.33 112.19,77.33 110.61,75.75 110.22,75.75 109.98,75.51 109.98,75.12 109.81,74.95 107.58,74.95 v1(107.18,75.35) ; v1(58.93,25.77) 59.56,25.77 63.25,29.45 72.03,29.45 76.48,33.9 135,33.9 v1(135.38,33.52)
  BOTTOM w0.191: R429.2 v1(58.93,25.77) 59.8,24.9 U74.6
UB960_MODE: length 6.6
  BOTTOM w0.191: U74.45 71.66,23.9 71.88,24.12 C805.1 R430.1 R428.2
UB960_PDB: length 161.8
  TOP w0.229: v1(110.38,76.95) 110.38,76.94 U37.AA1
  L2-SIGNAL w0.107: v1(139.67,78.95) 139.67,78.54 139.54,78.41 139.54,57.61 134.62,52.69 v1(134.62,33.39)
  L4-SIGNAL w0.163: v1(110.38,76.95) 111.24,77.81 120.26,77.81 120.3,77.84 120.32,77.84 122.42,79.94 136.19,79.94 138.67,79.94 v1(139.67,78.95)
  L5-SIGNAL w0.163: v1(134.62,33.39) 76.71,33.39 72.26,28.95 70.23,28.95 68.2,26.91 61.47,26.91 59.82,25.26 59.44,25.26 58.93,24.75 v1(58.93,23.74)
  BOTTOM w0.191: R433.1 v1(58.93,23.74) 59.27,23.4 U74.3
UB960_REFCLK: length 40.9
  L5-SIGNAL w0.163: v1(59.56,24.5) 60.83,24.5 61.21,24.12 68.58,24.12 68.92,23.78 98.13,23.78 v1(98.42,23.48)
  BOTTOM w0.191: R435.2 v1(98.42,23.48) ; U74.5 59.66,24.4 v1(59.56,24.5)
UB981_CLKIN: length 1.7
  BOTTOM w0.191: R434.2 103.02,23.48 103.05,23.52 U75.41
UB981_DOUT0_N: length 1.8
  BOTTOM w0.122: C831.2 109.02,14.47 108.86,14.32 108.86,13.88 109.12,13.62 FL41.4
UB981_DOUT0_P: length 1.8
  BOTTOM w0.122: FL41.1 108.31,13.62 108.56,13.88 108.56,14.32 108.41,14.47 C832.2
UB981_GPIO0: length 115.4
  TOP w0.229: U37.Y3 108.78,76.14 v1(108.78,76.15)
  L2-SIGNAL w0.107: v1(135.25,26.53) 135.89,27.17 135.89,52.44 140.72,57.27 v1(140.72,80)
  L5-SIGNAL w0.163: v1(114.05,20.6) 114.65,21.2 116.71,21.2 118.36,22.85 128.39,22.85 132.07,26.53 v1(135.25,26.53) ; v1(140.72,80) 140.29,80 140.16,80.13 137.67,80.13 137.39,79.85 121.69,79.85 120.78,80.76 119,80.76 117.22,78.98 114.3,78.98 113.41,78.09 111.35,78.09 110.61,77.35 110.22,77.35 109.98,77.11 109.98,76.75 109.78,76.55 109.18,76.55 v1(108.78,76.15)
  BOTTOM w0.191: v1(114.05,20.6) 113.96,20.52 U75.14
UB981_GPIO1: length 118
  TOP w0.229: U37.W4 107.98,75.34 v1(107.98,75.35)
  L2-SIGNAL w0.107: v1(107.98,75.35) 108.39,75.76 110.54,75.76 111.61,76.82 120.52,76.82 122.43,78.73 126.77,78.73 v1(128.4,80.36) ; v1(135.89,26.02) 136.27,26.41 136.27,52.31 141.1,57.14 141.1,78.82 141.09,78.82 141.09,79.14 141.1,79.15 141.1,79.62 v1(141.48,80)
  L5-SIGNAL w0.163: v1(128.4,80.36) 128.72,80.68 140.79,80.68 v1(141.48,80) ; v1(115.19,20.31) 115.63,20.75 117.28,20.75 118.87,22.34 128.52,22.34 132.21,26.02 v1(135.89,26.02)
  BOTTOM w0.191: v1(115.19,20.31) 114.75,20.31 114.46,20.02 U75.15
UB981_GPIO2: length 63
  TOP w0.229: U37.Y5 106.78,75.75 v1(107.18,76.15)
  L4-SIGNAL w0.163: v1(107.18,76.15) 107.58,75.75 107.58,74.38 107.35,74.15 107.01,74.15 106.78,73.91 106.78,73.58 105.74,72.55 105.41,72.55 105.18,72.31 105.18,71.98 104.95,71.75 104.15,71.75 104.15,71.75 103.01,71.75 103.01,71.75 102.94,71.75 102.78,71.58 102.78,71.18 102.54,70.94 102.14,70.94 101.98,70.79 101.98,69.15 101.98,68.31 101.98,64.5 101.98,64.5 101.98,63.98 101.74,63.75 101.42,63.75 100.38,62.71 100.38,61.91 100.38,61.11 100.38,61.11 100.38,59.74 100.33,59.69 100.33,31.1 104.01,27.42 104.01,22.5 v1(103.25,21.74)
  BOTTOM w0.191: U75.38 103.53,22.02 v1(103.25,21.74)
UB981_GPIO3: length 135.7
  TOP w0.229: U37.Y2 109.58,76.14 v1(109.58,76.15)
  L2-SIGNAL w0.107: v1(143.89,76.41) 143.89,56.38 139.32,51.81 139.32,44.06 140.08,43.3 140.08,42.15 139.45,41.52 139.45,26.15 v1(138.81,25.52)
  L4-SIGNAL w0.163: v1(109.58,76.15) 109.98,75.75 110.78,75.75 111.97,76.94 120.62,76.94 120.66,76.97 120.69,76.97 122.75,79.03 136.23,79.03 138.85,76.41 v1(143.89,76.41)
  L5-SIGNAL w0.163: v1(103.25,22.76) 104.52,21.49 104.52,19.67 107.33,16.87 110.38,16.87 111.12,16.12 113.28,16.12 113.64,15.76 116.86,15.76 122.94,21.83 128.65,21.83 132.33,25.52 v1(138.81,25.52)
  BOTTOM w0.191: v1(103.25,22.76) 103.49,22.52 U75.39
UB981_IDX: length 3.2
  BOTTOM w0.191: R447.2 111.63,16.77 ; R447.2 111.63,17.42 111.46,17.6 U75.19 ; R447.2 R446.1
UB981_INTB: length 5.1
  BOTTOM w0.191: U75.30 105.96,17.05 R448.2 107.19,15.82 107.19,14.72 R455.1
UB981_MODE_SEL0: length 3.3
  TOP w0.191: 111.63,16.77 R248.2 ; R248.2 111.63,17.45 v1(112,17.82) ; R248.2 R249.1
  BOTTOM w0.191: v1(112,17.82) 112,17.88 111.96,17.92 U75.18
UB981_MODE_SEL1: length 2.7
  TOP w0.191: R246.2 v1(104.01,17.93)
  BOTTOM w0.191: R246.2 v1(104.01,17.93) 104.34,18.26 104.34,18.52 104.58,18.77 U75.32
UB981_PDB: length 122.5
  TOP w0.229: v1(110.38,76.15) 110.38,76.14 U37.Y1
  L2-SIGNAL w0.107: v1(139.06,77.84) 139.06,77.43 139.22,77.28 139.22,57.8 134.24,52.82 134.24,34.41 133.99,34.15 133.99,32.88 134.49,32.37 v1(134.49,24.17)
  L4-SIGNAL w0.163: v1(110.38,76.15) 110.77,76.15 111.85,77.23 120.5,77.23 120.54,77.26 120.57,77.26 122.63,79.32 137.59,79.32 v1(139.06,77.84)
  L5-SIGNAL w0.163: v1(134.49,24.17) 133.83,23.51 130.96,23.51 128.78,21.33 123.95,21.33 119.89,17.26 119.13,17.26 117.35,15.48 113.16,15.48 113,15.64 110.84,15.64 109.98,16.5 106.86,16.5 v1(105.46,17.9)
  BOTTOM w0.191: R442.1 105.16,17.59 105.46,17.9 v1(105.46,17.9) U75.31
UB981_REM_INTB: length 1.9
  BOTTOM w0.191: R437.1 114.45,21.95 113.88,22.52 U75.10
USART_A_RXD: length 5.1
  TOP w0.191: R226.1 v1(37.08,27.68) ; U52.17 v1(34.59,29.15)
  L5-SIGNAL w0.163: v1(34.59,29.15) 36.07,27.68 v1(37.08,27.68)
USART_A_TXD: length 9.8
  TOP w0.191: U52.16 35.18,27.17 36.83,28.82 37.07,28.82 37.07,28.82 U55.4
USART_B_RXD: length 13.5
  TOP w0.191: U52.39 v1(28.45,35.55) ; R217.1 v1(37.85,35.55)
  L5-SIGNAL w0.163: v1(37.85,35.55) 37.47,35.93 35.81,35.93 35.43,35.55 v1(28.45,35.55)
USART_B_TXD: length 16.8
  TOP w0.191: U52.38 28.96,40.43 28.75,40.63 28.75,41.06 29.21,41.52 33.15,41.52 38.74,35.93 U51.4
USART_DM: length 27.5
  TOP w0.157: J19.2 15.51,12.83 16.05,13.38 U60.5 16.39,13.83 17.08,14.52 18.01,14.52 18.64,13.88 22.53,13.88 27.05,18.4 27.05,26.09 26.95,26.2 U52.7
USART_DP: length 27.5
  TOP w0.157: J19.3 16.31,10.07 17.39,11.16 U60.3 17.39,12.32 16.89,12.82 16.89,13.9 17.2,14.21 17.88,14.21 18.52,13.58 22.66,13.58 27.36,18.28 27.36,26.09 27.46,26.2 U52.8
USART_EECS: length 13
  TOP w0.191: R238.1 15.11,23.99 U56.5 v2(17.83,23.99) ; U52.63 23.04,29.66 23.37,29.33 v2(23.37,28.44)
  L5-SIGNAL w0.163: v2(23.37,28.44) 21.08,26.15 19.54,26.15 17.83,24.44 v2(17.83,23.99)
USART_EEDIN: length 10.5
  TOP w0.191: U56.3 R232.2 v2(18.85,27.29) ; v2(23.8,30.65) U52.61
  L5-SIGNAL w0.163: v2(18.85,27.29) 20.45,27.29 v2(23.8,30.65)
USART_EEDOUT: length 7.6
  TOP w0.191: 17.4,21.45 18.03,22.09 v2(18.08,22.09) 18.54,22.09 18.85,22.4 U56.1 ; v2(19.86,25.52) R232.1
  L5-SIGNAL w0.163: v2(19.86,25.52) 19.54,25.2 19.54,25.09 18.08,23.63 v2(18.08,22.09)
USART_EESK: length 13.3
  TOP w0.191: v2(23.8,29.83) 23.33,29.83 23.03,30.14 U52.62 ; U56.4 17.13,24.94 v2(18.08,25.9)
  L5-SIGNAL w0.163: v2(23.8,29.83) 20.62,26.66 18.85,26.66 v2(18.08,25.9)
  BOTTOM w0.191: v2(18.08,25.9) 17.2,25.01 17.2,24.5
USART_GND: length 22.3
  TOP w0.508: J19.6 J19.8 J19.9 J19.7 R255.2
USART_LED: length 2.8
  TOP w0.191: D14.2 R237.2
USART_NR: length 1.6
  TOP w0.191: U53.2 16.89,34.03 16.76,34.15 C374.1
USART_OSCI: length 14.2
  TOP w0.191: 17.3,19.32 18.03,20.06 18.03,20.94 21.29,24.2 21.29,24.96 22.15,25.82 24.13,25.82 24.46,26.15 U52.2 ; 17.3,19.32 16.03,19.32 C441.1 ; 17.3,19.32 Y5.1
USART_OSCO: length 17.7
  TOP w0.191: 19.48,15.66 19.48,15.81 18.47,16.83 18.47,20.74 21.72,23.99 21.72,24.75 22.35,25.39 24.38,25.39 24.94,25.95 U52.3 ; 19.48,15.66 19.48,15.61 20.5,15.61 20.68,15.79 C449.1 ; 19.48,15.66 Y5.3
USART_PD: length 22.6
  TOP w0.191: U51.10 v1(44.06,33.78) ; v1(39.63,35.43) U51.5 ; v1(39.63,28.32) U55.5 ; 45.85,27.42 45.31,27.42 45.2,27.32 U55.10 v1(44.06,26.67)
  BOTTOM w0.191: v1(44.06,33.78) 41.27,33.78 v1(39.63,35.43) 39.18,34.98 39.18,28.76 v1(39.63,28.32) 41.27,26.67 v1(44.06,26.67)
USART_PWREN: length 9.2
  TOP w0.191: U52.60 18.97,31.16 17.53,29.71 15.47,29.71 14.99,30.19 D14.1
USART_RESETN: length 3.7
  TOP w0.191: R236.2 32.18,25.04 31.32,25.9 30.74,25.9 30.45,26.18 U52.14
USART_RSET: length 2.1
  TOP w0.191: R235.2 26.29,26.02 26.44,26.18 U52.6
USB0_CS: length 47.8
  TOP w0.191: R55.1 v2(151.76,114.8)
  L2-SIGNAL w0.107: v1(114.81,127.5) 123.83,127.5 125.35,129.02 136.27,129.02 143.13,122.16 144.98,122.16 151.76,115.38 v2(151.76,114.8)
  BOTTOM w0.191: R268.2 R272.1 C499.1 v1(114.81,127.5)
USB0_DATA_N: length 74.1
  TOP w0.157: U37.AJ5 107.18,83.34 v1(107.18,83.35) ; U11.4 149.81,120.41 149.81,119.83 v1(149.61,119.62)
  L4-SIGNAL w0.147: v1(107.18,83.35) 107.18,83.74 107.31,83.88 107.31,84.74 107.46,84.89 107.67,84.89 108.29,84.27 108.51,84.27 108.67,84.43 108.67,84.66 107.99,85.34 107.99,85.57 110.43,88.01 110.43,89.52 111.73,90.81 111.73,93.89 112.9,95.06 112.9,103.11 118.11,108.32 124.46,108.32 126.57,110.43 145.11,110.43 148.01,113.32 148.01,119.36 149.03,120.39 149.64,120.39 149.87,120.16 149.87,119.95 149.76,119.84 149.76,119.78 v1(149.61,119.62)
USB0_DATA_P: length 74.1
  TOP w0.157: U11.5 150.11,120.38 150.11,119.82 v1(150.33,119.61) ; v1(106.38,82.55) 106.38,82.54 U37.AH6
  L4-SIGNAL w0.147: v1(106.38,82.55) 106.78,82.95 106.78,83.55 106.88,83.65 106.88,83.88 106.96,83.96 106.96,84.97 110.13,88.13 110.13,89.64 111.42,90.94 111.42,94.01 112.6,95.19 112.6,103.24 117.98,108.63 124.33,108.63 126.44,110.73 144.98,110.73 147.7,113.45 147.7,119.49 148.9,120.69 149.77,120.69 150.17,120.29 150.17,119.73 150.28,119.62 150.32,119.62 150.33,119.62 v1(150.33,119.61)
USB0_DRVVBUS: length 103.4
  TOP w0.191: v1(153.67,116.58) R56.1 R49.1 R50.1
  TOP w0.229: U37.U6 106.38,73.74 v1(106.38,73.75)
  L5-SIGNAL w0.163: v1(136.4,76.82) 137.29,75.94 139.95,75.94 146.69,69.2 149.61,69.2 151.26,70.86 151.26,73.65 153.8,76.19 153.8,78.6 154.31,79.11 154.31,103.62 153.67,104.26 v1(153.67,116.58)
  BOTTOM w0.163: 108.58,73.9 108.34,74.15 106.78,74.15 v1(106.38,73.75)
  BOTTOM w0.191: 108.58,73.9 109.15,73.34 110.68,73.34 111.12,73.78 113.03,73.78 117.09,77.84 121.28,77.84 122.05,78.6 134.62,78.6 v1(136.4,76.82)
USB0_ID: length 20.3
  TOP w0.191: R95.1 v1(111.61,95.49)
  TOP w0.229: v1(106.38,78.55) 106.38,78.54 U37.AC6
  L5-SIGNAL w0.163: v1(106.38,78.55) 106.38,81.19 107.58,82.38 107.58,84.71 110.24,87.37 110.24,90.41 111.12,91.3 111.12,92.45 111.61,92.93 v1(111.61,95.49)
USB0_IMON: length 164.3
  TOP w0.191: U37.L29 87.28,68.25 86.17,68.25 v1(83.82,70.6) ; R51.1 v1(143.89,117.59)
  L2-SIGNAL w0.107: v1(143.89,117.59) 137.03,117.59 133.93,120.69 103.96,120.69 101.47,123.18 94.87,123.18 89.53,128.51 83.19,128.51 82.04,127.37 75.31,127.37 73.03,129.66 70.48,129.66 57.78,116.96 57.78,94.22 59.31,92.7 61.47,92.7 69.98,84.19 69.98,81.9 70.87,81.02 70.87,78.48 78.36,70.99 83.44,70.99 v1(83.82,70.6)
USB0_RCALIB: length 6.5
  TOP w0.229: v1(106.38,77.75) 105.98,77.35 U37.AB6
  BOTTOM w0.163: v1(106.38,77.75) 106.78,77.35 110.85,77.35 110.87,77.33
  BOTTOM w0.191: 110.87,77.33 111.12,77.59 R343.1
USB0_SS_RX2_N: length 75.8
  TOP w0.157: v1(103.98,82.55) 103.98,82.54 U37.AH9
  L4-SIGNAL w0.147: v1(145.43,133.85) 145.62,133.66 145.62,132.6 145.47,132.45 143,132.45 135.64,125.08 132.41,125.08 119.38,112.05 117.22,112.05 109.42,104.26 109.42,96.76 106.38,93.72 106.38,88.89 105.79,88.31 104.6,88.31 104.06,87.77 104.06,84.35 104.07,83.85 104.35,83.57 104.35,82.92 v1(103.98,82.55)
  BOTTOM w0.157: FL36.4 145.54,134.64 145.54,133.96 v1(145.43,133.85)
USB0_SS_RX2_P: length 75.8
  TOP w0.157: v1(104.78,83.35) 104.78,83.34 U37.AJ8
  L4-SIGNAL w0.147: v1(104.78,83.35) 104.65,83.48 104.65,83.7 104.37,83.98 104.37,84.35 104.37,85.65 104.51,85.79 104.86,85.79 104.98,85.91 104.98,86.07 104.86,86.19 104.49,86.19 104.37,86.31 104.37,87.63 104.74,88 105.92,88 106.68,88.76 106.68,93.59 109.73,96.64 109.73,104.13 117.35,111.75 119.51,111.75 132.54,124.78 135.76,124.78 143.13,132.15 145.6,132.15 145.92,132.47 145.92,133.58 v1(146.19,133.85)
  BOTTOM w0.157: FL36.1 146.05,134.64 146.05,133.99 v1(146.19,133.85)
USB0_SS_TX2_N: length 1.6
  BOTTOM w0.157: FL35.4 147.42,134.51 147.68,134.25 147.68,133.66 C494.2
USB0_SS_TX2_P: length 1.6
  BOTTOM w0.157: C493.2 147.98,133.66 147.98,134.25 148.23,134.51 FL35.1
USB0_STATUS: length 79.4
  TOP w0.191: R39.1 146.05,123.31 v1(146.43,123.31) 147.08,122.66 U11.17
  TOP w0.229: v1(107.18,79.35) 107.18,79.34 U37.AD5
  L5-SIGNAL w0.163: v1(146.43,123.31) 145.16,123.31 144.91,123.05 144.13,123.05 144.07,123.11 143.71,123.11 143.65,123.05 119,123.05 117.73,121.78 117.73,117.59 112.27,112.13 112.27,92.19 111.51,91.43 111.51,86.22 108.59,83.3 108.59,82.92 106.78,81.12 106.78,79.75 v1(107.18,79.35)
USB0_VBUS_OCN: length 83.1
  TOP w0.191: U11.18 146.69,122.16 v1(146.52,122.33) 146.01,122.33 R40.1
  TOP w0.229: U37.W6 105.98,74.95 v1(106.38,75.35)
  L5-SIGNAL w0.163: v1(146.52,122.33) 144.69,122.33 144.53,122.16 143.42,122.16 143.04,122.54 119.13,122.54 118.24,121.66 118.24,114.42 114.17,110.35 114.17,91.18 112.2,89.2 112.19,89.2 111.93,88.94 111.93,85.51 108.38,81.96 108.38,79.35 108.01,78.98 107.8,78.98 107.58,78.77 107.58,78.39 107.35,78.15 107.02,78.15 106.78,77.92 106.78,75.75 v1(106.38,75.35)
USB0_VBUS_SOC: length 77.8
  TOP w0.191: v1(140.46,131.43) R17.2 R18.2
  TOP w0.229: v1(105.58,78.55) 105.18,78.15 U37.AC7
  L5-SIGNAL w0.163: v1(140.46,131.43) 139.83,131.43 131.95,123.56 118.87,123.56 117.22,121.91 117.22,118.1 111.63,112.51 111.63,96.38 110.74,95.49 110.74,91.56 109.73,90.54 109.73,88 106.78,85.05 106.78,82.38 106.05,81.65 106.05,79.01 v1(105.58,78.55)
USB1_DATA_N: length 36.2
  TOP w0.157: U16.27 104.68,111.12 104.57,111.01 104.57,110.13 v1(104.86,109.84) ; v1(105.58,82.55) 105.58,82.54 U37.AH7
  L5-SIGNAL w0.147: v1(105.58,82.55) 105.98,82.95 105.98,83.62 106.08,83.71 106.08,85.73 107.95,87.62 107.95,90.46 109.92,92.43 109.92,105.97 105.28,110.61 104.78,110.61 104.6,110.43 104.6,110.11 v1(104.86,109.84)
USB1_DATA_P: length 36.2
  TOP w0.157: U16.26 104.18,111.13 104.27,111.04 104.27,110.12 v1(103.99,109.84) ; v1(106.38,83.35) 106.38,83.34 U37.AJ6
  L5-SIGNAL w0.147: v1(106.38,83.35) 106.38,85.61 108.25,87.49 108.25,90.34 110.22,92.3 110.22,106.1 105.41,110.91 104.65,110.91 104.29,110.56 104.29,110.15 v1(103.99,109.84)
USB1_DM: length 2.8
  TOP w0.157: FL3.1 149.07,125.42 149.33,125.16 149.33,123.95 149.23,123.85 U11.14
USB1_DP: length 2.8
  TOP w0.157: U11.13 149.73,123.85 149.63,123.95 149.63,125.16 149.89,125.42 FL3.4
USB1_DRVVBUS: length 80.3
  TOP w0.191: v1(104.65,126.35) RJ1.3 ; R71.1 v1(105.28,106.92)
  TOP w0.229: v1(107.98,74.55) 107.98,74.54 U37.V4
  L4-SIGNAL w0.163: v1(105.28,106.92) 103,109.21 101.47,109.21 97.03,113.65 97.03,118.61 99.44,121.02 99.44,121.91 RJ1.3 v1(104.65,126.35)
  L5-SIGNAL w0.163: v1(117.6,105.78) 117.6,91.56 118.36,90.79 118.36,83.56 v1(115.06,80.25)
  L7-SIGNAL w0.107: v1(105.28,106.92) 116.46,106.92 v1(117.6,105.78)
  BOTTOM w0.163: v1(107.98,74.55) 108.39,74.95 108.39,75.18 108.38,75.18 108.38,75.51 108.61,75.75 108.62,75.75 108.62,75.75 110.55,75.75 110.55,75.76 110.82,75.76
  BOTTOM w0.191: v1(115.06,80.25) 114.55,79.75 114.55,77.84 112.47,75.76 110.82,75.76
USB1_HUB_D_N: length 32.6
  TOP w0.157: v1(112.59,116.24) 112.31,115.97 111.53,115.97 111.42,116.07 U16.42 ; U7.12 133.03,128.58 132.94,128.49 132.94,127.52 v1(133.1,127.37)
  L5-SIGNAL w0.147: v1(112.59,116.24) 112.78,116.04 113.15,116.04 116.15,119.05 116.15,122.54 118.69,125.08 128.27,125.08 131.55,128.36 132.77,128.36 133.1,128.03 v1(133.1,127.37)
USB1_HUB_D_P: length 32.6
  TOP w0.157: v1(112.59,115.37) 112.29,115.66 111.48,115.66 111.39,115.57 U16.41 ; U7.11 132.4,128.51 132.64,128.27 132.64,127.68 v1(132.33,127.37)
  L5-SIGNAL w0.147: v1(132.33,127.37) 132.51,127.37 132.79,127.65 132.79,127.9 132.64,128.06 131.67,128.06 128.4,124.78 118.82,124.78 116.46,122.42 116.46,118.93 113.27,115.74 112.95,115.74 v1(112.59,115.37)
USB1_HUB_PWRCLT1: length 26.6
  TOP w0.191: v1(128.14,125.72) 128.65,126.23 R26.1 128.65,127.4 128.27,127.78 Q1.2 ; v1(107.82,122.29) 107.68,122.14 U16.4
  L5-SIGNAL w0.163: v1(128.14,125.72) 118.36,125.72 115.7,123.05 108.58,123.05 v1(107.82,122.29)
USB1_ID: length 27.6
  TOP w0.191: v1(105.28,104.64) R75.1
  TOP w0.229: U37.AD7 105.58,79.34 v1(105.58,79.35)
  L5-SIGNAL w0.163: v1(105.58,79.35) 105.18,79.75 105.18,83.96 105.54,84.32 105.54,87.75 106.17,88.38 106.17,103.75 v1(105.28,104.64)
USB1_RCALIB: length 0.6
  TOP w0.229: v1(103.98,79.35) 103.58,78.95 U37.AD9
USB1_SS_RX1_N: length 65.7
  TOP w0.157: v1(101.58,82.55) 101.58,82.54 U37.AH12
  L4-SIGNAL w0.147: v1(126.48,133.85) 126.7,133.63 126.7,123.94 118.44,115.69 115.06,115.69 112.73,113.35 112.73,111.95 106.2,105.42 106.2,102.59 105.26,101.66 105.26,98.46 101.35,94.54 101.35,90.18 101.03,89.87 101.03,88.92 101.26,88.7 101.26,83.34 101.58,83.02 v1(101.58,82.55)
  BOTTOM w0.157: FL38.4 126.47,133.86 v1(126.48,133.85)
USB1_SS_RX1_P: length 65.8
  TOP w0.157: v1(102.38,83.35) 102.38,83.34 U37.AJ11
  L4-SIGNAL w0.147: v1(102.38,83.35) 102.13,83.1 101.93,83.1 101.56,83.46 101.56,88.82 101.34,89.05 101.34,89.75 101.65,90.06 101.65,94.41 105.57,98.33 105.57,101.53 106.5,102.47 106.5,105.3 113.03,111.83 113.03,113.22 115.19,115.38 118.57,115.38 127,123.81 127,133.61 v1(127.24,133.85)
  BOTTOM w0.157: v1(127.24,133.85) 127.28,133.89 FL38.1
USB1_SS_TX1_N: length 1.4
  BOTTOM w0.157: FL37.4 128.52,134.76 C496.2
USB1_SS_TX1_P: length 1.4
  BOTTOM w0.157: FL37.1 129.29,134.76 C495.2
USB1_VBUS_SOC: length 31.1
  TOP w0.191: 103.5,106.92 103.5,105.78 v1(102.74,105.78)
  TOP w0.229: v1(104.78,79.35) 104.78,79.34 U37.AD8
  L5-SIGNAL w0.163: v1(102.74,105.78) 103.63,104.89 103.63,104 105.82,101.82 105.82,88.66 105.11,87.95 104.75,87.95 104.38,87.58 104.38,79.75 v1(104.78,79.35)
USB2_DM: length 3.1
  TOP w0.157: FL1.4 133.12,137.3 132.87,137.05 132.87,135.73 133.03,135.56 U7.5
USB2_DP: length 3.1
  TOP w0.157: U7.6 132.4,135.56 132.56,135.73 132.56,137.05 132.31,137.3 FL1.1
VCAM_10V5: length 3.9
  TOP w0.305: 100.08,4.76 TP74.1 ; TP74.1 99.52,5.32 ; TP74.1 100.08,5.88
  L6-PWR w0.305: TP74.1 100.64,5.32 ; TP74.1 100.08,4.76 ; TP74.1 99.52,5.32 ; TP74.1 100.08,5.88
  vias: v2(27.05,8.24) v2(27.05,6.72) v2(43.69,8.24) v2(43.69,6.72) v2(60.33,8.24) v2(60.33,6.72) v2(76.96,8.24) v2(76.96,6.72) v3(99.44,4.56) v3(99.69,6.34)
VCAM_VDD18: length 15.4
  BOTTOM w0.254: v2(59.56,22.21) 59.75,22.4 U74.1 ; U74.2 v2(59.49,22.9) ; U74.48 69.79,22.4 v2(69.98,22.21) ; U74.47 v2(70.03,22.9)
  BOTTOM w0.305: R428.1 75.56,25.26 75.56,23.99 76.07,23.48 76.07,22.47 R440.1 74.04,20.44 71.75,20.44 v2(69.98,22.21)
  vias: v2(59.44,20.56) v2(59.94,21.33)
VCAM_VDD18_FPD: length 9.9
  TOP w0.254: v2(61.02,21) 60.96,21.06 C417.1 ; C419.1 64.01,21.02 v2(64.02,21) ; C420.1 65.53,21.02 v2(65.52,21) ; v2(68.52,21) 68.45,21.07 C422.1
  L2-SIGNAL w0.508: v2(68.52,21) 67.83,20.31 66.22,20.31 v2(65.52,21)
  BOTTOM w0.254: U74.64 v2(61.02,21) ; U74.55 v2(65.52,21) ; U74.58 v2(64.02,21) ; U74.49 v2(68.52,21)
VCAM_VDD_CSI: length 3.4
  BOTTOM w0.254: v2(62.99,31.36) 63.02,31.33 U74.21 ; U74.33 69.92,29.9 v2(69.98,29.96)
  BOTTOM w0.305: C800.1 v2(69.98,29.96) ; C791.1 62.87,31.49 v2(62.99,31.36)
VCAM_VDD_FPD: length 8.4
  TOP w0.254: v2(62.52,21) 62.61,21.1 C418.1 ; C421.1 67.06,21.04 v2(67.02,21)
  L2-SIGNAL w0.508: v2(62.52,21) 63.35,21.83 66.19,21.83 v2(67.02,21)
  BOTTOM w0.254: U74.52 v2(67.02,21) ; U74.61 v2(62.52,21)
VCAM_VDDA18: length 1.6
  BOTTOM w0.254: U74.32 v2(68.52,31.3)
  BOTTOM w0.305: v2(68.52,31.3) 68.83,31.61 C792.1
VCAM_VDDL: length 15.8
  L2-SIGNAL w0.508: v2(69.95,24.4) 69.5,24.85 69.5,25.49 68.2,26.79 61.21,26.79 v2(59.6,28.4)
  BOTTOM w0.254: U74.13 v2(59.6,28.4) ; U74.44 v2(69.95,24.4)
  BOTTOM w0.305: v2(59.6,28.4) 59.18,28.82 C802.1 ; C803.1 70.18,24.63 v2(69.95,24.4)
VCAP_MCU_VDDS0: length 0.6
  TOP w0.305: v1(91.98,67.35) 92.38,67.75 U37.K23
VCAP_MCU_VDDS1: length 0.6
  TOP w0.305: U37.J18 96.38,66.95 v1(95.98,66.55)
VCAP_MCU_VDDS2: length 0.6
  TOP w0.305: U37.J19 95.58,66.95 v1(95.18,66.55)
VCAP_VDDS0: length 0.6
  TOP w0.305: U37.U7 105.18,73.35 v1(105.58,73.75)
VCAP_VDDS1: length 0.6
  TOP w0.305: v1(93.58,77.75) 93.98,77.35 U37.AB21
VCAP_VDDS2: length 0.6
  TOP w0.305: U37.Y18 96.38,75.75 v1(95.98,76.15)
VCAP_VDDS3: length 0.6
  TOP w0.305: U37.W21 v1(93.58,75.35)
VCAP_VDDS4: length 0.6
  TOP w0.305: v1(92.78,76.95) 93.18,76.55 U37.AA22
VCAP_VDDS5: length 0.6
  TOP w0.305: v1(92.78,71.35) 93.18,71.75 U37.R22
VCAP_VDDS6: length 0.6
  TOP w0.305: v1(92.78,74.55) 93.18,74.15 U37.V22
VDA_DLL_0V8: length 29.5
  TOP w0.305: U27.9 v1(130.69,102.1) 130.69,102.68 130.81,102.79 C137.1
  L4-SIGNAL w0.508: v2(113.54,94.1) 115.57,94.1 117.35,95.87 117.35,100.32 120.37,103.34 120.37,104.26 120.88,104.76 125.6,104.76 127.38,106.54 130.64,106.54 131.65,105.53 v2(131.65,104.89)
  vias: v1(112.13,53.08)
VDA_MCU_1V8: length 8.2
  TOP w0.305: v1(92.78,70.55) 93.18,70.95 U37.P22 ; v1(92.78,65.75) 93.17,66.14 U37.H22 93.18,66.15 ; U37.N22 93.18,70.15 v1(92.78,69.75) ; v1(95.98,64.95) 96.38,65.35 U37.G18 ; U27.7 v1(131.69,102.1) 131.7,102.1 131.7,102.89 C138.1 ; U37.M23 92.38,69.35 v1(91.98,68.95) ; U37.P21 93.98,70.95 v1(93.58,70.55)
  BOTTOM w0.305: R290.2 135.51,101.21 v2(135.25,101.46) ; R381.2 v2(77.6,55.49)
  vias: v2(61.98,71.11) v2(62.99,71.11) v2(64.39,71.54) v2(65.79,71.11) v2(66.8,71.11) v2(68.07,71.54) v2(73.03,38.34) v2(74.17,38.34) v2(75.18,38.34)
VDA_PLL_1V8: length 8.1
  TOP w0.305: U20.7 v1(81.28,106.17) 81.28,106.16 82.07,106.16 C121.1 ; v1(103.98,70.55) 103.58,70.95 U37.P9 ; v1(96.78,68.95) 97.18,69.35 U37.M17 ; v1(101.58,71.35) 101.98,71.75 U37.R11 ; v1(96.78,75.35) 97.18,74.95 U37.W17 97.18,74.95 ; U37.R21 93.98,71.75 v1(93.58,71.35) ; U37.Y20 v1(94.38,76.15) ; U37.W15 98.78,74.95 v1(98.38,75.35) ; U37.L12 v1(101.58,68.15) ; U37.W18 96.38,74.95 v1(95.98,75.35) ; U37.H9 v1(103.98,65.75)
  vias: v1(90.3,96.13)
VDA_USB_3V3: length 2.7
  TOP w0.305: v1(103.18,77.75) 102.78,77.35 U37.AB10 ; C114.1 82.22,108.37 82.01,108.17 v1(81.28,108.17) U20.11
  vias: v2(93.9,96.13)
VEXP_1V8A: length 1.8
  BOTTOM w0.305: R376.2 4.01,57.27 4.1,57.18 J21.113
VEXP_1V8B: length 1.9
  BOTTOM w0.305: R380.2 3.75,56.58 J21.112
VEXP_3V3A: length 5.7
  BOTTOM w0.254: J21.8 13.37,57.18 13.53,57.33 15.05,57.33 R379.1
VEXP_3V3B: length 5.8
  BOTTOM w0.254: J21.9 11.99,56.58 13.25,55.32 15.28,55.32 15.32,55.36 R382.1
VEXP_5V0A: length 6.1
  BOTTOM w0.305: R355.1 12.45,65.45 12.06,65.06 12.06,61.71 11.72,61.37 J21.1
VEXP_5V0B: length 9.3
  BOTTOM w0.305: J21.5 12.25,58.97 12.7,59.43 12.7,64.38 13.59,65.27 R354.1
VEXP_5V0C: length 1.9
  BOTTOM w0.305: J21.117 3.66,59.57 R370.2
VEXP_5V0D: length 1.8
  BOTTOM w0.305: R375.2 3.61,58.97 J21.116
VIO_3V3_SD: length 4.3
  TOP w0.191: 19.83,81.27 v1(19.82,81.28) ; 19.7,72.13 v1(19.69,72.13) ; 19.7,76.7 v1(19.69,76.71)
  BOTTOM w0.191: U70.1 v1(19.82,81.28) ; U72.1 v1(19.69,72.13) ; U71.1 v1(19.69,76.71)
  BOTTOM w0.305: P5.4 v2(17.77,80.52)
VIO_3V3USB: length 21.7
  TOP w0.305: v2(106.43,121.91) 106.18,121.66 U16.7 ; U16.23 101.07,114.07 v2(100.84,113.84) ; U16.40 111.96,115.07 v2(111.98,115.05) ; U16.48 v2(111.97,119.07) ; U16.37 v2(111.97,113.57) ; U16.25 103.68,110.82 v2(103.76,110.73) ; U16.13 v2(100.76,119.07) ; v2(107.19,110.73) 107.68,111.22 U16.33
  TOP w0.406: v2(98.3,116.96) 97.79,116.96 C97.1 97.79,117.72 v2(98.3,117.72) ; 97.41,115.43 97.92,115.94 v2(98.3,115.94) ; 97.41,115.43 FL5.1 ; 97.41,115.43 97.92,114.92 v2(98.3,114.92)
  BOTTOM w0.305: v2(111.98,115.05) 111.25,115.05 C523.1 ; v2(106.43,121.91) C507.1 ; v2(100.84,113.84) 100.9,113.78 C524.1 ; v2(103.76,110.73) 103.89,110.86 C534.1 ; v2(100.76,119.07) 101.39,119.07 C512.1 ; v2(111.97,113.57) 111.33,113.57 C526.1 ; C511.1 111.3,119.07 v2(111.97,119.07) ; v2(107.19,110.73) C532.1
VMIC_BIAS: length 26.4
  TOP w0.305: R53.1 v2(19.68,118.61) 19.68,120 ; 19.67,139.07 19.67,139.05 ; 19.67,139.05 R7.2 ; 19.67,139.05 v2(19.67,137.67) 19.67,136.91 R10.1 ; R79.1 v2(19.68,99.56) R76.2 ; v2(19.67,128.27) 20.43,128.27 C63.1 ; v2(19.67,141.61) 20.43,141.61 C10.1 ; 19.67,132.72 19.67,132.7 ; 19.67,132.7 R13.2 ; 19.67,132.7 v2(19.67,131.32) 19.67,130.56 R22.1 ; R57.2 v2(19.68,112.26) R66.1 ; 10.47,75.98 10.02,76.43 U34.16 ; R96.2 v2(19.68,93.21) R102.1 ; C143.1 v2(19.68,103.49) ; C112.1 v2(19.68,109.21) ; C78.1 v2(19.68,122.54) ; C202.1 v2(19.68,90.16)
  TOP w0.508: C272.1 TP41.1
  TOP w0.635: 10.47,75.98 12.11,75.98 C272.1 12.19,74.79 11.68,74.28 R138.1
  L5-SIGNAL w0.305: 14.1,76.62 TP41.1 14.66,76.06
VMON_VEXT: length 28.6
  TOP w0.229: U37.V19 v1(95.18,74.55)
  L5-SIGNAL w0.163: v1(95.18,74.55) 94.78,74.95 93.32,74.95 93.17,75.09 93.17,75.51 92.94,75.75 92.52,75.75 92.37,75.89 92.37,76.31 92.14,76.55 91.21,76.55 89.53,78.22 88.27,78.22 87.76,77.71 84.96,77.71 83.57,79.11 70.99,79.11 v1(70.23,79.87)
VMON_VSYS: length 11.1
  TOP w0.305: R145.1 82.33,67.99 82.35,67.97 R144.2 C297.1 83.05,67.16 v2(83.06,67.17) ; v1(89.58,68.95) 89.98,69.35 U37.M26
  L5-SIGNAL w0.127: 86.71,68.54 89.17,68.54 v1(89.58,68.95)
  L5-SIGNAL w0.305: 86.71,68.54 86.2,68.54 84.84,67.17 v2(83.06,67.17)
VOSNS: length 6.2
  TOP w0.305: U46.12 193.43,55.62 194.94,57.14 C320.2 R168.2
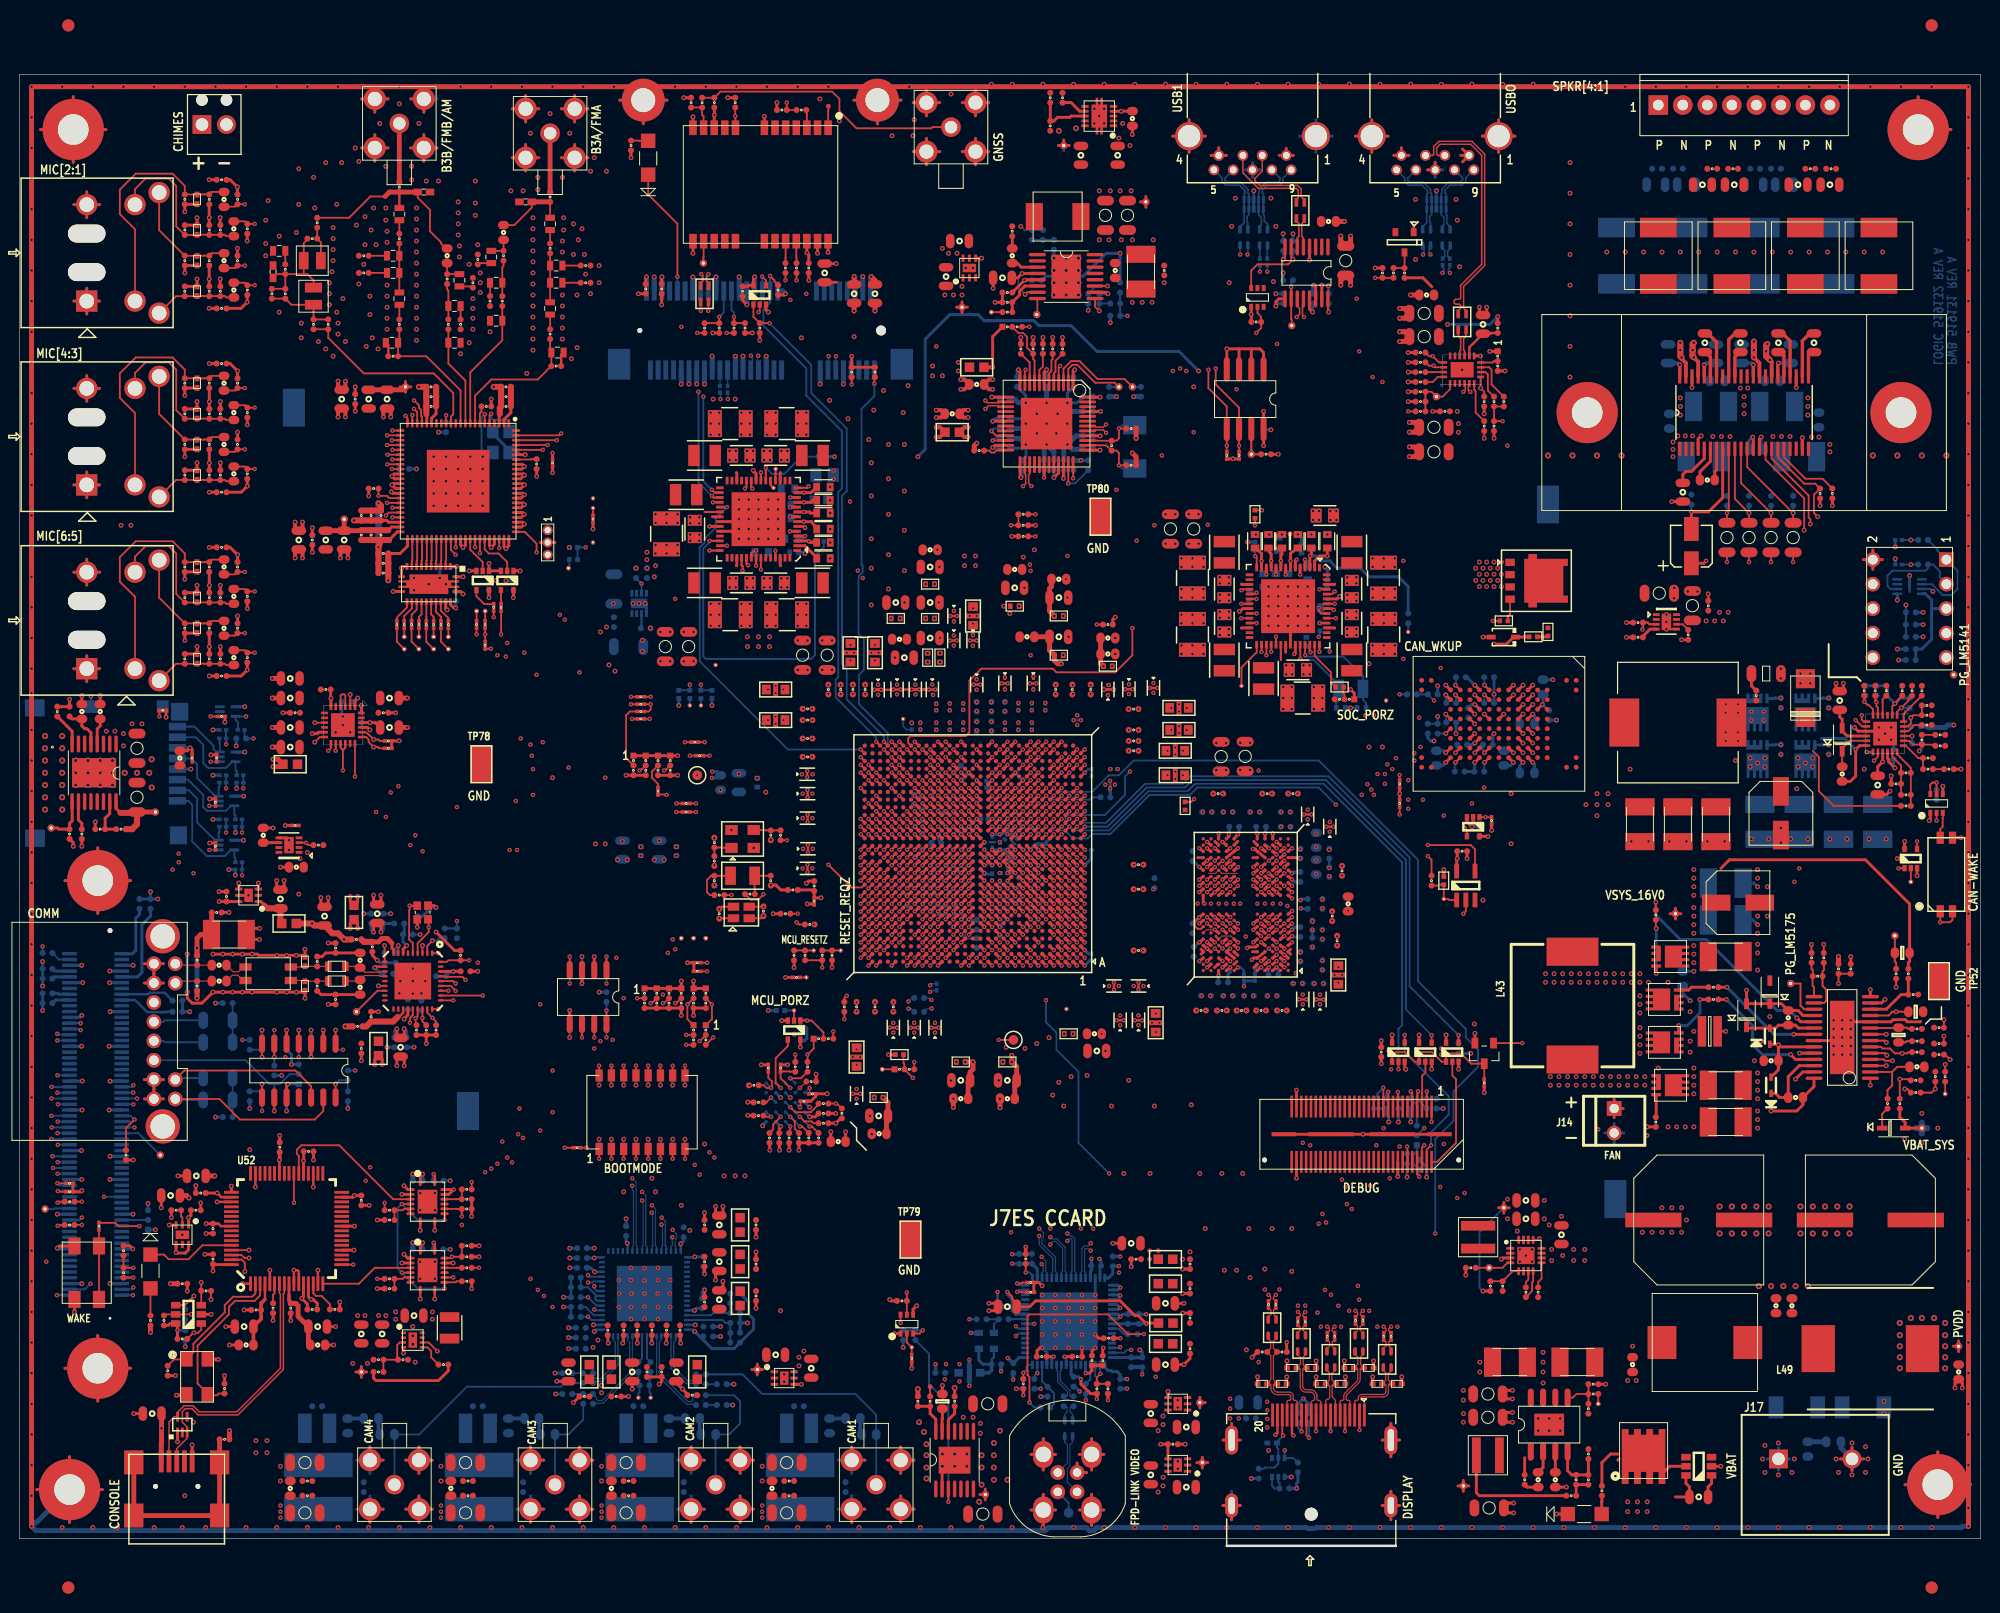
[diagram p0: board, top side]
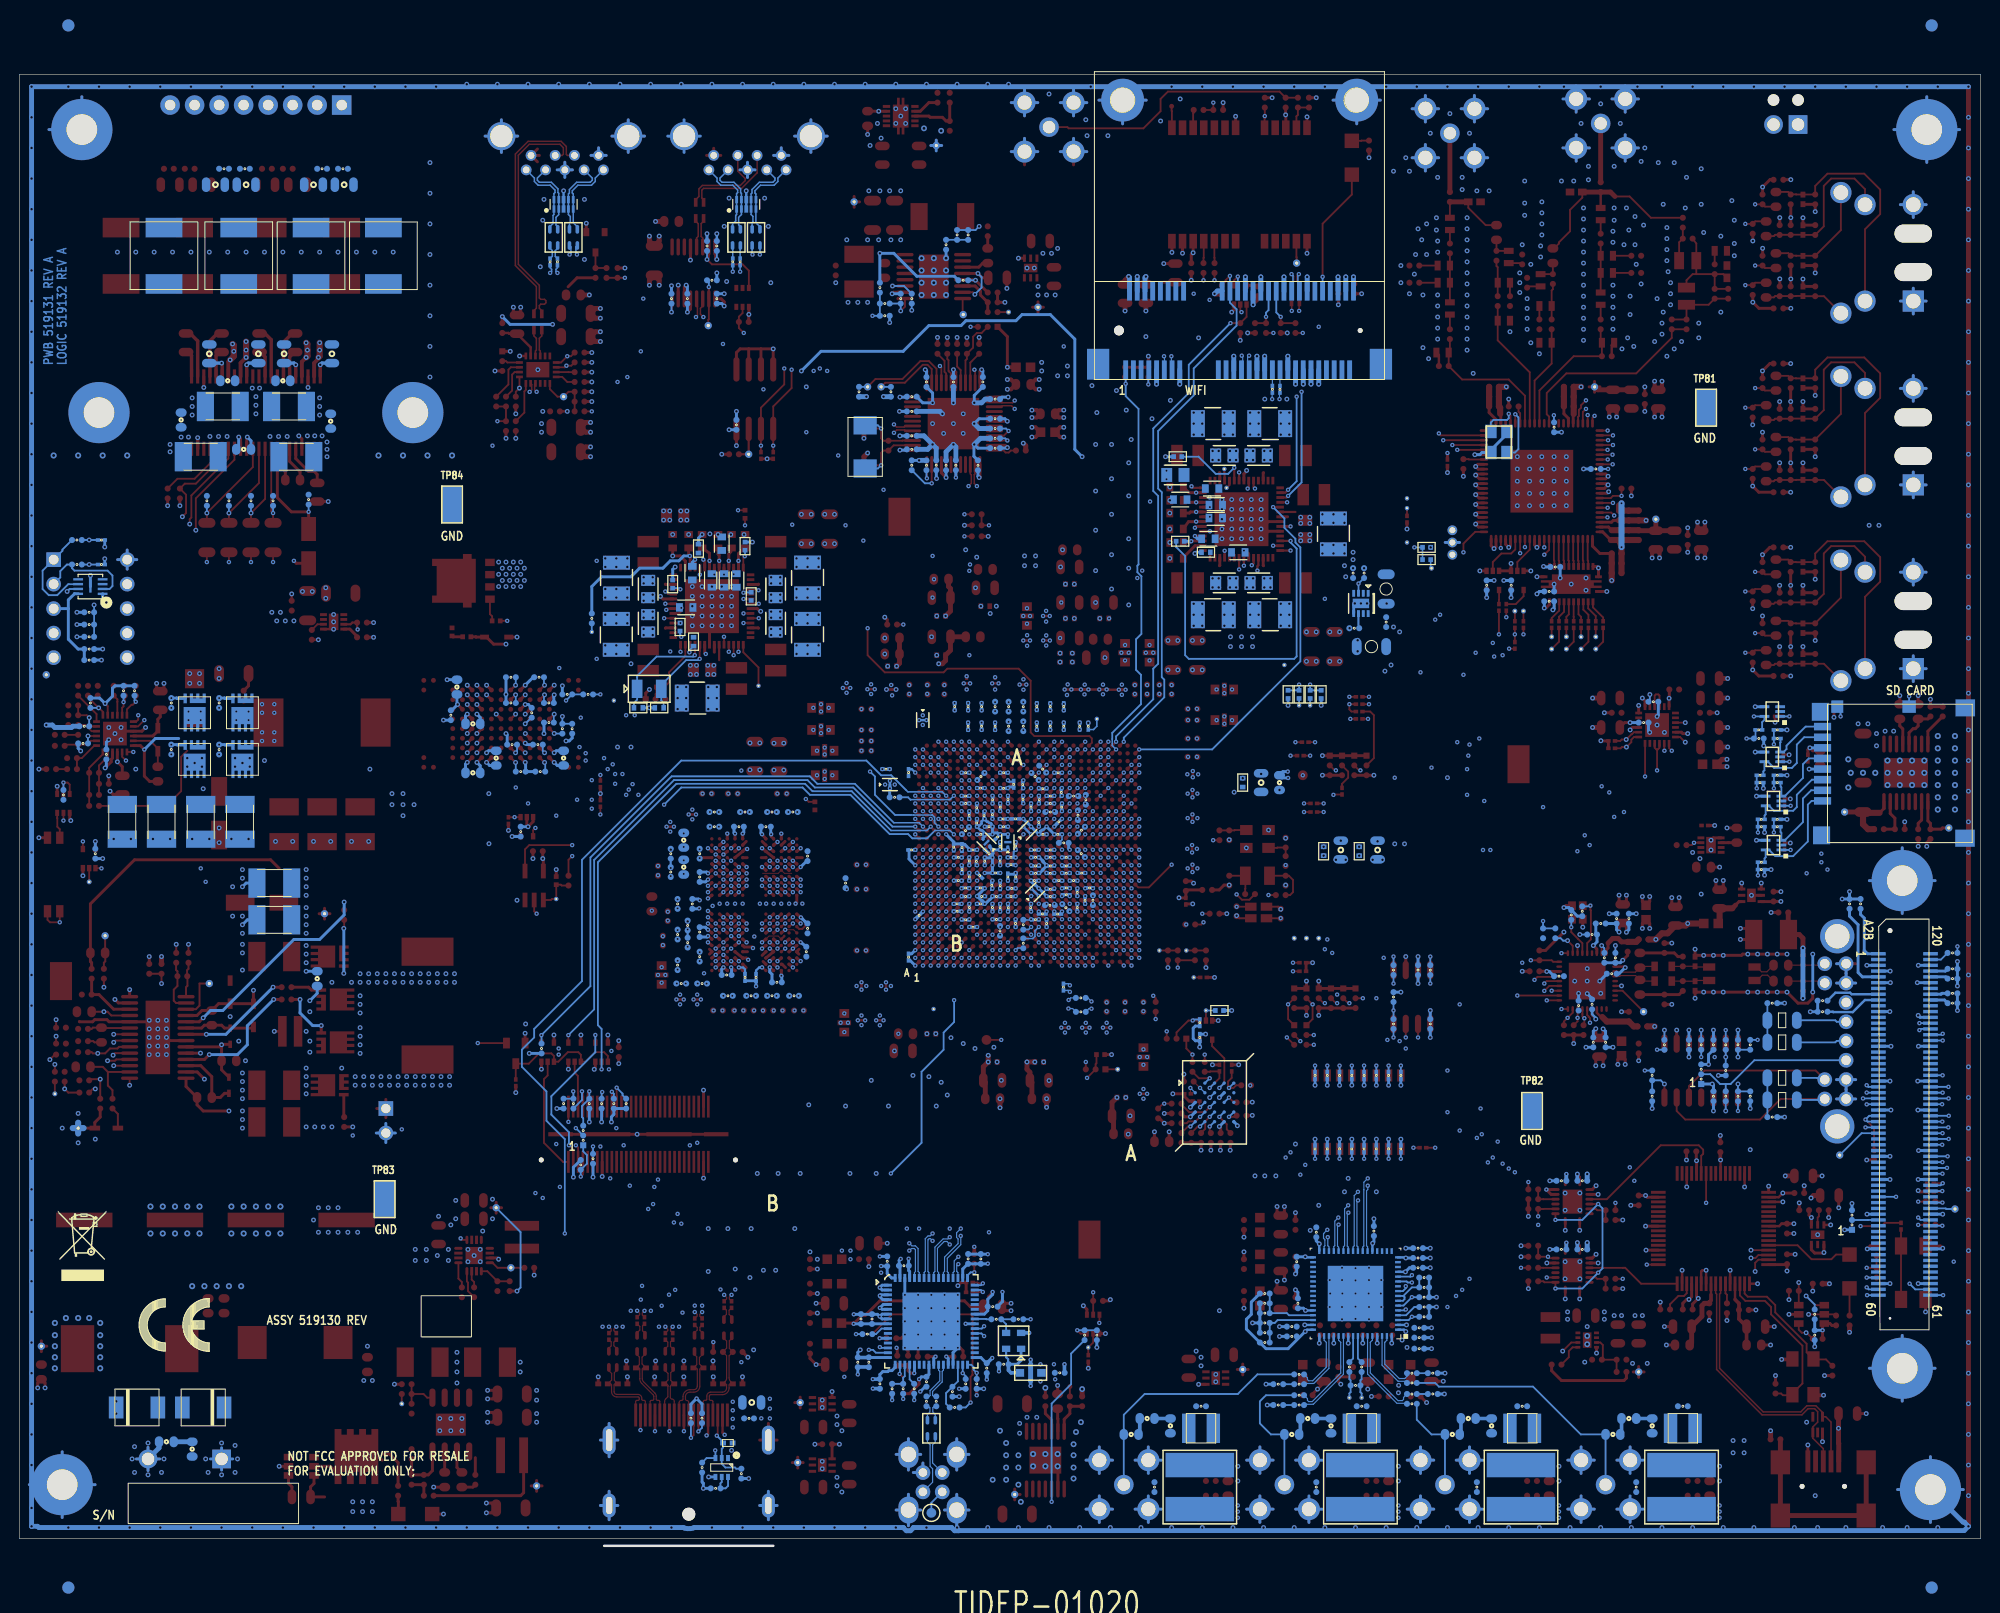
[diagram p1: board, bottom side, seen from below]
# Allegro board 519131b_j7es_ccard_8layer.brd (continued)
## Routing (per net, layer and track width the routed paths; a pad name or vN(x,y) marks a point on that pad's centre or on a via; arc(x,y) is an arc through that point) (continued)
VPCIE0_1V5: length 9.9
  TOP w0.305: 107.64,145.15 TP2.1 ; TP2.1 108.76,145.15 ; TP2.1 108.2,145.71 ; C52.1 66.55,131.5 v2(66.58,131.53)
  TOP w0.508: C58.1 v2(86.49,131.56)
  BOTTOM w0.305: 108.2,144.59 TP2.1 ; TP2.1 108.2,145.71 ; TP2.1 108.76,145.15 ; TP2.1 107.64,145.15
  BOTTOM w0.508: v2(86.49,131.56) 86.58,131.47 J20.6 ; J20.48 v2(66.58,131.53) ; J20.28 v2(74.58,131.53)
  vias: v3(107.7,146.67) v3(109.47,146.93)
VPHY_USART: length 6.8
  TOP w0.254: 25.45,25.53 U52.4
  TOP w0.381: L47.1 C415.1 25.04,23.51 C408.1 25.04,25.13 25.45,25.53
VPLL_USART: length 7.6
  TOP w0.254: 27.94,26.02 U52.9
  TOP w0.381: 27.94,26.02 27.94,25.44 28.12,25.26 C406.1
  TOP w0.508: L48.1 29.95,21.02 C416.1 28.88,23.79 28.88,24.89 28.64,25.14 C406.1
VPP_EFUSE_1V8: length 21.8
  TOP w0.305: v1(96.78,64.15) 97.18,64.55 U37.F17 ; U37.AB11 101.98,77.35 v1(102.38,77.75)
  L5-SIGNAL w0.127: 97.96,65.35 97.28,65.35 97.16,65.22 97.16,64.79 97.16,64.78 97.16,64.52 v1(96.78,64.15)
  L5-SIGNAL w0.152: 97.96,65.35 103.34,65.35 103.58,65.58 103.58,75.99 103.57,75.99 103.57,76.31 103.34,76.54 103.02,76.54 102.77,76.79 102.77,77.36 v1(102.38,77.75)
  vias: v1(114.96,89.3) v1(114.96,88.29) v1(117.5,89.43) v1(117.5,88.42)
VRTC_LEOA_1V8: length 16.4
  TOP w0.305: U27.3 133.69,102.57 v1(133.73,102.61) 133.86,102.73 C139.1
  BOTTOM w0.305: v1(133.73,102.61) 134.37,102.61 134.87,102.1 135.76,102.1 136.53,101.34 138.94,101.34 139.83,100.45 142.88,100.45 143.89,99.43 R293.2
VRTC_LEOB_1V8: length 2.8
  TOP w0.305: U20.3 81.75,104.17 v1(81.79,104.13) 81.92,104 C141.1
  BOTTOM w0.305: R283.1 v1(81.79,104.13)
VSYS_3V3: length 109.6
  TOP w0.305: R125.2 v2(201.17,80.51) ; U38.5 195.31,73 v2(195.33,73.01) ; 168.16,94.17 168.16,94.23 168.95,95.02 U28.4 ; U47.5 v2(142.22,52.95) ; R127.2 v2(193.93,79.81) ; U57.4 v2(39.8,19.98) ; R224.2 v2(149.86,28.06) ; R144.1 81.77,68.9 v2(81.55,68.68) ; U48.5 v2(145.02,52.95) ; C348.1 v2(141.1,52.36) ; U49.5 v2(147.81,52.95) ; R191.1 v2(151.76,46.98)
  L4-SIGNAL w0.305: v2(201.17,80.51) 199.28,82.39 v2(196.84,82.39) 194.92,82.39 193.42,80.89 193.42,80.32 v2(193.93,79.81) 192.6,78.48 v2(184.15,78.48) ; v2(70.99,41.65) 70.99,38.72 78.87,30.85 v2(78.87,24.37)
  L5-SIGNAL w0.305: v2(70.99,41.65) 70.99,55.36 69.22,57.14 69.22,59.3 69.98,60.06 69.98,61.2 70.48,61.71 70.48,65.27 74.3,69.08 79.12,69.08 79.52,68.68 v2(81.55,68.68)
  L5-SIGNAL w0.508: v2(141.1,52.36) 141.63,52.36 v2(142.22,52.95) 142.86,53.58 143.75,53.58 144.38,52.95 v2(145.02,52.95) 145.65,53.58 146.54,53.58 147.18,52.95 v2(147.81,52.95) 148.96,54.09 v2(150.75,54.09)
  L7-SIGNAL w0.305: v2(193.93,79.81) 195.33,78.41 v2(195.33,73.01)
  BOTTOM w0.305: R323.2 197.1,82.67 196.85,82.41 196.85,82.4 v2(196.84,82.39) ; C681.1 v2(195.33,73.01)
  vias: v2(42.8,24.25) v2(42.8,23.48) v2(158.75,30.72) v2(158.75,29.58) v2(159.89,30.09) v2(161.04,30.72) v2(161.04,29.58) v2(162.18,30.72) v2(162.18,29.58) v2(162.31,76.82) v2(163.45,77.97) v2(163.45,76.82) v2(163.45,75.68) v2(164.59,77.97) v2(164.59,76.82)
VSYS_5V0: length 217.8
  TOP w0.305: TP68.1 35.43,18.58 ; TP68.1 35.43,17.46 ; TP68.1 34.87,18.02 ; TP68.1 35.99,18.02 ; U33.16 193.54,81.65 193.68,81.52 193.68,81.27 v2(194.31,80.63) ; R245.2 44.45,18.15 43.43,17.13 36.96,17.13 36.7,17.39 36.7,18.02 ; U50.3 v2(30.23,50.66) ; U44.3 v2(58.29,58.28)
  L2-SIGNAL w0.305: 35.43,17.46 TP68.1 ; TP68.1 34.87,18.02 ; TP68.1 35.43,18.58 ; TP68.1 35.99,18.02
  L4-SIGNAL w0.508: v2(30.23,50.66) 30.84,51.27 30.84,62.5 28.96,64.38 v2(28.96,67.55)
  L4-SIGNAL w1.016: v2(194.31,80.63) 195.58,80.63 199.9,76.32 199.9,72.45 200.41,71.94 200.41,64 199.64,63.24 197.74,63.24 194.31,66.66 179.2,66.66 174.5,71.36 166.88,71.36 154.43,58.92 154.43,50.03 163.7,40.76 163.7,20.18 165.48,18.4 165.48,14.47 160.27,9.26 153.8,9.26 152.53,7.99 132.16,7.99 132.15,8 131.43,8 131.42,7.99 124.21,7.99 123.44,7.23 121.67,7.23 121.28,6.85
  L7-SIGNAL w0.305: TP68.1 35.43,18.58 ; TP68.1 35.43,17.46 ; TP68.1 34.87,18.02 ; TP68.1 35.99,18.02
  BOTTOM w0.305: R354.2 v2(13.59,67.81) ; R354.2 R355.2 ; R354.2 v2(14.35,67.05) ; v2(2.41,60.57) R370.1 R375.1 v2(2.41,58.03) ; v2(58.29,58.28) C765.1 ; C785.1 v2(30.23,50.66) ; v2(194.31,80.63) 194.18,80.76 C607.1
  vias: v2(24.51,10.91) v2(24.51,9.64) v2(25.65,10.91) v2(25.65,9.64) v2(34.54,18.91) v2(36.07,18.91) v2(117.98,5.58) v2(118.49,7.1) v2(118.49,6.21)
VSYS_10V5: length 76.5
  TOP w0.305: 149.05,6.21 TP73.1 ; TP73.1 149.61,6.77 ; TP73.1 149.61,5.65 ; TP73.1 150.17,6.21 ; U46.24 v2(184.43,51.07) ; L50.2 150.95,5.5 151.26,5.2 R261.2
  L5-SIGNAL w0.508: v2(149.61,16.12) 149.61,18.53 155.07,23.99 158.37,23.99 164.59,30.22 164.59,32.63 170.43,38.47 179.07,38.47 185.42,44.82 185.42,50.08 v2(184.43,51.07)
  L6-PWR w0.305: 149.05,6.21 TP73.1 ; TP73.1 149.61,6.77 ; TP73.1 150.17,6.21 ; TP73.1 149.61,5.65
  vias: v2(9.02,84.44) v2(9.91,84.44) v2(10.79,84.19) v2(10.79,82.92) v2(11.68,85.21) v2(12.7,85.21) v2(97.79,13.32) v2(98.81,13.32) v2(99.57,12.69) v2(99.57,11.67) v2(149.61,15.1) v2(149.61,13.71) v2(149.61,12.82)
VSYS_16V0: length 36.7
  TOP w0.305: 171.02,65.52 TP44.1 ; TP44.1 172.14,65.52 ; TP44.1 171.58,66.08 ; TP44.1 171.58,64.96 ; 176.28,70.22 177.16,71.11 191.26,71.11 195.83,66.54 R153.2 195.83,60.57 195.71,60.44 195.71,59.81 ; R247.1 v2(164.34,16.75)
  L5-SIGNAL w0.305: TP44.1 172.14,65.52 ; TP44.1 171.58,66.08 ; TP44.1 171.58,64.96
  L6-PWR w0.305: 171.02,65.52 TP44.1 ; TP44.1 171.58,66.08 ; TP44.1 172.14,65.52 ; TP44.1 171.58,64.96
  BOTTOM w0.305: C769.2 v2(173.48,59.55)
  vias: v2(115.32,128.89) v2(116.33,128.89) v2(117.35,128.89) v2(118.62,130.93) v2(157.86,20.06) v2(157.86,19.04) v2(157.86,18.02) v2(157.86,16.88) v2(173.48,70.09) v2(173.48,69.2) v2(173.48,68.32) v2(173.48,67.43) v2(173.48,66.16) v2(173.48,65.27) v2(173.48,64.38) v2(173.48,63.49) v2(173.48,62.22) v2(173.48,61.33) v2(173.48,60.44)
VSYS_IO_1V8: length 21.7
  TOP w0.305: U6.4 v2(99.69,133.47) ; TP62.1 154.36,35.04 ; TP62.1 153.8,34.48 ; TP62.1 153.24,35.04 ; TP62.1 153.8,35.6 ; U58.4 v2(81.03,16.74) ; 30.35,103.75 v2(30.35,102.99) ; U59.4 v2(119,15.99) ; R229.2 v2(151.64,26.41)
  TOP w0.406: v2(29.34,102.4) 29.34,102.91 C132.1 28.57,102.91 v2(28.57,102.4)
  L4-SIGNAL w0.305: TP62.1 154.36,35.04 ; TP62.1 153.24,35.04 ; TP62.1 153.8,34.48 ; TP62.1 153.8,35.6
  BOTTOM w0.191: TP62.1 151.27,32.51 151.27,26.77 v2(151.64,26.41)
  BOTTOM w0.305: v2(2.41,55.49) R380.1 R376.1
  vias: v2(10.54,105.78) v2(11.56,105.78) v2(60.3,16.64) v2(60.33,15.86) v2(80.77,19.55) v2(80.77,18.66) v2(81.28,20.18) v2(95.63,134.48) v2(96.27,133.97) v2(97.16,133.97) v2(113.92,145.91) v2(114.3,147.44) v2(115.06,145.15) v2(117.98,11.93) v2(118.49,13.45) v2(118.49,12.56) v2(120.52,29.71) v2(121.28,30.47) v2(154.18,35.93) v2(154.18,33.9) v2(155.19,32.63)
VSYS_SENSE: length 23.8
  TOP w0.305: v2(152.78,93.46) 154.06,93.46 154.8,94.19 D6.1 155.87,94.19 155.9,94.22 R99.2 ; U27.51 136.51,98.15 v2(136.78,98.41)
  L5-SIGNAL w0.305: v2(136.78,98.41) 136.78,97.89 137.27,97.4 146.18,97.4 150.11,93.46 v2(152.78,93.46)
VTUN_1V8: length 9.1
  TOP w0.305: 38.23,105.27 38.56,105.6 U19.43
  TOP w0.508: C134.1 35.38,105.22 C125.1 ; C134.1 L31.2 ; C134.1 TP18.1
  TOP w0.635: 38.23,105.27 C127.1 C126.1 C125.1
VTUN_3V3: length 17.6
  TOP w0.305: TP9.1 40.01,120.69 ; TP9.1 39.45,120.13 ; TP9.1 40.56,120.13 ; TP9.1 40.01,119.57 ; U19.18 42.22,117.26 42.16,117.31 ; 49.78,117.34 49.72,117.27 U19.3
  TOP w0.508: L27.2 C89.1 39.67,119.83 TP9.1
  TOP w0.635: 42.16,117.31 C91.2 C85.2 C83.2 v2(41.4,120.13) ; 49.78,117.34 49.78,117.97 49.91,118.1 49.91,120.13 v2(49.15,120.13)
  L4-SIGNAL w0.305: 39.45,120.13 TP9.1 ; TP9.1 40.56,120.13 ; TP9.1 40.01,120.69 ; TP9.1 40.01,119.57
VUSART_1V8: length 9.5
  TOP w0.305: v2(20.07,28.49) C387.1 20.12,29.15 U52.64 ; U52.49 v2(21.97,37.28) ; U52.12 29.44,25.82 v2(29.26,25.64) 29.84,25.06 29.84,24.5 ; C368.1 29.46,39.94 v2(29.44,39.92) U52.37
  TOP w0.508: v2(20.24,38.34) C369.1
VUSART_3V3: length 26.3
  TOP w0.254: 41.54,37.71 41.54,38.23 41.78,38.47 v2(41.78,38.53) ; v2(26.95,39.99) U52.42 ; U52.56 20.88,33.14 20.62,33.39 ; v2(41.78,31.42) 41.78,31.36 41.54,31.12 U55.1 ; v2(20.5,36.57) 20.93,36.13 U52.50
  TOP w0.305: U51.2 40.25,36.93 v2(39.85,37.33) ; U52.20 v2(34.67,30.65) ; U53.1 v2(17.54,34.03) 17.78,34.26 C375.1 ; L47.2 v2(21.77,20.82) ; v2(19.35,33.39) C382.1 20.62,33.39 ; v2(39.85,30.22) 40.25,29.82 U55.2 ; C372.1 v2(34.72,36.31) 34.54,36.13 U52.31 ; v2(33.2,25.26) R236.1 ; L48.2 v2(32.56,20.82) ; v2(20.5,36.57) C370.1 ; R238.2 15.43,22.85 15.62,23.04 U56.6 16.23,23.04 16.38,22.89 v1(16.38,22.34) R239.2
  TOP w0.381: C367.1 26.97,40.02 v2(26.95,39.99)
  TOP w0.508: C371.1 17.32,36.31 v2(17.58,36.06)
  BOTTOM w0.305: v1(16.38,22.34) C811.1 R432.2
  BOTTOM w0.381: C795.1 v2(41.78,31.42) ; C790.1 v2(41.78,38.53)
VUSART_VBUS: length 10.2
  TOP w0.305: U60.1 v2(16.39,10.79) ; U53.4 v2(16.24,30.4) 16.3,30.34 17.2,30.34 17.54,30.69 U53.6
  TOP w0.508: R237.1 v2(13.59,22.14) ; C393.1 v2(15.67,27.17) ; C456.1 v2(14.73,12.18) 14.73,10.66 14.71,10.63 J19.1
VUSB_5V0: length 24.8
  TOP w0.305: 116.71,138.75 TP3.1 ; TP3.1 116.71,139.87 ; TP3.1 116.15,139.31 ; v2(134.11,130.67) 134.3,130.48 U7.14 ; R48.1 v2(151.76,117.34) ; U7.15 v2(134.94,130.67)
  TOP w0.508: v2(137.92,130.67) 137.92,131.18 C37.1 136.91,131.18 v2(136.91,130.67)
  L5-SIGNAL w0.305: 116.15,139.31 TP3.1 ; TP3.1 116.71,139.87 ; TP3.1 116.71,138.75 ; TP3.1 117.27,139.31
  BOTTOM w0.305: R268.1 v2(114.05,133.97) 112.6,133.97 110.22,131.59 106.33,131.59 R267.2 ; v2(134.11,130.67) 133.99,130.55 C497.1 ; C499.2 v2(113.03,126.8) ; 131.95,135.24 v2(131.95,136.01)
  vias: v2(111.89,140.45) v2(113.03,140.45) v2(114.05,140.45) v2(115.19,140.45) v2(148.97,117.59) v2(149.1,116.32) v2(149.1,115.43)
VUSB_IO_1V1: length 2.2
  TOP w0.305: TP5.1 97.66,128.95 ; TP5.1 98.22,128.39 ; TP5.1 97.66,127.83 ; TP5.1 97.1,128.39
  vias: v2(95.89,129.66) v2(96.77,129.66) v2(97.28,122.67) v2(97.28,121.78) v2(97.66,130.55) v2(97.66,129.66)
WKUP_GPIO0_30: length 18.8
  TOP w0.191: RJ16.1 82.3,51.55 v1(81.66,50.92) R186.1
  TOP w0.229: U37.A23 91.98,60.14 v1(91.98,60.14)
  L2-SIGNAL w0.107: v1(81.66,50.92) 83.19,52.44 86.74,52.44 89.41,55.11 89.41,57.21 91.98,59.78 v1(91.98,60.14)
WKUP_LFOSC_XI: length 14.9
  TOP w0.191: R146.1 75.77,66.97 76.54,66.97 v1(77.09,67.52)
  TOP w0.229: U37.N28 88.38,70.15 v1(87.98,69.75)
  L5-SIGNAL w0.163: v1(87.98,69.75) 87.57,69.34 85.74,69.34 84.2,67.81 82.93,67.81 82.42,67.3 77.74,67.3 77.51,67.52 v1(77.09,67.52)
WKUP_LFOSC_XO: length 18.5
  TOP w0.191: v1(73.79,67.46) 73.78,67.45 R147.1
  TOP w0.229: U37.N26 89.58,69.75 v1(89.58,69.75)
  L5-SIGNAL w0.163: v1(89.58,69.75) 89.18,70.14 85.9,70.14 84.07,68.32 82.93,68.32 82.37,67.76 78.94,67.76 78.77,67.93 74.94,67.93 74.47,67.46 v1(73.79,67.46)
WKUP_OSC0_XIN: length 13.3
  TOP w0.191: Y4.3 77.08,66.25 v1(77.09,66.24)
  TOP w0.229: v1(87.18,68.95) 87.58,69.35 U37.M29
  L7-SIGNAL w0.107: v1(87.18,68.95) 83.05,68.95 82.17,68.06 79.5,68.06 77.68,66.24 v1(77.09,66.24)
WKUP_OSC0_XOUT: length 19.9
  TOP w0.191: v1(72.52,65.06) 72.53,65.05 Y4.1
  TOP w0.229: v1(88.78,68.95) 88.78,68.95 U37.M27
  L7-SIGNAL w0.107: v1(72.52,65.06) 74.47,65.06 75.18,65.78 77.72,65.78 79.76,67.81 82.3,67.81 82.95,68.46 87.4,68.46 87.51,68.58 88.4,68.58 v1(88.78,68.95)
XTAL1: length 6
  TOP w0.191: U19.6 v1(48.22,117.29)
  BOTTOM w0.191: v1(48.22,117.29) 47.89,116.97 47.89,113.68 48.25,113.32 Y6.1
XTAL2: length 4.5
  TOP w0.191: U19.5 48.72,117.16 v1(48.9,117.34)
  BOTTOM w0.191: v1(48.9,117.34) 48.9,116.88 49.07,116.7 50.48,116.7 50.75,116.44 Y6.3
ZIFCLK0: length 2.9
  TOP w0.191: U19.50 42.72,102.14 42.67,102.09 U25.6
ZIFCLK1: length 2.9
  TOP w0.191: U19.52 43.72,102.14 43.67,102.09 U25.4
ZIFFS0: length 2.9
  TOP w0.191: U25.8 41.67,102.09 41.72,102.14 U19.48
ZIFFS1: length 2.9
  TOP w0.191: U25.3 44.17,102.09 44.22,102.14 U19.53
ZIFI0: length 2.9
  TOP w0.191: U19.51 43.22,102.14 43.17,102.09 U25.5
ZIFI1: length 2.9
  TOP w0.191: U25.9 41.17,102.09 41.22,102.14 U19.47
ZIFQ0: length 2.9
  TOP w0.191: U19.49 42.22,102.14 42.17,102.09 U25.7
ZIFQ1: length 2.9
  TOP w0.191: U19.46 40.72,102.14 40.67,102.09 U25.10
N22073312: length 1.6
  TOP w0.229: U31.P6 v2(147.78,84.21)
  BOTTOM w0.191: v2(147.78,84.21) 147.77,84.19 R317.2
N22073335: length 13.8
  TOP w0.191: v1(149.73,74.41) 149.97,74.17 U35.4
  TOP w0.229: U31.M5 v2(150.79,85.21)
  L5-SIGNAL w0.163: v2(150.79,85.21) 149.73,84.15 v1(149.73,74.41)
  BOTTOM w0.191: R313.1 150.15,85.84 v2(150.79,85.21)
N23139394: length 2.8
  TOP w0.191: D4.3 R19.2 R18.1
N23154802: length 8.4
  TOP w0.191: v1(85.72,57.01) 85.47,56.76 R174.1
  TOP w0.229: v1(88.78,62.55) 89.18,62.95 U37.D27
  L7-SIGNAL w0.107: v1(85.72,57.01) 88.4,59.69 88.4,60.71 89.18,61.48 89.18,62.14 v1(88.78,62.55)
N23300995: length 11.8
  TOP w0.229: v1(95.98,78.55) 96.38,78.15 U37.AC18
  L4-SIGNAL w0.163: v1(95.98,78.55) 95.57,78.95 95.57,79.51 95.34,79.75 94.99,79.75 94.77,79.97 94.77,80.31 94.54,80.55 94.19,80.55 93.18,81.56 93.18,83.67 91.57,85.28 TP38.1
  BOTTOM w0.163: R316.1 91.91,84.61 91.57,84.95 TP38.1
N23785887: length 2.6
  BOTTOM w0.191: J16.2 108.71,4.47 TP75.1
N23786032: length 2.9
  BOTTOM w0.191: U76.3 100.97,22.98 R434.1 100.2,23.48
N24377130: length 45.8
  TOP w0.191: 146.3,69.46 146.3,71.11 v1(145.92,71.49)
  TOP w0.229: v1(107.98,73.75) 107.98,73.74 U37.U4
  L5-SIGNAL w0.163: v1(145.92,71.49) 140.59,76.82 138.18,76.82 136.42,78.58 123.04,78.58 122.68,78.22 120.9,78.22 120.14,77.46 114.58,77.46 113.88,76.76 112.97,76.76 110.87,74.67 110.87,74.48 110.55,74.15 110.23,74.15 110.23,74.15 110.22,74.15 109.82,73.75 v1(107.98,73.75)
N24525426: length 8.1
  TOP w0.229: v1(89.58,64.95) 89.58,64.95 U37.G26
  L5-SIGNAL w0.163: v1(89.58,64.95) 89.17,64.54 86.02,64.54 85.88,64.4 v1(82.31,64.4)
N27191474: length 20
  TOP w0.191: R83.2 v1(152.65,95.87) ; v1(136.27,98.92) 136,98.65 U27.52
  L5-SIGNAL w0.163: v1(152.65,95.87) 149.86,95.87 145.92,99.81 139.7,99.81 139.11,99.22 136.57,99.22 v1(136.27,98.92)
N27191486: length 2.3
  TOP w0.191: U24.4 154.44,96.58 154.22,96.35 R83.1
N27191539: length 1.1
  TOP w0.305: R98.2 158.28,94.22 R99.1
N28200806: length 3.6
  TOP w0.191: R146.2 76.2,68.09 76.18,68.11 Y2.2 77.85,69.46
N28200825: length 4.8
  TOP w0.191: Y2.1 71.68,69.46 71.25,69.03 71.25,67.76 71.55,67.45 R147.2
N28200987: length 2.8
  TOP w0.191: R141.2 C284.1 77.31,74.16 77.27,74.19 Y1.3
N28201033: length 2.7
  TOP w0.191: R143.2 C285.1 72.87,72.38 72.91,72.34 Y1.1
N28832809: length 1.1
  BOTTOM w0.191: C827.2 R444.1
N28833063:
  vias: v1(76.96,4.18) v1(76.96,3.55) v1(76.96,2.91)
N28833091: length 1.7
  BOTTOM w0.381: L63.1 L59.2
N28833093: length 1.7
  BOTTOM w0.381: L71.2 87.12,11.67 L59.1
N28833539: length 26.6
  BOTTOM w0.191: P4.1 L71.1 88.77,13.58 86.61,15.74 76.96,15.74 74.93,17.77 C823.2
N28846490:
  vias: v1(60.33,4.18) v1(60.33,3.55) v1(60.33,2.91)
N28846519: length 14.3
  BOTTOM w0.191: C830.2 74.04,15.61 74.68,14.98 74.68,12.69 73.53,11.55 L72.1 P3.1
N28846523: length 1.7
  BOTTOM w0.381: L72.2 70.48,11.67 L60.1
N28846525: length 1.7
  BOTTOM w0.381: L64.1 L60.2
N28846680: length 1.1
  BOTTOM w0.191: C835.2 R451.1
N28847103:
  vias: v1(43.69,4.18) v1(43.69,3.55) v1(43.69,2.91)
N28847132: length 10.4
  BOTTOM w0.191: P2.1 L73.1 56.9,11.55 58.42,13.07 C834.2
N28847136: length 1.7
  BOTTOM w0.381: L61.1 53.85,11.67 L73.2
N28847138: length 1.7
  BOTTOM w0.381: L65.1 L61.2
N28847293: length 1.1
  BOTTOM w0.191: C829.2 R449.1
N28847749:
  vias: v1(27.05,4.18) v1(27.05,3.55) v1(27.05,2.91)
N28847778: length 27
  BOTTOM w0.191: P1.1 L74.1 41.43,11.55 46.38,16.5 56.13,16.5 56.52,16.88 C825.2
N28847782: length 1.7
  BOTTOM w0.381: L74.2 37.21,11.67 L62.1
N28847784: length 1.7
  BOTTOM w0.381: L66.1 L62.2
N28847939: length 1.1
  BOTTOM w0.191: C822.2 R441.1
N28964551: length 8.6
  TOP w0.229: U31.K5 v2(151.79,86.21)
  L4-SIGNAL w0.163: v2(151.79,86.21) 151.26,86.73 150.11,86.73 149.22,87.62 v1(146.56,87.62)
  BOTTOM w0.191: v1(146.56,87.62) R301.1 R302.2
N28998069: length 14.4
  TOP w0.191: TP57.1 v1(101.47,52.44)
  TOP w0.229: U37.F13 100.38,64.54 v1(100.78,64.14)
  L5-SIGNAL w0.163: v1(101.47,52.44) 100.38,53.53 100.38,60.31 100.38,61.11 100.38,61.58 100.38,61.58 100.38,61.91 100.38,61.91 100.38,62.38 100.38,63.74 v1(100.78,64.14)
N29097966: length 2.5
  TOP w0.356: U14.44 v2(172.02,122.42)
  BOTTOM w0.356: v2(172.02,122.42) 171.84,122.6 C503.2
N29098001: length 2.5
  TOP w0.356: v2(174.56,122.42) U14.40
  BOTTOM w0.356: C502.2 174.74,122.6 v2(174.56,122.42)
N29098079: length 4.8
  TOP w0.305: U14.5 174.56,112.7 173.23,111.37 172.64,111.37 172.34,111.06 C113.1
N29098081: length 2.8
  TOP w0.356: U14.39 175.2,123.24 174.7,123.74 C73.2
N29098121: length 3.3
  TOP w0.305: U14.7 175.83,111.52 175.64,111.33 C110.2
N29098125: length 3.7
  TOP w0.305: U14.6 175.2,112.41 174.12,111.33 C110.1
N29098127: length 2.8
  TOP w0.356: U14.35 177.74,123.24 178.23,123.74 C74.2
N29098206: length 11.5
  TOP w0.305: C142.2 v1(173.23,107.18) 175.01,107.18 176.47,108.64 U14.8
  BOTTOM w0.191: C537.1 v1(173.23,107.18)
N29098208: length 2.5
  TOP w0.356: v2(179.64,122.42) U14.32
  BOTTOM w0.356: C501.2 179.46,122.6 v2(179.64,122.42)
N29098269: length 8.5
  TOP w0.191: C128.1 v1(176.91,107.05) 177.1,107.24 U14.9
  BOTTOM w0.191: C542.1 v1(176.91,107.05)
N29098271: length 2.7
  TOP w0.356: U14.28 182.18,122.53 v2(182.25,122.6)
  BOTTOM w0.356: C500.2 v2(182.25,122.6)
N29098305: length 9
  TOP w0.191: U14.10 177.74,108.51 v2(179.2,107.05) C129.1
  BOTTOM w0.191: C541.1 v2(179.2,107.05)
N29098342: length 9.7
  TOP w0.191: U14.11 178.37,110.16 v2(181.48,107.05) C130.1
  BOTTOM w0.191: C540.1 v2(181.48,107.05)
N29098394: length 10.4
  TOP w0.191: U14.12 179.01,111.81 v2(183.77,107.05) C131.1
  BOTTOM w0.191: C539.1 v2(183.77,107.05)
N29098396: length 2.9
  TOP w0.356: C75.2 182.46,123.74 182.82,123.38 U14.27
N29098435: length 2.9
  TOP w0.356: C76.2 185.72,123.74 185.36,123.37 U14.23
N29098652: length 7.2
  TOP w0.191: R70.1 186.82,110.61 185.04,110.61 182.82,112.83 U14.18
N29134681: length 2.6
  BOTTOM w0.191: U74.4 59.53,23.9 58.67,24.75 R431.1
N29136651: length 2.8
  BOTTOM w0.191: C818.2 65.41,17.28 65.28,17.15 R445.1 65.28,15.92 65.41,15.8 TP76.1
N29136657: length 2.8
  BOTTOM w0.191: C819.2 64.14,17.28 64.26,17.15 R445.2 64.26,15.92 64.14,15.8 TP77.1
N29136703: length 2.9
  BOTTOM w0.191: C818.1 65.02,19.42 U74.56
N29136712: length 2.9
  BOTTOM w0.191: U74.57 64.52,19.42 C819.1
N29139158: length 4.7
  BOTTOM w0.191: U74.8 59.81,25.9 ; 59.81,25.9 59.69,25.78 59.69,25.57 59.86,25.4 U74.7 ; 59.81,25.9 58.93,26.79 R427.1 R426.1
N29142214: length 4.1
  BOTTOM w0.191: C778.1 R384.1 R387.2
N29142221: length 2.3
  TOP w0.191: U44.1 v1(60.83,61.08)
  BOTTOM w0.191: v1(60.83,61.08) R371.2
N29142246: length 2.3
  TOP w0.191: v1(57.02,61.08) 57.02,59.68
  BOTTOM w0.191: R372.2 v1(57.02,61.08)
N29142266: length 3.2
  TOP w0.191: U44.8 v1(60.83,55.49)
  BOTTOM w0.191: R377.1 v1(60.83,55.49) R386.2
N29144479: length 25.3
  TOP w0.191: C18.2 21.2,140.34 19.93,140.34 19.67,140.08 ; 19.67,140.08 19.13,140.08 19.12,140.07 18.4,140.07 ; 19.67,140.08 R7.1 ; U3.1 18.4,140.07 ; 18.4,140.07 C17.2 17.14,140.96 15.88,142.23 12.06,142.23 10.41,140.58 10.41,138.04 11.98,136.47 J8.5B
N29144501: length 25.2
  TOP w0.191: C81.2 19.94,121.27 R45.1 19.14,121.02 19.13,121.01 U12.1 18.4,121.02 C80.2 17.14,121.91 15.88,123.18 12.06,123.18 10.41,121.53 10.41,118.99 11.98,117.42 J9.5B
N29144523: length 25.2
  TOP w0.191: C148.2 19.94,102.22 19.68,101.97 19.14,101.97 19.13,101.96 U21.1 18.4,101.97 17.14,101.97 17.14,102.86 15.88,104.13 12.06,104.13 10.41,102.48 10.41,99.94 11.98,98.37 J12.5B
N29144983: length 17.3
  TOP w0.191: J8.2B 11.98,140.63 13.08,141.72 15.49,141.72 16.26,140.96 16.26,136.77 C24.1 18.4,135.88 U4.1 18.41,135.91 ; 18.41,135.91 18.4,135.91 ; 18.41,135.91 19.66,135.91 19.67,135.89 19.68,135.89 ; 20.83,135.89 21.29,135.89 21.43,135.76 22.2,135.76 22.21,135.77 C23.2 ; 20.83,135.89 R11.2 ; 20.83,135.89 19.68,135.89 ; R10.2 19.68,135.89
N29144989: length 17.2
  TOP w0.191: J9.2B 11.98,121.58 13.08,122.67 15.49,122.67 16.26,121.91 16.26,117.72 C96.1 18.4,116.83 U15.1 19.67,116.84 R53.2 R54.2 21.3,116.83 21.44,116.69 22.22,116.69 C95.2
N29144995: length 17.2
  TOP w0.191: C160.2 22.22,97.64 21.44,97.64 21.3,97.78 R80.2 R79.2 19.67,97.79 U26.1 18.4,97.78 C161.1 16.26,98.67 16.26,102.86 15.49,103.62 13.08,103.62 11.98,102.53 J12.2B
N29145145: length 11.9
  TOP w0.191: 19.67,133.73 19.93,133.99 21.2,133.99 C36.2 ; 19.67,133.73 19.68,133.72 ; 19.67,133.73 19.13,133.73 19.12,133.72 18.4,133.72 ; U5.1 18.4,133.72 ; 18.4,133.72 17.14,133.72 14.49,136.38 J8.5A
N29145167: length 11.8
  TOP w0.191: C103.2 19.94,114.92 R57.1 19.14,114.67 19.13,114.66 U17.1 18.4,114.67 C102.2 14.49,117.33 J9.5A
N29145189: length 11.8
  TOP w0.191: J12.5A 14.49,98.28 C177.2 18.4,95.62 U29.1 19.13,95.61 19.14,95.62 R96.1 19.94,95.87 C178.2
N29145646: length 8.6
  TOP w0.191: 18.41,129.56 19.12,129.56 19.13,129.54 19.68,129.54 ; 18.41,129.56 U9.1 18.4,129.53 C54.1 16.24,129.53 J8.2A ; 18.41,129.56 18.4,129.56 ; 20.83,129.54 21.29,129.54 21.43,129.41 22.2,129.41 22.21,129.42 C53.2 ; 20.83,129.54 19.68,129.54 ; 20.83,129.54 R23.2 ; 19.68,129.54 R22.2
N29145652: length 8.5
  TOP w0.191: C108.2 22.22,110.34 21.44,110.34 21.3,110.48 R67.2 R66.2 19.14,110.48 19.13,110.49 U18.1 18.4,110.48 C109.1 16.24,110.48 J9.2A
N29145658: length 8.5
  TOP w0.191: J12.2A 16.24,91.43 C199.1 18.4,91.43 U30.1 19.13,91.44 19.14,91.43 R102.2 R103.2 21.3,91.43 21.44,91.29 22.22,91.29 C195.2
N29159706: length 12.6
  L4-SIGNAL w0.163: v2(198.25,98.92) 196.85,98.92 v2(195.45,97.53) 194.94,97.53 J11.8
  BOTTOM w0.191: U67.7 197.99,99.18 v2(198.25,98.92) ; R295.2 C574.1 R292.1 v2(195.45,97.53)
N29176310: length 2.1
  BOTTOM w0.191: R367.1 4.11,60.77 J21.119
N29176636: length 4.9
  BOTTOM w0.191: J21.32 12.33,42.77 TP61.1
N29176758: length 2
  TOP w0.191: v1(3.96,35.58) 4.06,35.68 R215.1
  BOTTOM w0.191: J21.77 v1(3.96,35.58)
N29176776: length 2.6
  BOTTOM w0.191: TP63.1 3.56,34.91 3.62,34.98 J21.76
N29176797: length 2.7
  BOTTOM w0.191: J21.47 11.68,33.78 11.68,33.77 RJ20.2
N29176814: length 2
  TOP w0.191: v1(3.98,33.18) 4.06,33.26 R219.1
  BOTTOM w0.191: J21.73 v1(3.98,33.18)
N29176862: length 2.2
  TOP w0.191: R225.1 v1(11.81,27.8)
  BOTTOM w0.191: v1(11.81,27.8) 10.62,27.8 J21.57
N29180491: length 7.9
  TOP w0.191: J15.12 143.81,41.34 v1(143.76,41.39) ; J15.1 v1(146.31,43.94)
  L2-SIGNAL w0.107: v1(146.31,43.94) 146.31,43.3 144.41,41.39 v1(143.76,41.39)
  BOTTOM w0.191: R424.2 v1(143.76,41.39)
N29180693: length 14.7
  TOP w0.191: R191.2 Q6.D 150.42,49.98 149.35,51.04 148.08,51.04 147.81,50.77 U49.1 147.36,50.18 146.37,51.17 145.29,51.17 145.02,50.9 U48.1 144.57,50.18 143.58,51.17 142.62,51.17 142.22,50.77 U47.1
N29180734: length 3.8
  TOP w0.191: J15.7 144.81,47.01 v1(144.91,47.11)
  BOTTOM w0.191: R411.1 144.91,46.22 v1(144.91,47.11)
N29180779: length 2.2
  TOP w0.191: J15.15 v1(142.81,47.04)
  BOTTOM w0.191: v1(142.81,47.04) 142.88,46.98 R413.2
N29182955: length 1.8
  TOP w0.191: 45.85,28.82 45.31,28.82 45.3,28.82 U55.13
N29183037: length 2.7
  TOP w0.191: R231.1 R226.2 39.73,27.68 39.87,27.82 U55.6
N29184661: length 2.8
  TOP w0.191: U51.13 45.3,35.93 45.31,35.93 45.85,35.93 45.85,36.95
N29185762: length 2.7
  TOP w0.191: R218.1 R217.2 39.73,34.79 39.87,34.93 U51.6
N29203019: length 7.8
  TOP w0.191: C25.2 51.28,136.9 53.09,138.7 D3.1 ; L5.1 C16.1
  TOP w0.254: D3.1 53.39,139.31
  TOP w0.508: 53.39,139.31 C16.1
N29203023: length 2.4
  TOP w0.191: C25.1 C32.2 L12.2
N29203029: length 3.7
  TOP w0.191: C62.2 L17.2 50.04,132.54 50.16,132.66 C32.1
N29203179: length 1.4
  TOP w0.191: C34.1 47.62,132.96 L12.1
N29203181: length 1.4
  TOP w0.191: L17.1 C61.1
N29203576: length 6.1
  TOP w0.508: C16.2 J7.1
N29203584: length 1.5
  TOP w0.191: U23.4 49.9,98.09 49.91,98.07 R82.1
N29203608: length 2.8
  TOP w0.191: U22.4 47.36,98.43 48.17,97.61 R81.1
N29203733: length 1.4
  TOP w0.191: L5.2 C29.2
N29203735: length 5.1
  TOP w0.191: L22.1 L18.2 L14.2 54.99,133.97
N29203745: length 1.5
  TOP w0.191: C71.2 54.99,127.62
N29203827: length 1.6
  TOP w0.191: U19.14 v1(44.22,117.19)
  BOTTOM w0.191: v1(44.22,117.19) 44.22,116.47 C522.2
N29203843: length 1.9
  TOP w0.191: L14.1 C38.1
N29203845: length 1.9
  TOP w0.191: L18.1 C50.1
N29203849: length 4
  TOP w0.305: U19.17 42.72,116.87 43.18,117.34 C91.1
  TOP w0.635: C83.1 C85.1 C91.1
N29203873: length 15.3
  TOP w0.305: U19.44 39.16,105.1 38.32,104.26
  TOP w0.635: v1(37.21,108.07) 37.47,107.81 C118.2 C117.2 C116.2 ; C127.2 v1(37.21,103.51) C144.2 C146.2 C150.2 ; C127.2 38.32,104.26 ; C127.2 C126.2 C125.2
  BOTTOM w0.635: v1(37.21,108.07) v1(37.21,103.51)
N29204635: length 20.3
  TOP w0.191: D2.1 41.27,139.75 42.55,138.48 42.55,136.26 43.7,135.1 43.7,134.98 44.2,134.48 C31.2 ; C22.1 34.16,137.66 36.37,139.87 37.9,139.87
  TOP w0.254: L3.1 C15.1 ; D2.1 40.97,140.32
  TOP w0.508: 40.97,140.32 C15.1 38.35,140.32 37.9,139.87
N29204639: length 2.4
  TOP w0.191: L16.2 C48.2 C31.1
N29204645: length 3.7
  TOP w0.191: C48.1 44.32,130.25 44.45,130.12 L21.2 C68.2
N29204746: length 1.4
  TOP w0.191: C49.1 46.86,130.55 L16.1
N29204748: length 1.4
  TOP w0.191: L21.1 C69.1
N29205057: length 6.1
  TOP w0.508: 39.37,141.34 J5.1
N29205223: length 1.4
  TOP w0.191: L3.2 C27.2
N29205225: length 5.1
  TOP w0.191: C27.1 L7.2 L15.2 L20.1
N29205235: length 1.5
  TOP w0.191: L20.2 C67.2
N29205377: length 1.9
  TOP w0.191: L15.1 C44.1
N29205379: length 1.9
  TOP w0.191: L7.1 C30.1
N29205614: length 12.1
  TOP w0.191: 29.46,131.82 C40.1 ; 29.46,131.82 29.84,131.82 30.48,131.18 L19.1 ; 29.46,131.82 L13.2 29.46,134.99 29.84,135.5 ; C40.1 26.67,131.82 D5.1 ; C40.1 C57.2 R24.2
N29205618: length 7.6
  TOP w0.191: R27.2 C66.2 L19.2 28.19,128.64 C57.1 R24.1
N29205650: length 3.6
  TOP w0.191: L13.1 31.24,135.12 C26.2 C22.2
N29205730: length 1.4
  TOP w0.191: L6.2 C40.2
N29214431: length 28.4
  TOP w0.191: C2.2 L2.2 72.64,150.74 84.2,150.74 84.96,149.98 84.96,148.71 86.74,146.93 94.49,146.93 94.61,147.06 J6.1
N29214437: length 3.3
  TOP w0.191: L1.2 C2.1 70.74,148.33 70.89,148.17 U2.11
N29214443: length 2.3
  TOP w0.191: U2.14 70.89,133.59 70.87,133.56 TP4.1
N29214525: length 2.3
  TOP w0.191: R15.1 79.38,133.5 79.39,133.52 U2.20
N29214549: length 2.3
  TOP w0.191: R16.1 80.52,133.5 80.49,133.53 U2.21
N29214557: length 1.9
  TOP w0.191: U2.3 81.59,148.49 81.53,148.55 R4.2
N29214575: length 2.2
  TOP w0.191: U2.1 83.79,148.71 83.82,148.74 TP1.1
N29427544: length 4.6
  TOP w0.305: R260.2 163.96,8.63 164.85,9.51 165.61,9.51 ; 165.74,9.01 165.61,8.88
N29427613: length 1.9
  BOTTOM w0.508: C838.1 C837.2
N29427748: length 1.9
  TOP w0.305: DS1.2 163.93,4.57 163.96,4.6 R260.1
N29427750: length 3.2
  TOP w0.305: U64.5 170.98,8.24 170.18,7.44 Q9.4
N29427801: length 2.4
  TOP w0.305: C477.1 174.96,6.11 175.31,6.47 U64.1
N29457313: length 8.8
  TOP w0.191: TP10.1 113.49,120.56 111.46,120.56 109.6,122.42 109.1,122.42 108.68,121.99 U16.2
  BOTTOM w0.191: R274.1 TP10.1
N29457315: length 10.9
  TOP w0.191: TP11.1 114.5,120.94 111.71,120.94 109.86,122.8 108.97,122.8 108.18,122.01 U16.3
  BOTTOM w0.191: R273.1 TP11.1
N29457363: length 7
  TOP w0.191: RJ1.2 103.5,125.72 104,125.72 104.39,125.33 104.39,124.2 R35.2 105.03,123.02 105.18,122.87 U16.9
N29457411: length 3.4
  TOP w0.191: U16.10 104.68,122.64 R34.1
N29457441: length 2.4
  TOP w0.191: U16.24 101.26,113.57 101.02,113.32 100.69,113.32 100.49,113.53 R60.2
N29457479: length 4.6
  TOP w0.191: U16.35 v1(108.68,110.13)
  BOTTOM w0.191: R278.2 109.38,110.13 v1(108.68,110.13)
N29457500: length 2.3
  TOP w0.191: U16.36 v1(109.17,110.65)
  BOTTOM w0.191: R279.2 109.22,110.7 v1(109.17,110.65)
N29457524: length 2.2
  TOP w0.191: U16.22 v1(100.84,114.57)
  BOTTOM w0.191: R276.2 101.06,114.8 v1(100.84,114.57)
N29457542: length 3.4
  TOP w0.191: R38.1 107.35,122.83 107.35,121.69 107.18,121.52 U16.5
N29457548: length 2.7
  TOP w0.191: v1(100.71,115.56) 101.2,115.07 U16.21
  BOTTOM w0.191: v1(100.71,115.56) 100.97,115.81 R275.2
N29457593: length 7.4
  TOP w0.191: U16.38 112.61,114.07 R59.2 113.67,113.53 113.92,113.27 v1(113.92,112) C107.1
  BOTTOM w0.191: v1(113.92,112) 114.25,111.67 Y7.1
N29457640: length 3.2
  TOP w0.191: U16.6 106.67,121.52 106.88,121.72 106.88,121.73 106.93,121.78 106.93,122.89 107.06,123.02 R37.1
N29457654: length 6.9
  TOP w0.191: U16.39 111.68,114.57 111.7,114.54 R59.1 113.67,114.54 113.92,114.8 v1(113.92,115.81) C101.1
  BOTTOM w0.191: Y7.2 114.25,116.14 v1(113.92,115.81)
N29457660: length 3.1
  TOP w0.191: U16.8 105.68,121.87 106.05,122.24 R36.1
N29483068: length 3.2
  TOP w0.157: FL2.4 70.59,130.9 70.83,131.15 70.83,131.62 v1(70.64,131.82)
  BOTTOM w0.157: v1(70.64,131.82) 70.74,131.71 70.74,130.24 J20.38
N29483119: length 3.2
  TOP w0.157: v1(71.4,131.82) 71.18,131.6 71.18,131.12 71.4,130.9 FL2.1
  BOTTOM w0.157: v1(71.4,131.82) 71.25,131.66 71.25,130.21 J20.36
N29500308: length 20.3
  TOP w0.191: R149.1 v1(80.64,65.52)
  TOP w0.229: v1(88.78,68.15) 89.18,68.55 U37.L27 ; U37.N24 91.58,70.15 v1(91.18,69.75) ; U37.L26 89.98,68.55 v1(89.58,68.15) ; U37.N23 92.38,70.15 v1(91.98,69.75) ; v1(90.38,68.15) 90.78,68.55 U37.L25 ; U37.M25 90.78,69.35 v1(90.38,68.95) ; U37.L24 91.58,68.55 v1(91.18,68.15) ; v1(91.18,68.95) 91.58,69.35 U37.M24
  L4-SIGNAL w0.163: v1(91.98,69.75) v1(91.18,69.75) v1(91.18,68.95) ; v1(91.18,68.95) v1(90.38,68.95) ; v1(91.18,68.95) v1(91.18,68.15) v1(90.38,68.15)
  L7-SIGNAL w0.107: v1(88.78,68.15) 88.4,67.78 87.82,67.78 87.67,67.92 84.57,67.92 82.68,66.03 81.15,66.03 v1(80.64,65.52)
  L7-SIGNAL w0.152: v1(88.78,68.15) v1(89.58,68.15) v1(90.38,68.15)
N29500526: length 6.2
  TOP w0.229: v1(110.38,80.95) 110.38,80.94 U37.AF1
  L4-SIGNAL w0.163: v1(110.38,80.95) 110.48,80.95 110.57,81.04 111.07,81.04 113.46,83.43 v1(114.94,83.43)
N29520912: length 1.7
  TOP w0.191: SW2.16 v1(60.07,49.77)
  BOTTOM w0.191: R402.2 v1(60.07,49.77)
N29520937: length 1.7
  TOP w0.191: 61.34,48.76 v1(61.34,49.77)
  BOTTOM w0.191: R401.2 v1(61.34,49.77)
N29520962: length 1.7
  TOP w0.191: SW2.14 v1(62.61,49.77)
  BOTTOM w0.191: R400.2 v1(62.61,49.77)
N29520987: length 1.7
  TOP w0.191: 63.88,48.76 v1(63.88,49.77)
  BOTTOM w0.191: R399.2 v1(63.88,49.77)
N29521012: length 1.7
  TOP w0.191: 65.15,48.76 v1(65.15,49.77)
  BOTTOM w0.191: R398.2 v1(65.15,49.77)
N29521037: length 1.7
  TOP w0.191: SW2.11 v1(66.42,49.77)
  BOTTOM w0.191: R397.2 v1(66.42,49.77)
N29521062: length 1.7
  TOP w0.191: SW2.10 v1(67.69,49.77)
  BOTTOM w0.191: R396.2 v1(67.69,49.77)
N29521082: length 1.7
  TOP w0.191: 68.96,48.76 v1(68.96,49.77)
  BOTTOM w0.191: R395.2 v1(68.96,49.77)
N29622583: length 37.3
  TOP w0.229: U20.40 v1(71.5,104.17)
  BOTTOM w0.191: v1(71.5,104.17) 71.5,104 70.87,103.37 70.87,92.19 71.12,91.94 82.04,91.94 82.42,92.32 82.42,102.61 83.35,103.53 R283.2
N29626619: length 2.7
  TOP w0.305: C236.1 8.38,84.99 8.07,84.68 U34.4
N29626723: length 4.2
  TOP w0.305: U34.15 9.37,75.91 8.89,75.43 R137.1 10.03,74.28
N29626795: length 4.5
  TOP w0.305: U34.5 7.42,84.28 7.01,84.7 6.77,84.7 6.48,84.99 C235.1 5.46,85.71 5.21,85.97
N29626827: length 3
  TOP w0.305: R140.1 6.48,74.88 6.12,75.24 U34.10
N29626839: length 3.5
  TOP w0.305: U34.8 5.47,84.43 3.94,85.97
N29626843: length 4.9
  TOP w0.305: TP42.1 3.96,74.41 4.09,74.28 R139.2 5.21,74.88 5.47,75.15 U34.9
N29649764: length 13.3
  TOP w0.191: v1(68.18,131.54) 68.18,137.04 65.15,140.07 D1.1
  BOTTOM w0.191: J20.44 v1(68.18,131.54)
N29668820: length 4.2
  TOP w0.305: 25.4,66.41 25.03,66.78 U39.1
  TOP w0.508: 25.73,66.08 25.4,66.41
  TOP w0.635: FL14.2 27.18,64.51 27.05,64.63 C296.1 25.73,66.08
N29890935: length 1.8
  TOP w0.191: U19.7 47.72,117.4 47.88,117.56 C92.2
N29891501: length 4.1
  TOP w0.305: C93.1 50.93,117.46 50.22,116.75 U19.2
  TOP w0.635: C84.1 C86.1 C93.1
N30029908: length 2.3
  TOP w0.191: U25.21 43.67,96.94 44.45,96.16 R92.1
N30029911: length 2.2
  TOP w0.191: U25.20 43.17,96.81 43.69,96.29 R91.1
N30029914: length 2.1
  TOP w0.191: R90.1 42.93,96.29 42.67,96.55 U25.19
N30029917: length 2.1
  TOP w0.191: R88.1 41.4,96.29 41.67,96.56 U25.17
N30029920: length 2
  TOP w0.191: R89.1 42.16,96.29 42.17,96.3 U25.18
N30029923: length 2.2
  TOP w0.191: U25.16 41.17,97.04 40.64,96.51 R87.1
N30029926: length 2.3
  TOP w0.191: U25.15 40.67,97.17 39.88,96.38 R86.1
N30029929: length 2.5
  TOP w0.191: U25.14 40.17,97.28 39.12,96.23 R85.1
N30068694: length 2.9
  TOP w0.191: U32.4 33.28,88.13 33.4,88.25 33.66,88.25 33.78,88.13 U32.3
N30080305: length 2.3
  TOP w0.191: v2(135.64,127.88) 135.57,127.94 U7.16
  BOTTOM w0.191: v2(135.64,127.88) R269.1
N30080322: length 4.8
  TOP w0.191: TP8.1 131.83,127.09 131.76,127.15 U7.10
  TOP w0.229: U7.10 v1(131.76,130.48)
  BOTTOM w0.191: v1(131.76,130.48) 131.76,130.99 R266.2
N30080336: length 8.9
  TOP w0.191: Q1.6 127.62,132.18 128.27,132.83 131.44,132.83 v2(131.95,133.34) 131.76,133.53 U7.7
  BOTTOM w0.191: R264.2 v2(131.95,133.34)
N30080339: length 2.3
  TOP w0.191: U7.8 131.13,133.53 v2(130.94,133.34)
  BOTTOM w0.191: v2(130.94,133.34) R265.2
N30130836: length 4.1
  TOP w0.305: U62.14 94.95,13.12 94.36,13.71 R251.2 R250.2
N30130873: length 1
  TOP w0.191: R251.1 TP69.1
N30130899: length 2.4
  TOP w0.305: U62.13 95.6,13.17 95.63,13.2 R252.2
N30130913: length 2.9
  TOP w0.305: U62.12 96.25,13.06 96.9,13.71 R253.2
N30133146: length 3.2
  TOP w0.191: Q8.3 93.26,22 v1(93.6,22.34)
  BOTTOM w0.191: v1(93.6,22.34) R438.1 R439.2
N30186501: length 4.3
  TOP w0.191: U45.1 v1(81.64,54.45) 82.08,54.45 83.31,53.22 RJ16.2
  BOTTOM w0.191: R385.1 81.52,54.56 v1(81.64,54.45)
N30188271: length 7.9
  L4-SIGNAL w0.305: v1(182.5,83.05) v1(187.45,83.05)
  BOTTOM w0.305: Q13.4 181.88,83.01 181.91,83.05 v1(182.5,83.05) ; Q12.4 186.83,83.01 186.87,83.05 v1(187.45,83.05)
N30188608: length 8
  L4-SIGNAL w0.305: v1(182.5,87.87) v1(187.45,87.87)
  BOTTOM w0.254: 181.94,87.87 181.9,87.84 181.88,87.84 ; 186.83,87.84 186.86,87.84 186.89,87.87
  BOTTOM w0.305: v1(182.5,87.87) 181.91,87.87 181.88,87.84 Q11.4 ; Q10.4 186.83,87.84 186.87,87.87 v1(187.45,87.87)
N30703324: length 4.5
  TOP w0.254: R33.2 152.53,125.72 152.45,125.64 C70.1 150.23,124.23 U11.12
N30703458: length 1.9
  TOP w0.191: U11.19 146.31,121.66 146.3,121.66 R43.1
N30703463: length 2.1
  TOP w0.191: U11.20 146.95,121.16 146.43,120.64 R44.1
N30745719: length 5.7
  TOP w0.191: U11.1 148.23,119.9 147.45,119.12 TP12.1 146.3,119.62 R47.1 C90.1 R51.2
N30746595: length 1.8
  TOP w0.191: RJ2.2 152.78,122.8 152.64,122.66 U11.10
N30809211: length 5.1
  TOP w0.191: C442.2 R243.1 39.24,19.29 39.15,19.39 39.15,20.82 39.41,21.08 U57.3
N30811250: length 4.3
  TOP w0.191: C451.2 R254.1 ; C451.2 161.32,15.74 160.94,15.36 U61.5 ; C451.2 R247.2
N30811520: length 2.2
  TOP w0.305: U61.3 C467.1
N30812987: length 2.4
  TOP w0.305: C466.1 157.86,8.12 157.86,9.77
N30812990: length 1.5
  TOP w0.305: C466.2 156.21,6.09 R258.1
N30812993: length 1.8
  TOP w0.305: R258.2 155.96,9.13
N30813342: length 6
  TOP w0.305: U61.4 160.4,7.79 160.83,7.36 R259.1 C468.1 R257.1
N30813649: length 2.4
  TOP w0.305: R261.1 R259.2 C468.2
N30821669: length 2.8
  TOP w0.191: R245.1 42.67,19.55 42.67,20.18 42.28,20.58 U57.5
N31193882: length 2.3
  TOP w0.305: R202.1 169.58,44.48 Q7.4
N31194203: length 5.8
  TOP w0.305: R173.1 v2(174.12,56.63) ; Q5.4 v2(171.92,53.93)
  BOTTOM w0.305: v2(171.92,53.93) 172.81,53.93 174.12,55.23 v2(174.12,56.63)
N31194290: length 3.2
  TOP w0.305: R172.2 173.23,57.9 172.94,57.61 Q4.4
N31194295: length 6.3
  TOP w0.191: v2(169.58,64) 169.54,64.04 R150.2
  TOP w0.305: Q3.4 v2(169.58,59.34)
  BOTTOM w0.305: v2(169.58,59.34) v2(169.58,64)
N31194655: length 2.3
  TOP w0.203: D13.1 192.99,44.77 R198.1
N31194670: length 7.3
  TOP w0.203: U46.2 194.02,49.12 ; 194.02,49.12 194.02,47.71 193.55,47.23 R198.2 ; 194.02,49.12 194.55,49.65 C353.1
N31194787: length 7.3
  TOP w0.305: U46.26 184.4,49.77 183.26,48.63 C361.1 182.37,46.47 181.94,46.9 D12.1
N31194818: length 7.3
  TOP w0.305: U46.20 184.32,53.67 184.02,53.96 182.25,53.96 181.94,53.66 D11.1 179.07,53.66 D10.1
N31196095: length 3.7
  TOP w0.203: U46.15 185.93,57.9 185.78,58.05 185.78,59.03 C315.2 185.82,59.06 185.82,59.66 185.67,59.81 R159.1
N31196104: length 5.5
  TOP w0.203: R160.1 186.96,60.43 186.96,59.7 186.82,59.55 C315.1 186.82,58.03 187.2,57.65 187.2,56.5 186.96,56.27 U46.16
N31196146: length 8.7
  TOP w0.203: C344.1 v2(199.39,52.82) ; U46.7 193.24,52.37 v2(193.42,52.19)
  L4-SIGNAL w0.163: v2(193.42,52.19) 198.75,52.19 v2(199.39,52.82)
N31196169: length 10.1
  TOP w0.203: v2(200.03,50.4) 200.03,50.41 200.03,50.41 199.52,50.92 R184.1 ; U46.5 193.27,51.07 v2(193.48,50.85)
  L4-SIGNAL w0.163: v2(200.03,50.4) 200.03,50.41 198.5,50.41 197.23,51.68 194.31,51.68 v2(193.48,50.85)
N31196187: length 10.3
  TOP w0.203: R182.1 195.71,51.17 195.58,51.04 v2(195.07,51.04) 194.31,51.04 193.8,51.55 193.04,51.55 192.87,51.72 U46.6 ; C354.2 v2(199.52,49.9)
  L4-SIGNAL w0.163: v2(195.07,51.04) 196.98,51.04 198.12,49.9 v2(199.52,49.9)
N31196205: length 10.4
  TOP w0.203: v2(194.06,50.28) 193.29,50.28 193.16,50.42 U46.4 ; R193.1 198.12,46.98 v2(198.5,47.36) R189.1
  L4-SIGNAL w0.163: v2(198.5,47.36) 195.58,50.28 v2(194.06,50.28)
N31196259: length 4.4
  TOP w0.203: U46.9 194.65,53.67 R181.2 195.58,53.71 195.71,53.58 C341.1
N31196266: length 1.4
  TOP w0.203: C343.1 195.54,52.31 195.41,52.19 R181.1
N31197066: length 9.1
  TOP w0.203: U46.8 v2(193.42,53.02) ; C340.1 v2(199.39,54.54)
  L4-SIGNAL w0.163: v2(193.42,53.02) 197.87,53.02 v2(199.39,54.54)
N31197134: length 6.8
  TOP w0.203: R199.2 v2(194.82,48.37) 195.84,48.37 C357.2 ; U46.3 v2(193.42,49.77)
  L4-SIGNAL w0.163: v2(193.42,49.77) v2(194.82,48.37)
N31197473: length 3.5
  TOP w0.203: TP45.1 R153.1 194.29,61.44 194.29,60.59 194.44,60.44 194.44,59.81
N31208960: length 2
  TOP w0.305: C226.1 179.45,89.14 R104.1
N31222024: length 18.9
  TOP w0.191: R108.2 195.71,87.75 195.71,87.58 v2(194.98,86.86) 194.94,86.86 194.54,86.45 U33.1 ; U38.4 v1(196.61,73.01)
  L7-SIGNAL w0.107: v2(194.98,86.86) 194.98,82.5 196.61,80.87 v1(196.61,73.01)
  BOTTOM w0.191: R308.1 v2(194.98,86.86)
N31222073: length 4.6
  TOP w0.191: U33.23 195.66,84.94 195.96,85.24 v2(195.96,85.84) 196.22,86.1 C239.2 R111.1
  BOTTOM w0.191: R315.1 v2(195.96,85.84)
N31222132: length 1.4
  TOP w0.191: R117.1 C249.2
N31222198: length 3.5
  TOP w0.191: C251.1 198.37,83.05 R117.2 196.22,83.05 195.82,83.44 U33.20
N31222241: length 3.5
  TOP w0.191: C225.2 195.2,86.22 U33.24
N31222246: length 2.2
  TOP w0.191: U33.22 195.7,84.44 196.34,85.08 C243.2
N31222265: length 3.2
  TOP w0.191: R106.2 v1(191.13,87.49) 191.45,87.18 191.58,87.18 192.05,86.71 U33.6
  BOTTOM w0.191: R300.1 191.26,87.62 v1(191.13,87.49)
N31222285: length 2.8
  TOP w0.191: U33.5 192.55,86.87 192.4,87.01 v1(192.4,87.45) 192.28,87.58 C223.2
  BOTTOM w0.191: R299.1 v1(192.41,87.45)
N31222303: length 2.2
  TOP w0.191: R107.2 193.04,87.75 193.04,87.5 193.05,87.5 U33.4
N31222717: length 1.1
  TOP w0.191: R124.2 R125.1
N31223527: length 2.4
  BOTTOM w0.191: v2(103.76,136.77) 104.14,136.39 R263.1 R262.1
N31223584: length 3.9
  TOP w0.305: U8.5 104.45,131.24 104.39,131.18 v2(104.14,131.18) C56.1
  BOTTOM w0.191: R267.1 v2(104.14,131.18)
N31223889: length 1.3
  TOP w0.305: R12.1 C33.2
N31224124: length 3.4
  TOP w0.191: U8.9 111.45,128.45 v2(111.89,128.01)
  BOTTOM w0.191: v2(111.89,128.01) R270.1 R272.2
N31225374: length 4.3
  TOP w0.191: R55.2 150.88,117.46 150.88,119.66 150.72,119.82 U11.6
N31225630: length 3.6
  TOP w0.191: U8.11 v2(112.74,130.59)
  BOTTOM w0.191: R271.2 111.55,130.59 v2(112.74,130.59)
N31225660: length 4.5
  TOP w0.305: C64.1 R25.1 103.63,129.66 103.63,130.04 104.18,130.59 U8.6
N31226612: length 6.8
  TOP w0.191: U8.7 104.42,129.94 v2(104.2,129.72)
  TOP w0.305: U8.4 v2(103.89,131.89) 103.43,131.43 C47.2
  BOTTOM w0.191: v2(104.2,129.72) 103.5,130.42 103.5,131.51 v2(103.89,131.89)
N31251157: length 4.6
  TOP w0.305: C319.2 C321.1 31.24,57.14 R171.2
N31251611: length 3.9
  TOP w0.122: L42.2 R171.1 30.85,58.52 U43.1 29.51,58.6 L41.3
N31252401: length 3.9
  TOP w0.122: L40.2 30.86,60.06 30.85,60.07 U41.1 29.51,60 L41.4
N31252434: length 4.6
  TOP w0.305: R162.2 31.37,61.08 31.75,61.46 C308.1 C311.2
N31279750: length 7.3
  TOP w0.191: R220.2 SW3.4 SW3.3
N31313642: length 3.4
  TOP w0.191: U11.8 151.89,121.66 152.15,121.4 152.15,119.75 R49.2
N31313645: length 4.6
  TOP w0.191: R50.2 152.53,120.39 152.53,121.91 152.28,122.16 U11.9
N31555915: length 2.3
  BOTTOM w0.191: C492.1 R262.2 R263.2
N31823309: length 3.8
  TOP w0.191: R224.1 TP64.1 153.65,28.82 154.18,29.34 U54.4
N31823321: length 3.4
  TOP w0.191: R229.1 R230.2 154.71,28.46 U54.5
N31828740: length 1.8
  TOP w0.191: U54.7 156.33,27.59 156.08,27.35 C395.1
N31828749: length 3
  TOP w0.191: 156.08,25.77 156.72,26.41 156.72,27.29 156.83,27.41 U54.8
N31829052: length 2.7
  TOP w0.191: U54.9 157.71,27.7 157.35,27.35 C396.2
N31832097: length 5.7
  TOP w0.305: U1.8 108.97,148.2 108.84,148.07 107.57,148.07 107.19,147.69 R5.1 R1.2
N31834422: length 2.7
  TOP w0.305: C1.2 108.97,149.6 109.86,148.7 U1.7
N31987713: length 0.7
  BOTTOM w0.191: R304.2 TP37.1
N31987901: length 0.7
  BOTTOM w0.191: R305.2 TP36.1
N32008315: length 1.8
  TOP w0.191: D1.2 64.18,145.63 64.15,145.66 R6.2
N32011520: length 6.5
  TOP w0.191: R210.1 11.05,43.3 v1(11.94,44.19)
  BOTTOM w0.191: J21.30 11.73,43.97 v1(11.94,44.19) 11.55,44.57 J21.29
N32137181: length 4.4
  TOP w0.191: v1(79.87,47.46) 78.87,48.47 R188.1 79.81,49.18 79.85,49.14 R185.2
  BOTTOM w0.191: U73.A3 v1(79.87,47.46)
N32140279: length 2.7
  TOP w0.191: Q2.3 199.28,75.43 199.26,75.42 199.26,74.54 199.01,74.28 SW1.4
N32140322: length 3.7
  TOP w0.191: Q2.6 197.98,78.91 198.18,79.11 v1(198.63,79.11) Q2.5
  BOTTOM w0.191: v1(198.63,79.11) R342.1
N32413216: length 3.6
  TOP w0.229: U13.7 TP15.1 128.65,113.15
N32594642: length 20.6
  L7-SIGNAL w0.107: v1(23.5,85.97) 21.97,87.49 7.98,87.49 v1(7.42,88.05)
  BOTTOM w0.191: v1(23.5,85.97) 22.41,85.97 U69.5 22.4,85.61 22.64,85.37 R319.2 ; P5.9 v1(7.42,88.05)
N32594704: length 1.8
  TOP w0.191: R112.1 v1(14.52,85.97)
  BOTTOM w0.191: v1(14.52,85.97) 14.52,86.64 14.86,86.98
N32594856: length 1.8
  TOP w0.191: v1(19.82,85.98) 19.83,85.97 C240.1
  BOTTOM w0.191: U69.1 v1(19.82,85.98)
N32595187: length 1.6
  TOP w0.305: U36.6 26.13,72.88 26.12,72.89 C283.1
N33430702: length 3.1
  BOTTOM w0.191: Q15.5 130.43,6.61 130.56,6.48 130.56,5.97 R464.1 130.03,5.96 129.78,6.21 Q15.6
N33657189: length 11.7
  TOP w0.508: R148.2 19.94,63.39 C305.2 18.8,63.36 18.41,62.98 v2(18.41,61.97) R161.2 ; R170.2 v2(18.41,56.76)
  BOTTOM w0.508: v2(18.41,56.76) v2(18.41,61.97)
N33657272: length 2.5
  TOP w0.122: C312.2 22.15,59.5 22.71,59.5 23.2,60 L41.1
N33657370: length 2.4
  TOP w0.122: C316.2 22.07,59.15 22.63,59.15 23.18,58.6 L41.2
N33657483: length 6.8
  TOP w0.191: U42.5 40.77,62.47 40.39,62.85 40.39,65.86 40.44,65.92 v1(40.44,66.36) Y3.3
  BOTTOM w0.191: v1(40.44,66.36) 40.51,66.28 C746.1
N33657512: length 4.8
  TOP w0.191: Y3.1 42.42,64.86 v1(42.42,64.12) 42.42,63.61 41.72,62.91 41.71,62.91 41.27,62.47 U42.4
  BOTTOM w0.191: C749.1 v1(42.42,64.12)
N33657557: length 2.9
  TOP w0.191: v2(42.8,62.73) 42.27,62.2 U42.2
  BOTTOM w0.191: R363.2 43.52,62.98 43.26,62.73 v2(42.8,62.73)
N33657559: length 3.8
  TOP w0.191: U42.16 37.1,57.54 TP56.1
N33658409: length 3.4
  TOP w0.191: U50.7 v2(25.15,50.66)
  BOTTOM w0.191: v2(25.15,50.66) R391.1 R392.2
N33658469: length 3.4
  TOP w0.191: U50.8 v2(25.15,47.87)
  BOTTOM w0.191: v2(25.15,47.87) R407.2 R408.2
N33658487: length 3
  TOP w0.191: U50.6 v2(26.42,50.66)
  BOTTOM w0.191: R394.2 v2(26.42,50.66) R390.2
N33658532: length 4
  TOP w0.191: U50.14 v2(32.77,47.87)
  BOTTOM w0.191: v2(32.77,47.87) 33.15,48.25 R403.2 R405.2
N33658660: length 2.4
  TOP w0.191: U50.9 v2(26.42,45.07)
  BOTTOM w0.191: v2(26.42,45.07) 26.42,46.09
N33658666: length 4.1
  BOTTOM w0.191: R404.1 R409.2 C788.1
N33658711: length 2.4
  TOP w0.191: U50.4 v2(28.96,53.46)
  BOTTOM w0.191: v2(28.96,53.46) 28.96,52.44
N33658728: length 2.4
  TOP w0.191: U50.1 v2(32.77,53.46)
  BOTTOM w0.191: v2(32.77,53.46) 32.77,52.44
N289339640: length 2.8
  TOP w0.305: U8.3 103.8,132.54 103.38,132.96 C33.1

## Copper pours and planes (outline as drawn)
DGND on TOP: 119.13,11.55 119.13,13.07 119.51,13.45 119.51,14.47 118.36,14.47 117.98,14.09 116.46,14.09 116.2,14.34 116.2,15.1 116.46,15.36 118.11,15.36 118.36,15.1 119.51,15.1 119.51,15.74 120.52,15.74 120.52,15.1 121.41,15.1 121.41,14.59 120.52,14.59 120.52,11.55 120.27,11.29 119.38,11.29
DGND on TOP: 119.13,5.2 119.13,6.72 119.51,7.1 119.51,8.12 118.36,8.12 117.98,7.74 116.46,7.74 116.2,7.99 116.2,8.75 116.46,9.01 118.11,9.01 118.36,8.75 119.51,8.75 119.51,9.39 120.52,9.39 120.52,8.63 121.41,8.63 121.41,8.24 120.52,8.24 120.52,5.2 120.27,4.94 119.38,4.94
DGND on TOP: 37.21,9.64 37.21,3.04 36.7,2.53 30.99,2.53 30.61,2.91 30.61,4.43 29.97,5.07 29.97,7.23 30.73,7.99 30.73,9.26 31.5,10.02 36.83,10.02
DGND on TOP: 60.45,22.6 60.45,27.42 60.96,27.93 60.96,29.07 61.28,29.39 67.44,29.39 68.96,27.87 68.96,22.6 68.83,22.47 60.58,22.47
DGND on TOP: 139.7,99.05 137.16,99.05 137.16,95.75 139.7,95.75 139.7,95.24 142.88,95.24 142.88,99.56 139.7,99.56
DGND on TOP: 192.02,151.5 201.42,142.1 201.42,106.92 190.25,106.92 190.25,110.73 188.09,112.89 188.09,114.67 187.2,115.56 185.42,115.56 184.91,115.05 184.91,114.67 173.74,114.67 173.74,115.56 173.48,115.81 171.2,115.81 170.31,114.92 170.31,109.46 168.15,107.3 157.35,107.3 157.35,140.96 167.89,151.5
DGND on TOP: 95.25,133.34 96.77,133.34 97.16,132.96 98.17,132.96 98.17,134.1 97.79,134.48 97.79,136.01 98.04,136.26 98.81,136.26 99.06,136.01 99.06,134.36 98.81,134.1 98.81,132.96 99.44,132.96 99.44,131.94 98.68,131.94 98.68,131.05 98.17,131.05 98.17,131.94 95.25,131.94 95,132.2 95,133.09
DGND on TOP: 175.13,35.93 175.13,26.91 176.78,25.26 189.23,25.26 190.88,26.91 190.88,36.06 189.87,37.07 176.28,37.07
DGND on TOP: 78.23,98.16 78.23,100.7 74.93,100.7 74.93,98.16 74.42,98.16 74.42,94.99 78.74,94.99 78.74,98.16
DGND on TOP: 34.92,22.34 38.99,22.34 39.37,21.96 40.39,21.96 40.39,19.93 39.88,19.42 39.88,19.04 40.26,18.66 41.4,18.66 41.66,18.91 41.66,19.8 41.15,20.31 41.15,24.5 40.77,24.88 35.43,24.88 34.54,23.99 34.54,22.72
DGND on TOP: 132.84,91.56 134.49,91.56 135.38,90.67 135.38,86.48 133.86,86.48 133.86,89.02 132.84,90.03
DGND on TOP: 101.35,15.99 101.35,12.31 99.69,10.66 94.74,10.66 94.23,11.17 94.23,12.94 93.6,13.58 92.84,13.58 92.46,13.2 92.46,10.53 92.71,10.28 92.71,6.47 93.22,5.96 94.11,5.96 94.49,6.34 94.49,6.97 94.74,7.23 100.08,7.23 100.84,6.47 100.84,2.66 101.09,2.4 102.49,2.4 103.63,3.55 103.63,15.61 102.87,16.37 101.73,16.37
DGND on TOP: 74.93,114.67 74.93,112.13 78.23,112.13 78.23,114.67 78.74,114.67 78.74,117.85 74.42,117.85 74.42,114.67
DGND on TOP: 123.19,95.75 125.73,95.75 125.73,99.05 123.19,99.05 123.19,99.56 120.02,99.56 120.02,95.24 123.19,95.24
DGND on TOP: 181.61,91.3 181.61,89.27 182.12,88.76 186.06,88.76 186.18,88.89 186.18,91.3 185.8,91.68 181.99,91.68
DGND on TOP: 53.85,9.64 53.85,3.04 53.34,2.53 47.62,2.53 47.24,2.91 47.24,4.43 46.61,5.07 46.61,7.23 47.37,7.99 47.37,9.26 48.13,10.02 53.47,10.02
DGND on TOP: 196.72,57.77 196.34,57.39 196.34,56.63 196.72,56.25 196.72,48.12 196.98,47.87 197.49,47.87 198.12,48.5 198.12,48.76 198.63,48.76 198.88,49.01 198.88,54.85 199.9,55.87 199.9,60.7 197.49,60.7 196.72,59.93
DGND on TOP: 157.86,26.02 157.86,25.01 157.61,24.75 154.31,24.75 153.29,25.77 153.29,26.66 153.54,26.91 154.56,26.91 155.57,27.93 155.57,29.2 155.19,29.2 155.19,30.98 155.7,30.98 155.7,32.25 156.46,33.01 156.46,36.44 156.72,36.69 159.13,36.69 162.37,33.45 162.37,32.57 162.31,32.5 156.84,32.5 156.59,32.25 156.59,30.98 156.97,30.98 156.97,29.2 156.08,29.2 156.08,27.8 155.57,27.29 155.57,25.64 155.96,25.26 156.34,25.26 156.72,25.64 156.72,25.9 156.97,26.15 157.73,26.15
DGND on TOP: 70.74,105.02 70.74,103.37 69.85,102.48 65.66,102.48 65.66,104 68.2,104 69.22,105.02
DGND on TOP: 177.55,42.03 192.79,42.03 192.79,69.08 191.26,70.6 177.55,70.6 177.55,56.38 177.1,55.93 176.72,55.93 176.66,56 176.15,56 175.26,55.11 175.26,50.92 176.91,50.92 177.55,50.28 ; 1 cut-out
DGND on TOP: 0.64,1.39 0.64,151.88 202.56,151.88 202.56,1.39 ; 10 cut-outs
DGND on TOP: 4.95,75.68 4.95,78.35 7.11,78.35 7.11,75.94 7.75,75.94 7.75,78.35 10.54,78.35 11.18,77.71 13.84,77.71 14.48,78.35 14.48,81.9 13.72,82.67 12.45,82.67 11.68,81.9 4.95,81.9 4.95,83.94 3.56,85.33 2.41,85.33 2.03,84.95 2.03,75.81 2.54,75.3 4.57,75.3
DGND on TOP: 150.88,17.64 151.13,17.64 152.78,15.99 152.78,11.8 152.91,11.67 154.31,11.67 154.81,11.17 160.78,11.17 162.43,9.51 163.96,9.51 165.1,10.66 165.1,15.36 166.5,16.75 167.39,16.75 167.89,17.26 167.89,18.4 167.51,18.79 166.5,18.79 164.47,20.82 162.05,20.82 162.05,17.39 162.18,17.26 164.34,17.26 164.59,17.01 164.59,14.59 164.21,14.21 160.02,14.21 159.77,14.47 159.77,16.5 158.88,16.5 158.75,16.37 158.75,13.96 156.97,13.96 156.97,16.12 156.84,16.25 155.45,16.25 154.31,17.39 154.31,20.69 150.75,20.69 150.62,20.56 150.62,17.9
DGND on TOP: 70.48,9.64 70.48,3.04 69.98,2.53 64.26,2.53 63.88,2.91 63.88,4.43 63.25,5.07 63.25,7.23 64.01,7.99 64.01,9.26 64.77,10.02 70.1,10.02
DGND on TOP: 115.19,141.21 103.63,141.21 103.63,150.48 104.65,151.5 108.97,151.5 109.86,150.61 115.95,150.61 115.95,144.01 116.2,143.75 116.2,142.23
DGND on TOP: 87.12,9.64 87.12,3.04 86.61,2.53 80.9,2.53 80.52,2.91 80.52,4.43 79.88,5.07 79.88,7.23 80.64,7.99 80.64,9.26 81.41,10.02 86.74,10.02
DGND on BOTTOM: 73.3,104.89 73.3,107.56 72.92,107.56 72.69,107.79 72.69,110.43 72.87,110.61 72.9,110.61 72.9,111.37 74.42,112.89 74.42,117.85 78.74,117.85 78.74,114.67 78.11,114.04 78.11,111.47 78.71,110.86 79.38,110.86 79.38,109.21 79.32,109.21 79.32,105.93 79.55,105.7 81.23,105.7 81.23,102.22 78.23,102.22 78.11,102.1 78.11,98.67 78.74,98.03 78.74,94.99 74.42,94.99 74.42,98.03 74.45,98.03 75.07,98.66 75.06,98.67 75.06,101.92 72.64,101.92 72.64,104.61 72.92,104.89
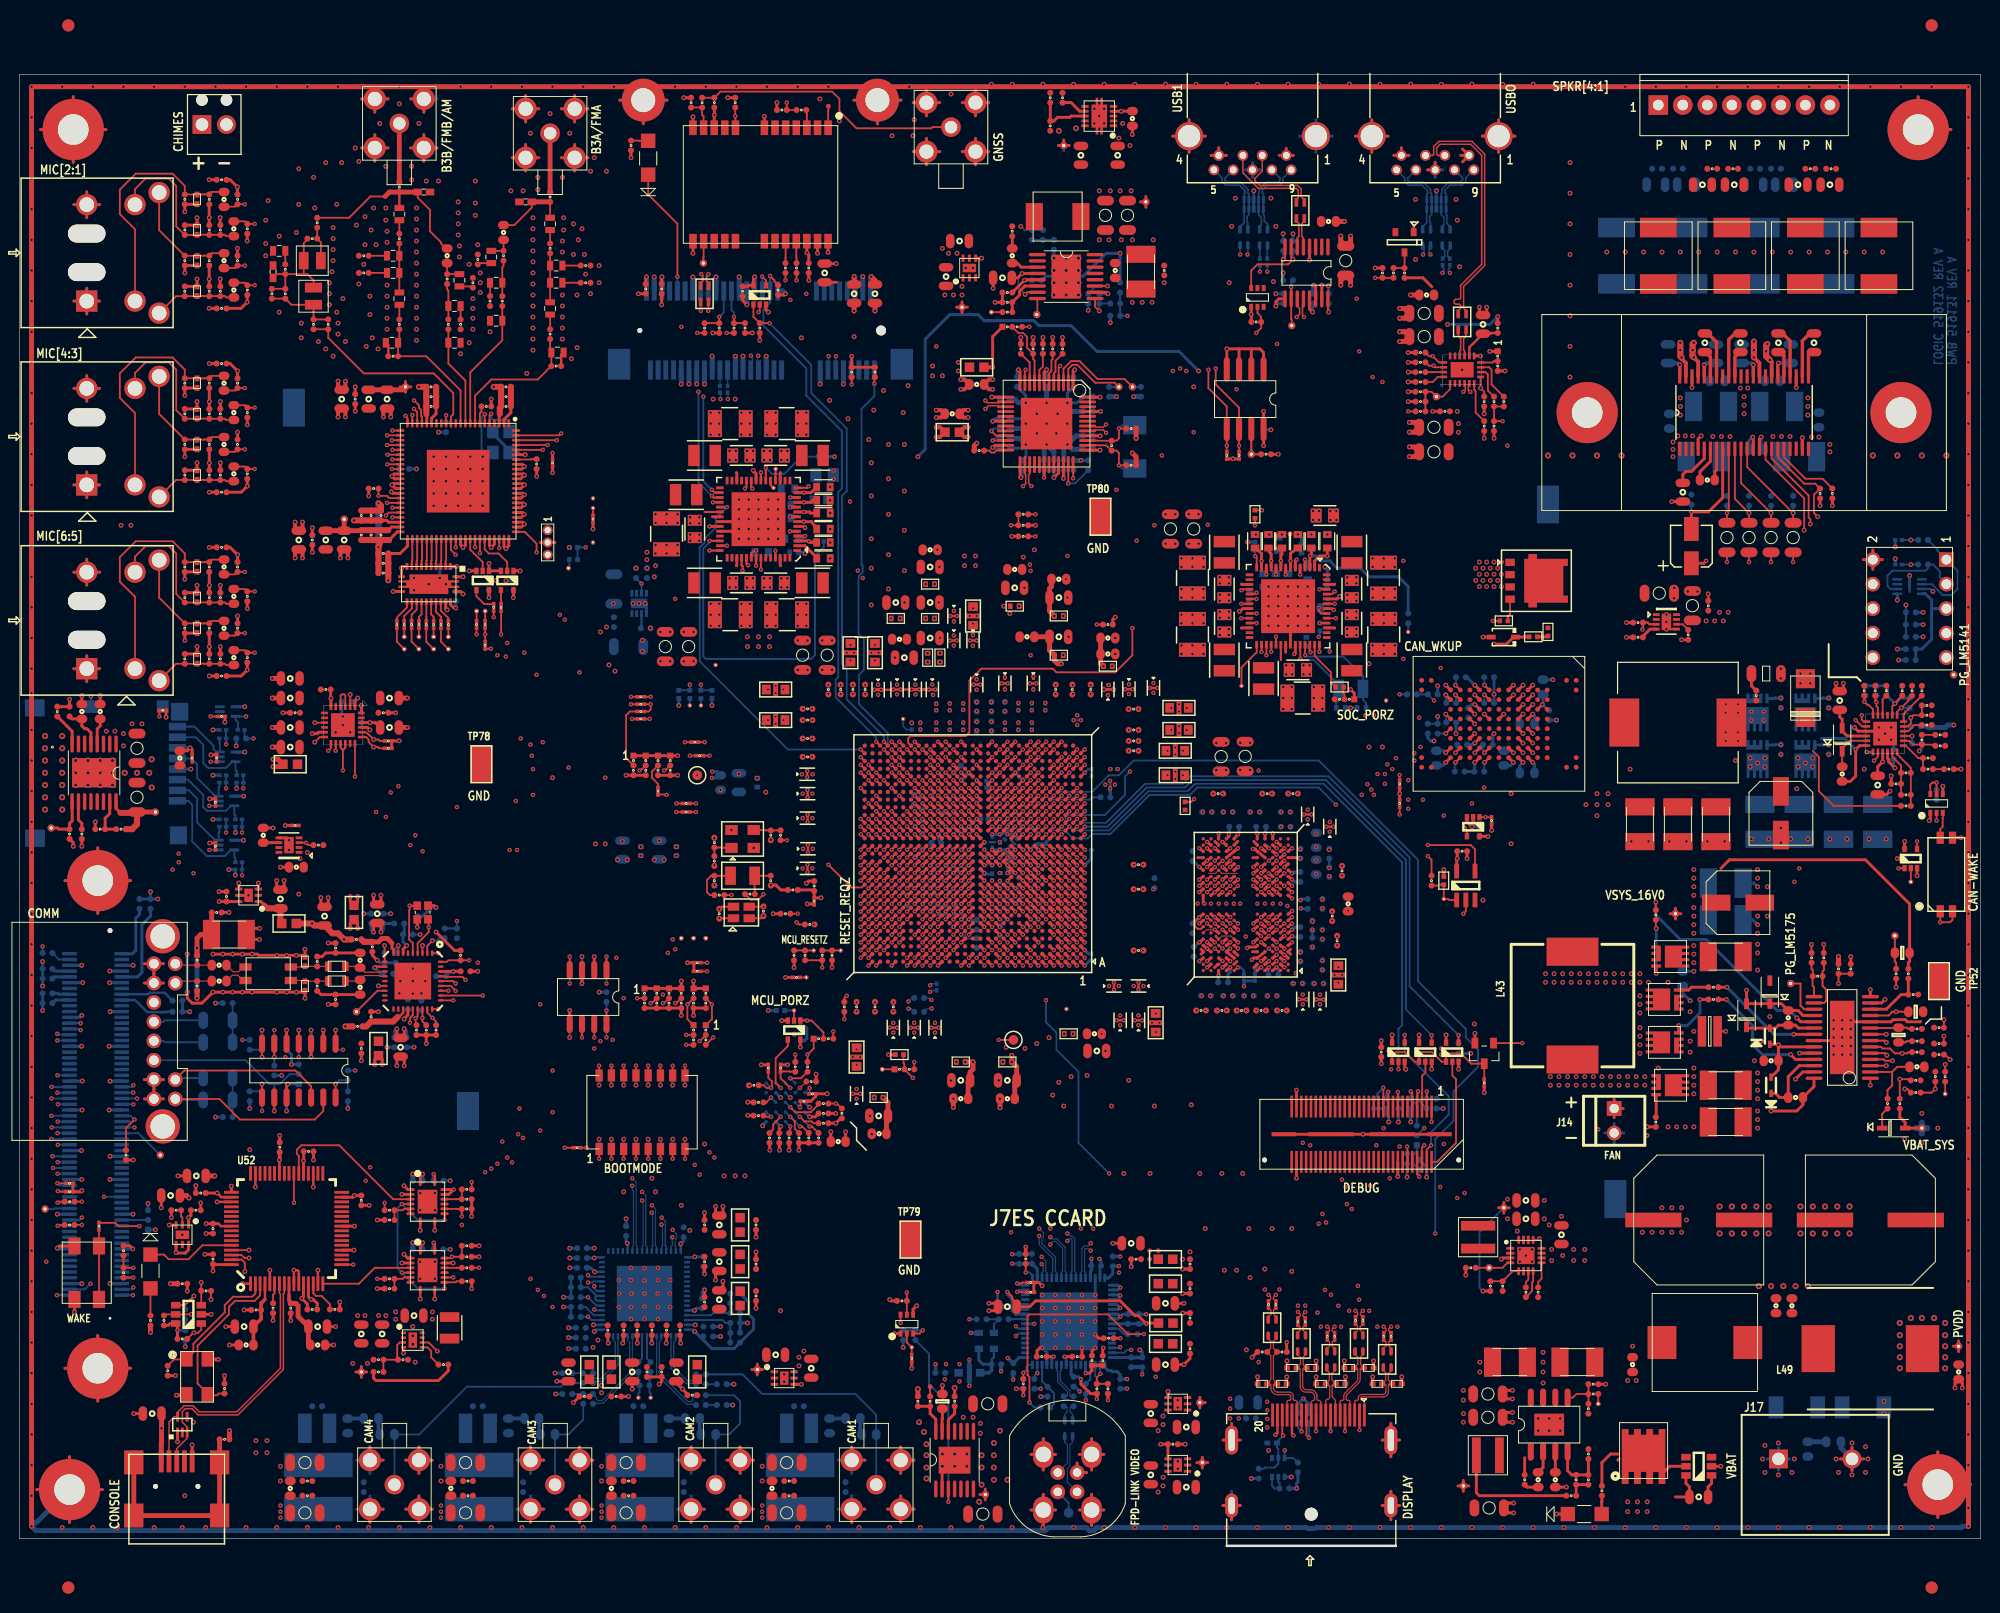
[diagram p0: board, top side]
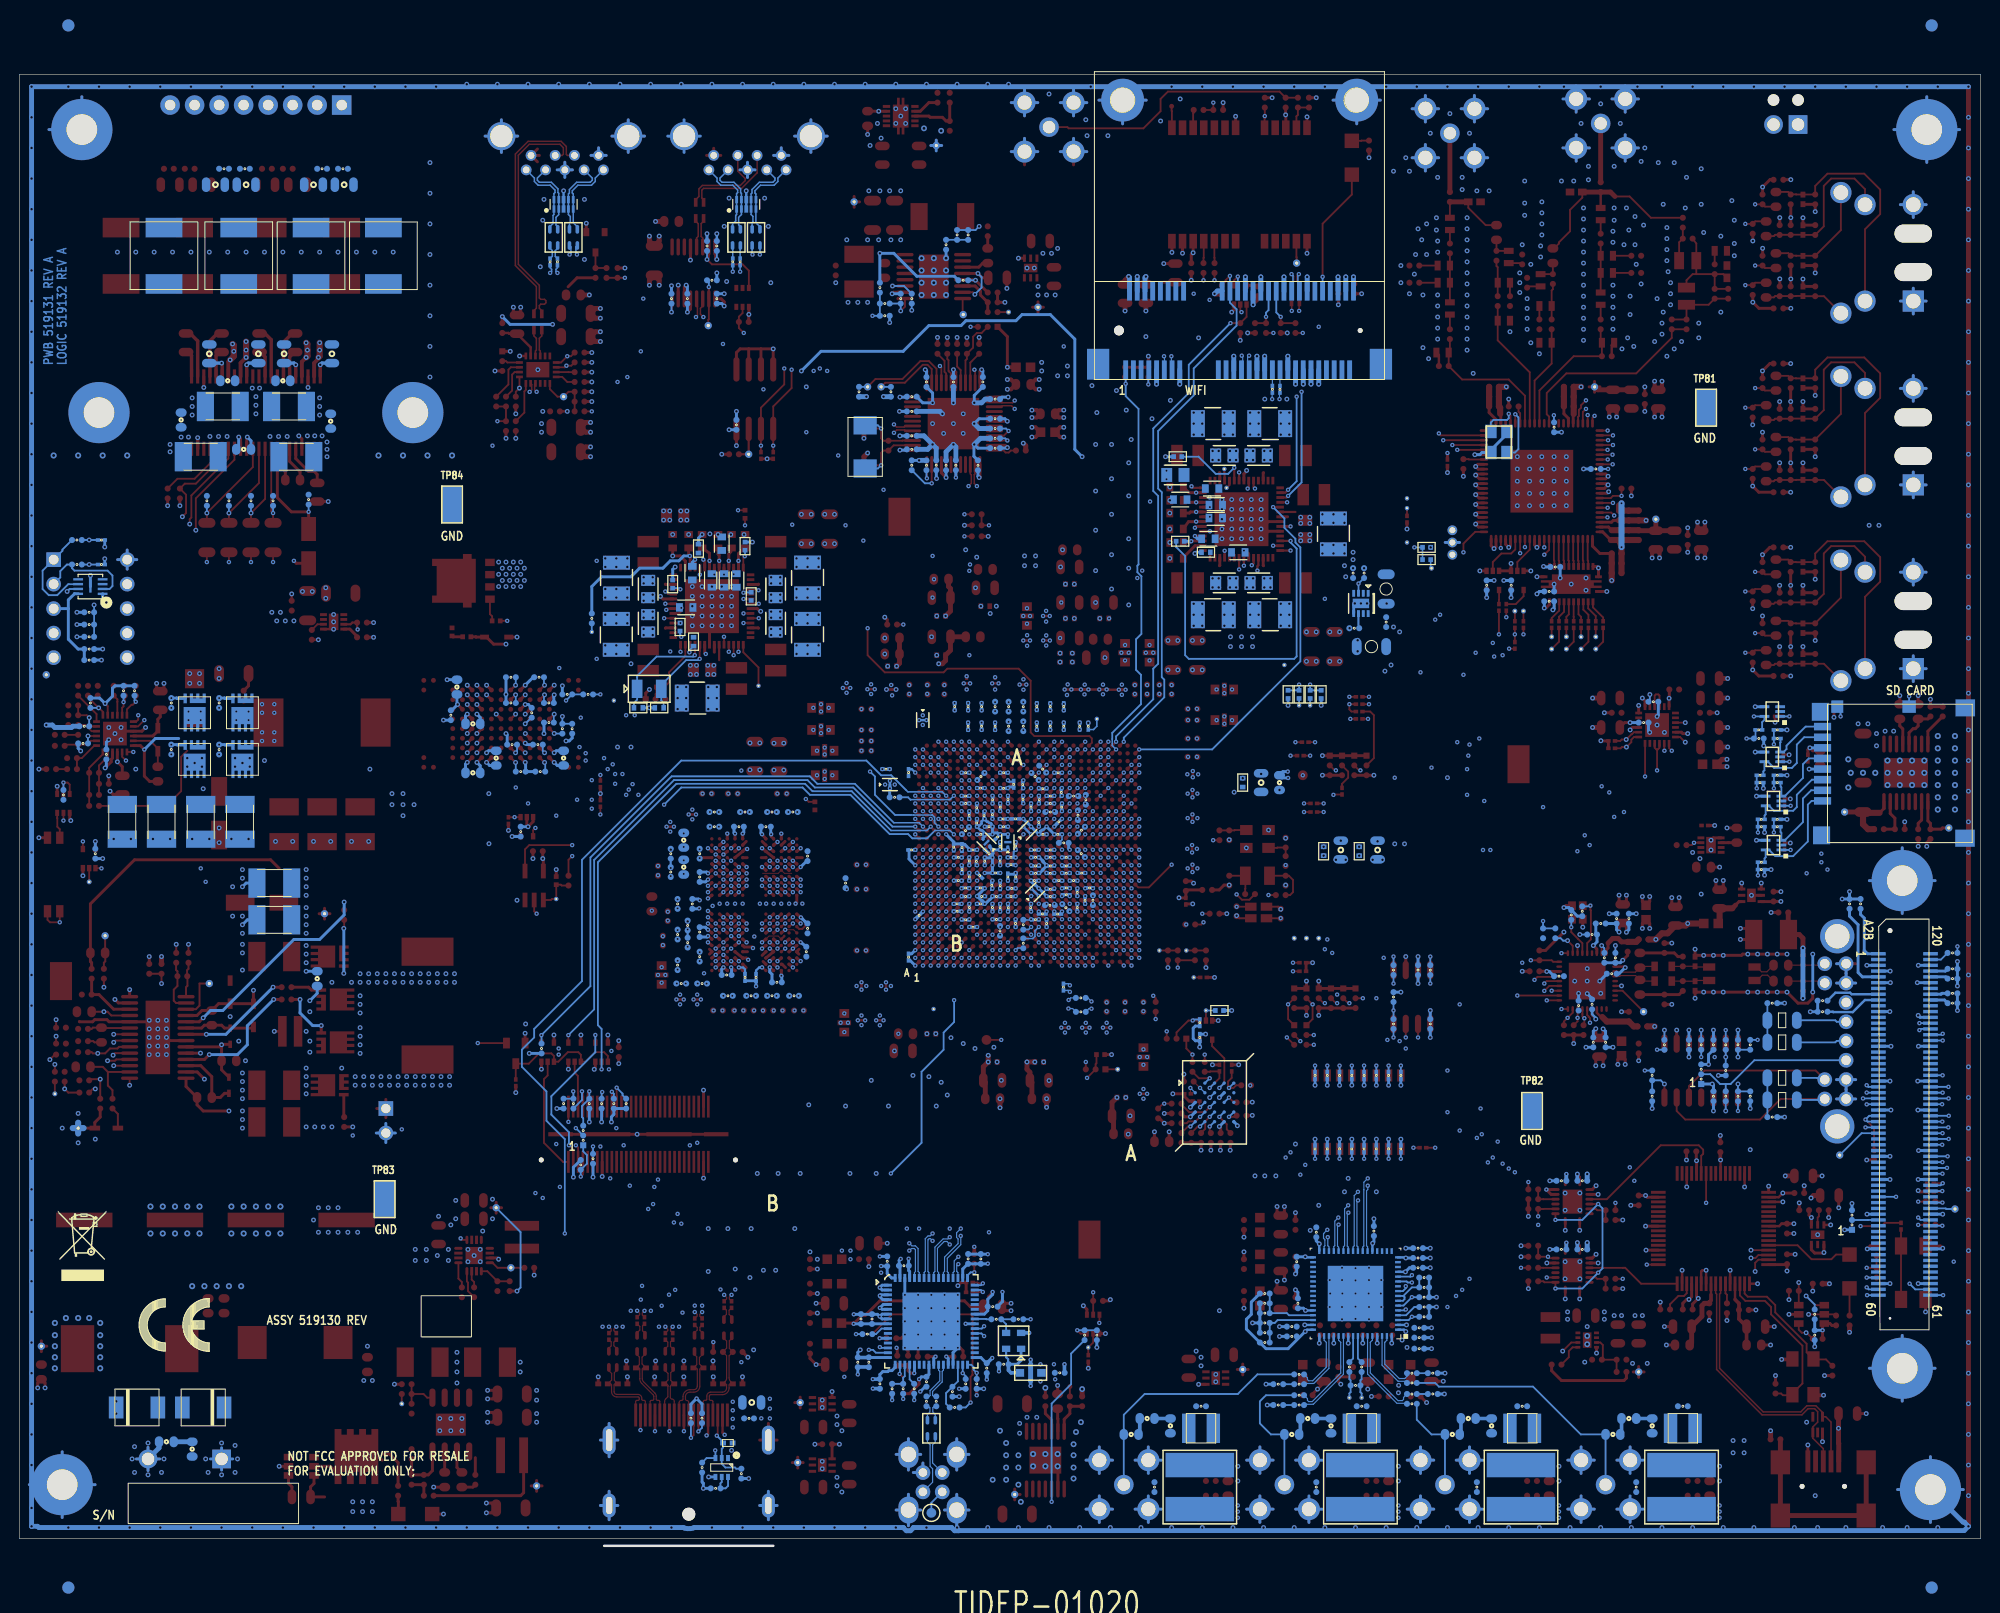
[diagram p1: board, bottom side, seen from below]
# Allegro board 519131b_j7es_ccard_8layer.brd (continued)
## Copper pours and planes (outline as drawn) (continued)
DGND on BOTTOM: 190.12,151.88 166.12,151.88 158.24,144.01 158.24,112.51 163.83,106.92 189.74,106.92 196.85,114.04 196.85,145.15
DGND on BOTTOM: 65.91,17.01 65.91,14.34 67.56,12.69 70.36,12.69 70.99,12.05 73.41,12.05 74.42,13.07 74.42,14.85 73.79,15.48 68.58,15.48 66.8,17.26 66.17,17.26
DGND on BOTTOM: 177.93,74.79 177.93,71.36 193.42,71.36 194.18,72.13 194.18,74.41 193.68,74.92 178.05,74.92
DGND on BOTTOM: 111,72.51 111,60.31 110.36,59.68 105.66,59.68 105.66,71.49 106.68,72.51
DGND on BOTTOM: 132.97,94.12 130.3,94.12 130.3,93.74 130.07,93.51 127.43,93.51 127.25,93.69 127.25,95.87 123.7,95.87 123.06,95.24 120.02,95.24 120.02,99.56 123.19,99.56 123.83,98.92 126.39,98.92 127,99.53 127,100.19 128.65,100.19 128.65,100.14 132.03,100.14 132.33,100.45 132.33,100.7 132.59,100.95 135.13,100.95 135.64,100.45 135.64,99.05 135.76,98.92 139.19,98.92 139.83,99.56 142.88,99.56 142.88,95.24 139.83,95.24 139.83,95.27 139.2,95.89 139.19,95.87 135.94,95.87 135.94,93.46 133.25,93.46 132.97,93.74
DGND on BOTTOM: 178.82,87.24 186.44,87.24 186.56,87.37 186.56,91.3 186.18,91.68 179.07,91.68 178.82,91.43
DGND on BOTTOM: 124.99,16 126.72,16 127.09,15.63 127.09,13.59 127.35,13.34 127.35,9.78 126.71,9.14 125.06,9.14 124.55,9.65 124.55,15.56
DGND on BOTTOM: 0.64,1.39 0.64,151.88 202.56,151.88 202.56,1.39 ; 4 cut-outs
DGND on L2-SIGNAL: 202.56,1.39 148.46,1.39 148.46,20.56 150.11,22.21 158.37,22.21 163.32,27.17 163.32,31.23 162.18,32.37 161.29,32.37 156.21,37.45 156.21,66.41 165.86,76.06 165.86,102.99 137.92,130.93 65.15,130.93 61.85,127.62 61.85,122.29 57.21,117.66 57.21,96.07 51.44,90.29 51.44,41.77 41.91,32.25 41.91,30.72 44.58,28.06 53.09,28.06 59.69,34.66 63.88,34.66 68.58,29.96 87.38,29.96 93.34,35.93 98.04,35.93 105.28,28.69 112.39,28.69 112.39,22.21 110.62,20.44 106.43,20.44 105.03,19.04 101.98,19.04 95.63,25.39 42.29,25.39 38.23,21.33 38.23,19.67 29.97,19.67 17.91,7.61 14.86,7.61 14.22,8.24 14.22,17.13 13.34,18.02 13.34,23.1 8.13,28.31 8.13,66.41 17.4,66.41 18.41,67.43 18.41,75.3 16.76,76.95 0.76,76.95 0.64,77.08 0.64,151.88 202.56,151.88
DGND on L2-SIGNAL: 132.59,54.09 132.59,41.52 133.73,40.38 133.73,25.14 133.35,24.75 124.71,24.75 119.25,19.29 119.13,19.42 119.13,31.87 117.73,33.26 113.41,33.26 106.93,39.74 106.93,58.54 107.06,58.66 113.16,58.66 114.3,57.52 120.78,57.52 121.54,56.76 121.54,54.47 121.92,54.09
DGND on L3-GND: 0.64,1.39 0.64,151.88 202.56,151.88 202.56,1.51 202.44,1.39
DGND on L4-SIGNAL: 117.98,151.5 117.98,140.45 119.13,139.31 139.7,139.31 142.24,136.77 148.84,136.77 156.46,129.15 156.46,105.15 157.99,103.62 157.99,96.76 154.18,92.95 153.8,92.95 153.16,92.32 153.16,84.95 140.97,72.76 139.83,72.76 138.68,71.62 138.68,58.28 134.11,53.71 101.85,53.71 100.97,52.82 100.97,50.41 102.74,48.63 102.74,47.23 115.7,34.28 115.7,32.76 117.09,31.36 121.54,31.36 122.05,30.85 122.05,22.47 124.84,19.67 125.09,19.67 125.09,5.96 122.17,5.96 122.05,5.83 122.05,1.77 202.06,1.77 202.18,1.89 202.18,151.12 201.8,151.5 ; 1 cut-out
DGND on L5-SIGNAL: 121.54,55.23 121.54,55.62 121.67,55.74 122.43,55.74 122.56,55.87 128.65,55.87 131.95,59.17 131.95,63.24 131.44,63.74 131.44,73.52 129.41,75.55 121.92,75.55 121.79,75.68 121.79,76.32 122.05,76.57 137.79,76.57 140.34,74.03 140.34,60.19 134.11,53.96 122.81,53.96
DGND on L5-SIGNAL: 1.27,2.02 1.27,151.25 201.93,151.25 201.93,2.02 ; 1 cut-out
DGND on L6-PWR: 151,1.39 151,12.05 163.45,12.05 165.86,14.47 165.86,29.2 202.56,29.2 202.56,1.39
DGND on L7-SIGNAL: 157.35,110.23 157.35,110.35 152.27,115.43 124.08,115.43 118.36,109.72 99.06,109.72 89.15,119.62 64.26,119.62 64.26,103.49 33.4,72.63 27.69,72.63 27.56,72.76 20.95,72.76 10.29,62.09 2.16,62.09 0.89,63.36 0.89,151.12 1.65,151.88 202.56,151.88 202.56,1.39 26.54,1.39 26.54,14.72 28.83,17.01 39.24,17.01 40.26,18.02 40.26,22.21 38.23,24.25 5.46,24.25 5.46,56.63 16.38,67.55 80.14,67.55 84.71,62.98 84.71,53.96 83.82,53.08 77.85,53.08 72.14,47.36 72.14,33.77 72.52,33.39 152.02,33.39 163.45,44.82 163.45,104.13
PVDD on TOP: 179.2,121.91 179.2,120.39 179.58,120 179.58,116.45 179.32,116.19 177.93,116.19 177.67,116.45 177.67,119.88 178.18,120.39 178.18,121.91
PVDD on TOP: 173.48,112.89 173.48,115.31 173.23,115.56 171.45,115.56 170.69,114.8 170.69,112.64 171.07,112.26 172.85,112.26
PVDD on TOP: 194.69,18.02 201.29,18.02 201.29,37.07 201.04,37.33 193.68,37.33 191.77,35.42 191.77,20.94
PVDD on TOP: 185.61,115.24 185.17,114.8 185.17,112.64 185.55,112.26 187.32,112.26 187.83,112.77 187.83,114.54 187.13,115.24
PVDD on BOTTOM: 176.02,121.27 175.77,121.02 175.77,115.94 181.23,115.94 181.23,120.77 180.72,121.27
PVDD on BOTTOM: 173.99,111.24 173.99,114.8 172.47,116.32 170.43,116.32 169.54,115.43 169.54,111.62 169.93,111.24
PVDD on BOTTOM: 185.17,111.11 187.83,111.11 187.83,115.69 187.07,116.45 186.06,116.45 185.17,115.56
PVDD on L5-SIGNAL: 168.15,122.04 168.15,103.11 186.18,85.08 186.18,20.94 190.75,16.37 201.29,16.37 201.29,118.48 196.22,123.56 169.67,123.56
V3V3_DP0 on TOP: 128.67,15.19 129.99,15.19 129.99,11.99 129.92,11.99 129.92,7.86 127.89,5.83 124.84,5.83 124.21,5.2 121.54,5.2 121.28,5.45 121.28,6.47 120.65,7.1 120.65,7.86 121.67,7.86 121.92,8.12 121.92,9.13 122.17,9.39 124.71,9.39 125.09,9.01 126.36,9.01 127.89,10.53 127.89,12.29 128.67,13.07
V3V3_DP0 on BOTTOM: 129.5,15.62 129.5,12.07 129.38,11.94 128.11,11.94 127.85,12.19 127.85,13.84 127.73,13.97 127.73,15.62 127.85,15.75 129.38,15.75
V941_IO_1V1 on TOP: 120.65,14.21 121.79,14.21 121.79,15.99 119,18.79 119,27.8 119.51,28.31 123.7,28.31 124.21,27.8 124.21,13.07 122.68,11.55 121.54,11.55 121.28,11.8 121.28,12.94 120.65,13.58
V960_IO_1V1 on TOP: 69.6,17.9 69.6,16.37 69.85,16.12 69.85,15.36 70.1,15.1 74.8,15.1 77.6,17.9 78.61,17.9 78.61,18.28 77.98,18.91 77.98,28.31 76.96,29.33 74.04,29.33 74.04,25.77 75.56,25.77 75.56,22.34 71.12,17.9
VBAT on TOP: 165.48,8.12 165.48,2.4 184.02,2.4 185.42,3.8 185.42,11.8 183.77,13.45 176.28,13.45 174.75,11.93 174.75,8.63 176.02,8.63 176.02,4.94 175.39,4.31 172.59,4.31 172.34,4.56 172.34,5.7 171.96,6.09 171.96,8.12
VBAT on BOTTOM: 186.18,9.51 186.18,7.74 184.53,6.09 180.34,6.09 178.94,7.48 178.94,14.09 180.85,15.99 183.01,15.99 183.26,15.74 183.26,10.53 183.9,9.9 185.8,9.9
VBAT on L6-PWR: 165.48,2.66 182.75,2.66 185.42,5.32 185.42,10.66 183.39,12.69 168.4,12.69 164.97,9.26 164.97,3.16
VBAT_SYS on TOP: 170.31,50.15 176.78,50.15 176.78,38.22 174.5,35.93 174.5,20.82 172.72,19.04 166.75,19.04 164.72,21.07 164.72,46.85 170.31,46.85
VBAT_SYS on BOTTOM: 197.36,82.29 197.74,82.67 197.74,83.56 196.72,84.57 196.72,85.33 196.98,85.59 201.29,85.59 201.29,42.03 198.88,39.61 173.23,39.61 169.04,43.8 169.04,47.87 171.2,50.03 182.75,50.03 184.21,51.49 184.21,61.78 194.56,72.13 194.56,74.67 193.93,75.3 177.16,75.3 177.16,81.4 178.05,82.29
VBAT_SYS on L6-PWR: 177.67,81.9 187.58,81.9 187.58,60.31 202.56,60.31 202.56,29.58 165.86,29.58 165.86,31.61 179.45,45.2 179.45,71.36 177.67,71.36
VBUS2_5V0 on TOP: 134.24,133.47 135,133.47 135.25,133.72 135.25,135.5 135.83,136.07 135.83,137.21 136.02,137.4 136.02,138.02 136.01,138.03 136.01,139.56 138.05,141.61 138.05,148.2 136.27,149.98 131.06,149.98 130.43,149.34 130.43,143.63 130.68,143.37 131.83,143.37 132.84,144.39 132.84,147.56 133.22,147.94 133.99,147.94 134.37,147.56 134.37,141.47 133.99,141.09 133.99,133.72
VBUS_USBC_CONN on TOP: 148.97,122.93 147.96,122.93 147.96,123.05 147.19,123.05 146.11,124.13 146.11,130.67 146.18,130.67 146.18,142.23 148.84,144.9 150.11,144.9 151.26,143.75 151.26,133.47 148.46,130.67 148.46,125.34 148.97,124.83
VCC_1V1USB on TOP: 99.44,122.8 99.44,120 99.82,119.62 101.09,119.62 101.35,119.88 101.35,122.29 100.71,122.93 99.57,122.93
VCC_1V1USB on L5-SIGNAL: 100.71,123.18 109.6,123.18 112.27,120.51 112.27,113.91 108.46,110.1 106.68,110.1 105.66,111.11 101.47,111.11 99.57,113.02 99.57,122.04
VCCA_3V3 on TOP: 78.61,113.78 78.61,110.23 78.74,110.1 78.99,110.1 78.99,111.11 79.88,112 79.88,113.78
VCCA_3V3 on TOP: 74.55,99.05 74.55,102.61 74.42,102.73 74.17,102.73 74.17,101.72 73.28,100.83 73.28,99.05
VCCA_3V3 on TOP: 74.55,113.78 74.55,110.23 74.42,110.1 74.17,110.1 74.17,111.11 73.28,112 73.28,113.78
VCCA_3V3 on TOP: 138.81,99.43 135.25,99.43 135.13,99.56 135.13,99.81 136.14,99.81 137.03,100.7 138.81,100.7
VCCA_3V3 on TOP: 124.08,99.43 127.64,99.43 127.76,99.56 127.76,99.81 126.75,99.81 125.86,100.7 124.08,100.7
VCCA_3V3 on TOP: 138.81,95.37 135.25,95.37 135.13,95.24 135.13,94.99 136.14,94.99 137.03,94.1 138.81,94.1
VCCA_3V3 on TOP: 124.08,95.37 127.64,95.37 127.76,95.24 127.76,94.99 126.75,94.99 125.86,94.1 124.08,94.1
VCCA_3V3 on TOP: 131.37,93.79 131.06,93.79 131.06,90.16 132.08,90.16 132.08,91.68 131.44,92.32 131.44,93.72
VCCA_3V3 on TOP: 71.63,106.29 72.97,106.29 72.97,106.8 69.34,106.8 69.34,105.78 71.12,105.78
VCCA_3V3 on TOP: 135.51,108.57 153.92,108.57 155.32,107.18 155.32,95.37 153.67,93.72 136.91,93.72 136.4,94.22 136.4,94.86 136.14,95.11 135.13,95.11 135.13,95.37 136.91,95.37 137.54,96 138.43,96 138.43,99.18 136.53,99.18 136.27,99.43 135.13,99.43 135.13,100.45 136.53,101.84 136.53,104.76 135.51,105.78
VCCA_3V3 on TOP: 78.61,99.05 78.61,102.61 78.74,102.73 78.99,102.73 78.99,101.72 79.88,100.83 79.88,99.05
VCCA_3V3 on BOTTOM: 128.4,100.32 131.7,100.32 132.46,101.08 133.99,101.08 133.99,102.86 133.6,103.24 132.46,103.24 132.21,103.49 129.54,103.49 129.54,101.72 129.16,101.34 128.4,101.34
VCCA_3V3 on BOTTOM: 65.41,98.41 62.87,98.41 62.87,99.18 62.1,99.94 60.58,99.94 59.82,100.7 59.82,102.61 60.58,103.37 65.53,103.37 66.42,102.48 66.42,100.32 65.41,99.3
VCCA_3V3 on BOTTOM: 81.41,111.88 83.31,111.88 83.31,109.97 82.68,109.34 82.68,107.3 81.41,106.03 79.63,106.03 79.63,108.83 79.88,109.08 79.88,110.35
VCCA_3V3 on L4-SIGNAL: 157.48,97.65 157.48,103.11 152.91,107.69 135.51,107.69 132.59,104.76 131.83,104.76 131.76,104.83 125.29,104.83 123.06,102.61 123.06,92.57 125.6,90.03 132.02,90.03 134.49,92.51 135.06,92.51 135.13,92.45 137.67,92.45 141.35,96.13 155.96,96.13
VCCA_3V3 on L4-SIGNAL: 63.55,102.02 63.55,113.15 65.3,114.9 85.66,114.9 85.66,101.84 85.72,101.78 85.72,98.41 83.44,96.13 69.44,96.13
VCCA_3V3 on L5-SIGNAL: 63.88,118.73 63.88,98.08 82.42,98.08 82.42,104.76 80.77,106.42 80.77,118.73
VCCA_3V3 on L6-PWR: 157.48,118.79 160.66,115.61 160.66,101.97 157.48,98.8 144.91,98.8 143.89,99.81 143.89,103.62 142.62,104.89 136.14,104.89 132.84,101.59 127.25,101.59 126.62,100.95 126.62,94.73 125.73,93.84 124.08,93.84 123.51,94.41 123.51,103.81 122.81,104.51 111.02,104.51 111.01,104.52 111.01,103.51 111,103.49 97.18,103.49 91.72,98.03 74.3,98.03 74.23,98.1 73.34,98.1 72.77,98.67 72.77,100.7 73.66,101.59 73.66,105.4 69.72,105.4 69.22,105.91 69.22,107.3 69.28,107.37 69.28,114.86 74.3,119.88 111.51,119.88 112.6,118.79
VDD1_LPDDR4_1V8 on L2-SIGNAL: 127.38,77.84 125.48,77.84 123.57,75.94 123.57,74.54 125.98,72.13 125.98,71.11 124.46,69.59 124.46,68.7 124.71,68.44 124.71,64.63 124.33,64.25 124.33,63.62 124.71,63.24 125.73,63.24 126.11,62.85 126.11,59.43 124.71,58.03 122.43,58.03 122.43,55.49 123.06,54.85 133.86,54.85 137.6,58.6 137.6,79.56 138.3,80.25 138.3,82.41 138.68,82.79 138.68,86.86 139.7,87.87 139.7,100.07 135.51,104.26 129.03,104.26 128.02,103.24 128.02,101.72 129.03,100.7 129.03,79.49
VDD1_LPDDR4_1V8 on L7-SIGNAL: 121.79,57.77 131.95,57.77 134.75,60.57 134.75,74.79 133.1,76.44 121.79,76.44
VDD18_DSI on TOP: 115.57,28.85 118.62,28.85 118.62,30.77 118.58,30.81 118.58,31.53 117.98,32.12 115.82,32.12 115.57,31.87
VDD18_DSI on L2-SIGNAL: 114.81,14.85 104.39,14.85 103.76,15.48 103.76,16.37 104.78,17.39 112.65,17.39 114.94,19.67 114.94,28.95 114.3,29.58 112.9,29.58 112.39,29.07 111,29.07 110.62,29.45 110.62,29.96 113.35,32.69 117.79,32.69 118.62,31.87 118.62,18.66
VDD_1P0 on BOTTOM: 34.16,53.46 34.54,53.84 34.54,60.06 33.91,60.7 33.91,63.36 32,65.27 30.23,65.27 29.72,64.76 29.72,63.11 31.24,61.58 31.24,55.62 33.4,53.46
VDD_CORE_0V8 on TOP: 77.36,74.56 76.83,75.09 75.03,75.09 73.41,76.71 73.41,84.44 68.33,89.52 65.02,89.52 59.56,94.99 59.56,114.8 63.18,118.42 74.87,118.42 75.18,118.73 87.5,118.73 89.48,116.76 89.48,95.37 90.17,95.37 90.93,94.6 90.93,90.92 96.01,90.92 100.71,95.62 103.63,95.62 104.14,95.11 104.14,92.7 102.36,90.92 100.97,90.92 99.06,89.02 99.06,86.73 99.19,86.6 99.19,85.33 97.61,83.76 87.13,83.76 86.68,83.31 86.68,74.35 87.85,73.19 95.04,73.19 96.65,74.79 97.16,74.79 98.9,73.05 98.96,73.05 99.06,73.14 99.06,73.4 98.04,74.41 98.04,74.67 98.3,74.92 98.93,74.92 98.93,75.43 99.06,75.55 99.69,75.55 99.69,73.14 100.2,72.63 100.2,70.91 100.97,70.91 100.97,67.08 94.94,67.08 94.94,72.8 87.24,72.8 85.6,71.16 80.75,71.16 80.75,73.78 80.64,73.78 80.39,74.03 80.39,74.43 80.26,74.56
VDD_CORE_0V8 on BOTTOM: 81.92,98.03 81.92,92.45 71.25,92.45 71.25,98.03 73.15,98.03 73.15,95.11 73.66,94.6 79.5,94.6 80.01,95.11 80.01,98.03
VDD_CORE_0V8 on L2-SIGNAL: 103.89,72.38 107.21,72.38 107.21,65.24 97.54,65.24 97,65.78 96.65,65.78 96.52,65.65 95.25,65.65 94.36,66.54 94.36,70.6 93.22,71.74 81.41,71.74 79.5,73.65 78.74,73.65 75.74,76.65 75.74,79.31 64.77,90.29 64.77,115.43 67.82,118.48 74.8,118.48 75.31,118.99 88.14,118.99 99.63,107.5 99.63,73.84 100.97,72.51 100.97,68.7 103,68.7 103.89,69.59
VDD_CORE_0V8 on L4-SIGNAL: 99.31,46.34 99.31,67.43 98.3,68.44 95.76,68.44 95.25,67.93 95.25,64.12 96.01,63.36 96.01,58.92 96.39,58.54 96.39,50.66 95.89,50.15 95.89,45.71 96.52,45.07 98.04,45.07
VDD_CORE_0V8 on L6-PWR: 90.17,80.25 76.58,80.25 73.91,82.92 73.91,89.65 72.64,90.92 72.64,96 74.17,97.53 90.17,97.53
VDD_CORE_0V8 on L7-SIGNAL: 87.38,91.46 87.38,93.33 82.8,97.91 68.2,97.91 65.41,95.11 65.41,91.18 66.42,90.16 86.08,90.16
VDD_CORE_0V8_REG_SW1 on TOP: 73.99,110.78 73.99,110.1 73.15,110.1 73.15,110.23 71.5,111.88 71.5,114.16 72.64,114.16 72.64,112.13
VDD_CORE_0V8_REG_SW2 on TOP: 79.17,110.78 79.17,110.1 80.01,110.1 80.01,110.23 81.66,111.88 81.66,114.16 80.52,114.16 80.52,112.13
VDD_CORE_0V8_REG_SW3 on TOP: 73.99,102.05 73.99,102.73 73.15,102.73 73.15,102.61 71.5,100.95 71.5,98.67 72.64,98.67 72.64,100.7
VDD_CORE_0V8_REG_SW4 on TOP: 79.17,102.05 79.17,102.73 80.01,102.73 80.01,102.61 81.66,100.95 81.66,98.67 80.52,98.67 80.52,100.7
VDD_CORE_RAM_0V85 on BOTTOM: 72.14,78.84 72.14,77.1 77.6,77.1 77.6,78.73 77.48,78.84
VDD_CORE_RAM_0V85 on L6-PWR: 99,67.7 97.84,68.86 97.84,71.41 97.76,71.49 84.96,71.49 82.16,74.3 78.6,74.3 76.83,76.06 76.83,79.2 77.6,79.96 90.7,79.96 90.88,79.77 90.88,75.1 92.58,73.4 95,73.4 95,75.43 95.5,75.43 95.85,75.09 100.63,75.09 101.26,74.45 101.22,74.41 101.22,67.81 101.11,67.7
VDD_CPU_AVS on TOP: 99.82,73.27 99.9,73.2 99.9,71.62 101.35,71.62 101.35,69.33 103.58,69.33 103.58,73.35 104.39,74.16 108.58,74.16 111.38,76.95 121.41,76.95 123.32,78.86 123.32,81.5 128.27,81.5 128.27,83.43 127.38,84.32 127.38,89.65 125.86,91.18 124.33,91.18 124.27,91.24 124.27,92.06 123.44,92.06 123.44,93.72 123.19,93.97 120.4,93.97 119.76,94.6 119.76,99.81 119.89,99.94 122.81,99.94 123.44,100.57 123.44,102.73 123.83,103.11 126.11,103.11 126.62,103.62 126.62,104.89 125.98,105.53 118.11,105.53 115.95,103.37 115.95,92.95 113.54,90.54 101.22,90.54 99.82,89.14
VDD_CPU_AVS on BOTTOM: 119.63,94.5 119.64,94.48 119.65,94.46 120.13,93.98 120.14,93.97 120.16,93.97 123.01,93.97 123.05,93.95 123.06,93.92 123.06,92.12 123.05,92.08 123.01,92.06 119.38,92.06 117.86,93.59 117.86,101.34 119.25,102.73 123.01,102.73 123.05,102.72 123.06,102.68 123.06,100.88 123.05,100.84 123.01,100.83 120.42,100.83 120.4,100.82 120.38,100.81 119.65,100.08 119.64,100.06 119.63,100.04
VDD_CPU_AVS on L2-SIGNAL: 102.87,68.95 103.63,69.71 103.63,72.38 103.89,72.63 107.14,72.63 111.05,76.55 120.78,76.55 123.7,79.47 128.14,79.47 128.14,100.19 123.7,104.64 115.32,104.64 110.36,99.68 110.36,92.6 105.59,87.82 101.04,87.82 100.03,86.81 100.03,72.71 101.12,71.62 101.12,68.95
VDD_CPU_AVS on L6-PWR: 103.25,69.33 103.25,72.63 107.57,72.63 108.71,73.78 110.24,73.78 112.52,76.06 120.02,76.06 120.14,76.19 120.14,86.98 123.06,89.91 123.06,103.24 122.17,104.13 111.25,104.13 111.25,79.62 107.57,75.94 103.12,75.94 101.47,74.28 101.47,69.84 101.98,69.33
VDD_CPU_AVS_REG_SW1 on TOP: 127.08,94.81 127.76,94.81 127.76,93.97 127.64,93.97 125.98,92.32 123.7,92.32 123.7,93.46 125.73,93.46
VDD_CPU_AVS_REG_SW2 on TOP: 127.08,99.99 127.76,99.99 127.76,100.83 127.64,100.83 125.98,102.48 123.7,102.48 123.7,101.34 125.73,101.34
VDD_CPU_RAM_0V85 on TOP: 92.84,104.09 93.99,104.09 94.03,104.05 94.03,102.22 94.23,102.03 94.23,99.18 94.11,99.05 92.84,99.05
VDD_CPU_RAM_0V85 on L5-SIGNAL: 102.71,67.83 101.45,67.83 101.42,67.81 99.19,67.81 96.52,70.47 96.52,85.33 89.41,92.45 89.41,98.67 89.79,99.05 89.92,99.05 90.93,100.07 93.98,100.07 94.61,99.43 94.61,98.29 93.15,96.83 93.15,93.4 100.97,85.59 100.97,78.48 103,76.44 103,68.12
VDD_DDR_1V1 on TOP: 141.2,104.89 141.22,104.89 141.24,104.88 142.86,103.26 142.87,103.24 142.88,103.22 142.88,101.13 142.86,101.1 142.82,101.08 139.62,101.08 139.59,101.1 139.57,101.13 139.57,102.84 139.57,102.86 139.56,102.87 139.08,103.35 139.06,103.36 139.04,103.37 136.83,103.37 136.79,103.38 136.78,103.42 136.78,104.84 136.79,104.88 136.83,104.89
VDD_DDR_1V1 on TOP: 123.44,78.48 121.54,76.57 111.76,76.57 110.36,75.17 110.36,74.28 109.86,73.78 104.65,73.78 104.01,73.14 104.01,65.65 106.55,63.11 106.55,59.68 113.16,53.08 132.72,53.08 138.43,58.79 138.43,74.16 134.11,78.48 ; 15 cut-outs
VDD_DDR_1V1 on L4-SIGNAL: 137.92,73.27 137.92,59.17 133.22,54.47 107.44,54.47 103.25,58.66 103.25,69.71 110.11,76.57 134.62,76.57
VDD_DDR_1V1 on L6-PWR: 103.22,66.53 103.37,66.38 103.46,66.47 103.46,72.38 107.58,72.38 108.84,73.64 110.17,73.64 110.39,73.42 112.78,75.81 120.27,75.81 120.4,75.94 120.4,86.6 127,93.21 127,100.76 127.51,101.27 133.03,101.27 136.27,104.51 142.75,104.51 143.51,103.75 143.51,96.38 141.48,94.35 139.7,94.35 138.05,92.7 138.05,79.62 140.72,76.95 140.72,60.44 134.37,54.09 122.68,54.09 121.41,52.82 109.32,52.82 109.27,52.87 109.22,52.82 103.89,52.82 103.68,53.03 103.68,58.46 103.22,58.92
VDD_DDR_1V1_REG_SW on TOP: 135.81,99.99 135.13,99.99 135.13,100.83 135.25,100.83 136.91,102.48 139.19,102.48 139.19,101.34 137.16,101.34
VDD_IO_1V8 on L2-SIGNAL: 109.98,92.83 105.41,88.25 100.08,88.25 100.08,111.37 100.2,111.5 108.71,111.5 109.98,112.77 155.45,112.77 164.97,103.24 164.97,80.13 148.34,80.13 144.65,83.81 144.65,101.46 139.45,106.67 116.59,106.67 109.98,100.07
VDD_IO_1V8 on L5-SIGNAL: 80.9,107.81 99.44,107.81 105.41,101.84 105.41,88.76 104.78,88.13 102.23,88.13 101.73,88.64 101.73,97.78 97.92,101.59 83.44,101.59 82.68,102.35 82.68,104.76 80.9,106.54
VDD_IO_1V8 on L6-PWR: 104.5,77.82 106.68,80 106.68,87.14 102.08,87.14 101.17,88.05 101.17,92.24 108.46,92.24 108.55,92.15 108.58,92.19 110.74,92.19 111,91.94 111,79.75 107.31,76.06 105.03,76.06 104.5,76.6
VDD_IO_3V3 on TOP: 177.42,97.27 177.42,96.13 176.78,95.49 172.47,95.49 172.21,95.75 171.32,95.75 171.32,97.27
VDD_IO_3V3 on TOP: 37.08,118.1 37.08,117.46 36.32,116.7 32.89,116.7 32.51,117.08 32.51,118.1 33.02,118.61 36.58,118.61
VDD_IO_3V3 on TOP: 29.64,74.92 29.62,74.89 29.59,74.92 28.7,74.92 28.66,74.88 28.66,69.88 29.21,69.33 32.13,69.33 32.13,74.92
VDD_IO_3V3 on BOTTOM: 97.92,16.79 97.92,19.08 95.63,19.08 95.63,16.79
VDD_IO_3V3 on BOTTOM: 35.05,86.1 37.97,86.1 39.62,84.44 39.62,81.52 37.97,79.87 26.54,79.87 25.91,80.51 25.91,81.65 26.54,82.29 33.78,82.29 35.05,83.56
VDD_IO_3V3 on L4-SIGNAL: 95.5,93.97 99.57,93.97 100.84,95.24 100.84,108.83 96.52,113.15 96.52,122.42 96.14,122.8 93.34,122.8 92.84,122.29 92.84,99.56 93.98,98.41 93.98,95.49
VDD_IO_3V3 on L4-SIGNAL: 91.69,78.22 91.69,72.25 92.71,71.24 100.84,71.24 102.23,72.63 105.28,72.63 106.05,73.4 106.05,75.43 105.41,76.06 103.76,76.06 103.25,75.55 103.12,75.55 102.62,75.05 97.28,75.05 96.9,75.43 96.9,78.86 92.33,78.86
VDD_IO_3V3 on L6-PWR: 100.74,92.65 100.74,87.98 101.85,86.86 106.43,86.86 106.55,86.73 106.55,85.97 106.43,85.84 106.43,80.13 104.32,78.02 104.32,77.97 102.03,75.68 94.61,75.68 94.61,73.65 92.71,73.65 91.31,75.05 90.88,75.56 90.88,80.47 90.48,80.87 90.48,96.05 97.54,103.11 110.24,103.11 110.74,102.61 110.74,92.95 110.44,92.65
VDD_IO_3V3 on L6-PWR: 187.96,60.7 187.96,82.29 177.29,82.29 177.29,71.87 168.4,71.87 164.08,67.55 164.08,49.01 150.5,35.42 150.5,19.42 145.8,14.72 5.84,14.72 5.84,68.57 4.95,69.46 4.95,74.54 14.22,74.54 14.22,86.86 0.76,86.86 0.76,151.88 202.56,151.88 202.56,60.7
VDD_MCU_0V85 on TOP: 136.78,91.43 136.78,89.91 139.83,89.91 140.97,91.05 142.88,91.05 142.88,93.72 139.83,93.72 139.83,92.19 139.06,91.43
VDD_MCU_0V85 on L6-PWR: 88.52,41.26 85.87,43.91 85.87,57.75 85.87,57.72 85.87,59.19 93.85,67.17 93.85,67.55 93.34,68.06 93.34,69.74 94.61,71.01 95.3,71.01 95.3,70.58 95.55,70.58 95.81,70.83 96.88,70.83 97.03,70.68 97.03,68.67 97.71,67.99 97.71,66.16 97.66,66.16 96.77,65.27 96.77,63.87 97.66,62.98 97.71,62.98 97.71,59.04 98.04,58.71 98.04,51.42 100.58,48.88 104.2,48.88 107.31,52 121.86,52 123.19,53.33 134.87,53.33 141.86,60.31 141.86,77.97 138.81,81.02 138.81,89.65 140.34,91.18 140.34,91.56 139.64,92.26 139.64,93.65 139.95,93.97 150.37,93.97 153.8,90.54 153.8,55.49 149.22,50.92 149.22,47.11 143.51,47.11 137.67,41.26
VDD_MCU_0V85_REG_SW on TOP: 135.81,94.81 135.13,94.81 135.13,93.97 135.25,93.97 136.91,92.32 139.19,92.32 139.19,93.46 137.16,93.46
VDD_MCU_RAM_0V85 on L7-SIGNAL: 95.76,67.17 94.23,67.17 92.58,65.52 92.58,51.55 89.92,48.88 89.92,45.84 89.15,45.07 87.76,45.07 87,45.84 87,55.62 89.41,58.03 89.41,66.66 90.93,68.19 91.82,68.19 93.47,69.84 93.85,69.84 94.49,70.47 94.49,71.49 94.87,71.87 94.87,72.25 95,72.38 95.63,72.38 95.76,72.25
VDD_MCUIO_1V8 on L7-SIGNAL: 95,66.92 96.14,65.78 96.14,57.77 96.2,57.72 96.2,53.71 96.17,53.68 96.17,49.29 100.81,49.29 100.84,49.27 100.84,45.33 101.35,44.82 137.54,44.82 144.15,51.42 144.15,98.41 137.16,105.4 131.19,105.4 129.92,104.13 129.92,101.84 128.02,101.84 127.25,102.61 127.25,108.32 128.4,109.46 141.73,109.46 148.97,102.22 148.97,97.14 153.35,92.76 153.35,49.27 143.57,39.49 76.58,39.49 74.17,41.9 74.17,48.25 78.36,52.44 83.06,52.44 84.84,50.66 84.84,47.49 87.82,44.5 89.09,44.5 90.3,45.71 90.3,48.63 92.96,51.3 92.96,65.52 94.36,66.92
VDD_MCUIO_3V3 on BOTTOM: 60.58,92.06 59.94,92.7 59.94,95.62 61.85,95.62 63.25,97.02 64.14,97.02 64.14,95.75 62.74,94.35 62.74,92.06
VDD_MCUIO_3V3 on L2-SIGNAL: 64.26,94.86 64.26,115.43 68.2,119.37 88.65,119.37 96.27,111.75 108.46,111.75 109.86,113.15 128.78,113.15 130.3,114.67 130.3,117.72 128.52,119.5 101.73,119.5 99.57,117.34 97.28,117.34 90.81,123.81 65.79,123.81 58.04,116.07 58.04,95.24 59.82,93.46 62.87,93.46
VDD_MCUIO_3V3 on L2-SIGNAL: 64.64,42.92 64.64,40.38 52.7,28.44 44.7,28.44 42.42,30.72 42.42,31.99 51.56,41.14 56.26,41.14 58.8,43.68 63.88,43.68
VDD_MCUIO_3V3 on L5-SIGNAL: 123.83,119.88 129.29,119.88 132.59,116.58 132.59,105.53 136.27,101.84 136.27,96.51 137.79,94.99 144.27,94.99 145.41,93.84 145.41,88.13 150.37,83.17 150.37,71.24 148.84,69.71 147.19,69.71 146.94,69.97 146.94,79.75 140.59,86.1 131.44,86.1 130.56,86.98 130.56,99.43 127.13,102.86 127.13,104.38 128.4,105.65 128.4,109.08 123.57,113.91 123.57,119.62
VDD_MCUIO_3V3 on L6-PWR: 93.09,70.63 84.73,70.63 84.18,71.19 83.82,71.19 81.23,73.78 77.72,73.78 75.82,75.68 75.82,77.33 74.8,78.35 69.34,78.35 64.77,82.92 64.77,95.24 63.63,96.38 59.82,96.38 58.93,95.49 58.93,62.09 87.76,33.26 139.45,33.26 147.96,41.77 147.96,46.09 147.32,46.73 143.64,46.73 137.79,40.88 88.39,40.88 85.6,43.68 85.6,59.3 92.71,66.41 92.84,66.41 93.27,66.85 93.42,66.85 93.8,67.23 93.8,67.55 93.09,68.26
VDD_MCUIO_3V3 on L7-SIGNAL: 77.47,103.24 77.47,99.3 76.45,98.29 67.94,98.29 63.63,93.97 60.07,93.97 59.56,94.48 59.56,97.78 65.41,103.62 77.09,103.62
VDD_PHYIO_1V8 on TOP: 127.76,89.4 127.76,84.44 131.32,80.89 140.46,80.89 141.86,82.29 141.86,84.44 140.97,85.33 133.27,85.33 132.21,86.4 132.21,89.4
VDD_PHYIO_1V8 on TOP: 104.84,100.15 104.95,100.27 104.95,102.02 103.58,102.02 103.2,101.64 103.2,100.6 103.64,100.15
VDD_PHYIO_1V8 on L7-SIGNAL: 105.53,74.91 105.4,75.04 105.41,75.05 105.41,75.43 105.92,75.43 106.05,75.3 110.24,75.3 112.14,77.21 112.14,80.38 113.03,81.27 113.03,94.99 109.73,98.29 105.41,98.29 104.01,99.68 104.01,101.72 104.52,102.22 110.36,102.22 117.09,95.49 117.09,92.95 119.38,90.67 131.06,90.67 132.46,89.27 132.46,84.44 130.81,82.79 121.03,82.79 112.01,73.78 106.05,73.78 105.53,74.3
VDD_PHYIO_1V8 on L7-SIGNAL: 143.76,51.68 143.76,82.41 142.88,83.3 139.7,83.3 139.51,83.11 139.51,56.63 135.32,52.44 104.39,52.44 101.22,49.27 101.22,45.46 101.47,45.2 137.29,45.2
VDD_PHYIO_1V8_REG_SW on TOP: 129.79,92.06 129.79,93.84 130.81,93.84 130.81,91.38 130.05,90.62 130.05,90.41 127.76,90.41 127.76,91.68 129.41,91.68
VDD_RAM_0V85 on TOP: 68.58,110.1 65.58,110.1 65.58,105.65 68.58,105.65
VDD_RAM_0V85 on L6-PWR: 71.88,78.6 69.72,78.6 65.15,83.17 65.15,95.37 63.75,96.76 61.21,96.76 60.33,97.65 60.33,106.29 61.85,107.81 68.83,107.81 68.83,105.46 70.17,104.13 70.17,90.29 70.74,89.72 70.74,86.73 71.37,86.1 71.37,80.76 71.56,80.57 72.07,80.57 72.39,80.25 72.39,79.11
VDD_RAM_0V85 on L7-SIGNAL: 95.76,103.37 95.76,106.54 95.69,106.61 95.69,111.81 88.27,119.24 68.45,119.24 64.77,115.56 64.77,106.16 65.41,105.53 69.98,105.53 75.82,111.37 84.84,111.37 93.47,102.73 95.12,102.73
VDD_RAM_0V85_REG_SW on TOP: 71.25,108.07 73.03,108.07 73.03,107.05 73,107.03 70.59,107.03 69.8,107.81 69.6,107.81 69.6,110.1 70.87,110.1 70.87,108.45
VDD_SD_DV on L2-SIGNAL: 62.48,90.92 62.48,73.9 60.83,72.25 59.31,72.25 58.55,73.01 58.55,89.91 60.45,91.81 61.59,91.81
VDD_SD_DV on L4-SIGNAL: 19.81,84.83 19.81,70.98 21.72,69.08 23.37,69.08 24,69.71 24,83.68 22.48,85.21 20.19,85.21
VDD_SD_DV on L5-SIGNAL: 81.03,108.83 81.03,118.99 63.63,118.99 63.63,90.29 59.82,90.29 58.67,91.43 58.67,121.02 61.59,123.94 82.42,123.94 85.6,120.77 85.6,109.97 84.07,108.45 81.41,108.45
VDD_SD_DV on L7-SIGNAL: 94.69,71.95 94.69,72.38 93.98,72.38 93.85,72.25 93.85,71.24 93.6,70.98 93.22,70.98 92.96,71.24 92.96,72.38 83.31,72.38 82.42,73.27 53.98,73.27 52.7,72 28.57,72 28.19,72.38 22.1,72.38 21.08,71.36 21.08,69.33 22.1,68.32 81.79,68.32 82.8,69.33 92.96,69.33 94.23,70.6 94.23,71.49
VDD_SPK on TOP: 32,85.97 30.73,85.97 29.97,86.73 28.96,86.73 28.7,86.48 28.7,85.59 28.32,85.21 28.32,80.63 28.57,80.38 29.46,80.38 29.97,80.89 29.97,83.94 30.61,84.57 32,84.57
VDD_TAS on TOP: 32,86.22 30.99,86.22 30.23,86.98 28.96,86.98 28.57,87.37 28.57,90.41 29.08,90.92 36.7,90.92 37.85,89.78 37.85,86.35 37.08,85.59 35.05,85.59 35.05,85.97 35.81,85.97 35.81,87.49 34.8,88.51 32,88.51
VDDA_0P8_CSIRX on L7-SIGNAL: 101.73,67.15 102.23,66.64 102.23,65.27 103.25,64.25 103.25,52.06 100.71,49.52 97.16,49.52 96.39,50.28 96.39,66.41 97.13,67.15
VDDA_0P8_DLL_MMC0 on L7-SIGNAL: 105.03,75.05 105.03,75.3 105.41,75.68 105.79,75.68 105.92,75.55 110.11,75.55 111.89,77.33 111.89,81.27 112.78,82.16 112.78,91.3 112.27,91.81 110.36,91.81 109.47,90.92 109.47,80.38 105.92,76.82 104.39,76.82 103.63,76.06 103.63,75.43 104.01,75.05
VDDA_0P8_PLL_DDR on TOP: 109.19,53.66 108.97,53.43 108.97,51.04 109.6,50.41 111.38,50.41 111.38,53.66
VDDA_0P8_PLL_DDR on L7-SIGNAL: 104.01,70.2 106.45,70.2 107.31,69.33 107.31,64.89 109.35,62.85 109.35,56.25 109.6,56 109.6,52.82 109.35,52.57 105.16,52.57 103.76,53.96 103.76,64.57 104.84,65.65 104.84,68.51 103.63,69.71 103.63,69.81
VDDA_0P8_SERDES on TOP: 94.49,92.06 94.49,92.83 94.11,93.21 94.11,94.6 93.73,94.99 91.82,94.99 91.44,94.6 91.44,93.08 92.08,92.45 92.08,91.18 95.76,91.18 95.89,91.3 95.89,91.94 95.76,92.06
VDDA_0P8_SERDES on L4-SIGNAL: 102.87,75.81 102.36,75.3 97.41,75.3 97.16,75.55 97.16,78.48 97.79,79.11 97.79,85.33 96.01,87.11 96.01,89.78 94.61,91.18 93.6,91.18 93.09,91.68 93.09,92.95 93.92,93.78 99.63,93.78 101.73,91.68 101.73,81.27 102.87,80.13
VDDA_0P8_UFS on L7-SIGNAL: 109.22,80.51 109.22,91.3 108.71,91.81 107.95,91.81 107.57,91.43 107.57,90.54 106.68,89.65 106.68,85.21 105.54,84.06 105.54,78.73 105.16,78.35 103.76,78.35 102.74,77.33 102.74,76.82 103,76.57 103.5,76.57 103.89,76.95 105.66,76.95
VDDA_1P8_CSI_RX on L6-PWR: 102.87,66.99 102.87,58.41 103.38,57.9 103.38,50.03 103,49.65 100.84,49.65 98.59,51.9 98.59,63.24 97.41,64.41 97.41,65.01 97.66,65.27 98.17,65.27 98.3,65.39 98.3,66.7 98.59,66.99
VDDA_1P8_SERDES on TOP: 100.84,96.51 100.84,102.22 102.77,102.22 102.77,98.14 103,97.91 103,96.13 101.22,96.13
VDDA_1P8_SERDES on L7-SIGNAL: 97.73,78.92 98.81,77.84 102.36,77.84 102.93,78.41 102.93,95.68 103.25,96 103.25,96.89 102.36,97.78 100.08,97.78 97.76,95.46 97.76,89.68 97.73,89.65
VDDA_1P8_UFS on L7-SIGNAL: 103.38,78.48 103.38,95.62 104.71,96.95 107.51,96.95 107.95,96.51 107.95,92.32 107.31,91.68 107.31,90.79 106.43,89.91 106.43,85.33 105.28,84.19 105.28,78.86 104.9,78.48
VDDA_TC811 on BOTTOM: 38.1,64.51 37.72,64.89 34.42,64.89 34.04,64.51 34.04,63.87 34.29,63.62 34.29,60.95 34.92,60.31 34.92,50.92 35.94,49.9 42.55,49.9 42.93,50.28 42.93,52.06 42.67,52.31 41.27,52.31 40.77,51.81 38.61,51.81 37.85,52.57 37.85,54.73 38.1,54.98
VDDHS11_DSI on TOP: 118.62,24.75 118.62,27.8 118.11,28.31 115.13,28.31 114.17,29.26 113.35,29.26 112.9,28.82 112.9,25.77 114.68,23.99 117.86,23.99
VDDHS11_DSI on L2-SIGNAL: 105.79,17.64 112.52,17.64 114.68,19.8 114.68,28.82 114.17,29.33 113.16,29.33 112.65,28.82 112.65,21.96 110.74,20.06 106.68,20.06 105.28,18.66 105.28,18.15
VDDIO_TC811 on TOP: 36.96,51.81 37.72,51.81 38.1,52.19 40.13,52.19 40.39,52.44 40.39,54.47 40.01,54.85 39.62,54.85 38.73,53.96 35.81,53.96 35.05,53.2 35.05,51.93 35.31,51.68 36.83,51.68
VDDIO_TC811 on BOTTOM: 41.78,55.87 39.62,55.87 38.23,54.47 38.23,52.69 38.61,52.31 40.77,52.31 41.02,52.57 45.21,52.57 47.88,55.23 47.88,61.58 46.23,63.24 45.21,63.24 44.58,62.6 44.58,58.92 43.69,58.03 42.42,58.03 42.29,57.9 42.29,56.38
VDDP11_DSI on TOP: 118.62,21.58 117.35,21.58 117.35,21.45 117.22,21.33 115.7,21.33 114.43,20.06 114.43,17.26 114.81,16.88 117.98,16.88 118.62,17.52
VDDP11_DSI on L5-SIGNAL: 102.36,29.71 104.65,29.71 112.78,21.58 116.59,21.58 118.55,19.61 118.55,17.83 117.47,16.75 110.87,16.75 101.47,26.15 101.47,28.82
(no net) on L4-SIGNAL: 115.19,20.18 89.28,20.18 88.27,21.2 42.93,21.2 42.55,21.58 42.55,39.11 41.78,39.87 33.4,39.87 31.11,42.15 19.94,42.15 19.68,42.41 19.68,68.44 23.37,68.44 24.51,69.59 24.51,84.19 19.81,88.89 19.81,137.15 21.72,139.05 87.38,139.05 94.74,131.69 103.63,131.69 107.95,136.01 117.09,136.01 118.49,137.4 138.68,137.4 141.22,134.86 147.57,134.86 154.18,128.26 154.18,108.45 153.92,108.19 126.75,108.19 122.56,104 122.56,90.29 120.52,88.25 83.06,88.25 83.06,56.63 89.53,50.15 100.58,50.15 102.23,48.5 102.23,46.47 115.19,33.52
CS_P on TOP: 171.32,50.54 175.01,50.54 175.01,56 174.12,56 174.12,57.14 171.32,57.14
HDRV1_N on TOP: 170.05,47.23 157.73,47.23 157.48,47.49 157.48,54.22 171.07,54.22 171.07,50.54 170.05,50.54
HDRV2_N on TOP: 171.07,54.47 157.48,54.47 157.48,63.11 169.16,63.11 169.16,62.98 170.05,62.98 170.05,58.66 171.07,58.66
LM5141_SW on TOP: 175.77,88 185.93,88 186.56,87.37 186.56,82.92 185.8,82.16 175.51,82.16 175.13,82.54 175.13,87.37
LM5141_SW on BOTTOM: 178.44,86.98 186.94,86.98 186.94,82.54 175.9,82.54 175.77,82.67 175.77,87.75 177.67,87.75
OUT1M3 on TOP: 191.52,128.39 194.06,128.39 194.94,129.28 194.94,132.2 190.37,132.2 185.04,126.86 185.04,125.34 185.29,125.08 188.21,125.08
OUT1P3 on TOP: 183.9,126.74 187.32,130.16 187.32,132.2 182.5,132.2 181.48,131.18 181.48,125.34 181.74,125.08 182.88,125.08 183.9,126.1
OUT2M3 on BOTTOM: 186.44,131.94 190.37,131.94 190.37,129.28 184.91,123.81 182.75,123.81 181.61,122.67 181.23,122.67 180.85,123.05 180.85,126.35
OUT2P3 on BOTTOM: 182.63,129.53 182.63,131.94 178.18,131.94 177.42,131.18 177.42,124.32 177.8,123.94 178.56,123.94 179.58,122.93 179.96,122.93 180.09,123.05 180.09,126.99
OUT3M3 on TOP: 180.28,126.55 180.28,131.75 179.83,132.2 175.39,132.2 175.39,129.91 177.16,128.13 177.16,125.47 177.55,125.08 178.82,125.08
OUT3P3 on TOP: 175.77,128.39 172.09,132.07 167.64,132.07 167.64,129.53 168.91,128.26 170.94,128.26 174.12,125.08 175.39,125.08 175.77,125.47
OUT4M3 on BOTTOM: 170.69,131.94 175.01,131.94 176.53,130.42 176.53,124.2 176.15,123.81 175.01,123.81 173.99,122.8 173.48,122.8 173.16,123.12 173.16,127.31 170.69,129.78
OUT4P3 on BOTTOM: 172.47,126.1 168.28,130.29 168.28,131.05 167.39,131.94 163.32,131.94 163.32,129.28 168.66,123.94 170.94,123.94 171.96,122.93 172.21,122.93 172.47,123.18
VCAM_10V5 on TOP: 29.46,6.34 29.72,6.59 29.72,7.1 28.7,8.12 28.7,9.26 28.45,9.51 27.05,9.51 26.8,9.26 26.8,6.59 27.05,6.34
VCAM_10V5 on TOP: 46.1,6.34 46.35,6.59 46.35,7.1 45.34,8.12 45.34,9.26 45.09,9.51 43.69,9.51 43.43,9.26 43.43,6.59 43.69,6.34
VCAM_10V5 on TOP: 97.41,6.85 97.41,2.78 97.79,2.4 99.19,2.4 100.39,3.61 100.39,4.82 100.52,4.94 100.52,6.15 99.82,6.85
VCAM_10V5 on TOP: 62.74,6.34 62.99,6.59 62.99,7.1 61.98,8.12 61.98,9.26 61.72,9.51 60.33,9.51 60.07,9.26 60.07,6.59 60.33,6.34
VCAM_10V5 on TOP: 79.38,6.34 79.63,6.59 79.63,7.1 78.61,8.12 78.61,9.26 78.36,9.51 76.96,9.51 76.71,9.26 76.71,6.59 76.96,6.34
VCAM_10V5 on L6-PWR: 100.71,1.39 100.71,7.48 99.44,8.75 27.18,8.75 26.42,7.99 26.42,2.02 27.05,1.39
VCAM_VDD18 on TOP: 59.69,18.15 56.39,18.15 56.01,18.53 56.01,19.55 56.64,20.18 57.02,20.18 58.29,21.45 58.29,22.72 58.8,23.23 59.82,23.23 60.33,22.72 60.33,18.79
VCAM_VDD18 on BOTTOM: 60.58,22.98 58.55,22.98 58.29,22.72 58.29,20.18 58.55,19.93 59.82,19.93 60.58,20.69
VCAM_VDD18 on BOTTOM: 68.96,22.98 71.25,22.98 71.25,21.45 70.74,20.94 69.85,20.94 68.96,21.83
VCAM_VDD18 on L2-SIGNAL: 59.05,20.44 59.05,23.48 60.07,24.5 69.72,24.5 70.48,23.74 70.48,22.09 70.1,21.71 67.31,21.71 66.8,22.21 62.87,22.21 60.96,20.31 59.18,20.31
VCAM_VDD18_FPD on TOP: 60.58,18.28 60.58,21.96 60.83,22.21 65.41,22.21 65.79,21.83 65.79,18.4 65.53,18.15 60.71,18.15
VCAM_VDD_CSI on TOP: 75.31,29.58 70.61,29.58 69.72,28.69 68.58,28.69 67.56,29.71 62.74,29.71 62.23,30.22 62.23,31.61 62.48,31.87 66.8,31.87 68.2,30.47 68.96,30.47 69.72,31.23 75.31,31.23
VCAM_VDD_FPD on TOP: 71.12,18.4 70.87,18.15 66.29,18.15 66.04,18.4 66.04,21.71 66.55,22.21 67.69,22.21 67.94,21.96 67.94,20.69 68.33,20.31 70.61,20.31 71.12,19.8
VCAM_VDDA18 on TOP: 75.31,33.14 75.31,31.49 69.6,31.49 68.96,30.85 68.33,30.85 68.07,31.1 68.07,31.87 69.34,33.14
VCAM_VDDL on TOP: 75.31,25.52 75.31,23.99 74.93,23.61 69.85,23.61 69.34,24.12 69.34,25.14 69.6,25.39 73.53,25.39 73.66,25.52
VDA_DLL_0V8 on L7-SIGNAL: 131.7,102.73 134.87,102.73 139.45,98.16 139.45,89.27 136.65,86.48 136.65,85.97 135.76,85.08 135.76,74.28 135.13,73.65 135.13,60.44 131.83,57.14 113.67,57.14 111.76,55.23 111.76,53.08 112.01,52.82 135.25,52.82 139.19,56.76 139.19,83.17 143.89,87.87 143.89,98.54 137.29,105.15 131.44,105.15 130.3,104 130.3,101.84 131.06,101.84 131.19,101.97 131.19,102.22
VDA_MCU_1V8 on TOP: 61.98,71.77 61.47,71.26 61.47,69.46 64.01,66.92 66.8,66.92 72.26,61.46 72.26,38.22 72.9,37.58 75.56,37.58 75.95,37.96 75.95,51.93 77.85,53.84 77.85,62.47 75.69,64.63 75.18,64.63 75.18,65.9 73.66,65.9 73.66,66.66 72.9,67.43 72.01,67.43 71.34,68.09 71.34,69.05 68.62,71.77
VDA_MCU_1V8 on BOTTOM: 68.21,70.36 68.83,70.98 68.83,72.25 61.21,72.25 61.21,70.75 61.61,70.36
VDA_MCU_1V8 on L2-SIGNAL: 62.74,73.65 73.41,73.65 77.6,69.46 82.93,69.46 84.07,70.6 89.41,70.6 89.79,70.98 93.47,70.98 94.11,70.35 94.11,66.41 95,65.52 95.89,65.52 96.27,65.14 96.27,64.76 95.63,64.12 92.84,64.12 90.81,66.16 83.57,66.16 82.68,65.27 80.77,65.27 80.64,65.14 64.52,65.14 61.47,68.19 61.47,72.38
VDA_MCU_1V8 on L7-SIGNAL: 163.07,101.72 163.07,44.95 151.89,33.77 72.26,33.77 72.26,38.47 72.77,38.98 143.76,38.98 153.92,49.14 153.92,92.83 149.35,97.4 149.35,102.61 142.24,109.72 128.02,109.72 127,108.7 127,102.48 127.89,101.59 131.19,101.59 131.44,101.84 131.44,102.35 131.7,102.61 134.62,102.61 135.89,101.34 135.89,99.94 133.99,98.03 125.09,98.03 123.19,99.94 123.19,110.23 127,114.04 150.75,114.04
VDA_PLL_1V8 on TOP: 89.41,98.54 89.41,95.87 89.69,95.6 90.65,95.6 90.65,98.54
VDA_PLL_1V8 on L7-SIGNAL: 96.33,67.85 96.88,67.3 101.98,67.3 102.49,66.79 102.49,65.65 103,65.14 104.01,65.14 104.52,65.65 104.52,68.44 103.38,69.59 103.38,69.84 104.27,70.73 104.27,71.62 103.76,72.13 103.7,72.13 97.47,78.35 97.47,90.35 81.53,106.29 80.52,106.29 79.76,105.53 79.76,101.59 88.01,93.33 88.01,87.24 91.25,84 91.25,78.54 91.44,78.35 91.44,72.86 93.09,72.86 93.09,71.49 93.34,71.24 93.6,71.24 93.73,71.36 93.73,72.86 95.74,72.86 96.33,72.27
VDA_USB_3V3 on TOP: 92.96,98.54 92.96,95.87 93.24,95.6 94.21,95.6 94.21,98.54
VDA_USB_3V3 on L5-SIGNAL: 101.47,91.18 101.47,88.38 104.01,85.84 104.01,77.97 103.5,77.46 102.23,77.46 101.35,78.35 101.35,85.71 93.47,93.59 93.47,96.51 93.85,96.89 95.76,96.89
VDA_USB_3V3 on L7-SIGNAL: 84.58,108.83 80.77,108.83 80.77,107.56 92.84,95.49 94.61,95.49 95.25,96.13 95.25,98.16
VIO_3V3_SD on TOP: 24.46,72.91 26.11,72.91 26.37,72.66 27.25,72.66 27.25,69.92 26.8,69.46 19.05,69.46 15.88,72.63 15.88,81.14 16.38,81.65 22.1,81.65 24.13,79.62 24.13,73.24
VIO_3V3USB on TOP: 96.77,114.54 96.77,117.72 97.16,118.1 98.68,118.1 98.93,117.85 98.93,114.92 98.42,114.42 96.9,114.42
VIO_3V3USB on L4-SIGNAL: 97.54,118.48 97.54,114.04 101.73,109.84 107.19,109.84 110.24,112.89 112.14,112.89 112.65,113.4 112.65,120.13 110.11,122.67 106.3,122.67 105.41,121.78 100.84,121.78
VMIC_BIAS on L5-SIGNAL: 13.97,75.55 13.97,139.05 17.91,142.99 19.81,142.99 20.83,141.98 20.83,89.65 18.16,86.98 18.16,76.82 16.38,75.05 14.48,75.05
VPCIE0_1V5 on TOP: 106.43,147.18 107.57,147.18 107.82,147.44 109.09,147.44 109.47,147.82 110.74,147.82 110.74,144.77 110.49,144.52 107.06,144.52 106.17,145.4 106.17,146.93
VPCIE0_1V5 on BOTTOM: 88.39,130.67 66.04,130.67 66.04,140.07 69.22,143.25 100.46,143.25 104.9,147.69 109.35,147.69 110.36,146.67 110.36,141.34 107.06,138.04 94.23,138.04 89.15,132.96 89.15,131.43
VPP_EFUSE_1V8 on BOTTOM: 102.11,77.33 104.39,77.33 104.9,77.84 106.55,77.84 115.7,86.98 117.09,86.98 117.98,87.87 117.98,89.65 117.6,90.03 112.27,90.03 110.49,88.25 110.49,84.95 103.89,78.35 102.23,78.35 101.98,78.09 101.98,77.46
VSYS_3V3 on TOP: 169.93,94.48 169.93,97.02 169.16,97.78 169.16,100.57 165.61,104.13 155.7,104.13 155.7,96.26 157.1,94.86 159.13,94.86 160.15,93.84 160.15,77.84 162.69,75.3 178.18,75.3 179.07,76.19 184.53,76.19 184.53,81.27 184.02,81.78 175.39,81.78 174.75,82.41 174.75,93.21 173.48,94.48
VSYS_3V3 on TOP: 41.4,21.96 41.4,24.75 41.66,25.01 45.47,25.01 45.85,24.63 45.85,23.1 45.59,22.85 42.67,22.85 42.29,22.47 42.29,21.96
VSYS_3V3 on TOP: 157.23,29.71 158.24,29.71 158.88,29.07 162.43,29.07 162.81,29.45 162.81,31.49 162.18,32.12 157.73,32.12 157.23,31.61
VSYS_3V3 on L2-SIGNAL: 149.99,22.6 148.08,20.69 148.08,2.78 42.42,2.78 38.73,6.47 38.73,21.2 42.55,25.01 53.85,25.01 59.05,19.8 73.53,19.8 77.03,23.29 77.09,23.29 78.93,25.14 95.12,25.14 101.47,18.79 101.47,17.01 104.14,14.34 115.06,14.34 125.09,24.37 140.59,24.37 148.72,32.5 148.72,34.53 151.51,37.33 151.51,47.74 150.37,48.88 150.37,72.38 157.73,79.75 164.34,79.75 164.97,79.11 164.97,76.57 155.45,67.05 155.45,37.33 155.7,37.07 155.96,37.07 161.1,31.93 161.86,31.93 162.81,30.98 162.81,27.17 158.24,22.6
VSYS_3V3 on L4-SIGNAL: 165.23,78.22 162.69,78.22 160.27,75.81 157.23,75.81 140.72,59.3 140.72,51.68 155.83,36.57 155.83,29.83 157.1,28.56 162.05,28.56 162.81,29.33 162.81,40.38 153.54,49.65 153.54,59.3 166.62,72.38 166.62,76.82
VSYS_5V0 on TOP: 40.13,21.71 38.48,21.71 38.35,21.58 34.8,21.58 33.85,20.63 33.85,18.47 34.92,17.39 36.7,17.39 37.08,17.77 37.08,19.67 37.34,19.93 38.73,19.93 38.73,20.94 39.12,21.33 40.13,21.33
VSYS_5V0 on TOP: 119.38,7.86 118.49,7.86 118.11,7.48 118.11,7.1 117.98,6.97 116.59,6.97 116.33,6.72 116.33,5.58 116.59,5.32 118.62,5.32 118.87,5.58 118.87,6.72 119.38,7.23
VSYS_5V0 on L2-SIGNAL: 36.45,19.04 36.45,2.66 1.91,2.66 1.91,74.28 4.19,76.57 16.38,76.57 17.91,75.05 17.91,67.55 17.14,66.79 7.75,66.79 7.49,66.54 7.49,26.91 8.64,26.91 12.7,22.85 12.7,17.9 13.59,17.01 13.59,7.23 14.48,6.34 17.4,6.34 30.35,19.29 36.2,19.29
VSYS_5V0 on L4-SIGNAL: 121.67,11.67 121.67,1.64 23.88,1.64 23.88,11.67
VSYS_5V0 on L5-SIGNAL: 13.72,68.32 54.48,68.32 59.05,63.74 59.05,58.03 58.55,57.52 56.64,57.52 55.75,58.41 55.75,62.22 53.72,64.25 13.97,64.25 13.08,65.14 13.08,67.68
VSYS_5V0 on L7-SIGNAL: 26.16,2.53 1.78,2.53 1.78,22.21 3.3,23.74 38.1,23.74 39.88,21.96 39.88,18.28 38.99,17.39 28.32,17.39 26.16,15.23
VSYS_10V5 on TOP: 151.51,16.75 151,17.26 149.86,17.26 149.22,16.63 149.22,9.51 148.72,9.01 148.72,3.42 149.35,2.78 151,2.78 151.51,3.29
VSYS_10V5 on TOP: 97.28,10.91 97.28,15.86 97.92,16.5 99.44,16.5 100.2,15.74 100.2,11.55 99.57,10.91
VSYS_10V5 on TOP: 8.51,82.16 11.56,82.16 13.34,83.94 13.34,85.21 12.57,85.97 9.91,85.97 8.51,84.57
VSYS_10V5 on L6-PWR: 99.69,9.01 101.09,7.61 101.09,1.39 150.5,1.39 150.62,1.51 150.62,18.66 150.24,18.66 145.92,14.34 5.59,14.34 5.59,68.32 4.7,69.2 4.7,74.79 13.97,74.79 13.97,86.6 0.64,86.6 0.64,2.53 26.04,2.53 26.04,8.12 26.92,9.01
VSYS_16V0 on TOP: 158.62,14.09 158.62,16.75 159.13,17.26 160.91,17.26 161.16,17.52 161.16,20.69 155.32,20.69 155.19,20.56 155.19,17.13 155.7,16.63 156.97,16.63 157.23,16.37 157.23,14.09
VSYS_16V0 on TOP: 176.66,58.92 170.31,58.92 170.31,69.59 171.2,70.47 176.66,70.47
VSYS_16V0 on TOP: 110.36,130.93 113.03,130.93 113.28,130.67 113.28,129.02 113.98,128.32 118.17,128.32 119.38,129.53 119.38,131.69 119.13,131.94 113.16,131.94 112.9,132.2 110.36,132.2
VSYS_16V0 on BOTTOM: 176.28,63.24 173.1,63.24 172.85,63.49 172.85,70.35 173.1,70.6 176.28,70.6
VSYS_16V0 on L5-SIGNAL: 171.58,58.66 175.51,58.66 176.78,59.93 176.78,93.33 159.38,110.73 159.38,148.71 157.35,150.74 108.46,150.74 104.65,146.93 104.65,136.01 112.27,128.39 118.62,128.39 119.76,129.53 119.76,131.56 117.98,133.34 113.41,133.34 111,135.75 111,141.59 111.89,142.48 152.15,142.48 154.18,140.45 154.18,106.92 171.58,89.52
VSYS_16V0 on L6-PWR: 151,35.3 164.72,49.01 164.72,67.3 168.4,70.98 178.94,70.98 178.94,45.33 165.42,31.8 165.42,14.4 163.45,12.44 151,12.44
VSYS_IO_1V8 on TOP: 97.92,133.09 97.92,133.97 97.54,134.36 97.16,134.36 97.03,134.48 97.03,135.88 96.77,136.13 95.63,136.13 95.38,135.88 95.38,133.85 95.63,133.59 96.77,133.59 97.28,133.09
VSYS_IO_1V8 on TOP: 112.9,149.47 112.9,148.58 113.92,148.58 113.92,147.82 113.03,147.82 113.03,144.64 113.54,144.13 115.95,144.13 116.84,145.02 116.84,149.72 116.2,150.36 113.79,150.36
VSYS_IO_1V8 on TOP: 119,29.07 121.41,29.07 121.92,29.58 121.92,30.72 121.41,31.23 119.38,31.23 118.87,30.72 118.87,29.2
VSYS_IO_1V8 on TOP: 58.29,17.9 58.29,15.74 59.31,14.72 61.47,14.72 61.85,15.1 61.85,17.9
VSYS_IO_1V8 on TOP: 81.03,17.9 81.15,18.02 81.15,18.4 81.28,18.53 82.68,18.53 82.93,18.79 82.93,30.85 78.87,34.91 74.04,34.91 74.04,33.39 76.83,33.39 80.39,29.83 80.39,18.79 79.88,18.28 79.88,17.9
VSYS_IO_1V8 on TOP: 119.38,14.21 118.49,14.21 118.11,13.83 118.11,13.45 117.98,13.32 116.59,13.32 116.33,13.07 116.33,11.93 116.59,11.67 118.62,11.67 118.87,11.93 118.87,13.07 119.38,13.58
VSYS_IO_1V8 on TOP: 155.57,31.23 155.07,31.23 153.8,32.5 149.22,32.5 149.22,34.03 152.91,34.03 152.91,35.93 153.92,36.95 155.07,36.95 155.57,36.44
VSYS_IO_1V8 on TOP: 32.64,103.49 32.64,102.86 31.88,102.1 28.45,102.1 28.07,102.48 28.07,103.49 28.57,104 32.13,104
VSYS_IO_1V8 on L4-SIGNAL: 155.19,36.57 155.19,13.58 150.11,8.5 125.35,8.5 121.79,12.05 86.49,12.05 86.42,12.12 23.37,12.12 23.37,1.77 1.02,1.77 1.02,150.99 117.09,150.99 117.6,150.48 117.6,143.25 115.51,141.15 110.17,141.15 101.35,132.32 95,132.32 87.63,139.69 21.46,139.69 19.18,137.4 19.18,41.65 15.24,37.71 15.24,22.85 17.78,20.31 37.47,20.31 37.85,20.69 88.01,20.69 88.9,19.8 115.32,19.8 117.86,22.34 117.86,29.45 119.38,30.98 121.54,30.98 121.79,30.72 121.79,22.47 126.75,17.52 140.97,17.52 149.86,26.41 149.86,34.28 152.15,36.57
VSYS_IO_1V8 on L7-SIGNAL: 9.53,106.29 9.91,106.67 29.97,106.67 31.11,105.53 31.11,102.35 30.23,101.46 27.18,101.46 25.15,103.49 10.03,103.49 9.53,104
VTUN_3V3 on TOP: 35.94,118.86 35.31,119.5 35.31,120.51 35.69,120.89 41.91,120.89 42.42,120.39 42.42,119.12 42.16,118.86 41.53,118.86 41.27,119.12 40.51,119.12 40.26,118.86
VTUN_3V3 on L4-SIGNAL: 40.01,118.86 39.37,119.5 39.37,120.39 39.88,120.89 49.66,120.89 50.16,120.39 50.16,119.75 49.28,118.86
VUSART_1V8 on L2-SIGNAL: 28.96,25.14 30.53,25.14 31.42,26.02 31.42,39.99 30.91,40.5 28.75,40.5 27.23,38.98 19.86,38.98 19.68,38.8 19.68,37.71 19.43,37.45 19.43,27.68 28.57,27.68 28.57,25.52
VUSART_3V3 on L4-SIGNAL: 15.62,37.33 19.81,41.52 30.99,41.52 33.27,39.23 41.66,39.23 42.04,38.85 42.04,25.39 37.27,20.63 30.67,20.63 30.61,20.69 30.48,20.56 17.91,20.56 15.62,22.85
VUSART_VBUS on L5-SIGNAL: 13.21,30.72 13.21,12.69 16.13,9.77 16.89,9.77 18.92,11.8 18.92,29.58 16.64,31.87 14.35,31.87
VUSB_5V0 on TOP: 108.97,136.26 108.97,141.09 116.97,141.09 116.97,138.67 111.38,138.67 111,138.29 111,136.26
VUSB_5V0 on TOP: 149.48,120.89 148.59,120.89 148.59,119.62 147.7,118.73 147.7,117.34 147.45,117.08 147.45,112.77 147.83,112.38 148.97,112.38 149.48,112.89
VUSB_5V0 on L5-SIGNAL: 111.38,141.34 111.38,136.01 113.79,133.59 118.36,133.59 120.14,131.82 120.14,129.4 118.75,128.01 112.27,128.01 111.89,127.62 111.89,126.74 112.39,126.23 123.44,126.23 127.13,129.91 137.79,129.91 139.57,131.69 141.22,131.69 147.32,125.59 147.32,115.56 148.08,114.8 152.02,114.8 153.67,116.45 153.67,140.07 151.76,141.98 112.01,141.98
VUSB_IO_1V1 on TOP: 97.92,131.82 97.92,130.67 99.06,129.53 99.06,121.78 98.68,121.4 96.77,121.4 95.25,122.93 95.25,130.93 95.5,131.18 96.65,131.18 97.28,131.82
N28833063 on TOP: 78.23,2.4 78.74,2.91 78.74,4.31 79.5,5.07 79.5,5.2 79.12,5.58 77.34,5.58 76.71,4.94 76.71,2.66 76.96,2.4
N28833063 on BOTTOM: 85.72,5.83 85.85,5.7 85.85,5.45 84.45,4.05 84.45,2.4 76.96,2.4 76.71,2.66 76.71,4.69 76.96,4.94 84.45,4.94 85.34,5.83
N28833077 on BOTTOM: 78.87,13.71 78.87,9.51 77.34,9.51 77.34,6.97 84.45,6.97 85.09,6.34 85.72,6.34 85.85,6.47 85.85,6.72 84.45,8.12 84.45,9.51 80.26,9.51 80.26,14.09 80.52,14.34 80.52,14.59 80.39,14.72 79.88,14.72
N28833083 on BOTTOM: 81.03,14.34 81.41,13.96 81.41,10.66 82.68,10.66 82.68,11.29 84.2,11.29 84.33,11.42 84.33,11.93 84.2,12.05 82.68,12.05 82.68,14.09 82.04,14.72 81.15,14.72 81.03,14.59
N28846480 on BOTTOM: 64.39,14.34 64.77,13.96 64.77,10.66 66.04,10.66 66.04,11.29 67.56,11.29 67.69,11.42 67.69,11.93 67.56,12.05 66.04,12.05 66.04,14.09 65.41,14.72 64.52,14.72 64.39,14.59
N28846484 on BOTTOM: 62.23,13.71 62.23,9.51 60.71,9.51 60.71,6.97 67.82,6.97 68.45,6.34 69.09,6.34 69.22,6.47 69.22,6.72 67.82,8.12 67.82,9.51 63.63,9.51 63.63,14.09 63.88,14.34 63.88,14.59 63.75,14.72 63.25,14.72
N28846490 on TOP: 61.59,2.4 62.1,2.91 62.1,4.31 62.87,5.07 62.87,5.2 62.48,5.58 60.71,5.58 60.07,4.94 60.07,2.66 60.33,2.4
N28846490 on BOTTOM: 69.09,5.83 69.22,5.7 69.22,5.45 67.82,4.05 67.82,2.4 60.33,2.4 60.07,2.66 60.07,4.69 60.33,4.94 67.82,4.94 68.71,5.83
N28847093 on BOTTOM: 47.75,14.34 48.13,13.96 48.13,10.66 49.4,10.66 49.4,11.29 50.93,11.29 51.05,11.42 51.05,11.93 50.93,12.05 49.4,12.05 49.4,14.09 48.77,14.72 47.88,14.72 47.75,14.59
N28847097 on BOTTOM: 45.59,13.71 45.59,9.51 44.07,9.51 44.07,6.97 51.18,6.97 51.82,6.34 52.45,6.34 52.58,6.47 52.58,6.72 51.18,8.12 51.18,9.51 46.99,9.51 46.99,14.09 47.24,14.34 47.24,14.59 47.12,14.72 46.61,14.72
N28847103 on TOP: 44.96,2.4 45.47,2.91 45.47,4.31 46.23,5.07 46.23,5.2 45.85,5.58 44.07,5.58 43.43,4.94 43.43,2.66 43.69,2.4
N28847103 on BOTTOM: 52.45,5.83 52.58,5.7 52.58,5.45 51.18,4.05 51.18,2.4 43.69,2.4 43.43,2.66 43.43,4.69 43.69,4.94 51.18,4.94 52.07,5.83
N28847739 on BOTTOM: 31.11,14.34 31.5,13.96 31.5,10.66 32.77,10.66 32.77,11.29 34.29,11.29 34.42,11.42 34.42,11.93 34.29,12.05 32.77,12.05 32.77,14.09 32.13,14.72 31.24,14.72 31.11,14.59
N28847743 on BOTTOM: 28.96,13.71 28.96,9.51 27.43,9.51 27.43,6.97 34.54,6.97 35.18,6.34 35.81,6.34 35.94,6.47 35.94,6.72 34.54,8.12 34.54,9.51 30.35,9.51 30.35,14.09 30.61,14.34 30.61,14.59 30.48,14.72 29.97,14.72
N28847749 on TOP: 28.32,2.4 28.83,2.91 28.83,4.31 29.59,5.07 29.59,5.2 29.21,5.58 27.43,5.58 26.8,4.94 26.8,2.66 27.05,2.4
N28847749 on BOTTOM: 35.81,5.83 35.94,5.7 35.94,5.45 34.54,4.05 34.54,2.4 27.05,2.4 26.8,2.66 26.8,4.69 27.05,4.94 34.54,4.94 35.43,5.83
N29097715 on BOTTOM: 163.32,135.5 167.89,135.5 169.04,136.64 169.04,141.98 169.54,142.48 169.54,142.99 170.62,144.07 170.62,149.72 170.18,150.17 169.48,150.17 168.91,149.6 168.91,148.33 163.32,142.74
N29097939 on BOTTOM: 171.45,143.88 171.96,143.37 171.96,142.48 172.85,141.59 172.85,140.58 172.72,140.58 170.18,138.04 170.18,135.5 175.01,135.5 175.51,136.01 175.51,144.26 173.1,146.67 173.1,149.72 172.72,150.1 172.09,150.1 171.45,149.47
N29098045 on TOP: 175.64,149.98 175.64,143.88 175.26,143.5 175.26,142.74 173.99,141.47 173.99,137.15 172.47,135.63 167.77,135.63 167.77,141.59 174.12,147.94 174.12,149.72 174.62,150.23 175.39,150.23
N29098169 on TOP: 176.66,144.13 177.67,143.12 177.67,140.83 175.39,138.55 175.39,135.63 179.45,135.63 180.47,136.64 180.47,145.4 178.18,147.69 178.18,149.72 177.67,150.23 177.16,150.23 176.66,149.72
N29098355 on BOTTOM: 177.16,145.28 179.07,147.18 179.07,149.47 179.58,149.98 180.4,149.98 180.78,149.6 180.78,144.07 179.71,142.99 179.71,140.32 180.59,139.44 181.48,139.44 182.63,138.29 182.63,135.37 177.16,135.37
N29098388 on BOTTOM: 181.67,143.82 182.12,143.37 182.12,142.36 183.39,141.09 183.39,140.58 186.18,137.78 186.18,135.5 190.25,135.5 190.25,140.58 183.39,147.44 183.39,149.6 182.88,150.1 181.93,150.1 181.67,149.85
N29098418 on TOP: 181.99,144.9 184.28,147.18 184.28,149.72 184.66,150.1 185.55,150.1 185.8,149.85 185.8,145.53 185.42,145.15 185.42,142.74 184.4,141.72 184.4,140.58 187.07,137.91 187.07,135.63 182.88,135.63 181.99,136.51
N29098431 on TOP: 186.82,143.88 187.83,142.86 187.83,140.71 190.63,137.91 190.63,135.63 194.69,135.63 194.69,140.83 188.34,147.18 188.34,149.72 187.96,150.1 187.07,150.1 186.82,149.85
N29427544 on TOP: 187.58,24.63 189.48,22.72 189.48,17.9 186.69,15.1 186.56,15.1 185.42,13.96 176.15,13.96 173.61,11.42 173.61,8.75 165.48,8.75 165.48,15.1 166.75,16.37 168.15,16.37 168.15,18.66 172.85,18.66 174.88,20.69 174.88,23.87 175.64,24.63
N29427634 on BOTTOM: 184.91,15.86 184.91,12.56 185.17,12.31 189.74,12.31 190.25,12.82 190.25,15.74 189.74,16.25 185.29,16.25
N30808408 on TOP: 41.53,21.45 42.55,21.45 43.31,20.69 45.72,20.69 45.72,22.21 42.93,22.21 42.55,21.83 42.42,21.83 42.29,21.71 41.53,21.71
N30812993 on TOP: 156.97,8.88 156.97,10.53 156.72,10.78 153.92,10.78 153.92,11.29 152.78,11.29 152.78,7.48 153.92,7.48 153.92,8.75 156.84,8.75
